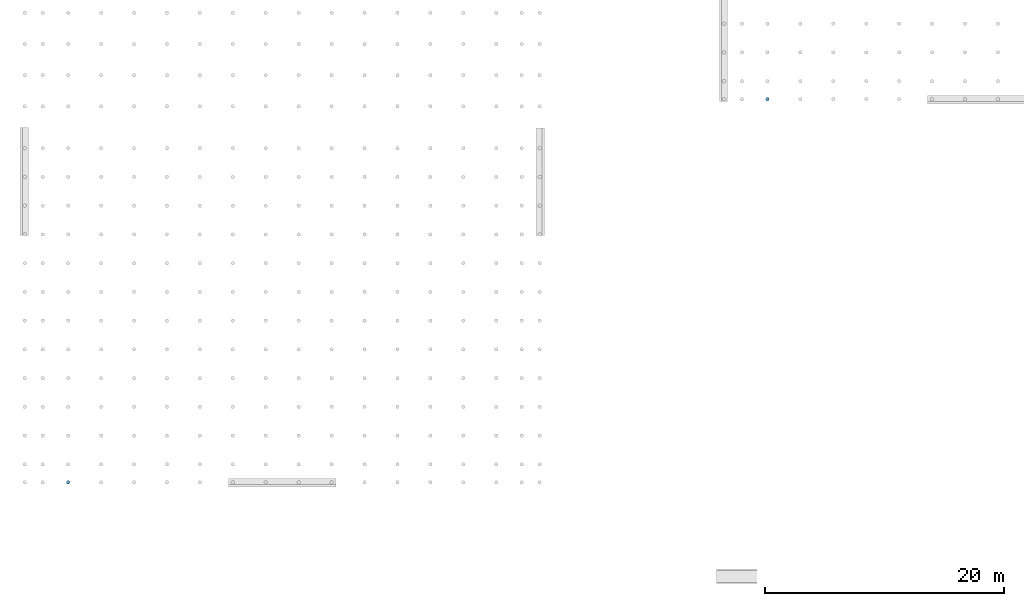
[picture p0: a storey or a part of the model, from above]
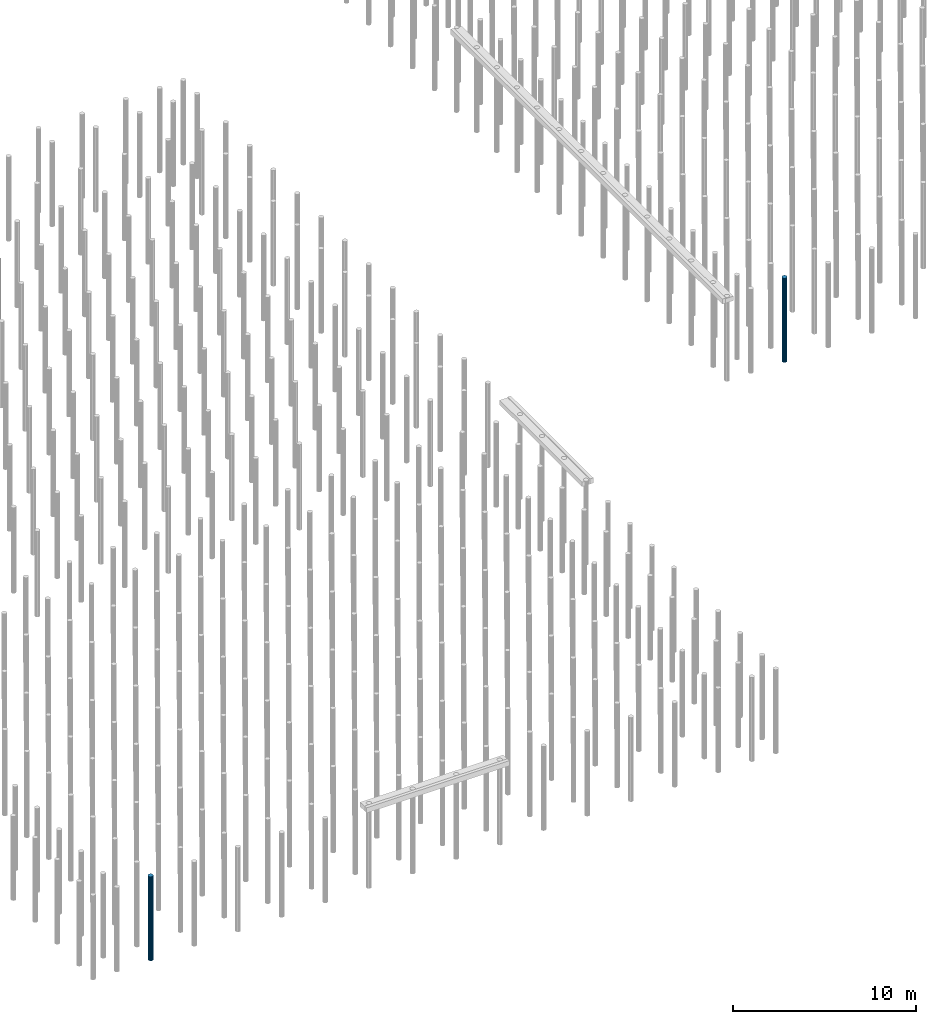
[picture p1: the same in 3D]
Properties of the parts of a building model (IFC2X3), part 1 of 13

# File
Description: ViewDefinition [1, SurfaceGeometryAddOnView, QuantityTakeOffAddOnView, SpaceBoundary2ndLevelAddOnView], Option [Elements to export: Visible elements (on all stories)], Option [Partial Structure Display: Entire Model], Option [IFC Domain: All], Option [Structural Function: All Elements], Option [Convert Grid elements: On], Option [Convert IFC Annotations and Archicad 2D elements: Off], Option [Convert 2D symbols of Doors and Windows: Off], Option [Export geometries that Participates in Collision Detection only: On], Option [Split complex elements: Off], Option [Material Preservation: Never explode], Option [IFC Model position: Survey Point and Project Origin], Option [Curtain Wall export mode: Single Element], Option [Railing export mode: Single Element], Option [Stair export mode: Single Element], Option [Properties To Export: Current Scheme properties only], Option [Space containment: On], Option [IFC Domain For Space Containment: Custom], Option [Geometry to type objects: On], Option [Element Properties: Off], Option [Building Material Properties: Off], Option [Element Parameters: Off], Option [Component Parameters: IFC Component Quantities Only], Option [IFC Base Quantities: On], Option [Door Window Parameters: Off], Option [IFC Space boundaries: On], Option [Archicad Zone Categories as IFC Space classification data: Off], Option [Element Classifications: On]
File name: /Volumes/WERKEN/COURAGE - WERKEN - 2025/COURAGE - 2507 - zrd - middelburg/2507 - TEKENWERK/2507 - 04 - TO - TECHNISCH ONTWERP/2507 - TO - IFC/2507 - 20260205 - definitief - IFC/ZRD-MIDDELBURG_TO_ARC_COU.ifc.ifc
Time: 2026-02-26T14:34:23
Author: Architect
Organization: COURAGE architecten B.V.
Written by: DDS_IFC v3.0
Made in: Graphisoft - Archicad - 27.0.0
Authorization: The authorising person

# IfcProject, ZRD MIDDELBURG
Phase: VOORLOPIG

# IfcSite, Site
RefLatitude: 51, 27, 0, 0; RefLongitude: 5, 29, 0, 0; RefElevation: 0 mm
BaseQuantities - GrossPerimeter: 0 mm; GrossArea: 0 m2

# IfcBuilding, Naam gebouw
BaseQuantities - GrossFloorArea: 0 m2

# IfcBuildingStorey (3)
In: Naam gebouw
BaseQuantities - GrossFloorArea: 0 m2
Name | Elevation (mm) | NetHeight (mm) = GrossHeight (mm) = Height (mm)
-2 fundering | -1020 | 1020
01 dak | 15320 | 1000
00 begane grond | 0 | 15320

# IfcBeam: ALG - ALGEMEEN 200 x 100, samengesteld_element_opsluitband
In: 00 begane grond
Type - PredefinedType: BEAM
Classification: Balk (ARCHICAD Classification); Material: ALG - ALGEMEEN
Pset_BeamCommon - Slope: 0 deg; IsExternal: yes; LoadBearing: no; Reference: ALG - ALGEMEEN 200 x 100
Component Quantities - ALG - ALGEMEEN, Mass: 2.64 kg; ALG - ALGEMEEN, Projected Component Area (Net): 0.0165 m2; ALG - ALGEMEEN, Projected Component Area (Gross): 0.0165 m2; ALG - ALGEMEEN, Component Thickness: 200 mm; ALG - ALGEMEEN, Rectangular Component Height: 100 mm; ALG - ALGEMEEN, Rectangular Component Width: 200 mm; ALG - ALGEMEEN, Component Cross Section Area: 0.02 m2; ALG - ALGEMEEN, Component Volume (Net): 0.0033 m3; ALG - ALGEMEEN, Component Volume (Gross): 0.0033 m3
BaseQuantities - NetSurfaceAreaExtrudedSides: 0.099 m2; Length: 165 mm; Width: 200 mm; Depth: 100 mm; CrossSectionArea: 0.02 m2; OuterSurfaceArea: 0.099 m2; TotalSurfaceArea: 0.139 m2; GrossSurfaceArea: 0.139 m2; GrossVolume: 0.0033 m3; NetSurfaceArea: 0.139 m2; NetVolume: 0.0033 m3
CPset_Phasing - Renovation Phase: Bestaand

# IfcBeam: Beton gewapend C 1000 x 600 (3)
In: -2 fundering
Type - PredefinedType: BEAM
Classification: Balk (ARCHICAD Classification); Material: Beton gewapend C
Pset_BeamCommon - Slope: 0 deg; IsExternal: yes; LoadBearing: yes; Reference: Beton gewapend C 1000 x 600
CPset_Phasing - Renovation Phase: Bestaand
BaseQuantities - Width: 1000 mm; Depth: 600 mm; CrossSectionArea: 0.6 m2
Component Quantities - Beton gewapend C, Component Thickness: 1000 mm; Beton gewapend C, Rectangular Component Height: 600 mm; Beton gewapend C, Rectangular Component Width: 1000 mm; Beton gewapend C, Component Cross Section Area: 0.6 m2
Name | NetSurfaceAreaExtrudedSides (m2) = OuterSurfaceArea (m2) | Length (mm) | TotalSurfaceArea (m2) = GrossSurfaceArea (m2) = NetSurfaceArea (m2) | GrossVolume (m3) = NetVolume (m3) = Beton gewapend C, Projected Component Area (Net) (m2) = Beton gewapend C, Projected Component Area (Gross) (m2) = Beton gewapend C, Component Volume (Net) (m3) = Beton gewapend C, Component Volume (Gross) (m3) | Beton gewapend C, Mass (kg)
Balk-x | 80.8 | 25250 | 82 | 15.15 | 34845
Balk-x | 27.2 | 8500 | 28.4 | 5.1 | 11730
Balk-x | 62.4 | 19500 | 63.6 | 11.7 | 26910

# IfcBeam: Beton gewapend C 500 x 600 (5)
In: -2 fundering
Type - PredefinedType: BEAM
Classification: Balk (ARCHICAD Classification); Material: Beton gewapend C
Pset_BeamCommon - Slope: 0 deg; IsExternal: yes; LoadBearing: yes; Reference: Beton gewapend C 500 x 600
Component Quantities - Beton gewapend C, Component Thickness: 500 mm; Beton gewapend C, Rectangular Component Height: 600 mm; Beton gewapend C, Rectangular Component Width: 500 mm; Beton gewapend C, Component Cross Section Area: 0.3 m2
CPset_Phasing - Renovation Phase: Bestaand
BaseQuantities - Width: 500 mm; Depth: 600 mm; CrossSectionArea: 0.3 m2
Name | Beton gewapend C, Mass (kg) | Beton gewapend C, Projected Component Area (Net) (m2) = Beton gewapend C, Projected Component Area (Gross) (m2) | Beton gewapend C, Component Volume (Net) (m3) = Beton gewapend C, Component Volume (Gross) (m3) = NetVolume (m3) | NetSurfaceAreaExtrudedSides (m2) = OuterSurfaceArea (m2) | Length (mm) | TotalSurfaceArea (m2) = GrossSurfaceArea (m2) = NetSurfaceArea (m2) | GrossVolume (m3)
2 x Balk-x | 10453.5 | 9.24 | 4.545 | 33.33 | 15400 | 33.93 | 4.845
Balk-x | 10971 | 9.84 | 4.77 | 34.98 | 16400 | 35.58 | 4.77
2 x Balk-x | 10626 | 9.24 | 4.62 | 33.88 | 15400 | 34.48 | 4.92

# IfcBeam: Beton gewapend C vloer 200 x 350 (8)
In: -2 fundering
Type - PredefinedType: BEAM
Classification: Balk (ARCHICAD Classification); Material: Beton gewapend C vloer
Pset_BeamCommon - Slope: 0 deg; IsExternal: yes; LoadBearing: no; Reference: Beton gewapend C vloer 200 x 350
CPset_Phasing - Renovation Phase: Bestaand
BaseQuantities - Width: 200 mm; Depth: 350 mm; CrossSectionArea: 0.07 m2
Component Quantities - Beton gewapend C vloer, Component Thickness: 200 mm; Beton gewapend C vloer, Rectangular Component Height: 350 mm; Beton gewapend C vloer, Rectangular Component Width: 200 mm; Beton gewapend C vloer, Component Cross Section Area: 0.07 m2
Name | NetSurfaceAreaExtrudedSides (m2) = OuterSurfaceArea (m2) | Length (mm) | TotalSurfaceArea (m2) = GrossSurfaceArea (m2) = NetSurfaceArea (m2) | GrossVolume (m3) = NetVolume (m3) = Beton gewapend C vloer, Component Volume (Net) (m3) = Beton gewapend C vloer, Component Volume (Gross) (m3) | Beton gewapend C vloer, Mass (kg) | Beton gewapend C vloer, Projected Component Area (Net) (m2) = Beton gewapend C vloer, Projected Component Area (Gross) (m2)
6 x wvb. | 9.9 | 9000 | 10.04 | 0.63 | 1512 | 3.15
wvb. | 9.196 | 8360 | 9.336 | 0.5852 | 1404.48 | 2.926
wvb. | 32.604 | 29640 | 32.744 | 2.0748 | 4979.52 | 10.374

# IfcBeam: Beton gewapend C vloer 500 x 300 (8)
In: -2 fundering
Type - PredefinedType: BEAM
Classification: Balk (ARCHICAD Classification); Material: Beton gewapend C vloer
CPset_Phasing - Renovation Phase: Bestaand
Pset_BeamCommon - Slope: 0 deg; IsExternal: yes; LoadBearing: no; Reference: Beton gewapend C vloer 500 x 300
BaseQuantities - Width: 500 mm; Depth: 300 mm; CrossSectionArea: 0.15 m2
Component Quantities - Beton gewapend C vloer, Component Thickness: 500 mm; Beton gewapend C vloer, Rectangular Component Height: 300 mm; Beton gewapend C vloer, Rectangular Component Width: 500 mm; Beton gewapend C vloer, Component Cross Section Area: 0.15 m2
Name | NetSurfaceAreaExtrudedSides (m2) = OuterSurfaceArea (m2) | Length (mm) | TotalSurfaceArea (m2) = GrossSurfaceArea (m2) = NetSurfaceArea (m2) | GrossVolume (m3) = NetVolume (m3) = Beton gewapend C vloer, Component Volume (Net) (m3) = Beton gewapend C vloer, Component Volume (Gross) (m3) | Beton gewapend C vloer, Mass (kg) | Beton gewapend C vloer, Projected Component Area (Net) (m2) = Beton gewapend C vloer, Projected Component Area (Gross) (m2)
6 x wvb. | 14.4 | 9000 | 14.7 | 1.35 | 3240 | 2.7
wvb. | 13.376 | 8360 | 13.676 | 1.254 | 3009.6 | 2.508
wvb. | 47.424 | 29640 | 47.724 | 4.446 | 10670.4 | 8.892

# IfcBeam: Boiler elektrisch 27, boilervat 250 liter
In: 00 begane grond
Type - PredefinedType: BEAM
Classification: Balk (ARCHICAD Classification); 47 Dakafwerkingen (NL/SfB (4 cijfers))
Component Quantities - Component, Component Volume (Net): 0.414247 m3; Component, Component Volume (Gross): 0.414247 m3
Pset_BeamCommon - IsExternal: yes; LoadBearing: yes
CPset_Phasing - Renovation Phase: Bestaand

# IfcBeam: Brandslang haspelkast 27 (6)
In: 00 begane grond
Type - PredefinedType: BEAM
Classification: Balk (ARCHICAD Classification); 47 Dakafwerkingen (NL/SfB (4 cijfers))
CPset_Phasing - Renovation Phase: Bestaand
Pset_BeamCommon - IsExternal: yes; LoadBearing: no
Component Quantities - Component, Component Volume (Net): 0.0522858 m3; Component, Component Volume (Gross): 0.0522858 m3

# IfcBeam: Buis vk koudgev balk 27 (252)
Type - PredefinedType: BEAM
Classification: Balk (ARCHICAD Classification); 28.11 kolom-/liggerconstructies (NL/SfB (4 cijfers)); Material: Metaal - Staal AFW
CPset_Phasing - Renovation Phase: Bestaand
Pset_BeamCommon - IsExternal: no; LoadBearing: yes
Name | In | Metaal - Staal AFW, Mass (kg) | Metaal - Staal AFW, Component Volume (Net) (m3) = Metaal - Staal AFW, Component Volume (Gross) (m3)
56 x K90x4 | 00 begane grond | 71.1366 | 0.008948
129 x K90x4 | 00 begane grond | 72.6055 | 0.00913277
32 x K90x4 | 00 begane grond | 34.8339 | 0.00438162
6 x K90x4 | 00 begane grond | 70.9268 | 0.00892161
6 x K90x4 | 00 begane grond | 73.0777 | 0.00919216
2 x K90x4 | 00 begane grond | 71.3465 | 0.0089744
3 x K90x4 | 00 begane grond | 598.471 | 0.0752794
3 x K120x5 | 00 begane grond | 266.611 | 0.0335359
K120x5 | 00 begane grond | 276.459 | 0.0347747
K120x5 | 00 begane grond | 206.993 | 0.0260368
K120x5 | 00 begane grond | 48.0989 | 0.00605018
2 x K120x5 | 00 begane grond | 83.8874 | 0.0105519
5 x K90x4 | 01 dak | 673.804 | 0.0847553
5 x K90x4 | 01 dak | 598.261 | 0.075253

# IfcBeam: Constructie - achterconstructie lamellen (ophanging) 60 x 7310 (16)
In: 00 begane grond
Type - PredefinedType: BEAM
Classification: Balk (ARCHICAD Classification); 28.11 kolom-/liggerconstructies (NL/SfB (4 cijfers)); Material: Metaal - Staal C (3)
Pset_BeamCommon - Slope: 0 deg; IsExternal: yes; LoadBearing: yes; Reference: Constructie - achterconstructie lamellen (ophanging) 60 x 7310
CPset_Phasing - Renovation Phase: Bestaand
BaseQuantities - NetSurfaceAreaExtrudedSides: 0.324155 m2; Length: 450 mm; CrossSectionArea: 0.0108103 m2; OuterSurfaceArea: 0.324155 m2; TotalSurfaceArea: 0.345775 m2; GrossSurfaceArea: 0.345775 m2; GrossVolume: 0.00486464 m3; NetSurfaceArea: 0.345775 m2; NetVolume: 0.00486464 m3
Component Quantities - Metaal - Staal C 1, Mass: 12.8913 kg; Metaal - Staal C 1, Rectangular Component Height: 60.0286 mm; Metaal - Staal C 1, Rectangular Component Width: 60.0286 mm; Metaal - Staal C 1, Component Cross Section Area: 0.00360343 m2; Metaal - Staal C 1, Component Volume (Net): 0.00162155 m3; Metaal - Staal C 1, Component Volume (Gross): 0.00162155 m3; Metaal - Staal C 2, Mass: 12.8913 kg; Metaal - Staal C 2, Rectangular Component Height: 60.0286 mm; Metaal - Staal C 2, Rectangular Component Width: 60.0286 mm; Metaal - Staal C 2, Component Cross Section Area: 0.00360343 m2; Metaal - Staal C 2, Component Volume (Net): 0.00162155 m3; Metaal - Staal C 2, Component Volume (Gross): 0.00162155 m3; Metaal - Staal C 3, Mass: 12.8913 kg; Metaal - Staal C 3, Rectangular Component Height: 60.0286 mm; Metaal - Staal C 3, Rectangular Component Width: 60.0286 mm; Metaal - Staal C 3, Component Cross Section Area: 0.00360343 m2; Metaal - Staal C 3, Component Volume (Net): 0.00162155 m3; Metaal - Staal C 3, Component Volume (Gross): 0.00162155 m3

# IfcBeam: Constructie - achterconstructie lamellen 150 x 7400 (4)
In: 00 begane grond
Type - PredefinedType: BEAM
Classification: Balk (ARCHICAD Classification); 28.11 kolom-/liggerconstructies (NL/SfB (4 cijfers)); Material: Metaal - Staal C (3)
CPset_Phasing - Renovation Phase: Bestaand
BaseQuantities - CrossSectionArea: 0.0086588 m2
Pset_BeamCommon - Slope: 0 deg; IsExternal: yes; LoadBearing: yes; Reference: Constructie - achterconstructie lamellen 150 x 7400
Component Quantities - Metaal - Staal C 1, Component Cross Section Area: 0.00288627 m2; Metaal - Staal C 2, Component Cross Section Area: 0.00288627 m2; Metaal - Staal C 3, Component Cross Section Area: 0.00288627 m2
Name | NetSurfaceAreaExtrudedSides (m2) = OuterSurfaceArea (m2) | Length (mm) | TotalSurfaceArea (m2) = GrossSurfaceArea (m2) = NetSurfaceArea (m2) | GrossVolume (m3) | NetVolume (m3) | Metaal - Staal C 1, Mass (kg) = Metaal - Staal C 2, Mass (kg) = Metaal - Staal C 3, Mass (kg) | Metaal - Staal C 1, Component Volume (Net) (m3) = Metaal - Staal C 1, Component Volume (Gross) (m3) = Metaal - Staal C 2, Component Volume (Net) (m3) = Metaal - Staal C 2, Component Volume (Gross) (m3) = Metaal - Staal C 3, Component Volume (Net) (m3) = Metaal - Staal C 3, Component Volume (Gross) (m3)
K150 (X3) | 62.1806 | 18127.5 | 62.1979 | 0.15669 | 0.156474 | 414.655 | 0.0521579
3 x K150 (X3) | 62.0518 | 18090 | 62.0691 | 0.156366 | 0.156149 | 413.796 | 0.0520498

# IfcBeam: Fundering - EPS bekisting KME 1240 x 720 (3)
In: -2 fundering
Type - PredefinedType: BEAM
Classification: Balk (ARCHICAD Classification); Material: Isolatie - Kunststof hard
CPset_Phasing - Renovation Phase: Bestaand
Pset_BeamCommon - Slope: 0 deg; IsExternal: yes; LoadBearing: no; Reference: Fundering - EPS bekisting KME 1240 x 720
BaseQuantities - CrossSectionArea: 0.333915 m2
Component Quantities - Isolatie - Kunststof hard, Component Cross Section Area: 0.333915 m2
Name | NetSurfaceAreaExtrudedSides (m2) = OuterSurfaceArea (m2) | Length (mm) | TotalSurfaceArea (m2) = GrossSurfaceArea (m2) = NetSurfaceArea (m2) | GrossVolume (m3) | NetVolume (m3) = Isolatie - Kunststof hard, Component Volume (Net) (m3) = Isolatie - Kunststof hard, Component Volume (Gross) (m3) | Isolatie - Kunststof hard, Mass (kg)
wvb. | 74.4122 | 19500 | 75.08 | 6.51135 | 5.61898 | 561.898
wvb. | 32.4361 | 8500 | 33.1039 | 2.83828 | 2.4493 | 244.93
wvb. | 95.6481 | 25250 | 96.3159 | 8.43136 | 7.20618 | 720.618

# IfcBeam: Fundering - EPS bekisting KME 740 x 720 (5)
In: -2 fundering
Type - PredefinedType: BEAM
Classification: Balk (ARCHICAD Classification); Material: Isolatie - Kunststof hard
BaseQuantities - CrossSectionArea: 0.228153 m2
Component Quantities - Isolatie - Kunststof hard, Component Cross Section Area: 0.228153 m2
Pset_BeamCommon - Slope: 0 deg; IsExternal: yes; LoadBearing: no; Reference: Fundering - EPS bekisting KME 740 x 720
CPset_Phasing - Renovation Phase: Bestaand
Name | NetSurfaceAreaExtrudedSides (m2) = OuterSurfaceArea (m2) | Length (mm) | TotalSurfaceArea (m2) = GrossSurfaceArea (m2) = NetSurfaceArea (m2) | GrossVolume (m3) | NetVolume (m3) = Isolatie - Kunststof hard, Component Volume (Net) (m3) = Isolatie - Kunststof hard, Component Volume (Gross) (m3) | Isolatie - Kunststof hard, Mass (kg)
wvb. | 60.2143 | 15420 | 60.6706 | 3.45651 | 3.35993 | 335.993
2 x wvb. | 62.0658 | 15200 | 62.5221 | 3.79552 | 3.45973 | 345.973
wvb. | 60.2143 | 15420 | 60.6706 | 3.45506 | 3.35993 | 335.993
wvb. | 65.0673 | 16640 | 65.5236 | 3.62763 | 3.62763 | 362.763

# IfcBeam: Gevel lekdorpel 30 x 57 (19)
In: 00 begane grond
Type - PredefinedType: BEAM
Material: Metaal - Titanium zink
CPset_Phasing - Renovation Phase: Bestaand
Pset_BeamCommon - Slope: 0 deg; IsExternal: yes; LoadBearing: no; Reference: Gevel lekdorpel 30 x 57
Component Quantities - Metaal - Titanium zink, Component Cross Section Area: 0.00015341 m2
BaseQuantities - CrossSectionArea: 0.00015341 m2
Name | Classification | Metaal - Titanium zink, Mass (kg) | Metaal - Titanium zink, Component Volume (Net) (m3) = Metaal - Titanium zink, Component Volume (Gross) (m3) = GrossVolume (m3) = NetVolume (m3) | NetSurfaceAreaExtrudedSides (m2) = OuterSurfaceArea (m2) | Length (mm) | TotalSurfaceArea (m2) = GrossSurfaceArea (m2) = NetSurfaceArea (m2)
8 x aluminium lekdorpel | Balk (ARCHICAD Classification); 41.12 bekledingen (NL/SfB (4 cijfers)) | 19.9384 | 0.00276922 | 2.93163 | 18270 | 2.93193
2 x aluminium lekdorpel | Balk (ARCHICAD Classification); 41.12 bekledingen (NL/SfB (4 cijfers)) | 39.5652 | 0.00549517 | 5.81745 | 36240 | 5.81776
2 x aluminium lekdorpel | Balk (ARCHICAD Classification); 41.12 bekledingen (NL/SfB (4 cijfers)) | 23.8375 | 0.00331077 | 3.50494 | 21840 | 3.50524
aluminium lekdorpel | Balk (ARCHICAD Classification); 41.12 bekledingen (NL/SfB (4 cijfers)) | 0.453512 | 0.0000629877 | 0.0666738 | 430 | 0.0669806
3 x aluminium lekdorpel | Balk (ARCHICAD Classification); 41.12 bekledingen (NL/SfB (4 cijfers)) | 0.655321 | 0.0000910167 | 0.0963549 | 600 | 0.0966617
aluminium lekdorpel | Balk (ARCHICAD Classification); 41.12 bekledingen (NL/SfB (4 cijfers)) | 24.0393 | 0.0033388 | 3.53462 | 22010 | 3.53492
 | Balk (ARCHICAD Classification) | 0.453512 | 0.0000629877 | 0.0666738 | 430 | 0.0669806
aluminium lekdorpel | Balk (ARCHICAD Classification); 41.12 bekledingen (NL/SfB (4 cijfers)) | 63.1625 | 0.00877257 | 9.28706 | 57860 | 9.28737

# IfcBeam: HEA balk 27 (82)
Type - PredefinedType: BEAM
Classification: Balk (ARCHICAD Classification); 28.11 kolom-/liggerconstructies (NL/SfB (4 cijfers)); Material: Metaal - Staal AFW
CPset_Phasing - Renovation Phase: Bestaand
Pset_BeamCommon - IsExternal: no; LoadBearing: yes
Name | In | Metaal - Staal AFW, Mass (kg) | Metaal - Staal AFW, Component Volume (Net) (m3) | Metaal - Staal AFW, Component Volume (Gross) (m3)
2 x HEA240 | 00 begane grond | 3943.37 | 0.496021 | 0.497603
2 x HEA240 | 00 begane grond | 3943.39 | 0.496023 | 0.497603
2 x HEA240 | 00 begane grond | 3501.56 | 0.440448 | 0.441832
2 x HEA240 | 00 begane grond | 3508.04 | 0.441263 | 0.441832
4 x HEA240 | 00 begane grond | 2616.37 | 0.329103 | 0.330289
4 x HEA240 | 00 begane grond | 1312.69 | 0.165118 | 0.165145
4 x HEA240 | 00 begane grond | 1312.82 | 0.165135 | 0.165145
15 x HEA240 | 00 begane grond | 1312.9 | 0.165145 | 0.165145
15 x HEA240 | 00 begane grond | 2625.8 | 0.330289 | 0.330289
15 x HEA240 | 00 begane grond | 1313.44 | 0.165213 | 0.165213
HEA240 | 00 begane grond | 3512.56 | 0.441832 | 0.441832
2 x HEA160 | 01 dak | 1989.81 | 0.25029 | 0.25029
2 x HEA220 | 01 dak | 2585.07 | 0.325166 | 0.325166
4 x HEA220 | 01 dak | 382.249 | 0.0480816 | 0.0480816
2 x HEA220 | 01 dak | 2214.16 | 0.27851 | 0.27851
4 x HEA160 | 01 dak | 1323.74 | 0.166508 | 0.166508
2 x HEA160 | 01 dak | 1767.62 | 0.222342 | 0.222342

# IfcBeam: HEA140 140 x 133 (180)
In: 00 begane grond
Type - PredefinedType: BEAM
Classification: Balk (ARCHICAD Classification); Material: Metaal - Staal C
Component Quantities - Metaal - Staal C, Component Cross Section Area: 0.003018 m2
BaseQuantities - CrossSectionArea: 0.003018 m2
CPset_Phasing - Renovation Phase: Bestaand
Pset_BeamCommon - IsExternal: no; LoadBearing: yes; Reference: HEA140 140 x 133
Name | Metaal - Staal C, Mass (kg) | Metaal - Staal C, Component Volume (Net) (m3) = NetVolume (m3) | Metaal - Staal C, Component Volume (Gross) (m3) | NetSurfaceAreaExtrudedSides (m2) = OuterSurfaceArea (m2) | Length (mm) | TotalSurfaceArea (m2) = GrossSurfaceArea (m2) = NetSurfaceArea (m2) | GrossVolume (m3) | Slope (deg)
30 x HEA140 | 101.111 | 0.0127183 | 0.0133229 | 3.43453 | 4350.46 | 3.44057 | 0.0133229 | 38.6749
30 x HEA140 | 99.0656 | 0.0124611 | 0.0130767 | 3.36507 | 4266.87 | 3.37111 | 0.0130767 | 37.3061
30 x HEA140 | 100.084 | 0.0125891 | 0.0131989 | 3.39965 | 4308.43 | 3.40569 | 0.0131989 | 37.9969
30 x HEA140 | 102.15 | 0.012849 | 0.0134489 | 3.46983 | 4393.1 | 3.47586 | 0.0134489 | 39.3403
16 x HEA140 | 94.4002 | 0.0118742 | 0.0125029 | 3.20659 | 4074.5 | 3.21263 | 0.0125029 | 35.8857
30 x HEA140 | 98.0599 | 0.0123346 | 0.0129564 | 3.33091 | 4225.93 | 3.33694 | 0.0129564 | 36.6024
14 x HEA140 | 94.2291 | 0.0118527 | 0.0124813 | 3.20078 | 4067.37 | 3.20682 | 0.0125029 | 35.8857

# IfcBeam: HEA200 200 x 190 (3)
In: 00 begane grond
Type - PredefinedType: BEAM
Classification: Balk (ARCHICAD Classification); 28.11 kolom-/liggerconstructies (NL/SfB (4 cijfers)); Material: Metaal - Staal C
Pset_BeamCommon - Slope: 0 deg; IsExternal: no; LoadBearing: yes; Reference: HEA200 200 x 190
CPset_Phasing - Renovation Phase: Bestaand
BaseQuantities - CrossSectionArea: 0.005105 m2
Component Quantities - Metaal - Staal C, Component Cross Section Area: 0.005105 m2
Name | NetSurfaceAreaExtrudedSides (m2) = OuterSurfaceArea (m2) | Length (mm) | TotalSurfaceArea (m2) = GrossSurfaceArea (m2) = NetSurfaceArea (m2) | GrossVolume (m3) = NetVolume (m3) = Metaal - Staal C, Component Volume (Net) (m3) = Metaal - Staal C, Component Volume (Gross) (m3) | Metaal - Staal C, Mass (kg)
stalen constructie | 7.88892 | 6760 | 7.89913 | 0.0345098 | 274.353
2 x HEA200 | 16.6648 | 14280 | 16.675 | 0.0728994 | 579.55

# IfcBeam: Hoeklijn gelijk balk 27 (25)
In: 00 begane grond
Type - PredefinedType: BEAM
Classification: Balk (ARCHICAD Classification); 28.11 kolom-/liggerconstructies (NL/SfB (4 cijfers)); Material: Metaal - Staal AFW
Pset_BeamCommon - IsExternal: yes; LoadBearing: yes
CPset_Phasing - Renovation Phase: Bestaand
Name | Metaal - Staal AFW, Mass (kg) | Metaal - Staal AFW, Component Volume (Net) (m3) = Metaal - Staal AFW, Component Volume (Gross) (m3)
L60x6 | 34.5898 | 0.00435091
3 x L60x6 | 24.2386 | 0.00304887
4 x L60x6 | 30.6679 | 0.00385759
4 x L60x6 | 24.9458 | 0.00313783
L60x6 | 17.5842 | 0.00221185
2 x L60x6 | 44.3623 | 0.00558017
6 x L60x6 | 46.2268 | 0.0058147
2 x L60x6 | 43.5265 | 0.00547503
2 x L60x6 | 44.716 | 0.00562465

# IfcBeam: Hout AFW 20 x 65 (294)
In: 00 begane grond
Type - PredefinedType: BEAM
Classification: Balk (ARCHICAD Classification); Material: Hout AFW
Pset_BeamCommon - Slope: 0 deg; IsExternal: no; LoadBearing: yes; Reference: Hout AFW 20 x 65
Component Quantities - Hout AFW, Component Thickness: 20 mm; Hout AFW, Rectangular Component Height: 65 mm; Hout AFW, Rectangular Component Width: 20 mm; Hout AFW, Component Cross Section Area: 0.0013 m2
CPset_Phasing - Renovation Phase: Bestaand
BaseQuantities - Width: 20 mm; Depth: 65 mm; CrossSectionArea: 0.0013 m2
Name | Hout AFW, Mass (kg) | Hout AFW, Projected Component Area (Net) (m2) = Hout AFW, Projected Component Area (Gross) (m2) | Hout AFW, Component Volume (Net) (m3) = Hout AFW, Component Volume (Gross) (m3) = GrossVolume (m3) = NetVolume (m3) | NetSurfaceAreaExtrudedSides (m2) = OuterSurfaceArea (m2) | Length (mm) | TotalSurfaceArea (m2) = GrossSurfaceArea (m2) = NetSurfaceArea (m2)
24 x plafondafwerking_02 | 1.7875 | 0.1625 | 0.00325 | 0.425 | 2500 | 0.4276
262 x plafondafwerking_02 | 1.02245 | 0.09295 | 0.001859 | 0.2431 | 1430 | 0.2457
8 x plafondafwerking_02 | 1.66738 | 0.15158 | 0.00303159 | 0.396439 | 2331.99 | 0.399039

# IfcBeam: Hout AFW 31 x 55, Plafondafwerking 3
In: 00 begane grond
Type - PredefinedType: BEAM
Classification: Balk (ARCHICAD Classification); Material: Hout AFW
Pset_BeamCommon - Slope: 0 deg; IsExternal: no; LoadBearing: yes; Reference: Hout AFW 31 x 55
BaseQuantities - NetSurfaceAreaExtrudedSides: 0.43 m2; Length: 2500 mm; Width: 31 mm; Depth: 55 mm; CrossSectionArea: 0.001705 m2; OuterSurfaceArea: 0.43 m2; TotalSurfaceArea: 0.43341 m2; GrossSurfaceArea: 0.43341 m2; GrossVolume: 0.0042625 m3; NetSurfaceArea: 0.43341 m2; NetVolume: 0.0042625 m3
CPset_Phasing - Renovation Phase: Bestaand
Component Quantities - Hout AFW, Mass: 2.34438 kg; Hout AFW, Projected Component Area (Net): 0.1375 m2; Hout AFW, Projected Component Area (Gross): 0.1375 m2; Hout AFW, Component Thickness: 31 mm; Hout AFW, Rectangular Component Height: 55 mm; Hout AFW, Rectangular Component Width: 31 mm; Hout AFW, Component Cross Section Area: 0.001705 m2; Hout AFW, Component Volume (Net): 0.0042625 m3; Hout AFW, Component Volume (Gross): 0.0042625 m3

# IfcBeam: L 140x70x15 - S355 140 x 78 (4)
In: 00 begane grond
Type - PredefinedType: BEAM
Classification: Balk (ARCHICAD Classification); 28.11 kolom-/liggerconstructies (NL/SfB (4 cijfers)); Material: WSP_metaal - staal - S355
Pset_ReinforcementBarPitchOfBeam - Reference: Tequ 140x140x15 - S355
Pset_BeamCommon - Slope: 0 deg; Reference: Tequ 140x140x15 - S355; Span: 1510 mm; FireRating: use instance; IsExternal: no; LoadBearing: yes
CPset_Phasing - Renovation Phase: Bestaand
BaseQuantities - CrossSectionArea: 0.00306619 m2
Component Quantities - WSP_metaal - staal - S355, Component Cross Section Area: 0.00306619 m2
Name (28_WSP_SF_staal - T v21-1:Tequ 140x140x15 - S355:...) | NetSurfaceAreaExtrudedSides (m2) = OuterSurfaceArea (m2) | Length (mm) | TotalSurfaceArea (m2) = GrossSurfaceArea (m2) = NetSurfaceArea (m2) | GrossVolume (m3) | NetVolume (m3) = WSP_metaal - staal - S355, Component Volume (Net) (m3) | WSP_metaal - staal - S355, Mass (kg) | WSP_metaal - staal - S355, Component Volume (Gross) (m3)
2 x 1613390 | 0.545053 | 1510 | 0.551185 | 0.00463119 | 0.00419732 | 9.65384 | 0.00116797
2 x 1613390 | 0.839237 | 2325 | 0.845369 | 0.0071308 | 0.00646276 | 14.8644 | 0.00179836

# IfcBeam: L60X6 60 x 60 (34)
In: 00 begane grond
Type - PredefinedType: BEAM
Classification: Balk (ARCHICAD Classification); Material: Metaal - Aluminium AFW
CPset_Phasing - Renovation Phase: Bestaand
Pset_BeamCommon - Slope: 0 deg; IsExternal: no; LoadBearing: no; Reference: L60X6 60 x 60
Component Quantities - Metaal - Aluminium AFW, Component Cross Section Area: 0.000684 m2
BaseQuantities - CrossSectionArea: 0.000684 m2
Name | Metaal - Aluminium AFW, Mass (kg) | Metaal - Aluminium AFW, Component Volume (Net) (m3) = Metaal - Aluminium AFW, Component Volume (Gross) (m3) = NetVolume (m3) | NetSurfaceAreaExtrudedSides (m2) = OuterSurfaceArea (m2) | Length (mm) | TotalSurfaceArea (m2) = GrossSurfaceArea (m2) = NetSurfaceArea (m2) | GrossVolume (m3)
2 x hout_multiplex_aansluitplaat | 14.8714 | 0.00531123 | 1.86821 | 7884.64 | 1.86958 | 0.00538006
2 x hout_multiplex_aansluitplaat | 7.15438 | 0.00255514 | 0.896232 | 3770 | 0.8976 | 0.00255514
hout_multiplex_aansluitplaat | 9.22546 | 0.00329481 | 1.15809 | 4891.59 | 1.15946 | 0.00332806
6 x hout_multiplex_aansluitplaat | 0.229824 | 0.00008208 | 0.0288 | 180 | 0.030168 | 0.00008208
4 x hout_multiplex_aansluitplaat | 9.08873 | 0.00324598 | 1.13863 | 4780 | 1.14 | 0.00324598
hout_multiplex_aansluitplaat | 9.22738 | 0.00329549 | 1.15841 | 4891.59 | 1.15978 | 0.00332806
hout_multiplex_aansluitplaat | 9.32813 | 0.00333148 | 1.16863 | 4905 | 1.17 | 0.00333148
hout_multiplex_aansluitplaat | 9.00027 | 0.00321438 | 1.12816 | 4784.97 | 1.12953 | 0.00321438
hout_multiplex_aansluitplaat | 5.17161 | 0.001847 | 0.647765 | 2734.72 | 0.649133 | 0.001847
hout_multiplex_aansluitplaat | 7.35608 | 0.00262717 | 0.921528 | 3882 | 0.922896 | 0.00263722
hout_multiplex_aansluitplaat | 0.295747 | 0.000105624 | 0.037368 | 240 | 0.038736 | 0.000105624
hout_multiplex_aansluitplaat | 0.229885 | 0.0000821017 | 0.0288076 | 180.032 | 0.0301756 | 0.0000821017
2 x hout_multiplex_aansluitplaat | 0.2394 | 0.0000855 | 0.03 | 185 | 0.031368 | 0.0000855
hout_multiplex_aansluitplaat | 0.297904 | 0.000106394 | 0.0376383 | 241.126 | 0.0390063 | 0.000106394
hout_multiplex_aansluitplaat | 1.68487 | 0.000601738 | 0.210829 | 914.155 | 0.212197 | 0.000601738
hout_multiplex_aansluitplaat | 0.293385 | 0.00010478 | 0.037072 | 238.767 | 0.03844 | 0.00010478
hout_multiplex_aansluitplaat | 0.206414 | 0.0000737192 | 0.021564 | 180 | 0.022932 | 0.00008208
hout_multiplex_aansluitplaat | 7.38061 | 0.00263593 | 0.924727 | 3886.23 | 0.926095 | 0.00263806
hout_multiplex_aansluitplaat | 0.229824 | 0.0000820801 | 0.0288 | 180 | 0.030168 | 0.0000820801
hout_multiplex_aansluitplaat | 0.224516 | 0.0000801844 | 0.0281651 | 180 | 0.0295331 | 0.00008208
hout_multiplex_aansluitplaat | 7.37726 | 0.00263473 | 0.924243 | 3883.05 | 0.925611 | 0.00263722
hout_multiplex_aansluitplaat | 7.37471 | 0.00263383 | 0.924013 | 3885 | 0.925381 | 0.00263722
hout_multiplex_aansluitplaat | 7.3842 | 0.00263722 | 0.925032 | 3890 | 0.9264 | 0.00263722

# IfcBeam: Lichtgewicht Betonnen Jersey Barrières 610 x 810 (50)
In: 00 begane grond
Type - PredefinedType: BEAM
Material: Beton gewapend C
Pset_BeamCommon - Slope: 0 deg; IsExternal: yes; LoadBearing: no; Reference: Lichtgewicht Betonnen Jersey Barrières 610 x 810
BaseQuantities - NetSurfaceAreaExtrudedSides: 3.00618 m2; Length: 1200 mm; CrossSectionArea: 0.252044 m2; OuterSurfaceArea: 3.00618 m2; TotalSurfaceArea: 3.51027 m2; GrossSurfaceArea: 3.51027 m2; GrossVolume: 0.302453 m3; NetSurfaceArea: 3.51027 m2; NetVolume: 0.302453 m3
CPset_Phasing - Renovation Phase: Bestaand
Component Quantities - Beton gewapend C, Mass: 695.641 kg; Beton gewapend C, Component Cross Section Area: 0.252044 m2; Beton gewapend C, Component Volume (Net): 0.302453 m3; Beton gewapend C, Component Volume (Gross): 0.302453 m3
Name | Classification
42 x jersey barriere | Balk (ARCHICAD Classification); 71 Vaste verkeersvoorzieningen (NL/SfB (4 cijfers))
8 x betonnen afdekker | Balk (ARCHICAD Classification)

# IfcBeam: Logo ZRD overslaghal 3438 x 3000 (2)
In: 00 begane grond
Type - PredefinedType: BEAM
Classification: Balk (ARCHICAD Classification); 64 Communicatie (NL/SfB (4 cijfers)); Material: ALG - GRIJS (3), ALG - BLAUW, ALG - GROEN
Pset_BeamCommon - Slope: 0 deg; IsExternal: yes; LoadBearing: no; Reference: Logo ZRD overslaghal 3438 x 3000
CPset_Phasing - Renovation Phase: Bestaand
BaseQuantities - NetSurfaceAreaExtrudedSides: 1.49015 m2; Length: 50 mm; CrossSectionArea: 4.20748 m2; OuterSurfaceArea: 1.49015 m2; TotalSurfaceArea: 9.90512 m2; GrossSurfaceArea: 9.90512 m2; GrossVolume: 0.210298 m3; NetSurfaceArea: 9.90512 m2; NetVolume: 0.210298 m3
Component Quantities - ALG - GRIJS 1, Mass: 27.7001 kg; ALG - GRIJS 1, Component Cross Section Area: 0.692502 m2; ALG - GRIJS 1, Component Volume (Net): 0.0346251 m3; ALG - GRIJS 1, Component Volume (Gross): 0.0346251 m3; ALG - BLAUW, Mass: 35.4353 kg; ALG - BLAUW, Component Cross Section Area: 0.886218 m2; ALG - BLAUW, Component Volume (Net): 0.0442941 m3; ALG - BLAUW, Component Volume (Gross): 0.0442941 m3; ALG - GROEN, Mass: 35.4353 kg; ALG - GROEN, Component Cross Section Area: 0.886218 m2; ALG - GROEN, Component Volume (Net): 0.0442941 m3; ALG - GROEN, Component Volume (Gross): 0.0442941 m3; ALG - GRIJS 2, Mass: 35.7544 kg; ALG - GRIJS 2, Component Cross Section Area: 0.894383 m2; ALG - GRIJS 2, Component Volume (Net): 0.0446931 m3; ALG - GRIJS 2, Component Volume (Gross): 0.0446931 m3; ALG - GRIJS 3, Mass: 33.9131 kg; ALG - GRIJS 3, Component Cross Section Area: 0.848162 m2; ALG - GRIJS 3, Component Volume (Net): 0.0423913 m3; ALG - GRIJS 3, Component Volume (Gross): 0.0423913 m3

# IfcBeam: Logo ZRD personeelsgebouw (blauw) 859 x 716 (2)
In: 00 begane grond
Type - PredefinedType: BEAM
Classification: Balk (ARCHICAD Classification); Material: Hout - Hardhout
Pset_BeamCommon - Slope: 0 deg; IsExternal: no; LoadBearing: yes; Reference: Logo ZRD personeelsgebouw (blauw) 859 x 716
Component Quantities - Hout - Hardhout, Mass: 1.42847 kg; Hout - Hardhout, Component Cross Section Area: 0.204185 m2; Hout - Hardhout, Component Volume (Net): 0.00204068 m3; Hout - Hardhout, Component Volume (Gross): 0.00204068 m3
BaseQuantities - NetSurfaceAreaExtrudedSides: 0.0268842 m2; Length: 10 mm; CrossSectionArea: 0.204185 m2; OuterSurfaceArea: 0.0268842 m2; TotalSurfaceArea: 0.435254 m2; GrossSurfaceArea: 0.435254 m2; GrossVolume: 0.00204068 m3; NetSurfaceArea: 0.435254 m2; NetVolume: 0.00204068 m3
CPset_Phasing - Renovation Phase: Bestaand

# IfcBeam: Logo ZRD personeelsgebouw (grijs) 1650 x 600 (2)
In: 00 begane grond
Type - PredefinedType: BEAM
Classification: Balk (ARCHICAD Classification); Material: Hout - Hardhout (3)
CPset_Phasing - Renovation Phase: Bestaand
BaseQuantities - NetSurfaceAreaExtrudedSides: 0.0892593 m2; Length: 10 mm; CrossSectionArea: 0.561035 m2; OuterSurfaceArea: 0.0892593 m2; TotalSurfaceArea: 1.21133 m2; GrossSurfaceArea: 1.21133 m2; GrossVolume: 0.0056076 m3; NetSurfaceArea: 1.21133 m2; NetVolume: 0.0056076 m3
Pset_BeamCommon - Slope: 0 deg; IsExternal: no; LoadBearing: yes; Reference: Logo ZRD personeelsgebouw (grijs) 1650 x 600
Component Quantities - Hout - Hardhout 1, Mass: 1.11687 kg; Hout - Hardhout 1, Component Cross Section Area: 0.159553 m2; Hout - Hardhout 1, Component Volume (Net): 0.00159553 m3; Hout - Hardhout 1, Component Volume (Gross): 0.00159553 m3; Hout - Hardhout 2, Mass: 1.44132 kg; Hout - Hardhout 2, Component Cross Section Area: 0.206066 m2; Hout - Hardhout 2, Component Volume (Net): 0.00205903 m3; Hout - Hardhout 2, Component Volume (Gross): 0.00205903 m3; Hout - Hardhout 3, Mass: 1.36713 kg; Hout - Hardhout 3, Component Cross Section Area: 0.195416 m2; Hout - Hardhout 3, Component Volume (Net): 0.00195304 m3; Hout - Hardhout 3, Component Volume (Gross): 0.00195304 m3

# IfcBeam: Logo ZRD personeelsgebouw (groen) 859 x 716 (2)
In: 00 begane grond
Type - PredefinedType: BEAM
Classification: Balk (ARCHICAD Classification); Material: Hout - Hardhout
Pset_BeamCommon - Slope: 0 deg; IsExternal: no; LoadBearing: yes; Reference: Logo ZRD personeelsgebouw (groen) 859 x 716
BaseQuantities - NetSurfaceAreaExtrudedSides: 0.0268842 m2; Length: 10 mm; CrossSectionArea: 0.204185 m2; OuterSurfaceArea: 0.0268842 m2; TotalSurfaceArea: 0.435254 m2; GrossSurfaceArea: 0.435254 m2; GrossVolume: 0.00204068 m3; NetSurfaceArea: 0.435254 m2; NetVolume: 0.00204068 m3
CPset_Phasing - Renovation Phase: Bestaand
Component Quantities - Hout - Hardhout, Mass: 1.42847 kg; Hout - Hardhout, Component Cross Section Area: 0.204185 m2; Hout - Hardhout, Component Volume (Net): 0.00204068 m3; Hout - Hardhout, Component Volume (Gross): 0.00204068 m3

# IfcBeam: Membraan - dampopen D250 (6)
In: 00 begane grond
Type - PredefinedType: BEAM
Classification: Balk (ARCHICAD Classification); Material: Membraan - dampopen
BaseQuantities - Width: 250 mm; Depth: 250 mm; CrossSectionArea: 0.0490874 m2
CPset_Phasing - Renovation Phase: Bestaand
Component Quantities - Membraan - dampopen, Component Thickness: 250 mm; Membraan - dampopen, Component Cross Section Area: 0.0490874 m2
Pset_BeamCommon - Slope: 0 deg; IsExternal: no; LoadBearing: yes; Reference: Membraan - dampopen D250
Name | NetSurfaceAreaExtrudedSides (m2) = OuterSurfaceArea (m2) | Length (mm) | TotalSurfaceArea (m2) = GrossSurfaceArea (m2) = NetSurfaceArea (m2) | GrossVolume (m3) = NetVolume (m3) = Membraan - dampopen, Component Volume (Net) (m3) = Membraan - dampopen, Component Volume (Gross) (m3) | Membraan - dampopen, Mass (kg) | Membraan - dampopen, Projected Component Area (Net) (m2) = Membraan - dampopen, Projected Component Area (Gross) (m2)
5 x airsock | 3.13501 | 4000 | 3.23318 | 0.194706 | 177.182 | 1
airsock | 1.5675 | 2000 | 1.66568 | 0.0973529 | 88.5911 | 0.5

# IfcBeam: Metaal - Aluminium 34 x 33 (12)
In: 00 begane grond
Type - PredefinedType: BEAM
Classification: Balk (ARCHICAD Classification); Material: Metaal - Aluminium
Pset_BeamCommon - Slope: 0 deg; IsExternal: no; LoadBearing: no; Reference: Metaal - Aluminium 34 x 33
BaseQuantities - Width: 33.5 mm; Depth: 32.5 mm; CrossSectionArea: 0.00108875 m2
CPset_Phasing - Renovation Phase: Nieuw
Component Quantities - Metaal - Aluminium, Component Thickness: 33.5 mm; Metaal - Aluminium, Rectangular Component Height: 32.5 mm; Metaal - Aluminium, Rectangular Component Width: 33.5 mm; Metaal - Aluminium, Component Cross Section Area: 0.00108875 m2
Name | NetSurfaceAreaExtrudedSides (m2) = OuterSurfaceArea (m2) | Length (mm) | TotalSurfaceArea (m2) = GrossSurfaceArea (m2) = NetSurfaceArea (m2) | GrossVolume (m3) | NetVolume (m3) = Metaal - Aluminium, Component Volume (Net) (m3) = Metaal - Aluminium, Component Volume (Gross) (m3) | Metaal - Aluminium, Mass (kg) | Metaal - Aluminium, Projected Component Area (Net) (m2) = Metaal - Aluminium, Projected Component Area (Gross) (m2)
10 x led-lijn | 0.520608 | 3944 | 0.522786 | 0.00430056 | 0.00429403 | 12.0233 | 0.12818
led-lijn | 0.329868 | 2499 | 0.332046 | 0.00272188 | 0.00272079 | 7.6182 | 0.0812175
led-lijn | 0.521268 | 3949 | 0.523446 | 0.00430056 | 0.00429947 | 12.0385 | 0.128343

# IfcBeam: Metaal - Staal C 10 x 70 (10)
In: 00 begane grond
Type - PredefinedType: BEAM
Classification: Balk (ARCHICAD Classification); 28.11 kolom-/liggerconstructies (NL/SfB (4 cijfers)); Material: Metaal - Staal C
BaseQuantities - Width: 10 mm; Depth: 70 mm; CrossSectionArea: 0.0007 m2
Pset_BeamCommon - IsExternal: no; LoadBearing: yes; Reference: Metaal - Staal C 10 x 70
CPset_Phasing - Renovation Phase: Bestaand
Component Quantities - Metaal - Staal C, Component Thickness: 10 mm; Metaal - Staal C, Rectangular Component Height: 70 mm; Metaal - Staal C, Rectangular Component Width: 10 mm; Metaal - Staal C, Component Cross Section Area: 0.0007 m2
Name | NetSurfaceAreaExtrudedSides (m2) = OuterSurfaceArea (m2) | Length (mm) | TotalSurfaceArea (m2) = GrossSurfaceArea (m2) = NetSurfaceArea (m2) | GrossVolume (m3) | NetVolume (m3) = Metaal - Staal C, Component Volume (Net) (m3) = Metaal - Staal C, Component Volume (Gross) (m3) | Slope (deg) | Metaal - Staal C, Mass (kg) | Metaal - Staal C, Projected Component Area (Net) (m2) = Metaal - Staal C, Projected Component Area (Gross) (m2)
2 x wvb. - S70x10 | 0.898507 | 5656.1 | 0.899907 | 0.00393253 | 0.0039317 | 31.8891 | 31.257 | 0.39317
2 x wvb. - S70x10 | 0.903809 | 5698.27 | 0.905209 | 0.00396229 | 0.0039549 | 31.6217 | 31.4414 | 0.39549
2 x wvb. - S70x10 | 0.758869 | 4796.37 | 0.760269 | 0.00332005 | 0.00332005 | 37.3573 | 26.3944 | 0.332005
2 x wvb. - S70x10 | 0.772576 | 4839.61 | 0.773976 | 0.00338002 | 0.00338002 | 8.93561 | 26.8712 | 0.338002
2 x wvb. - S70x10 | 0.795393 | 4991.75 | 0.796793 | 0.00347984 | 0.00347984 | 16.357 | 27.6648 | 0.347984

# IfcBeam: Metaal - Staal C 15 x 120 (120)
In: 00 begane grond
Type - PredefinedType: BEAM
Classification: Balk (ARCHICAD Classification); Material: Metaal - Staal C
Pset_BeamCommon - IsExternal: yes; LoadBearing: no; Reference: Metaal - Staal C 15 x 120
BaseQuantities - Width: 15 mm; Depth: 120 mm; CrossSectionArea: 0.0018 m2
Component Quantities - Metaal - Staal C, Component Thickness: 15 mm; Metaal - Staal C, Rectangular Component Height: 120 mm; Metaal - Staal C, Rectangular Component Width: 15 mm; Metaal - Staal C, Component Cross Section Area: 0.0018 m2
CPset_Phasing - Renovation Phase: Bestaand
Name | Slope (deg) | NetSurfaceAreaExtrudedSides (m2) = OuterSurfaceArea (m2) | Length (mm) | TotalSurfaceArea (m2) = GrossSurfaceArea (m2) = NetSurfaceArea (m2) | GrossVolume (m3) | NetVolume (m3) = Metaal - Staal C, Component Volume (Net) (m3) = Metaal - Staal C, Component Volume (Gross) (m3) | Metaal - Staal C, Mass (kg) | Metaal - Staal C, Projected Component Area (Net) (m2) = Metaal - Staal C, Projected Component Area (Gross) (m2)
36 x wvb. - S120x15 | 28.1239 | 2.11853 | 7910.56 | 2.12213 | 0.0141236 | 0.0141236 | 112.282 | 0.941571
24 x wvb. - S120x15 | 28.6135 | 2.08527 | 7788.7 | 2.08887 | 0.0139018 | 0.0139018 | 110.519 | 0.926788
12 x wvb. - S120x15 | 18.3589 | 1.87458 | 7143.59 | 1.87818 | 0.0128585 | 0.0124972 | 99.3526 | 0.833146
12 x wvb. - S120x15 | 18.3589 | 1.92877 | 7183.41 | 1.93237 | 0.0128585 | 0.0128585 | 102.225 | 0.857231
18 x wvb. - S120x15 | 18.0117 | 1.90959 | 7276.6 | 1.91319 | 0.0130979 | 0.0127306 | 101.208 | 0.848707
18 x wvb. - S120x15 | 18.0117 | 1.96468 | 7315.62 | 1.96828 | 0.0130979 | 0.0130979 | 104.128 | 0.873192

# IfcBeam: Metaal - Staal C 45 x 3680 (2)
In: 00 begane grond
Type - PredefinedType: BEAM
Classification: Balk (ARCHICAD Classification); Material: Metaal - Staal C
Pset_BeamCommon - Slope: 0 deg; IsExternal: yes; LoadBearing: no; Reference: Metaal - Staal C 45 x 3680
CPset_Phasing - Renovation Phase: Bestaand
BaseQuantities - NetSurfaceAreaExtrudedSides: 0.3725 m2; Length: 50 mm; Width: 45 mm; Depth: 3680 mm; CrossSectionArea: 0.1656 m2; OuterSurfaceArea: 0.3725 m2; TotalSurfaceArea: 0.7037 m2; GrossSurfaceArea: 0.7037 m2; GrossVolume: 0.00828 m3; NetSurfaceArea: 0.7037 m2; NetVolume: 0.00828 m3
Component Quantities - Metaal - Staal C, Mass: 65.826 kg; Metaal - Staal C, Projected Component Area (Net): 0.184 m2; Metaal - Staal C, Projected Component Area (Gross): 0.184 m2; Metaal - Staal C, Component Thickness: 45 mm; Metaal - Staal C, Rectangular Component Height: 3680 mm; Metaal - Staal C, Rectangular Component Width: 45 mm; Metaal - Staal C, Component Cross Section Area: 0.1656 m2; Metaal - Staal C, Component Volume (Net): 0.00828 m3; Metaal - Staal C, Component Volume (Gross): 0.00828 m3

# IfcBeam: Metaal - Staal C 45 x 50 (4)
In: 00 begane grond
Type - PredefinedType: BEAM
Classification: Balk (ARCHICAD Classification); Material: Metaal - Staal C
Pset_BeamCommon - Slope: 0 deg; IsExternal: yes; LoadBearing: no; Reference: Metaal - Staal C 45 x 50
CPset_Phasing - Renovation Phase: Bestaand
BaseQuantities - Width: 45 mm; Depth: 50 mm; CrossSectionArea: 0.00225 m2
Component Quantities - Metaal - Staal C, Component Thickness: 45 mm; Metaal - Staal C, Rectangular Component Height: 50 mm; Metaal - Staal C, Rectangular Component Width: 45 mm; Metaal - Staal C, Component Cross Section Area: 0.00225 m2
Name | NetSurfaceAreaExtrudedSides (m2) = OuterSurfaceArea (m2) | Length (mm) | TotalSurfaceArea (m2) = GrossSurfaceArea (m2) = NetSurfaceArea (m2) | GrossVolume (m3) = NetVolume (m3) = Metaal - Staal C, Component Volume (Net) (m3) = Metaal - Staal C, Component Volume (Gross) (m3) | Metaal - Staal C, Mass (kg) | Metaal - Staal C, Projected Component Area (Net) (m2) = Metaal - Staal C, Projected Component Area (Gross) (m2)
2 x wvb. | 10.972 | 57770 | 10.9765 | 0.129932 | 1032.96 | 2.8885
2 x wvb. | 2.75215 | 14507.5 | 2.75665 | 0.0325912 | 259.1 | 0.725375

# IfcBeam: Metaal - Staal C D16 (6)
In: 00 begane grond
Type - PredefinedType: BEAM
Classification: Balk (ARCHICAD Classification); 28.11 kolom-/liggerconstructies (NL/SfB (4 cijfers)); Material: Metaal - Staal C
BaseQuantities - Width: 16 mm; Depth: 16 mm; CrossSectionArea: 0.000201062 m2
Component Quantities - Metaal - Staal C, Component Thickness: 16 mm; Metaal - Staal C, Component Cross Section Area: 0.000201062 m2
CPset_Phasing - Renovation Phase: Bestaand
Pset_BeamCommon - IsExternal: no; LoadBearing: yes; Reference: Metaal - Staal C D16
Name | NetSurfaceAreaExtrudedSides (m2) = OuterSurfaceArea (m2) | Length (mm) | TotalSurfaceArea (m2) = GrossSurfaceArea (m2) = NetSurfaceArea (m2) | GrossVolume (m3) = NetVolume (m3) = Metaal - Staal C, Component Volume (Net) (m3) = Metaal - Staal C, Component Volume (Gross) (m3) | Metaal - Staal C, Mass (kg) | Metaal - Staal C, Projected Component Area (Net) (m2) = Metaal - Staal C, Projected Component Area (Gross) (m2) | Slope (deg)
2 x wvb. - R16 | 0.239104 | 4893.53 | 0.239506 | 0.000883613 | 7.02472 | 0.078101 | 37.3573
2 x wvb. - R16 | 0.193574 | 3954.92 | 0.193976 | 0.000715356 | 5.68708 | 0.0632292 | 10.9403
2 x wvb. - R16 | 0.20205 | 4130.62 | 0.202452 | 0.000746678 | 5.93609 | 0.0659977 | 19.8407

# IfcBeam: Muurafdekker_210 394 x 841 (8)
In: 01 dak
Type - PredefinedType: BEAM
Classification: Balk (ARCHICAD Classification); 27.16 gootconstructies (NL/SfB (4 cijfers)); Material: Membraan - dampdicht, Metaal - Titanium zink
CPset_Phasing - Renovation Phase: Bestaand
Pset_BeamCommon - Slope: 0 deg; IsExternal: yes; LoadBearing: no; Reference: Muurafdekker_210 394 x 841
Component Quantities - Metaal - Titanium zink, Component Cross Section Area: 0.00108094 m2; Membraan - dampdicht, Rectangular Component Height: 813.652 mm; Membraan - dampdicht, Rectangular Component Width: 2 mm; Membraan - dampdicht, Component Cross Section Area: 0.0016273 m2
BaseQuantities - CrossSectionArea: 0.00270825 m2
Name | Metaal - Titanium zink, Mass (kg) | Metaal - Titanium zink, Component Volume (Net) (m3) = Metaal - Titanium zink, Component Volume (Gross) (m3) | Membraan - dampdicht, Mass (kg) | Membraan - dampdicht, Component Volume (Net) (m3) = Membraan - dampdicht, Component Volume (Gross) (m3) | NetSurfaceAreaExtrudedSides (m2) = OuterSurfaceArea (m2) | Length (mm) | TotalSurfaceArea (m2) = GrossSurfaceArea (m2) = NetSurfaceArea (m2) | GrossVolume (m3) = NetVolume (m3)
2 x dakkap | 502.342 | 0.0697697 | 95.2096 | 0.104626 | 174.999 | 65010 | 175.005 | 0.174396
2 x dakkap | 446.397 | 0.0619996 | 84.5475 | 0.0929093 | 155.445 | 57810 | 155.451 | 0.154909
4 x dakkap | 334.507 | 0.0464593 | 63.2233 | 0.0694761 | 116.337 | 43410 | 116.342 | 0.115935

# IfcBeam: Pomp vloermontage 27, hydrofoor
In: 00 begane grond
Type - PredefinedType: BEAM
Classification: Balk (ARCHICAD Classification); 47 Dakafwerkingen (NL/SfB (4 cijfers))
CPset_Phasing - Renovation Phase: Bestaand
Pset_BeamCommon - IsExternal: no; LoadBearing: no
Component Quantities - Component, Component Volume (Net): 0.0440682 m3; Component, Component Volume (Gross): 0.0440682 m3

# IfcBeam: Radiator paneel 27, radiator
In: 00 begane grond
Type - PredefinedType: BEAM
Classification: Balk (ARCHICAD Classification); 47 Dakafwerkingen (NL/SfB (4 cijfers))
CPset_Phasing - Renovation Phase: Bestaand
Pset_BeamCommon - IsExternal: no; LoadBearing: no
Component Quantities - Component, Component Volume (Net): 0.00825 m3; Component, Component Volume (Gross): 0.00825 m3

# IfcBeam: SFB180-HE180B+290x10 290 x 190 (8)
In: 00 begane grond
Type - PredefinedType: BEAM
Classification: Balk (ARCHICAD Classification); 28.11 kolom-/liggerconstructies (NL/SfB (4 cijfers)); Material: Metaal - Staal C (2)
Pset_BeamCommon - Slope: 0 deg; IsExternal: yes; LoadBearing: no; Reference: SFB180-HE180B+290x10 290 x 190
CPset_Phasing - Renovation Phase: Bestaand
Component Quantities - Metaal - Staal C 1, Rectangular Component Height: 10 mm; Metaal - Staal C 1, Rectangular Component Width: 290 mm; Metaal - Staal C 1, Component Cross Section Area: 0.0029 m2; Metaal - Staal C 2, Component Cross Section Area: 0.00652514 m2
BaseQuantities - CrossSectionArea: 0.00942514 m2
Name | Metaal - Staal C 1, Mass (kg) | Metaal - Staal C 1, Component Volume (Net) (m3) = Metaal - Staal C 1, Component Volume (Gross) (m3) | Metaal - Staal C 2, Mass (kg) | Metaal - Staal C 2, Component Volume (Net) (m3) = Metaal - Staal C 2, Component Volume (Gross) (m3) | NetSurfaceAreaExtrudedSides (m2) = OuterSurfaceArea (m2) | Length (mm) | TotalSurfaceArea (m2) = GrossSurfaceArea (m2) = NetSurfaceArea (m2) | GrossVolume (m3) | NetVolume (m3)
SFB180_300 | 361.843 | 0.0455148 | 828.421 | 0.104204 | 20.1609 | 15892 | 20.1797 | 0.150291 | 0.149719
2 x SFB180_300 | 107.436 | 0.013514 | 242.917 | 0.0305556 | 5.94697 | 4660 | 5.96583 | 0.0440696 | 0.0440696
SFB180_300 | 361.963 | 0.04553 | 828.838 | 0.104256 | 20.1694 | 15900 | 20.1882 | 0.150366 | 0.149786
2 x SFB180_300 | 107.466 | 0.0135177 | 242.984 | 0.030564 | 5.94861 | 4661.28 | 5.96746 | 0.0440817 | 0.0440817
2 x SFB180_300 | 122.162 | 0.0153663 | 276.212 | 0.0347437 | 6.76209 | 5298.72 | 6.78094 | 0.05011 | 0.05011

# IfcBeam: SFB180-HE180B+400x10 400 x 190 (2)
In: 00 begane grond
Type - PredefinedType: BEAM
Classification: Balk (ARCHICAD Classification); 28.11 kolom-/liggerconstructies (NL/SfB (4 cijfers)); Material: Metaal - Staal C (2)
Pset_BeamCommon - Slope: 0 deg; IsExternal: yes; LoadBearing: no; Reference: SFB180-HE180B+400x10 400 x 190
CPset_Phasing - Renovation Phase: Bestaand
BaseQuantities - NetSurfaceAreaExtrudedSides: 23.5456 m2; Length: 15900 mm; CrossSectionArea: 0.0105251 m2; OuterSurfaceArea: 23.5456 m2; TotalSurfaceArea: 23.5666 m2; GrossSurfaceArea: 23.5666 m2; GrossVolume: 0.167856 m3; NetSurfaceArea: 23.5666 m2; NetVolume: 0.166696 m3
Component Quantities - Metaal - Staal C 1, Mass: 496.398 kg; Metaal - Staal C 1, Rectangular Component Height: 10 mm; Metaal - Staal C 1, Rectangular Component Width: 400 mm; Metaal - Staal C 1, Component Cross Section Area: 0.004 m2; Metaal - Staal C 1, Component Volume (Net): 0.06244 m3; Metaal - Staal C 1, Component Volume (Gross): 0.06244 m3; Metaal - Staal C 2, Mass: 828.838 kg; Metaal - Staal C 2, Component Cross Section Area: 0.00652514 m2; Metaal - Staal C 2, Component Volume (Net): 0.104256 m3; Metaal - Staal C 2, Component Volume (Gross): 0.104256 m3

# IfcBeam: Schilderij 27 (7)
In: 00 begane grond
Type - PredefinedType: BEAM
Classification: Balk (ARCHICAD Classification); 47 Dakafwerkingen (NL/SfB (4 cijfers))
Pset_BeamCommon - IsExternal: yes; LoadBearing: yes
CPset_Phasing - Renovation Phase: Bestaand
Component Quantities - Component, Component Volume (Net): 0.0111375 m3; Component, Component Volume (Gross): 0.0111375 m3

# IfcBeam: UNP300 100 x 300 (11)
In: 00 begane grond
Type - PredefinedType: BEAM
Classification: Balk (ARCHICAD Classification); 28.11 kolom-/liggerconstructies (NL/SfB (4 cijfers)); Material: Metaal - Staal C
BaseQuantities - CrossSectionArea: 0.00544322 m2
Component Quantities - Metaal - Staal C, Component Cross Section Area: 0.00544322 m2
Pset_BeamCommon - Slope: 0 deg; IsExternal: yes; LoadBearing: yes; Reference: UNP300 100 x 300
CPset_Phasing - Renovation Phase: Bestaand
Name | NetSurfaceAreaExtrudedSides (m2) = OuterSurfaceArea (m2) | Length (mm) | TotalSurfaceArea (m2) = GrossSurfaceArea (m2) = NetSurfaceArea (m2) | GrossVolume (m3) | NetVolume (m3) = Metaal - Staal C, Component Volume (Net) (m3) = Metaal - Staal C, Component Volume (Gross) (m3) | Metaal - Staal C, Mass (kg)
UNP300 | 6.42486 | 6900 | 6.43574 | 0.0377758 | 0.0372671 | 296.273
5 x UNP300 | 6.50245 | 6920 | 6.51334 | 0.0377758 | 0.0377758 | 300.318
UNP300 | 6.31452 | 6720 | 6.32541 | 0.0367386 | 0.036684 | 291.638
UNP300 | 6.31452 | 6720 | 6.32541 | 0.0367932 | 0.036684 | 291.638
UNP300 | 6.48084 | 6980 | 6.49173 | 0.0382125 | 0.037578 | 298.745
UNP300 | 6.35211 | 6760 | 6.36299 | 0.0369024 | 0.0369024 | 293.374
UNP300 | 6.3801 | 6800 | 6.39099 | 0.0371207 | 0.0370578 | 294.609

# IfcBeam: Warmtepomp enkelsysteem 27, wtw unit
In: 00 begane grond
Type - PredefinedType: BEAM
Classification: Balk (ARCHICAD Classification); 47 Dakafwerkingen (NL/SfB (4 cijfers))
CPset_Phasing - Renovation Phase: Bestaand
Pset_BeamCommon - IsExternal: no; LoadBearing: no
Component Quantities - Component, Component Volume (Net): 0.359527 m3; Component, Component Volume (Gross): 0.359527 m3

# IfcBeam: betonnen wand - opstand 205 x 110 (47)
In: 00 begane grond
Type - PredefinedType: BEAM
Classification: Balk (ARCHICAD Classification); Material: Beton gewapend C
Pset_BeamCommon - Slope: 0 deg; IsExternal: yes; LoadBearing: no; Reference: betonnen wand - opstand 205 x 110
BaseQuantities - CrossSectionArea: 0.0149 m2
CPset_Phasing - Renovation Phase: Bestaand
Component Quantities - Beton gewapend C, Component Cross Section Area: 0.0149 m2
Name | NetSurfaceAreaExtrudedSides (m2) = OuterSurfaceArea (m2) | Length (mm) | TotalSurfaceArea (m2) = GrossSurfaceArea (m2) = NetSurfaceArea (m2) | GrossVolume (m3) | NetVolume (m3) = Beton gewapend C, Component Volume (Net) (m3) = Beton gewapend C, Component Volume (Gross) (m3) | Beton gewapend C, Mass (kg)
29 x betonnen afdekker | 3.89766 | 6910 | 3.92746 | 0.102959 | 0.102959 | 236.806
2 x betonnen afdekker | 3.81805 | 6770 | 3.84785 | 0.100873 | 0.100869 | 231.999
2 x betonnen afdekker | 3.91647 | 6960 | 3.94627 | 0.103704 | 0.103648 | 238.39
3 x betonnen afdekker | 1.86986 | 3315 | 1.89966 | 0.0493935 | 0.0493935 | 113.605
4 x betonnen afdekker | 3.81587 | 6765 | 3.84567 | 0.100798 | 0.100798 | 231.837
betonnen afdekker | 3.81796 | 6770 | 3.84776 | 0.100873 | 0.100867 | 231.994
4 x betonnen afdekker | 3.81869 | 6770 | 3.84849 | 0.100873 | 0.100873 | 232.008
betonnen afdekker | 3.91438 | 6960 | 3.94418 | 0.103704 | 0.103616 | 238.318
betonnen afdekker | 1.86704 | 3310 | 1.89684 | 0.049319 | 0.049319 | 113.434

# IfcBeam: dakrand personeelsgebouw 370 x 272 (4)
In: 01 dak
Type - PredefinedType: BEAM
Classification: Balk (ARCHICAD Classification); 27.16 gootconstructies (NL/SfB (4 cijfers)); Material: Membraan - dampdicht, Metaal - Titanium zink (6)
BaseQuantities - CrossSectionArea: 0.000850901 m2
Pset_BeamCommon - Slope: 0 deg; IsExternal: yes; LoadBearing: no; Reference: dakrand personeelsgebouw 370 x 272
Component Quantities - Metaal - Titanium zink 1, Component Cross Section Area: 0.0000075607 m2; Metaal - Titanium zink 2, Component Cross Section Area: 0.0000249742 m2; Metaal - Titanium zink 3, Component Cross Section Area: 0.0000334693 m2; Metaal - Titanium zink 4, Component Cross Section Area: 0.000156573 m2; Metaal - Titanium zink 5, Component Cross Section Area: 0.00000850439 m2; Metaal - Titanium zink 6, Component Cross Section Area: 0.0000198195 m2; Membraan - dampdicht, Rectangular Component Height: 200 mm; Membraan - dampdicht, Rectangular Component Width: 3 mm; Membraan - dampdicht, Component Cross Section Area: 0.0006 m2
CPset_Phasing - Renovation Phase: Bestaand
Name | NetSurfaceAreaExtrudedSides (m2) = OuterSurfaceArea (m2) | Length (mm) | TotalSurfaceArea (m2) = GrossSurfaceArea (m2) = NetSurfaceArea (m2) | GrossVolume (m3) = NetVolume (m3) | Metaal - Titanium zink 1, Mass (kg) | Metaal - Titanium zink 1, Component Volume (Net) (m3) = Metaal - Titanium zink 1, Component Volume (Gross) (m3) | Metaal - Titanium zink 2, Mass (kg) | Metaal - Titanium zink 2, Component Volume (Net) (m3) = Metaal - Titanium zink 2, Component Volume (Gross) (m3) | Metaal - Titanium zink 3, Mass (kg) | Metaal - Titanium zink 3, Component Volume (Net) (m3) = Metaal - Titanium zink 3, Component Volume (Gross) (m3) | Metaal - Titanium zink 4, Mass (kg) | Metaal - Titanium zink 4, Component Volume (Net) (m3) = Metaal - Titanium zink 4, Component Volume (Gross) (m3) | Metaal - Titanium zink 5, Mass (kg) | Metaal - Titanium zink 5, Component Volume (Net) (m3) = Metaal - Titanium zink 5, Component Volume (Gross) (m3) | Metaal - Titanium zink 6, Mass (kg) | Metaal - Titanium zink 6, Component Volume (Net) (m3) = Metaal - Titanium zink 6, Component Volume (Gross) (m3) | Membraan - dampdicht, Mass (kg) | Membraan - dampdicht, Component Volume (Net) (m3) = Membraan - dampdicht, Component Volume (Gross) (m3)
2 x dakkap | 21.7794 | 15900 | 21.7811 | 0.0130096 | 0.860132 | 0.000119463 | 2.85006 | 0.000395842 | 3.7916 | 0.000526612 | 17.4412 | 0.00242239 | 0.928925 | 0.000129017 | 2.16341 | 0.000300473 | 8.29538 | 0.0091158
2 x dakkap | 22.4854 | 16400 | 22.4871 | 0.013435 | 0.887351 | 0.000123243 | 2.93997 | 0.000408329 | 3.91209 | 0.000543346 | 18.0049 | 0.00250067 | 0.959541 | 0.00013327 | 2.23476 | 0.000310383 | 8.56838 | 0.0094158

# IfcBeam: duivenpin (994)
In: 01 dak
Type - PredefinedType: BEAM
Classification: Balk (ARCHICAD Classification); 47 Dakafwerkingen (NL/SfB (4 cijfers)); Material: Metaal - Staal C, Hout C
CPset_Phasing - Renovation Phase: Bestaand
Pset_BeamCommon - IsExternal: yes; LoadBearing: no
Component Quantities - Metaal - Staal C, Mass: 0.99375 kg; Metaal - Staal C, Component Volume (Net): 0.000125 m3; Metaal - Staal C, Component Volume (Gross): 0.000125 m3; Hout C, Mass: 0.0452956 kg; Hout C, Component Volume (Net): 0.0000823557 m3; Hout C, Component Volume (Gross): 0.0000823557 m3

# IfcBeam: gevel waterslag 80 x 57 (8)
In: 00 begane grond
Type - PredefinedType: BEAM
Classification: Balk (ARCHICAD Classification); 41.12 bekledingen (NL/SfB (4 cijfers)); Material: Metaal - Titanium zink
CPset_Phasing - Renovation Phase: Bestaand
Pset_BeamCommon - Slope: 0 deg; IsExternal: yes; LoadBearing: no; Reference: gevel waterslag 80 x 57
Component Quantities - Metaal - Titanium zink, Component Cross Section Area: 0.000250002 m2
BaseQuantities - CrossSectionArea: 0.000250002 m2
Name | Metaal - Titanium zink, Mass (kg) | Metaal - Titanium zink, Component Volume (Net) (m3) = Metaal - Titanium zink, Component Volume (Gross) (m3) = GrossVolume (m3) = NetVolume (m3) | NetSurfaceAreaExtrudedSides (m2) = OuterSurfaceArea (m2) | Length (mm) | TotalSurfaceArea (m2) = GrossSurfaceArea (m2) = NetSurfaceArea (m2)
4 x aluminium waterslag | 77.5523 | 0.0107711 | 11.0038 | 43460 | 11.0043
2 x aluminium waterslag | 103.295 | 0.0143465 | 14.6564 | 57860 | 14.6569
2 x aluminium waterslag | 116.166 | 0.0161341 | 16.4826 | 65060 | 16.4831

# IfcBeam: led-lijn 55 x 75 (23)
In: 00 begane grond
Type - PredefinedType: BEAM
Classification: Balk (ARCHICAD Classification); Material: Glas - Lichtgevend, Metaal - Aluminium AFW
Pset_BeamCommon - Slope: 0 deg; IsExternal: no; LoadBearing: no; Reference: led-lijn 55 x 75
CPset_Phasing - Renovation Phase: Bestaand
Component Quantities - Metaal - Aluminium AFW, Component Cross Section Area: 0.000975 m2; Glas - Lichtgevend, Rectangular Component Height: 70 mm; Glas - Lichtgevend, Rectangular Component Width: 45 mm; Glas - Lichtgevend, Component Cross Section Area: 0.00315 m2
BaseQuantities - CrossSectionArea: 0.004125 m2
Name | Metaal - Aluminium AFW, Mass (kg) | Metaal - Aluminium AFW, Component Volume (Net) (m3) = Metaal - Aluminium AFW, Component Volume (Gross) (m3) | Glas - Lichtgevend, Mass (kg) | Glas - Lichtgevend, Component Volume (Net) (m3) = Glas - Lichtgevend, Component Volume (Gross) (m3) | NetSurfaceAreaExtrudedSides (m2) = OuterSurfaceArea (m2) | Length (mm) | TotalSurfaceArea (m2) = GrossSurfaceArea (m2) = NetSurfaceArea (m2) | GrossVolume (m3) = NetVolume (m3)
20 x led-lijn | 3.9039 | 0.00139425 | 9.81981 | 0.0045045 | 0.3718 | 1430 | 0.38005 | 0.00589875
2 x led-lijn | 6.825 | 0.0024375 | 17.1675 | 0.007875 | 0.65 | 2500 | 0.65825 | 0.0103125
led-lijn | 6.36634 | 0.00227369 | 16.0138 | 0.00734578 | 0.606318 | 2331.99 | 0.614568 | 0.00961948

# IfcBeam: lichtstraat polycarbonaat (constructie) 7420 x 670 (65)
In: 01 dak
Type - PredefinedType: BEAM
Pset_BeamCommon - Slope: 0 deg; IsExternal: yes; LoadBearing: yes; Reference: lichtstraat polycarbonaat (constructie) 7420 x 670
CPset_Phasing - Renovation Phase: Bestaand
BaseQuantities - Length: 75 mm; CrossSectionArea: 0.114269 m2; GrossVolume: 0.00853573 m3
Name | Classification | Material | NetSurfaceAreaExtrudedSides (m2) = OuterSurfaceArea (m2) | TotalSurfaceArea (m2) = GrossSurfaceArea (m2) = NetSurfaceArea (m2) | NetVolume (m3) | Metaal - Aluminium AFW 1, Mass (kg) | Metaal - Aluminium AFW 1, Component Cross Section Area (m2) | Metaal - Aluminium AFW 1, Component Volume (Net) (m3) = Metaal - Aluminium AFW 1, Component Volume (Gross) (m3) | Metaal - Aluminium AFW 2, Mass (kg) | Metaal - Aluminium AFW 2, Component Cross Section Area (m2) | Metaal - Aluminium AFW 2, Component Volume (Net) (m3) = Metaal - Aluminium AFW 2, Component Volume (Gross) (m3)
61 x Plafondafwerking 3 | Balk (ARCHICAD Classification) | Metaal - Aluminium AFW (2) | 2.17709 | 2.40563 | 0.00534423 | 7.47808 | 0.0358301 | 0.00267074 | 7.48575 | 0.0358858 | 0.00267348
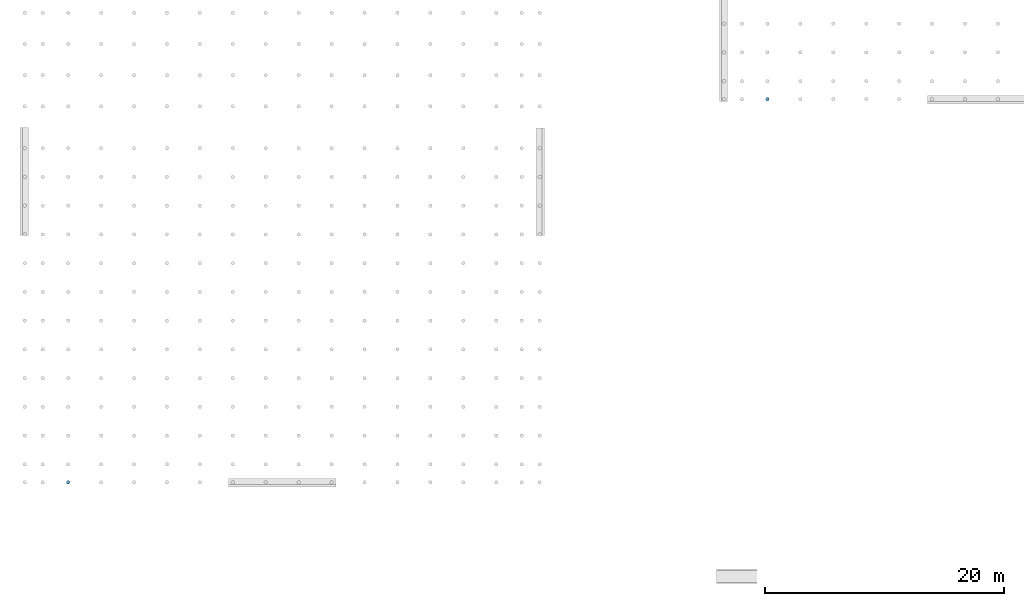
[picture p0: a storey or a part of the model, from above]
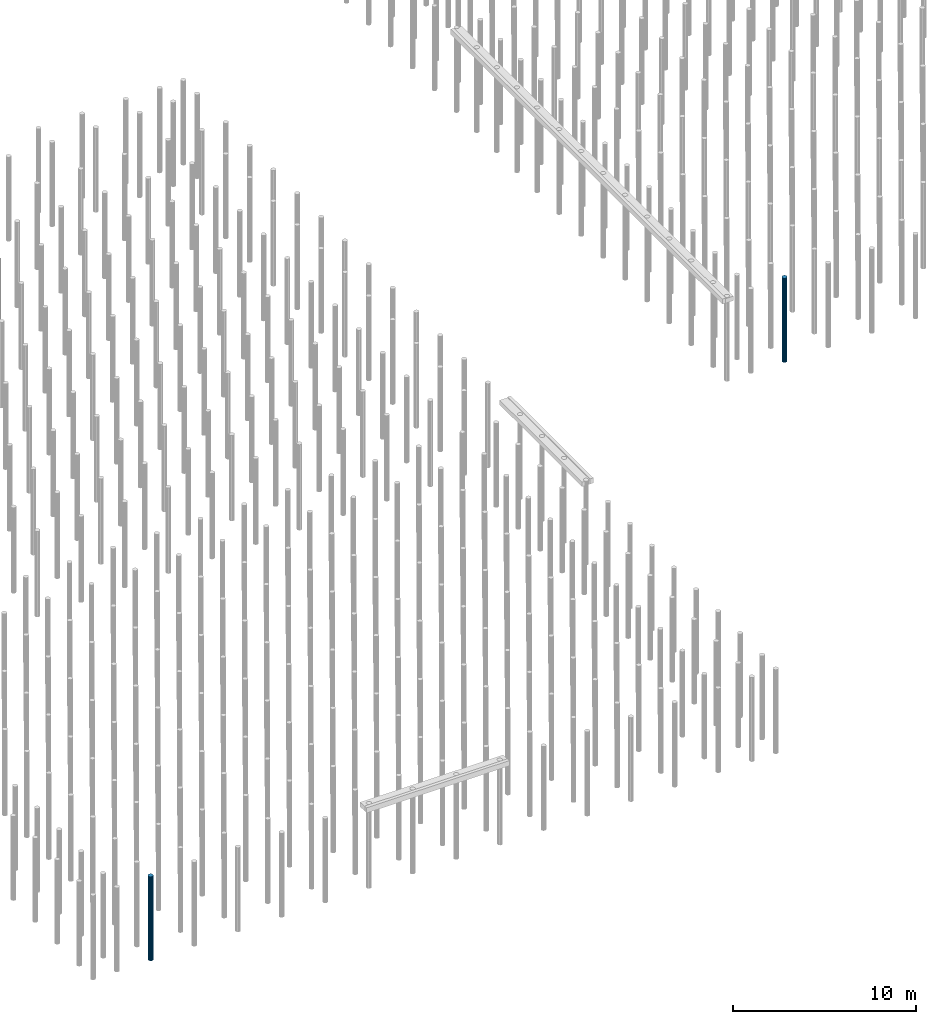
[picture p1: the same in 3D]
Properties of the parts of a building model (IFC2X3), part 2 of 13

# IfcBeam: lichtstraat polycarbonaat (constructie) 7420 x 670 (65)
Name | Classification | Material | NetSurfaceAreaExtrudedSides (m2) = OuterSurfaceArea (m2) | TotalSurfaceArea (m2) = GrossSurfaceArea (m2) = NetSurfaceArea (m2) | NetVolume (m3) | Metaal - Aluminium AFW 1, Mass (kg) | Metaal - Aluminium AFW 1, Component Cross Section Area (m2) | Metaal - Aluminium AFW 1, Component Volume (Net) (m3) = Metaal - Aluminium AFW 1, Component Volume (Gross) (m3) | Metaal - Aluminium AFW 2, Mass (kg) | Metaal - Aluminium AFW 2, Component Cross Section Area (m2) | Metaal - Aluminium AFW 2, Component Volume (Net) (m3) = Metaal - Aluminium AFW 2, Component Volume (Gross) (m3)
3 x lichtstraat | Balk (ARCHICAD Classification); 31.21 gesloten ramen (NL/SfB (4 cijfers)) | Metaal - Aluminium AFW (8), Hout - Dak (6) | 2.33589 | 2.56443 | 0.00853573 | 0.0880012 | 0.000419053 | 0.000031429 | 0.0384308 | 0.000183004 | 0.0000137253 | Component Quantities - Hout - Dak 1, Mass: 0.34086 kg; Hout - Dak 1, Rectangular Component Height: 184 mm; Hout - Dak 1, Rectangular Component Width: 38 mm; Hout - Dak 1, Component Cross Section Area: 0.006992 m2; Hout - Dak 1, Component Volume (Net): 0.0005244 m3; Hout - Dak 1, Component Volume (Gross): 0.0005244 m3; Hout - Dak 2, Mass: 0.514605 kg; Hout - Dak 2, Component Cross Section Area: 0.010556 m2; Hout - Dak 2, Component Volume (Net): 0.0007917 m3; Hout - Dak 2, Component Volume (Gross): 0.0007917 m3; Hout - Dak 3, Mass: 0.119438 kg; Hout - Dak 3, Component Cross Section Area: 0.00245 m2; Hout - Dak 3, Component Volume (Net): 0.00018375 m3; Hout - Dak 3, Component Volume (Gross): 0.00018375 m3; Metaal - Aluminium AFW 3, Mass: 0.142091 kg; Metaal - Aluminium AFW 3, Component Cross Section Area: 0.000676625 m2; Metaal - Aluminium AFW 3, Component Volume (Net): 0.0000507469 m3; Metaal - Aluminium AFW 3, Component Volume (Gross): 0.0000507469 m3; Hout - Dak 4, Mass: 0.34086 kg; Hout - Dak 4, Rectangular Component Height: 184 mm; Hout - Dak 4, Rectangular Component Width: 38 mm; Hout - Dak 4, Component Cross Section Area: 0.006992 m2; Hout - Dak 4, Component Volume (Net): 0.0005244 m3; Hout - Dak 4, Component Volume (Gross): 0.0005244 m3; Hout - Dak 5, Mass: 0.514605 kg; Hout - Dak 5, Component Cross Section Area: 0.010556 m2; Hout - Dak 5, Component Volume (Net): 0.0007917 m3; Hout - Dak 5, Component Volume (Gross): 0.0007917 m3; Hout - Dak 6, Mass: 0.119438 kg; Hout - Dak 6, Component Cross Section Area: 0.00245 m2; Hout - Dak 6, Component Volume (Net): 0.00018375 m3; Hout - Dak 6, Component Volume (Gross): 0.00018375 m3; Metaal - Aluminium AFW 4, Mass: 0.0880012 kg; Metaal - Aluminium AFW 4, Component Cross Section Area: 0.000419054 m2; Metaal - Aluminium AFW 4, Component Volume (Net): 0.000031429 m3; Metaal - Aluminium AFW 4, Component Volume (Gross): 0.000031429 m3; Metaal - Aluminium AFW 5, Mass: 0.0384308 kg; Metaal - Aluminium AFW 5, Component Cross Section Area: 0.000183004 m2; Metaal - Aluminium AFW 5, Component Volume (Net): 0.0000137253 m3; Metaal - Aluminium AFW 5, Component Volume (Gross): 0.0000137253 m3; Metaal - Aluminium AFW 6, Mass: 0.142091 kg; Metaal - Aluminium AFW 6, Component Cross Section Area: 0.000676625 m2; Metaal - Aluminium AFW 6, Component Volume (Net): 0.0000507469 m3; Metaal - Aluminium AFW 6, Component Volume (Gross): 0.0000507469 m3; Metaal - Aluminium AFW 7, Mass: 7.47808 kg; Metaal - Aluminium AFW 7, Component Cross Section Area: 0.0358301 m2; Metaal - Aluminium AFW 7, Component Volume (Net): 0.00267074 m3; Metaal - Aluminium AFW 7, Component Volume (Gross): 0.00267074 m3; Metaal - Aluminium AFW 8, Mass: 7.48575 kg; Metaal - Aluminium AFW 8, Component Cross Section Area: 0.0358858 m2; Metaal - Aluminium AFW 8, Component Volume (Net): 0.00267348 m3; Metaal - Aluminium AFW 8, Component Volume (Gross): 0.00267348 m3
Plafondafwerking 3 | Balk (ARCHICAD Classification) | Metaal - Aluminium AFW (8), Hout - Dak (6) | 2.33589 | 2.56443 | 0.00853573 | 0.0880012 | 0.000419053 | 0.000031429 | 0.0384308 | 0.000183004 | 0.0000137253 | Component Quantities - Hout - Dak 1, Mass: 0.34086 kg; Hout - Dak 1, Rectangular Component Height: 184 mm; Hout - Dak 1, Rectangular Component Width: 38 mm; Hout - Dak 1, Component Cross Section Area: 0.006992 m2; Hout - Dak 1, Component Volume (Net): 0.0005244 m3; Hout - Dak 1, Component Volume (Gross): 0.0005244 m3; Hout - Dak 2, Mass: 0.514605 kg; Hout - Dak 2, Component Cross Section Area: 0.010556 m2; Hout - Dak 2, Component Volume (Net): 0.0007917 m3; Hout - Dak 2, Component Volume (Gross): 0.0007917 m3; Hout - Dak 3, Mass: 0.119438 kg; Hout - Dak 3, Component Cross Section Area: 0.00245 m2; Hout - Dak 3, Component Volume (Net): 0.00018375 m3; Hout - Dak 3, Component Volume (Gross): 0.00018375 m3; Metaal - Aluminium AFW 3, Mass: 0.142091 kg; Metaal - Aluminium AFW 3, Component Cross Section Area: 0.000676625 m2; Metaal - Aluminium AFW 3, Component Volume (Net): 0.0000507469 m3; Metaal - Aluminium AFW 3, Component Volume (Gross): 0.0000507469 m3; Hout - Dak 4, Mass: 0.34086 kg; Hout - Dak 4, Rectangular Component Height: 184 mm; Hout - Dak 4, Rectangular Component Width: 38 mm; Hout - Dak 4, Component Cross Section Area: 0.006992 m2; Hout - Dak 4, Component Volume (Net): 0.0005244 m3; Hout - Dak 4, Component Volume (Gross): 0.0005244 m3; Hout - Dak 5, Mass: 0.514605 kg; Hout - Dak 5, Component Cross Section Area: 0.010556 m2; Hout - Dak 5, Component Volume (Net): 0.0007917 m3; Hout - Dak 5, Component Volume (Gross): 0.0007917 m3; Hout - Dak 6, Mass: 0.119438 kg; Hout - Dak 6, Component Cross Section Area: 0.00245 m2; Hout - Dak 6, Component Volume (Net): 0.00018375 m3; Hout - Dak 6, Component Volume (Gross): 0.00018375 m3; Metaal - Aluminium AFW 4, Mass: 0.0880012 kg; Metaal - Aluminium AFW 4, Component Cross Section Area: 0.000419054 m2; Metaal - Aluminium AFW 4, Component Volume (Net): 0.000031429 m3; Metaal - Aluminium AFW 4, Component Volume (Gross): 0.000031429 m3; Metaal - Aluminium AFW 5, Mass: 0.0384308 kg; Metaal - Aluminium AFW 5, Component Cross Section Area: 0.000183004 m2; Metaal - Aluminium AFW 5, Component Volume (Net): 0.0000137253 m3; Metaal - Aluminium AFW 5, Component Volume (Gross): 0.0000137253 m3; Metaal - Aluminium AFW 6, Mass: 0.142091 kg; Metaal - Aluminium AFW 6, Component Cross Section Area: 0.000676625 m2; Metaal - Aluminium AFW 6, Component Volume (Net): 0.0000507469 m3; Metaal - Aluminium AFW 6, Component Volume (Gross): 0.0000507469 m3; Metaal - Aluminium AFW 7, Mass: 7.47808 kg; Metaal - Aluminium AFW 7, Component Cross Section Area: 0.0358301 m2; Metaal - Aluminium AFW 7, Component Volume (Net): 0.00267074 m3; Metaal - Aluminium AFW 7, Component Volume (Gross): 0.00267074 m3; Metaal - Aluminium AFW 8, Mass: 7.48575 kg; Metaal - Aluminium AFW 8, Component Cross Section Area: 0.0358858 m2; Metaal - Aluminium AFW 8, Component Volume (Net): 0.00267348 m3; Metaal - Aluminium AFW 8, Component Volume (Gross): 0.00267348 m3

# IfcBeam: lichtstraat polycarbonaat (constructie-kopzijde) 220 x 193 (4)
In: 01 dak
Type - PredefinedType: BEAM
Classification: Balk (ARCHICAD Classification); Material: Metaal - Aluminium AFW (3), Hout - Dak (3)
Pset_BeamCommon - Slope: 0 deg; IsExternal: yes; LoadBearing: yes; Reference: lichtstraat polycarbonaat (constructie-kopzijde) 220 x 193
BaseQuantities - NetSurfaceAreaExtrudedSides: 7.40753 m2; Length: 6980 mm; CrossSectionArea: 0.0212767 m2; OuterSurfaceArea: 7.40753 m2; TotalSurfaceArea: 7.45008 m2; GrossSurfaceArea: 7.45008 m2; GrossVolume: 0.148511 m3; NetSurfaceArea: 7.45008 m2; NetVolume: 0.148511 m3
Component Quantities - Hout - Dak 1, Mass: 31.7227 kg; Hout - Dak 1, Rectangular Component Height: 184 mm; Hout - Dak 1, Rectangular Component Width: 38 mm; Hout - Dak 1, Component Cross Section Area: 0.006992 m2; Hout - Dak 1, Component Volume (Net): 0.0488042 m3; Hout - Dak 1, Component Volume (Gross): 0.0488042 m3; Hout - Dak 2, Mass: 47.8926 kg; Hout - Dak 2, Component Cross Section Area: 0.010556 m2; Hout - Dak 2, Component Volume (Net): 0.0736809 m3; Hout - Dak 2, Component Volume (Gross): 0.0736809 m3; Hout - Dak 3, Mass: 11.1156 kg; Hout - Dak 3, Component Cross Section Area: 0.00245 m2; Hout - Dak 3, Component Volume (Net): 0.017101 m3; Hout - Dak 3, Component Volume (Gross): 0.017101 m3; Metaal - Aluminium AFW 1, Mass: 8.18998 kg; Metaal - Aluminium AFW 1, Component Cross Section Area: 0.000419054 m2; Metaal - Aluminium AFW 1, Component Volume (Net): 0.00292499 m3; Metaal - Aluminium AFW 1, Component Volume (Gross): 0.00292499 m3; Metaal - Aluminium AFW 2, Mass: 3.57663 kg; Metaal - Aluminium AFW 2, Component Cross Section Area: 0.000183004 m2; Metaal - Aluminium AFW 2, Component Volume (Net): 0.00127737 m3; Metaal - Aluminium AFW 2, Component Volume (Gross): 0.00127737 m3; Metaal - Aluminium AFW 3, Mass: 13.224 kg; Metaal - Aluminium AFW 3, Component Cross Section Area: 0.000676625 m2; Metaal - Aluminium AFW 3, Component Volume (Net): 0.00472285 m3; Metaal - Aluminium AFW 3, Component Volume (Gross): 0.00472285 m3
CPset_Phasing - Renovation Phase: Bestaand

# IfcBeam: lichtstraat polycarbonaat (polycarbonaat) 7420 x 665 (2)
In: 01 dak
Type - PredefinedType: BEAM
Classification: Balk (ARCHICAD Classification); 31.21 gesloten ramen (NL/SfB (4 cijfers)); Material: Kunststof - massief, Metaal - Aluminium AFW (6), Hout - Dak (6)
BaseQuantities - CrossSectionArea: 0.150136 m2
CPset_Phasing - Renovation Phase: Bestaand
Pset_BeamCommon - Slope: 0 deg; IsExternal: yes; LoadBearing: yes; Reference: lichtstraat polycarbonaat (polycarbonaat) 7420 x 665
Component Quantities - Hout - Dak 1, Rectangular Component Height: 184 mm; Hout - Dak 1, Rectangular Component Width: 38 mm; Hout - Dak 1, Component Cross Section Area: 0.006992 m2; Hout - Dak 2, Component Cross Section Area: 0.010556 m2; Hout - Dak 3, Component Cross Section Area: 0.00245 m2; Metaal - Aluminium AFW 1, Component Cross Section Area: 0.000419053 m2; Metaal - Aluminium AFW 2, Component Cross Section Area: 0.000183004 m2; Metaal - Aluminium AFW 3, Component Cross Section Area: 0.000676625 m2; Hout - Dak 4, Rectangular Component Height: 184 mm; Hout - Dak 4, Rectangular Component Width: 38 mm; Hout - Dak 4, Component Cross Section Area: 0.006992 m2; Hout - Dak 5, Component Cross Section Area: 0.010556 m2; Hout - Dak 6, Component Cross Section Area: 0.00245 m2; Metaal - Aluminium AFW 4, Component Cross Section Area: 0.000419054 m2; Metaal - Aluminium AFW 5, Component Cross Section Area: 0.000183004 m2; Metaal - Aluminium AFW 6, Component Cross Section Area: 0.000676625 m2; Kunststof - massief, Component Cross Section Area: 0.107583 m2
Name | NetSurfaceAreaExtrudedSides (m2) = OuterSurfaceArea (m2) | Length (mm) | TotalSurfaceArea (m2) = GrossSurfaceArea (m2) = NetSurfaceArea (m2) | GrossVolume (m3) | NetVolume (m3) | Hout - Dak 1, Mass (kg) = Hout - Dak 4, Mass (kg) | Hout - Dak 1, Component Volume (Net) (m3) = Hout - Dak 1, Component Volume (Gross) (m3) = Hout - Dak 4, Component Volume (Net) (m3) = Hout - Dak 4, Component Volume (Gross) (m3) | Hout - Dak 2, Mass (kg) = Hout - Dak 5, Mass (kg) | Hout - Dak 2, Component Volume (Net) (m3) = Hout - Dak 2, Component Volume (Gross) (m3) = Hout - Dak 5, Component Volume (Net) (m3) = Hout - Dak 5, Component Volume (Gross) (m3) | Hout - Dak 3, Mass (kg) = Hout - Dak 6, Mass (kg) | Hout - Dak 3, Component Volume (Net) (m3) = Hout - Dak 3, Component Volume (Gross) (m3) = Hout - Dak 6, Component Volume (Net) (m3) = Hout - Dak 6, Component Volume (Gross) (m3) | Metaal - Aluminium AFW 1, Mass (kg) = Metaal - Aluminium AFW 4, Mass (kg) | Metaal - Aluminium AFW 1, Component Volume (Net) (m3) = Metaal - Aluminium AFW 1, Component Volume (Gross) (m3) = Metaal - Aluminium AFW 4, Component Volume (Net) (m3) = Metaal - Aluminium AFW 4, Component Volume (Gross) (m3) | Metaal - Aluminium AFW 2, Mass (kg) = Metaal - Aluminium AFW 5, Mass (kg) | Metaal - Aluminium AFW 2, Component Volume (Net) (m3) = Metaal - Aluminium AFW 2, Component Volume (Gross) (m3) = Metaal - Aluminium AFW 5, Component Volume (Net) (m3) = Metaal - Aluminium AFW 5, Component Volume (Gross) (m3) | Metaal - Aluminium AFW 3, Mass (kg) = Metaal - Aluminium AFW 6, Mass (kg) | Metaal - Aluminium AFW 3, Component Volume (Net) (m3) = Metaal - Aluminium AFW 3, Component Volume (Gross) (m3) = Metaal - Aluminium AFW 6, Component Volume (Net) (m3) = Metaal - Aluminium AFW 6, Component Volume (Gross) (m3) | Kunststof - massief, Mass (kg) | Kunststof - massief, Component Volume (Net) (m3) = Kunststof - massief, Component Volume (Gross) (m3)
lichtstraat | 715.665 | 42970 | 715.966 | 6.46078 | 6.45886 | 195.086 | 0.300132 | 294.526 | 0.453116 | 68.3581 | 0.105166 | 50.366 | 0.0179879 | 21.9952 | 0.00785544 | 81.3236 | 0.0290441 | 6438.84 | 4.63226
lichtstraat | 835.597 | 50170 | 835.898 | 7.54333 | 7.54142 | 227.808 | 0.350474 | 343.928 | 0.52912 | 79.8241 | 0.122806 | 58.8142 | 0.0210051 | 25.6846 | 0.00917307 | 94.9644 | 0.0339158 | 7517.72 | 5.40843

# IfcBuildingElementProxy: 8200 - hanglamp 03 (3)
In: 00 begane grond
Material: ALG - ALGEMEEN
Component Quantities - ALG - ALGEMEEN, Mass: 0.467878 kg; ALG - ALGEMEEN, Component Volume (Net): 0.000584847 m3; ALG - ALGEMEEN, Component Volume (Gross): 0.000584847 m3

# IfcBuildingElementProxy: 8200 - railspot 02 (37)
In: 00 begane grond
Material: ALG - ALGEMEEN
Component Quantities - ALG - ALGEMEEN, Mass: 0.0894263 kg; ALG - ALGEMEEN, Component Volume (Net): 0.000111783 m3; ALG - ALGEMEEN, Component Volume (Gross): 0.000111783 m3

# IfcBuildingElementProxy: Bandalux_Premium-Plus-2-Roller-Shades_INT (16)
In: 00 begane grond
Name | Component, Component Volume (Net) (m3) = Component, Component Volume (Gross) (m3)
2 x rolgordijn | 0.006937
2 x rolgordijn | 0.00613877
4 x rolgordijn | 0.00627596
4 x rolgordijn | 0.00506614
rolgordijn | 0.00217255
rolgordijn | 0.00519087
2 x rolgordijn | 0.0050412

# IfcBuildingElementProxy: Beton C (3)
In: 00 begane grond
Material: Beton C
Name | Beton C, Mass (kg) | Beton C, Component Volume (Net) (m3) = Beton C, Component Volume (Gross) (m3)
 | 162.58 | 0.0677417
2 x  | 0 | 0

# IfcBuildingElementProxy: Bovenkast recht 27 (3)
In: 00 begane grond
Component Quantities - Component, Component Volume (Net): 0.0377543 m3; Component, Component Volume (Gross): 0.0377543 m3

# IfcBuildingElementProxy: Douche armatuur 27 (2)
In: 00 begane grond
Component Quantities - Component, Component Volume (Net): 0.00195224 m3; Component, Component Volume (Gross): 0.00195224 m3

# IfcBuildingElementProxy: Frame vloer 27 KM, hulpstaal
In: 01 dak
Component Quantities - Component, Component Volume (Net): 0.45243 m3; Component, Component Volume (Gross): 0.45243 m3

# IfcBuildingElementProxy: Invalidentoilet 27
In: 00 begane grond
Component Quantities - Component, Component Volume (Net): 0.0263776 m3; Component, Component Volume (Gross): 0.0263776 m3

# IfcBuildingElementProxy: Koffiezetapparaat 27
In: 00 begane grond
Component Quantities - Component, Component Volume (Net): 0.0753755 m3; Component, Component Volume (Gross): 0.0753755 m3

# IfcBuildingElementProxy: Kraan wand 27 (2)
In: 00 begane grond
Component Quantities - Component, Component Volume (Net): 0.000236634 m3; Component, Component Volume (Gross): 0.000236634 m3

# IfcBuildingElementProxy: Kubus 27 (6)
Name | In | Component, Component Volume (Net) (m3) = Component, Component Volume (Gross) (m3)
3 x nestkast | 00 begane grond | 0.1296
nestkast | 00 begane grond | 0.1296 | Classification: 0- INDIRECTE PROJECTVOORZIENINGEN (NL/SfB (4 cijfers))
2 x  | 01 dak | 0.341303

# IfcBuildingElementProxy: Onderkast recht 27 (6)
In: 00 begane grond
Name | Component, Component Volume (Net) (m3) = Component, Component Volume (Gross) (m3)
 | 0.0793267
 | 0.0781367
2 x  | 0.107883
2 x sanitairmeubel | 0.0585062

# IfcBuildingElementProxy: Pot 27 (2)
In: 00 begane grond
Component Quantities - Component, Component Volume (Net): 0.00114238 m3; Component, Component Volume (Gross): 0.00114238 m3

# IfcBuildingElementProxy: Quooker+fusion+square
In: 00 begane grond
Component Quantities - Component, Component Volume (Net): 0 m3; Component, Component Volume (Gross): 0 m3

# IfcBuildingElementProxy: Spiegel 27 (7)
In: 00 begane grond
Name | Component, Component Volume (Net) (m3) = Component, Component Volume (Gross) (m3)
2 x spiegel | 0.00954
spiegel | 0.0096
2 x spiegel | 0.00182528
2 x spiegel | 0.0064

# IfcBuildingElementProxy: Tekst 3D 27 (23)
In: 00 begane grond
Name | Component, Component Volume (Net) (m3) = Component, Component Volume (Gross) (m3)
11 x 03 | 0.000329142
03 | 0.00138403
03 | 0.000813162
03 | 0.000459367
03 | 0.000753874
2 x 03 | 0.001108
03 | 0.00131255
03 | 0.00140227
03 | 0.00151212
03 | 0.00140341
03 | 0.000779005
03 | 0.00329879

# IfcBuildingElementProxy: Televisie flatscreen 27 (7)
In: 00 begane grond
Name | Component, Component Volume (Net) (m3) = Component, Component Volume (Gross) (m3)
2 x  | 0.0464199
 | 0.0951764
 | 0.132587
2 x  | 0.0475784
 | 0.0865615

# IfcBuildingElementProxy: Toilet 27 (2)
In: 00 begane grond
Component Quantities - Component, Component Volume (Net): 0.0239146 m3; Component, Component Volume (Gross): 0.0239146 m3

# IfcBuildingElementProxy: Uitstortgootsteen 27 (4)
In: 00 begane grond
Name | Component, Component Volume (Net) (m3) = Component, Component Volume (Gross) (m3)
 | 0.135071
 | 0.0774343
2 x  | 0.094429

# IfcBuildingElementProxy: Urinoir 27
In: 00 begane grond
Component Quantities - Component, Component Volume (Net): 0.0164242 m3; Component, Component Volume (Gross): 0.0164242 m3

# IfcBuildingElementProxy: Wasbak 27 (2)
In: 00 begane grond
Name | Component, Component Volume (Net) (m3) = Component, Component Volume (Gross) (m3)
 | 0.0286349
 | 0.0331347

# IfcBuildingElementProxy: Zonnepaneel 27 (6)
In: 01 dak
Component Quantities - Component, Component Volume (Net): 0.313022 m3; Component, Component Volume (Gross): 0.313022 m3

# IfcBuildingElementProxy: rood-groen-licht (5)
In: 00 begane grond
Component Quantities - Component, Component Volume (Net): 0 m3; Component, Component Volume (Gross): 0 m3

# IfcColumn: ALG - ONTWERP 100 x 200, Kolom-x
In: 00 begane grond
Type - PredefinedType: COLUMN
Classification: Kolom (ARCHICAD Classification); Material: ALG - ONTWERP
CPset_Phasing - Renovation Phase: Bestaand
Pset_ColumnCommon - Slope: 90 deg; IsExternal: yes; LoadBearing: no; Reference: ALG - ONTWERP 100 x 200
BaseQuantities - Length: 3600 mm; Width: 100 mm; Depth: 200 mm; CrossSectionArea: 0.02 m2; OuterSurfaceArea: 2.16 m2; TotalSurfaceArea: 2.2 m2; GrossSurfaceArea: 2.2 m2; GrossVolume: 0.072 m3; NetVolume: 0.072 m3
Component Quantities - ALG - ONTWERP, Mass: 57.6 kg; ALG - ONTWERP, Component Thickness: 100 mm; ALG - ONTWERP, Rectangular Component Height: 200 mm; ALG - ONTWERP, Rectangular Component Width: 100 mm; ALG - ONTWERP, Component Cross Section Area: 0.02 m2; ALG - ONTWERP, Component Volume (Net): 0.072 m3; ALG - ONTWERP, Component Volume (Gross): 0.072 m3

# IfcColumn: ALG - ONTWERP 200 x 200, Kolom-x
In: 00 begane grond
Type - PredefinedType: COLUMN
Classification: Kolom (ARCHICAD Classification); Material: ALG - ONTWERP
Pset_ColumnCommon - Slope: 90 deg; IsExternal: yes; LoadBearing: no; Reference: ALG - ONTWERP 200 x 200
BaseQuantities - Length: 3600 mm; Width: 200 mm; Depth: 200 mm; CrossSectionArea: 0.04 m2; OuterSurfaceArea: 2.88 m2; TotalSurfaceArea: 2.96 m2; GrossSurfaceArea: 2.96 m2; GrossVolume: 0.144 m3; NetVolume: 0.144 m3
Component Quantities - ALG - ONTWERP, Mass: 115.2 kg; ALG - ONTWERP, Component Thickness: 200 mm; ALG - ONTWERP, Rectangular Component Height: 200 mm; ALG - ONTWERP, Rectangular Component Width: 200 mm; ALG - ONTWERP, Component Cross Section Area: 0.04 m2; ALG - ONTWERP, Component Volume (Net): 0.144 m3; ALG - ONTWERP, Component Volume (Gross): 0.144 m3
CPset_Phasing - Renovation Phase: Bestaand

# IfcColumn: CFRHS120X120X8 120 x 120 (23)
In: 00 begane grond
Type - PredefinedType: COLUMN
Classification: Kolom (ARCHICAD Classification); Material: Metaal - Staal C
CPset_Phasing - Renovation Phase: Bestaand
BaseQuantities - Length: 3110 mm; CrossSectionArea: 0.00357027 m2; OuterSurfaceArea: 2.73986 m2; TotalSurfaceArea: 2.74699 m2; GrossSurfaceArea: 2.74699 m2; GrossVolume: 0.0110879 m3; NetVolume: 0.0110879 m3
Pset_ColumnCommon - Slope: 90 deg; IsExternal: no; LoadBearing: yes; Reference: CFRHS120X120X8 120 x 120
Component Quantities - Metaal - Staal C, Mass: 88.1491 kg; Metaal - Staal C, Component Cross Section Area: 0.00357027 m2; Metaal - Staal C, Component Volume (Net): 0.0110879 m3; Metaal - Staal C, Component Volume (Gross): 0.0110879 m3

# IfcColumn: CFRHS60X60X5 60 x 60 (2)
In: 00 begane grond
Type - PredefinedType: COLUMN
Classification: Kolom (ARCHICAD Classification); Material: Metaal - Staal C
Pset_ColumnCommon - Slope: 90 deg; IsExternal: no; LoadBearing: yes; Reference: CFRHS60X60X5 60 x 60
CPset_Phasing - Renovation Phase: Bestaand
BaseQuantities - Length: 3110 mm; CrossSectionArea: 0.0011 m2; OuterSurfaceArea: 1.3684 m2; TotalSurfaceArea: 1.3706 m2; GrossSurfaceArea: 1.3706 m2; GrossVolume: 0.003421 m3; NetVolume: 0.003421 m3
Component Quantities - Metaal - Staal C, Mass: 27.1969 kg; Metaal - Staal C, Component Cross Section Area: 0.0011 m2; Metaal - Staal C, Component Volume (Net): 0.003421 m3; Metaal - Staal C, Component Volume (Gross): 0.003421 m3

# IfcColumn: HEA140 140 x 133 (165)
In: 00 begane grond
Type - PredefinedType: COLUMN
Classification: Kolom (ARCHICAD Classification); Material: Metaal - Staal C
Pset_ColumnCommon - Slope: 90 deg; IsExternal: no; LoadBearing: yes; Reference: HEA140 140 x 133
Component Quantities - Metaal - Staal C, Component Cross Section Area: 0.003018 m2
BaseQuantities - CrossSectionArea: 0.003018 m2
CPset_Phasing - Renovation Phase: Bestaand
Name | Metaal - Staal C, Mass (kg) | Metaal - Staal C, Component Volume (Net) (m3) = Metaal - Staal C, Component Volume (Gross) (m3) = GrossVolume (m3) = NetVolume (m3) | Length (mm) | OuterSurfaceArea (m2) | TotalSurfaceArea (m2) = GrossSurfaceArea (m2)
30 x HEA140 | 60.4569 | 0.00760464 | 2519.76 | 2.05361 | 2.05964
30 x HEA140 | 65.2281 | 0.00820479 | 2718.62 | 2.21567 | 2.22171
30 x HEA140 | 62.0473 | 0.00780469 | 2586.05 | 2.10763 | 2.11367
30 x HEA140 | 63.6377 | 0.00800474 | 2652.33 | 2.16165 | 2.16769
30 x HEA140 | 66.8185 | 0.00840484 | 2784.9 | 2.2697 | 2.27573
15 x HEA140 | 68.3793 | 0.00860118 | 2849.96 | 2.32272 | 2.32875

# IfcColumn: HEA160 160 x 152 (62)
In: 01 dak
Type - PredefinedType: COLUMN
Classification: 28.11 kolom-/liggerconstructies (NL/SfB (4 cijfers)); Kolom (ARCHICAD Classification); Material: Metaal - Staal C
Pset_ColumnCommon - Slope: 90 deg; IsExternal: no; LoadBearing: yes; Reference: HEA160 160 x 152
Component Quantities - Metaal - Staal C, Component Cross Section Area: 0.003684 m2
CPset_Phasing - Renovation Phase: Bestaand
BaseQuantities - CrossSectionArea: 0.003684 m2
Name | Metaal - Staal C, Mass (kg) | Metaal - Staal C, Component Volume (Net) (m3) = Metaal - Staal C, Component Volume (Gross) (m3) = GrossVolume (m3) = NetVolume (m3) | Length (mm) | OuterSurfaceArea (m2) | TotalSurfaceArea (m2) = GrossSurfaceArea (m2)
38 x HEA160 | 30.8986 | 0.00388662 | 1055 | 0.98326 | 0.990628
2 x HEA160 | 24.0148 | 0.00302073 | 819.961 | 0.764203 | 0.771571
4 x HEA160 | 27.1526 | 0.00341543 | 927.097 | 0.864054 | 0.871422
4 x HEA160 | 23.2509 | 0.00292465 | 793.878 | 0.739895 | 0.747263
2 x HEA160 | 23.2447 | 0.00292386 | 793.665 | 0.739695 | 0.747063
4 x HEA160 | 21.2938 | 0.00267847 | 727.055 | 0.677615 | 0.684983
4 x HEA160 | 27.1464 | 0.00341464 | 926.883 | 0.863855 | 0.871223
4 x HEA160 | 21.3001 | 0.00267926 | 727.269 | 0.677815 | 0.685183

# IfcColumn: HEA220 220 x 210 (30)
In: 01 dak
Type - PredefinedType: COLUMN
Classification: 28.11 kolom-/liggerconstructies (NL/SfB (4 cijfers)); Kolom (ARCHICAD Classification); Material: Metaal - Staal C
CPset_Phasing - Renovation Phase: Bestaand
Pset_ColumnCommon - Slope: 90 deg; IsExternal: no; LoadBearing: yes; Reference: HEA220 220 x 210
BaseQuantities - Length: 420 mm; CrossSectionArea: 0.006156 m2; OuterSurfaceArea: 0.54012 m2; TotalSurfaceArea: 0.552432 m2; GrossSurfaceArea: 0.552432 m2; GrossVolume: 0.00258552 m3; NetVolume: 0.00258552 m3
Component Quantities - Metaal - Staal C, Mass: 20.5549 kg; Metaal - Staal C, Component Cross Section Area: 0.006156 m2; Metaal - Staal C, Component Volume (Net): 0.00258552 m3; Metaal - Staal C, Component Volume (Gross): 0.00258552 m3

# IfcColumn: HEA240 240 x 230 (9)
In: 00 begane grond
Type - PredefinedType: COLUMN
Classification: 28.11 kolom-/liggerconstructies (NL/SfB (4 cijfers)); Kolom (ARCHICAD Classification); Material: Metaal - Staal C
Pset_ColumnCommon - Slope: 90 deg; IsExternal: no; LoadBearing: yes; Reference: HEA240 240 x 230
CPset_Phasing - Renovation Phase: Bestaand
BaseQuantities - Length: 12000 mm; CrossSectionArea: 0.007305 m2; OuterSurfaceArea: 16.86 m2; TotalSurfaceArea: 16.8746 m2; GrossSurfaceArea: 16.8746 m2; GrossVolume: 0.08766 m3; NetVolume: 0.08766 m3
Component Quantities - Metaal - Staal C, Mass: 696.897 kg; Metaal - Staal C, Component Cross Section Area: 0.007305 m2; Metaal - Staal C, Component Volume (Net): 0.08766 m3; Metaal - Staal C, Component Volume (Gross): 0.08766 m3

# IfcColumn: HEB280 280 x 280 (62)
In: 00 begane grond
Type - PredefinedType: COLUMN
Classification: 28.11 kolom-/liggerconstructies (NL/SfB (4 cijfers)); Kolom (ARCHICAD Classification); Material: Metaal - Staal C
Pset_ColumnCommon - Slope: 90 deg; IsExternal: no; LoadBearing: yes; Reference: HEB280 280 x 280
CPset_Phasing - Renovation Phase: Bestaand
BaseQuantities - CrossSectionArea: 0.012642 m2
Component Quantities - Metaal - Staal C, Component Cross Section Area: 0.012642 m2
Name | Length (mm) | OuterSurfaceArea (m2) | TotalSurfaceArea (m2) = GrossSurfaceArea (m2) | GrossVolume (m3) = NetVolume (m3) = Metaal - Staal C, Component Volume (Net) (m3) = Metaal - Staal C, Component Volume (Gross) (m3) | Metaal - Staal C, Mass (kg)
20 x HEB280 | 10920 | 18.1162 | 18.1415 | 0.13805 | 1097.5
18 x HEB280 | 10920 | 18.1163 | 18.1416 | 0.138051 | 1097.5
2 x HEB280 | 10817.8 | 17.9468 | 17.9721 | 0.136759 | 1087.24
2 x HEB280 | 10951.1 | 18.1678 | 18.1931 | 0.138443 | 1100.62
2 x HEB280 | 10951.3 | 18.1682 | 18.1935 | 0.138446 | 1100.65
2 x HEB280 | 10818.1 | 17.9472 | 17.9724 | 0.136762 | 1087.26
2 x HEB280 | 10817.8 | 17.9468 | 17.9721 | 0.136759 | 1087.23
2 x HEB280 | 10951 | 18.1678 | 18.1931 | 0.138443 | 1100.62
2 x HEB280 | 10951.3 | 18.1681 | 18.1934 | 0.138446 | 1100.64
2 x HEB280 | 10818 | 17.9471 | 17.9724 | 0.136762 | 1087.26
2 x HEB280 | 11017.9 | 18.2786 | 18.3039 | 0.139288 | 1107.34
4 x HEB280 | 11017.7 | 18.2783 | 18.3036 | 0.139285 | 1107.32
2 x HEB280 | 11017.9 | 18.2787 | 18.304 | 0.139288 | 1107.34

# IfcColumn: Hout C 75 x 200 (190)
In: 00 begane grond
Type - PredefinedType: COLUMN
Classification: Kolom (ARCHICAD Classification); 41.12 bekledingen (NL/SfB (4 cijfers)); Material: Hout C
Pset_ColumnCommon - Slope: 90 deg; IsExternal: yes; LoadBearing: no; Reference: Hout C 75 x 200
CPset_Phasing - Renovation Phase: Bestaand
Component Quantities - Hout C, Component Thickness: 75 mm; Hout C, Rectangular Component Height: 200 mm; Hout C, Rectangular Component Width: 75 mm; Hout C, Component Cross Section Area: 0.015 m2
BaseQuantities - Width: 75 mm; Depth: 200 mm; CrossSectionArea: 0.015 m2
Name | Hout C, Mass (kg) | Hout C, Component Volume (Net) (m3) = Hout C, Component Volume (Gross) (m3) = GrossVolume (m3) = NetVolume (m3) | Length (mm) | OuterSurfaceArea (m2) | TotalSurfaceArea (m2) = GrossSurfaceArea (m2)
182 x houten lamellen | 30.195 | 0.0549 | 3660 | 2.013 | 2.043
4 x houten lamellen | 9.1575 | 0.01665 | 1110 | 0.6105 | 0.6405
4 x houten lamellen | 8.02312 | 0.0145875 | 972.5 | 0.534875 | 0.564875

# IfcColumn: Hout C 75 x 250 (154)
In: 00 begane grond
Type - PredefinedType: COLUMN
Classification: Kolom (ARCHICAD Classification); 41.12 bekledingen (NL/SfB (4 cijfers)); Material: Hout C
Pset_ColumnCommon - Slope: 90 deg; IsExternal: yes; LoadBearing: no; Reference: Hout C 75 x 250
CPset_Phasing - Renovation Phase: Bestaand
BaseQuantities - Width: 75 mm; Depth: 250 mm; CrossSectionArea: 0.01875 m2
Component Quantities - Hout C, Component Thickness: 75 mm; Hout C, Rectangular Component Height: 250 mm; Hout C, Rectangular Component Width: 75 mm; Hout C, Component Cross Section Area: 0.01875 m2
Name | Length (mm) | OuterSurfaceArea (m2) | TotalSurfaceArea (m2) = GrossSurfaceArea (m2) | GrossVolume (m3) = NetVolume (m3) = Hout C, Component Volume (Net) (m3) = Hout C, Component Volume (Gross) (m3) | Hout C, Mass (kg)
63 x houten lamellen | 8100 | 5.265 | 5.3025 | 0.151875 | 83.5313
81 x houten lamellen | 8100 | 5.265 | 5.3025 | 0.151875 | 83.5312
5 x houten lamellen | 1110 | 0.7215 | 0.759 | 0.0208125 | 11.4469
5 x houten lamellen | 972.5 | 0.632125 | 0.669625 | 0.0182344 | 10.0289

# IfcColumn: Hout C 75 x 400 (8)
In: 00 begane grond
Type - PredefinedType: COLUMN
Classification: Kolom (ARCHICAD Classification); 41.12 bekledingen (NL/SfB (4 cijfers)); Material: Hout C
Pset_ColumnCommon - Slope: 90 deg; IsExternal: yes; LoadBearing: no; Reference: Hout C 75 x 400
CPset_Phasing - Renovation Phase: Bestaand
Component Quantities - Hout C, Mass: 133.65 kg; Hout C, Component Thickness: 75 mm; Hout C, Rectangular Component Height: 400 mm; Hout C, Rectangular Component Width: 75 mm; Hout C, Component Cross Section Area: 0.03 m2; Hout C, Component Volume (Net): 0.243 m3; Hout C, Component Volume (Gross): 0.243 m3
BaseQuantities - Length: 8100 mm; Width: 75 mm; Depth: 400 mm; CrossSectionArea: 0.03 m2; OuterSurfaceArea: 7.695 m2; TotalSurfaceArea: 7.755 m2; GrossSurfaceArea: 7.755 m2; GrossVolume: 0.243 m3; NetVolume: 0.243 m3

# IfcColumn: Metaal - Aluminium 20 x 22 (7)
In: 00 begane grond
Type - PredefinedType: COLUMN
Classification: Kolom (ARCHICAD Classification); Material: Metaal - Aluminium
Pset_ColumnCommon - Slope: 90 deg; IsExternal: yes; LoadBearing: no; Reference: Metaal - Aluminium 20 x 22
CPset_Phasing - Renovation Phase: Bestaand
BaseQuantities - Length: 1464 mm; Width: 20 mm; Depth: 22 mm; CrossSectionArea: 0.00044 m2
Component Quantities - Metaal - Aluminium, Component Thickness: 20 mm; Metaal - Aluminium, Rectangular Component Height: 22 mm; Metaal - Aluminium, Rectangular Component Width: 20 mm; Metaal - Aluminium, Component Cross Section Area: 0.00044 m2
Name | OuterSurfaceArea (m2) | TotalSurfaceArea (m2) = GrossSurfaceArea (m2) | GrossVolume (m3) = NetVolume (m3) = Metaal - Aluminium, Component Volume (Net) (m3) = Metaal - Aluminium, Component Volume (Gross) (m3) | Metaal - Aluminium, Mass (kg)
4 x Kolom-x | 0.090768 | 0.091608 | 0.00061488 | 1.72166
3 x Kolom-x | 0.122976 | 0.123856 | 0.00064416 | 1.80365

# IfcColumn: UNP300 100 x 300 (22)
In: 00 begane grond
Type - PredefinedType: COLUMN
Classification: 28.11 kolom-/liggerconstructies (NL/SfB (4 cijfers)); Kolom (ARCHICAD Classification); Material: Metaal - Staal C
Pset_ColumnCommon - Slope: 90 deg; IsExternal: yes; LoadBearing: yes; Reference: UNP300 100 x 300
CPset_Phasing - Renovation Phase: Bestaand
BaseQuantities - CrossSectionArea: 0.00544322 m2
Component Quantities - Metaal - Staal C, Component Cross Section Area: 0.00544322 m2
Name | Length (mm) | OuterSurfaceArea (m2) | TotalSurfaceArea (m2) = GrossSurfaceArea (m2) | GrossVolume (m3) = NetVolume (m3) = Metaal - Staal C, Component Volume (Net) (m3) = Metaal - Staal C, Component Volume (Gross) (m3) | Metaal - Staal C, Mass (kg)
8 x UNP300 | 6600 | 6.20176 | 6.21268 | 0.0360289 | 286.43
14 x UNP300 | 6500 | 6.1078 | 6.11871 | 0.035483 | 282.09

# IfcDoor: D1 27 (18)
In: 00 begane grond
Type - OperationType: SINGLE_SWING_LEFT; ParameterTakesPrecedence: no; Sizeable: no
Material - Deurblad: n.v.t.; Onderdorpel: n.v.t.; Stofdorpel: n.v.t.; Vensterbank: n.v.t.; Ventilatierooster: n.v.t.; Spouwlat: n.v.t.; Rollaag / Latei: n.v.t.; Afwerking dagkant buiten: n.v.t.; Afwerking dagkant binnen: n.v.t.; Zonwering - behuizing: n.v.t.; Zonwering - isolatie: n.v.t.; Glas: Glas - kozijn exterieur
Pset_DoorCommon - ThermalTransmittance: 0
CPset_Phasing - Renovation Phase: Bestaand
Name | OverallHeight (mm) | OverallWidth (mm) = Width (mm) | Classification | Frame / Draaiend deel | IsExternal | Component, Component Volume (Net) (m3) = Component, Component Volume (Gross) (m3) = Volume (m3) = NetVolume (m3) | Height (mm) | Perimeter (mm) | Area (m2) | Depth (mm) | SelfClosing
2 x aluminium loopdeur | 2367 | 1034 | 31 Buitenwandopeningen (NL/SfB (4 cijfers)); Deur (ARCHICAD Classification) | n.v.t. | yes | 0.125918 | 2387 | 6842 | 2.46816 | 400 | Pset_FireRatingProperties - FireResistanceRating: Zelfsluitend
aluminium loopdeur | 2600 | 1035 | Deur (ARCHICAD Classification) | Aluminium | no | 0.0521654 | 2600 | 7270 | 2.691 | 200 | Pset_FireRatingProperties - FireResistanceRating: Zelfsluitend; Pset_DoorCommon - GlazingAreaFraction: 1.72182
aluminium loopdeur | 2367 | 1034 | 31 Buitenwandopeningen (NL/SfB (4 cijfers)); Deur (ARCHICAD Classification) | n.v.t. | yes | 0.125918 | 2367 | 6802 | 2.44748 | 400 | Pset_FireRatingProperties - FireResistanceRating: Zelfsluitend
Bi-H05 | 2600 | 1034 | Deur (ARCHICAD Classification) | n.v.t. | no | 0.137862 | 2600 | 7268 | 2.6884 | 100 | no
Bi-H07 | 2600 | 1034 | Deur (ARCHICAD Classification) | n.v.t. | no | 0.137846 | 2600 | 7268 | 2.6884 | 100 | no
Bi-H11 | 2600 | 1034 | Deur (ARCHICAD Classification) | n.v.t. | no | 0.136928 | 2600 | 7268 | 2.6884 | 100 | no
Bi-H09 | 2600 | 1034 | Deur (ARCHICAD Classification) | n.v.t. | no | 0.136912 | 2600 | 7268 | 2.6884 | 100 | no
Bi-H12 | 2600 | 1034 | Deur (ARCHICAD Classification) | n.v.t. | no | 0.136912 | 2600 | 7268 | 2.6884 | 100 | no
Bi-H13 | 2600 | 1034 | Deur (ARCHICAD Classification) | n.v.t. | no | 0.136928 | 2600 | 7268 | 2.6884 | 100 | no
Bi-S07 | 2600 | 1034 | Deur (ARCHICAD Classification) | Aluminium | no | 0.039172 | 2600 | 7268 | 2.6884 | 100 | yes | Pset_FireRatingProperties - FireResistanceRating: Zelfsluitend; Pset_DoorCommon - GlazingAreaFraction: 1.90483
2 x Merk-x | 2367 | 1034 | Deur (ARCHICAD Classification) | n.v.t. | no | 0.125959 | 2367 | 6802 | 2.44748 | 120 | Pset_FireRatingProperties - FireResistanceRating: Zelfsluitend
Bi-H01 | 2600 | 1034 | Deur (ARCHICAD Classification) | n.v.t. | no | 0.136928 | 2600 | 7268 | 2.6884 | 100 | no
Bi-H02 | 2600 | 1034 | Deur (ARCHICAD Classification) | n.v.t. | no | 0.136928 | 2600 | 7268 | 2.6884 | 100 | no
Bi-H03 | 2600 | 1034 | Deur (ARCHICAD Classification) | n.v.t. | no | 0.136928 | 2600 | 7268 | 2.6884 | 100 | no
Bi-H04 | 2600 | 1034 | Deur (ARCHICAD Classification) | n.v.t. | no | 0.136912 | 2600 | 7268 | 2.6884 | 100 | no
Bi-H06 | 2600 | 1034 | Deur (ARCHICAD Classification) | n.v.t. | no | 0.136928 | 2600 | 7268 | 2.6884 | 100 | no

# IfcDoor: D1 27 (8)
In: 00 begane grond
Type - OperationType: SINGLE_SWING_RIGHT; ParameterTakesPrecedence: no; Sizeable: no
OverallWidth: 1034 mm
Material - Frame / Draaiend deel: n.v.t.; Deurblad: n.v.t.; Onderdorpel: n.v.t.; Stofdorpel: n.v.t.; Vensterbank: n.v.t.; Ventilatierooster: n.v.t.; Spouwlat: n.v.t.; Rollaag / Latei: n.v.t.; Afwerking dagkant buiten: n.v.t.; Afwerking dagkant binnen: n.v.t.; Zonwering - behuizing: n.v.t.; Zonwering - isolatie: n.v.t.; Glas: Glas - kozijn exterieur
Pset_DoorCommon - ThermalTransmittance: 0
CPset_Phasing - Renovation Phase: Bestaand
BaseQuantities - Width: 1034 mm
Name | OverallHeight (mm) | Classification | IsExternal | Height (mm) | Perimeter (mm) | Area (m2) | Volume (m3) = NetVolume (m3) = Component, Component Volume (Net) (m3) = Component, Component Volume (Gross) (m3) | Depth (mm)
aluminium loopdeur | 2367 | 31 Buitenwandopeningen (NL/SfB (4 cijfers)); Deur (ARCHICAD Classification) | yes | 2387 | 6842 | 2.46816 | 0.125918 | 400 | Pset_FireRatingProperties - FireResistanceRating: Zelfsluitend
Bi-H14 | 2600 | Deur (ARCHICAD Classification) | no | 2600 | 7268 | 2.6884 | 0.136928 | 100 | Pset_DoorCommon - SelfClosing: no
Bi-H10 | 2600 | Deur (ARCHICAD Classification) | no | 2600 | 7268 | 2.6884 | 0.136928 | 100 | Pset_DoorCommon - SelfClosing: no
Bi-H08 | 2600 | Deur (ARCHICAD Classification) | no | 2600 | 7268 | 2.6884 | 0.136928 | 100 | Pset_DoorCommon - SelfClosing: no
2 x Merk-x | 2367 | Deur (ARCHICAD Classification) | no | 2367 | 6802 | 2.44748 | 0.125959 | 120 | Pset_FireRatingProperties - FireResistanceRating: Zelfsluitend
2 x Merk-x | 2600 | Deur (ARCHICAD Classification) | no | 2600 | 7268 | 2.6884 | 0.137906 | 100

# IfcDoor: D1 garage hefdeur 27 (11)
In: 00 begane grond
Type - OperationType: ROLLINGUP; ParameterTakesPrecedence: no; Sizeable: no
OverallHeight: 6550 mm
Material - Frame / Draaiend deel: n.v.t.; Deurblad: n.v.t.; Onderdorpel: n.v.t.; Stofdorpel: n.v.t.; Spouwlat: n.v.t.; Rollaag / Latei: n.v.t.; Afwerking dagkant buiten: n.v.t.; Afwerking dagkant binnen: n.v.t.; Zonwering - behuizing: n.v.t.; Zonwering - isolatie: n.v.t.; Glas: Glas - kozijn exterieur
CPset_Phasing - Renovation Phase: Bestaand
BaseQuantities - Height: 4500 mm; Depth: 70 mm
Pset_DoorCommon - ThermalTransmittance: 0; IsExternal: yes
Name | OverallWidth (mm) | Classification | Width (mm) | Perimeter (mm) | Area (m2) | Volume (m3) = NetVolume (m3) = Component, Component Volume (Net) (m3) = Component, Component Volume (Gross) (m3)
Merk-x | 6820 | Deur (ARCHICAD Classification) | 6820 | 22640 | 30.69 | 2.19066
Merk-x | 6880.01 | Deur (ARCHICAD Classification) | 6880.01 | 22760 | 30.96 | 2.20974
2 x Merk-x | 6820 | Deur (ARCHICAD Classification) | 6720 | 22440 | 30.24 | 2.19066
Merk-x | 6820 | Deur (ARCHICAD Classification) | 6770 | 22540 | 30.465 | 2.19066
Merk-x | 6880 | Deur (ARCHICAD Classification) | 6880.01 | 22760 | 30.96 | 2.20974
2 x Merk-x | 6500 | Deur (ARCHICAD Classification) | 5200 | 19400 | 23.4 | 2.0889
Merk-x | 6500 | Deur (ARCHICAD Classification) | 6400 | 21800 | 28.8 | 2.0889
Merk-x | 6500 | Deur (ARCHICAD Classification); 31.30 algemeen (verzamelniveau) (NL/SfB (4 cijfers)) | 6400 | 21800 | 28.8 | 2.0889
Merk-x | 6800 | Deur (ARCHICAD Classification) | 6800 | 22600 | 30.6 | 2.1843

# IfcDoor: D1 zl1-b 27 (2)
In: 00 begane grond
Type - OperationType: SINGLE_SWING_LEFT; ParameterTakesPrecedence: no; Sizeable: no
OverallHeight: 2600 mm; OverallWidth: 1440 mm; Classification: Deur (ARCHICAD Classification)
Pset_DoorCommon - ThermalTransmittance: 0; GlazingAreaFraction: 2.73732; IsExternal: no
Material - Frame / Draaiend deel: Aluminium; Deurblad: n.v.t.; Onderdorpel: n.v.t.; Stofdorpel: n.v.t.; Vensterbank: n.v.t.; Ventilatierooster: n.v.t.; Spouwlat: n.v.t.; Rollaag / Latei: n.v.t.; Afwerking dagkant buiten: n.v.t.; Afwerking dagkant binnen: n.v.t.; Zonwering - behuizing: n.v.t.; Zonwering - isolatie: n.v.t.; Glas: Glas - kozijn interieur
Pset_FireRatingProperties - FireResistanceRating: Zelfsluitend
CPset_Phasing - Renovation Phase: Bestaand
Component Quantities - Component, Component Volume (Net): 0.0525958 m3; Component, Component Volume (Gross): 0.0525958 m3
BaseQuantities - Height: 2600 mm; Width: 1440 mm; Perimeter: 8080 mm; Area: 3.744 m2; Volume: 0.0525958 m3; Depth: 100 mm; NetVolume: 0.0525958 m3
Name | SelfClosing
Bi-S04 | no
Bi-S09 | yes

# IfcDoor: D1 zl2 27 (4)
In: 00 begane grond
Type - OperationType: USERDEFINED; ParameterTakesPrecedence: no; Sizeable: no
OverallHeight: 2600 mm; Classification: Deur (ARCHICAD Classification)
Material - Frame / Draaiend deel: Aluminium; Deurblad: n.v.t.; Onderdorpel: n.v.t.; Stofdorpel: n.v.t.; Vensterbank: n.v.t.; Ventilatierooster: n.v.t.; Spouwlat: n.v.t.; Rollaag / Latei: n.v.t.; Afwerking dagkant buiten: n.v.t.; Afwerking dagkant binnen: n.v.t.; Zonwering - behuizing: n.v.t.; Zonwering - isolatie: n.v.t.; Glas: Glas - kozijn interieur
CPset_Phasing - Renovation Phase: Bestaand
BaseQuantities - Height: 2600 mm; Depth: 100 mm
Pset_DoorCommon - ThermalTransmittance: 0; SelfClosing: no; IsExternal: no
Name | OverallWidth (mm) = Width (mm) | Perimeter (mm) | Area (m2) | Volume (m3) = NetVolume (m3) = Component, Component Volume (Net) (m3) = Component, Component Volume (Gross) (m3) | GlazingAreaFraction
Bi-S10 | 3770 | 12740 | 9.802 | 0.0830075 | 8.28846
Bi-S02 | 3770 | 12740 | 9.802 | 0.0830075 | 8.28846
Bi-S05 | 3880 | 12960 | 10.088 | 0.0839777 | 8.55829
Bi-S06 | 3770 | 12740 | 9.802 | 0.0830075 | 8.28846

# IfcDoor: DSn 27 (2)
In: 00 begane grond
Type - OperationType: USERDEFINED; ParameterTakesPrecedence: no; Sizeable: no
OverallHeight: 2600 mm; Classification: Deur (ARCHICAD Classification)
Pset_DoorCommon - ThermalTransmittance: 0
Material - Frame / Draaiend deel: Aluminium; Deurblad: n.v.t.; Onderdorpel: n.v.t.; Stofdorpel: n.v.t.; Vensterbank: n.v.t.; Ventilatierooster: n.v.t.; Spouwlat: n.v.t.; Rollaag / Latei: n.v.t.; Afwerking dagkant buiten: n.v.t.; Afwerking dagkant binnen: n.v.t.; Zonwering - behuizing: n.v.t.; Zonwering - isolatie: n.v.t.; Glas: Verf - wit
BaseQuantities - Height: 2600 mm
CPset_Phasing - Renovation Phase: Bestaand
Name | OverallWidth (mm) = Width (mm) | GlazingAreaFraction | IsExternal | Component, Component Volume (Net) (m3) = Component, Component Volume (Gross) (m3) = Volume (m3) = NetVolume (m3) | Perimeter (mm) | Area (m2) | Depth (mm)
aluminium loopdeur | 2400 | 4.71869 | yes | 0.0734124 | 10000 | 6.24 | 200
Bi-S01b | 2380 | 4.848 | no | 0.0552432 | 9960 | 6.188 | 100 | Pset_DoorCommon - SelfClosing: no

# IfcDoor: DV1 27, Bi-S06
In: 00 begane grond
Type - OperationType: FOLDING_TO_LEFT; ParameterTakesPrecedence: no; Sizeable: no
OverallHeight: 2600 mm; OverallWidth: 4770 mm; Classification: Deur (ARCHICAD Classification)
CPset_Phasing - Renovation Phase: Bestaand
Pset_DoorCommon - ThermalTransmittance: 0; SelfClosing: no; IsExternal: no
Material - Frame / Draaiend deel: n.v.t.; Deurblad: n.v.t.; Onderdorpel: n.v.t.; Stofdorpel: n.v.t.; Vensterbank: n.v.t.; Ventilatierooster: n.v.t.; Spouwlat: n.v.t.; Rollaag / Latei: n.v.t.; Afwerking dagkant buiten: n.v.t.; Afwerking dagkant binnen: n.v.t.; Zonwering - behuizing: n.v.t.; Zonwering - isolatie: n.v.t.; Glas: Verf - wit
BaseQuantities - Height: 2600 mm; Width: 4770 mm; Perimeter: 14740 mm; Area: 12.402 m2; Volume: 0.644775 m3; Depth: 100 mm; NetVolume: 0.644775 m3
Component Quantities - Component, Component Volume (Net): 0.644775 m3; Component, Component Volume (Gross): 0.644775 m3

# IfcFlowTerminal: Spot plafond 01 27 (40)
In: 00 begane grond
Classification: Verlichting - lamp (ARCHICAD Classification)
Component Quantities - Component, Component Volume (Net): 0.0000277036 m3; Component, Component Volume (Gross): 0.0000277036 m3
CPset_Phasing - Renovation Phase: Bestaand

# IfcFlowTerminal: TL plafond 27 (23)
In: 00 begane grond
Classification: Verlichting - lamp (ARCHICAD Classification)
Component Quantities - Component, Component Volume (Net): 0.00221184 m3; Component, Component Volume (Gross): 0.00221184 m3
CPset_Phasing - Renovation Phase: Bestaand

# IfcOpeningElement (74)
Name | In | Depth (mm) | Height (mm) | Width (mm) | Area (m2) | Volume (m3)
3 x aluminium loopdeur | 00 begane grond | 400 | 2387 | 1034 | 2.46816 | 0.125918
4 x Opening-x | 00 begane grond | 100 | 2500 | 6920 | 17.3 | 1.73 | Classification: Lege opening (ARCHICAD Classification); CPset_Phasing - Renovation Phase: Bestaand
2 x Opening-x | 00 begane grond | 100 | 2500 | 6980 | 17.45 | 1.745 | Classification: Lege opening (ARCHICAD Classification); CPset_Phasing - Renovation Phase: Bestaand
4 x Opening-x | 00 begane grond | 100 | 2500 | 6600 | 16.5 | 1.65 | Classification: Lege opening (ARCHICAD Classification); CPset_Phasing - Renovation Phase: Bestaand
Opening-x | 00 begane grond | 100 | 2500 | 6790 | 16.975 | 1.6975 | Classification: Lege opening (ARCHICAD Classification); CPset_Phasing - Renovation Phase: Bestaand
aluminium kozijn | 00 begane grond | 200 | 1600 | 15280 | 24.448 | 0.227277
aluminium loopdeur | 00 begane grond | 200 | 2600 | 1035 | 2.691 | 0.0521654
aluminium kozijn | 00 begane grond | 200 | 1600 | 11950 | 19.12 | 0.179851
aluminium kozijn | 00 begane grond | 200 | 1600 | 2915 | 4.664 | 0.0511747
2 x aluminium kozijn | 00 begane grond | 200 | 2600 | 1545 | 4.017 | 0.0392561
aluminium kozijn | 00 begane grond | 200 | 1600 | 4945 | 7.912 | 0.080086
aluminium kozijn | 00 begane grond | 200 | 1600 | 4825 | 7.72 | 0.0615819
aluminium loopdeur | 00 begane grond | 200 | 2600 | 2400 | 6.24 | 0.0734124
Bi-S01c | 00 begane grond | 100 | 2600 | 1142 | 2.9692 | 0.026385
Bi-S01b | 00 begane grond | 100 | 2600 | 2380 | 6.188 | 0.0552432
Bi-S01a | 00 begane grond | 100 | 2600 | 1142 | 2.9692 | 0.026385
aluminium loopdeur | 00 begane grond | 400 | 2367 | 1034 | 2.44748 | 0.125918
Bi-S10 | 00 begane grond | 100 | 2600 | 3770 | 9.802 | 0.0830075
Bi-S02 | 00 begane grond | 100 | 2600 | 3770 | 9.802 | 0.0830075
Bi-S04 | 00 begane grond | 100 | 2600 | 1440 | 3.744 | 0.0525958
Bi-H05 | 00 begane grond | 100 | 2600 | 1034 | 2.6884 | 0.137862
Bi-H07 | 00 begane grond | 100 | 2600 | 1034 | 2.6884 | 0.137846
Bi-H14 | 00 begane grond | 100 | 2600 | 1034 | 2.6884 | 0.136928
Bi-S09 | 00 begane grond | 100 | 2600 | 1440 | 3.744 | 0.0525958
Bi-H11 | 00 begane grond | 100 | 2600 | 1034 | 2.6884 | 0.136928
Bi-H10 | 00 begane grond | 100 | 2600 | 1034 | 2.6884 | 0.136928
Bi-H08 | 00 begane grond | 100 | 2600 | 1034 | 2.6884 | 0.136928
Bi-H12 | 00 begane grond | 100 | 2600 | 1034 | 2.6884 | 0.136912
Bi-H09 | 00 begane grond | 100 | 2600 | 1034 | 2.6884 | 0.136912
Bi-H13 | 00 begane grond | 100 | 2600 | 1034 | 2.6884 | 0.136928
Bi-S06 | 00 begane grond | 100 | 2600 | 4770 | 12.402 | 0.644775
Bi-S07 | 00 begane grond | 100 | 2600 | 1034 | 2.6884 | 0.039172
Bi-S08 | 00 begane grond | 100 | 1575 | 1730 | 2.72475 | 0.0295995
4 x Merk-x | 00 begane grond | 120 | 2367 | 1034 | 2.44748 | 0.125959
Bi-S06 | 00 begane grond | 100 | 2600 | 3770 | 9.802 | 0.0830075
Bi-S03 | 00 begane grond | 100 | 2600 | 3880 | 10.088 | 0.04692
Bi-S05 | 00 begane grond | 100 | 2600 | 3880 | 10.088 | 0.0839777
Bi-H02 | 00 begane grond | 100 | 2600 | 1034 | 2.6884 | 0.136928
Bi-H03 | 00 begane grond | 100 | 2600 | 1034 | 2.6884 | 0.136928
Bi-H01 | 00 begane grond | 100 | 2600 | 1034 | 2.6884 | 0.136928
Bi-H04 | 00 begane grond | 100 | 2600 | 1034 | 2.6884 | 0.136912
Bi-H06 | 00 begane grond | 100 | 2600 | 1034 | 2.6884 | 0.136928
Bi-S11 | 00 begane grond | 100 | 2600 | 3880 | 10.088 | 0.04692
2 x Merk-x | 00 begane grond | 100 | 2600 | 1034 | 2.6884 | 0.137906
15 x Merk-x | 01 dak | 100 | 800 | 800 | 0.64 | 0.064
solatube | 01 dak | 100 | 800 | 800 | 0.64 | 0.064

# IfcRailing: Railing Type (5)
Type - PredefinedType: BALUSTRADE
Classification: Balustrade (ARCHICAD Classification)
CPset_Phasing - Renovation Phase: Bestaand
Pset_RailingCommon - IsExternal: yes
Name | In | Material | GrossVolume (m3) = NetVolume (m3) | Length (mm) | Metaal - RVS 2, Mass (kg) | Metaal - RVS 2, Component Volume (Net) (m3) = Metaal - RVS 2, Component Volume (Gross) (m3) | Metaal - RVS 1, Mass (kg) | Metaal - RVS 1, Component Volume (Net) (m3) = Metaal - RVS 1, Component Volume (Gross) (m3) | Metaal - Aluminium C 1, Mass (kg) = Metaal - Aluminium C 2, Mass (kg) | Metaal - Aluminium C 1, Component Volume (Net) (m3) = Metaal - Aluminium C 1, Component Volume (Gross) (m3) = Metaal - Aluminium C 2, Component Volume (Net) (m3) = Metaal - Aluminium C 2, Component Volume (Gross) (m3) | Metaal - Staal C 1, Mass (kg) = Metaal - Staal C 2, Mass (kg) | Metaal - Staal C 1, Component Volume (Net) (m3) = Metaal - Staal C 1, Component Volume (Gross) (m3) = Metaal - Staal C 2, Component Volume (Net) (m3) = Metaal - Staal C 2, Component Volume (Gross) (m3)
Reling-x | 00 begane grond | Metaal - RVS (6), Metaal - Aluminium C (4) | 0.450624 | 25090 | 0.2528 | 0.000032 | 170.387 | 0.021568 | 60.3904 | 0.021568 | Component Quantities - Metaal - RVS 5, Mass: 1268.55 kg; Metaal - RVS 5, Component Volume (Net): 0.160576 m3; Metaal - RVS 5, Component Volume (Gross): 0.160576 m3; Metaal - RVS 6, Mass: 1268.55 kg; Metaal - RVS 6, Component Volume (Net): 0.160576 m3; Metaal - RVS 6, Component Volume (Gross): 0.160576 m3; Metaal - Aluminium C 3, Mass: 60.3904 kg; Metaal - Aluminium C 3, Component Volume (Net): 0.021568 m3; Metaal - Aluminium C 3, Component Volume (Gross): 0.021568 m3; Metaal - Aluminium C 4, Mass: 60.3904 kg; Metaal - Aluminium C 4, Component Volume (Net): 0.021568 m3; Metaal - Aluminium C 4, Component Volume (Gross): 0.021568 m3; Metaal - RVS 4, Mass: 0.2528 kg; Metaal - RVS 4, Component Volume (Net): 0.000032 m3; Metaal - RVS 4, Component Volume (Gross): 0.000032 m3; Metaal - RVS 3, Mass: 170.387 kg; Metaal - RVS 3, Component Volume (Net): 0.021568 m3; Metaal - RVS 3, Component Volume (Gross): 0.021568 m3
2 x Reling-x | 01 dak | Metaal - Staal C (2), Metaal - RVS (2), Metaal - Aluminium C (2) | 0.0304 | 6000 | 75.84 | 0.0096 | 75.84 | 0.0096 | 7.84 | 0.0028 | 22.26 | 0.0028
2 x Reling-x | 01 dak | Metaal - Staal C (2), Metaal - RVS (2), Metaal - Aluminium C | 0.016272 | 2460 | 31.0944 | 0.003936 | 31.0944 | 0.003936 |  |  | 22.26 | 0.0028 | Component Quantities - Metaal - Aluminium C, Mass: 7.84 kg; Metaal - Aluminium C, Component Volume (Net): 0.0028 m3; Metaal - Aluminium C, Component Volume (Gross): 0.0028 m3

# IfcRoof (4)
In: 01 dak
Classification: 27.11 vlakke daken (NL/SfB (4 cijfers)); Dak (ARCHICAD Classification); Material: Isolatie - PIR
Pset_RoofCommon - IsExternal: yes
CPset_Phasing - Renovation Phase: Bestaand
Component Quantities - Isolatie - PIR, Component Thickness: 100 mm
Name | TotalArea (m2) = Isolatie - PIR, Projected Component Area (Net) (m2) = TotalSurfaceArea (m2) | Isolatie - PIR, Mass (kg) | Isolatie - PIR, Projected Component Area (Gross) (m2) | Isolatie - PIR, Component Volume (Net) (m3) | Isolatie - PIR, Component Volume (Gross) (m3)
2 x dakisolatie | 1179.08 | 18864.4 | 1179.08 | 117.902 | 117.902
dakisolatie | 1044.79 | 16715.7 | 1052.79 | 104.473 | 105.274
dakisolatie | 1052.79 | 16843.8 | 1052.79 | 105.274 | 105.274

# IfcRoof: FLAT_ROOF (4)
In: 01 dak
Classification: Plat dak (ARCHICAD Classification); 27.11 vlakke daken (NL/SfB (4 cijfers)); Material: Metaal - Staal AFW
Pset_RoofCommon - IsExternal: no
CPset_Phasing - Renovation Phase: Bestaand
Name | TotalArea (m2) | Metaal - Staal AFW, Mass (kg) | Metaal - Staal AFW, Component Volume (Net) (m3) | Metaal - Staal AFW, Component Volume (Gross) (m3)
stalen dakplaat | 4105.7 | 11423.7 | 1.43694 | 1.66702
stalen dakplaat | 4105.71 | 11423.7 | 1.43695 | 1.66702
stalen dakplaat | 3339.61 | 9291.93 | 1.1688 | 1.34617
stalen dakplaat | 3364.58 | 9361.55 | 1.17755 | 1.34617

# IfcSlab: ALG - ALGEMEEN 70, Vloer-x
In: 00 begane grond
Classification: Vloer (ARCHICAD Classification); Material: ALG - ALGEMEEN
Pset_SlabCommon - IsExternal: yes; LoadBearing: no
CPset_Phasing - Renovation Phase: Bestaand
Component Quantities - ALG - ALGEMEEN, Mass: 171.808 kg; ALG - ALGEMEEN, Projected Component Area (Net): 3.068 m2; ALG - ALGEMEEN, Projected Component Area (Gross): 3.068 m2; ALG - ALGEMEEN, Component Thickness: 70 mm; ALG - ALGEMEEN, Component Volume (Net): 0.21476 m3; ALG - ALGEMEEN, Component Volume (Gross): 0.21476 m3
BaseQuantities - Width: 70 mm; Perimeter: 7320 mm; GrossArea: 3.068 m2; NetArea: 3.068 m2; GrossVolume: 0.21476 m3; NetVolume: 0.21476 m3

# IfcSlab: Cement 20 (2)
In: 00 begane grond
Material: Cement
Pset_SlabCommon - IsExternal: no; LoadBearing: yes
CPset_Phasing - Renovation Phase: Bestaand
Component Quantities - Cement, Component Thickness: 20 mm
BaseQuantities - Width: 20 mm
Name | Classification | Cement, Mass (kg) | Cement, Projected Component Area (Net) (m2) = NetArea (m2) | Cement, Projected Component Area (Gross) (m2) | Cement, Component Volume (Net) (m3) = NetVolume (m3) | Cement, Component Volume (Gross) (m3) | Perimeter (mm) | GrossArea (m2) | GrossVolume (m3)
pantserdekvloer | Vloer (ARCHICAD Classification); 43.21 afwerklagen (NL/SfB (4 cijfers)) | 92058.7 | 2422.6 | 2428 | 48.4519 | 48.5599 | 199200 | 2422.8 | 48.456
pantserdekvloer | Vloer (ARCHICAD Classification) | 103919 | 2734.72 | 2734.72 | 54.6943 | 54.6943 | 213600 | 2734.92 | 54.6984

# IfcSlab: Grind 50 (3)
In: 01 dak
Classification: Vloer (ARCHICAD Classification); Material: Grind
Pset_SlabCommon - IsExternal: yes; LoadBearing: no
BaseQuantities - Width: 50 mm
CPset_Phasing - Renovation Phase: Bestaand
Component Quantities - Grind, Component Thickness: 50 mm
Name | Perimeter (mm) | GrossArea (m2) | NetArea (m2) | GrossVolume (m3) | NetVolume (m3) = Grind, Component Volume (Net) (m3) | Grind, Mass (kg) | Grind, Projected Component Area (Net) (m2) | Grind, Projected Component Area (Gross) (m2) | Grind, Component Volume (Gross) (m3)
Vloer-x | 61778 | 238.471 | 17.8028 | 11.9263 | 0.89292 | 1607.26 | 17.8711 | 238.331 | 11.9159
Vloer-x | 25564 | 31.8269 | 27.2457 | 1.59134 | 1.36228 | 2452.11 | 27.2457 | 31.8269 | 1.59134
Vloer-x | 6000 | 2.16 | 2.16 | 0.108 | 0.108 | 194.4 | 2.16 | 2.16 | 0.108

# IfcSlab: Hout - Hardhout 40, Vloer-x
In: 00 begane grond
Classification: Vloer (ARCHICAD Classification); Material: Hout - Hardhout
CPset_Phasing - Renovation Phase: Bestaand
Component Quantities - Hout - Hardhout, Mass: 15.54 kg; Hout - Hardhout, Projected Component Area (Net): 0.555 m2; Hout - Hardhout, Projected Component Area (Gross): 0.555 m2; Hout - Hardhout, Component Thickness: 40 mm; Hout - Hardhout, Component Volume (Net): 0.0222 m3; Hout - Hardhout, Component Volume (Gross): 0.0222 m3
BaseQuantities - Width: 40 mm; Perimeter: 4300 mm; GrossArea: 0.555 m2; NetArea: 0.555 m2; GrossVolume: 0.0222 m3; NetVolume: 0.0222 m3
Pset_SlabCommon - IsExternal: no; LoadBearing: no

# IfcSlab: Hout - Hardhout 50 (8)
In: 00 begane grond
Classification: Vloer (ARCHICAD Classification); Material: Hout - Hardhout
BaseQuantities - Width: 50 mm
Component Quantities - Hout - Hardhout, Component Thickness: 50 mm
CPset_Phasing - Renovation Phase: Bestaand
Pset_SlabCommon - IsExternal: no; LoadBearing: no
Name | Perimeter (mm) | GrossArea (m2) = NetArea (m2) = Hout - Hardhout, Projected Component Area (Net) (m2) = Hout - Hardhout, Projected Component Area (Gross) (m2) | GrossVolume (m3) = NetVolume (m3) = Hout - Hardhout, Component Volume (Net) (m3) = Hout - Hardhout, Component Volume (Gross) (m3) | Hout - Hardhout, Mass (kg)
2 x Vloer-x | 4730 | 0.433 | 0.02165 | 15.155
4 x Vloer-x | 8124 | 0.7724 | 0.03862 | 27.034
2 x Vloer-x | 2332 | 0.166 | 0.0083 | 5.81

# IfcSlab: Metaal - Aluminium AFW 50 (3)
In: 00 begane grond
Classification: Vloer (ARCHICAD Classification); 52.11 afvoerinstallatie; in het gebouw (NL/SfB (4 cijfers)); Material: Metaal - Aluminium AFW
CPset_Phasing - Renovation Phase: Bestaand
Component Quantities - Metaal - Aluminium AFW, Mass: 252 kg; Metaal - Aluminium AFW, Projected Component Area (Net): 1.8 m2; Metaal - Aluminium AFW, Projected Component Area (Gross): 1.8 m2; Metaal - Aluminium AFW, Component Thickness: 50 mm; Metaal - Aluminium AFW, Component Volume (Net): 0.09 m3; Metaal - Aluminium AFW, Component Volume (Gross): 0.09 m3
BaseQuantities - Width: 50 mm; Perimeter: 12600 mm; GrossArea: 1.8 m2; NetArea: 1.8 m2; GrossVolume: 0.09 m3; NetVolume: 0.09 m3
Pset_SlabCommon - IsExternal: no; LoadBearing: yes

# IfcSlab: Profielplaat 27 (6)
In: 00 begane grond
Classification: Vloer (ARCHICAD Classification); 27.21 vlakke daken (NL/SfB (4 cijfers)); Material: Metaal - Staal AFW
CPset_Phasing - Renovation Phase: Bestaand
Name | Metaal - Staal AFW, Mass (kg) | Metaal - Staal AFW, Component Volume (Net) (m3) = Metaal - Staal AFW, Component Volume (Gross) (m3)
plafondafwerking_01 | 309.773 | 0.0389652
plafondafwerking_01 | 303.754 | 0.0382081
plafondafwerking_01 | 46.4182 | 0.00583877
plafondafwerking_01 | 25.5162 | 0.00320958
plafondafwerking_01 | 74.0264 | 0.00931149
plafondafwerking_01 | 150.703 | 0.0189564

# IfcSlab: Slab 10, 17_WSP_FD_beton - fundatiepaal v21-2:ø300 (schroef):1528049
In: -2 fundering
Classification: Vloerplaat - fundering (ARCHICAD Classification); Material: WSP_beton - ihwg beton
Pset_SlabCommon - Reference: ø300 (schroef); IsExternal: yes; LoadBearing: no
Pset_ReinforcementBarPitchOfSlab - Reference: ø300 (schroef)
CPset_Phasing - Renovation Phase: Bestaand
Component Quantities - WSP_beton - ihwg beton, Mass: 903.056 kg; WSP_beton - ihwg beton, Component Volume (Net): 0.392633 m3; WSP_beton - ihwg beton, Component Volume (Gross): 0.392633 m3

# IfcSlab: Slab 100, 17_WSP_FD_beton - fundatiepaal v21-2:ø300 (schroef):1473540
In: -2 fundering
Classification: Vloerplaat - fundering (ARCHICAD Classification); Material: WSP_beton - ihwg beton
Pset_SlabCommon - Reference: ø300 (schroef); IsExternal: yes; LoadBearing: no
Component Quantities - WSP_beton - ihwg beton, Mass: 903.056 kg; WSP_beton - ihwg beton, Component Volume (Net): 0.392633 m3; WSP_beton - ihwg beton, Component Volume (Gross): 0.392633 m3
Pset_ReinforcementBarPitchOfSlab - Reference: ø300 (schroef)
CPset_Phasing - Renovation Phase: Bestaand

# IfcSlab: Slab 101, 17_WSP_FD_beton - fundatiepaal v21-2:ø300 (schroef):1473541
In: -2 fundering
Classification: Vloerplaat - fundering (ARCHICAD Classification); Material: WSP_beton - ihwg beton
Pset_ReinforcementBarPitchOfSlab - Reference: ø300 (schroef)
Pset_SlabCommon - Reference: ø300 (schroef); IsExternal: yes; LoadBearing: no
Component Quantities - WSP_beton - ihwg beton, Mass: 903.056 kg; WSP_beton - ihwg beton, Component Volume (Net): 0.392633 m3; WSP_beton - ihwg beton, Component Volume (Gross): 0.392633 m3
CPset_Phasing - Renovation Phase: Bestaand

# IfcSlab: Slab 102, 17_WSP_FD_beton - fundatiepaal v21-2:ø300 (schroef):1473546
In: -2 fundering
Classification: Vloerplaat - fundering (ARCHICAD Classification); Material: WSP_beton - ihwg beton
Pset_SlabCommon - Reference: ø300 (schroef); IsExternal: yes; LoadBearing: no
Pset_ReinforcementBarPitchOfSlab - Reference: ø300 (schroef)
CPset_Phasing - Renovation Phase: Bestaand
Component Quantities - WSP_beton - ihwg beton, Mass: 903.056 kg; WSP_beton - ihwg beton, Component Volume (Net): 0.392633 m3; WSP_beton - ihwg beton, Component Volume (Gross): 0.392633 m3

# IfcSlab: Slab 103, 17_WSP_FD_beton - fundatiepaal v21-2:ø300 (schroef):1473547
In: -2 fundering
Classification: Vloerplaat - fundering (ARCHICAD Classification); Material: WSP_beton - ihwg beton
Pset_SlabCommon - Reference: ø300 (schroef); IsExternal: yes; LoadBearing: no
CPset_Phasing - Renovation Phase: Bestaand
Component Quantities - WSP_beton - ihwg beton, Mass: 903.056 kg; WSP_beton - ihwg beton, Component Volume (Net): 0.392633 m3; WSP_beton - ihwg beton, Component Volume (Gross): 0.392633 m3
Pset_ReinforcementBarPitchOfSlab - Reference: ø300 (schroef)

# IfcSlab: Slab 104, 17_WSP_FD_beton - fundatiepaal v21-2:ø300 (schroef):1473544
In: -2 fundering
Classification: Vloerplaat - fundering (ARCHICAD Classification); Material: WSP_beton - ihwg beton
Pset_SlabCommon - Reference: ø300 (schroef); IsExternal: yes; LoadBearing: no
Component Quantities - WSP_beton - ihwg beton, Mass: 903.056 kg; WSP_beton - ihwg beton, Component Volume (Net): 0.392633 m3; WSP_beton - ihwg beton, Component Volume (Gross): 0.392633 m3
CPset_Phasing - Renovation Phase: Bestaand
Pset_ReinforcementBarPitchOfSlab - Reference: ø300 (schroef)

# IfcSlab: Slab 105, 17_WSP_FD_beton - fundatiepaal v21-2:ø300 (schroef):1473545
In: -2 fundering
Classification: Vloerplaat - fundering (ARCHICAD Classification); Material: WSP_beton - ihwg beton
Pset_SlabCommon - Reference: ø300 (schroef); IsExternal: yes; LoadBearing: no
Pset_ReinforcementBarPitchOfSlab - Reference: ø300 (schroef)
Component Quantities - WSP_beton - ihwg beton, Mass: 903.056 kg; WSP_beton - ihwg beton, Component Volume (Net): 0.392633 m3; WSP_beton - ihwg beton, Component Volume (Gross): 0.392633 m3
CPset_Phasing - Renovation Phase: Bestaand

# IfcSlab: Slab 106, 17_WSP_FD_beton - fundatiepaal v21-2:ø300 (schroef):1473550
In: -2 fundering
Classification: Vloerplaat - fundering (ARCHICAD Classification); Material: WSP_beton - ihwg beton
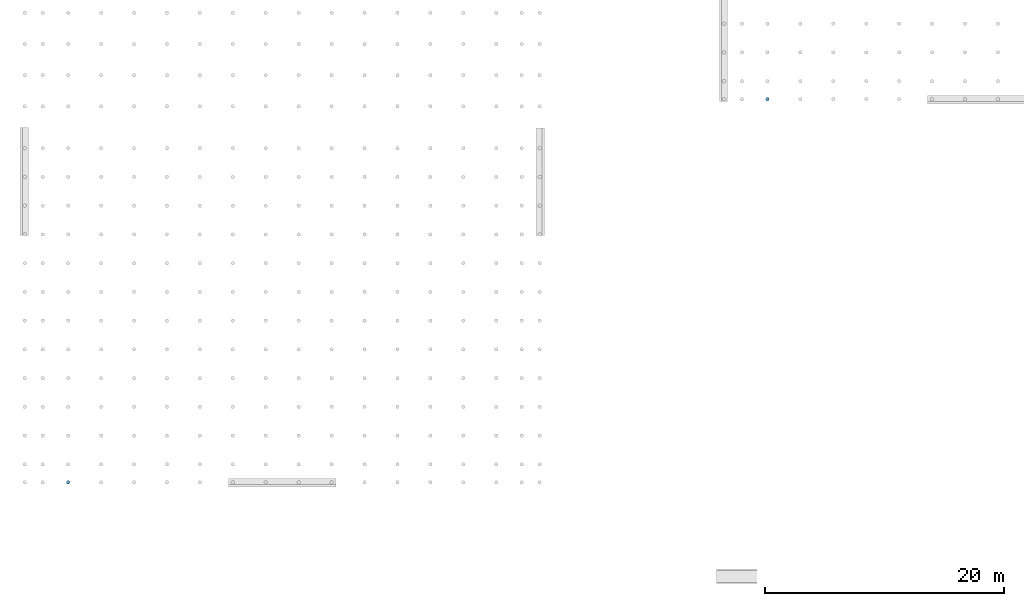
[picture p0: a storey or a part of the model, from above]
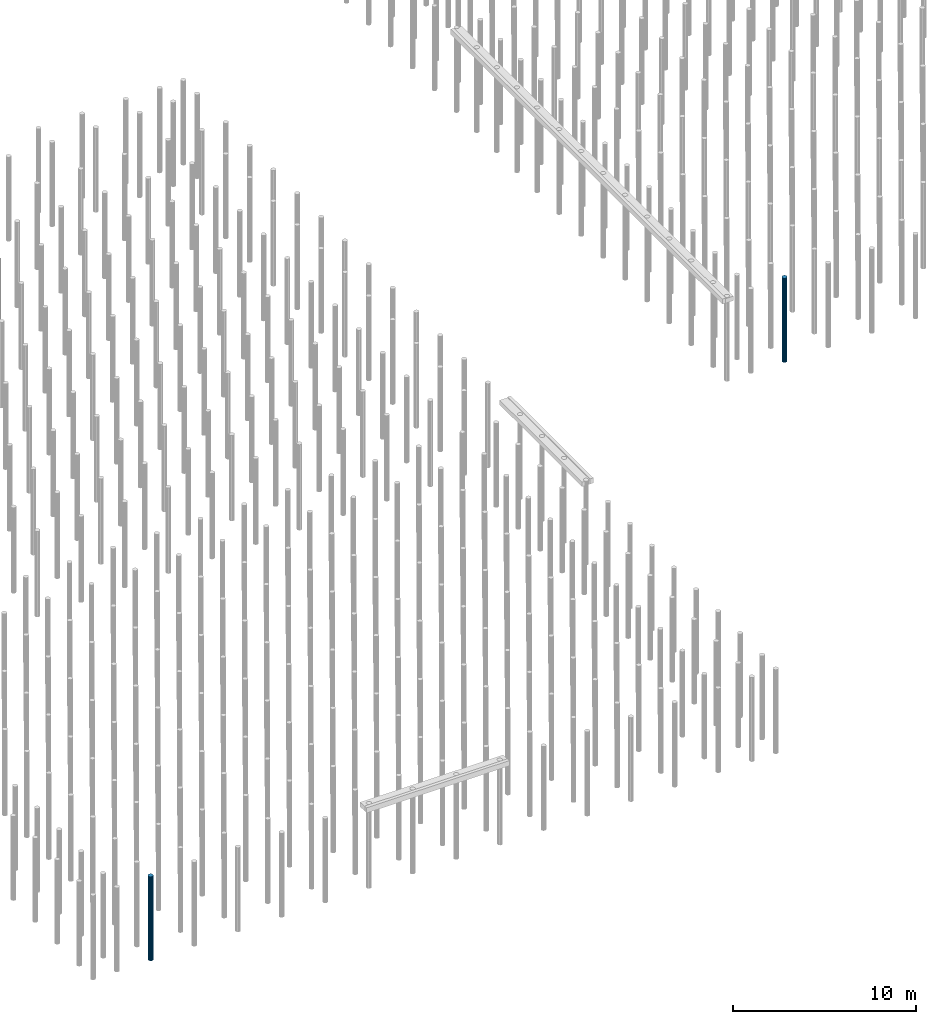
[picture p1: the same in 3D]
Properties of the parts of a building model (IFC2X3), part 3 of 13

# IfcSlab: Slab 106, 17_WSP_FD_beton - fundatiepaal v21-2:ø300 (schroef):1473550
Pset_SlabCommon - Reference: ø300 (schroef); IsExternal: yes; LoadBearing: no
Component Quantities - WSP_beton - ihwg beton, Mass: 903.056 kg; WSP_beton - ihwg beton, Component Volume (Net): 0.392633 m3; WSP_beton - ihwg beton, Component Volume (Gross): 0.392633 m3
CPset_Phasing - Renovation Phase: Bestaand
Pset_ReinforcementBarPitchOfSlab - Reference: ø300 (schroef)

# IfcSlab: Slab 107, 17_WSP_FD_beton - fundatiepaal v21-2:ø300 (schroef):1473551
In: -2 fundering
Classification: Vloerplaat - fundering (ARCHICAD Classification); Material: WSP_beton - ihwg beton
Pset_SlabCommon - Reference: ø300 (schroef); IsExternal: yes; LoadBearing: no
Pset_ReinforcementBarPitchOfSlab - Reference: ø300 (schroef)
Component Quantities - WSP_beton - ihwg beton, Mass: 903.056 kg; WSP_beton - ihwg beton, Component Volume (Net): 0.392633 m3; WSP_beton - ihwg beton, Component Volume (Gross): 0.392633 m3
CPset_Phasing - Renovation Phase: Bestaand

# IfcSlab: Slab 108, 17_WSP_FD_beton - fundatiepaal v21-2:ø300 (schroef):1473548
In: -2 fundering
Classification: Vloerplaat - fundering (ARCHICAD Classification); Material: WSP_beton - ihwg beton
Pset_ReinforcementBarPitchOfSlab - Reference: ø300 (schroef)
Pset_SlabCommon - Reference: ø300 (schroef); IsExternal: yes; LoadBearing: no
Component Quantities - WSP_beton - ihwg beton, Mass: 903.056 kg; WSP_beton - ihwg beton, Component Volume (Net): 0.392633 m3; WSP_beton - ihwg beton, Component Volume (Gross): 0.392633 m3
CPset_Phasing - Renovation Phase: Bestaand

# IfcSlab: Slab 109, 17_WSP_FD_beton - fundatiepaal v21-2:ø300 (schroef):1473549
In: -2 fundering
Classification: Vloerplaat - fundering (ARCHICAD Classification); Material: WSP_beton - ihwg beton
Pset_SlabCommon - Reference: ø300 (schroef); IsExternal: yes; LoadBearing: no
Pset_ReinforcementBarPitchOfSlab - Reference: ø300 (schroef)
CPset_Phasing - Renovation Phase: Bestaand
Component Quantities - WSP_beton - ihwg beton, Mass: 903.056 kg; WSP_beton - ihwg beton, Component Volume (Net): 0.392633 m3; WSP_beton - ihwg beton, Component Volume (Gross): 0.392633 m3

# IfcSlab: Slab 11, 17_WSP_FD_beton - fundatiepaal v21-2:ø300 (schroef):1528048
In: -2 fundering
Classification: Vloerplaat - fundering (ARCHICAD Classification); Material: WSP_beton - ihwg beton
CPset_Phasing - Renovation Phase: Bestaand
Pset_ReinforcementBarPitchOfSlab - Reference: ø300 (schroef)
Pset_SlabCommon - Reference: ø300 (schroef); IsExternal: yes; LoadBearing: no
Component Quantities - WSP_beton - ihwg beton, Mass: 903.056 kg; WSP_beton - ihwg beton, Component Volume (Net): 0.392633 m3; WSP_beton - ihwg beton, Component Volume (Gross): 0.392633 m3

# IfcSlab: Slab 110, 17_WSP_FD_beton - fundatiepaal v21-2:ø300 (schroef):1473554
In: -2 fundering
Classification: Vloerplaat - fundering (ARCHICAD Classification); Material: WSP_beton - ihwg beton
Pset_SlabCommon - Reference: ø300 (schroef); IsExternal: yes; LoadBearing: no
CPset_Phasing - Renovation Phase: Bestaand
Pset_ReinforcementBarPitchOfSlab - Reference: ø300 (schroef)
Component Quantities - WSP_beton - ihwg beton, Mass: 903.056 kg; WSP_beton - ihwg beton, Component Volume (Net): 0.392633 m3; WSP_beton - ihwg beton, Component Volume (Gross): 0.392633 m3

# IfcSlab: Slab 111, 17_WSP_FD_beton - fundatiepaal v21-2:ø300 (schroef):1473555
In: -2 fundering
Classification: Vloerplaat - fundering (ARCHICAD Classification); Material: WSP_beton - ihwg beton
Pset_SlabCommon - Reference: ø300 (schroef); IsExternal: yes; LoadBearing: no
CPset_Phasing - Renovation Phase: Bestaand
Pset_ReinforcementBarPitchOfSlab - Reference: ø300 (schroef)
Component Quantities - WSP_beton - ihwg beton, Mass: 903.056 kg; WSP_beton - ihwg beton, Component Volume (Net): 0.392633 m3; WSP_beton - ihwg beton, Component Volume (Gross): 0.392633 m3

# IfcSlab: Slab 112, 17_WSP_FD_beton - fundatiepaal v21-2:ø300 (schroef):1473552
In: -2 fundering
Classification: Vloerplaat - fundering (ARCHICAD Classification); Material: WSP_beton - ihwg beton
Pset_SlabCommon - Reference: ø300 (schroef); IsExternal: yes; LoadBearing: no
Pset_ReinforcementBarPitchOfSlab - Reference: ø300 (schroef)
CPset_Phasing - Renovation Phase: Bestaand
Component Quantities - WSP_beton - ihwg beton, Mass: 903.056 kg; WSP_beton - ihwg beton, Component Volume (Net): 0.392633 m3; WSP_beton - ihwg beton, Component Volume (Gross): 0.392633 m3

# IfcSlab: Slab 113, 17_WSP_FD_beton - fundatiepaal v21-2:ø300 (schroef):1473553
In: -2 fundering
Classification: Vloerplaat - fundering (ARCHICAD Classification); Material: WSP_beton - ihwg beton
Pset_SlabCommon - Reference: ø300 (schroef); IsExternal: yes; LoadBearing: no
CPset_Phasing - Renovation Phase: Bestaand
Component Quantities - WSP_beton - ihwg beton, Mass: 903.056 kg; WSP_beton - ihwg beton, Component Volume (Net): 0.392633 m3; WSP_beton - ihwg beton, Component Volume (Gross): 0.392633 m3
Pset_ReinforcementBarPitchOfSlab - Reference: ø300 (schroef)

# IfcSlab: Slab 114, 17_WSP_FD_beton - fundatiepaal v21-2:ø300 (schroef):1473558
In: -2 fundering
Classification: Vloerplaat - fundering (ARCHICAD Classification); Material: WSP_beton - ihwg beton
Pset_SlabCommon - Reference: ø300 (schroef); IsExternal: yes; LoadBearing: no
Component Quantities - WSP_beton - ihwg beton, Mass: 903.056 kg; WSP_beton - ihwg beton, Component Volume (Net): 0.392633 m3; WSP_beton - ihwg beton, Component Volume (Gross): 0.392633 m3
CPset_Phasing - Renovation Phase: Bestaand
Pset_ReinforcementBarPitchOfSlab - Reference: ø300 (schroef)

# IfcSlab: Slab 115, 17_WSP_FD_beton - fundatiepaal v21-2:ø300 (schroef):1473559
In: -2 fundering
Classification: Vloerplaat - fundering (ARCHICAD Classification); Material: WSP_beton - ihwg beton
Pset_ReinforcementBarPitchOfSlab - Reference: ø300 (schroef)
CPset_Phasing - Renovation Phase: Bestaand
Pset_SlabCommon - Reference: ø300 (schroef); IsExternal: yes; LoadBearing: no
Component Quantities - WSP_beton - ihwg beton, Mass: 903.056 kg; WSP_beton - ihwg beton, Component Volume (Net): 0.392633 m3; WSP_beton - ihwg beton, Component Volume (Gross): 0.392633 m3

# IfcSlab: Slab 116, 17_WSP_FD_beton - fundatiepaal v21-2:ø300 (schroef):1473556
In: -2 fundering
Classification: Vloerplaat - fundering (ARCHICAD Classification); Material: WSP_beton - ihwg beton
Pset_SlabCommon - Reference: ø300 (schroef); IsExternal: yes; LoadBearing: no
Component Quantities - WSP_beton - ihwg beton, Mass: 903.056 kg; WSP_beton - ihwg beton, Component Volume (Net): 0.392633 m3; WSP_beton - ihwg beton, Component Volume (Gross): 0.392633 m3
CPset_Phasing - Renovation Phase: Bestaand
Pset_ReinforcementBarPitchOfSlab - Reference: ø300 (schroef)

# IfcSlab: Slab 117, 17_WSP_FD_beton - fundatiepaal v21-2:ø300 (schroef):1473557
In: -2 fundering
Classification: Vloerplaat - fundering (ARCHICAD Classification); Material: WSP_beton - ihwg beton
Pset_ReinforcementBarPitchOfSlab - Reference: ø300 (schroef)
Pset_SlabCommon - Reference: ø300 (schroef); IsExternal: yes; LoadBearing: no
CPset_Phasing - Renovation Phase: Bestaand
Component Quantities - WSP_beton - ihwg beton, Mass: 903.056 kg; WSP_beton - ihwg beton, Component Volume (Net): 0.392633 m3; WSP_beton - ihwg beton, Component Volume (Gross): 0.392633 m3

# IfcSlab: Slab 118, 17_WSP_FD_beton - fundatiepaal v21-2:ø300 (schroef):1473562
In: -2 fundering
Classification: Vloerplaat - fundering (ARCHICAD Classification); Material: WSP_beton - ihwg beton
Pset_ReinforcementBarPitchOfSlab - Reference: ø300 (schroef)
Pset_SlabCommon - Reference: ø300 (schroef); IsExternal: yes; LoadBearing: no
Component Quantities - WSP_beton - ihwg beton, Mass: 903.056 kg; WSP_beton - ihwg beton, Component Volume (Net): 0.392633 m3; WSP_beton - ihwg beton, Component Volume (Gross): 0.392633 m3
CPset_Phasing - Renovation Phase: Bestaand

# IfcSlab: Slab 119, 17_WSP_FD_beton - fundatiepaal v21-2:ø300 (schroef):1473563
In: -2 fundering
Classification: Vloerplaat - fundering (ARCHICAD Classification); Material: WSP_beton - ihwg beton
CPset_Phasing - Renovation Phase: Bestaand
Pset_SlabCommon - Reference: ø300 (schroef); IsExternal: yes; LoadBearing: no
Pset_ReinforcementBarPitchOfSlab - Reference: ø300 (schroef)
Component Quantities - WSP_beton - ihwg beton, Mass: 903.056 kg; WSP_beton - ihwg beton, Component Volume (Net): 0.392633 m3; WSP_beton - ihwg beton, Component Volume (Gross): 0.392633 m3

# IfcSlab: Slab 12, 17_WSP_FD_beton - fundatiepaal v21-2:ø300 (schroef):1528051
In: -2 fundering
Classification: Vloerplaat - fundering (ARCHICAD Classification); Material: WSP_beton - ihwg beton
Pset_SlabCommon - Reference: ø300 (schroef); IsExternal: yes; LoadBearing: no
Component Quantities - WSP_beton - ihwg beton, Mass: 903.056 kg; WSP_beton - ihwg beton, Component Volume (Net): 0.392633 m3; WSP_beton - ihwg beton, Component Volume (Gross): 0.392633 m3
CPset_Phasing - Renovation Phase: Bestaand
Pset_ReinforcementBarPitchOfSlab - Reference: ø300 (schroef)

# IfcSlab: Slab 120, 17_WSP_FD_beton - fundatiepaal v21-2:ø300 (schroef):1473560
In: -2 fundering
Classification: Vloerplaat - fundering (ARCHICAD Classification); Material: WSP_beton - ihwg beton
Pset_SlabCommon - Reference: ø300 (schroef); IsExternal: yes; LoadBearing: no
Pset_ReinforcementBarPitchOfSlab - Reference: ø300 (schroef)
CPset_Phasing - Renovation Phase: Bestaand
Component Quantities - WSP_beton - ihwg beton, Mass: 903.056 kg; WSP_beton - ihwg beton, Component Volume (Net): 0.392633 m3; WSP_beton - ihwg beton, Component Volume (Gross): 0.392633 m3

# IfcSlab: Slab 121, 17_WSP_FD_beton - fundatiepaal v21-2:ø300 (schroef):1473561
In: -2 fundering
Classification: Vloerplaat - fundering (ARCHICAD Classification); Material: WSP_beton - ihwg beton
Pset_ReinforcementBarPitchOfSlab - Reference: ø300 (schroef)
CPset_Phasing - Renovation Phase: Bestaand
Pset_SlabCommon - Reference: ø300 (schroef); IsExternal: yes; LoadBearing: no
Component Quantities - WSP_beton - ihwg beton, Mass: 903.056 kg; WSP_beton - ihwg beton, Component Volume (Net): 0.392633 m3; WSP_beton - ihwg beton, Component Volume (Gross): 0.392633 m3

# IfcSlab: Slab 122, 17_WSP_FD_beton - fundatiepaal v21-2:ø300 (schroef):1473566
In: -2 fundering
Classification: Vloerplaat - fundering (ARCHICAD Classification); Material: WSP_beton - ihwg beton
Pset_SlabCommon - Reference: ø300 (schroef); IsExternal: yes; LoadBearing: no
Pset_ReinforcementBarPitchOfSlab - Reference: ø300 (schroef)
Component Quantities - WSP_beton - ihwg beton, Mass: 903.056 kg; WSP_beton - ihwg beton, Component Volume (Net): 0.392633 m3; WSP_beton - ihwg beton, Component Volume (Gross): 0.392633 m3
CPset_Phasing - Renovation Phase: Bestaand

# IfcSlab: Slab 123, 17_WSP_FD_beton - fundatiepaal v21-2:ø300 (schroef):1473567
In: -2 fundering
Classification: Vloerplaat - fundering (ARCHICAD Classification); Material: WSP_beton - ihwg beton
Pset_SlabCommon - Reference: ø300 (schroef); IsExternal: yes; LoadBearing: no
CPset_Phasing - Renovation Phase: Bestaand
Pset_ReinforcementBarPitchOfSlab - Reference: ø300 (schroef)
Component Quantities - WSP_beton - ihwg beton, Mass: 903.056 kg; WSP_beton - ihwg beton, Component Volume (Net): 0.392633 m3; WSP_beton - ihwg beton, Component Volume (Gross): 0.392633 m3

# IfcSlab: Slab 124, 17_WSP_FD_beton - fundatiepaal v21-2:ø300 (schroef):1473564
In: -2 fundering
Classification: Vloerplaat - fundering (ARCHICAD Classification); Material: WSP_beton - ihwg beton
Pset_SlabCommon - Reference: ø300 (schroef); IsExternal: yes; LoadBearing: no
Pset_ReinforcementBarPitchOfSlab - Reference: ø300 (schroef)
Component Quantities - WSP_beton - ihwg beton, Mass: 903.056 kg; WSP_beton - ihwg beton, Component Volume (Net): 0.392633 m3; WSP_beton - ihwg beton, Component Volume (Gross): 0.392633 m3
CPset_Phasing - Renovation Phase: Bestaand

# IfcSlab: Slab 125, 17_WSP_FD_beton - fundatiepaal v21-2:ø300 (schroef):1473565
In: -2 fundering
Classification: Vloerplaat - fundering (ARCHICAD Classification); Material: WSP_beton - ihwg beton
Pset_SlabCommon - Reference: ø300 (schroef); IsExternal: yes; LoadBearing: no
Pset_ReinforcementBarPitchOfSlab - Reference: ø300 (schroef)
Component Quantities - WSP_beton - ihwg beton, Mass: 903.056 kg; WSP_beton - ihwg beton, Component Volume (Net): 0.392633 m3; WSP_beton - ihwg beton, Component Volume (Gross): 0.392633 m3
CPset_Phasing - Renovation Phase: Bestaand

# IfcSlab: Slab 126, 17_WSP_FD_beton - fundatiepaal v21-2:ø300 (schroef):1472802
In: -2 fundering
Classification: Vloerplaat - fundering (ARCHICAD Classification); Material: WSP_beton - ihwg beton
Pset_ReinforcementBarPitchOfSlab - Reference: ø300 (schroef)
Pset_SlabCommon - Reference: ø300 (schroef); IsExternal: yes; LoadBearing: no
Component Quantities - WSP_beton - ihwg beton, Mass: 887.213 kg; WSP_beton - ihwg beton, Component Volume (Net): 0.385745 m3; WSP_beton - ihwg beton, Component Volume (Gross): 0.385745 m3
CPset_Phasing - Renovation Phase: Bestaand

# IfcSlab: Slab 127, 17_WSP_FD_beton - fundatiepaal v21-2:ø300 (schroef):1472803
In: -2 fundering
Classification: Vloerplaat - fundering (ARCHICAD Classification); Material: WSP_beton - ihwg beton
Pset_SlabCommon - Reference: ø300 (schroef); IsExternal: yes; LoadBearing: no
Component Quantities - WSP_beton - ihwg beton, Mass: 887.213 kg; WSP_beton - ihwg beton, Component Volume (Net): 0.385745 m3; WSP_beton - ihwg beton, Component Volume (Gross): 0.385745 m3
CPset_Phasing - Renovation Phase: Bestaand
Pset_ReinforcementBarPitchOfSlab - Reference: ø300 (schroef)

# IfcSlab: Slab 128, 17_WSP_FD_beton - fundatiepaal v21-2:ø300 (schroef):1472806
In: -2 fundering
Classification: Vloerplaat - fundering (ARCHICAD Classification); Material: WSP_beton - ihwg beton
Pset_SlabCommon - Reference: ø300 (schroef); IsExternal: yes; LoadBearing: no
Component Quantities - WSP_beton - ihwg beton, Mass: 887.213 kg; WSP_beton - ihwg beton, Component Volume (Net): 0.385745 m3; WSP_beton - ihwg beton, Component Volume (Gross): 0.385745 m3
Pset_ReinforcementBarPitchOfSlab - Reference: ø300 (schroef)
CPset_Phasing - Renovation Phase: Bestaand

# IfcSlab: Slab 129, 17_WSP_FD_beton - fundatiepaal v21-2:ø300 (schroef):1472807
In: -2 fundering
Classification: Vloerplaat - fundering (ARCHICAD Classification); Material: WSP_beton - ihwg beton
Pset_ReinforcementBarPitchOfSlab - Reference: ø300 (schroef)
Pset_SlabCommon - Reference: ø300 (schroef); IsExternal: yes; LoadBearing: no
CPset_Phasing - Renovation Phase: Bestaand
Component Quantities - WSP_beton - ihwg beton, Mass: 887.213 kg; WSP_beton - ihwg beton, Component Volume (Net): 0.385745 m3; WSP_beton - ihwg beton, Component Volume (Gross): 0.385745 m3

# IfcSlab: Slab 13, 17_WSP_FD_beton - fundatiepaal v21-2:ø300 (schroef):1528050
In: -2 fundering
Classification: Vloerplaat - fundering (ARCHICAD Classification); Material: WSP_beton - ihwg beton
Pset_ReinforcementBarPitchOfSlab - Reference: ø300 (schroef)
Pset_SlabCommon - Reference: ø300 (schroef); IsExternal: yes; LoadBearing: no
CPset_Phasing - Renovation Phase: Bestaand
Component Quantities - WSP_beton - ihwg beton, Mass: 903.056 kg; WSP_beton - ihwg beton, Component Volume (Net): 0.392633 m3; WSP_beton - ihwg beton, Component Volume (Gross): 0.392633 m3

# IfcSlab: Slab 130, 17_WSP_FD_beton - fundatiepaal v21-2:ø300 (schroef):1472804
In: -2 fundering
Classification: Vloerplaat - fundering (ARCHICAD Classification); Material: WSP_beton - ihwg beton
Pset_ReinforcementBarPitchOfSlab - Reference: ø300 (schroef)
Pset_SlabCommon - Reference: ø300 (schroef); IsExternal: yes; LoadBearing: no
CPset_Phasing - Renovation Phase: Bestaand
Component Quantities - WSP_beton - ihwg beton, Mass: 887.213 kg; WSP_beton - ihwg beton, Component Volume (Net): 0.385745 m3; WSP_beton - ihwg beton, Component Volume (Gross): 0.385745 m3

# IfcSlab: Slab 131, 17_WSP_FD_beton - fundatiepaal v21-2:ø300 (schroef):1472805
In: -2 fundering
Classification: Vloerplaat - fundering (ARCHICAD Classification); Material: WSP_beton - ihwg beton
Pset_SlabCommon - Reference: ø300 (schroef); IsExternal: yes; LoadBearing: no
Pset_ReinforcementBarPitchOfSlab - Reference: ø300 (schroef)
Component Quantities - WSP_beton - ihwg beton, Mass: 887.213 kg; WSP_beton - ihwg beton, Component Volume (Net): 0.385745 m3; WSP_beton - ihwg beton, Component Volume (Gross): 0.385745 m3
CPset_Phasing - Renovation Phase: Bestaand

# IfcSlab: Slab 132, 17_WSP_FD_beton - fundatiepaal v21-2:ø300 (schroef):1472810
In: -2 fundering
Classification: Vloerplaat - fundering (ARCHICAD Classification); Material: WSP_beton - ihwg beton
Pset_ReinforcementBarPitchOfSlab - Reference: ø300 (schroef)
Pset_SlabCommon - Reference: ø300 (schroef); IsExternal: yes; LoadBearing: no
Component Quantities - WSP_beton - ihwg beton, Mass: 887.213 kg; WSP_beton - ihwg beton, Component Volume (Net): 0.385745 m3; WSP_beton - ihwg beton, Component Volume (Gross): 0.385745 m3
CPset_Phasing - Renovation Phase: Bestaand

# IfcSlab: Slab 133, 17_WSP_FD_beton - fundatiepaal v21-2:ø300 (schroef):1472811
In: -2 fundering
Classification: Vloerplaat - fundering (ARCHICAD Classification); Material: WSP_beton - ihwg beton
Pset_SlabCommon - Reference: ø300 (schroef); IsExternal: yes; LoadBearing: no
Pset_ReinforcementBarPitchOfSlab - Reference: ø300 (schroef)
CPset_Phasing - Renovation Phase: Bestaand
Component Quantities - WSP_beton - ihwg beton, Mass: 887.213 kg; WSP_beton - ihwg beton, Component Volume (Net): 0.385745 m3; WSP_beton - ihwg beton, Component Volume (Gross): 0.385745 m3

# IfcSlab: Slab 134, 17_WSP_FD_beton - fundatiepaal v21-2:ø300 (schroef):1472808
In: -2 fundering
Classification: Vloerplaat - fundering (ARCHICAD Classification); Material: WSP_beton - ihwg beton
Pset_SlabCommon - Reference: ø300 (schroef); IsExternal: yes; LoadBearing: no
Pset_ReinforcementBarPitchOfSlab - Reference: ø300 (schroef)
Component Quantities - WSP_beton - ihwg beton, Mass: 887.213 kg; WSP_beton - ihwg beton, Component Volume (Net): 0.385745 m3; WSP_beton - ihwg beton, Component Volume (Gross): 0.385745 m3
CPset_Phasing - Renovation Phase: Bestaand

# IfcSlab: Slab 135, 17_WSP_FD_beton - fundatiepaal v21-2:ø300 (schroef):1472809
In: -2 fundering
Classification: Vloerplaat - fundering (ARCHICAD Classification); Material: WSP_beton - ihwg beton
Pset_SlabCommon - Reference: ø300 (schroef); IsExternal: yes; LoadBearing: no
Pset_ReinforcementBarPitchOfSlab - Reference: ø300 (schroef)
CPset_Phasing - Renovation Phase: Bestaand
Component Quantities - WSP_beton - ihwg beton, Mass: 887.213 kg; WSP_beton - ihwg beton, Component Volume (Net): 0.385745 m3; WSP_beton - ihwg beton, Component Volume (Gross): 0.385745 m3

# IfcSlab: Slab 136, 17_WSP_FD_beton - fundatiepaal v21-2:ø300 (schroef):1472815
In: -2 fundering
Classification: Vloerplaat - fundering (ARCHICAD Classification); Material: WSP_beton - ihwg beton
Pset_SlabCommon - Reference: ø300 (schroef); IsExternal: yes; LoadBearing: no
Pset_ReinforcementBarPitchOfSlab - Reference: ø300 (schroef)
Component Quantities - WSP_beton - ihwg beton, Mass: 887.213 kg; WSP_beton - ihwg beton, Component Volume (Net): 0.385745 m3; WSP_beton - ihwg beton, Component Volume (Gross): 0.385745 m3
CPset_Phasing - Renovation Phase: Bestaand

# IfcSlab: Slab 137, 17_WSP_FD_beton - fundatiepaal v21-2:ø300 (schroef):1472812
In: -2 fundering
Classification: Vloerplaat - fundering (ARCHICAD Classification); Material: WSP_beton - ihwg beton
Pset_ReinforcementBarPitchOfSlab - Reference: ø300 (schroef)
CPset_Phasing - Renovation Phase: Bestaand
Component Quantities - WSP_beton - ihwg beton, Mass: 887.213 kg; WSP_beton - ihwg beton, Component Volume (Net): 0.385745 m3; WSP_beton - ihwg beton, Component Volume (Gross): 0.385745 m3
Pset_SlabCommon - Reference: ø300 (schroef); IsExternal: yes; LoadBearing: no

# IfcSlab: Slab 138, 17_WSP_FD_beton - fundatiepaal v21-2:ø300 (schroef):1472813
In: -2 fundering
Classification: Vloerplaat - fundering (ARCHICAD Classification); Material: WSP_beton - ihwg beton
CPset_Phasing - Renovation Phase: Bestaand
Pset_SlabCommon - Reference: ø300 (schroef); IsExternal: yes; LoadBearing: no
Component Quantities - WSP_beton - ihwg beton, Mass: 887.213 kg; WSP_beton - ihwg beton, Component Volume (Net): 0.385745 m3; WSP_beton - ihwg beton, Component Volume (Gross): 0.385745 m3
Pset_ReinforcementBarPitchOfSlab - Reference: ø300 (schroef)

# IfcSlab: Slab 139, 17_WSP_FD_beton - fundatiepaal v21-2:ø300 (schroef):1472610
In: -2 fundering
Classification: Vloerplaat - fundering (ARCHICAD Classification); Material: WSP_beton - ihwg beton
Pset_SlabCommon - Reference: ø300 (schroef); IsExternal: yes; LoadBearing: no
Pset_ReinforcementBarPitchOfSlab - Reference: ø300 (schroef)
CPset_Phasing - Renovation Phase: Bestaand
Component Quantities - WSP_beton - ihwg beton, Mass: 887.213 kg; WSP_beton - ihwg beton, Component Volume (Net): 0.385745 m3; WSP_beton - ihwg beton, Component Volume (Gross): 0.385745 m3

# IfcSlab: Slab 14, 17_WSP_FD_beton - fundatiepaal v21-2:ø300 (schroef):1528061
In: -2 fundering
Classification: Vloerplaat - fundering (ARCHICAD Classification); Material: WSP_beton - ihwg beton
Pset_SlabCommon - Reference: ø300 (schroef); IsExternal: yes; LoadBearing: no
CPset_Phasing - Renovation Phase: Bestaand
Pset_ReinforcementBarPitchOfSlab - Reference: ø300 (schroef)
Component Quantities - WSP_beton - ihwg beton, Mass: 903.056 kg; WSP_beton - ihwg beton, Component Volume (Net): 0.392633 m3; WSP_beton - ihwg beton, Component Volume (Gross): 0.392633 m3

# IfcSlab: Slab 140, 17_WSP_FD_beton - fundatiepaal v21-2:ø300 (schroef):1472611
In: -2 fundering
Classification: Vloerplaat - fundering (ARCHICAD Classification); Material: WSP_beton - ihwg beton
Pset_SlabCommon - Reference: ø300 (schroef); IsExternal: yes; LoadBearing: no
CPset_Phasing - Renovation Phase: Bestaand
Pset_ReinforcementBarPitchOfSlab - Reference: ø300 (schroef)
Component Quantities - WSP_beton - ihwg beton, Mass: 887.213 kg; WSP_beton - ihwg beton, Component Volume (Net): 0.385745 m3; WSP_beton - ihwg beton, Component Volume (Gross): 0.385745 m3

# IfcSlab: Slab 141, 17_WSP_FD_beton - fundatiepaal v21-2:ø300 (schroef):1472614
In: -2 fundering
Classification: Vloerplaat - fundering (ARCHICAD Classification); Material: WSP_beton - ihwg beton
Pset_SlabCommon - Reference: ø300 (schroef); IsExternal: yes; LoadBearing: no
Component Quantities - WSP_beton - ihwg beton, Mass: 887.213 kg; WSP_beton - ihwg beton, Component Volume (Net): 0.385745 m3; WSP_beton - ihwg beton, Component Volume (Gross): 0.385745 m3
CPset_Phasing - Renovation Phase: Bestaand
Pset_ReinforcementBarPitchOfSlab - Reference: ø300 (schroef)

# IfcSlab: Slab 142, 17_WSP_FD_beton - fundatiepaal v21-2:ø300 (schroef):1472615
In: -2 fundering
Classification: Vloerplaat - fundering (ARCHICAD Classification); Material: WSP_beton - ihwg beton
Pset_ReinforcementBarPitchOfSlab - Reference: ø300 (schroef)
Pset_SlabCommon - Reference: ø300 (schroef); IsExternal: yes; LoadBearing: no
CPset_Phasing - Renovation Phase: Bestaand
Component Quantities - WSP_beton - ihwg beton, Mass: 887.213 kg; WSP_beton - ihwg beton, Component Volume (Net): 0.385745 m3; WSP_beton - ihwg beton, Component Volume (Gross): 0.385745 m3

# IfcSlab: Slab 143, 17_WSP_FD_beton - fundatiepaal v21-2:ø300 (schroef):1472612
In: -2 fundering
Classification: Vloerplaat - fundering (ARCHICAD Classification); Material: WSP_beton - ihwg beton
Pset_SlabCommon - Reference: ø300 (schroef); IsExternal: yes; LoadBearing: no
Pset_ReinforcementBarPitchOfSlab - Reference: ø300 (schroef)
Component Quantities - WSP_beton - ihwg beton, Mass: 887.213 kg; WSP_beton - ihwg beton, Component Volume (Net): 0.385745 m3; WSP_beton - ihwg beton, Component Volume (Gross): 0.385745 m3
CPset_Phasing - Renovation Phase: Bestaand

# IfcSlab: Slab 144, 17_WSP_FD_beton - fundatiepaal v21-2:ø300 (schroef):1472613
In: -2 fundering
Classification: Vloerplaat - fundering (ARCHICAD Classification); Material: WSP_beton - ihwg beton
Pset_SlabCommon - Reference: ø300 (schroef); IsExternal: yes; LoadBearing: no
CPset_Phasing - Renovation Phase: Bestaand
Component Quantities - WSP_beton - ihwg beton, Mass: 887.213 kg; WSP_beton - ihwg beton, Component Volume (Net): 0.385745 m3; WSP_beton - ihwg beton, Component Volume (Gross): 0.385745 m3
Pset_ReinforcementBarPitchOfSlab - Reference: ø300 (schroef)

# IfcSlab: Slab 145, 17_WSP_FD_beton - fundatiepaal v21-2:ø300 (schroef):1472618
In: -2 fundering
Classification: Vloerplaat - fundering (ARCHICAD Classification); Material: WSP_beton - ihwg beton
Pset_SlabCommon - Reference: ø300 (schroef); IsExternal: yes; LoadBearing: no
Pset_ReinforcementBarPitchOfSlab - Reference: ø300 (schroef)
Component Quantities - WSP_beton - ihwg beton, Mass: 887.213 kg; WSP_beton - ihwg beton, Component Volume (Net): 0.385745 m3; WSP_beton - ihwg beton, Component Volume (Gross): 0.385745 m3
CPset_Phasing - Renovation Phase: Bestaand

# IfcSlab: Slab 146, 17_WSP_FD_beton - fundatiepaal v21-2:ø300 (schroef):1472619
In: -2 fundering
Classification: Vloerplaat - fundering (ARCHICAD Classification); Material: WSP_beton - ihwg beton
Pset_SlabCommon - Reference: ø300 (schroef); IsExternal: yes; LoadBearing: no
Component Quantities - WSP_beton - ihwg beton, Mass: 887.213 kg; WSP_beton - ihwg beton, Component Volume (Net): 0.385745 m3; WSP_beton - ihwg beton, Component Volume (Gross): 0.385745 m3
Pset_ReinforcementBarPitchOfSlab - Reference: ø300 (schroef)
CPset_Phasing - Renovation Phase: Bestaand

# IfcSlab: Slab 147, 17_WSP_FD_beton - fundatiepaal v21-2:ø300 (schroef):1472616
In: -2 fundering
Classification: Vloerplaat - fundering (ARCHICAD Classification); Material: WSP_beton - ihwg beton
Pset_SlabCommon - Reference: ø300 (schroef); IsExternal: yes; LoadBearing: no
CPset_Phasing - Renovation Phase: Bestaand
Pset_ReinforcementBarPitchOfSlab - Reference: ø300 (schroef)
Component Quantities - WSP_beton - ihwg beton, Mass: 887.213 kg; WSP_beton - ihwg beton, Component Volume (Net): 0.385745 m3; WSP_beton - ihwg beton, Component Volume (Gross): 0.385745 m3

# IfcSlab: Slab 148, 17_WSP_FD_beton - fundatiepaal v21-2:ø300 (schroef):1472617
In: -2 fundering
Classification: Vloerplaat - fundering (ARCHICAD Classification); Material: WSP_beton - ihwg beton
Pset_SlabCommon - Reference: ø300 (schroef); IsExternal: yes; LoadBearing: no
Pset_ReinforcementBarPitchOfSlab - Reference: ø300 (schroef)
Component Quantities - WSP_beton - ihwg beton, Mass: 887.213 kg; WSP_beton - ihwg beton, Component Volume (Net): 0.385745 m3; WSP_beton - ihwg beton, Component Volume (Gross): 0.385745 m3
CPset_Phasing - Renovation Phase: Bestaand

# IfcSlab: Slab 149, 17_WSP_FD_beton - fundatiepaal v21-2:ø300 (schroef):1472622
In: -2 fundering
Classification: Vloerplaat - fundering (ARCHICAD Classification); Material: WSP_beton - ihwg beton
Pset_SlabCommon - Reference: ø300 (schroef); IsExternal: yes; LoadBearing: no
Pset_ReinforcementBarPitchOfSlab - Reference: ø300 (schroef)
CPset_Phasing - Renovation Phase: Bestaand
Component Quantities - WSP_beton - ihwg beton, Mass: 887.213 kg; WSP_beton - ihwg beton, Component Volume (Net): 0.385745 m3; WSP_beton - ihwg beton, Component Volume (Gross): 0.385745 m3

# IfcSlab: Slab 15, 17_WSP_FD_beton - fundatiepaal v21-2:ø300 (schroef):1528060
In: -2 fundering
Classification: Vloerplaat - fundering (ARCHICAD Classification); Material: WSP_beton - ihwg beton
Pset_ReinforcementBarPitchOfSlab - Reference: ø300 (schroef)
Pset_SlabCommon - Reference: ø300 (schroef); IsExternal: yes; LoadBearing: no
CPset_Phasing - Renovation Phase: Bestaand
Component Quantities - WSP_beton - ihwg beton, Mass: 903.056 kg; WSP_beton - ihwg beton, Component Volume (Net): 0.392633 m3; WSP_beton - ihwg beton, Component Volume (Gross): 0.392633 m3

# IfcSlab: Slab 150, 17_WSP_FD_beton - fundatiepaal v21-2:ø300 (schroef):1472623
In: -2 fundering
Classification: Vloerplaat - fundering (ARCHICAD Classification); Material: WSP_beton - ihwg beton
Pset_SlabCommon - Reference: ø300 (schroef); IsExternal: yes; LoadBearing: no
CPset_Phasing - Renovation Phase: Bestaand
Pset_ReinforcementBarPitchOfSlab - Reference: ø300 (schroef)
Component Quantities - WSP_beton - ihwg beton, Mass: 887.213 kg; WSP_beton - ihwg beton, Component Volume (Net): 0.385745 m3; WSP_beton - ihwg beton, Component Volume (Gross): 0.385745 m3

# IfcSlab: Slab 151, 17_WSP_FD_beton - fundatiepaal v21-2:ø300 (schroef):1472620
In: -2 fundering
Classification: Vloerplaat - fundering (ARCHICAD Classification); Material: WSP_beton - ihwg beton
Pset_ReinforcementBarPitchOfSlab - Reference: ø300 (schroef)
Component Quantities - WSP_beton - ihwg beton, Mass: 887.213 kg; WSP_beton - ihwg beton, Component Volume (Net): 0.385745 m3; WSP_beton - ihwg beton, Component Volume (Gross): 0.385745 m3
Pset_SlabCommon - Reference: ø300 (schroef); IsExternal: yes; LoadBearing: no
CPset_Phasing - Renovation Phase: Bestaand

# IfcSlab: Slab 152, 17_WSP_FD_beton - fundatiepaal v21-2:ø300 (schroef):1472621
In: -2 fundering
Classification: Vloerplaat - fundering (ARCHICAD Classification); Material: WSP_beton - ihwg beton
Pset_SlabCommon - Reference: ø300 (schroef); IsExternal: yes; LoadBearing: no
Pset_ReinforcementBarPitchOfSlab - Reference: ø300 (schroef)
CPset_Phasing - Renovation Phase: Bestaand
Component Quantities - WSP_beton - ihwg beton, Mass: 887.213 kg; WSP_beton - ihwg beton, Component Volume (Net): 0.385745 m3; WSP_beton - ihwg beton, Component Volume (Gross): 0.385745 m3

# IfcSlab: Slab 153, 17_WSP_FD_beton - fundatiepaal v21-2:ø300 (schroef):1472578
In: -2 fundering
Classification: Vloerplaat - fundering (ARCHICAD Classification); Material: WSP_beton - ihwg beton
Pset_SlabCommon - Reference: ø300 (schroef); IsExternal: yes; LoadBearing: no
Pset_ReinforcementBarPitchOfSlab - Reference: ø300 (schroef)
Component Quantities - WSP_beton - ihwg beton, Mass: 903.056 kg; WSP_beton - ihwg beton, Component Volume (Net): 0.392633 m3; WSP_beton - ihwg beton, Component Volume (Gross): 0.392633 m3
CPset_Phasing - Renovation Phase: Bestaand

# IfcSlab: Slab 154, 17_WSP_FD_beton - fundatiepaal v21-2:ø300 (schroef):1472579
In: -2 fundering
Classification: Vloerplaat - fundering (ARCHICAD Classification); Material: WSP_beton - ihwg beton
Pset_ReinforcementBarPitchOfSlab - Reference: ø300 (schroef)
CPset_Phasing - Renovation Phase: Bestaand
Component Quantities - WSP_beton - ihwg beton, Mass: 903.056 kg; WSP_beton - ihwg beton, Component Volume (Net): 0.392633 m3; WSP_beton - ihwg beton, Component Volume (Gross): 0.392633 m3
Pset_SlabCommon - Reference: ø300 (schroef); IsExternal: yes; LoadBearing: no

# IfcSlab: Slab 155, 17_WSP_FD_beton - fundatiepaal v21-2:ø300 (schroef):1472576
In: -2 fundering
Classification: Vloerplaat - fundering (ARCHICAD Classification); Material: WSP_beton - ihwg beton
Pset_SlabCommon - Reference: ø300 (schroef); IsExternal: yes; LoadBearing: no
Pset_ReinforcementBarPitchOfSlab - Reference: ø300 (schroef)
Component Quantities - WSP_beton - ihwg beton, Mass: 903.056 kg; WSP_beton - ihwg beton, Component Volume (Net): 0.392633 m3; WSP_beton - ihwg beton, Component Volume (Gross): 0.392633 m3
CPset_Phasing - Renovation Phase: Bestaand

# IfcSlab: Slab 156, 17_WSP_FD_beton - fundatiepaal v21-2:ø300 (schroef):1472577
In: -2 fundering
Classification: Vloerplaat - fundering (ARCHICAD Classification); Material: WSP_beton - ihwg beton
Pset_SlabCommon - Reference: ø300 (schroef); IsExternal: yes; LoadBearing: no
Pset_ReinforcementBarPitchOfSlab - Reference: ø300 (schroef)
CPset_Phasing - Renovation Phase: Bestaand
Component Quantities - WSP_beton - ihwg beton, Mass: 903.056 kg; WSP_beton - ihwg beton, Component Volume (Net): 0.392633 m3; WSP_beton - ihwg beton, Component Volume (Gross): 0.392633 m3

# IfcSlab: Slab 157, 17_WSP_FD_beton - fundatiepaal v21-2:ø300 (schroef):1472582
In: -2 fundering
Classification: Vloerplaat - fundering (ARCHICAD Classification); Material: WSP_beton - ihwg beton
Pset_SlabCommon - Reference: ø300 (schroef); IsExternal: yes; LoadBearing: no
Pset_ReinforcementBarPitchOfSlab - Reference: ø300 (schroef)
CPset_Phasing - Renovation Phase: Bestaand
Component Quantities - WSP_beton - ihwg beton, Mass: 903.056 kg; WSP_beton - ihwg beton, Component Volume (Net): 0.392633 m3; WSP_beton - ihwg beton, Component Volume (Gross): 0.392633 m3

# IfcSlab: Slab 158, 17_WSP_FD_beton - fundatiepaal v21-2:ø300 (schroef):1472583
In: -2 fundering
Classification: Vloerplaat - fundering (ARCHICAD Classification); Material: WSP_beton - ihwg beton
Pset_ReinforcementBarPitchOfSlab - Reference: ø300 (schroef)
Pset_SlabCommon - Reference: ø300 (schroef); IsExternal: yes; LoadBearing: no
Component Quantities - WSP_beton - ihwg beton, Mass: 903.056 kg; WSP_beton - ihwg beton, Component Volume (Net): 0.392633 m3; WSP_beton - ihwg beton, Component Volume (Gross): 0.392633 m3
CPset_Phasing - Renovation Phase: Bestaand

# IfcSlab: Slab 159, 17_WSP_FD_beton - fundatiepaal v21-2:ø300 (schroef):1472580
In: -2 fundering
Classification: Vloerplaat - fundering (ARCHICAD Classification); Material: WSP_beton - ihwg beton
Pset_ReinforcementBarPitchOfSlab - Reference: ø300 (schroef)
Component Quantities - WSP_beton - ihwg beton, Mass: 903.056 kg; WSP_beton - ihwg beton, Component Volume (Net): 0.392633 m3; WSP_beton - ihwg beton, Component Volume (Gross): 0.392633 m3
CPset_Phasing - Renovation Phase: Bestaand
Pset_SlabCommon - Reference: ø300 (schroef); IsExternal: yes; LoadBearing: no

# IfcSlab: Slab 16, 17_WSP_FD_beton - fundatiepaal v21-2:ø300 (schroef):1528062
In: -2 fundering
Classification: Vloerplaat - fundering (ARCHICAD Classification); Material: WSP_beton - ihwg beton
Pset_SlabCommon - Reference: ø300 (schroef); IsExternal: yes; LoadBearing: no
CPset_Phasing - Renovation Phase: Bestaand
Pset_ReinforcementBarPitchOfSlab - Reference: ø300 (schroef)
Component Quantities - WSP_beton - ihwg beton, Mass: 887.213 kg; WSP_beton - ihwg beton, Component Volume (Net): 0.385745 m3; WSP_beton - ihwg beton, Component Volume (Gross): 0.385745 m3

# IfcSlab: Slab 160, 17_WSP_FD_beton - fundatiepaal v21-2:ø300 (schroef):1472581
In: -2 fundering
Classification: Vloerplaat - fundering (ARCHICAD Classification); Material: WSP_beton - ihwg beton
Pset_SlabCommon - Reference: ø300 (schroef); IsExternal: yes; LoadBearing: no
Component Quantities - WSP_beton - ihwg beton, Mass: 903.056 kg; WSP_beton - ihwg beton, Component Volume (Net): 0.392633 m3; WSP_beton - ihwg beton, Component Volume (Gross): 0.392633 m3
CPset_Phasing - Renovation Phase: Bestaand
Pset_ReinforcementBarPitchOfSlab - Reference: ø300 (schroef)

# IfcSlab: Slab 161, 17_WSP_FD_beton - fundatiepaal v21-2:ø300 (schroef):1472586
In: -2 fundering
Classification: Vloerplaat - fundering (ARCHICAD Classification); Material: WSP_beton - ihwg beton
Pset_SlabCommon - Reference: ø300 (schroef); IsExternal: yes; LoadBearing: no
CPset_Phasing - Renovation Phase: Bestaand
Component Quantities - WSP_beton - ihwg beton, Mass: 903.056 kg; WSP_beton - ihwg beton, Component Volume (Net): 0.392633 m3; WSP_beton - ihwg beton, Component Volume (Gross): 0.392633 m3
Pset_ReinforcementBarPitchOfSlab - Reference: ø300 (schroef)

# IfcSlab: Slab 162, 17_WSP_FD_beton - fundatiepaal v21-2:ø300 (schroef):1472587
In: -2 fundering
Classification: Vloerplaat - fundering (ARCHICAD Classification); Material: WSP_beton - ihwg beton
CPset_Phasing - Renovation Phase: Bestaand
Pset_ReinforcementBarPitchOfSlab - Reference: ø300 (schroef)
Pset_SlabCommon - Reference: ø300 (schroef); IsExternal: yes; LoadBearing: no
Component Quantities - WSP_beton - ihwg beton, Mass: 903.056 kg; WSP_beton - ihwg beton, Component Volume (Net): 0.392633 m3; WSP_beton - ihwg beton, Component Volume (Gross): 0.392633 m3

# IfcSlab: Slab 163, 17_WSP_FD_beton - fundatiepaal v21-2:ø300 (schroef):1472584
In: -2 fundering
Classification: Vloerplaat - fundering (ARCHICAD Classification); Material: WSP_beton - ihwg beton
Pset_SlabCommon - Reference: ø300 (schroef); IsExternal: yes; LoadBearing: no
Pset_ReinforcementBarPitchOfSlab - Reference: ø300 (schroef)
Component Quantities - WSP_beton - ihwg beton, Mass: 903.056 kg; WSP_beton - ihwg beton, Component Volume (Net): 0.392633 m3; WSP_beton - ihwg beton, Component Volume (Gross): 0.392633 m3
CPset_Phasing - Renovation Phase: Bestaand

# IfcSlab: Slab 164, 17_WSP_FD_beton - fundatiepaal v21-2:ø300 (schroef):1472585
In: -2 fundering
Classification: Vloerplaat - fundering (ARCHICAD Classification); Material: WSP_beton - ihwg beton
CPset_Phasing - Renovation Phase: Bestaand
Component Quantities - WSP_beton - ihwg beton, Mass: 903.056 kg; WSP_beton - ihwg beton, Component Volume (Net): 0.392633 m3; WSP_beton - ihwg beton, Component Volume (Gross): 0.392633 m3
Pset_ReinforcementBarPitchOfSlab - Reference: ø300 (schroef)
Pset_SlabCommon - Reference: ø300 (schroef); IsExternal: yes; LoadBearing: no

# IfcSlab: Slab 165, 17_WSP_FD_beton - fundatiepaal v21-2:ø300 (schroef):1472590
In: -2 fundering
Classification: Vloerplaat - fundering (ARCHICAD Classification); Material: WSP_beton - ihwg beton
Pset_ReinforcementBarPitchOfSlab - Reference: ø300 (schroef)
CPset_Phasing - Renovation Phase: Bestaand
Pset_SlabCommon - Reference: ø300 (schroef); IsExternal: yes; LoadBearing: no
Component Quantities - WSP_beton - ihwg beton, Mass: 903.056 kg; WSP_beton - ihwg beton, Component Volume (Net): 0.392633 m3; WSP_beton - ihwg beton, Component Volume (Gross): 0.392633 m3

# IfcSlab: Slab 166, 17_WSP_FD_beton - fundatiepaal v21-2:ø300 (schroef):1472591
In: -2 fundering
Classification: Vloerplaat - fundering (ARCHICAD Classification); Material: WSP_beton - ihwg beton
Pset_ReinforcementBarPitchOfSlab - Reference: ø300 (schroef)
CPset_Phasing - Renovation Phase: Bestaand
Component Quantities - WSP_beton - ihwg beton, Mass: 903.056 kg; WSP_beton - ihwg beton, Component Volume (Net): 0.392633 m3; WSP_beton - ihwg beton, Component Volume (Gross): 0.392633 m3
Pset_SlabCommon - Reference: ø300 (schroef); IsExternal: yes; LoadBearing: no

# IfcSlab: Slab 167, 17_WSP_FD_beton - fundatiepaal v21-2:ø300 (schroef):1472588
In: -2 fundering
Classification: Vloerplaat - fundering (ARCHICAD Classification); Material: WSP_beton - ihwg beton
Pset_ReinforcementBarPitchOfSlab - Reference: ø300 (schroef)
CPset_Phasing - Renovation Phase: Bestaand
Pset_SlabCommon - Reference: ø300 (schroef); IsExternal: yes; LoadBearing: no
Component Quantities - WSP_beton - ihwg beton, Mass: 903.056 kg; WSP_beton - ihwg beton, Component Volume (Net): 0.392633 m3; WSP_beton - ihwg beton, Component Volume (Gross): 0.392633 m3

# IfcSlab: Slab 168, 17_WSP_FD_beton - fundatiepaal v21-2:ø300 (schroef):1472589
In: -2 fundering
Classification: Vloerplaat - fundering (ARCHICAD Classification); Material: WSP_beton - ihwg beton
Pset_SlabCommon - Reference: ø300 (schroef); IsExternal: yes; LoadBearing: no
Pset_ReinforcementBarPitchOfSlab - Reference: ø300 (schroef)
Component Quantities - WSP_beton - ihwg beton, Mass: 903.056 kg; WSP_beton - ihwg beton, Component Volume (Net): 0.392633 m3; WSP_beton - ihwg beton, Component Volume (Gross): 0.392633 m3
CPset_Phasing - Renovation Phase: Bestaand

# IfcSlab: Slab 169, 17_WSP_FD_beton - fundatiepaal v21-2:ø300 (schroef):1472594
In: -2 fundering
Classification: Vloerplaat - fundering (ARCHICAD Classification); Material: WSP_beton - ihwg beton
Pset_SlabCommon - Reference: ø300 (schroef); IsExternal: yes; LoadBearing: no
Pset_ReinforcementBarPitchOfSlab - Reference: ø300 (schroef)
Component Quantities - WSP_beton - ihwg beton, Mass: 903.056 kg; WSP_beton - ihwg beton, Component Volume (Net): 0.392633 m3; WSP_beton - ihwg beton, Component Volume (Gross): 0.392633 m3
CPset_Phasing - Renovation Phase: Bestaand

# IfcSlab: Slab 17, 17_WSP_FD_beton - fundatiepaal v21-2:ø300 (schroef):1528057
In: -2 fundering
Classification: Vloerplaat - fundering (ARCHICAD Classification); Material: WSP_beton - ihwg beton
Pset_ReinforcementBarPitchOfSlab - Reference: ø300 (schroef)
Pset_SlabCommon - Reference: ø300 (schroef); IsExternal: yes; LoadBearing: no
Component Quantities - WSP_beton - ihwg beton, Mass: 903.056 kg; WSP_beton - ihwg beton, Component Volume (Net): 0.392633 m3; WSP_beton - ihwg beton, Component Volume (Gross): 0.392633 m3
CPset_Phasing - Renovation Phase: Bestaand

# IfcSlab: Slab 170, 17_WSP_FD_beton - fundatiepaal v21-2:ø300 (schroef):1472595
In: -2 fundering
Classification: Vloerplaat - fundering (ARCHICAD Classification); Material: WSP_beton - ihwg beton
CPset_Phasing - Renovation Phase: Bestaand
Pset_ReinforcementBarPitchOfSlab - Reference: ø300 (schroef)
Pset_SlabCommon - Reference: ø300 (schroef); IsExternal: yes; LoadBearing: no
Component Quantities - WSP_beton - ihwg beton, Mass: 903.056 kg; WSP_beton - ihwg beton, Component Volume (Net): 0.392633 m3; WSP_beton - ihwg beton, Component Volume (Gross): 0.392633 m3

# IfcSlab: Slab 171, 17_WSP_FD_beton - fundatiepaal v21-2:ø300 (schroef):1472592
In: -2 fundering
Classification: Vloerplaat - fundering (ARCHICAD Classification); Material: WSP_beton - ihwg beton
Pset_SlabCommon - Reference: ø300 (schroef); IsExternal: yes; LoadBearing: no
Component Quantities - WSP_beton - ihwg beton, Mass: 903.056 kg; WSP_beton - ihwg beton, Component Volume (Net): 0.392633 m3; WSP_beton - ihwg beton, Component Volume (Gross): 0.392633 m3
Pset_ReinforcementBarPitchOfSlab - Reference: ø300 (schroef)
CPset_Phasing - Renovation Phase: Bestaand

# IfcSlab: Slab 172, 17_WSP_FD_beton - fundatiepaal v21-2:ø300 (schroef):1472593
In: -2 fundering
Classification: Vloerplaat - fundering (ARCHICAD Classification); Material: WSP_beton - ihwg beton
Pset_SlabCommon - Reference: ø300 (schroef); IsExternal: yes; LoadBearing: no
CPset_Phasing - Renovation Phase: Bestaand
Pset_ReinforcementBarPitchOfSlab - Reference: ø300 (schroef)
Component Quantities - WSP_beton - ihwg beton, Mass: 903.056 kg; WSP_beton - ihwg beton, Component Volume (Net): 0.392633 m3; WSP_beton - ihwg beton, Component Volume (Gross): 0.392633 m3

# IfcSlab: Slab 173, 17_WSP_FD_beton - fundatiepaal v21-2:ø300 (schroef):1472546
In: -2 fundering
Classification: Vloerplaat - fundering (ARCHICAD Classification); Material: WSP_beton - ihwg beton
Pset_ReinforcementBarPitchOfSlab - Reference: ø300 (schroef)
Pset_SlabCommon - Reference: ø300 (schroef); IsExternal: yes; LoadBearing: no
CPset_Phasing - Renovation Phase: Bestaand
Component Quantities - WSP_beton - ihwg beton, Mass: 903.056 kg; WSP_beton - ihwg beton, Component Volume (Net): 0.392633 m3; WSP_beton - ihwg beton, Component Volume (Gross): 0.392633 m3

# IfcSlab: Slab 174, 17_WSP_FD_beton - fundatiepaal v21-2:ø300 (schroef):1472547
In: -2 fundering
Classification: Vloerplaat - fundering (ARCHICAD Classification); Material: WSP_beton - ihwg beton
Pset_SlabCommon - Reference: ø300 (schroef); IsExternal: yes; LoadBearing: no
Pset_ReinforcementBarPitchOfSlab - Reference: ø300 (schroef)
CPset_Phasing - Renovation Phase: Bestaand
Component Quantities - WSP_beton - ihwg beton, Mass: 903.056 kg; WSP_beton - ihwg beton, Component Volume (Net): 0.392633 m3; WSP_beton - ihwg beton, Component Volume (Gross): 0.392633 m3

# IfcSlab: Slab 175, 17_WSP_FD_beton - fundatiepaal v21-2:ø300 (schroef):1472544
In: -2 fundering
Classification: Vloerplaat - fundering (ARCHICAD Classification); Material: WSP_beton - ihwg beton
Pset_SlabCommon - Reference: ø300 (schroef); IsExternal: yes; LoadBearing: no
Pset_ReinforcementBarPitchOfSlab - Reference: ø300 (schroef)
Component Quantities - WSP_beton - ihwg beton, Mass: 903.056 kg; WSP_beton - ihwg beton, Component Volume (Net): 0.392633 m3; WSP_beton - ihwg beton, Component Volume (Gross): 0.392633 m3
CPset_Phasing - Renovation Phase: Bestaand

# IfcSlab: Slab 176, 17_WSP_FD_beton - fundatiepaal v21-2:ø300 (schroef):1472545
In: -2 fundering
Classification: Vloerplaat - fundering (ARCHICAD Classification); Material: WSP_beton - ihwg beton
Pset_SlabCommon - Reference: ø300 (schroef); IsExternal: yes; LoadBearing: no
Pset_ReinforcementBarPitchOfSlab - Reference: ø300 (schroef)
CPset_Phasing - Renovation Phase: Bestaand
Component Quantities - WSP_beton - ihwg beton, Mass: 903.056 kg; WSP_beton - ihwg beton, Component Volume (Net): 0.392633 m3; WSP_beton - ihwg beton, Component Volume (Gross): 0.392633 m3

# IfcSlab: Slab 177, 17_WSP_FD_beton - fundatiepaal v21-2:ø300 (schroef):1472550
In: -2 fundering
Classification: Vloerplaat - fundering (ARCHICAD Classification); Material: WSP_beton - ihwg beton
Pset_SlabCommon - Reference: ø300 (schroef); IsExternal: yes; LoadBearing: no
Pset_ReinforcementBarPitchOfSlab - Reference: ø300 (schroef)
CPset_Phasing - Renovation Phase: Bestaand
Component Quantities - WSP_beton - ihwg beton, Mass: 903.056 kg; WSP_beton - ihwg beton, Component Volume (Net): 0.392633 m3; WSP_beton - ihwg beton, Component Volume (Gross): 0.392633 m3

# IfcSlab: Slab 178, 17_WSP_FD_beton - fundatiepaal v21-2:ø300 (schroef):1472551
In: -2 fundering
Classification: Vloerplaat - fundering (ARCHICAD Classification); Material: WSP_beton - ihwg beton
CPset_Phasing - Renovation Phase: Bestaand
Pset_ReinforcementBarPitchOfSlab - Reference: ø300 (schroef)
Component Quantities - WSP_beton - ihwg beton, Mass: 903.056 kg; WSP_beton - ihwg beton, Component Volume (Net): 0.392633 m3; WSP_beton - ihwg beton, Component Volume (Gross): 0.392633 m3
Pset_SlabCommon - Reference: ø300 (schroef); IsExternal: yes; LoadBearing: no

# IfcSlab: Slab 179, 17_WSP_FD_beton - fundatiepaal v21-2:ø300 (schroef):1472548
In: -2 fundering
Classification: Vloerplaat - fundering (ARCHICAD Classification); Material: WSP_beton - ihwg beton
Pset_SlabCommon - Reference: ø300 (schroef); IsExternal: yes; LoadBearing: no
Pset_ReinforcementBarPitchOfSlab - Reference: ø300 (schroef)
CPset_Phasing - Renovation Phase: Bestaand
Component Quantities - WSP_beton - ihwg beton, Mass: 903.056 kg; WSP_beton - ihwg beton, Component Volume (Net): 0.392633 m3; WSP_beton - ihwg beton, Component Volume (Gross): 0.392633 m3

# IfcSlab: Slab 18, 17_WSP_FD_beton - fundatiepaal v21-2:ø300 (schroef):1528056
In: -2 fundering
Classification: Vloerplaat - fundering (ARCHICAD Classification); Material: WSP_beton - ihwg beton
Pset_ReinforcementBarPitchOfSlab - Reference: ø300 (schroef)
Pset_SlabCommon - Reference: ø300 (schroef); IsExternal: yes; LoadBearing: no
CPset_Phasing - Renovation Phase: Bestaand
Component Quantities - WSP_beton - ihwg beton, Mass: 903.056 kg; WSP_beton - ihwg beton, Component Volume (Net): 0.392633 m3; WSP_beton - ihwg beton, Component Volume (Gross): 0.392633 m3

# IfcSlab: Slab 180, 17_WSP_FD_beton - fundatiepaal v21-2:ø300 (schroef):1472549
In: -2 fundering
Classification: Vloerplaat - fundering (ARCHICAD Classification); Material: WSP_beton - ihwg beton
Pset_ReinforcementBarPitchOfSlab - Reference: ø300 (schroef)
Pset_SlabCommon - Reference: ø300 (schroef); IsExternal: yes; LoadBearing: no
CPset_Phasing - Renovation Phase: Bestaand
Component Quantities - WSP_beton - ihwg beton, Mass: 903.056 kg; WSP_beton - ihwg beton, Component Volume (Net): 0.392633 m3; WSP_beton - ihwg beton, Component Volume (Gross): 0.392633 m3

# IfcSlab: Slab 181, 17_WSP_FD_beton - fundatiepaal v21-2:ø300 (schroef):1472554
In: -2 fundering
Classification: Vloerplaat - fundering (ARCHICAD Classification); Material: WSP_beton - ihwg beton
Pset_SlabCommon - Reference: ø300 (schroef); IsExternal: yes; LoadBearing: no
Pset_ReinforcementBarPitchOfSlab - Reference: ø300 (schroef)
CPset_Phasing - Renovation Phase: Bestaand
Component Quantities - WSP_beton - ihwg beton, Mass: 903.056 kg; WSP_beton - ihwg beton, Component Volume (Net): 0.392633 m3; WSP_beton - ihwg beton, Component Volume (Gross): 0.392633 m3

# IfcSlab: Slab 182, 17_WSP_FD_beton - fundatiepaal v21-2:ø300 (schroef):1472555
In: -2 fundering
Classification: Vloerplaat - fundering (ARCHICAD Classification); Material: WSP_beton - ihwg beton
Pset_ReinforcementBarPitchOfSlab - Reference: ø300 (schroef)
Pset_SlabCommon - Reference: ø300 (schroef); IsExternal: yes; LoadBearing: no
CPset_Phasing - Renovation Phase: Bestaand
Component Quantities - WSP_beton - ihwg beton, Mass: 903.056 kg; WSP_beton - ihwg beton, Component Volume (Net): 0.392633 m3; WSP_beton - ihwg beton, Component Volume (Gross): 0.392633 m3

# IfcSlab: Slab 183, 17_WSP_FD_beton - fundatiepaal v21-2:ø300 (schroef):1472552
In: -2 fundering
Classification: Vloerplaat - fundering (ARCHICAD Classification); Material: WSP_beton - ihwg beton
Pset_SlabCommon - Reference: ø300 (schroef); IsExternal: yes; LoadBearing: no
Pset_ReinforcementBarPitchOfSlab - Reference: ø300 (schroef)
Component Quantities - WSP_beton - ihwg beton, Mass: 903.056 kg; WSP_beton - ihwg beton, Component Volume (Net): 0.392633 m3; WSP_beton - ihwg beton, Component Volume (Gross): 0.392633 m3
CPset_Phasing - Renovation Phase: Bestaand

# IfcSlab: Slab 184, 17_WSP_FD_beton - fundatiepaal v21-2:ø300 (schroef):1472553
In: -2 fundering
Classification: Vloerplaat - fundering (ARCHICAD Classification); Material: WSP_beton - ihwg beton
Pset_SlabCommon - Reference: ø300 (schroef); IsExternal: yes; LoadBearing: no
Pset_ReinforcementBarPitchOfSlab - Reference: ø300 (schroef)
CPset_Phasing - Renovation Phase: Bestaand
Component Quantities - WSP_beton - ihwg beton, Mass: 903.056 kg; WSP_beton - ihwg beton, Component Volume (Net): 0.392633 m3; WSP_beton - ihwg beton, Component Volume (Gross): 0.392633 m3

# IfcSlab: Slab 185, 17_WSP_FD_beton - fundatiepaal v21-2:ø300 (schroef):1472558
In: -2 fundering
Classification: Vloerplaat - fundering (ARCHICAD Classification); Material: WSP_beton - ihwg beton
Pset_SlabCommon - Reference: ø300 (schroef); IsExternal: yes; LoadBearing: no
Pset_ReinforcementBarPitchOfSlab - Reference: ø300 (schroef)
CPset_Phasing - Renovation Phase: Bestaand
Component Quantities - WSP_beton - ihwg beton, Mass: 903.056 kg; WSP_beton - ihwg beton, Component Volume (Net): 0.392633 m3; WSP_beton - ihwg beton, Component Volume (Gross): 0.392633 m3

# IfcSlab: Slab 186, 17_WSP_FD_beton - fundatiepaal v21-2:ø300 (schroef):1472559
In: -2 fundering
Classification: Vloerplaat - fundering (ARCHICAD Classification); Material: WSP_beton - ihwg beton
Pset_SlabCommon - Reference: ø300 (schroef); IsExternal: yes; LoadBearing: no
Pset_ReinforcementBarPitchOfSlab - Reference: ø300 (schroef)
CPset_Phasing - Renovation Phase: Bestaand
Component Quantities - WSP_beton - ihwg beton, Mass: 903.056 kg; WSP_beton - ihwg beton, Component Volume (Net): 0.392633 m3; WSP_beton - ihwg beton, Component Volume (Gross): 0.392633 m3

# IfcSlab: Slab 187, 17_WSP_FD_beton - fundatiepaal v21-2:ø300 (schroef):1472556
In: -2 fundering
Classification: Vloerplaat - fundering (ARCHICAD Classification); Material: WSP_beton - ihwg beton
Pset_ReinforcementBarPitchOfSlab - Reference: ø300 (schroef)
CPset_Phasing - Renovation Phase: Bestaand
Pset_SlabCommon - Reference: ø300 (schroef); IsExternal: yes; LoadBearing: no
Component Quantities - WSP_beton - ihwg beton, Mass: 903.056 kg; WSP_beton - ihwg beton, Component Volume (Net): 0.392633 m3; WSP_beton - ihwg beton, Component Volume (Gross): 0.392633 m3

# IfcSlab: Slab 188, 17_WSP_FD_beton - fundatiepaal v21-2:ø300 (schroef):1472557
In: -2 fundering
Classification: Vloerplaat - fundering (ARCHICAD Classification); Material: WSP_beton - ihwg beton
Pset_ReinforcementBarPitchOfSlab - Reference: ø300 (schroef)
Pset_SlabCommon - Reference: ø300 (schroef); IsExternal: yes; LoadBearing: no
Component Quantities - WSP_beton - ihwg beton, Mass: 903.056 kg; WSP_beton - ihwg beton, Component Volume (Net): 0.392633 m3; WSP_beton - ihwg beton, Component Volume (Gross): 0.392633 m3
CPset_Phasing - Renovation Phase: Bestaand

# IfcSlab: Slab 189, 17_WSP_FD_beton - fundatiepaal v21-2:ø300 (schroef):1472562
In: -2 fundering
Classification: Vloerplaat - fundering (ARCHICAD Classification); Material: WSP_beton - ihwg beton
Pset_SlabCommon - Reference: ø300 (schroef); IsExternal: yes; LoadBearing: no
Pset_ReinforcementBarPitchOfSlab - Reference: ø300 (schroef)
CPset_Phasing - Renovation Phase: Bestaand
Component Quantities - WSP_beton - ihwg beton, Mass: 903.056 kg; WSP_beton - ihwg beton, Component Volume (Net): 0.392633 m3; WSP_beton - ihwg beton, Component Volume (Gross): 0.392633 m3

# IfcSlab: Slab 19, 17_WSP_FD_beton - fundatiepaal v21-2:ø300 (schroef):1528059
In: -2 fundering
Classification: Vloerplaat - fundering (ARCHICAD Classification); Material: WSP_beton - ihwg beton
Pset_ReinforcementBarPitchOfSlab - Reference: ø300 (schroef)
Pset_SlabCommon - Reference: ø300 (schroef); IsExternal: yes; LoadBearing: no
Component Quantities - WSP_beton - ihwg beton, Mass: 903.056 kg; WSP_beton - ihwg beton, Component Volume (Net): 0.392633 m3; WSP_beton - ihwg beton, Component Volume (Gross): 0.392633 m3
CPset_Phasing - Renovation Phase: Bestaand

# IfcSlab: Slab 190, 17_WSP_FD_beton - fundatiepaal v21-2:ø300 (schroef):1472563
In: -2 fundering
Classification: Vloerplaat - fundering (ARCHICAD Classification); Material: WSP_beton - ihwg beton
Pset_ReinforcementBarPitchOfSlab - Reference: ø300 (schroef)
Pset_SlabCommon - Reference: ø300 (schroef); IsExternal: yes; LoadBearing: no
CPset_Phasing - Renovation Phase: Bestaand
Component Quantities - WSP_beton - ihwg beton, Mass: 903.056 kg; WSP_beton - ihwg beton, Component Volume (Net): 0.392633 m3; WSP_beton - ihwg beton, Component Volume (Gross): 0.392633 m3

# IfcSlab: Slab 191, 17_WSP_FD_beton - fundatiepaal v21-2:ø300 (schroef):1472560
In: -2 fundering
Classification: Vloerplaat - fundering (ARCHICAD Classification); Material: WSP_beton - ihwg beton
Pset_SlabCommon - Reference: ø300 (schroef); IsExternal: yes; LoadBearing: no
Pset_ReinforcementBarPitchOfSlab - Reference: ø300 (schroef)
Component Quantities - WSP_beton - ihwg beton, Mass: 903.056 kg; WSP_beton - ihwg beton, Component Volume (Net): 0.392633 m3; WSP_beton - ihwg beton, Component Volume (Gross): 0.392633 m3
CPset_Phasing - Renovation Phase: Bestaand

# IfcSlab: Slab 192, 17_WSP_FD_beton - fundatiepaal v21-2:ø300 (schroef):1472561
In: -2 fundering
Classification: Vloerplaat - fundering (ARCHICAD Classification); Material: WSP_beton - ihwg beton
Pset_SlabCommon - Reference: ø300 (schroef); IsExternal: yes; LoadBearing: no
Pset_ReinforcementBarPitchOfSlab - Reference: ø300 (schroef)
CPset_Phasing - Renovation Phase: Bestaand
Component Quantities - WSP_beton - ihwg beton, Mass: 903.056 kg; WSP_beton - ihwg beton, Component Volume (Net): 0.392633 m3; WSP_beton - ihwg beton, Component Volume (Gross): 0.392633 m3

# IfcSlab: Slab 193, 17_WSP_FD_beton - fundatiepaal v21-2:ø300 (schroef):1472566
In: -2 fundering
Classification: Vloerplaat - fundering (ARCHICAD Classification); Material: WSP_beton - ihwg beton
Pset_ReinforcementBarPitchOfSlab - Reference: ø300 (schroef)
Pset_SlabCommon - Reference: ø300 (schroef); IsExternal: yes; LoadBearing: no
Component Quantities - WSP_beton - ihwg beton, Mass: 903.056 kg; WSP_beton - ihwg beton, Component Volume (Net): 0.392633 m3; WSP_beton - ihwg beton, Component Volume (Gross): 0.392633 m3
CPset_Phasing - Renovation Phase: Bestaand

# IfcSlab: Slab 194, 17_WSP_FD_beton - fundatiepaal v21-2:ø300 (schroef):1472567
In: -2 fundering
Classification: Vloerplaat - fundering (ARCHICAD Classification); Material: WSP_beton - ihwg beton
Pset_SlabCommon - Reference: ø300 (schroef); IsExternal: yes; LoadBearing: no
Component Quantities - WSP_beton - ihwg beton, Mass: 903.056 kg; WSP_beton - ihwg beton, Component Volume (Net): 0.392633 m3; WSP_beton - ihwg beton, Component Volume (Gross): 0.392633 m3
CPset_Phasing - Renovation Phase: Bestaand
Pset_ReinforcementBarPitchOfSlab - Reference: ø300 (schroef)

# IfcSlab: Slab 195, 17_WSP_FD_beton - fundatiepaal v21-2:ø300 (schroef):1472564
In: -2 fundering
Classification: Vloerplaat - fundering (ARCHICAD Classification); Material: WSP_beton - ihwg beton
Pset_SlabCommon - Reference: ø300 (schroef); IsExternal: yes; LoadBearing: no
Pset_ReinforcementBarPitchOfSlab - Reference: ø300 (schroef)
CPset_Phasing - Renovation Phase: Bestaand
Component Quantities - WSP_beton - ihwg beton, Mass: 903.056 kg; WSP_beton - ihwg beton, Component Volume (Net): 0.392633 m3; WSP_beton - ihwg beton, Component Volume (Gross): 0.392633 m3

# IfcSlab: Slab 196, 17_WSP_FD_beton - fundatiepaal v21-2:ø300 (schroef):1472565
In: -2 fundering
Classification: Vloerplaat - fundering (ARCHICAD Classification); Material: WSP_beton - ihwg beton
Pset_ReinforcementBarPitchOfSlab - Reference: ø300 (schroef)
Pset_SlabCommon - Reference: ø300 (schroef); IsExternal: yes; LoadBearing: no
Component Quantities - WSP_beton - ihwg beton, Mass: 903.056 kg; WSP_beton - ihwg beton, Component Volume (Net): 0.392633 m3; WSP_beton - ihwg beton, Component Volume (Gross): 0.392633 m3
CPset_Phasing - Renovation Phase: Bestaand

# IfcSlab: Slab 197, 17_WSP_FD_beton - fundatiepaal v21-2:ø300 (schroef):1472570
In: -2 fundering
Classification: Vloerplaat - fundering (ARCHICAD Classification); Material: WSP_beton - ihwg beton
Pset_ReinforcementBarPitchOfSlab - Reference: ø300 (schroef)
Pset_SlabCommon - Reference: ø300 (schroef); IsExternal: yes; LoadBearing: no
Component Quantities - WSP_beton - ihwg beton, Mass: 903.056 kg; WSP_beton - ihwg beton, Component Volume (Net): 0.392633 m3; WSP_beton - ihwg beton, Component Volume (Gross): 0.392633 m3
CPset_Phasing - Renovation Phase: Bestaand

# IfcSlab: Slab 198, 17_WSP_FD_beton - fundatiepaal v21-2:ø300 (schroef):1472571
In: -2 fundering
Classification: Vloerplaat - fundering (ARCHICAD Classification); Material: WSP_beton - ihwg beton
CPset_Phasing - Renovation Phase: Bestaand
Pset_SlabCommon - Reference: ø300 (schroef); IsExternal: yes; LoadBearing: no
Component Quantities - WSP_beton - ihwg beton, Mass: 903.056 kg; WSP_beton - ihwg beton, Component Volume (Net): 0.392633 m3; WSP_beton - ihwg beton, Component Volume (Gross): 0.392633 m3
Pset_ReinforcementBarPitchOfSlab - Reference: ø300 (schroef)

# IfcSlab: Slab 199, 17_WSP_FD_beton - fundatiepaal v21-2:ø300 (schroef):1472568
In: -2 fundering
Classification: Vloerplaat - fundering (ARCHICAD Classification); Material: WSP_beton - ihwg beton
Pset_SlabCommon - Reference: ø300 (schroef); IsExternal: yes; LoadBearing: no
Pset_ReinforcementBarPitchOfSlab - Reference: ø300 (schroef)
Component Quantities - WSP_beton - ihwg beton, Mass: 903.056 kg; WSP_beton - ihwg beton, Component Volume (Net): 0.392633 m3; WSP_beton - ihwg beton, Component Volume (Gross): 0.392633 m3
CPset_Phasing - Renovation Phase: Bestaand

# IfcSlab: Slab 20, 17_WSP_FD_beton - fundatiepaal v21-2:ø300 (schroef):1528058
In: -2 fundering
Classification: Vloerplaat - fundering (ARCHICAD Classification); Material: WSP_beton - ihwg beton
Pset_ReinforcementBarPitchOfSlab - Reference: ø300 (schroef)
CPset_Phasing - Renovation Phase: Bestaand
Pset_SlabCommon - Reference: ø300 (schroef); IsExternal: yes; LoadBearing: no
Component Quantities - WSP_beton - ihwg beton, Mass: 903.056 kg; WSP_beton - ihwg beton, Component Volume (Net): 0.392633 m3; WSP_beton - ihwg beton, Component Volume (Gross): 0.392633 m3

# IfcSlab: Slab 200, 17_WSP_FD_beton - fundatiepaal v21-2:ø300 (schroef):1472569
In: -2 fundering
Classification: Vloerplaat - fundering (ARCHICAD Classification); Material: WSP_beton - ihwg beton
Pset_SlabCommon - Reference: ø300 (schroef); IsExternal: yes; LoadBearing: no
Component Quantities - WSP_beton - ihwg beton, Mass: 903.056 kg; WSP_beton - ihwg beton, Component Volume (Net): 0.392633 m3; WSP_beton - ihwg beton, Component Volume (Gross): 0.392633 m3
CPset_Phasing - Renovation Phase: Bestaand
Pset_ReinforcementBarPitchOfSlab - Reference: ø300 (schroef)

# IfcSlab: Slab 201, 17_WSP_FD_beton - fundatiepaal v21-2:ø300 (schroef):1472574
In: -2 fundering
Classification: Vloerplaat - fundering (ARCHICAD Classification); Material: WSP_beton - ihwg beton
Pset_SlabCommon - Reference: ø300 (schroef); IsExternal: yes; LoadBearing: no
CPset_Phasing - Renovation Phase: Bestaand
Pset_ReinforcementBarPitchOfSlab - Reference: ø300 (schroef)
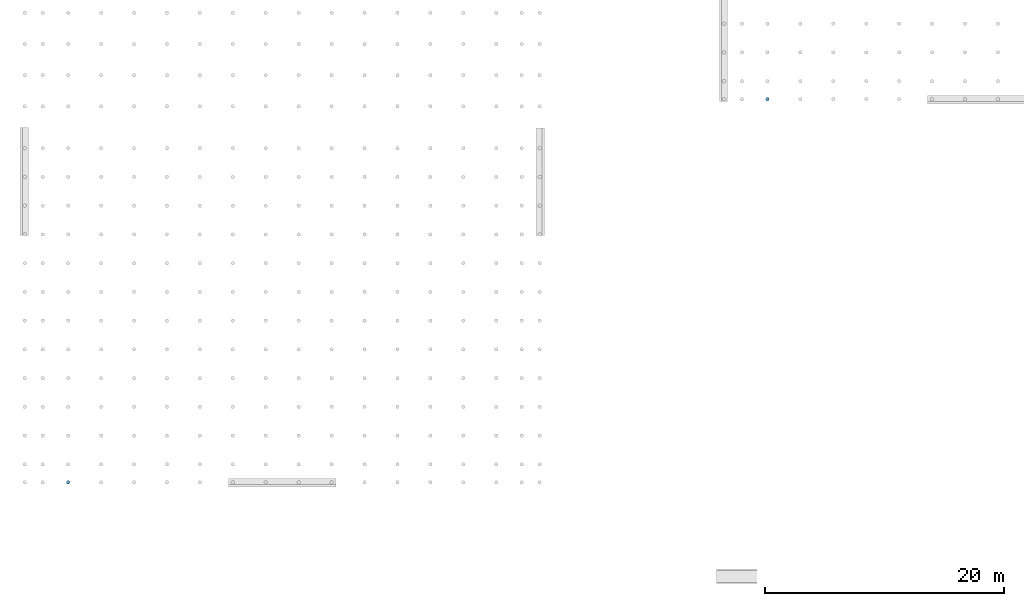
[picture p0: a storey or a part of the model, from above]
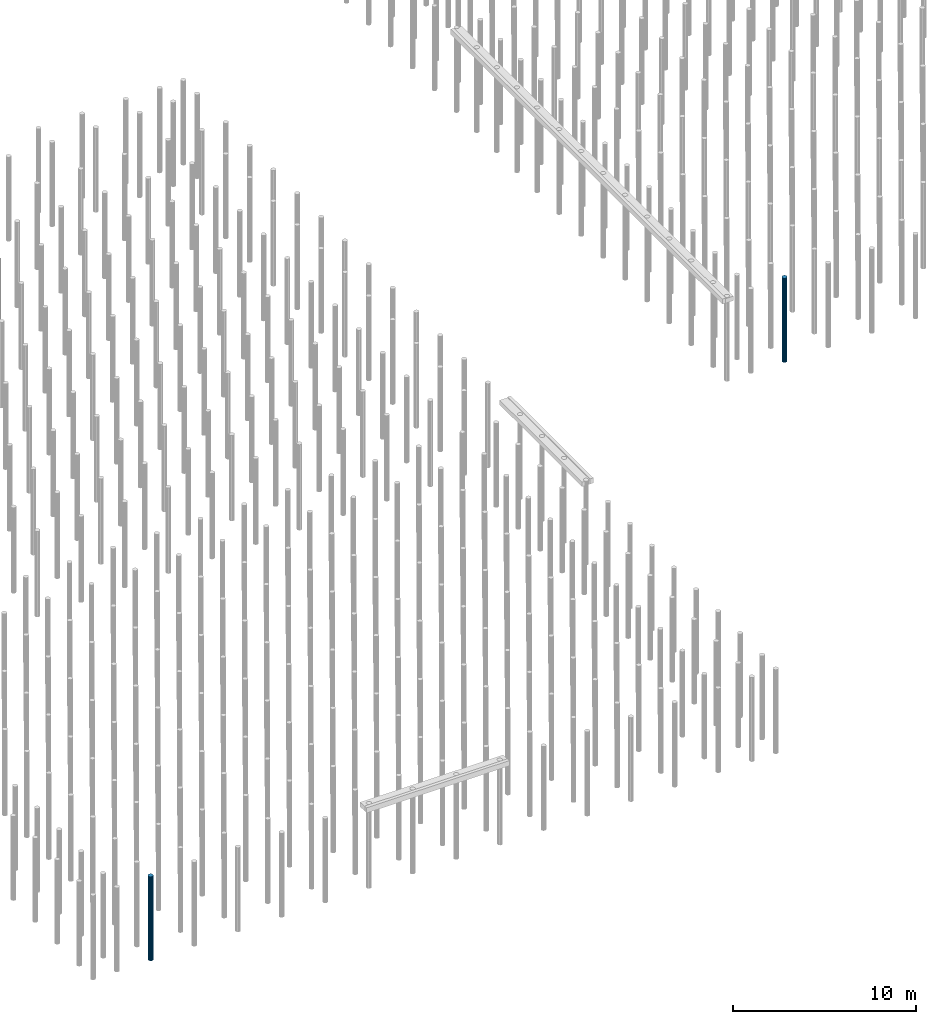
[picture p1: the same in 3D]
Properties of the parts of a building model (IFC2X3), part 4 of 13

# IfcSlab: Slab 201, 17_WSP_FD_beton - fundatiepaal v21-2:ø300 (schroef):1472574
Component Quantities - WSP_beton - ihwg beton, Mass: 903.056 kg; WSP_beton - ihwg beton, Component Volume (Net): 0.392633 m3; WSP_beton - ihwg beton, Component Volume (Gross): 0.392633 m3

# IfcSlab: Slab 202, 17_WSP_FD_beton - fundatiepaal v21-2:ø300 (schroef):1472575
In: -2 fundering
Classification: Vloerplaat - fundering (ARCHICAD Classification); Material: WSP_beton - ihwg beton
Pset_SlabCommon - Reference: ø300 (schroef); IsExternal: yes; LoadBearing: no
Pset_ReinforcementBarPitchOfSlab - Reference: ø300 (schroef)
Component Quantities - WSP_beton - ihwg beton, Mass: 903.056 kg; WSP_beton - ihwg beton, Component Volume (Net): 0.392633 m3; WSP_beton - ihwg beton, Component Volume (Gross): 0.392633 m3
CPset_Phasing - Renovation Phase: Bestaand

# IfcSlab: Slab 203, 17_WSP_FD_beton - fundatiepaal v21-2:ø300 (schroef):1472572
In: -2 fundering
Classification: Vloerplaat - fundering (ARCHICAD Classification); Material: WSP_beton - ihwg beton
Pset_SlabCommon - Reference: ø300 (schroef); IsExternal: yes; LoadBearing: no
Pset_ReinforcementBarPitchOfSlab - Reference: ø300 (schroef)
CPset_Phasing - Renovation Phase: Bestaand
Component Quantities - WSP_beton - ihwg beton, Mass: 903.056 kg; WSP_beton - ihwg beton, Component Volume (Net): 0.392633 m3; WSP_beton - ihwg beton, Component Volume (Gross): 0.392633 m3

# IfcSlab: Slab 204, 17_WSP_FD_beton - fundatiepaal v21-2:ø300 (schroef):1472573
In: -2 fundering
Classification: Vloerplaat - fundering (ARCHICAD Classification); Material: WSP_beton - ihwg beton
CPset_Phasing - Renovation Phase: Bestaand
Component Quantities - WSP_beton - ihwg beton, Mass: 903.056 kg; WSP_beton - ihwg beton, Component Volume (Net): 0.392633 m3; WSP_beton - ihwg beton, Component Volume (Gross): 0.392633 m3
Pset_ReinforcementBarPitchOfSlab - Reference: ø300 (schroef)
Pset_SlabCommon - Reference: ø300 (schroef); IsExternal: yes; LoadBearing: no

# IfcSlab: Slab 205, 17_WSP_FD_beton - fundatiepaal v21-2:ø300 (schroef):1472514
In: -2 fundering
Classification: Vloerplaat - fundering (ARCHICAD Classification); Material: WSP_beton - ihwg beton
Pset_ReinforcementBarPitchOfSlab - Reference: ø300 (schroef)
Pset_SlabCommon - Reference: ø300 (schroef); IsExternal: yes; LoadBearing: no
CPset_Phasing - Renovation Phase: Bestaand
Component Quantities - WSP_beton - ihwg beton, Mass: 903.056 kg; WSP_beton - ihwg beton, Component Volume (Net): 0.392633 m3; WSP_beton - ihwg beton, Component Volume (Gross): 0.392633 m3

# IfcSlab: Slab 206, 17_WSP_FD_beton - fundatiepaal v21-2:ø300 (schroef):1472515
In: -2 fundering
Classification: Vloerplaat - fundering (ARCHICAD Classification); Material: WSP_beton - ihwg beton
Pset_SlabCommon - Reference: ø300 (schroef); IsExternal: yes; LoadBearing: no
Pset_ReinforcementBarPitchOfSlab - Reference: ø300 (schroef)
CPset_Phasing - Renovation Phase: Bestaand
Component Quantities - WSP_beton - ihwg beton, Mass: 903.056 kg; WSP_beton - ihwg beton, Component Volume (Net): 0.392633 m3; WSP_beton - ihwg beton, Component Volume (Gross): 0.392633 m3

# IfcSlab: Slab 207, 17_WSP_FD_beton - fundatiepaal v21-2:ø300 (schroef):1472512
In: -2 fundering
Classification: Vloerplaat - fundering (ARCHICAD Classification); Material: WSP_beton - ihwg beton
Pset_SlabCommon - Reference: ø300 (schroef); IsExternal: yes; LoadBearing: no
Component Quantities - WSP_beton - ihwg beton, Mass: 903.056 kg; WSP_beton - ihwg beton, Component Volume (Net): 0.392633 m3; WSP_beton - ihwg beton, Component Volume (Gross): 0.392633 m3
CPset_Phasing - Renovation Phase: Bestaand
Pset_ReinforcementBarPitchOfSlab - Reference: ø300 (schroef)

# IfcSlab: Slab 208, 17_WSP_FD_beton - fundatiepaal v21-2:ø300 (schroef):1472513
In: -2 fundering
Classification: Vloerplaat - fundering (ARCHICAD Classification); Material: WSP_beton - ihwg beton
Pset_SlabCommon - Reference: ø300 (schroef); IsExternal: yes; LoadBearing: no
Component Quantities - WSP_beton - ihwg beton, Mass: 903.056 kg; WSP_beton - ihwg beton, Component Volume (Net): 0.392633 m3; WSP_beton - ihwg beton, Component Volume (Gross): 0.392633 m3
CPset_Phasing - Renovation Phase: Bestaand
Pset_ReinforcementBarPitchOfSlab - Reference: ø300 (schroef)

# IfcSlab: Slab 209, 17_WSP_FD_beton - fundatiepaal v21-2:ø300 (schroef):1472518
In: -2 fundering
Classification: Vloerplaat - fundering (ARCHICAD Classification); Material: WSP_beton - ihwg beton
Pset_ReinforcementBarPitchOfSlab - Reference: ø300 (schroef)
Pset_SlabCommon - Reference: ø300 (schroef); IsExternal: yes; LoadBearing: no
CPset_Phasing - Renovation Phase: Bestaand
Component Quantities - WSP_beton - ihwg beton, Mass: 903.056 kg; WSP_beton - ihwg beton, Component Volume (Net): 0.392633 m3; WSP_beton - ihwg beton, Component Volume (Gross): 0.392633 m3

# IfcSlab: Slab 21, 17_WSP_FD_beton - fundatiepaal v21-2:ø300 (schroef):1528485
In: -2 fundering
Classification: Vloerplaat - fundering (ARCHICAD Classification); Material: WSP_beton - ihwg beton
CPset_Phasing - Renovation Phase: Bestaand
Pset_ReinforcementBarPitchOfSlab - Reference: ø300 (schroef)
Pset_SlabCommon - Reference: ø300 (schroef); IsExternal: yes; LoadBearing: no
Component Quantities - WSP_beton - ihwg beton, Mass: 903.056 kg; WSP_beton - ihwg beton, Component Volume (Net): 0.392633 m3; WSP_beton - ihwg beton, Component Volume (Gross): 0.392633 m3

# IfcSlab: Slab 210, 17_WSP_FD_beton - fundatiepaal v21-2:ø300 (schroef):1472519
In: -2 fundering
Classification: Vloerplaat - fundering (ARCHICAD Classification); Material: WSP_beton - ihwg beton
Pset_SlabCommon - Reference: ø300 (schroef); IsExternal: yes; LoadBearing: no
Component Quantities - WSP_beton - ihwg beton, Mass: 903.056 kg; WSP_beton - ihwg beton, Component Volume (Net): 0.392633 m3; WSP_beton - ihwg beton, Component Volume (Gross): 0.392633 m3
CPset_Phasing - Renovation Phase: Bestaand
Pset_ReinforcementBarPitchOfSlab - Reference: ø300 (schroef)

# IfcSlab: Slab 211, 17_WSP_FD_beton - fundatiepaal v21-2:ø300 (schroef):1472516
In: -2 fundering
Classification: Vloerplaat - fundering (ARCHICAD Classification); Material: WSP_beton - ihwg beton
Pset_ReinforcementBarPitchOfSlab - Reference: ø300 (schroef)
Pset_SlabCommon - Reference: ø300 (schroef); IsExternal: yes; LoadBearing: no
CPset_Phasing - Renovation Phase: Bestaand
Component Quantities - WSP_beton - ihwg beton, Mass: 903.056 kg; WSP_beton - ihwg beton, Component Volume (Net): 0.392633 m3; WSP_beton - ihwg beton, Component Volume (Gross): 0.392633 m3

# IfcSlab: Slab 212, 17_WSP_FD_beton - fundatiepaal v21-2:ø300 (schroef):1472517
In: -2 fundering
Classification: Vloerplaat - fundering (ARCHICAD Classification); Material: WSP_beton - ihwg beton
Pset_ReinforcementBarPitchOfSlab - Reference: ø300 (schroef)
Pset_SlabCommon - Reference: ø300 (schroef); IsExternal: yes; LoadBearing: no
Component Quantities - WSP_beton - ihwg beton, Mass: 903.056 kg; WSP_beton - ihwg beton, Component Volume (Net): 0.392633 m3; WSP_beton - ihwg beton, Component Volume (Gross): 0.392633 m3
CPset_Phasing - Renovation Phase: Bestaand

# IfcSlab: Slab 213, 17_WSP_FD_beton - fundatiepaal v21-2:ø300 (schroef):1472522
In: -2 fundering
Classification: Vloerplaat - fundering (ARCHICAD Classification); Material: WSP_beton - ihwg beton
Pset_SlabCommon - Reference: ø300 (schroef); IsExternal: yes; LoadBearing: no
Pset_ReinforcementBarPitchOfSlab - Reference: ø300 (schroef)
CPset_Phasing - Renovation Phase: Bestaand
Component Quantities - WSP_beton - ihwg beton, Mass: 903.056 kg; WSP_beton - ihwg beton, Component Volume (Net): 0.392633 m3; WSP_beton - ihwg beton, Component Volume (Gross): 0.392633 m3

# IfcSlab: Slab 214, 17_WSP_FD_beton - fundatiepaal v21-2:ø300 (schroef):1472523
In: -2 fundering
Classification: Vloerplaat - fundering (ARCHICAD Classification); Material: WSP_beton - ihwg beton
Pset_SlabCommon - Reference: ø300 (schroef); IsExternal: yes; LoadBearing: no
CPset_Phasing - Renovation Phase: Bestaand
Pset_ReinforcementBarPitchOfSlab - Reference: ø300 (schroef)
Component Quantities - WSP_beton - ihwg beton, Mass: 903.056 kg; WSP_beton - ihwg beton, Component Volume (Net): 0.392633 m3; WSP_beton - ihwg beton, Component Volume (Gross): 0.392633 m3

# IfcSlab: Slab 215, 17_WSP_FD_beton - fundatiepaal v21-2:ø300 (schroef):1472520
In: -2 fundering
Classification: Vloerplaat - fundering (ARCHICAD Classification); Material: WSP_beton - ihwg beton
Pset_SlabCommon - Reference: ø300 (schroef); IsExternal: yes; LoadBearing: no
Pset_ReinforcementBarPitchOfSlab - Reference: ø300 (schroef)
Component Quantities - WSP_beton - ihwg beton, Mass: 903.056 kg; WSP_beton - ihwg beton, Component Volume (Net): 0.392633 m3; WSP_beton - ihwg beton, Component Volume (Gross): 0.392633 m3
CPset_Phasing - Renovation Phase: Bestaand

# IfcSlab: Slab 216, 17_WSP_FD_beton - fundatiepaal v21-2:ø300 (schroef):1472521
In: -2 fundering
Classification: Vloerplaat - fundering (ARCHICAD Classification); Material: WSP_beton - ihwg beton
Pset_SlabCommon - Reference: ø300 (schroef); IsExternal: yes; LoadBearing: no
Pset_ReinforcementBarPitchOfSlab - Reference: ø300 (schroef)
CPset_Phasing - Renovation Phase: Bestaand
Component Quantities - WSP_beton - ihwg beton, Mass: 903.056 kg; WSP_beton - ihwg beton, Component Volume (Net): 0.392633 m3; WSP_beton - ihwg beton, Component Volume (Gross): 0.392633 m3

# IfcSlab: Slab 217, 17_WSP_FD_beton - fundatiepaal v21-2:ø300 (schroef):1472526
In: -2 fundering
Classification: Vloerplaat - fundering (ARCHICAD Classification); Material: WSP_beton - ihwg beton
Pset_SlabCommon - Reference: ø300 (schroef); IsExternal: yes; LoadBearing: no
Pset_ReinforcementBarPitchOfSlab - Reference: ø300 (schroef)
Component Quantities - WSP_beton - ihwg beton, Mass: 903.056 kg; WSP_beton - ihwg beton, Component Volume (Net): 0.392633 m3; WSP_beton - ihwg beton, Component Volume (Gross): 0.392633 m3
CPset_Phasing - Renovation Phase: Bestaand

# IfcSlab: Slab 218, 17_WSP_FD_beton - fundatiepaal v21-2:ø300 (schroef):1472527
In: -2 fundering
Classification: Vloerplaat - fundering (ARCHICAD Classification); Material: WSP_beton - ihwg beton
Pset_SlabCommon - Reference: ø300 (schroef); IsExternal: yes; LoadBearing: no
Pset_ReinforcementBarPitchOfSlab - Reference: ø300 (schroef)
Component Quantities - WSP_beton - ihwg beton, Mass: 903.056 kg; WSP_beton - ihwg beton, Component Volume (Net): 0.392633 m3; WSP_beton - ihwg beton, Component Volume (Gross): 0.392633 m3
CPset_Phasing - Renovation Phase: Bestaand

# IfcSlab: Slab 219, 17_WSP_FD_beton - fundatiepaal v21-2:ø300 (schroef):1472524
In: -2 fundering
Classification: Vloerplaat - fundering (ARCHICAD Classification); Material: WSP_beton - ihwg beton
Pset_SlabCommon - Reference: ø300 (schroef); IsExternal: yes; LoadBearing: no
Pset_ReinforcementBarPitchOfSlab - Reference: ø300 (schroef)
Component Quantities - WSP_beton - ihwg beton, Mass: 903.056 kg; WSP_beton - ihwg beton, Component Volume (Net): 0.392633 m3; WSP_beton - ihwg beton, Component Volume (Gross): 0.392633 m3
CPset_Phasing - Renovation Phase: Bestaand

# IfcSlab: Slab 22, 17_WSP_FD_beton - fundatiepaal v21-2:ø300 (schroef):1528484
In: -2 fundering
Classification: Vloerplaat - fundering (ARCHICAD Classification); Material: WSP_beton - ihwg beton
CPset_Phasing - Renovation Phase: Bestaand
Pset_ReinforcementBarPitchOfSlab - Reference: ø300 (schroef)
Pset_SlabCommon - Reference: ø300 (schroef); IsExternal: yes; LoadBearing: no
Component Quantities - WSP_beton - ihwg beton, Mass: 903.056 kg; WSP_beton - ihwg beton, Component Volume (Net): 0.392633 m3; WSP_beton - ihwg beton, Component Volume (Gross): 0.392633 m3

# IfcSlab: Slab 220, 17_WSP_FD_beton - fundatiepaal v21-2:ø300 (schroef):1472525
In: -2 fundering
Classification: Vloerplaat - fundering (ARCHICAD Classification); Material: WSP_beton - ihwg beton
CPset_Phasing - Renovation Phase: Bestaand
Pset_ReinforcementBarPitchOfSlab - Reference: ø300 (schroef)
Pset_SlabCommon - Reference: ø300 (schroef); IsExternal: yes; LoadBearing: no
Component Quantities - WSP_beton - ihwg beton, Mass: 903.056 kg; WSP_beton - ihwg beton, Component Volume (Net): 0.392633 m3; WSP_beton - ihwg beton, Component Volume (Gross): 0.392633 m3

# IfcSlab: Slab 221, 17_WSP_FD_beton - fundatiepaal v21-2:ø300 (schroef):1472530
In: -2 fundering
Classification: Vloerplaat - fundering (ARCHICAD Classification); Material: WSP_beton - ihwg beton
CPset_Phasing - Renovation Phase: Bestaand
Pset_ReinforcementBarPitchOfSlab - Reference: ø300 (schroef)
Pset_SlabCommon - Reference: ø300 (schroef); IsExternal: yes; LoadBearing: no
Component Quantities - WSP_beton - ihwg beton, Mass: 903.056 kg; WSP_beton - ihwg beton, Component Volume (Net): 0.392633 m3; WSP_beton - ihwg beton, Component Volume (Gross): 0.392633 m3

# IfcSlab: Slab 222, 17_WSP_FD_beton - fundatiepaal v21-2:ø300 (schroef):1472531
In: -2 fundering
Classification: Vloerplaat - fundering (ARCHICAD Classification); Material: WSP_beton - ihwg beton
Pset_ReinforcementBarPitchOfSlab - Reference: ø300 (schroef)
Pset_SlabCommon - Reference: ø300 (schroef); IsExternal: yes; LoadBearing: no
CPset_Phasing - Renovation Phase: Bestaand
Component Quantities - WSP_beton - ihwg beton, Mass: 903.056 kg; WSP_beton - ihwg beton, Component Volume (Net): 0.392633 m3; WSP_beton - ihwg beton, Component Volume (Gross): 0.392633 m3

# IfcSlab: Slab 223, 17_WSP_FD_beton - fundatiepaal v21-2:ø300 (schroef):1472528
In: -2 fundering
Classification: Vloerplaat - fundering (ARCHICAD Classification); Material: WSP_beton - ihwg beton
Pset_ReinforcementBarPitchOfSlab - Reference: ø300 (schroef)
CPset_Phasing - Renovation Phase: Bestaand
Component Quantities - WSP_beton - ihwg beton, Mass: 903.056 kg; WSP_beton - ihwg beton, Component Volume (Net): 0.392633 m3; WSP_beton - ihwg beton, Component Volume (Gross): 0.392633 m3
Pset_SlabCommon - Reference: ø300 (schroef); IsExternal: yes; LoadBearing: no

# IfcSlab: Slab 224, 17_WSP_FD_beton - fundatiepaal v21-2:ø300 (schroef):1472529
In: -2 fundering
Classification: Vloerplaat - fundering (ARCHICAD Classification); Material: WSP_beton - ihwg beton
CPset_Phasing - Renovation Phase: Bestaand
Pset_ReinforcementBarPitchOfSlab - Reference: ø300 (schroef)
Pset_SlabCommon - Reference: ø300 (schroef); IsExternal: yes; LoadBearing: no
Component Quantities - WSP_beton - ihwg beton, Mass: 903.056 kg; WSP_beton - ihwg beton, Component Volume (Net): 0.392633 m3; WSP_beton - ihwg beton, Component Volume (Gross): 0.392633 m3

# IfcSlab: Slab 225, 17_WSP_FD_beton - fundatiepaal v21-2:ø300 (schroef):1472534
In: -2 fundering
Classification: Vloerplaat - fundering (ARCHICAD Classification); Material: WSP_beton - ihwg beton
Pset_SlabCommon - Reference: ø300 (schroef); IsExternal: yes; LoadBearing: no
Pset_ReinforcementBarPitchOfSlab - Reference: ø300 (schroef)
CPset_Phasing - Renovation Phase: Bestaand
Component Quantities - WSP_beton - ihwg beton, Mass: 903.056 kg; WSP_beton - ihwg beton, Component Volume (Net): 0.392633 m3; WSP_beton - ihwg beton, Component Volume (Gross): 0.392633 m3

# IfcSlab: Slab 226, 17_WSP_FD_beton - fundatiepaal v21-2:ø300 (schroef):1472535
In: -2 fundering
Classification: Vloerplaat - fundering (ARCHICAD Classification); Material: WSP_beton - ihwg beton
Pset_ReinforcementBarPitchOfSlab - Reference: ø300 (schroef)
Pset_SlabCommon - Reference: ø300 (schroef); IsExternal: yes; LoadBearing: no
CPset_Phasing - Renovation Phase: Bestaand
Component Quantities - WSP_beton - ihwg beton, Mass: 903.056 kg; WSP_beton - ihwg beton, Component Volume (Net): 0.392633 m3; WSP_beton - ihwg beton, Component Volume (Gross): 0.392633 m3

# IfcSlab: Slab 227, 17_WSP_FD_beton - fundatiepaal v21-2:ø300 (schroef):1472532
In: -2 fundering
Classification: Vloerplaat - fundering (ARCHICAD Classification); Material: WSP_beton - ihwg beton
Pset_SlabCommon - Reference: ø300 (schroef); IsExternal: yes; LoadBearing: no
Pset_ReinforcementBarPitchOfSlab - Reference: ø300 (schroef)
Component Quantities - WSP_beton - ihwg beton, Mass: 903.056 kg; WSP_beton - ihwg beton, Component Volume (Net): 0.392633 m3; WSP_beton - ihwg beton, Component Volume (Gross): 0.392633 m3
CPset_Phasing - Renovation Phase: Bestaand

# IfcSlab: Slab 228, 17_WSP_FD_beton - fundatiepaal v21-2:ø300 (schroef):1472533
In: -2 fundering
Classification: Vloerplaat - fundering (ARCHICAD Classification); Material: WSP_beton - ihwg beton
Pset_SlabCommon - Reference: ø300 (schroef); IsExternal: yes; LoadBearing: no
Pset_ReinforcementBarPitchOfSlab - Reference: ø300 (schroef)
Component Quantities - WSP_beton - ihwg beton, Mass: 903.056 kg; WSP_beton - ihwg beton, Component Volume (Net): 0.392633 m3; WSP_beton - ihwg beton, Component Volume (Gross): 0.392633 m3
CPset_Phasing - Renovation Phase: Bestaand

# IfcSlab: Slab 229, 17_WSP_FD_beton - fundatiepaal v21-2:ø300 (schroef):1472538
In: -2 fundering
Classification: Vloerplaat - fundering (ARCHICAD Classification); Material: WSP_beton - ihwg beton
Pset_SlabCommon - Reference: ø300 (schroef); IsExternal: yes; LoadBearing: no
Pset_ReinforcementBarPitchOfSlab - Reference: ø300 (schroef)
CPset_Phasing - Renovation Phase: Bestaand
Component Quantities - WSP_beton - ihwg beton, Mass: 903.056 kg; WSP_beton - ihwg beton, Component Volume (Net): 0.392633 m3; WSP_beton - ihwg beton, Component Volume (Gross): 0.392633 m3

# IfcSlab: Slab 23, 17_WSP_FD_beton - fundatiepaal v21-2:ø300 (schroef):1528487
In: -2 fundering
Classification: Vloerplaat - fundering (ARCHICAD Classification); Material: WSP_beton - ihwg beton
Pset_SlabCommon - Reference: ø300 (schroef); IsExternal: yes; LoadBearing: no
Pset_ReinforcementBarPitchOfSlab - Reference: ø300 (schroef)
CPset_Phasing - Renovation Phase: Bestaand
Component Quantities - WSP_beton - ihwg beton, Mass: 903.056 kg; WSP_beton - ihwg beton, Component Volume (Net): 0.392633 m3; WSP_beton - ihwg beton, Component Volume (Gross): 0.392633 m3

# IfcSlab: Slab 230, 17_WSP_FD_beton - fundatiepaal v21-2:ø300 (schroef):1472539
In: -2 fundering
Classification: Vloerplaat - fundering (ARCHICAD Classification); Material: WSP_beton - ihwg beton
Pset_SlabCommon - Reference: ø300 (schroef); IsExternal: yes; LoadBearing: no
Pset_ReinforcementBarPitchOfSlab - Reference: ø300 (schroef)
CPset_Phasing - Renovation Phase: Bestaand
Component Quantities - WSP_beton - ihwg beton, Mass: 903.056 kg; WSP_beton - ihwg beton, Component Volume (Net): 0.392633 m3; WSP_beton - ihwg beton, Component Volume (Gross): 0.392633 m3

# IfcSlab: Slab 231, 17_WSP_FD_beton - fundatiepaal v21-2:ø300 (schroef):1472536
In: -2 fundering
Classification: Vloerplaat - fundering (ARCHICAD Classification); Material: WSP_beton - ihwg beton
Pset_SlabCommon - Reference: ø300 (schroef); IsExternal: yes; LoadBearing: no
CPset_Phasing - Renovation Phase: Bestaand
Pset_ReinforcementBarPitchOfSlab - Reference: ø300 (schroef)
Component Quantities - WSP_beton - ihwg beton, Mass: 903.056 kg; WSP_beton - ihwg beton, Component Volume (Net): 0.392633 m3; WSP_beton - ihwg beton, Component Volume (Gross): 0.392633 m3

# IfcSlab: Slab 232, 17_WSP_FD_beton - fundatiepaal v21-2:ø300 (schroef):1472537
In: -2 fundering
Classification: Vloerplaat - fundering (ARCHICAD Classification); Material: WSP_beton - ihwg beton
Pset_ReinforcementBarPitchOfSlab - Reference: ø300 (schroef)
Component Quantities - WSP_beton - ihwg beton, Mass: 903.056 kg; WSP_beton - ihwg beton, Component Volume (Net): 0.392633 m3; WSP_beton - ihwg beton, Component Volume (Gross): 0.392633 m3
Pset_SlabCommon - Reference: ø300 (schroef); IsExternal: yes; LoadBearing: no
CPset_Phasing - Renovation Phase: Bestaand

# IfcSlab: Slab 233, 17_WSP_FD_beton - fundatiepaal v21-2:ø300 (schroef):1472542
In: -2 fundering
Classification: Vloerplaat - fundering (ARCHICAD Classification); Material: WSP_beton - ihwg beton
Pset_SlabCommon - Reference: ø300 (schroef); IsExternal: yes; LoadBearing: no
Pset_ReinforcementBarPitchOfSlab - Reference: ø300 (schroef)
Component Quantities - WSP_beton - ihwg beton, Mass: 903.056 kg; WSP_beton - ihwg beton, Component Volume (Net): 0.392633 m3; WSP_beton - ihwg beton, Component Volume (Gross): 0.392633 m3
CPset_Phasing - Renovation Phase: Bestaand

# IfcSlab: Slab 234, 17_WSP_FD_beton - fundatiepaal v21-2:ø300 (schroef):1472543
In: -2 fundering
Classification: Vloerplaat - fundering (ARCHICAD Classification); Material: WSP_beton - ihwg beton
Pset_ReinforcementBarPitchOfSlab - Reference: ø300 (schroef)
Pset_SlabCommon - Reference: ø300 (schroef); IsExternal: yes; LoadBearing: no
CPset_Phasing - Renovation Phase: Bestaand
Component Quantities - WSP_beton - ihwg beton, Mass: 903.056 kg; WSP_beton - ihwg beton, Component Volume (Net): 0.392633 m3; WSP_beton - ihwg beton, Component Volume (Gross): 0.392633 m3

# IfcSlab: Slab 235, 17_WSP_FD_beton - fundatiepaal v21-2:ø300 (schroef):1472540
In: -2 fundering
Classification: Vloerplaat - fundering (ARCHICAD Classification); Material: WSP_beton - ihwg beton
Pset_SlabCommon - Reference: ø300 (schroef); IsExternal: yes; LoadBearing: no
Pset_ReinforcementBarPitchOfSlab - Reference: ø300 (schroef)
CPset_Phasing - Renovation Phase: Bestaand
Component Quantities - WSP_beton - ihwg beton, Mass: 903.056 kg; WSP_beton - ihwg beton, Component Volume (Net): 0.392633 m3; WSP_beton - ihwg beton, Component Volume (Gross): 0.392633 m3

# IfcSlab: Slab 236, 17_WSP_FD_beton - fundatiepaal v21-2:ø300 (schroef):1472541
In: -2 fundering
Classification: Vloerplaat - fundering (ARCHICAD Classification); Material: WSP_beton - ihwg beton
Pset_ReinforcementBarPitchOfSlab - Reference: ø300 (schroef)
Pset_SlabCommon - Reference: ø300 (schroef); IsExternal: yes; LoadBearing: no
Component Quantities - WSP_beton - ihwg beton, Mass: 903.056 kg; WSP_beton - ihwg beton, Component Volume (Net): 0.392633 m3; WSP_beton - ihwg beton, Component Volume (Gross): 0.392633 m3
CPset_Phasing - Renovation Phase: Bestaand

# IfcSlab: Slab 237, 17_WSP_FD_beton - fundatiepaal v21-2:ø300 (schroef):1473350
In: -2 fundering
Classification: Vloerplaat - fundering (ARCHICAD Classification); Material: WSP_beton - ihwg beton
Pset_ReinforcementBarPitchOfSlab - Reference: ø300 (schroef)
Pset_SlabCommon - Reference: ø300 (schroef); IsExternal: yes; LoadBearing: no
CPset_Phasing - Renovation Phase: Bestaand
Component Quantities - WSP_beton - ihwg beton, Mass: 887.213 kg; WSP_beton - ihwg beton, Component Volume (Net): 0.385745 m3; WSP_beton - ihwg beton, Component Volume (Gross): 0.385745 m3

# IfcSlab: Slab 238, 17_WSP_FD_beton - fundatiepaal v21-2:ø300 (schroef):1473351
In: -2 fundering
Classification: Vloerplaat - fundering (ARCHICAD Classification); Material: WSP_beton - ihwg beton
Pset_SlabCommon - Reference: ø300 (schroef); IsExternal: yes; LoadBearing: no
Pset_ReinforcementBarPitchOfSlab - Reference: ø300 (schroef)
Component Quantities - WSP_beton - ihwg beton, Mass: 887.213 kg; WSP_beton - ihwg beton, Component Volume (Net): 0.385745 m3; WSP_beton - ihwg beton, Component Volume (Gross): 0.385745 m3
CPset_Phasing - Renovation Phase: Bestaand

# IfcSlab: Slab 239, 17_WSP_FD_beton - fundatiepaal v21-2:ø300 (schroef):1473348
In: -2 fundering
Classification: Vloerplaat - fundering (ARCHICAD Classification); Material: WSP_beton - ihwg beton
Pset_SlabCommon - Reference: ø300 (schroef); IsExternal: yes; LoadBearing: no
CPset_Phasing - Renovation Phase: Bestaand
Component Quantities - WSP_beton - ihwg beton, Mass: 887.213 kg; WSP_beton - ihwg beton, Component Volume (Net): 0.385745 m3; WSP_beton - ihwg beton, Component Volume (Gross): 0.385745 m3
Pset_ReinforcementBarPitchOfSlab - Reference: ø300 (schroef)

# IfcSlab: Slab 24, 17_WSP_FD_beton - fundatiepaal v21-2:ø300 (schroef):1528486
In: -2 fundering
Classification: Vloerplaat - fundering (ARCHICAD Classification); Material: WSP_beton - ihwg beton
Pset_SlabCommon - Reference: ø300 (schroef); IsExternal: yes; LoadBearing: no
Pset_ReinforcementBarPitchOfSlab - Reference: ø300 (schroef)
CPset_Phasing - Renovation Phase: Bestaand
Component Quantities - WSP_beton - ihwg beton, Mass: 903.056 kg; WSP_beton - ihwg beton, Component Volume (Net): 0.392633 m3; WSP_beton - ihwg beton, Component Volume (Gross): 0.392633 m3

# IfcSlab: Slab 240, 17_WSP_FD_beton - fundatiepaal v21-2:ø300 (schroef):1473349
In: -2 fundering
Classification: Vloerplaat - fundering (ARCHICAD Classification); Material: WSP_beton - ihwg beton
Pset_SlabCommon - Reference: ø300 (schroef); IsExternal: yes; LoadBearing: no
Pset_ReinforcementBarPitchOfSlab - Reference: ø300 (schroef)
Component Quantities - WSP_beton - ihwg beton, Mass: 887.213 kg; WSP_beton - ihwg beton, Component Volume (Net): 0.385745 m3; WSP_beton - ihwg beton, Component Volume (Gross): 0.385745 m3
CPset_Phasing - Renovation Phase: Bestaand

# IfcSlab: Slab 241, 17_WSP_FD_beton - fundatiepaal v21-2:ø300 (schroef):1473354
In: -2 fundering
Classification: Vloerplaat - fundering (ARCHICAD Classification); Material: WSP_beton - ihwg beton
Pset_SlabCommon - Reference: ø300 (schroef); IsExternal: yes; LoadBearing: no
CPset_Phasing - Renovation Phase: Bestaand
Component Quantities - WSP_beton - ihwg beton, Mass: 887.213 kg; WSP_beton - ihwg beton, Component Volume (Net): 0.385745 m3; WSP_beton - ihwg beton, Component Volume (Gross): 0.385745 m3
Pset_ReinforcementBarPitchOfSlab - Reference: ø300 (schroef)

# IfcSlab: Slab 242, 17_WSP_FD_beton - fundatiepaal v21-2:ø300 (schroef):1473355
In: -2 fundering
Classification: Vloerplaat - fundering (ARCHICAD Classification); Material: WSP_beton - ihwg beton
Pset_SlabCommon - Reference: ø300 (schroef); IsExternal: yes; LoadBearing: no
Pset_ReinforcementBarPitchOfSlab - Reference: ø300 (schroef)
Component Quantities - WSP_beton - ihwg beton, Mass: 887.213 kg; WSP_beton - ihwg beton, Component Volume (Net): 0.385745 m3; WSP_beton - ihwg beton, Component Volume (Gross): 0.385745 m3
CPset_Phasing - Renovation Phase: Bestaand

# IfcSlab: Slab 243, 17_WSP_FD_beton - fundatiepaal v21-2:ø300 (schroef):1473352
In: -2 fundering
Classification: Vloerplaat - fundering (ARCHICAD Classification); Material: WSP_beton - ihwg beton
Pset_SlabCommon - Reference: ø300 (schroef); IsExternal: yes; LoadBearing: no
Pset_ReinforcementBarPitchOfSlab - Reference: ø300 (schroef)
CPset_Phasing - Renovation Phase: Bestaand
Component Quantities - WSP_beton - ihwg beton, Mass: 887.213 kg; WSP_beton - ihwg beton, Component Volume (Net): 0.385745 m3; WSP_beton - ihwg beton, Component Volume (Gross): 0.385745 m3

# IfcSlab: Slab 244, 17_WSP_FD_beton - fundatiepaal v21-2:ø300 (schroef):1473353
In: -2 fundering
Classification: Vloerplaat - fundering (ARCHICAD Classification); Material: WSP_beton - ihwg beton
Pset_ReinforcementBarPitchOfSlab - Reference: ø300 (schroef)
Pset_SlabCommon - Reference: ø300 (schroef); IsExternal: yes; LoadBearing: no
Component Quantities - WSP_beton - ihwg beton, Mass: 887.213 kg; WSP_beton - ihwg beton, Component Volume (Net): 0.385745 m3; WSP_beton - ihwg beton, Component Volume (Gross): 0.385745 m3
CPset_Phasing - Renovation Phase: Bestaand

# IfcSlab: Slab 245, 17_WSP_FD_beton - fundatiepaal v21-2:ø300 (schroef):1473358
In: -2 fundering
Classification: Vloerplaat - fundering (ARCHICAD Classification); Material: WSP_beton - ihwg beton
Pset_ReinforcementBarPitchOfSlab - Reference: ø300 (schroef)
Pset_SlabCommon - Reference: ø300 (schroef); IsExternal: yes; LoadBearing: no
Component Quantities - WSP_beton - ihwg beton, Mass: 887.213 kg; WSP_beton - ihwg beton, Component Volume (Net): 0.385745 m3; WSP_beton - ihwg beton, Component Volume (Gross): 0.385745 m3
CPset_Phasing - Renovation Phase: Bestaand

# IfcSlab: Slab 246, 17_WSP_FD_beton - fundatiepaal v21-2:ø300 (schroef):1473359
In: -2 fundering
Classification: Vloerplaat - fundering (ARCHICAD Classification); Material: WSP_beton - ihwg beton
Pset_ReinforcementBarPitchOfSlab - Reference: ø300 (schroef)
Pset_SlabCommon - Reference: ø300 (schroef); IsExternal: yes; LoadBearing: no
CPset_Phasing - Renovation Phase: Bestaand
Component Quantities - WSP_beton - ihwg beton, Mass: 887.213 kg; WSP_beton - ihwg beton, Component Volume (Net): 0.385745 m3; WSP_beton - ihwg beton, Component Volume (Gross): 0.385745 m3

# IfcSlab: Slab 247, 17_WSP_FD_beton - fundatiepaal v21-2:ø300 (schroef):1473356
In: -2 fundering
Classification: Vloerplaat - fundering (ARCHICAD Classification); Material: WSP_beton - ihwg beton
Pset_SlabCommon - Reference: ø300 (schroef); IsExternal: yes; LoadBearing: no
Component Quantities - WSP_beton - ihwg beton, Mass: 887.213 kg; WSP_beton - ihwg beton, Component Volume (Net): 0.385745 m3; WSP_beton - ihwg beton, Component Volume (Gross): 0.385745 m3
CPset_Phasing - Renovation Phase: Bestaand
Pset_ReinforcementBarPitchOfSlab - Reference: ø300 (schroef)

# IfcSlab: Slab 248, 17_WSP_FD_beton - fundatiepaal v21-2:ø300 (schroef):1473357
In: -2 fundering
Classification: Vloerplaat - fundering (ARCHICAD Classification); Material: WSP_beton - ihwg beton
Pset_ReinforcementBarPitchOfSlab - Reference: ø300 (schroef)
Pset_SlabCommon - Reference: ø300 (schroef); IsExternal: yes; LoadBearing: no
CPset_Phasing - Renovation Phase: Bestaand
Component Quantities - WSP_beton - ihwg beton, Mass: 887.213 kg; WSP_beton - ihwg beton, Component Volume (Net): 0.385745 m3; WSP_beton - ihwg beton, Component Volume (Gross): 0.385745 m3

# IfcSlab: Slab 249, 17_WSP_FD_beton - fundatiepaal v21-2:ø300 (schroef):1473362
In: -2 fundering
Classification: Vloerplaat - fundering (ARCHICAD Classification); Material: WSP_beton - ihwg beton
Pset_SlabCommon - Reference: ø300 (schroef); IsExternal: yes; LoadBearing: no
Pset_ReinforcementBarPitchOfSlab - Reference: ø300 (schroef)
CPset_Phasing - Renovation Phase: Bestaand
Component Quantities - WSP_beton - ihwg beton, Mass: 887.213 kg; WSP_beton - ihwg beton, Component Volume (Net): 0.385745 m3; WSP_beton - ihwg beton, Component Volume (Gross): 0.385745 m3

# IfcSlab: Slab 25, 17_WSP_FD_beton - fundatiepaal v21-2:ø300 (schroef):1528481
In: -2 fundering
Classification: Vloerplaat - fundering (ARCHICAD Classification); Material: WSP_beton - ihwg beton
CPset_Phasing - Renovation Phase: Bestaand
Pset_ReinforcementBarPitchOfSlab - Reference: ø300 (schroef)
Pset_SlabCommon - Reference: ø300 (schroef); IsExternal: yes; LoadBearing: no
Component Quantities - WSP_beton - ihwg beton, Mass: 903.056 kg; WSP_beton - ihwg beton, Component Volume (Net): 0.392633 m3; WSP_beton - ihwg beton, Component Volume (Gross): 0.392633 m3

# IfcSlab: Slab 250, 17_WSP_FD_beton - fundatiepaal v21-2:ø300 (schroef):1473363
In: -2 fundering
Classification: Vloerplaat - fundering (ARCHICAD Classification); Material: WSP_beton - ihwg beton
Pset_ReinforcementBarPitchOfSlab - Reference: ø300 (schroef)
CPset_Phasing - Renovation Phase: Bestaand
Component Quantities - WSP_beton - ihwg beton, Mass: 887.213 kg; WSP_beton - ihwg beton, Component Volume (Net): 0.385745 m3; WSP_beton - ihwg beton, Component Volume (Gross): 0.385745 m3
Pset_SlabCommon - Reference: ø300 (schroef); IsExternal: yes; LoadBearing: no

# IfcSlab: Slab 251, 17_WSP_FD_beton - fundatiepaal v21-2:ø300 (schroef):1473360
In: -2 fundering
Classification: Vloerplaat - fundering (ARCHICAD Classification); Material: WSP_beton - ihwg beton
Pset_ReinforcementBarPitchOfSlab - Reference: ø300 (schroef)
CPset_Phasing - Renovation Phase: Bestaand
Component Quantities - WSP_beton - ihwg beton, Mass: 887.213 kg; WSP_beton - ihwg beton, Component Volume (Net): 0.385745 m3; WSP_beton - ihwg beton, Component Volume (Gross): 0.385745 m3
Pset_SlabCommon - Reference: ø300 (schroef); IsExternal: yes; LoadBearing: no

# IfcSlab: Slab 252, 17_WSP_FD_beton - fundatiepaal v21-2:ø300 (schroef):1473361
In: -2 fundering
Classification: Vloerplaat - fundering (ARCHICAD Classification); Material: WSP_beton - ihwg beton
Pset_SlabCommon - Reference: ø300 (schroef); IsExternal: yes; LoadBearing: no
Pset_ReinforcementBarPitchOfSlab - Reference: ø300 (schroef)
CPset_Phasing - Renovation Phase: Bestaand
Component Quantities - WSP_beton - ihwg beton, Mass: 887.213 kg; WSP_beton - ihwg beton, Component Volume (Net): 0.385745 m3; WSP_beton - ihwg beton, Component Volume (Gross): 0.385745 m3

# IfcSlab: Slab 253, 17_WSP_FD_beton - fundatiepaal v21-2:ø300 (schroef):1473364
In: -2 fundering
Classification: Vloerplaat - fundering (ARCHICAD Classification); Material: WSP_beton - ihwg beton
Pset_SlabCommon - Reference: ø300 (schroef); IsExternal: yes; LoadBearing: no
Pset_ReinforcementBarPitchOfSlab - Reference: ø300 (schroef)
Component Quantities - WSP_beton - ihwg beton, Mass: 887.213 kg; WSP_beton - ihwg beton, Component Volume (Net): 0.385745 m3; WSP_beton - ihwg beton, Component Volume (Gross): 0.385745 m3
CPset_Phasing - Renovation Phase: Bestaand

# IfcSlab: Slab 254, 17_WSP_FD_beton - fundatiepaal v21-2:ø300 (schroef):1473365
In: -2 fundering
Classification: Vloerplaat - fundering (ARCHICAD Classification); Material: WSP_beton - ihwg beton
Pset_SlabCommon - Reference: ø300 (schroef); IsExternal: yes; LoadBearing: no
Pset_ReinforcementBarPitchOfSlab - Reference: ø300 (schroef)
CPset_Phasing - Renovation Phase: Bestaand
Component Quantities - WSP_beton - ihwg beton, Mass: 887.213 kg; WSP_beton - ihwg beton, Component Volume (Net): 0.385745 m3; WSP_beton - ihwg beton, Component Volume (Gross): 0.385745 m3

# IfcSlab: Slab 255, 17_WSP_FD_beton - fundatiepaal v21-2:ø300 (schroef):1473506
In: -2 fundering
Classification: Vloerplaat - fundering (ARCHICAD Classification); Material: WSP_beton - ihwg beton
Pset_SlabCommon - Reference: ø300 (schroef); IsExternal: yes; LoadBearing: no
CPset_Phasing - Renovation Phase: Bestaand
Pset_ReinforcementBarPitchOfSlab - Reference: ø300 (schroef)
Component Quantities - WSP_beton - ihwg beton, Mass: 903.056 kg; WSP_beton - ihwg beton, Component Volume (Net): 0.392633 m3; WSP_beton - ihwg beton, Component Volume (Gross): 0.392633 m3

# IfcSlab: Slab 256, 17_WSP_FD_beton - fundatiepaal v21-2:ø300 (schroef):1473507
In: -2 fundering
Classification: Vloerplaat - fundering (ARCHICAD Classification); Material: WSP_beton - ihwg beton
Pset_SlabCommon - Reference: ø300 (schroef); IsExternal: yes; LoadBearing: no
Pset_ReinforcementBarPitchOfSlab - Reference: ø300 (schroef)
CPset_Phasing - Renovation Phase: Bestaand
Component Quantities - WSP_beton - ihwg beton, Mass: 903.056 kg; WSP_beton - ihwg beton, Component Volume (Net): 0.392633 m3; WSP_beton - ihwg beton, Component Volume (Gross): 0.392633 m3

# IfcSlab: Slab 257, 17_WSP_FD_beton - fundatiepaal v21-2:ø300 (schroef):1473504
In: -2 fundering
Classification: Vloerplaat - fundering (ARCHICAD Classification); Material: WSP_beton - ihwg beton
Pset_ReinforcementBarPitchOfSlab - Reference: ø300 (schroef)
Pset_SlabCommon - Reference: ø300 (schroef); IsExternal: yes; LoadBearing: no
Component Quantities - WSP_beton - ihwg beton, Mass: 903.056 kg; WSP_beton - ihwg beton, Component Volume (Net): 0.392633 m3; WSP_beton - ihwg beton, Component Volume (Gross): 0.392633 m3
CPset_Phasing - Renovation Phase: Bestaand

# IfcSlab: Slab 258, 17_WSP_FD_beton - fundatiepaal v21-2:ø300 (schroef):1473505
In: -2 fundering
Classification: Vloerplaat - fundering (ARCHICAD Classification); Material: WSP_beton - ihwg beton
Component Quantities - WSP_beton - ihwg beton, Mass: 903.056 kg; WSP_beton - ihwg beton, Component Volume (Net): 0.392633 m3; WSP_beton - ihwg beton, Component Volume (Gross): 0.392633 m3
Pset_ReinforcementBarPitchOfSlab - Reference: ø300 (schroef)
Pset_SlabCommon - Reference: ø300 (schroef); IsExternal: yes; LoadBearing: no
CPset_Phasing - Renovation Phase: Bestaand

# IfcSlab: Slab 259, 17_WSP_FD_beton - fundatiepaal v21-2:ø300 (schroef):1473510
In: -2 fundering
Classification: Vloerplaat - fundering (ARCHICAD Classification); Material: WSP_beton - ihwg beton
Pset_SlabCommon - Reference: ø300 (schroef); IsExternal: yes; LoadBearing: no
Pset_ReinforcementBarPitchOfSlab - Reference: ø300 (schroef)
Component Quantities - WSP_beton - ihwg beton, Mass: 903.056 kg; WSP_beton - ihwg beton, Component Volume (Net): 0.392633 m3; WSP_beton - ihwg beton, Component Volume (Gross): 0.392633 m3
CPset_Phasing - Renovation Phase: Bestaand

# IfcSlab: Slab 26, 17_WSP_FD_beton - fundatiepaal v21-2:ø300 (schroef):1528480
In: -2 fundering
Classification: Vloerplaat - fundering (ARCHICAD Classification); Material: WSP_beton - ihwg beton
Pset_SlabCommon - Reference: ø300 (schroef); IsExternal: yes; LoadBearing: no
Pset_ReinforcementBarPitchOfSlab - Reference: ø300 (schroef)
CPset_Phasing - Renovation Phase: Bestaand
Component Quantities - WSP_beton - ihwg beton, Mass: 903.056 kg; WSP_beton - ihwg beton, Component Volume (Net): 0.392633 m3; WSP_beton - ihwg beton, Component Volume (Gross): 0.392633 m3

# IfcSlab: Slab 260, 17_WSP_FD_beton - fundatiepaal v21-2:ø300 (schroef):1473511
In: -2 fundering
Classification: Vloerplaat - fundering (ARCHICAD Classification); Material: WSP_beton - ihwg beton
Pset_SlabCommon - Reference: ø300 (schroef); IsExternal: yes; LoadBearing: no
Pset_ReinforcementBarPitchOfSlab - Reference: ø300 (schroef)
Component Quantities - WSP_beton - ihwg beton, Mass: 903.056 kg; WSP_beton - ihwg beton, Component Volume (Net): 0.392633 m3; WSP_beton - ihwg beton, Component Volume (Gross): 0.392633 m3
CPset_Phasing - Renovation Phase: Bestaand

# IfcSlab: Slab 261, 17_WSP_FD_beton - fundatiepaal v21-2:ø300 (schroef):1473508
In: -2 fundering
Classification: Vloerplaat - fundering (ARCHICAD Classification); Material: WSP_beton - ihwg beton
Pset_SlabCommon - Reference: ø300 (schroef); IsExternal: yes; LoadBearing: no
CPset_Phasing - Renovation Phase: Bestaand
Pset_ReinforcementBarPitchOfSlab - Reference: ø300 (schroef)
Component Quantities - WSP_beton - ihwg beton, Mass: 903.056 kg; WSP_beton - ihwg beton, Component Volume (Net): 0.392633 m3; WSP_beton - ihwg beton, Component Volume (Gross): 0.392633 m3

# IfcSlab: Slab 262, 17_WSP_FD_beton - fundatiepaal v21-2:ø300 (schroef):1473509
In: -2 fundering
Classification: Vloerplaat - fundering (ARCHICAD Classification); Material: WSP_beton - ihwg beton
CPset_Phasing - Renovation Phase: Bestaand
Pset_ReinforcementBarPitchOfSlab - Reference: ø300 (schroef)
Pset_SlabCommon - Reference: ø300 (schroef); IsExternal: yes; LoadBearing: no
Component Quantities - WSP_beton - ihwg beton, Mass: 903.056 kg; WSP_beton - ihwg beton, Component Volume (Net): 0.392633 m3; WSP_beton - ihwg beton, Component Volume (Gross): 0.392633 m3

# IfcSlab: Slab 263, 17_WSP_FD_beton - fundatiepaal v21-2:ø300 (schroef):1473514
In: -2 fundering
Classification: Vloerplaat - fundering (ARCHICAD Classification); Material: WSP_beton - ihwg beton
Pset_ReinforcementBarPitchOfSlab - Reference: ø300 (schroef)
CPset_Phasing - Renovation Phase: Bestaand
Pset_SlabCommon - Reference: ø300 (schroef); IsExternal: yes; LoadBearing: no
Component Quantities - WSP_beton - ihwg beton, Mass: 903.056 kg; WSP_beton - ihwg beton, Component Volume (Net): 0.392633 m3; WSP_beton - ihwg beton, Component Volume (Gross): 0.392633 m3

# IfcSlab: Slab 264, 17_WSP_FD_beton - fundatiepaal v21-2:ø300 (schroef):1473515
In: -2 fundering
Classification: Vloerplaat - fundering (ARCHICAD Classification); Material: WSP_beton - ihwg beton
Pset_SlabCommon - Reference: ø300 (schroef); IsExternal: yes; LoadBearing: no
CPset_Phasing - Renovation Phase: Bestaand
Component Quantities - WSP_beton - ihwg beton, Mass: 903.056 kg; WSP_beton - ihwg beton, Component Volume (Net): 0.392633 m3; WSP_beton - ihwg beton, Component Volume (Gross): 0.392633 m3
Pset_ReinforcementBarPitchOfSlab - Reference: ø300 (schroef)

# IfcSlab: Slab 265, 17_WSP_FD_beton - fundatiepaal v21-2:ø300 (schroef):1473512
In: -2 fundering
Classification: Vloerplaat - fundering (ARCHICAD Classification); Material: WSP_beton - ihwg beton
Pset_SlabCommon - Reference: ø300 (schroef); IsExternal: yes; LoadBearing: no
CPset_Phasing - Renovation Phase: Bestaand
Component Quantities - WSP_beton - ihwg beton, Mass: 903.056 kg; WSP_beton - ihwg beton, Component Volume (Net): 0.392633 m3; WSP_beton - ihwg beton, Component Volume (Gross): 0.392633 m3
Pset_ReinforcementBarPitchOfSlab - Reference: ø300 (schroef)

# IfcSlab: Slab 266, 17_WSP_FD_beton - fundatiepaal v21-2:ø300 (schroef):1473513
In: -2 fundering
Classification: Vloerplaat - fundering (ARCHICAD Classification); Material: WSP_beton - ihwg beton
Pset_SlabCommon - Reference: ø300 (schroef); IsExternal: yes; LoadBearing: no
CPset_Phasing - Renovation Phase: Bestaand
Pset_ReinforcementBarPitchOfSlab - Reference: ø300 (schroef)
Component Quantities - WSP_beton - ihwg beton, Mass: 903.056 kg; WSP_beton - ihwg beton, Component Volume (Net): 0.392633 m3; WSP_beton - ihwg beton, Component Volume (Gross): 0.392633 m3

# IfcSlab: Slab 267, 17_WSP_FD_beton - fundatiepaal v21-2:ø300 (schroef):1473518
In: -2 fundering
Classification: Vloerplaat - fundering (ARCHICAD Classification); Material: WSP_beton - ihwg beton
Pset_SlabCommon - Reference: ø300 (schroef); IsExternal: yes; LoadBearing: no
Component Quantities - WSP_beton - ihwg beton, Mass: 903.056 kg; WSP_beton - ihwg beton, Component Volume (Net): 0.392633 m3; WSP_beton - ihwg beton, Component Volume (Gross): 0.392633 m3
Pset_ReinforcementBarPitchOfSlab - Reference: ø300 (schroef)
CPset_Phasing - Renovation Phase: Bestaand

# IfcSlab: Slab 268, 17_WSP_FD_beton - fundatiepaal v21-2:ø300 (schroef):1473519
In: -2 fundering
Classification: Vloerplaat - fundering (ARCHICAD Classification); Material: WSP_beton - ihwg beton
Pset_ReinforcementBarPitchOfSlab - Reference: ø300 (schroef)
Pset_SlabCommon - Reference: ø300 (schroef); IsExternal: yes; LoadBearing: no
Component Quantities - WSP_beton - ihwg beton, Mass: 903.056 kg; WSP_beton - ihwg beton, Component Volume (Net): 0.392633 m3; WSP_beton - ihwg beton, Component Volume (Gross): 0.392633 m3
CPset_Phasing - Renovation Phase: Bestaand

# IfcSlab: Slab 269, 17_WSP_FD_beton - fundatiepaal v21-2:ø300 (schroef):1473516
In: -2 fundering
Classification: Vloerplaat - fundering (ARCHICAD Classification); Material: WSP_beton - ihwg beton
Pset_ReinforcementBarPitchOfSlab - Reference: ø300 (schroef)
Pset_SlabCommon - Reference: ø300 (schroef); IsExternal: yes; LoadBearing: no
CPset_Phasing - Renovation Phase: Bestaand
Component Quantities - WSP_beton - ihwg beton, Mass: 903.056 kg; WSP_beton - ihwg beton, Component Volume (Net): 0.392633 m3; WSP_beton - ihwg beton, Component Volume (Gross): 0.392633 m3

# IfcSlab: Slab 27, 17_WSP_FD_beton - fundatiepaal v21-2:ø300 (schroef):1528483
In: -2 fundering
Classification: Vloerplaat - fundering (ARCHICAD Classification); Material: WSP_beton - ihwg beton
Pset_SlabCommon - Reference: ø300 (schroef); IsExternal: yes; LoadBearing: no
Pset_ReinforcementBarPitchOfSlab - Reference: ø300 (schroef)
CPset_Phasing - Renovation Phase: Bestaand
Component Quantities - WSP_beton - ihwg beton, Mass: 903.056 kg; WSP_beton - ihwg beton, Component Volume (Net): 0.392633 m3; WSP_beton - ihwg beton, Component Volume (Gross): 0.392633 m3

# IfcSlab: Slab 270, 17_WSP_FD_beton - fundatiepaal v21-2:ø300 (schroef):1473517
In: -2 fundering
Classification: Vloerplaat - fundering (ARCHICAD Classification); Material: WSP_beton - ihwg beton
Pset_ReinforcementBarPitchOfSlab - Reference: ø300 (schroef)
Pset_SlabCommon - Reference: ø300 (schroef); IsExternal: yes; LoadBearing: no
CPset_Phasing - Renovation Phase: Bestaand
Component Quantities - WSP_beton - ihwg beton, Mass: 903.056 kg; WSP_beton - ihwg beton, Component Volume (Net): 0.392633 m3; WSP_beton - ihwg beton, Component Volume (Gross): 0.392633 m3

# IfcSlab: Slab 271, 17_WSP_FD_beton - fundatiepaal v21-2:ø300 (schroef):1473522
In: -2 fundering
Classification: Vloerplaat - fundering (ARCHICAD Classification); Material: WSP_beton - ihwg beton
Pset_ReinforcementBarPitchOfSlab - Reference: ø300 (schroef)
Pset_SlabCommon - Reference: ø300 (schroef); IsExternal: yes; LoadBearing: no
Component Quantities - WSP_beton - ihwg beton, Mass: 903.056 kg; WSP_beton - ihwg beton, Component Volume (Net): 0.392633 m3; WSP_beton - ihwg beton, Component Volume (Gross): 0.392633 m3
CPset_Phasing - Renovation Phase: Bestaand

# IfcSlab: Slab 272, 17_WSP_FD_beton - fundatiepaal v21-2:ø300 (schroef):1473523
In: -2 fundering
Classification: Vloerplaat - fundering (ARCHICAD Classification); Material: WSP_beton - ihwg beton
Pset_ReinforcementBarPitchOfSlab - Reference: ø300 (schroef)
Pset_SlabCommon - Reference: ø300 (schroef); IsExternal: yes; LoadBearing: no
CPset_Phasing - Renovation Phase: Bestaand
Component Quantities - WSP_beton - ihwg beton, Mass: 903.056 kg; WSP_beton - ihwg beton, Component Volume (Net): 0.392633 m3; WSP_beton - ihwg beton, Component Volume (Gross): 0.392633 m3

# IfcSlab: Slab 273, 17_WSP_FD_beton - fundatiepaal v21-2:ø300 (schroef):1473520
In: -2 fundering
Classification: Vloerplaat - fundering (ARCHICAD Classification); Material: WSP_beton - ihwg beton
Pset_ReinforcementBarPitchOfSlab - Reference: ø300 (schroef)
CPset_Phasing - Renovation Phase: Bestaand
Pset_SlabCommon - Reference: ø300 (schroef); IsExternal: yes; LoadBearing: no
Component Quantities - WSP_beton - ihwg beton, Mass: 903.056 kg; WSP_beton - ihwg beton, Component Volume (Net): 0.392633 m3; WSP_beton - ihwg beton, Component Volume (Gross): 0.392633 m3

# IfcSlab: Slab 274, 17_WSP_FD_beton - fundatiepaal v21-2:ø300 (schroef):1473521
In: -2 fundering
Classification: Vloerplaat - fundering (ARCHICAD Classification); Material: WSP_beton - ihwg beton
CPset_Phasing - Renovation Phase: Bestaand
Pset_ReinforcementBarPitchOfSlab - Reference: ø300 (schroef)
Pset_SlabCommon - Reference: ø300 (schroef); IsExternal: yes; LoadBearing: no
Component Quantities - WSP_beton - ihwg beton, Mass: 903.056 kg; WSP_beton - ihwg beton, Component Volume (Net): 0.392633 m3; WSP_beton - ihwg beton, Component Volume (Gross): 0.392633 m3

# IfcSlab: Slab 275, 17_WSP_FD_beton - fundatiepaal v21-2:ø300 (schroef):1473526
In: -2 fundering
Classification: Vloerplaat - fundering (ARCHICAD Classification); Material: WSP_beton - ihwg beton
Pset_SlabCommon - Reference: ø300 (schroef); IsExternal: yes; LoadBearing: no
CPset_Phasing - Renovation Phase: Bestaand
Pset_ReinforcementBarPitchOfSlab - Reference: ø300 (schroef)
Component Quantities - WSP_beton - ihwg beton, Mass: 903.056 kg; WSP_beton - ihwg beton, Component Volume (Net): 0.392633 m3; WSP_beton - ihwg beton, Component Volume (Gross): 0.392633 m3

# IfcSlab: Slab 276, 17_WSP_FD_beton - fundatiepaal v21-2:ø300 (schroef):1473527
In: -2 fundering
Classification: Vloerplaat - fundering (ARCHICAD Classification); Material: WSP_beton - ihwg beton
Pset_SlabCommon - Reference: ø300 (schroef); IsExternal: yes; LoadBearing: no
Pset_ReinforcementBarPitchOfSlab - Reference: ø300 (schroef)
CPset_Phasing - Renovation Phase: Bestaand
Component Quantities - WSP_beton - ihwg beton, Mass: 903.056 kg; WSP_beton - ihwg beton, Component Volume (Net): 0.392633 m3; WSP_beton - ihwg beton, Component Volume (Gross): 0.392633 m3

# IfcSlab: Slab 277, 17_WSP_FD_beton - fundatiepaal v21-2:ø300 (schroef):1473524
In: -2 fundering
Classification: Vloerplaat - fundering (ARCHICAD Classification); Material: WSP_beton - ihwg beton
Pset_SlabCommon - Reference: ø300 (schroef); IsExternal: yes; LoadBearing: no
Pset_ReinforcementBarPitchOfSlab - Reference: ø300 (schroef)
CPset_Phasing - Renovation Phase: Bestaand
Component Quantities - WSP_beton - ihwg beton, Mass: 903.056 kg; WSP_beton - ihwg beton, Component Volume (Net): 0.392633 m3; WSP_beton - ihwg beton, Component Volume (Gross): 0.392633 m3

# IfcSlab: Slab 278, 17_WSP_FD_beton - fundatiepaal v21-2:ø300 (schroef):1473525
In: -2 fundering
Classification: Vloerplaat - fundering (ARCHICAD Classification); Material: WSP_beton - ihwg beton
Pset_ReinforcementBarPitchOfSlab - Reference: ø300 (schroef)
Pset_SlabCommon - Reference: ø300 (schroef); IsExternal: yes; LoadBearing: no
CPset_Phasing - Renovation Phase: Bestaand
Component Quantities - WSP_beton - ihwg beton, Mass: 903.056 kg; WSP_beton - ihwg beton, Component Volume (Net): 0.392633 m3; WSP_beton - ihwg beton, Component Volume (Gross): 0.392633 m3

# IfcSlab: Slab 279, 17_WSP_FD_beton - fundatiepaal v21-2:ø300 (schroef):1473530
In: -2 fundering
Classification: Vloerplaat - fundering (ARCHICAD Classification); Material: WSP_beton - ihwg beton
Pset_SlabCommon - Reference: ø300 (schroef); IsExternal: yes; LoadBearing: no
CPset_Phasing - Renovation Phase: Bestaand
Component Quantities - WSP_beton - ihwg beton, Mass: 903.056 kg; WSP_beton - ihwg beton, Component Volume (Net): 0.392633 m3; WSP_beton - ihwg beton, Component Volume (Gross): 0.392633 m3
Pset_ReinforcementBarPitchOfSlab - Reference: ø300 (schroef)

# IfcSlab: Slab 28, 17_WSP_FD_beton - fundatiepaal v21-2:ø300 (schroef):1528482
In: -2 fundering
Classification: Vloerplaat - fundering (ARCHICAD Classification); Material: WSP_beton - ihwg beton
Pset_SlabCommon - Reference: ø300 (schroef); IsExternal: yes; LoadBearing: no
Pset_ReinforcementBarPitchOfSlab - Reference: ø300 (schroef)
CPset_Phasing - Renovation Phase: Bestaand
Component Quantities - WSP_beton - ihwg beton, Mass: 903.056 kg; WSP_beton - ihwg beton, Component Volume (Net): 0.392633 m3; WSP_beton - ihwg beton, Component Volume (Gross): 0.392633 m3

# IfcSlab: Slab 280, 17_WSP_FD_beton - fundatiepaal v21-2:ø300 (schroef):1473531
In: -2 fundering
Classification: Vloerplaat - fundering (ARCHICAD Classification); Material: WSP_beton - ihwg beton
Pset_SlabCommon - Reference: ø300 (schroef); IsExternal: yes; LoadBearing: no
Pset_ReinforcementBarPitchOfSlab - Reference: ø300 (schroef)
CPset_Phasing - Renovation Phase: Bestaand
Component Quantities - WSP_beton - ihwg beton, Mass: 903.056 kg; WSP_beton - ihwg beton, Component Volume (Net): 0.392633 m3; WSP_beton - ihwg beton, Component Volume (Gross): 0.392633 m3

# IfcSlab: Slab 281, 17_WSP_FD_beton - fundatiepaal v21-2:ø300 (schroef):1473528
In: -2 fundering
Classification: Vloerplaat - fundering (ARCHICAD Classification); Material: WSP_beton - ihwg beton
Pset_ReinforcementBarPitchOfSlab - Reference: ø300 (schroef)
Pset_SlabCommon - Reference: ø300 (schroef); IsExternal: yes; LoadBearing: no
CPset_Phasing - Renovation Phase: Bestaand
Component Quantities - WSP_beton - ihwg beton, Mass: 903.056 kg; WSP_beton - ihwg beton, Component Volume (Net): 0.392633 m3; WSP_beton - ihwg beton, Component Volume (Gross): 0.392633 m3

# IfcSlab: Slab 282, 17_WSP_FD_beton - fundatiepaal v21-2:ø300 (schroef):1473529
In: -2 fundering
Classification: Vloerplaat - fundering (ARCHICAD Classification); Material: WSP_beton - ihwg beton
Pset_SlabCommon - Reference: ø300 (schroef); IsExternal: yes; LoadBearing: no
Pset_ReinforcementBarPitchOfSlab - Reference: ø300 (schroef)
Component Quantities - WSP_beton - ihwg beton, Mass: 903.056 kg; WSP_beton - ihwg beton, Component Volume (Net): 0.392633 m3; WSP_beton - ihwg beton, Component Volume (Gross): 0.392633 m3
CPset_Phasing - Renovation Phase: Bestaand

# IfcSlab: Slab 283, 17_WSP_FD_beton - fundatiepaal v21-2:ø300 (schroef):1473534
In: -2 fundering
Classification: Vloerplaat - fundering (ARCHICAD Classification); Material: WSP_beton - ihwg beton
Pset_SlabCommon - Reference: ø300 (schroef); IsExternal: yes; LoadBearing: no
Component Quantities - WSP_beton - ihwg beton, Mass: 903.056 kg; WSP_beton - ihwg beton, Component Volume (Net): 0.392633 m3; WSP_beton - ihwg beton, Component Volume (Gross): 0.392633 m3
CPset_Phasing - Renovation Phase: Bestaand
Pset_ReinforcementBarPitchOfSlab - Reference: ø300 (schroef)

# IfcSlab: Slab 284, 17_WSP_FD_beton - fundatiepaal v21-2:ø300 (schroef):1473535
In: -2 fundering
Classification: Vloerplaat - fundering (ARCHICAD Classification); Material: WSP_beton - ihwg beton
Pset_ReinforcementBarPitchOfSlab - Reference: ø300 (schroef)
Component Quantities - WSP_beton - ihwg beton, Mass: 903.056 kg; WSP_beton - ihwg beton, Component Volume (Net): 0.392633 m3; WSP_beton - ihwg beton, Component Volume (Gross): 0.392633 m3
CPset_Phasing - Renovation Phase: Bestaand
Pset_SlabCommon - Reference: ø300 (schroef); IsExternal: yes; LoadBearing: no

# IfcSlab: Slab 285, 17_WSP_FD_beton - fundatiepaal v21-2:ø300 (schroef):1473532
In: -2 fundering
Classification: Vloerplaat - fundering (ARCHICAD Classification); Material: WSP_beton - ihwg beton
Component Quantities - WSP_beton - ihwg beton, Mass: 903.056 kg; WSP_beton - ihwg beton, Component Volume (Net): 0.392633 m3; WSP_beton - ihwg beton, Component Volume (Gross): 0.392633 m3
CPset_Phasing - Renovation Phase: Bestaand
Pset_ReinforcementBarPitchOfSlab - Reference: ø300 (schroef)
Pset_SlabCommon - Reference: ø300 (schroef); IsExternal: yes; LoadBearing: no

# IfcSlab: Slab 286, 17_WSP_FD_beton - fundatiepaal v21-2:ø300 (schroef):1473533
In: -2 fundering
Classification: Vloerplaat - fundering (ARCHICAD Classification); Material: WSP_beton - ihwg beton
Pset_ReinforcementBarPitchOfSlab - Reference: ø300 (schroef)
Pset_SlabCommon - Reference: ø300 (schroef); IsExternal: yes; LoadBearing: no
Component Quantities - WSP_beton - ihwg beton, Mass: 903.056 kg; WSP_beton - ihwg beton, Component Volume (Net): 0.392633 m3; WSP_beton - ihwg beton, Component Volume (Gross): 0.392633 m3
CPset_Phasing - Renovation Phase: Bestaand

# IfcSlab: Slab 287, 17_WSP_FD_beton - fundatiepaal v21-2:ø300 (schroef):1473474
In: -2 fundering
Classification: Vloerplaat - fundering (ARCHICAD Classification); Material: WSP_beton - ihwg beton
Pset_SlabCommon - Reference: ø300 (schroef); IsExternal: yes; LoadBearing: no
Pset_ReinforcementBarPitchOfSlab - Reference: ø300 (schroef)
CPset_Phasing - Renovation Phase: Bestaand
Component Quantities - WSP_beton - ihwg beton, Mass: 903.056 kg; WSP_beton - ihwg beton, Component Volume (Net): 0.392633 m3; WSP_beton - ihwg beton, Component Volume (Gross): 0.392633 m3

# IfcSlab: Slab 288, 17_WSP_FD_beton - fundatiepaal v21-2:ø300 (schroef):1473475
In: -2 fundering
Classification: Vloerplaat - fundering (ARCHICAD Classification); Material: WSP_beton - ihwg beton
Pset_SlabCommon - Reference: ø300 (schroef); IsExternal: yes; LoadBearing: no
Pset_ReinforcementBarPitchOfSlab - Reference: ø300 (schroef)
CPset_Phasing - Renovation Phase: Bestaand
Component Quantities - WSP_beton - ihwg beton, Mass: 903.056 kg; WSP_beton - ihwg beton, Component Volume (Net): 0.392633 m3; WSP_beton - ihwg beton, Component Volume (Gross): 0.392633 m3

# IfcSlab: Slab 289, 17_WSP_FD_beton - fundatiepaal v21-2:ø300 (schroef):1473472
In: -2 fundering
Classification: Vloerplaat - fundering (ARCHICAD Classification); Material: WSP_beton - ihwg beton
Pset_ReinforcementBarPitchOfSlab - Reference: ø300 (schroef)
Component Quantities - WSP_beton - ihwg beton, Mass: 903.056 kg; WSP_beton - ihwg beton, Component Volume (Net): 0.392633 m3; WSP_beton - ihwg beton, Component Volume (Gross): 0.392633 m3
CPset_Phasing - Renovation Phase: Bestaand
Pset_SlabCommon - Reference: ø300 (schroef); IsExternal: yes; LoadBearing: no

# IfcSlab: Slab 29, 17_WSP_FD_beton - fundatiepaal v21-2:ø300 (schroef):1528492
In: -2 fundering
Classification: Vloerplaat - fundering (ARCHICAD Classification); Material: WSP_beton - ihwg beton
Pset_SlabCommon - Reference: ø300 (schroef); IsExternal: yes; LoadBearing: no
CPset_Phasing - Renovation Phase: Bestaand
Pset_ReinforcementBarPitchOfSlab - Reference: ø300 (schroef)
Component Quantities - WSP_beton - ihwg beton, Mass: 887.213 kg; WSP_beton - ihwg beton, Component Volume (Net): 0.385745 m3; WSP_beton - ihwg beton, Component Volume (Gross): 0.385745 m3

# IfcSlab: Slab 290, 17_WSP_FD_beton - fundatiepaal v21-2:ø300 (schroef):1473473
In: -2 fundering
Classification: Vloerplaat - fundering (ARCHICAD Classification); Material: WSP_beton - ihwg beton
Pset_SlabCommon - Reference: ø300 (schroef); IsExternal: yes; LoadBearing: no
Pset_ReinforcementBarPitchOfSlab - Reference: ø300 (schroef)
Component Quantities - WSP_beton - ihwg beton, Mass: 903.056 kg; WSP_beton - ihwg beton, Component Volume (Net): 0.392633 m3; WSP_beton - ihwg beton, Component Volume (Gross): 0.392633 m3
CPset_Phasing - Renovation Phase: Bestaand

# IfcSlab: Slab 291, 17_WSP_FD_beton - fundatiepaal v21-2:ø300 (schroef):1473478
In: -2 fundering
Classification: Vloerplaat - fundering (ARCHICAD Classification); Material: WSP_beton - ihwg beton
Component Quantities - WSP_beton - ihwg beton, Mass: 903.056 kg; WSP_beton - ihwg beton, Component Volume (Net): 0.392633 m3; WSP_beton - ihwg beton, Component Volume (Gross): 0.392633 m3
CPset_Phasing - Renovation Phase: Bestaand
Pset_ReinforcementBarPitchOfSlab - Reference: ø300 (schroef)
Pset_SlabCommon - Reference: ø300 (schroef); IsExternal: yes; LoadBearing: no

# IfcSlab: Slab 292, 17_WSP_FD_beton - fundatiepaal v21-2:ø300 (schroef):1473479
In: -2 fundering
Classification: Vloerplaat - fundering (ARCHICAD Classification); Material: WSP_beton - ihwg beton
Pset_ReinforcementBarPitchOfSlab - Reference: ø300 (schroef)
Pset_SlabCommon - Reference: ø300 (schroef); IsExternal: yes; LoadBearing: no
CPset_Phasing - Renovation Phase: Bestaand
Component Quantities - WSP_beton - ihwg beton, Mass: 903.056 kg; WSP_beton - ihwg beton, Component Volume (Net): 0.392633 m3; WSP_beton - ihwg beton, Component Volume (Gross): 0.392633 m3

# IfcSlab: Slab 293, 17_WSP_FD_beton - fundatiepaal v21-2:ø300 (schroef):1473476
In: -2 fundering
Classification: Vloerplaat - fundering (ARCHICAD Classification); Material: WSP_beton - ihwg beton
Pset_ReinforcementBarPitchOfSlab - Reference: ø300 (schroef)
Pset_SlabCommon - Reference: ø300 (schroef); IsExternal: yes; LoadBearing: no
Component Quantities - WSP_beton - ihwg beton, Mass: 903.056 kg; WSP_beton - ihwg beton, Component Volume (Net): 0.392633 m3; WSP_beton - ihwg beton, Component Volume (Gross): 0.392633 m3
CPset_Phasing - Renovation Phase: Bestaand

# IfcSlab: Slab 294, 17_WSP_FD_beton - fundatiepaal v21-2:ø300 (schroef):1473477
In: -2 fundering
Classification: Vloerplaat - fundering (ARCHICAD Classification); Material: WSP_beton - ihwg beton
Pset_SlabCommon - Reference: ø300 (schroef); IsExternal: yes; LoadBearing: no
CPset_Phasing - Renovation Phase: Bestaand
Component Quantities - WSP_beton - ihwg beton, Mass: 903.056 kg; WSP_beton - ihwg beton, Component Volume (Net): 0.392633 m3; WSP_beton - ihwg beton, Component Volume (Gross): 0.392633 m3
Pset_ReinforcementBarPitchOfSlab - Reference: ø300 (schroef)

# IfcSlab: Slab 295, 17_WSP_FD_beton - fundatiepaal v21-2:ø300 (schroef):1473482
In: -2 fundering
Classification: Vloerplaat - fundering (ARCHICAD Classification); Material: WSP_beton - ihwg beton
Component Quantities - WSP_beton - ihwg beton, Mass: 903.056 kg; WSP_beton - ihwg beton, Component Volume (Net): 0.392633 m3; WSP_beton - ihwg beton, Component Volume (Gross): 0.392633 m3
Pset_SlabCommon - Reference: ø300 (schroef); IsExternal: yes; LoadBearing: no
Pset_ReinforcementBarPitchOfSlab - Reference: ø300 (schroef)
CPset_Phasing - Renovation Phase: Bestaand

# IfcSlab: Slab 296, 17_WSP_FD_beton - fundatiepaal v21-2:ø300 (schroef):1473483
In: -2 fundering
Classification: Vloerplaat - fundering (ARCHICAD Classification); Material: WSP_beton - ihwg beton
Pset_SlabCommon - Reference: ø300 (schroef); IsExternal: yes; LoadBearing: no
Pset_ReinforcementBarPitchOfSlab - Reference: ø300 (schroef)
CPset_Phasing - Renovation Phase: Bestaand
Component Quantities - WSP_beton - ihwg beton, Mass: 903.056 kg; WSP_beton - ihwg beton, Component Volume (Net): 0.392633 m3; WSP_beton - ihwg beton, Component Volume (Gross): 0.392633 m3

# IfcSlab: Slab 297, 17_WSP_FD_beton - fundatiepaal v21-2:ø300 (schroef):1473480
In: -2 fundering
Classification: Vloerplaat - fundering (ARCHICAD Classification); Material: WSP_beton - ihwg beton
Pset_SlabCommon - Reference: ø300 (schroef); IsExternal: yes; LoadBearing: no
CPset_Phasing - Renovation Phase: Bestaand
Component Quantities - WSP_beton - ihwg beton, Mass: 903.056 kg; WSP_beton - ihwg beton, Component Volume (Net): 0.392633 m3; WSP_beton - ihwg beton, Component Volume (Gross): 0.392633 m3
Pset_ReinforcementBarPitchOfSlab - Reference: ø300 (schroef)

# IfcSlab: Slab 298, 17_WSP_FD_beton - fundatiepaal v21-2:ø300 (schroef):1473481
In: -2 fundering
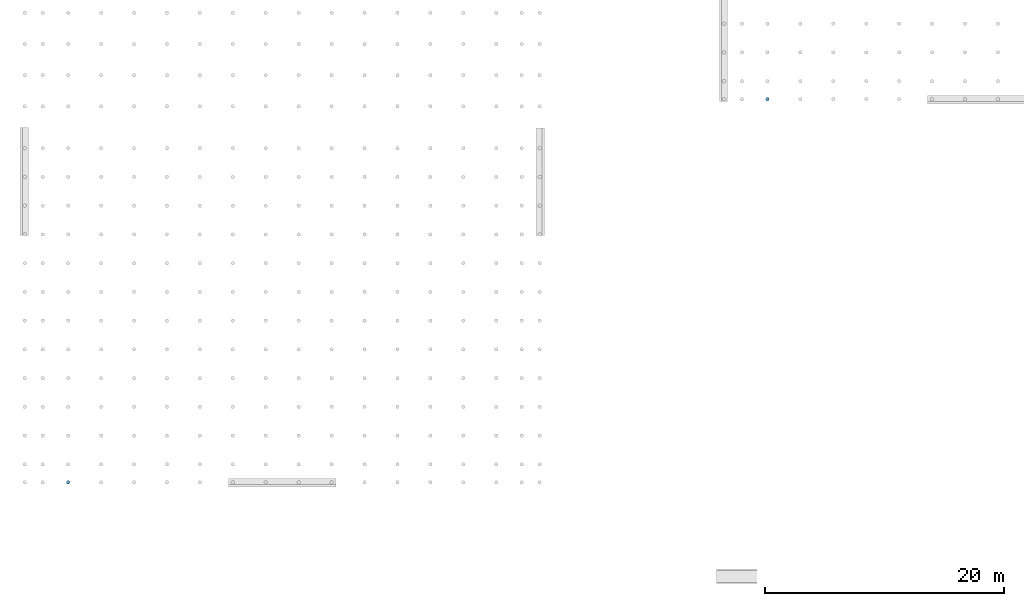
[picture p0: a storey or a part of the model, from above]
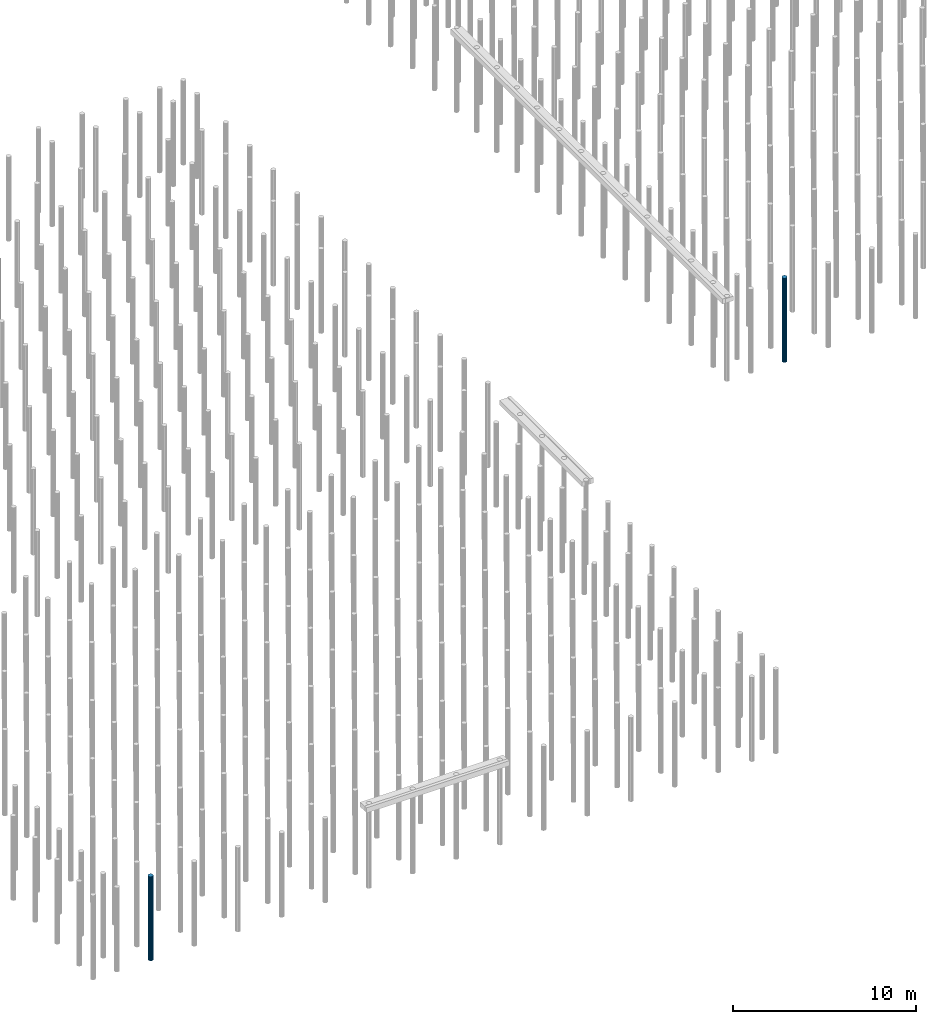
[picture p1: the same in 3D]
Properties of the parts of a building model (IFC2X3), part 5 of 13

# IfcSlab: Slab 298, 17_WSP_FD_beton - fundatiepaal v21-2:ø300 (schroef):1473481
Classification: Vloerplaat - fundering (ARCHICAD Classification); Material: WSP_beton - ihwg beton
Pset_SlabCommon - Reference: ø300 (schroef); IsExternal: yes; LoadBearing: no
CPset_Phasing - Renovation Phase: Bestaand
Pset_ReinforcementBarPitchOfSlab - Reference: ø300 (schroef)
Component Quantities - WSP_beton - ihwg beton, Mass: 903.056 kg; WSP_beton - ihwg beton, Component Volume (Net): 0.392633 m3; WSP_beton - ihwg beton, Component Volume (Gross): 0.392633 m3

# IfcSlab: Slab 299, 17_WSP_FD_beton - fundatiepaal v21-2:ø300 (schroef):1473486
In: -2 fundering
Classification: Vloerplaat - fundering (ARCHICAD Classification); Material: WSP_beton - ihwg beton
Pset_ReinforcementBarPitchOfSlab - Reference: ø300 (schroef)
Pset_SlabCommon - Reference: ø300 (schroef); IsExternal: yes; LoadBearing: no
Component Quantities - WSP_beton - ihwg beton, Mass: 903.056 kg; WSP_beton - ihwg beton, Component Volume (Net): 0.392633 m3; WSP_beton - ihwg beton, Component Volume (Gross): 0.392633 m3
CPset_Phasing - Renovation Phase: Bestaand

# IfcSlab: Slab 3, 17_WSP_FD_beton - fundatiepaal v21-2:ø300 (schroef):1528045
In: -2 fundering
Classification: Vloerplaat - fundering (ARCHICAD Classification); Material: WSP_beton - ihwg beton
Component Quantities - WSP_beton - ihwg beton, Mass: 887.213 kg; WSP_beton - ihwg beton, Component Volume (Net): 0.385745 m3; WSP_beton - ihwg beton, Component Volume (Gross): 0.385745 m3
CPset_Phasing - Renovation Phase: Bestaand
Pset_ReinforcementBarPitchOfSlab - Reference: ø300 (schroef)
Pset_SlabCommon - Reference: ø300 (schroef); IsExternal: yes; LoadBearing: no

# IfcSlab: Slab 30, 17_WSP_FD_beton - fundatiepaal v21-2:ø300 (schroef):1528489
In: -2 fundering
Classification: Vloerplaat - fundering (ARCHICAD Classification); Material: WSP_beton - ihwg beton
Pset_SlabCommon - Reference: ø300 (schroef); IsExternal: yes; LoadBearing: no
Pset_ReinforcementBarPitchOfSlab - Reference: ø300 (schroef)
CPset_Phasing - Renovation Phase: Bestaand
Component Quantities - WSP_beton - ihwg beton, Mass: 903.056 kg; WSP_beton - ihwg beton, Component Volume (Net): 0.392633 m3; WSP_beton - ihwg beton, Component Volume (Gross): 0.392633 m3

# IfcSlab: Slab 300, 17_WSP_FD_beton - fundatiepaal v21-2:ø300 (schroef):1473487
In: -2 fundering
Classification: Vloerplaat - fundering (ARCHICAD Classification); Material: WSP_beton - ihwg beton
Pset_SlabCommon - Reference: ø300 (schroef); IsExternal: yes; LoadBearing: no
Pset_ReinforcementBarPitchOfSlab - Reference: ø300 (schroef)
CPset_Phasing - Renovation Phase: Bestaand
Component Quantities - WSP_beton - ihwg beton, Mass: 903.056 kg; WSP_beton - ihwg beton, Component Volume (Net): 0.392633 m3; WSP_beton - ihwg beton, Component Volume (Gross): 0.392633 m3

# IfcSlab: Slab 301, 17_WSP_FD_beton - fundatiepaal v21-2:ø300 (schroef):1473484
In: -2 fundering
Classification: Vloerplaat - fundering (ARCHICAD Classification); Material: WSP_beton - ihwg beton
Pset_ReinforcementBarPitchOfSlab - Reference: ø300 (schroef)
Pset_SlabCommon - Reference: ø300 (schroef); IsExternal: yes; LoadBearing: no
CPset_Phasing - Renovation Phase: Bestaand
Component Quantities - WSP_beton - ihwg beton, Mass: 903.056 kg; WSP_beton - ihwg beton, Component Volume (Net): 0.392633 m3; WSP_beton - ihwg beton, Component Volume (Gross): 0.392633 m3

# IfcSlab: Slab 302, 17_WSP_FD_beton - fundatiepaal v21-2:ø300 (schroef):1473485
In: -2 fundering
Classification: Vloerplaat - fundering (ARCHICAD Classification); Material: WSP_beton - ihwg beton
Pset_SlabCommon - Reference: ø300 (schroef); IsExternal: yes; LoadBearing: no
Pset_ReinforcementBarPitchOfSlab - Reference: ø300 (schroef)
CPset_Phasing - Renovation Phase: Bestaand
Component Quantities - WSP_beton - ihwg beton, Mass: 903.056 kg; WSP_beton - ihwg beton, Component Volume (Net): 0.392633 m3; WSP_beton - ihwg beton, Component Volume (Gross): 0.392633 m3

# IfcSlab: Slab 303, 17_WSP_FD_beton - fundatiepaal v21-2:ø300 (schroef):1473490
In: -2 fundering
Classification: Vloerplaat - fundering (ARCHICAD Classification); Material: WSP_beton - ihwg beton
Pset_ReinforcementBarPitchOfSlab - Reference: ø300 (schroef)
Pset_SlabCommon - Reference: ø300 (schroef); IsExternal: yes; LoadBearing: no
Component Quantities - WSP_beton - ihwg beton, Mass: 903.056 kg; WSP_beton - ihwg beton, Component Volume (Net): 0.392633 m3; WSP_beton - ihwg beton, Component Volume (Gross): 0.392633 m3
CPset_Phasing - Renovation Phase: Bestaand

# IfcSlab: Slab 304, 17_WSP_FD_beton - fundatiepaal v21-2:ø300 (schroef):1473491
In: -2 fundering
Classification: Vloerplaat - fundering (ARCHICAD Classification); Material: WSP_beton - ihwg beton
Pset_SlabCommon - Reference: ø300 (schroef); IsExternal: yes; LoadBearing: no
Pset_ReinforcementBarPitchOfSlab - Reference: ø300 (schroef)
Component Quantities - WSP_beton - ihwg beton, Mass: 903.056 kg; WSP_beton - ihwg beton, Component Volume (Net): 0.392633 m3; WSP_beton - ihwg beton, Component Volume (Gross): 0.392633 m3
CPset_Phasing - Renovation Phase: Bestaand

# IfcSlab: Slab 305, 17_WSP_FD_beton - fundatiepaal v21-2:ø300 (schroef):1473488
In: -2 fundering
Classification: Vloerplaat - fundering (ARCHICAD Classification); Material: WSP_beton - ihwg beton
Pset_SlabCommon - Reference: ø300 (schroef); IsExternal: yes; LoadBearing: no
Component Quantities - WSP_beton - ihwg beton, Mass: 903.056 kg; WSP_beton - ihwg beton, Component Volume (Net): 0.392633 m3; WSP_beton - ihwg beton, Component Volume (Gross): 0.392633 m3
Pset_ReinforcementBarPitchOfSlab - Reference: ø300 (schroef)
CPset_Phasing - Renovation Phase: Bestaand

# IfcSlab: Slab 306, 17_WSP_FD_beton - fundatiepaal v21-2:ø300 (schroef):1473489
In: -2 fundering
Classification: Vloerplaat - fundering (ARCHICAD Classification); Material: WSP_beton - ihwg beton
Pset_SlabCommon - Reference: ø300 (schroef); IsExternal: yes; LoadBearing: no
Pset_ReinforcementBarPitchOfSlab - Reference: ø300 (schroef)
Component Quantities - WSP_beton - ihwg beton, Mass: 903.056 kg; WSP_beton - ihwg beton, Component Volume (Net): 0.392633 m3; WSP_beton - ihwg beton, Component Volume (Gross): 0.392633 m3
CPset_Phasing - Renovation Phase: Bestaand

# IfcSlab: Slab 307, 17_WSP_FD_beton - fundatiepaal v21-2:ø300 (schroef):1473494
In: -2 fundering
Classification: Vloerplaat - fundering (ARCHICAD Classification); Material: WSP_beton - ihwg beton
Pset_ReinforcementBarPitchOfSlab - Reference: ø300 (schroef)
Pset_SlabCommon - Reference: ø300 (schroef); IsExternal: yes; LoadBearing: no
CPset_Phasing - Renovation Phase: Bestaand
Component Quantities - WSP_beton - ihwg beton, Mass: 903.056 kg; WSP_beton - ihwg beton, Component Volume (Net): 0.392633 m3; WSP_beton - ihwg beton, Component Volume (Gross): 0.392633 m3

# IfcSlab: Slab 308, 17_WSP_FD_beton - fundatiepaal v21-2:ø300 (schroef):1473495
In: -2 fundering
Classification: Vloerplaat - fundering (ARCHICAD Classification); Material: WSP_beton - ihwg beton
CPset_Phasing - Renovation Phase: Bestaand
Pset_SlabCommon - Reference: ø300 (schroef); IsExternal: yes; LoadBearing: no
Component Quantities - WSP_beton - ihwg beton, Mass: 903.056 kg; WSP_beton - ihwg beton, Component Volume (Net): 0.392633 m3; WSP_beton - ihwg beton, Component Volume (Gross): 0.392633 m3
Pset_ReinforcementBarPitchOfSlab - Reference: ø300 (schroef)

# IfcSlab: Slab 309, 17_WSP_FD_beton - fundatiepaal v21-2:ø300 (schroef):1473492
In: -2 fundering
Classification: Vloerplaat - fundering (ARCHICAD Classification); Material: WSP_beton - ihwg beton
Pset_SlabCommon - Reference: ø300 (schroef); IsExternal: yes; LoadBearing: no
Pset_ReinforcementBarPitchOfSlab - Reference: ø300 (schroef)
CPset_Phasing - Renovation Phase: Bestaand
Component Quantities - WSP_beton - ihwg beton, Mass: 903.056 kg; WSP_beton - ihwg beton, Component Volume (Net): 0.392633 m3; WSP_beton - ihwg beton, Component Volume (Gross): 0.392633 m3

# IfcSlab: Slab 31, 17_WSP_FD_beton - fundatiepaal v21-2:ø300 (schroef):1528488
In: -2 fundering
Classification: Vloerplaat - fundering (ARCHICAD Classification); Material: WSP_beton - ihwg beton
Pset_ReinforcementBarPitchOfSlab - Reference: ø300 (schroef)
Pset_SlabCommon - Reference: ø300 (schroef); IsExternal: yes; LoadBearing: no
CPset_Phasing - Renovation Phase: Bestaand
Component Quantities - WSP_beton - ihwg beton, Mass: 903.056 kg; WSP_beton - ihwg beton, Component Volume (Net): 0.392633 m3; WSP_beton - ihwg beton, Component Volume (Gross): 0.392633 m3

# IfcSlab: Slab 310, 17_WSP_FD_beton - fundatiepaal v21-2:ø300 (schroef):1473493
In: -2 fundering
Classification: Vloerplaat - fundering (ARCHICAD Classification); Material: WSP_beton - ihwg beton
Pset_ReinforcementBarPitchOfSlab - Reference: ø300 (schroef)
Pset_SlabCommon - Reference: ø300 (schroef); IsExternal: yes; LoadBearing: no
CPset_Phasing - Renovation Phase: Bestaand
Component Quantities - WSP_beton - ihwg beton, Mass: 903.056 kg; WSP_beton - ihwg beton, Component Volume (Net): 0.392633 m3; WSP_beton - ihwg beton, Component Volume (Gross): 0.392633 m3

# IfcSlab: Slab 311, 17_WSP_FD_beton - fundatiepaal v21-2:ø300 (schroef):1473498
In: -2 fundering
Classification: Vloerplaat - fundering (ARCHICAD Classification); Material: WSP_beton - ihwg beton
Pset_SlabCommon - Reference: ø300 (schroef); IsExternal: yes; LoadBearing: no
CPset_Phasing - Renovation Phase: Bestaand
Component Quantities - WSP_beton - ihwg beton, Mass: 903.056 kg; WSP_beton - ihwg beton, Component Volume (Net): 0.392633 m3; WSP_beton - ihwg beton, Component Volume (Gross): 0.392633 m3
Pset_ReinforcementBarPitchOfSlab - Reference: ø300 (schroef)

# IfcSlab: Slab 312, 17_WSP_FD_beton - fundatiepaal v21-2:ø300 (schroef):1473499
In: -2 fundering
Classification: Vloerplaat - fundering (ARCHICAD Classification); Material: WSP_beton - ihwg beton
Pset_SlabCommon - Reference: ø300 (schroef); IsExternal: yes; LoadBearing: no
Pset_ReinforcementBarPitchOfSlab - Reference: ø300 (schroef)
CPset_Phasing - Renovation Phase: Bestaand
Component Quantities - WSP_beton - ihwg beton, Mass: 903.056 kg; WSP_beton - ihwg beton, Component Volume (Net): 0.392633 m3; WSP_beton - ihwg beton, Component Volume (Gross): 0.392633 m3

# IfcSlab: Slab 313, 17_WSP_FD_beton - fundatiepaal v21-2:ø300 (schroef):1473496
In: -2 fundering
Classification: Vloerplaat - fundering (ARCHICAD Classification); Material: WSP_beton - ihwg beton
Pset_ReinforcementBarPitchOfSlab - Reference: ø300 (schroef)
Pset_SlabCommon - Reference: ø300 (schroef); IsExternal: yes; LoadBearing: no
Component Quantities - WSP_beton - ihwg beton, Mass: 903.056 kg; WSP_beton - ihwg beton, Component Volume (Net): 0.392633 m3; WSP_beton - ihwg beton, Component Volume (Gross): 0.392633 m3
CPset_Phasing - Renovation Phase: Bestaand

# IfcSlab: Slab 314, 17_WSP_FD_beton - fundatiepaal v21-2:ø300 (schroef):1473497
In: -2 fundering
Classification: Vloerplaat - fundering (ARCHICAD Classification); Material: WSP_beton - ihwg beton
Pset_SlabCommon - Reference: ø300 (schroef); IsExternal: yes; LoadBearing: no
Pset_ReinforcementBarPitchOfSlab - Reference: ø300 (schroef)
CPset_Phasing - Renovation Phase: Bestaand
Component Quantities - WSP_beton - ihwg beton, Mass: 903.056 kg; WSP_beton - ihwg beton, Component Volume (Net): 0.392633 m3; WSP_beton - ihwg beton, Component Volume (Gross): 0.392633 m3

# IfcSlab: Slab 315, 17_WSP_FD_beton - fundatiepaal v21-2:ø300 (schroef):1473502
In: -2 fundering
Classification: Vloerplaat - fundering (ARCHICAD Classification); Material: WSP_beton - ihwg beton
CPset_Phasing - Renovation Phase: Bestaand
Pset_ReinforcementBarPitchOfSlab - Reference: ø300 (schroef)
Pset_SlabCommon - Reference: ø300 (schroef); IsExternal: yes; LoadBearing: no
Component Quantities - WSP_beton - ihwg beton, Mass: 903.056 kg; WSP_beton - ihwg beton, Component Volume (Net): 0.392633 m3; WSP_beton - ihwg beton, Component Volume (Gross): 0.392633 m3

# IfcSlab: Slab 316, 17_WSP_FD_beton - fundatiepaal v21-2:ø300 (schroef):1473503
In: -2 fundering
Classification: Vloerplaat - fundering (ARCHICAD Classification); Material: WSP_beton - ihwg beton
CPset_Phasing - Renovation Phase: Bestaand
Pset_SlabCommon - Reference: ø300 (schroef); IsExternal: yes; LoadBearing: no
Pset_ReinforcementBarPitchOfSlab - Reference: ø300 (schroef)
Component Quantities - WSP_beton - ihwg beton, Mass: 903.056 kg; WSP_beton - ihwg beton, Component Volume (Net): 0.392633 m3; WSP_beton - ihwg beton, Component Volume (Gross): 0.392633 m3

# IfcSlab: Slab 317, 17_WSP_FD_beton - fundatiepaal v21-2:ø300 (schroef):1473500
In: -2 fundering
Classification: Vloerplaat - fundering (ARCHICAD Classification); Material: WSP_beton - ihwg beton
Pset_SlabCommon - Reference: ø300 (schroef); IsExternal: yes; LoadBearing: no
Pset_ReinforcementBarPitchOfSlab - Reference: ø300 (schroef)
Component Quantities - WSP_beton - ihwg beton, Mass: 903.056 kg; WSP_beton - ihwg beton, Component Volume (Net): 0.392633 m3; WSP_beton - ihwg beton, Component Volume (Gross): 0.392633 m3
CPset_Phasing - Renovation Phase: Bestaand

# IfcSlab: Slab 318, 17_WSP_FD_beton - fundatiepaal v21-2:ø300 (schroef):1473501
In: -2 fundering
Classification: Vloerplaat - fundering (ARCHICAD Classification); Material: WSP_beton - ihwg beton
Pset_SlabCommon - Reference: ø300 (schroef); IsExternal: yes; LoadBearing: no
Component Quantities - WSP_beton - ihwg beton, Mass: 903.056 kg; WSP_beton - ihwg beton, Component Volume (Net): 0.392633 m3; WSP_beton - ihwg beton, Component Volume (Gross): 0.392633 m3
CPset_Phasing - Renovation Phase: Bestaand
Pset_ReinforcementBarPitchOfSlab - Reference: ø300 (schroef)

# IfcSlab: Slab 319, 17_WSP_FD_beton - fundatiepaal v21-2:ø300 (schroef):1473442
In: -2 fundering
Classification: Vloerplaat - fundering (ARCHICAD Classification); Material: WSP_beton - ihwg beton
Pset_SlabCommon - Reference: ø300 (schroef); IsExternal: yes; LoadBearing: no
Pset_ReinforcementBarPitchOfSlab - Reference: ø300 (schroef)
CPset_Phasing - Renovation Phase: Bestaand
Component Quantities - WSP_beton - ihwg beton, Mass: 887.213 kg; WSP_beton - ihwg beton, Component Volume (Net): 0.385745 m3; WSP_beton - ihwg beton, Component Volume (Gross): 0.385745 m3

# IfcSlab: Slab 32, 17_WSP_FD_beton - fundatiepaal v21-2:ø300 (schroef):1528491
In: -2 fundering
Classification: Vloerplaat - fundering (ARCHICAD Classification); Material: WSP_beton - ihwg beton
Pset_SlabCommon - Reference: ø300 (schroef); IsExternal: yes; LoadBearing: no
CPset_Phasing - Renovation Phase: Bestaand
Component Quantities - WSP_beton - ihwg beton, Mass: 903.056 kg; WSP_beton - ihwg beton, Component Volume (Net): 0.392633 m3; WSP_beton - ihwg beton, Component Volume (Gross): 0.392633 m3
Pset_ReinforcementBarPitchOfSlab - Reference: ø300 (schroef)

# IfcSlab: Slab 320, 17_WSP_FD_beton - fundatiepaal v21-2:ø300 (schroef):1473443
In: -2 fundering
Classification: Vloerplaat - fundering (ARCHICAD Classification); Material: WSP_beton - ihwg beton
Pset_SlabCommon - Reference: ø300 (schroef); IsExternal: yes; LoadBearing: no
Pset_ReinforcementBarPitchOfSlab - Reference: ø300 (schroef)
Component Quantities - WSP_beton - ihwg beton, Mass: 887.213 kg; WSP_beton - ihwg beton, Component Volume (Net): 0.385745 m3; WSP_beton - ihwg beton, Component Volume (Gross): 0.385745 m3
CPset_Phasing - Renovation Phase: Bestaand

# IfcSlab: Slab 321, 17_WSP_FD_beton - fundatiepaal v21-2:ø300 (schroef):1473440
In: -2 fundering
Classification: Vloerplaat - fundering (ARCHICAD Classification); Material: WSP_beton - ihwg beton
Pset_ReinforcementBarPitchOfSlab - Reference: ø300 (schroef)
Pset_SlabCommon - Reference: ø300 (schroef); IsExternal: yes; LoadBearing: no
CPset_Phasing - Renovation Phase: Bestaand
Component Quantities - WSP_beton - ihwg beton, Mass: 887.213 kg; WSP_beton - ihwg beton, Component Volume (Net): 0.385745 m3; WSP_beton - ihwg beton, Component Volume (Gross): 0.385745 m3

# IfcSlab: Slab 322, 17_WSP_FD_beton - fundatiepaal v21-2:ø300 (schroef):1473441
In: -2 fundering
Classification: Vloerplaat - fundering (ARCHICAD Classification); Material: WSP_beton - ihwg beton
CPset_Phasing - Renovation Phase: Bestaand
Pset_SlabCommon - Reference: ø300 (schroef); IsExternal: yes; LoadBearing: no
Pset_ReinforcementBarPitchOfSlab - Reference: ø300 (schroef)
Component Quantities - WSP_beton - ihwg beton, Mass: 887.213 kg; WSP_beton - ihwg beton, Component Volume (Net): 0.385745 m3; WSP_beton - ihwg beton, Component Volume (Gross): 0.385745 m3

# IfcSlab: Slab 323, 17_WSP_FD_beton - fundatiepaal v21-2:ø300 (schroef):1473446
In: -2 fundering
Classification: Vloerplaat - fundering (ARCHICAD Classification); Material: WSP_beton - ihwg beton
CPset_Phasing - Renovation Phase: Bestaand
Pset_ReinforcementBarPitchOfSlab - Reference: ø300 (schroef)
Pset_SlabCommon - Reference: ø300 (schroef); IsExternal: yes; LoadBearing: no
Component Quantities - WSP_beton - ihwg beton, Mass: 887.213 kg; WSP_beton - ihwg beton, Component Volume (Net): 0.385745 m3; WSP_beton - ihwg beton, Component Volume (Gross): 0.385745 m3

# IfcSlab: Slab 324, 17_WSP_FD_beton - fundatiepaal v21-2:ø300 (schroef):1473447
In: -2 fundering
Classification: Vloerplaat - fundering (ARCHICAD Classification); Material: WSP_beton - ihwg beton
Pset_SlabCommon - Reference: ø300 (schroef); IsExternal: yes; LoadBearing: no
Pset_ReinforcementBarPitchOfSlab - Reference: ø300 (schroef)
CPset_Phasing - Renovation Phase: Bestaand
Component Quantities - WSP_beton - ihwg beton, Mass: 887.213 kg; WSP_beton - ihwg beton, Component Volume (Net): 0.385745 m3; WSP_beton - ihwg beton, Component Volume (Gross): 0.385745 m3

# IfcSlab: Slab 325, 17_WSP_FD_beton - fundatiepaal v21-2:ø300 (schroef):1473444
In: -2 fundering
Classification: Vloerplaat - fundering (ARCHICAD Classification); Material: WSP_beton - ihwg beton
Pset_ReinforcementBarPitchOfSlab - Reference: ø300 (schroef)
Pset_SlabCommon - Reference: ø300 (schroef); IsExternal: yes; LoadBearing: no
Component Quantities - WSP_beton - ihwg beton, Mass: 887.213 kg; WSP_beton - ihwg beton, Component Volume (Net): 0.385745 m3; WSP_beton - ihwg beton, Component Volume (Gross): 0.385745 m3
CPset_Phasing - Renovation Phase: Bestaand

# IfcSlab: Slab 326, 17_WSP_FD_beton - fundatiepaal v21-2:ø300 (schroef):1473445
In: -2 fundering
Classification: Vloerplaat - fundering (ARCHICAD Classification); Material: WSP_beton - ihwg beton
CPset_Phasing - Renovation Phase: Bestaand
Component Quantities - WSP_beton - ihwg beton, Mass: 887.213 kg; WSP_beton - ihwg beton, Component Volume (Net): 0.385745 m3; WSP_beton - ihwg beton, Component Volume (Gross): 0.385745 m3
Pset_ReinforcementBarPitchOfSlab - Reference: ø300 (schroef)
Pset_SlabCommon - Reference: ø300 (schroef); IsExternal: yes; LoadBearing: no

# IfcSlab: Slab 327, 17_WSP_FD_beton - fundatiepaal v21-2:ø300 (schroef):1473450
In: -2 fundering
Classification: Vloerplaat - fundering (ARCHICAD Classification); Material: WSP_beton - ihwg beton
CPset_Phasing - Renovation Phase: Bestaand
Pset_SlabCommon - Reference: ø300 (schroef); IsExternal: yes; LoadBearing: no
Pset_ReinforcementBarPitchOfSlab - Reference: ø300 (schroef)
Component Quantities - WSP_beton - ihwg beton, Mass: 887.213 kg; WSP_beton - ihwg beton, Component Volume (Net): 0.385745 m3; WSP_beton - ihwg beton, Component Volume (Gross): 0.385745 m3

# IfcSlab: Slab 328, 17_WSP_FD_beton - fundatiepaal v21-2:ø300 (schroef):1473451
In: -2 fundering
Classification: Vloerplaat - fundering (ARCHICAD Classification); Material: WSP_beton - ihwg beton
Component Quantities - WSP_beton - ihwg beton, Mass: 887.213 kg; WSP_beton - ihwg beton, Component Volume (Net): 0.385745 m3; WSP_beton - ihwg beton, Component Volume (Gross): 0.385745 m3
Pset_SlabCommon - Reference: ø300 (schroef); IsExternal: yes; LoadBearing: no
Pset_ReinforcementBarPitchOfSlab - Reference: ø300 (schroef)
CPset_Phasing - Renovation Phase: Bestaand

# IfcSlab: Slab 329, 17_WSP_FD_beton - fundatiepaal v21-2:ø300 (schroef):1473448
In: -2 fundering
Classification: Vloerplaat - fundering (ARCHICAD Classification); Material: WSP_beton - ihwg beton
Pset_SlabCommon - Reference: ø300 (schroef); IsExternal: yes; LoadBearing: no
Pset_ReinforcementBarPitchOfSlab - Reference: ø300 (schroef)
Component Quantities - WSP_beton - ihwg beton, Mass: 887.213 kg; WSP_beton - ihwg beton, Component Volume (Net): 0.385745 m3; WSP_beton - ihwg beton, Component Volume (Gross): 0.385745 m3
CPset_Phasing - Renovation Phase: Bestaand

# IfcSlab: Slab 33, 17_WSP_FD_beton - fundatiepaal v21-2:ø300 (schroef):1528490
In: -2 fundering
Classification: Vloerplaat - fundering (ARCHICAD Classification); Material: WSP_beton - ihwg beton
Pset_ReinforcementBarPitchOfSlab - Reference: ø300 (schroef)
Component Quantities - WSP_beton - ihwg beton, Mass: 903.056 kg; WSP_beton - ihwg beton, Component Volume (Net): 0.392633 m3; WSP_beton - ihwg beton, Component Volume (Gross): 0.392633 m3
CPset_Phasing - Renovation Phase: Bestaand
Pset_SlabCommon - Reference: ø300 (schroef); IsExternal: yes; LoadBearing: no

# IfcSlab: Slab 330, 17_WSP_FD_beton - fundatiepaal v21-2:ø300 (schroef):1473449
In: -2 fundering
Classification: Vloerplaat - fundering (ARCHICAD Classification); Material: WSP_beton - ihwg beton
Component Quantities - WSP_beton - ihwg beton, Mass: 887.213 kg; WSP_beton - ihwg beton, Component Volume (Net): 0.385745 m3; WSP_beton - ihwg beton, Component Volume (Gross): 0.385745 m3
Pset_SlabCommon - Reference: ø300 (schroef); IsExternal: yes; LoadBearing: no
Pset_ReinforcementBarPitchOfSlab - Reference: ø300 (schroef)
CPset_Phasing - Renovation Phase: Bestaand

# IfcSlab: Slab 331, 17_WSP_FD_beton - fundatiepaal v21-2:ø300 (schroef):1473454
In: -2 fundering
Classification: Vloerplaat - fundering (ARCHICAD Classification); Material: WSP_beton - ihwg beton
CPset_Phasing - Renovation Phase: Bestaand
Pset_ReinforcementBarPitchOfSlab - Reference: ø300 (schroef)
Component Quantities - WSP_beton - ihwg beton, Mass: 887.213 kg; WSP_beton - ihwg beton, Component Volume (Net): 0.385745 m3; WSP_beton - ihwg beton, Component Volume (Gross): 0.385745 m3
Pset_SlabCommon - Reference: ø300 (schroef); IsExternal: yes; LoadBearing: no

# IfcSlab: Slab 332, 17_WSP_FD_beton - fundatiepaal v21-2:ø300 (schroef):1473455
In: -2 fundering
Classification: Vloerplaat - fundering (ARCHICAD Classification); Material: WSP_beton - ihwg beton
Pset_SlabCommon - Reference: ø300 (schroef); IsExternal: yes; LoadBearing: no
Pset_ReinforcementBarPitchOfSlab - Reference: ø300 (schroef)
Component Quantities - WSP_beton - ihwg beton, Mass: 887.213 kg; WSP_beton - ihwg beton, Component Volume (Net): 0.385745 m3; WSP_beton - ihwg beton, Component Volume (Gross): 0.385745 m3
CPset_Phasing - Renovation Phase: Bestaand

# IfcSlab: Slab 333, 17_WSP_FD_beton - fundatiepaal v21-2:ø300 (schroef):1473452
In: -2 fundering
Classification: Vloerplaat - fundering (ARCHICAD Classification); Material: WSP_beton - ihwg beton
Pset_ReinforcementBarPitchOfSlab - Reference: ø300 (schroef)
Pset_SlabCommon - Reference: ø300 (schroef); IsExternal: yes; LoadBearing: no
Component Quantities - WSP_beton - ihwg beton, Mass: 887.213 kg; WSP_beton - ihwg beton, Component Volume (Net): 0.385745 m3; WSP_beton - ihwg beton, Component Volume (Gross): 0.385745 m3
CPset_Phasing - Renovation Phase: Bestaand

# IfcSlab: Slab 334, 17_WSP_FD_beton - fundatiepaal v21-2:ø300 (schroef):1473453
In: -2 fundering
Classification: Vloerplaat - fundering (ARCHICAD Classification); Material: WSP_beton - ihwg beton
Pset_SlabCommon - Reference: ø300 (schroef); IsExternal: yes; LoadBearing: no
CPset_Phasing - Renovation Phase: Bestaand
Component Quantities - WSP_beton - ihwg beton, Mass: 887.213 kg; WSP_beton - ihwg beton, Component Volume (Net): 0.385745 m3; WSP_beton - ihwg beton, Component Volume (Gross): 0.385745 m3
Pset_ReinforcementBarPitchOfSlab - Reference: ø300 (schroef)

# IfcSlab: Slab 335, 17_WSP_FD_beton - fundatiepaal v21-2:ø300 (schroef):1473458
In: -2 fundering
Classification: Vloerplaat - fundering (ARCHICAD Classification); Material: WSP_beton - ihwg beton
Pset_SlabCommon - Reference: ø300 (schroef); IsExternal: yes; LoadBearing: no
Pset_ReinforcementBarPitchOfSlab - Reference: ø300 (schroef)
CPset_Phasing - Renovation Phase: Bestaand
Component Quantities - WSP_beton - ihwg beton, Mass: 903.056 kg; WSP_beton - ihwg beton, Component Volume (Net): 0.392633 m3; WSP_beton - ihwg beton, Component Volume (Gross): 0.392633 m3

# IfcSlab: Slab 336, 17_WSP_FD_beton - fundatiepaal v21-2:ø300 (schroef):1473459
In: -2 fundering
Classification: Vloerplaat - fundering (ARCHICAD Classification); Material: WSP_beton - ihwg beton
Pset_SlabCommon - Reference: ø300 (schroef); IsExternal: yes; LoadBearing: no
Pset_ReinforcementBarPitchOfSlab - Reference: ø300 (schroef)
CPset_Phasing - Renovation Phase: Bestaand
Component Quantities - WSP_beton - ihwg beton, Mass: 903.056 kg; WSP_beton - ihwg beton, Component Volume (Net): 0.392633 m3; WSP_beton - ihwg beton, Component Volume (Gross): 0.392633 m3

# IfcSlab: Slab 337, 17_WSP_FD_beton - fundatiepaal v21-2:ø300 (schroef):1473456
In: -2 fundering
Classification: Vloerplaat - fundering (ARCHICAD Classification); Material: WSP_beton - ihwg beton
Pset_ReinforcementBarPitchOfSlab - Reference: ø300 (schroef)
Pset_SlabCommon - Reference: ø300 (schroef); IsExternal: yes; LoadBearing: no
Component Quantities - WSP_beton - ihwg beton, Mass: 887.213 kg; WSP_beton - ihwg beton, Component Volume (Net): 0.385745 m3; WSP_beton - ihwg beton, Component Volume (Gross): 0.385745 m3
CPset_Phasing - Renovation Phase: Bestaand

# IfcSlab: Slab 338, 17_WSP_FD_beton - fundatiepaal v21-2:ø300 (schroef):1473457
In: -2 fundering
Classification: Vloerplaat - fundering (ARCHICAD Classification); Material: WSP_beton - ihwg beton
Pset_SlabCommon - Reference: ø300 (schroef); IsExternal: yes; LoadBearing: no
CPset_Phasing - Renovation Phase: Bestaand
Pset_ReinforcementBarPitchOfSlab - Reference: ø300 (schroef)
Component Quantities - WSP_beton - ihwg beton, Mass: 887.213 kg; WSP_beton - ihwg beton, Component Volume (Net): 0.385745 m3; WSP_beton - ihwg beton, Component Volume (Gross): 0.385745 m3

# IfcSlab: Slab 339, 17_WSP_FD_beton - fundatiepaal v21-2:ø300 (schroef):1473462
In: -2 fundering
Classification: Vloerplaat - fundering (ARCHICAD Classification); Material: WSP_beton - ihwg beton
Pset_SlabCommon - Reference: ø300 (schroef); IsExternal: yes; LoadBearing: no
Pset_ReinforcementBarPitchOfSlab - Reference: ø300 (schroef)
CPset_Phasing - Renovation Phase: Bestaand
Component Quantities - WSP_beton - ihwg beton, Mass: 903.056 kg; WSP_beton - ihwg beton, Component Volume (Net): 0.392633 m3; WSP_beton - ihwg beton, Component Volume (Gross): 0.392633 m3

# IfcSlab: Slab 34, 17_WSP_FD_beton - fundatiepaal v21-2:ø300 (schroef):1528477
In: -2 fundering
Classification: Vloerplaat - fundering (ARCHICAD Classification); Material: WSP_beton - ihwg beton
Pset_SlabCommon - Reference: ø300 (schroef); IsExternal: yes; LoadBearing: no
Pset_ReinforcementBarPitchOfSlab - Reference: ø300 (schroef)
CPset_Phasing - Renovation Phase: Bestaand
Component Quantities - WSP_beton - ihwg beton, Mass: 887.213 kg; WSP_beton - ihwg beton, Component Volume (Net): 0.385745 m3; WSP_beton - ihwg beton, Component Volume (Gross): 0.385745 m3

# IfcSlab: Slab 340, 17_WSP_FD_beton - fundatiepaal v21-2:ø300 (schroef):1473463
In: -2 fundering
Classification: Vloerplaat - fundering (ARCHICAD Classification); Material: WSP_beton - ihwg beton
Pset_ReinforcementBarPitchOfSlab - Reference: ø300 (schroef)
Pset_SlabCommon - Reference: ø300 (schroef); IsExternal: yes; LoadBearing: no
CPset_Phasing - Renovation Phase: Bestaand
Component Quantities - WSP_beton - ihwg beton, Mass: 903.056 kg; WSP_beton - ihwg beton, Component Volume (Net): 0.392633 m3; WSP_beton - ihwg beton, Component Volume (Gross): 0.392633 m3

# IfcSlab: Slab 341, 17_WSP_FD_beton - fundatiepaal v21-2:ø300 (schroef):1473460
In: -2 fundering
Classification: Vloerplaat - fundering (ARCHICAD Classification); Material: WSP_beton - ihwg beton
Pset_ReinforcementBarPitchOfSlab - Reference: ø300 (schroef)
Pset_SlabCommon - Reference: ø300 (schroef); IsExternal: yes; LoadBearing: no
CPset_Phasing - Renovation Phase: Bestaand
Component Quantities - WSP_beton - ihwg beton, Mass: 903.056 kg; WSP_beton - ihwg beton, Component Volume (Net): 0.392633 m3; WSP_beton - ihwg beton, Component Volume (Gross): 0.392633 m3

# IfcSlab: Slab 342, 17_WSP_FD_beton - fundatiepaal v21-2:ø300 (schroef):1473461
In: -2 fundering
Classification: Vloerplaat - fundering (ARCHICAD Classification); Material: WSP_beton - ihwg beton
Pset_SlabCommon - Reference: ø300 (schroef); IsExternal: yes; LoadBearing: no
Pset_ReinforcementBarPitchOfSlab - Reference: ø300 (schroef)
Component Quantities - WSP_beton - ihwg beton, Mass: 903.056 kg; WSP_beton - ihwg beton, Component Volume (Net): 0.392633 m3; WSP_beton - ihwg beton, Component Volume (Gross): 0.392633 m3
CPset_Phasing - Renovation Phase: Bestaand

# IfcSlab: Slab 343, 17_WSP_FD_beton - fundatiepaal v21-2:ø300 (schroef):1473466
In: -2 fundering
Classification: Vloerplaat - fundering (ARCHICAD Classification); Material: WSP_beton - ihwg beton
Component Quantities - WSP_beton - ihwg beton, Mass: 903.056 kg; WSP_beton - ihwg beton, Component Volume (Net): 0.392633 m3; WSP_beton - ihwg beton, Component Volume (Gross): 0.392633 m3
Pset_SlabCommon - Reference: ø300 (schroef); IsExternal: yes; LoadBearing: no
CPset_Phasing - Renovation Phase: Bestaand
Pset_ReinforcementBarPitchOfSlab - Reference: ø300 (schroef)

# IfcSlab: Slab 344, 17_WSP_FD_beton - fundatiepaal v21-2:ø300 (schroef):1473467
In: -2 fundering
Classification: Vloerplaat - fundering (ARCHICAD Classification); Material: WSP_beton - ihwg beton
Pset_SlabCommon - Reference: ø300 (schroef); IsExternal: yes; LoadBearing: no
CPset_Phasing - Renovation Phase: Bestaand
Pset_ReinforcementBarPitchOfSlab - Reference: ø300 (schroef)
Component Quantities - WSP_beton - ihwg beton, Mass: 903.056 kg; WSP_beton - ihwg beton, Component Volume (Net): 0.392633 m3; WSP_beton - ihwg beton, Component Volume (Gross): 0.392633 m3

# IfcSlab: Slab 345, 17_WSP_FD_beton - fundatiepaal v21-2:ø300 (schroef):1473464
In: -2 fundering
Classification: Vloerplaat - fundering (ARCHICAD Classification); Material: WSP_beton - ihwg beton
Pset_SlabCommon - Reference: ø300 (schroef); IsExternal: yes; LoadBearing: no
Pset_ReinforcementBarPitchOfSlab - Reference: ø300 (schroef)
CPset_Phasing - Renovation Phase: Bestaand
Component Quantities - WSP_beton - ihwg beton, Mass: 903.056 kg; WSP_beton - ihwg beton, Component Volume (Net): 0.392633 m3; WSP_beton - ihwg beton, Component Volume (Gross): 0.392633 m3

# IfcSlab: Slab 346, 17_WSP_FD_beton - fundatiepaal v21-2:ø300 (schroef):1473465
In: -2 fundering
Classification: Vloerplaat - fundering (ARCHICAD Classification); Material: WSP_beton - ihwg beton
Pset_SlabCommon - Reference: ø300 (schroef); IsExternal: yes; LoadBearing: no
Pset_ReinforcementBarPitchOfSlab - Reference: ø300 (schroef)
Component Quantities - WSP_beton - ihwg beton, Mass: 903.056 kg; WSP_beton - ihwg beton, Component Volume (Net): 0.392633 m3; WSP_beton - ihwg beton, Component Volume (Gross): 0.392633 m3
CPset_Phasing - Renovation Phase: Bestaand

# IfcSlab: Slab 347, 17_WSP_FD_beton - fundatiepaal v21-2:ø300 (schroef):1473470
In: -2 fundering
Classification: Vloerplaat - fundering (ARCHICAD Classification); Material: WSP_beton - ihwg beton
Pset_SlabCommon - Reference: ø300 (schroef); IsExternal: yes; LoadBearing: no
Pset_ReinforcementBarPitchOfSlab - Reference: ø300 (schroef)
Component Quantities - WSP_beton - ihwg beton, Mass: 903.056 kg; WSP_beton - ihwg beton, Component Volume (Net): 0.392633 m3; WSP_beton - ihwg beton, Component Volume (Gross): 0.392633 m3
CPset_Phasing - Renovation Phase: Bestaand

# IfcSlab: Slab 348, 17_WSP_FD_beton - fundatiepaal v21-2:ø300 (schroef):1473471
In: -2 fundering
Classification: Vloerplaat - fundering (ARCHICAD Classification); Material: WSP_beton - ihwg beton
Pset_SlabCommon - Reference: ø300 (schroef); IsExternal: yes; LoadBearing: no
Pset_ReinforcementBarPitchOfSlab - Reference: ø300 (schroef)
CPset_Phasing - Renovation Phase: Bestaand
Component Quantities - WSP_beton - ihwg beton, Mass: 903.056 kg; WSP_beton - ihwg beton, Component Volume (Net): 0.392633 m3; WSP_beton - ihwg beton, Component Volume (Gross): 0.392633 m3

# IfcSlab: Slab 349, 17_WSP_FD_beton - fundatiepaal v21-2:ø300 (schroef):1473468
In: -2 fundering
Classification: Vloerplaat - fundering (ARCHICAD Classification); Material: WSP_beton - ihwg beton
Pset_SlabCommon - Reference: ø300 (schroef); IsExternal: yes; LoadBearing: no
Pset_ReinforcementBarPitchOfSlab - Reference: ø300 (schroef)
Component Quantities - WSP_beton - ihwg beton, Mass: 903.056 kg; WSP_beton - ihwg beton, Component Volume (Net): 0.392633 m3; WSP_beton - ihwg beton, Component Volume (Gross): 0.392633 m3
CPset_Phasing - Renovation Phase: Bestaand

# IfcSlab: Slab 35, 17_WSP_FD_beton - fundatiepaal v21-2:ø300 (schroef):1528476
In: -2 fundering
Classification: Vloerplaat - fundering (ARCHICAD Classification); Material: WSP_beton - ihwg beton
Pset_SlabCommon - Reference: ø300 (schroef); IsExternal: yes; LoadBearing: no
Pset_ReinforcementBarPitchOfSlab - Reference: ø300 (schroef)
Component Quantities - WSP_beton - ihwg beton, Mass: 887.213 kg; WSP_beton - ihwg beton, Component Volume (Net): 0.385745 m3; WSP_beton - ihwg beton, Component Volume (Gross): 0.385745 m3
CPset_Phasing - Renovation Phase: Bestaand

# IfcSlab: Slab 350, 17_WSP_FD_beton - fundatiepaal v21-2:ø300 (schroef):1473469
In: -2 fundering
Classification: Vloerplaat - fundering (ARCHICAD Classification); Material: WSP_beton - ihwg beton
Pset_SlabCommon - Reference: ø300 (schroef); IsExternal: yes; LoadBearing: no
Pset_ReinforcementBarPitchOfSlab - Reference: ø300 (schroef)
CPset_Phasing - Renovation Phase: Bestaand
Component Quantities - WSP_beton - ihwg beton, Mass: 903.056 kg; WSP_beton - ihwg beton, Component Volume (Net): 0.392633 m3; WSP_beton - ihwg beton, Component Volume (Gross): 0.392633 m3

# IfcSlab: Slab 351, 17_WSP_FD_beton - fundatiepaal v21-2:ø300 (schroef):1473426
In: -2 fundering
Classification: Vloerplaat - fundering (ARCHICAD Classification); Material: WSP_beton - ihwg beton
Pset_SlabCommon - Reference: ø300 (schroef); IsExternal: yes; LoadBearing: no
Pset_ReinforcementBarPitchOfSlab - Reference: ø300 (schroef)
Component Quantities - WSP_beton - ihwg beton, Mass: 887.213 kg; WSP_beton - ihwg beton, Component Volume (Net): 0.385745 m3; WSP_beton - ihwg beton, Component Volume (Gross): 0.385745 m3
CPset_Phasing - Renovation Phase: Bestaand

# IfcSlab: Slab 352, 17_WSP_FD_beton - fundatiepaal v21-2:ø300 (schroef):1473427
In: -2 fundering
Classification: Vloerplaat - fundering (ARCHICAD Classification); Material: WSP_beton - ihwg beton
Pset_SlabCommon - Reference: ø300 (schroef); IsExternal: yes; LoadBearing: no
Pset_ReinforcementBarPitchOfSlab - Reference: ø300 (schroef)
CPset_Phasing - Renovation Phase: Bestaand
Component Quantities - WSP_beton - ihwg beton, Mass: 887.213 kg; WSP_beton - ihwg beton, Component Volume (Net): 0.385745 m3; WSP_beton - ihwg beton, Component Volume (Gross): 0.385745 m3

# IfcSlab: Slab 353, 17_WSP_FD_beton - fundatiepaal v21-2:ø300 (schroef):1473425
In: -2 fundering
Classification: Vloerplaat - fundering (ARCHICAD Classification); Material: WSP_beton - ihwg beton
Pset_ReinforcementBarPitchOfSlab - Reference: ø300 (schroef)
CPset_Phasing - Renovation Phase: Bestaand
Component Quantities - WSP_beton - ihwg beton, Mass: 887.213 kg; WSP_beton - ihwg beton, Component Volume (Net): 0.385745 m3; WSP_beton - ihwg beton, Component Volume (Gross): 0.385745 m3
Pset_SlabCommon - Reference: ø300 (schroef); IsExternal: yes; LoadBearing: no

# IfcSlab: Slab 354, 17_WSP_FD_beton - fundatiepaal v21-2:ø300 (schroef):1473430
In: -2 fundering
Classification: Vloerplaat - fundering (ARCHICAD Classification); Material: WSP_beton - ihwg beton
Pset_SlabCommon - Reference: ø300 (schroef); IsExternal: yes; LoadBearing: no
Pset_ReinforcementBarPitchOfSlab - Reference: ø300 (schroef)
Component Quantities - WSP_beton - ihwg beton, Mass: 887.213 kg; WSP_beton - ihwg beton, Component Volume (Net): 0.385745 m3; WSP_beton - ihwg beton, Component Volume (Gross): 0.385745 m3
CPset_Phasing - Renovation Phase: Bestaand

# IfcSlab: Slab 355, 17_WSP_FD_beton - fundatiepaal v21-2:ø300 (schroef):1473431
In: -2 fundering
Classification: Vloerplaat - fundering (ARCHICAD Classification); Material: WSP_beton - ihwg beton
Pset_SlabCommon - Reference: ø300 (schroef); IsExternal: yes; LoadBearing: no
Pset_ReinforcementBarPitchOfSlab - Reference: ø300 (schroef)
Component Quantities - WSP_beton - ihwg beton, Mass: 887.213 kg; WSP_beton - ihwg beton, Component Volume (Net): 0.385745 m3; WSP_beton - ihwg beton, Component Volume (Gross): 0.385745 m3
CPset_Phasing - Renovation Phase: Bestaand

# IfcSlab: Slab 356, 17_WSP_FD_beton - fundatiepaal v21-2:ø300 (schroef):1473428
In: -2 fundering
Classification: Vloerplaat - fundering (ARCHICAD Classification); Material: WSP_beton - ihwg beton
Pset_ReinforcementBarPitchOfSlab - Reference: ø300 (schroef)
Pset_SlabCommon - Reference: ø300 (schroef); IsExternal: yes; LoadBearing: no
CPset_Phasing - Renovation Phase: Bestaand
Component Quantities - WSP_beton - ihwg beton, Mass: 887.213 kg; WSP_beton - ihwg beton, Component Volume (Net): 0.385745 m3; WSP_beton - ihwg beton, Component Volume (Gross): 0.385745 m3

# IfcSlab: Slab 357, 17_WSP_FD_beton - fundatiepaal v21-2:ø300 (schroef):1473429
In: -2 fundering
Classification: Vloerplaat - fundering (ARCHICAD Classification); Material: WSP_beton - ihwg beton
Pset_SlabCommon - Reference: ø300 (schroef); IsExternal: yes; LoadBearing: no
Pset_ReinforcementBarPitchOfSlab - Reference: ø300 (schroef)
CPset_Phasing - Renovation Phase: Bestaand
Component Quantities - WSP_beton - ihwg beton, Mass: 887.213 kg; WSP_beton - ihwg beton, Component Volume (Net): 0.385745 m3; WSP_beton - ihwg beton, Component Volume (Gross): 0.385745 m3

# IfcSlab: Slab 358, 17_WSP_FD_beton - fundatiepaal v21-2:ø300 (schroef):1473434
In: -2 fundering
Classification: Vloerplaat - fundering (ARCHICAD Classification); Material: WSP_beton - ihwg beton
Component Quantities - WSP_beton - ihwg beton, Mass: 887.213 kg; WSP_beton - ihwg beton, Component Volume (Net): 0.385745 m3; WSP_beton - ihwg beton, Component Volume (Gross): 0.385745 m3
CPset_Phasing - Renovation Phase: Bestaand
Pset_SlabCommon - Reference: ø300 (schroef); IsExternal: yes; LoadBearing: no
Pset_ReinforcementBarPitchOfSlab - Reference: ø300 (schroef)

# IfcSlab: Slab 359, 17_WSP_FD_beton - fundatiepaal v21-2:ø300 (schroef):1473435
In: -2 fundering
Classification: Vloerplaat - fundering (ARCHICAD Classification); Material: WSP_beton - ihwg beton
Pset_ReinforcementBarPitchOfSlab - Reference: ø300 (schroef)
Component Quantities - WSP_beton - ihwg beton, Mass: 887.213 kg; WSP_beton - ihwg beton, Component Volume (Net): 0.385745 m3; WSP_beton - ihwg beton, Component Volume (Gross): 0.385745 m3
CPset_Phasing - Renovation Phase: Bestaand
Pset_SlabCommon - Reference: ø300 (schroef); IsExternal: yes; LoadBearing: no

# IfcSlab: Slab 36, 17_WSP_FD_beton - fundatiepaal v21-2:ø300 (schroef):1528479
In: -2 fundering
Classification: Vloerplaat - fundering (ARCHICAD Classification); Material: WSP_beton - ihwg beton
CPset_Phasing - Renovation Phase: Bestaand
Pset_ReinforcementBarPitchOfSlab - Reference: ø300 (schroef)
Component Quantities - WSP_beton - ihwg beton, Mass: 903.056 kg; WSP_beton - ihwg beton, Component Volume (Net): 0.392633 m3; WSP_beton - ihwg beton, Component Volume (Gross): 0.392633 m3
Pset_SlabCommon - Reference: ø300 (schroef); IsExternal: yes; LoadBearing: no

# IfcSlab: Slab 360, 17_WSP_FD_beton - fundatiepaal v21-2:ø300 (schroef):1473432
In: -2 fundering
Classification: Vloerplaat - fundering (ARCHICAD Classification); Material: WSP_beton - ihwg beton
Pset_ReinforcementBarPitchOfSlab - Reference: ø300 (schroef)
Pset_SlabCommon - Reference: ø300 (schroef); IsExternal: yes; LoadBearing: no
CPset_Phasing - Renovation Phase: Bestaand
Component Quantities - WSP_beton - ihwg beton, Mass: 887.213 kg; WSP_beton - ihwg beton, Component Volume (Net): 0.385745 m3; WSP_beton - ihwg beton, Component Volume (Gross): 0.385745 m3

# IfcSlab: Slab 361, 17_WSP_FD_beton - fundatiepaal v21-2:ø300 (schroef):1473433
In: -2 fundering
Classification: Vloerplaat - fundering (ARCHICAD Classification); Material: WSP_beton - ihwg beton
Pset_SlabCommon - Reference: ø300 (schroef); IsExternal: yes; LoadBearing: no
CPset_Phasing - Renovation Phase: Bestaand
Pset_ReinforcementBarPitchOfSlab - Reference: ø300 (schroef)
Component Quantities - WSP_beton - ihwg beton, Mass: 887.213 kg; WSP_beton - ihwg beton, Component Volume (Net): 0.385745 m3; WSP_beton - ihwg beton, Component Volume (Gross): 0.385745 m3

# IfcSlab: Slab 362, 17_WSP_FD_beton - fundatiepaal v21-2:ø300 (schroef):1473438
In: -2 fundering
Classification: Vloerplaat - fundering (ARCHICAD Classification); Material: WSP_beton - ihwg beton
CPset_Phasing - Renovation Phase: Bestaand
Pset_SlabCommon - Reference: ø300 (schroef); IsExternal: yes; LoadBearing: no
Pset_ReinforcementBarPitchOfSlab - Reference: ø300 (schroef)
Component Quantities - WSP_beton - ihwg beton, Mass: 887.213 kg; WSP_beton - ihwg beton, Component Volume (Net): 0.385745 m3; WSP_beton - ihwg beton, Component Volume (Gross): 0.385745 m3

# IfcSlab: Slab 363, 17_WSP_FD_beton - fundatiepaal v21-2:ø300 (schroef):1473439
In: -2 fundering
Classification: Vloerplaat - fundering (ARCHICAD Classification); Material: WSP_beton - ihwg beton
Pset_SlabCommon - Reference: ø300 (schroef); IsExternal: yes; LoadBearing: no
CPset_Phasing - Renovation Phase: Bestaand
Pset_ReinforcementBarPitchOfSlab - Reference: ø300 (schroef)
Component Quantities - WSP_beton - ihwg beton, Mass: 887.213 kg; WSP_beton - ihwg beton, Component Volume (Net): 0.385745 m3; WSP_beton - ihwg beton, Component Volume (Gross): 0.385745 m3

# IfcSlab: Slab 364, 17_WSP_FD_beton - fundatiepaal v21-2:ø300 (schroef):1473436
In: -2 fundering
Classification: Vloerplaat - fundering (ARCHICAD Classification); Material: WSP_beton - ihwg beton
Pset_SlabCommon - Reference: ø300 (schroef); IsExternal: yes; LoadBearing: no
Component Quantities - WSP_beton - ihwg beton, Mass: 887.213 kg; WSP_beton - ihwg beton, Component Volume (Net): 0.385745 m3; WSP_beton - ihwg beton, Component Volume (Gross): 0.385745 m3
Pset_ReinforcementBarPitchOfSlab - Reference: ø300 (schroef)
CPset_Phasing - Renovation Phase: Bestaand

# IfcSlab: Slab 365, 17_WSP_FD_beton - fundatiepaal v21-2:ø300 (schroef):1473437
In: -2 fundering
Classification: Vloerplaat - fundering (ARCHICAD Classification); Material: WSP_beton - ihwg beton
Pset_ReinforcementBarPitchOfSlab - Reference: ø300 (schroef)
CPset_Phasing - Renovation Phase: Bestaand
Pset_SlabCommon - Reference: ø300 (schroef); IsExternal: yes; LoadBearing: no
Component Quantities - WSP_beton - ihwg beton, Mass: 887.213 kg; WSP_beton - ihwg beton, Component Volume (Net): 0.385745 m3; WSP_beton - ihwg beton, Component Volume (Gross): 0.385745 m3

# IfcSlab: Slab 366, 17_WSP_FD_beton - fundatiepaal v21-2:ø300 (schroef):1473262
In: -2 fundering
Classification: Vloerplaat - fundering (ARCHICAD Classification); Material: WSP_beton - ihwg beton
Pset_SlabCommon - Reference: ø300 (schroef); IsExternal: yes; LoadBearing: no
Pset_ReinforcementBarPitchOfSlab - Reference: ø300 (schroef)
Component Quantities - WSP_beton - ihwg beton, Mass: 887.213 kg; WSP_beton - ihwg beton, Component Volume (Net): 0.385745 m3; WSP_beton - ihwg beton, Component Volume (Gross): 0.385745 m3
CPset_Phasing - Renovation Phase: Bestaand

# IfcSlab: Slab 367, 17_WSP_FD_beton - fundatiepaal v21-2:ø300 (schroef):1473263
In: -2 fundering
Classification: Vloerplaat - fundering (ARCHICAD Classification); Material: WSP_beton - ihwg beton
Pset_ReinforcementBarPitchOfSlab - Reference: ø300 (schroef)
Pset_SlabCommon - Reference: ø300 (schroef); IsExternal: yes; LoadBearing: no
Component Quantities - WSP_beton - ihwg beton, Mass: 887.213 kg; WSP_beton - ihwg beton, Component Volume (Net): 0.385745 m3; WSP_beton - ihwg beton, Component Volume (Gross): 0.385745 m3
CPset_Phasing - Renovation Phase: Bestaand

# IfcSlab: Slab 368, 17_WSP_FD_beton - fundatiepaal v21-2:ø300 (schroef):1473266
In: -2 fundering
Classification: Vloerplaat - fundering (ARCHICAD Classification); Material: WSP_beton - ihwg beton
CPset_Phasing - Renovation Phase: Bestaand
Pset_ReinforcementBarPitchOfSlab - Reference: ø300 (schroef)
Component Quantities - WSP_beton - ihwg beton, Mass: 887.213 kg; WSP_beton - ihwg beton, Component Volume (Net): 0.385745 m3; WSP_beton - ihwg beton, Component Volume (Gross): 0.385745 m3
Pset_SlabCommon - Reference: ø300 (schroef); IsExternal: yes; LoadBearing: no

# IfcSlab: Slab 369, 17_WSP_FD_beton - fundatiepaal v21-2:ø300 (schroef):1473267
In: -2 fundering
Classification: Vloerplaat - fundering (ARCHICAD Classification); Material: WSP_beton - ihwg beton
Pset_ReinforcementBarPitchOfSlab - Reference: ø300 (schroef)
Component Quantities - WSP_beton - ihwg beton, Mass: 887.213 kg; WSP_beton - ihwg beton, Component Volume (Net): 0.385745 m3; WSP_beton - ihwg beton, Component Volume (Gross): 0.385745 m3
CPset_Phasing - Renovation Phase: Bestaand
Pset_SlabCommon - Reference: ø300 (schroef); IsExternal: yes; LoadBearing: no

# IfcSlab: Slab 37, 17_WSP_FD_beton - fundatiepaal v21-2:ø300 (schroef):1528478
In: -2 fundering
Classification: Vloerplaat - fundering (ARCHICAD Classification); Material: WSP_beton - ihwg beton
Pset_SlabCommon - Reference: ø300 (schroef); IsExternal: yes; LoadBearing: no
CPset_Phasing - Renovation Phase: Bestaand
Pset_ReinforcementBarPitchOfSlab - Reference: ø300 (schroef)
Component Quantities - WSP_beton - ihwg beton, Mass: 903.056 kg; WSP_beton - ihwg beton, Component Volume (Net): 0.392633 m3; WSP_beton - ihwg beton, Component Volume (Gross): 0.392633 m3

# IfcSlab: Slab 370, 17_WSP_FD_beton - fundatiepaal v21-2:ø300 (schroef):1473264
In: -2 fundering
Classification: Vloerplaat - fundering (ARCHICAD Classification); Material: WSP_beton - ihwg beton
Pset_SlabCommon - Reference: ø300 (schroef); IsExternal: yes; LoadBearing: no
Pset_ReinforcementBarPitchOfSlab - Reference: ø300 (schroef)
Component Quantities - WSP_beton - ihwg beton, Mass: 887.213 kg; WSP_beton - ihwg beton, Component Volume (Net): 0.385745 m3; WSP_beton - ihwg beton, Component Volume (Gross): 0.385745 m3
CPset_Phasing - Renovation Phase: Bestaand

# IfcSlab: Slab 371, 17_WSP_FD_beton - fundatiepaal v21-2:ø300 (schroef):1473265
In: -2 fundering
Classification: Vloerplaat - fundering (ARCHICAD Classification); Material: WSP_beton - ihwg beton
Pset_SlabCommon - Reference: ø300 (schroef); IsExternal: yes; LoadBearing: no
CPset_Phasing - Renovation Phase: Bestaand
Pset_ReinforcementBarPitchOfSlab - Reference: ø300 (schroef)
Component Quantities - WSP_beton - ihwg beton, Mass: 887.213 kg; WSP_beton - ihwg beton, Component Volume (Net): 0.385745 m3; WSP_beton - ihwg beton, Component Volume (Gross): 0.385745 m3

# IfcSlab: Slab 372, 17_WSP_FD_beton - fundatiepaal v21-2:ø300 (schroef):1473270
In: -2 fundering
Classification: Vloerplaat - fundering (ARCHICAD Classification); Material: WSP_beton - ihwg beton
Pset_SlabCommon - Reference: ø300 (schroef); IsExternal: yes; LoadBearing: no
CPset_Phasing - Renovation Phase: Bestaand
Component Quantities - WSP_beton - ihwg beton, Mass: 887.213 kg; WSP_beton - ihwg beton, Component Volume (Net): 0.385745 m3; WSP_beton - ihwg beton, Component Volume (Gross): 0.385745 m3
Pset_ReinforcementBarPitchOfSlab - Reference: ø300 (schroef)

# IfcSlab: Slab 373, 17_WSP_FD_beton - fundatiepaal v21-2:ø300 (schroef):1473271
In: -2 fundering
Classification: Vloerplaat - fundering (ARCHICAD Classification); Material: WSP_beton - ihwg beton
Pset_SlabCommon - Reference: ø300 (schroef); IsExternal: yes; LoadBearing: no
Pset_ReinforcementBarPitchOfSlab - Reference: ø300 (schroef)
CPset_Phasing - Renovation Phase: Bestaand
Component Quantities - WSP_beton - ihwg beton, Mass: 887.213 kg; WSP_beton - ihwg beton, Component Volume (Net): 0.385745 m3; WSP_beton - ihwg beton, Component Volume (Gross): 0.385745 m3

# IfcSlab: Slab 374, 17_WSP_FD_beton - fundatiepaal v21-2:ø300 (schroef):1473268
In: -2 fundering
Classification: Vloerplaat - fundering (ARCHICAD Classification); Material: WSP_beton - ihwg beton
Pset_SlabCommon - Reference: ø300 (schroef); IsExternal: yes; LoadBearing: no
Pset_ReinforcementBarPitchOfSlab - Reference: ø300 (schroef)
CPset_Phasing - Renovation Phase: Bestaand
Component Quantities - WSP_beton - ihwg beton, Mass: 887.213 kg; WSP_beton - ihwg beton, Component Volume (Net): 0.385745 m3; WSP_beton - ihwg beton, Component Volume (Gross): 0.385745 m3

# IfcSlab: Slab 375, 17_WSP_FD_beton - fundatiepaal v21-2:ø300 (schroef):1473269
In: -2 fundering
Classification: Vloerplaat - fundering (ARCHICAD Classification); Material: WSP_beton - ihwg beton
Pset_ReinforcementBarPitchOfSlab - Reference: ø300 (schroef)
Pset_SlabCommon - Reference: ø300 (schroef); IsExternal: yes; LoadBearing: no
Component Quantities - WSP_beton - ihwg beton, Mass: 887.213 kg; WSP_beton - ihwg beton, Component Volume (Net): 0.385745 m3; WSP_beton - ihwg beton, Component Volume (Gross): 0.385745 m3
CPset_Phasing - Renovation Phase: Bestaand

# IfcSlab: Slab 376, 17_WSP_FD_beton - fundatiepaal v21-2:ø300 (schroef):1473274
In: -2 fundering
Classification: Vloerplaat - fundering (ARCHICAD Classification); Material: WSP_beton - ihwg beton
Pset_SlabCommon - Reference: ø300 (schroef); IsExternal: yes; LoadBearing: no
Component Quantities - WSP_beton - ihwg beton, Mass: 887.213 kg; WSP_beton - ihwg beton, Component Volume (Net): 0.385745 m3; WSP_beton - ihwg beton, Component Volume (Gross): 0.385745 m3
CPset_Phasing - Renovation Phase: Bestaand
Pset_ReinforcementBarPitchOfSlab - Reference: ø300 (schroef)

# IfcSlab: Slab 377, 17_WSP_FD_beton - fundatiepaal v21-2:ø300 (schroef):1473275
In: -2 fundering
Classification: Vloerplaat - fundering (ARCHICAD Classification); Material: WSP_beton - ihwg beton
Pset_SlabCommon - Reference: ø300 (schroef); IsExternal: yes; LoadBearing: no
Pset_ReinforcementBarPitchOfSlab - Reference: ø300 (schroef)
CPset_Phasing - Renovation Phase: Bestaand
Component Quantities - WSP_beton - ihwg beton, Mass: 887.213 kg; WSP_beton - ihwg beton, Component Volume (Net): 0.385745 m3; WSP_beton - ihwg beton, Component Volume (Gross): 0.385745 m3

# IfcSlab: Slab 378, 17_WSP_FD_beton - fundatiepaal v21-2:ø300 (schroef):1473272
In: -2 fundering
Classification: Vloerplaat - fundering (ARCHICAD Classification); Material: WSP_beton - ihwg beton
Pset_SlabCommon - Reference: ø300 (schroef); IsExternal: yes; LoadBearing: no
Pset_ReinforcementBarPitchOfSlab - Reference: ø300 (schroef)
CPset_Phasing - Renovation Phase: Bestaand
Component Quantities - WSP_beton - ihwg beton, Mass: 887.213 kg; WSP_beton - ihwg beton, Component Volume (Net): 0.385745 m3; WSP_beton - ihwg beton, Component Volume (Gross): 0.385745 m3

# IfcSlab: Slab 379, 17_WSP_FD_beton - fundatiepaal v21-2:ø300 (schroef):1473273
In: -2 fundering
Classification: Vloerplaat - fundering (ARCHICAD Classification); Material: WSP_beton - ihwg beton
Pset_SlabCommon - Reference: ø300 (schroef); IsExternal: yes; LoadBearing: no
CPset_Phasing - Renovation Phase: Bestaand
Component Quantities - WSP_beton - ihwg beton, Mass: 887.213 kg; WSP_beton - ihwg beton, Component Volume (Net): 0.385745 m3; WSP_beton - ihwg beton, Component Volume (Gross): 0.385745 m3
Pset_ReinforcementBarPitchOfSlab - Reference: ø300 (schroef)

# IfcSlab: Slab 38, 17_WSP_FD_beton - fundatiepaal v21-2:ø300 (schroef):1528475
In: -2 fundering
Classification: Vloerplaat - fundering (ARCHICAD Classification); Material: WSP_beton - ihwg beton
Pset_SlabCommon - Reference: ø300 (schroef); IsExternal: yes; LoadBearing: no
Pset_ReinforcementBarPitchOfSlab - Reference: ø300 (schroef)
Component Quantities - WSP_beton - ihwg beton, Mass: 887.213 kg; WSP_beton - ihwg beton, Component Volume (Net): 0.385745 m3; WSP_beton - ihwg beton, Component Volume (Gross): 0.385745 m3
CPset_Phasing - Renovation Phase: Bestaand

# IfcSlab: Slab 380, 17_WSP_FD_beton - fundatiepaal v21-2:ø300 (schroef):1473278
In: -2 fundering
Classification: Vloerplaat - fundering (ARCHICAD Classification); Material: WSP_beton - ihwg beton
Pset_ReinforcementBarPitchOfSlab - Reference: ø300 (schroef)
Pset_SlabCommon - Reference: ø300 (schroef); IsExternal: yes; LoadBearing: no
Component Quantities - WSP_beton - ihwg beton, Mass: 887.213 kg; WSP_beton - ihwg beton, Component Volume (Net): 0.385745 m3; WSP_beton - ihwg beton, Component Volume (Gross): 0.385745 m3
CPset_Phasing - Renovation Phase: Bestaand

# IfcSlab: Slab 381, 17_WSP_FD_beton - fundatiepaal v21-2:ø300 (schroef):1473279
In: -2 fundering
Classification: Vloerplaat - fundering (ARCHICAD Classification); Material: WSP_beton - ihwg beton
Pset_SlabCommon - Reference: ø300 (schroef); IsExternal: yes; LoadBearing: no
Pset_ReinforcementBarPitchOfSlab - Reference: ø300 (schroef)
CPset_Phasing - Renovation Phase: Bestaand
Component Quantities - WSP_beton - ihwg beton, Mass: 887.213 kg; WSP_beton - ihwg beton, Component Volume (Net): 0.385745 m3; WSP_beton - ihwg beton, Component Volume (Gross): 0.385745 m3

# IfcSlab: Slab 382, 17_WSP_FD_beton - fundatiepaal v21-2:ø300 (schroef):1473276
In: -2 fundering
Classification: Vloerplaat - fundering (ARCHICAD Classification); Material: WSP_beton - ihwg beton
Pset_SlabCommon - Reference: ø300 (schroef); IsExternal: yes; LoadBearing: no
Component Quantities - WSP_beton - ihwg beton, Mass: 887.213 kg; WSP_beton - ihwg beton, Component Volume (Net): 0.385745 m3; WSP_beton - ihwg beton, Component Volume (Gross): 0.385745 m3
CPset_Phasing - Renovation Phase: Bestaand
Pset_ReinforcementBarPitchOfSlab - Reference: ø300 (schroef)

# IfcSlab: Slab 383, 17_WSP_FD_beton - fundatiepaal v21-2:ø300 (schroef):1473277
In: -2 fundering
Classification: Vloerplaat - fundering (ARCHICAD Classification); Material: WSP_beton - ihwg beton
Pset_SlabCommon - Reference: ø300 (schroef); IsExternal: yes; LoadBearing: no
Component Quantities - WSP_beton - ihwg beton, Mass: 887.213 kg; WSP_beton - ihwg beton, Component Volume (Net): 0.385745 m3; WSP_beton - ihwg beton, Component Volume (Gross): 0.385745 m3
CPset_Phasing - Renovation Phase: Bestaand
Pset_ReinforcementBarPitchOfSlab - Reference: ø300 (schroef)

# IfcSlab: Slab 384, 17_WSP_FD_beton - fundatiepaal v21-2:ø300 (schroef):1471566
In: -2 fundering
Classification: Vloerplaat - fundering (ARCHICAD Classification); Material: WSP_beton - ihwg beton
Pset_ReinforcementBarPitchOfSlab - Reference: ø300 (schroef)
Pset_SlabCommon - Reference: ø300 (schroef); IsExternal: yes; LoadBearing: no
Component Quantities - WSP_beton - ihwg beton, Mass: 887.213 kg; WSP_beton - ihwg beton, Component Volume (Net): 0.385745 m3; WSP_beton - ihwg beton, Component Volume (Gross): 0.385745 m3
CPset_Phasing - Renovation Phase: Bestaand

# IfcSlab: Slab 385, 17_WSP_FD_beton - fundatiepaal v21-2:ø300 (schroef):1471567
In: -2 fundering
Classification: Vloerplaat - fundering (ARCHICAD Classification); Material: WSP_beton - ihwg beton
Pset_SlabCommon - Reference: ø300 (schroef); IsExternal: yes; LoadBearing: no
CPset_Phasing - Renovation Phase: Bestaand
Component Quantities - WSP_beton - ihwg beton, Mass: 887.213 kg; WSP_beton - ihwg beton, Component Volume (Net): 0.385745 m3; WSP_beton - ihwg beton, Component Volume (Gross): 0.385745 m3
Pset_ReinforcementBarPitchOfSlab - Reference: ø300 (schroef)

# IfcSlab: Slab 386, 17_WSP_FD_beton - fundatiepaal v21-2:ø300 (schroef):1471564
In: -2 fundering
Classification: Vloerplaat - fundering (ARCHICAD Classification); Material: WSP_beton - ihwg beton
Pset_SlabCommon - Reference: ø300 (schroef); IsExternal: yes; LoadBearing: no
Component Quantities - WSP_beton - ihwg beton, Mass: 887.213 kg; WSP_beton - ihwg beton, Component Volume (Net): 0.385745 m3; WSP_beton - ihwg beton, Component Volume (Gross): 0.385745 m3
CPset_Phasing - Renovation Phase: Bestaand
Pset_ReinforcementBarPitchOfSlab - Reference: ø300 (schroef)

# IfcSlab: Slab 387, 17_WSP_FD_beton - fundatiepaal v21-2:ø300 (schroef):1471565
In: -2 fundering
Classification: Vloerplaat - fundering (ARCHICAD Classification); Material: WSP_beton - ihwg beton
Pset_SlabCommon - Reference: ø300 (schroef); IsExternal: yes; LoadBearing: no
Pset_ReinforcementBarPitchOfSlab - Reference: ø300 (schroef)
Component Quantities - WSP_beton - ihwg beton, Mass: 887.213 kg; WSP_beton - ihwg beton, Component Volume (Net): 0.385745 m3; WSP_beton - ihwg beton, Component Volume (Gross): 0.385745 m3
CPset_Phasing - Renovation Phase: Bestaand

# IfcSlab: Slab 388, 17_WSP_FD_beton - fundatiepaal v21-2:ø300 (schroef):1471570
In: -2 fundering
Classification: Vloerplaat - fundering (ARCHICAD Classification); Material: WSP_beton - ihwg beton
Pset_ReinforcementBarPitchOfSlab - Reference: ø300 (schroef)
Pset_SlabCommon - Reference: ø300 (schroef); IsExternal: yes; LoadBearing: no
Component Quantities - WSP_beton - ihwg beton, Mass: 887.213 kg; WSP_beton - ihwg beton, Component Volume (Net): 0.385745 m3; WSP_beton - ihwg beton, Component Volume (Gross): 0.385745 m3
CPset_Phasing - Renovation Phase: Bestaand

# IfcSlab: Slab 389, 17_WSP_FD_beton - fundatiepaal v21-2:ø300 (schroef):1471571
In: -2 fundering
Classification: Vloerplaat - fundering (ARCHICAD Classification); Material: WSP_beton - ihwg beton
Pset_ReinforcementBarPitchOfSlab - Reference: ø300 (schroef)
Pset_SlabCommon - Reference: ø300 (schroef); IsExternal: yes; LoadBearing: no
Component Quantities - WSP_beton - ihwg beton, Mass: 887.213 kg; WSP_beton - ihwg beton, Component Volume (Net): 0.385745 m3; WSP_beton - ihwg beton, Component Volume (Gross): 0.385745 m3
CPset_Phasing - Renovation Phase: Bestaand

# IfcSlab: Slab 39, 17_WSP_FD_beton - fundatiepaal v21-2:ø300 (schroef):1473602
In: -2 fundering
Classification: Vloerplaat - fundering (ARCHICAD Classification); Material: WSP_beton - ihwg beton
Pset_SlabCommon - Reference: ø300 (schroef); IsExternal: yes; LoadBearing: no
Component Quantities - WSP_beton - ihwg beton, Mass: 903.056 kg; WSP_beton - ihwg beton, Component Volume (Net): 0.392633 m3; WSP_beton - ihwg beton, Component Volume (Gross): 0.392633 m3
Pset_ReinforcementBarPitchOfSlab - Reference: ø300 (schroef)
CPset_Phasing - Renovation Phase: Bestaand

# IfcSlab: Slab 390, 17_WSP_FD_beton - fundatiepaal v21-2:ø300 (schroef):1471568
In: -2 fundering
Classification: Vloerplaat - fundering (ARCHICAD Classification); Material: WSP_beton - ihwg beton
Pset_SlabCommon - Reference: ø300 (schroef); IsExternal: yes; LoadBearing: no
Component Quantities - WSP_beton - ihwg beton, Mass: 887.213 kg; WSP_beton - ihwg beton, Component Volume (Net): 0.385745 m3; WSP_beton - ihwg beton, Component Volume (Gross): 0.385745 m3
Pset_ReinforcementBarPitchOfSlab - Reference: ø300 (schroef)
CPset_Phasing - Renovation Phase: Bestaand

# IfcSlab: Slab 391, 17_WSP_FD_beton - fundatiepaal v21-2:ø300 (schroef):1471569
In: -2 fundering
Classification: Vloerplaat - fundering (ARCHICAD Classification); Material: WSP_beton - ihwg beton
Pset_ReinforcementBarPitchOfSlab - Reference: ø300 (schroef)
Pset_SlabCommon - Reference: ø300 (schroef); IsExternal: yes; LoadBearing: no
CPset_Phasing - Renovation Phase: Bestaand
Component Quantities - WSP_beton - ihwg beton, Mass: 887.213 kg; WSP_beton - ihwg beton, Component Volume (Net): 0.385745 m3; WSP_beton - ihwg beton, Component Volume (Gross): 0.385745 m3

# IfcSlab: Slab 392, 17_WSP_FD_beton - fundatiepaal v21-2:ø300 (schroef):1471574
In: -2 fundering
Classification: Vloerplaat - fundering (ARCHICAD Classification); Material: WSP_beton - ihwg beton
Pset_ReinforcementBarPitchOfSlab - Reference: ø300 (schroef)
Pset_SlabCommon - Reference: ø300 (schroef); IsExternal: yes; LoadBearing: no
CPset_Phasing - Renovation Phase: Bestaand
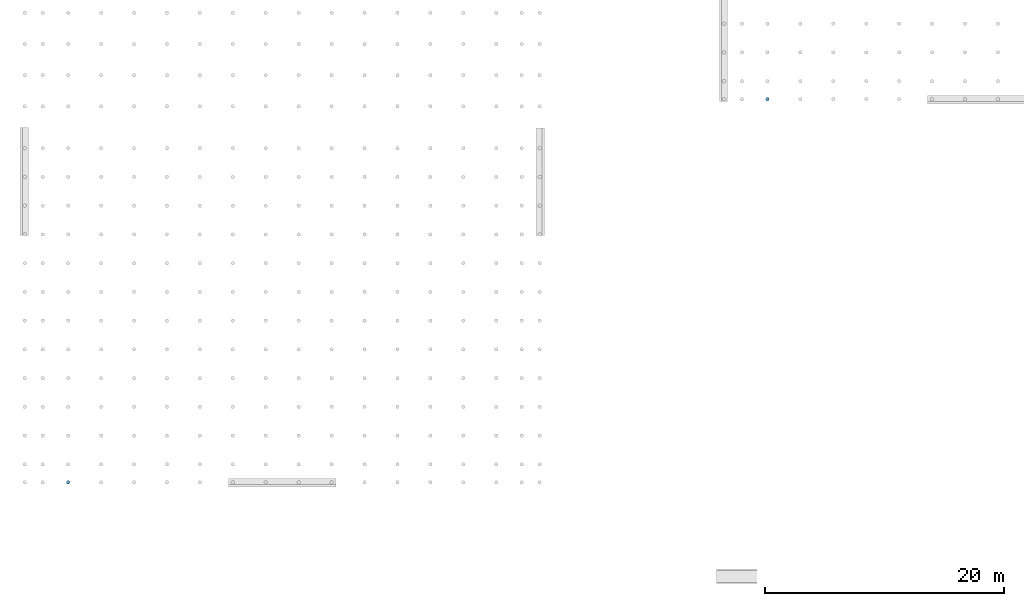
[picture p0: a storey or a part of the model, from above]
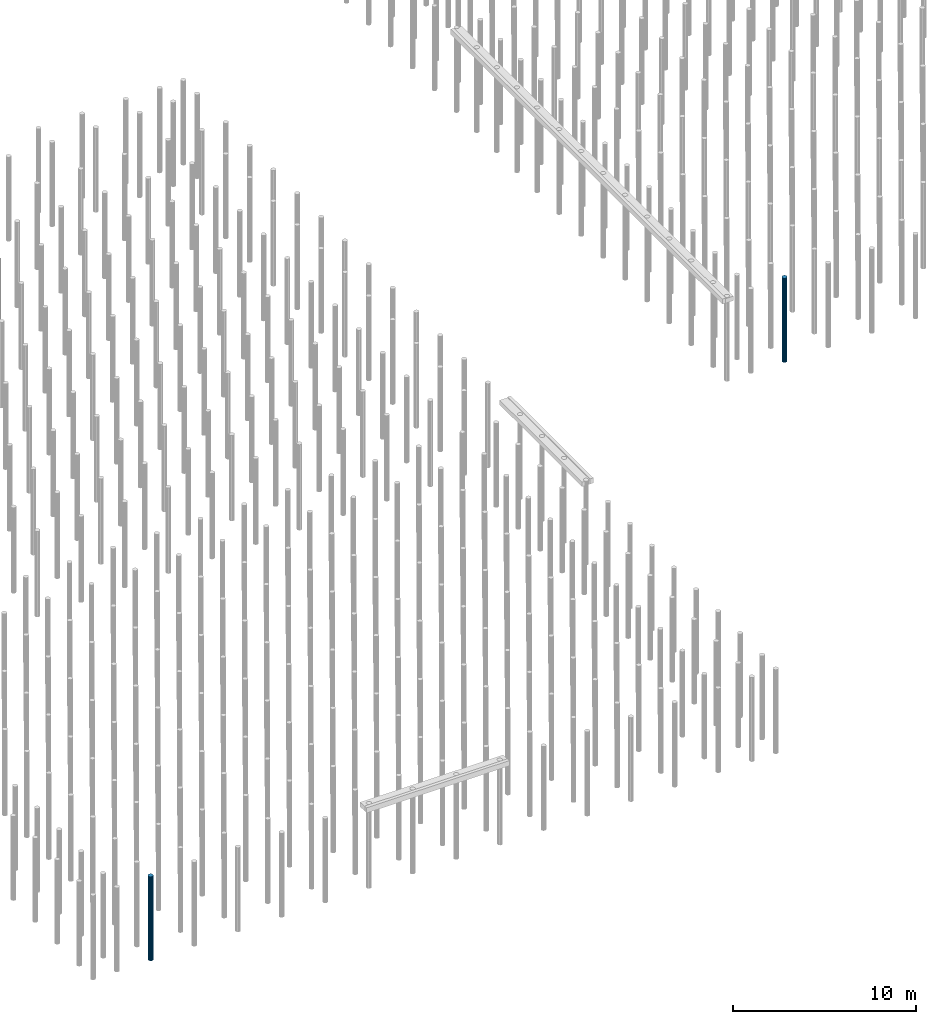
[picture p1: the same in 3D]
Properties of the parts of a building model (IFC2X3), part 6 of 13

# IfcSlab: Slab 392, 17_WSP_FD_beton - fundatiepaal v21-2:ø300 (schroef):1471574
Component Quantities - WSP_beton - ihwg beton, Mass: 887.213 kg; WSP_beton - ihwg beton, Component Volume (Net): 0.385745 m3; WSP_beton - ihwg beton, Component Volume (Gross): 0.385745 m3

# IfcSlab: Slab 393, 17_WSP_FD_beton - fundatiepaal v21-2:ø300 (schroef):1471575
In: -2 fundering
Classification: Vloerplaat - fundering (ARCHICAD Classification); Material: WSP_beton - ihwg beton
Pset_SlabCommon - Reference: ø300 (schroef); IsExternal: yes; LoadBearing: no
Component Quantities - WSP_beton - ihwg beton, Mass: 887.213 kg; WSP_beton - ihwg beton, Component Volume (Net): 0.385745 m3; WSP_beton - ihwg beton, Component Volume (Gross): 0.385745 m3
CPset_Phasing - Renovation Phase: Bestaand
Pset_ReinforcementBarPitchOfSlab - Reference: ø300 (schroef)

# IfcSlab: Slab 394, 17_WSP_FD_beton - fundatiepaal v21-2:ø300 (schroef):1471572
In: -2 fundering
Classification: Vloerplaat - fundering (ARCHICAD Classification); Material: WSP_beton - ihwg beton
Pset_SlabCommon - Reference: ø300 (schroef); IsExternal: yes; LoadBearing: no
Pset_ReinforcementBarPitchOfSlab - Reference: ø300 (schroef)
Component Quantities - WSP_beton - ihwg beton, Mass: 887.213 kg; WSP_beton - ihwg beton, Component Volume (Net): 0.385745 m3; WSP_beton - ihwg beton, Component Volume (Gross): 0.385745 m3
CPset_Phasing - Renovation Phase: Bestaand

# IfcSlab: Slab 395, 17_WSP_FD_beton - fundatiepaal v21-2:ø300 (schroef):1471573
In: -2 fundering
Classification: Vloerplaat - fundering (ARCHICAD Classification); Material: WSP_beton - ihwg beton
Pset_SlabCommon - Reference: ø300 (schroef); IsExternal: yes; LoadBearing: no
Pset_ReinforcementBarPitchOfSlab - Reference: ø300 (schroef)
Component Quantities - WSP_beton - ihwg beton, Mass: 887.213 kg; WSP_beton - ihwg beton, Component Volume (Net): 0.385745 m3; WSP_beton - ihwg beton, Component Volume (Gross): 0.385745 m3
CPset_Phasing - Renovation Phase: Bestaand

# IfcSlab: Slab 396, 17_WSP_FD_beton - fundatiepaal v21-2:ø300 (schroef):1471576
In: -2 fundering
Classification: Vloerplaat - fundering (ARCHICAD Classification); Material: WSP_beton - ihwg beton
Pset_SlabCommon - Reference: ø300 (schroef); IsExternal: yes; LoadBearing: no
Pset_ReinforcementBarPitchOfSlab - Reference: ø300 (schroef)
Component Quantities - WSP_beton - ihwg beton, Mass: 887.213 kg; WSP_beton - ihwg beton, Component Volume (Net): 0.385745 m3; WSP_beton - ihwg beton, Component Volume (Gross): 0.385745 m3
CPset_Phasing - Renovation Phase: Bestaand

# IfcSlab: Slab 397, 17_WSP_FD_beton - fundatiepaal v21-2:ø300 (schroef):1471577
In: -2 fundering
Classification: Vloerplaat - fundering (ARCHICAD Classification); Material: WSP_beton - ihwg beton
Pset_ReinforcementBarPitchOfSlab - Reference: ø300 (schroef)
Pset_SlabCommon - Reference: ø300 (schroef); IsExternal: yes; LoadBearing: no
CPset_Phasing - Renovation Phase: Bestaand
Component Quantities - WSP_beton - ihwg beton, Mass: 887.213 kg; WSP_beton - ihwg beton, Component Volume (Net): 0.385745 m3; WSP_beton - ihwg beton, Component Volume (Gross): 0.385745 m3

# IfcSlab: Slab 398, 17_WSP_FD_beton - fundatiepaal v21-2:ø300 (schroef):1472482
In: -2 fundering
Classification: Vloerplaat - fundering (ARCHICAD Classification); Material: WSP_beton - ihwg beton
Pset_SlabCommon - Reference: ø300 (schroef); IsExternal: yes; LoadBearing: no
Pset_ReinforcementBarPitchOfSlab - Reference: ø300 (schroef)
CPset_Phasing - Renovation Phase: Bestaand
Component Quantities - WSP_beton - ihwg beton, Mass: 903.056 kg; WSP_beton - ihwg beton, Component Volume (Net): 0.392633 m3; WSP_beton - ihwg beton, Component Volume (Gross): 0.392633 m3

# IfcSlab: Slab 399, 17_WSP_FD_beton - fundatiepaal v21-2:ø300 (schroef):1472483
In: -2 fundering
Classification: Vloerplaat - fundering (ARCHICAD Classification); Material: WSP_beton - ihwg beton
Pset_SlabCommon - Reference: ø300 (schroef); IsExternal: yes; LoadBearing: no
Pset_ReinforcementBarPitchOfSlab - Reference: ø300 (schroef)
Component Quantities - WSP_beton - ihwg beton, Mass: 903.056 kg; WSP_beton - ihwg beton, Component Volume (Net): 0.392633 m3; WSP_beton - ihwg beton, Component Volume (Gross): 0.392633 m3
CPset_Phasing - Renovation Phase: Bestaand

# IfcSlab: Slab 4, 17_WSP_FD_beton - fundatiepaal v21-2:ø300 (schroef):1528047
In: -2 fundering
Classification: Vloerplaat - fundering (ARCHICAD Classification); Material: WSP_beton - ihwg beton
Pset_SlabCommon - Reference: ø300 (schroef); IsExternal: yes; LoadBearing: no
Component Quantities - WSP_beton - ihwg beton, Mass: 887.213 kg; WSP_beton - ihwg beton, Component Volume (Net): 0.385745 m3; WSP_beton - ihwg beton, Component Volume (Gross): 0.385745 m3
CPset_Phasing - Renovation Phase: Bestaand
Pset_ReinforcementBarPitchOfSlab - Reference: ø300 (schroef)

# IfcSlab: Slab 40, 17_WSP_FD_beton - fundatiepaal v21-2:ø300 (schroef):1473603
In: -2 fundering
Classification: Vloerplaat - fundering (ARCHICAD Classification); Material: WSP_beton - ihwg beton
Pset_ReinforcementBarPitchOfSlab - Reference: ø300 (schroef)
Component Quantities - WSP_beton - ihwg beton, Mass: 903.056 kg; WSP_beton - ihwg beton, Component Volume (Net): 0.392633 m3; WSP_beton - ihwg beton, Component Volume (Gross): 0.392633 m3
CPset_Phasing - Renovation Phase: Bestaand
Pset_SlabCommon - Reference: ø300 (schroef); IsExternal: yes; LoadBearing: no

# IfcSlab: Slab 400, 17_WSP_FD_beton - fundatiepaal v21-2:ø300 (schroef):1472480
In: -2 fundering
Classification: Vloerplaat - fundering (ARCHICAD Classification); Material: WSP_beton - ihwg beton
Component Quantities - WSP_beton - ihwg beton, Mass: 903.056 kg; WSP_beton - ihwg beton, Component Volume (Net): 0.392633 m3; WSP_beton - ihwg beton, Component Volume (Gross): 0.392633 m3
Pset_ReinforcementBarPitchOfSlab - Reference: ø300 (schroef)
Pset_SlabCommon - Reference: ø300 (schroef); IsExternal: yes; LoadBearing: no
CPset_Phasing - Renovation Phase: Bestaand

# IfcSlab: Slab 401, 17_WSP_FD_beton - fundatiepaal v21-2:ø300 (schroef):1472481
In: -2 fundering
Classification: Vloerplaat - fundering (ARCHICAD Classification); Material: WSP_beton - ihwg beton
Pset_ReinforcementBarPitchOfSlab - Reference: ø300 (schroef)
Component Quantities - WSP_beton - ihwg beton, Mass: 903.056 kg; WSP_beton - ihwg beton, Component Volume (Net): 0.392633 m3; WSP_beton - ihwg beton, Component Volume (Gross): 0.392633 m3
CPset_Phasing - Renovation Phase: Bestaand
Pset_SlabCommon - Reference: ø300 (schroef); IsExternal: yes; LoadBearing: no

# IfcSlab: Slab 402, 17_WSP_FD_beton - fundatiepaal v21-2:ø300 (schroef):1472486
In: -2 fundering
Classification: Vloerplaat - fundering (ARCHICAD Classification); Material: WSP_beton - ihwg beton
Pset_SlabCommon - Reference: ø300 (schroef); IsExternal: yes; LoadBearing: no
Pset_ReinforcementBarPitchOfSlab - Reference: ø300 (schroef)
Component Quantities - WSP_beton - ihwg beton, Mass: 903.056 kg; WSP_beton - ihwg beton, Component Volume (Net): 0.392633 m3; WSP_beton - ihwg beton, Component Volume (Gross): 0.392633 m3
CPset_Phasing - Renovation Phase: Bestaand

# IfcSlab: Slab 403, 17_WSP_FD_beton - fundatiepaal v21-2:ø300 (schroef):1472487
In: -2 fundering
Classification: Vloerplaat - fundering (ARCHICAD Classification); Material: WSP_beton - ihwg beton
Pset_SlabCommon - Reference: ø300 (schroef); IsExternal: yes; LoadBearing: no
Pset_ReinforcementBarPitchOfSlab - Reference: ø300 (schroef)
CPset_Phasing - Renovation Phase: Bestaand
Component Quantities - WSP_beton - ihwg beton, Mass: 903.056 kg; WSP_beton - ihwg beton, Component Volume (Net): 0.392633 m3; WSP_beton - ihwg beton, Component Volume (Gross): 0.392633 m3

# IfcSlab: Slab 404, 17_WSP_FD_beton - fundatiepaal v21-2:ø300 (schroef):1472484
In: -2 fundering
Classification: Vloerplaat - fundering (ARCHICAD Classification); Material: WSP_beton - ihwg beton
Pset_SlabCommon - Reference: ø300 (schroef); IsExternal: yes; LoadBearing: no
Pset_ReinforcementBarPitchOfSlab - Reference: ø300 (schroef)
CPset_Phasing - Renovation Phase: Bestaand
Component Quantities - WSP_beton - ihwg beton, Mass: 903.056 kg; WSP_beton - ihwg beton, Component Volume (Net): 0.392633 m3; WSP_beton - ihwg beton, Component Volume (Gross): 0.392633 m3

# IfcSlab: Slab 405, 17_WSP_FD_beton - fundatiepaal v21-2:ø300 (schroef):1472485
In: -2 fundering
Classification: Vloerplaat - fundering (ARCHICAD Classification); Material: WSP_beton - ihwg beton
CPset_Phasing - Renovation Phase: Bestaand
Component Quantities - WSP_beton - ihwg beton, Mass: 903.056 kg; WSP_beton - ihwg beton, Component Volume (Net): 0.392633 m3; WSP_beton - ihwg beton, Component Volume (Gross): 0.392633 m3
Pset_ReinforcementBarPitchOfSlab - Reference: ø300 (schroef)
Pset_SlabCommon - Reference: ø300 (schroef); IsExternal: yes; LoadBearing: no

# IfcSlab: Slab 406, 17_WSP_FD_beton - fundatiepaal v21-2:ø300 (schroef):1472490
In: -2 fundering
Classification: Vloerplaat - fundering (ARCHICAD Classification); Material: WSP_beton - ihwg beton
Pset_ReinforcementBarPitchOfSlab - Reference: ø300 (schroef)
Pset_SlabCommon - Reference: ø300 (schroef); IsExternal: yes; LoadBearing: no
CPset_Phasing - Renovation Phase: Bestaand
Component Quantities - WSP_beton - ihwg beton, Mass: 903.056 kg; WSP_beton - ihwg beton, Component Volume (Net): 0.392633 m3; WSP_beton - ihwg beton, Component Volume (Gross): 0.392633 m3

# IfcSlab: Slab 407, 17_WSP_FD_beton - fundatiepaal v21-2:ø300 (schroef):1472491
In: -2 fundering
Classification: Vloerplaat - fundering (ARCHICAD Classification); Material: WSP_beton - ihwg beton
Pset_SlabCommon - Reference: ø300 (schroef); IsExternal: yes; LoadBearing: no
Pset_ReinforcementBarPitchOfSlab - Reference: ø300 (schroef)
CPset_Phasing - Renovation Phase: Bestaand
Component Quantities - WSP_beton - ihwg beton, Mass: 903.056 kg; WSP_beton - ihwg beton, Component Volume (Net): 0.392633 m3; WSP_beton - ihwg beton, Component Volume (Gross): 0.392633 m3

# IfcSlab: Slab 408, 17_WSP_FD_beton - fundatiepaal v21-2:ø300 (schroef):1472488
In: -2 fundering
Classification: Vloerplaat - fundering (ARCHICAD Classification); Material: WSP_beton - ihwg beton
Pset_SlabCommon - Reference: ø300 (schroef); IsExternal: yes; LoadBearing: no
Pset_ReinforcementBarPitchOfSlab - Reference: ø300 (schroef)
CPset_Phasing - Renovation Phase: Bestaand
Component Quantities - WSP_beton - ihwg beton, Mass: 903.056 kg; WSP_beton - ihwg beton, Component Volume (Net): 0.392633 m3; WSP_beton - ihwg beton, Component Volume (Gross): 0.392633 m3

# IfcSlab: Slab 409, 17_WSP_FD_beton - fundatiepaal v21-2:ø300 (schroef):1472489
In: -2 fundering
Classification: Vloerplaat - fundering (ARCHICAD Classification); Material: WSP_beton - ihwg beton
Pset_SlabCommon - Reference: ø300 (schroef); IsExternal: yes; LoadBearing: no
Pset_ReinforcementBarPitchOfSlab - Reference: ø300 (schroef)
Component Quantities - WSP_beton - ihwg beton, Mass: 903.056 kg; WSP_beton - ihwg beton, Component Volume (Net): 0.392633 m3; WSP_beton - ihwg beton, Component Volume (Gross): 0.392633 m3
CPset_Phasing - Renovation Phase: Bestaand

# IfcSlab: Slab 41, 17_WSP_FD_beton - fundatiepaal v21-2:ø300 (schroef):1473600
In: -2 fundering
Classification: Vloerplaat - fundering (ARCHICAD Classification); Material: WSP_beton - ihwg beton
Pset_SlabCommon - Reference: ø300 (schroef); IsExternal: yes; LoadBearing: no
Pset_ReinforcementBarPitchOfSlab - Reference: ø300 (schroef)
CPset_Phasing - Renovation Phase: Bestaand
Component Quantities - WSP_beton - ihwg beton, Mass: 903.056 kg; WSP_beton - ihwg beton, Component Volume (Net): 0.392633 m3; WSP_beton - ihwg beton, Component Volume (Gross): 0.392633 m3

# IfcSlab: Slab 410, 17_WSP_FD_beton - fundatiepaal v21-2:ø300 (schroef):1472494
In: -2 fundering
Classification: Vloerplaat - fundering (ARCHICAD Classification); Material: WSP_beton - ihwg beton
Pset_ReinforcementBarPitchOfSlab - Reference: ø300 (schroef)
CPset_Phasing - Renovation Phase: Bestaand
Component Quantities - WSP_beton - ihwg beton, Mass: 903.056 kg; WSP_beton - ihwg beton, Component Volume (Net): 0.392633 m3; WSP_beton - ihwg beton, Component Volume (Gross): 0.392633 m3
Pset_SlabCommon - Reference: ø300 (schroef); IsExternal: yes; LoadBearing: no

# IfcSlab: Slab 411, 17_WSP_FD_beton - fundatiepaal v21-2:ø300 (schroef):1472495
In: -2 fundering
Classification: Vloerplaat - fundering (ARCHICAD Classification); Material: WSP_beton - ihwg beton
Pset_ReinforcementBarPitchOfSlab - Reference: ø300 (schroef)
CPset_Phasing - Renovation Phase: Bestaand
Pset_SlabCommon - Reference: ø300 (schroef); IsExternal: yes; LoadBearing: no
Component Quantities - WSP_beton - ihwg beton, Mass: 903.056 kg; WSP_beton - ihwg beton, Component Volume (Net): 0.392633 m3; WSP_beton - ihwg beton, Component Volume (Gross): 0.392633 m3

# IfcSlab: Slab 412, 17_WSP_FD_beton - fundatiepaal v21-2:ø300 (schroef):1472492
In: -2 fundering
Classification: Vloerplaat - fundering (ARCHICAD Classification); Material: WSP_beton - ihwg beton
Pset_ReinforcementBarPitchOfSlab - Reference: ø300 (schroef)
CPset_Phasing - Renovation Phase: Bestaand
Pset_SlabCommon - Reference: ø300 (schroef); IsExternal: yes; LoadBearing: no
Component Quantities - WSP_beton - ihwg beton, Mass: 903.056 kg; WSP_beton - ihwg beton, Component Volume (Net): 0.392633 m3; WSP_beton - ihwg beton, Component Volume (Gross): 0.392633 m3

# IfcSlab: Slab 413, 17_WSP_FD_beton - fundatiepaal v21-2:ø300 (schroef):1472493
In: -2 fundering
Classification: Vloerplaat - fundering (ARCHICAD Classification); Material: WSP_beton - ihwg beton
Pset_ReinforcementBarPitchOfSlab - Reference: ø300 (schroef)
Pset_SlabCommon - Reference: ø300 (schroef); IsExternal: yes; LoadBearing: no
CPset_Phasing - Renovation Phase: Bestaand
Component Quantities - WSP_beton - ihwg beton, Mass: 903.056 kg; WSP_beton - ihwg beton, Component Volume (Net): 0.392633 m3; WSP_beton - ihwg beton, Component Volume (Gross): 0.392633 m3

# IfcSlab: Slab 414, 17_WSP_FD_beton - fundatiepaal v21-2:ø300 (schroef):1472498
In: -2 fundering
Classification: Vloerplaat - fundering (ARCHICAD Classification); Material: WSP_beton - ihwg beton
Pset_SlabCommon - Reference: ø300 (schroef); IsExternal: yes; LoadBearing: no
Pset_ReinforcementBarPitchOfSlab - Reference: ø300 (schroef)
CPset_Phasing - Renovation Phase: Bestaand
Component Quantities - WSP_beton - ihwg beton, Mass: 903.056 kg; WSP_beton - ihwg beton, Component Volume (Net): 0.392633 m3; WSP_beton - ihwg beton, Component Volume (Gross): 0.392633 m3

# IfcSlab: Slab 415, 17_WSP_FD_beton - fundatiepaal v21-2:ø300 (schroef):1472499
In: -2 fundering
Classification: Vloerplaat - fundering (ARCHICAD Classification); Material: WSP_beton - ihwg beton
Pset_ReinforcementBarPitchOfSlab - Reference: ø300 (schroef)
CPset_Phasing - Renovation Phase: Bestaand
Pset_SlabCommon - Reference: ø300 (schroef); IsExternal: yes; LoadBearing: no
Component Quantities - WSP_beton - ihwg beton, Mass: 903.056 kg; WSP_beton - ihwg beton, Component Volume (Net): 0.392633 m3; WSP_beton - ihwg beton, Component Volume (Gross): 0.392633 m3

# IfcSlab: Slab 416, 17_WSP_FD_beton - fundatiepaal v21-2:ø300 (schroef):1472496
In: -2 fundering
Classification: Vloerplaat - fundering (ARCHICAD Classification); Material: WSP_beton - ihwg beton
Pset_SlabCommon - Reference: ø300 (schroef); IsExternal: yes; LoadBearing: no
Pset_ReinforcementBarPitchOfSlab - Reference: ø300 (schroef)
CPset_Phasing - Renovation Phase: Bestaand
Component Quantities - WSP_beton - ihwg beton, Mass: 903.056 kg; WSP_beton - ihwg beton, Component Volume (Net): 0.392633 m3; WSP_beton - ihwg beton, Component Volume (Gross): 0.392633 m3

# IfcSlab: Slab 417, 17_WSP_FD_beton - fundatiepaal v21-2:ø300 (schroef):1472497
In: -2 fundering
Classification: Vloerplaat - fundering (ARCHICAD Classification); Material: WSP_beton - ihwg beton
Pset_SlabCommon - Reference: ø300 (schroef); IsExternal: yes; LoadBearing: no
Component Quantities - WSP_beton - ihwg beton, Mass: 903.056 kg; WSP_beton - ihwg beton, Component Volume (Net): 0.392633 m3; WSP_beton - ihwg beton, Component Volume (Gross): 0.392633 m3
Pset_ReinforcementBarPitchOfSlab - Reference: ø300 (schroef)
CPset_Phasing - Renovation Phase: Bestaand

# IfcSlab: Slab 418, 17_WSP_FD_beton - fundatiepaal v21-2:ø300 (schroef):1472502
In: -2 fundering
Classification: Vloerplaat - fundering (ARCHICAD Classification); Material: WSP_beton - ihwg beton
Pset_ReinforcementBarPitchOfSlab - Reference: ø300 (schroef)
Component Quantities - WSP_beton - ihwg beton, Mass: 903.056 kg; WSP_beton - ihwg beton, Component Volume (Net): 0.392633 m3; WSP_beton - ihwg beton, Component Volume (Gross): 0.392633 m3
Pset_SlabCommon - Reference: ø300 (schroef); IsExternal: yes; LoadBearing: no
CPset_Phasing - Renovation Phase: Bestaand

# IfcSlab: Slab 419, 17_WSP_FD_beton - fundatiepaal v21-2:ø300 (schroef):1472503
In: -2 fundering
Classification: Vloerplaat - fundering (ARCHICAD Classification); Material: WSP_beton - ihwg beton
Pset_SlabCommon - Reference: ø300 (schroef); IsExternal: yes; LoadBearing: no
Pset_ReinforcementBarPitchOfSlab - Reference: ø300 (schroef)
CPset_Phasing - Renovation Phase: Bestaand
Component Quantities - WSP_beton - ihwg beton, Mass: 903.056 kg; WSP_beton - ihwg beton, Component Volume (Net): 0.392633 m3; WSP_beton - ihwg beton, Component Volume (Gross): 0.392633 m3

# IfcSlab: Slab 42, 17_WSP_FD_beton - fundatiepaal v21-2:ø300 (schroef):1473601
In: -2 fundering
Classification: Vloerplaat - fundering (ARCHICAD Classification); Material: WSP_beton - ihwg beton
CPset_Phasing - Renovation Phase: Bestaand
Component Quantities - WSP_beton - ihwg beton, Mass: 903.056 kg; WSP_beton - ihwg beton, Component Volume (Net): 0.392633 m3; WSP_beton - ihwg beton, Component Volume (Gross): 0.392633 m3
Pset_ReinforcementBarPitchOfSlab - Reference: ø300 (schroef)
Pset_SlabCommon - Reference: ø300 (schroef); IsExternal: yes; LoadBearing: no

# IfcSlab: Slab 420, 17_WSP_FD_beton - fundatiepaal v21-2:ø300 (schroef):1472500
In: -2 fundering
Classification: Vloerplaat - fundering (ARCHICAD Classification); Material: WSP_beton - ihwg beton
Component Quantities - WSP_beton - ihwg beton, Mass: 903.056 kg; WSP_beton - ihwg beton, Component Volume (Net): 0.392633 m3; WSP_beton - ihwg beton, Component Volume (Gross): 0.392633 m3
CPset_Phasing - Renovation Phase: Bestaand
Pset_ReinforcementBarPitchOfSlab - Reference: ø300 (schroef)
Pset_SlabCommon - Reference: ø300 (schroef); IsExternal: yes; LoadBearing: no

# IfcSlab: Slab 421, 17_WSP_FD_beton - fundatiepaal v21-2:ø300 (schroef):1472501
In: -2 fundering
Classification: Vloerplaat - fundering (ARCHICAD Classification); Material: WSP_beton - ihwg beton
Pset_SlabCommon - Reference: ø300 (schroef); IsExternal: yes; LoadBearing: no
Pset_ReinforcementBarPitchOfSlab - Reference: ø300 (schroef)
Component Quantities - WSP_beton - ihwg beton, Mass: 903.056 kg; WSP_beton - ihwg beton, Component Volume (Net): 0.392633 m3; WSP_beton - ihwg beton, Component Volume (Gross): 0.392633 m3
CPset_Phasing - Renovation Phase: Bestaand

# IfcSlab: Slab 422, 17_WSP_FD_beton - fundatiepaal v21-2:ø300 (schroef):1472506
In: -2 fundering
Classification: Vloerplaat - fundering (ARCHICAD Classification); Material: WSP_beton - ihwg beton
Pset_SlabCommon - Reference: ø300 (schroef); IsExternal: yes; LoadBearing: no
Pset_ReinforcementBarPitchOfSlab - Reference: ø300 (schroef)
Component Quantities - WSP_beton - ihwg beton, Mass: 903.056 kg; WSP_beton - ihwg beton, Component Volume (Net): 0.392633 m3; WSP_beton - ihwg beton, Component Volume (Gross): 0.392633 m3
CPset_Phasing - Renovation Phase: Bestaand

# IfcSlab: Slab 423, 17_WSP_FD_beton - fundatiepaal v21-2:ø300 (schroef):1472507
In: -2 fundering
Classification: Vloerplaat - fundering (ARCHICAD Classification); Material: WSP_beton - ihwg beton
Pset_SlabCommon - Reference: ø300 (schroef); IsExternal: yes; LoadBearing: no
CPset_Phasing - Renovation Phase: Bestaand
Component Quantities - WSP_beton - ihwg beton, Mass: 903.056 kg; WSP_beton - ihwg beton, Component Volume (Net): 0.392633 m3; WSP_beton - ihwg beton, Component Volume (Gross): 0.392633 m3
Pset_ReinforcementBarPitchOfSlab - Reference: ø300 (schroef)

# IfcSlab: Slab 424, 17_WSP_FD_beton - fundatiepaal v21-2:ø300 (schroef):1472504
In: -2 fundering
Classification: Vloerplaat - fundering (ARCHICAD Classification); Material: WSP_beton - ihwg beton
Pset_ReinforcementBarPitchOfSlab - Reference: ø300 (schroef)
Pset_SlabCommon - Reference: ø300 (schroef); IsExternal: yes; LoadBearing: no
CPset_Phasing - Renovation Phase: Bestaand
Component Quantities - WSP_beton - ihwg beton, Mass: 903.056 kg; WSP_beton - ihwg beton, Component Volume (Net): 0.392633 m3; WSP_beton - ihwg beton, Component Volume (Gross): 0.392633 m3

# IfcSlab: Slab 425, 17_WSP_FD_beton - fundatiepaal v21-2:ø300 (schroef):1472505
In: -2 fundering
Classification: Vloerplaat - fundering (ARCHICAD Classification); Material: WSP_beton - ihwg beton
Pset_SlabCommon - Reference: ø300 (schroef); IsExternal: yes; LoadBearing: no
CPset_Phasing - Renovation Phase: Bestaand
Pset_ReinforcementBarPitchOfSlab - Reference: ø300 (schroef)
Component Quantities - WSP_beton - ihwg beton, Mass: 903.056 kg; WSP_beton - ihwg beton, Component Volume (Net): 0.392633 m3; WSP_beton - ihwg beton, Component Volume (Gross): 0.392633 m3

# IfcSlab: Slab 426, 17_WSP_FD_beton - fundatiepaal v21-2:ø300 (schroef):1472510
In: -2 fundering
Classification: Vloerplaat - fundering (ARCHICAD Classification); Material: WSP_beton - ihwg beton
Pset_SlabCommon - Reference: ø300 (schroef); IsExternal: yes; LoadBearing: no
Pset_ReinforcementBarPitchOfSlab - Reference: ø300 (schroef)
Component Quantities - WSP_beton - ihwg beton, Mass: 903.056 kg; WSP_beton - ihwg beton, Component Volume (Net): 0.392633 m3; WSP_beton - ihwg beton, Component Volume (Gross): 0.392633 m3
CPset_Phasing - Renovation Phase: Bestaand

# IfcSlab: Slab 427, 17_WSP_FD_beton - fundatiepaal v21-2:ø300 (schroef):1472511
In: -2 fundering
Classification: Vloerplaat - fundering (ARCHICAD Classification); Material: WSP_beton - ihwg beton
Pset_ReinforcementBarPitchOfSlab - Reference: ø300 (schroef)
CPset_Phasing - Renovation Phase: Bestaand
Pset_SlabCommon - Reference: ø300 (schroef); IsExternal: yes; LoadBearing: no
Component Quantities - WSP_beton - ihwg beton, Mass: 903.056 kg; WSP_beton - ihwg beton, Component Volume (Net): 0.392633 m3; WSP_beton - ihwg beton, Component Volume (Gross): 0.392633 m3

# IfcSlab: Slab 428, 17_WSP_FD_beton - fundatiepaal v21-2:ø300 (schroef):1472508
In: -2 fundering
Classification: Vloerplaat - fundering (ARCHICAD Classification); Material: WSP_beton - ihwg beton
Pset_SlabCommon - Reference: ø300 (schroef); IsExternal: yes; LoadBearing: no
Pset_ReinforcementBarPitchOfSlab - Reference: ø300 (schroef)
Component Quantities - WSP_beton - ihwg beton, Mass: 903.056 kg; WSP_beton - ihwg beton, Component Volume (Net): 0.392633 m3; WSP_beton - ihwg beton, Component Volume (Gross): 0.392633 m3
CPset_Phasing - Renovation Phase: Bestaand

# IfcSlab: Slab 429, 17_WSP_FD_beton - fundatiepaal v21-2:ø300 (schroef):1472509
In: -2 fundering
Classification: Vloerplaat - fundering (ARCHICAD Classification); Material: WSP_beton - ihwg beton
Pset_SlabCommon - Reference: ø300 (schroef); IsExternal: yes; LoadBearing: no
Component Quantities - WSP_beton - ihwg beton, Mass: 903.056 kg; WSP_beton - ihwg beton, Component Volume (Net): 0.392633 m3; WSP_beton - ihwg beton, Component Volume (Gross): 0.392633 m3
CPset_Phasing - Renovation Phase: Bestaand
Pset_ReinforcementBarPitchOfSlab - Reference: ø300 (schroef)

# IfcSlab: Slab 43, 17_WSP_FD_beton - fundatiepaal v21-2:ø300 (schroef):1473606
In: -2 fundering
Classification: Vloerplaat - fundering (ARCHICAD Classification); Material: WSP_beton - ihwg beton
Pset_SlabCommon - Reference: ø300 (schroef); IsExternal: yes; LoadBearing: no
Pset_ReinforcementBarPitchOfSlab - Reference: ø300 (schroef)
Component Quantities - WSP_beton - ihwg beton, Mass: 903.056 kg; WSP_beton - ihwg beton, Component Volume (Net): 0.392633 m3; WSP_beton - ihwg beton, Component Volume (Gross): 0.392633 m3
CPset_Phasing - Renovation Phase: Bestaand

# IfcSlab: Slab 430, 17_WSP_FD_beton - fundatiepaal v21-2:ø300 (schroef):1472450
In: -2 fundering
Classification: Vloerplaat - fundering (ARCHICAD Classification); Material: WSP_beton - ihwg beton
Component Quantities - WSP_beton - ihwg beton, Mass: 903.056 kg; WSP_beton - ihwg beton, Component Volume (Net): 0.392633 m3; WSP_beton - ihwg beton, Component Volume (Gross): 0.392633 m3
CPset_Phasing - Renovation Phase: Bestaand
Pset_ReinforcementBarPitchOfSlab - Reference: ø300 (schroef)
Pset_SlabCommon - Reference: ø300 (schroef); IsExternal: yes; LoadBearing: no

# IfcSlab: Slab 431, 17_WSP_FD_beton - fundatiepaal v21-2:ø300 (schroef):1472451
In: -2 fundering
Classification: Vloerplaat - fundering (ARCHICAD Classification); Material: WSP_beton - ihwg beton
CPset_Phasing - Renovation Phase: Bestaand
Pset_ReinforcementBarPitchOfSlab - Reference: ø300 (schroef)
Pset_SlabCommon - Reference: ø300 (schroef); IsExternal: yes; LoadBearing: no
Component Quantities - WSP_beton - ihwg beton, Mass: 903.056 kg; WSP_beton - ihwg beton, Component Volume (Net): 0.392633 m3; WSP_beton - ihwg beton, Component Volume (Gross): 0.392633 m3

# IfcSlab: Slab 432, 17_WSP_FD_beton - fundatiepaal v21-2:ø300 (schroef):1472448
In: -2 fundering
Classification: Vloerplaat - fundering (ARCHICAD Classification); Material: WSP_beton - ihwg beton
Pset_ReinforcementBarPitchOfSlab - Reference: ø300 (schroef)
Pset_SlabCommon - Reference: ø300 (schroef); IsExternal: yes; LoadBearing: no
Component Quantities - WSP_beton - ihwg beton, Mass: 903.056 kg; WSP_beton - ihwg beton, Component Volume (Net): 0.392633 m3; WSP_beton - ihwg beton, Component Volume (Gross): 0.392633 m3
CPset_Phasing - Renovation Phase: Bestaand

# IfcSlab: Slab 433, 17_WSP_FD_beton - fundatiepaal v21-2:ø300 (schroef):1472449
In: -2 fundering
Classification: Vloerplaat - fundering (ARCHICAD Classification); Material: WSP_beton - ihwg beton
Pset_SlabCommon - Reference: ø300 (schroef); IsExternal: yes; LoadBearing: no
Component Quantities - WSP_beton - ihwg beton, Mass: 903.056 kg; WSP_beton - ihwg beton, Component Volume (Net): 0.392633 m3; WSP_beton - ihwg beton, Component Volume (Gross): 0.392633 m3
Pset_ReinforcementBarPitchOfSlab - Reference: ø300 (schroef)
CPset_Phasing - Renovation Phase: Bestaand

# IfcSlab: Slab 434, 17_WSP_FD_beton - fundatiepaal v21-2:ø300 (schroef):1472454
In: -2 fundering
Classification: Vloerplaat - fundering (ARCHICAD Classification); Material: WSP_beton - ihwg beton
Pset_SlabCommon - Reference: ø300 (schroef); IsExternal: yes; LoadBearing: no
Pset_ReinforcementBarPitchOfSlab - Reference: ø300 (schroef)
Component Quantities - WSP_beton - ihwg beton, Mass: 903.056 kg; WSP_beton - ihwg beton, Component Volume (Net): 0.392633 m3; WSP_beton - ihwg beton, Component Volume (Gross): 0.392633 m3
CPset_Phasing - Renovation Phase: Bestaand

# IfcSlab: Slab 435, 17_WSP_FD_beton - fundatiepaal v21-2:ø300 (schroef):1472455
In: -2 fundering
Classification: Vloerplaat - fundering (ARCHICAD Classification); Material: WSP_beton - ihwg beton
CPset_Phasing - Renovation Phase: Bestaand
Component Quantities - WSP_beton - ihwg beton, Mass: 903.056 kg; WSP_beton - ihwg beton, Component Volume (Net): 0.392633 m3; WSP_beton - ihwg beton, Component Volume (Gross): 0.392633 m3
Pset_SlabCommon - Reference: ø300 (schroef); IsExternal: yes; LoadBearing: no
Pset_ReinforcementBarPitchOfSlab - Reference: ø300 (schroef)

# IfcSlab: Slab 436, 17_WSP_FD_beton - fundatiepaal v21-2:ø300 (schroef):1472452
In: -2 fundering
Classification: Vloerplaat - fundering (ARCHICAD Classification); Material: WSP_beton - ihwg beton
Pset_SlabCommon - Reference: ø300 (schroef); IsExternal: yes; LoadBearing: no
CPset_Phasing - Renovation Phase: Bestaand
Pset_ReinforcementBarPitchOfSlab - Reference: ø300 (schroef)
Component Quantities - WSP_beton - ihwg beton, Mass: 903.056 kg; WSP_beton - ihwg beton, Component Volume (Net): 0.392633 m3; WSP_beton - ihwg beton, Component Volume (Gross): 0.392633 m3

# IfcSlab: Slab 437, 17_WSP_FD_beton - fundatiepaal v21-2:ø300 (schroef):1472453
In: -2 fundering
Classification: Vloerplaat - fundering (ARCHICAD Classification); Material: WSP_beton - ihwg beton
Pset_ReinforcementBarPitchOfSlab - Reference: ø300 (schroef)
Pset_SlabCommon - Reference: ø300 (schroef); IsExternal: yes; LoadBearing: no
Component Quantities - WSP_beton - ihwg beton, Mass: 903.056 kg; WSP_beton - ihwg beton, Component Volume (Net): 0.392633 m3; WSP_beton - ihwg beton, Component Volume (Gross): 0.392633 m3
CPset_Phasing - Renovation Phase: Bestaand

# IfcSlab: Slab 438, 17_WSP_FD_beton - fundatiepaal v21-2:ø300 (schroef):1472458
In: -2 fundering
Classification: Vloerplaat - fundering (ARCHICAD Classification); Material: WSP_beton - ihwg beton
Pset_SlabCommon - Reference: ø300 (schroef); IsExternal: yes; LoadBearing: no
Pset_ReinforcementBarPitchOfSlab - Reference: ø300 (schroef)
Component Quantities - WSP_beton - ihwg beton, Mass: 903.056 kg; WSP_beton - ihwg beton, Component Volume (Net): 0.392633 m3; WSP_beton - ihwg beton, Component Volume (Gross): 0.392633 m3
CPset_Phasing - Renovation Phase: Bestaand

# IfcSlab: Slab 439, 17_WSP_FD_beton - fundatiepaal v21-2:ø300 (schroef):1472459
In: -2 fundering
Classification: Vloerplaat - fundering (ARCHICAD Classification); Material: WSP_beton - ihwg beton
Pset_ReinforcementBarPitchOfSlab - Reference: ø300 (schroef)
Pset_SlabCommon - Reference: ø300 (schroef); IsExternal: yes; LoadBearing: no
CPset_Phasing - Renovation Phase: Bestaand
Component Quantities - WSP_beton - ihwg beton, Mass: 903.056 kg; WSP_beton - ihwg beton, Component Volume (Net): 0.392633 m3; WSP_beton - ihwg beton, Component Volume (Gross): 0.392633 m3

# IfcSlab: Slab 44, 17_WSP_FD_beton - fundatiepaal v21-2:ø300 (schroef):1473607
In: -2 fundering
Classification: Vloerplaat - fundering (ARCHICAD Classification); Material: WSP_beton - ihwg beton
Pset_SlabCommon - Reference: ø300 (schroef); IsExternal: yes; LoadBearing: no
CPset_Phasing - Renovation Phase: Bestaand
Pset_ReinforcementBarPitchOfSlab - Reference: ø300 (schroef)
Component Quantities - WSP_beton - ihwg beton, Mass: 903.056 kg; WSP_beton - ihwg beton, Component Volume (Net): 0.392633 m3; WSP_beton - ihwg beton, Component Volume (Gross): 0.392633 m3

# IfcSlab: Slab 440, 17_WSP_FD_beton - fundatiepaal v21-2:ø300 (schroef):1472456
In: -2 fundering
Classification: Vloerplaat - fundering (ARCHICAD Classification); Material: WSP_beton - ihwg beton
Pset_ReinforcementBarPitchOfSlab - Reference: ø300 (schroef)
Pset_SlabCommon - Reference: ø300 (schroef); IsExternal: yes; LoadBearing: no
Component Quantities - WSP_beton - ihwg beton, Mass: 903.056 kg; WSP_beton - ihwg beton, Component Volume (Net): 0.392633 m3; WSP_beton - ihwg beton, Component Volume (Gross): 0.392633 m3
CPset_Phasing - Renovation Phase: Bestaand

# IfcSlab: Slab 441, 17_WSP_FD_beton - fundatiepaal v21-2:ø300 (schroef):1472457
In: -2 fundering
Classification: Vloerplaat - fundering (ARCHICAD Classification); Material: WSP_beton - ihwg beton
Pset_SlabCommon - Reference: ø300 (schroef); IsExternal: yes; LoadBearing: no
Pset_ReinforcementBarPitchOfSlab - Reference: ø300 (schroef)
CPset_Phasing - Renovation Phase: Bestaand
Component Quantities - WSP_beton - ihwg beton, Mass: 903.056 kg; WSP_beton - ihwg beton, Component Volume (Net): 0.392633 m3; WSP_beton - ihwg beton, Component Volume (Gross): 0.392633 m3

# IfcSlab: Slab 442, 17_WSP_FD_beton - fundatiepaal v21-2:ø300 (schroef):1472462
In: -2 fundering
Classification: Vloerplaat - fundering (ARCHICAD Classification); Material: WSP_beton - ihwg beton
Pset_ReinforcementBarPitchOfSlab - Reference: ø300 (schroef)
Pset_SlabCommon - Reference: ø300 (schroef); IsExternal: yes; LoadBearing: no
CPset_Phasing - Renovation Phase: Bestaand
Component Quantities - WSP_beton - ihwg beton, Mass: 903.056 kg; WSP_beton - ihwg beton, Component Volume (Net): 0.392633 m3; WSP_beton - ihwg beton, Component Volume (Gross): 0.392633 m3

# IfcSlab: Slab 443, 17_WSP_FD_beton - fundatiepaal v21-2:ø300 (schroef):1472463
In: -2 fundering
Classification: Vloerplaat - fundering (ARCHICAD Classification); Material: WSP_beton - ihwg beton
Pset_ReinforcementBarPitchOfSlab - Reference: ø300 (schroef)
Pset_SlabCommon - Reference: ø300 (schroef); IsExternal: yes; LoadBearing: no
CPset_Phasing - Renovation Phase: Bestaand
Component Quantities - WSP_beton - ihwg beton, Mass: 903.056 kg; WSP_beton - ihwg beton, Component Volume (Net): 0.392633 m3; WSP_beton - ihwg beton, Component Volume (Gross): 0.392633 m3

# IfcSlab: Slab 444, 17_WSP_FD_beton - fundatiepaal v21-2:ø300 (schroef):1472460
In: -2 fundering
Classification: Vloerplaat - fundering (ARCHICAD Classification); Material: WSP_beton - ihwg beton
Pset_ReinforcementBarPitchOfSlab - Reference: ø300 (schroef)
Pset_SlabCommon - Reference: ø300 (schroef); IsExternal: yes; LoadBearing: no
CPset_Phasing - Renovation Phase: Bestaand
Component Quantities - WSP_beton - ihwg beton, Mass: 903.056 kg; WSP_beton - ihwg beton, Component Volume (Net): 0.392633 m3; WSP_beton - ihwg beton, Component Volume (Gross): 0.392633 m3

# IfcSlab: Slab 445, 17_WSP_FD_beton - fundatiepaal v21-2:ø300 (schroef):1472461
In: -2 fundering
Classification: Vloerplaat - fundering (ARCHICAD Classification); Material: WSP_beton - ihwg beton
Pset_SlabCommon - Reference: ø300 (schroef); IsExternal: yes; LoadBearing: no
Pset_ReinforcementBarPitchOfSlab - Reference: ø300 (schroef)
Component Quantities - WSP_beton - ihwg beton, Mass: 903.056 kg; WSP_beton - ihwg beton, Component Volume (Net): 0.392633 m3; WSP_beton - ihwg beton, Component Volume (Gross): 0.392633 m3
CPset_Phasing - Renovation Phase: Bestaand

# IfcSlab: Slab 446, 17_WSP_FD_beton - fundatiepaal v21-2:ø300 (schroef):1472466
In: -2 fundering
Classification: Vloerplaat - fundering (ARCHICAD Classification); Material: WSP_beton - ihwg beton
Pset_SlabCommon - Reference: ø300 (schroef); IsExternal: yes; LoadBearing: no
Component Quantities - WSP_beton - ihwg beton, Mass: 903.056 kg; WSP_beton - ihwg beton, Component Volume (Net): 0.392633 m3; WSP_beton - ihwg beton, Component Volume (Gross): 0.392633 m3
CPset_Phasing - Renovation Phase: Bestaand
Pset_ReinforcementBarPitchOfSlab - Reference: ø300 (schroef)

# IfcSlab: Slab 447, 17_WSP_FD_beton - fundatiepaal v21-2:ø300 (schroef):1472467
In: -2 fundering
Classification: Vloerplaat - fundering (ARCHICAD Classification); Material: WSP_beton - ihwg beton
Pset_SlabCommon - Reference: ø300 (schroef); IsExternal: yes; LoadBearing: no
CPset_Phasing - Renovation Phase: Bestaand
Component Quantities - WSP_beton - ihwg beton, Mass: 903.056 kg; WSP_beton - ihwg beton, Component Volume (Net): 0.392633 m3; WSP_beton - ihwg beton, Component Volume (Gross): 0.392633 m3
Pset_ReinforcementBarPitchOfSlab - Reference: ø300 (schroef)

# IfcSlab: Slab 448, 17_WSP_FD_beton - fundatiepaal v21-2:ø300 (schroef):1472464
In: -2 fundering
Classification: Vloerplaat - fundering (ARCHICAD Classification); Material: WSP_beton - ihwg beton
Pset_SlabCommon - Reference: ø300 (schroef); IsExternal: yes; LoadBearing: no
Pset_ReinforcementBarPitchOfSlab - Reference: ø300 (schroef)
CPset_Phasing - Renovation Phase: Bestaand
Component Quantities - WSP_beton - ihwg beton, Mass: 903.056 kg; WSP_beton - ihwg beton, Component Volume (Net): 0.392633 m3; WSP_beton - ihwg beton, Component Volume (Gross): 0.392633 m3

# IfcSlab: Slab 449, 17_WSP_FD_beton - fundatiepaal v21-2:ø300 (schroef):1472465
In: -2 fundering
Classification: Vloerplaat - fundering (ARCHICAD Classification); Material: WSP_beton - ihwg beton
CPset_Phasing - Renovation Phase: Bestaand
Pset_SlabCommon - Reference: ø300 (schroef); IsExternal: yes; LoadBearing: no
Pset_ReinforcementBarPitchOfSlab - Reference: ø300 (schroef)
Component Quantities - WSP_beton - ihwg beton, Mass: 903.056 kg; WSP_beton - ihwg beton, Component Volume (Net): 0.392633 m3; WSP_beton - ihwg beton, Component Volume (Gross): 0.392633 m3

# IfcSlab: Slab 45, 17_WSP_FD_beton - fundatiepaal v21-2:ø300 (schroef):1473604
In: -2 fundering
Classification: Vloerplaat - fundering (ARCHICAD Classification); Material: WSP_beton - ihwg beton
CPset_Phasing - Renovation Phase: Bestaand
Pset_SlabCommon - Reference: ø300 (schroef); IsExternal: yes; LoadBearing: no
Component Quantities - WSP_beton - ihwg beton, Mass: 903.056 kg; WSP_beton - ihwg beton, Component Volume (Net): 0.392633 m3; WSP_beton - ihwg beton, Component Volume (Gross): 0.392633 m3
Pset_ReinforcementBarPitchOfSlab - Reference: ø300 (schroef)

# IfcSlab: Slab 450, 17_WSP_FD_beton - fundatiepaal v21-2:ø300 (schroef):1472470
In: -2 fundering
Classification: Vloerplaat - fundering (ARCHICAD Classification); Material: WSP_beton - ihwg beton
Pset_SlabCommon - Reference: ø300 (schroef); IsExternal: yes; LoadBearing: no
CPset_Phasing - Renovation Phase: Bestaand
Component Quantities - WSP_beton - ihwg beton, Mass: 903.056 kg; WSP_beton - ihwg beton, Component Volume (Net): 0.392633 m3; WSP_beton - ihwg beton, Component Volume (Gross): 0.392633 m3
Pset_ReinforcementBarPitchOfSlab - Reference: ø300 (schroef)

# IfcSlab: Slab 451, 17_WSP_FD_beton - fundatiepaal v21-2:ø300 (schroef):1472471
In: -2 fundering
Classification: Vloerplaat - fundering (ARCHICAD Classification); Material: WSP_beton - ihwg beton
Pset_SlabCommon - Reference: ø300 (schroef); IsExternal: yes; LoadBearing: no
Pset_ReinforcementBarPitchOfSlab - Reference: ø300 (schroef)
CPset_Phasing - Renovation Phase: Bestaand
Component Quantities - WSP_beton - ihwg beton, Mass: 903.056 kg; WSP_beton - ihwg beton, Component Volume (Net): 0.392633 m3; WSP_beton - ihwg beton, Component Volume (Gross): 0.392633 m3

# IfcSlab: Slab 452, 17_WSP_FD_beton - fundatiepaal v21-2:ø300 (schroef):1472468
In: -2 fundering
Classification: Vloerplaat - fundering (ARCHICAD Classification); Material: WSP_beton - ihwg beton
Pset_ReinforcementBarPitchOfSlab - Reference: ø300 (schroef)
Pset_SlabCommon - Reference: ø300 (schroef); IsExternal: yes; LoadBearing: no
CPset_Phasing - Renovation Phase: Bestaand
Component Quantities - WSP_beton - ihwg beton, Mass: 903.056 kg; WSP_beton - ihwg beton, Component Volume (Net): 0.392633 m3; WSP_beton - ihwg beton, Component Volume (Gross): 0.392633 m3

# IfcSlab: Slab 453, 17_WSP_FD_beton - fundatiepaal v21-2:ø300 (schroef):1472469
In: -2 fundering
Classification: Vloerplaat - fundering (ARCHICAD Classification); Material: WSP_beton - ihwg beton
Pset_SlabCommon - Reference: ø300 (schroef); IsExternal: yes; LoadBearing: no
Pset_ReinforcementBarPitchOfSlab - Reference: ø300 (schroef)
CPset_Phasing - Renovation Phase: Bestaand
Component Quantities - WSP_beton - ihwg beton, Mass: 903.056 kg; WSP_beton - ihwg beton, Component Volume (Net): 0.392633 m3; WSP_beton - ihwg beton, Component Volume (Gross): 0.392633 m3

# IfcSlab: Slab 454, 17_WSP_FD_beton - fundatiepaal v21-2:ø300 (schroef):1472474
In: -2 fundering
Classification: Vloerplaat - fundering (ARCHICAD Classification); Material: WSP_beton - ihwg beton
Pset_SlabCommon - Reference: ø300 (schroef); IsExternal: yes; LoadBearing: no
CPset_Phasing - Renovation Phase: Bestaand
Component Quantities - WSP_beton - ihwg beton, Mass: 903.056 kg; WSP_beton - ihwg beton, Component Volume (Net): 0.392633 m3; WSP_beton - ihwg beton, Component Volume (Gross): 0.392633 m3
Pset_ReinforcementBarPitchOfSlab - Reference: ø300 (schroef)

# IfcSlab: Slab 455, 17_WSP_FD_beton - fundatiepaal v21-2:ø300 (schroef):1472475
In: -2 fundering
Classification: Vloerplaat - fundering (ARCHICAD Classification); Material: WSP_beton - ihwg beton
Pset_ReinforcementBarPitchOfSlab - Reference: ø300 (schroef)
Pset_SlabCommon - Reference: ø300 (schroef); IsExternal: yes; LoadBearing: no
Component Quantities - WSP_beton - ihwg beton, Mass: 903.056 kg; WSP_beton - ihwg beton, Component Volume (Net): 0.392633 m3; WSP_beton - ihwg beton, Component Volume (Gross): 0.392633 m3
CPset_Phasing - Renovation Phase: Bestaand

# IfcSlab: Slab 456, 17_WSP_FD_beton - fundatiepaal v21-2:ø300 (schroef):1472472
In: -2 fundering
Classification: Vloerplaat - fundering (ARCHICAD Classification); Material: WSP_beton - ihwg beton
Pset_SlabCommon - Reference: ø300 (schroef); IsExternal: yes; LoadBearing: no
Pset_ReinforcementBarPitchOfSlab - Reference: ø300 (schroef)
CPset_Phasing - Renovation Phase: Bestaand
Component Quantities - WSP_beton - ihwg beton, Mass: 903.056 kg; WSP_beton - ihwg beton, Component Volume (Net): 0.392633 m3; WSP_beton - ihwg beton, Component Volume (Gross): 0.392633 m3

# IfcSlab: Slab 457, 17_WSP_FD_beton - fundatiepaal v21-2:ø300 (schroef):1472473
In: -2 fundering
Classification: Vloerplaat - fundering (ARCHICAD Classification); Material: WSP_beton - ihwg beton
Component Quantities - WSP_beton - ihwg beton, Mass: 903.056 kg; WSP_beton - ihwg beton, Component Volume (Net): 0.392633 m3; WSP_beton - ihwg beton, Component Volume (Gross): 0.392633 m3
CPset_Phasing - Renovation Phase: Bestaand
Pset_ReinforcementBarPitchOfSlab - Reference: ø300 (schroef)
Pset_SlabCommon - Reference: ø300 (schroef); IsExternal: yes; LoadBearing: no

# IfcSlab: Slab 458, 17_WSP_FD_beton - fundatiepaal v21-2:ø300 (schroef):1472478
In: -2 fundering
Classification: Vloerplaat - fundering (ARCHICAD Classification); Material: WSP_beton - ihwg beton
Pset_SlabCommon - Reference: ø300 (schroef); IsExternal: yes; LoadBearing: no
CPset_Phasing - Renovation Phase: Bestaand
Pset_ReinforcementBarPitchOfSlab - Reference: ø300 (schroef)
Component Quantities - WSP_beton - ihwg beton, Mass: 903.056 kg; WSP_beton - ihwg beton, Component Volume (Net): 0.392633 m3; WSP_beton - ihwg beton, Component Volume (Gross): 0.392633 m3

# IfcSlab: Slab 459, 17_WSP_FD_beton - fundatiepaal v21-2:ø300 (schroef):1472479
In: -2 fundering
Classification: Vloerplaat - fundering (ARCHICAD Classification); Material: WSP_beton - ihwg beton
Pset_SlabCommon - Reference: ø300 (schroef); IsExternal: yes; LoadBearing: no
Component Quantities - WSP_beton - ihwg beton, Mass: 903.056 kg; WSP_beton - ihwg beton, Component Volume (Net): 0.392633 m3; WSP_beton - ihwg beton, Component Volume (Gross): 0.392633 m3
CPset_Phasing - Renovation Phase: Bestaand
Pset_ReinforcementBarPitchOfSlab - Reference: ø300 (schroef)

# IfcSlab: Slab 46, 17_WSP_FD_beton - fundatiepaal v21-2:ø300 (schroef):1473605
In: -2 fundering
Classification: Vloerplaat - fundering (ARCHICAD Classification); Material: WSP_beton - ihwg beton
Pset_SlabCommon - Reference: ø300 (schroef); IsExternal: yes; LoadBearing: no
Pset_ReinforcementBarPitchOfSlab - Reference: ø300 (schroef)
CPset_Phasing - Renovation Phase: Bestaand
Component Quantities - WSP_beton - ihwg beton, Mass: 903.056 kg; WSP_beton - ihwg beton, Component Volume (Net): 0.392633 m3; WSP_beton - ihwg beton, Component Volume (Gross): 0.392633 m3

# IfcSlab: Slab 460, 17_WSP_FD_beton - fundatiepaal v21-2:ø300 (schroef):1472476
In: -2 fundering
Classification: Vloerplaat - fundering (ARCHICAD Classification); Material: WSP_beton - ihwg beton
Pset_SlabCommon - Reference: ø300 (schroef); IsExternal: yes; LoadBearing: no
Pset_ReinforcementBarPitchOfSlab - Reference: ø300 (schroef)
Component Quantities - WSP_beton - ihwg beton, Mass: 903.056 kg; WSP_beton - ihwg beton, Component Volume (Net): 0.392633 m3; WSP_beton - ihwg beton, Component Volume (Gross): 0.392633 m3
CPset_Phasing - Renovation Phase: Bestaand

# IfcSlab: Slab 461, 17_WSP_FD_beton - fundatiepaal v21-2:ø300 (schroef):1472477
In: -2 fundering
Classification: Vloerplaat - fundering (ARCHICAD Classification); Material: WSP_beton - ihwg beton
Pset_SlabCommon - Reference: ø300 (schroef); IsExternal: yes; LoadBearing: no
Component Quantities - WSP_beton - ihwg beton, Mass: 903.056 kg; WSP_beton - ihwg beton, Component Volume (Net): 0.392633 m3; WSP_beton - ihwg beton, Component Volume (Gross): 0.392633 m3
CPset_Phasing - Renovation Phase: Bestaand
Pset_ReinforcementBarPitchOfSlab - Reference: ø300 (schroef)

# IfcSlab: Slab 462, 17_WSP_FD_beton - fundatiepaal v21-2:ø300 (schroef):1472430
In: -2 fundering
Classification: Vloerplaat - fundering (ARCHICAD Classification); Material: WSP_beton - ihwg beton
Pset_SlabCommon - Reference: ø300 (schroef); IsExternal: yes; LoadBearing: no
Pset_ReinforcementBarPitchOfSlab - Reference: ø300 (schroef)
CPset_Phasing - Renovation Phase: Bestaand
Component Quantities - WSP_beton - ihwg beton, Mass: 903.056 kg; WSP_beton - ihwg beton, Component Volume (Net): 0.392633 m3; WSP_beton - ihwg beton, Component Volume (Gross): 0.392633 m3

# IfcSlab: Slab 463, 17_WSP_FD_beton - fundatiepaal v21-2:ø300 (schroef):1472431
In: -2 fundering
Classification: Vloerplaat - fundering (ARCHICAD Classification); Material: WSP_beton - ihwg beton
Pset_SlabCommon - Reference: ø300 (schroef); IsExternal: yes; LoadBearing: no
Pset_ReinforcementBarPitchOfSlab - Reference: ø300 (schroef)
CPset_Phasing - Renovation Phase: Bestaand
Component Quantities - WSP_beton - ihwg beton, Mass: 903.056 kg; WSP_beton - ihwg beton, Component Volume (Net): 0.392633 m3; WSP_beton - ihwg beton, Component Volume (Gross): 0.392633 m3

# IfcSlab: Slab 464, 17_WSP_FD_beton - fundatiepaal v21-2:ø300 (schroef):1472428
In: -2 fundering
Classification: Vloerplaat - fundering (ARCHICAD Classification); Material: WSP_beton - ihwg beton
Pset_ReinforcementBarPitchOfSlab - Reference: ø300 (schroef)
Pset_SlabCommon - Reference: ø300 (schroef); IsExternal: yes; LoadBearing: no
CPset_Phasing - Renovation Phase: Bestaand
Component Quantities - WSP_beton - ihwg beton, Mass: 903.056 kg; WSP_beton - ihwg beton, Component Volume (Net): 0.392633 m3; WSP_beton - ihwg beton, Component Volume (Gross): 0.392633 m3

# IfcSlab: Slab 465, 17_WSP_FD_beton - fundatiepaal v21-2:ø300 (schroef):1472429
In: -2 fundering
Classification: Vloerplaat - fundering (ARCHICAD Classification); Material: WSP_beton - ihwg beton
Pset_ReinforcementBarPitchOfSlab - Reference: ø300 (schroef)
Pset_SlabCommon - Reference: ø300 (schroef); IsExternal: yes; LoadBearing: no
CPset_Phasing - Renovation Phase: Bestaand
Component Quantities - WSP_beton - ihwg beton, Mass: 903.056 kg; WSP_beton - ihwg beton, Component Volume (Net): 0.392633 m3; WSP_beton - ihwg beton, Component Volume (Gross): 0.392633 m3

# IfcSlab: Slab 466, 17_WSP_FD_beton - fundatiepaal v21-2:ø300 (schroef):1472434
In: -2 fundering
Classification: Vloerplaat - fundering (ARCHICAD Classification); Material: WSP_beton - ihwg beton
Pset_SlabCommon - Reference: ø300 (schroef); IsExternal: yes; LoadBearing: no
Pset_ReinforcementBarPitchOfSlab - Reference: ø300 (schroef)
Component Quantities - WSP_beton - ihwg beton, Mass: 903.056 kg; WSP_beton - ihwg beton, Component Volume (Net): 0.392633 m3; WSP_beton - ihwg beton, Component Volume (Gross): 0.392633 m3
CPset_Phasing - Renovation Phase: Bestaand

# IfcSlab: Slab 467, 17_WSP_FD_beton - fundatiepaal v21-2:ø300 (schroef):1472435
In: -2 fundering
Classification: Vloerplaat - fundering (ARCHICAD Classification); Material: WSP_beton - ihwg beton
Pset_ReinforcementBarPitchOfSlab - Reference: ø300 (schroef)
Pset_SlabCommon - Reference: ø300 (schroef); IsExternal: yes; LoadBearing: no
CPset_Phasing - Renovation Phase: Bestaand
Component Quantities - WSP_beton - ihwg beton, Mass: 903.056 kg; WSP_beton - ihwg beton, Component Volume (Net): 0.392633 m3; WSP_beton - ihwg beton, Component Volume (Gross): 0.392633 m3

# IfcSlab: Slab 468, 17_WSP_FD_beton - fundatiepaal v21-2:ø300 (schroef):1472432
In: -2 fundering
Classification: Vloerplaat - fundering (ARCHICAD Classification); Material: WSP_beton - ihwg beton
Pset_ReinforcementBarPitchOfSlab - Reference: ø300 (schroef)
Pset_SlabCommon - Reference: ø300 (schroef); IsExternal: yes; LoadBearing: no
Component Quantities - WSP_beton - ihwg beton, Mass: 903.056 kg; WSP_beton - ihwg beton, Component Volume (Net): 0.392633 m3; WSP_beton - ihwg beton, Component Volume (Gross): 0.392633 m3
CPset_Phasing - Renovation Phase: Bestaand

# IfcSlab: Slab 469, 17_WSP_FD_beton - fundatiepaal v21-2:ø300 (schroef):1472433
In: -2 fundering
Classification: Vloerplaat - fundering (ARCHICAD Classification); Material: WSP_beton - ihwg beton
Pset_SlabCommon - Reference: ø300 (schroef); IsExternal: yes; LoadBearing: no
Pset_ReinforcementBarPitchOfSlab - Reference: ø300 (schroef)
Component Quantities - WSP_beton - ihwg beton, Mass: 903.056 kg; WSP_beton - ihwg beton, Component Volume (Net): 0.392633 m3; WSP_beton - ihwg beton, Component Volume (Gross): 0.392633 m3
CPset_Phasing - Renovation Phase: Bestaand

# IfcSlab: Slab 47, 17_WSP_FD_beton - fundatiepaal v21-2:ø300 (schroef):1473610
In: -2 fundering
Classification: Vloerplaat - fundering (ARCHICAD Classification); Material: WSP_beton - ihwg beton
Pset_SlabCommon - Reference: ø300 (schroef); IsExternal: yes; LoadBearing: no
Pset_ReinforcementBarPitchOfSlab - Reference: ø300 (schroef)
CPset_Phasing - Renovation Phase: Bestaand
Component Quantities - WSP_beton - ihwg beton, Mass: 903.056 kg; WSP_beton - ihwg beton, Component Volume (Net): 0.392633 m3; WSP_beton - ihwg beton, Component Volume (Gross): 0.392633 m3

# IfcSlab: Slab 470, 17_WSP_FD_beton - fundatiepaal v21-2:ø300 (schroef):1472438
In: -2 fundering
Classification: Vloerplaat - fundering (ARCHICAD Classification); Material: WSP_beton - ihwg beton
Pset_SlabCommon - Reference: ø300 (schroef); IsExternal: yes; LoadBearing: no
Pset_ReinforcementBarPitchOfSlab - Reference: ø300 (schroef)
Component Quantities - WSP_beton - ihwg beton, Mass: 903.056 kg; WSP_beton - ihwg beton, Component Volume (Net): 0.392633 m3; WSP_beton - ihwg beton, Component Volume (Gross): 0.392633 m3
CPset_Phasing - Renovation Phase: Bestaand

# IfcSlab: Slab 471, 17_WSP_FD_beton - fundatiepaal v21-2:ø300 (schroef):1472439
In: -2 fundering
Classification: Vloerplaat - fundering (ARCHICAD Classification); Material: WSP_beton - ihwg beton
Pset_SlabCommon - Reference: ø300 (schroef); IsExternal: yes; LoadBearing: no
Component Quantities - WSP_beton - ihwg beton, Mass: 903.056 kg; WSP_beton - ihwg beton, Component Volume (Net): 0.392633 m3; WSP_beton - ihwg beton, Component Volume (Gross): 0.392633 m3
CPset_Phasing - Renovation Phase: Bestaand
Pset_ReinforcementBarPitchOfSlab - Reference: ø300 (schroef)

# IfcSlab: Slab 472, 17_WSP_FD_beton - fundatiepaal v21-2:ø300 (schroef):1472436
In: -2 fundering
Classification: Vloerplaat - fundering (ARCHICAD Classification); Material: WSP_beton - ihwg beton
Pset_ReinforcementBarPitchOfSlab - Reference: ø300 (schroef)
Pset_SlabCommon - Reference: ø300 (schroef); IsExternal: yes; LoadBearing: no
CPset_Phasing - Renovation Phase: Bestaand
Component Quantities - WSP_beton - ihwg beton, Mass: 903.056 kg; WSP_beton - ihwg beton, Component Volume (Net): 0.392633 m3; WSP_beton - ihwg beton, Component Volume (Gross): 0.392633 m3

# IfcSlab: Slab 473, 17_WSP_FD_beton - fundatiepaal v21-2:ø300 (schroef):1472437
In: -2 fundering
Classification: Vloerplaat - fundering (ARCHICAD Classification); Material: WSP_beton - ihwg beton
Pset_SlabCommon - Reference: ø300 (schroef); IsExternal: yes; LoadBearing: no
CPset_Phasing - Renovation Phase: Bestaand
Component Quantities - WSP_beton - ihwg beton, Mass: 903.056 kg; WSP_beton - ihwg beton, Component Volume (Net): 0.392633 m3; WSP_beton - ihwg beton, Component Volume (Gross): 0.392633 m3
Pset_ReinforcementBarPitchOfSlab - Reference: ø300 (schroef)

# IfcSlab: Slab 474, 17_WSP_FD_beton - fundatiepaal v21-2:ø300 (schroef):1472442
In: -2 fundering
Classification: Vloerplaat - fundering (ARCHICAD Classification); Material: WSP_beton - ihwg beton
Pset_SlabCommon - Reference: ø300 (schroef); IsExternal: yes; LoadBearing: no
Pset_ReinforcementBarPitchOfSlab - Reference: ø300 (schroef)
CPset_Phasing - Renovation Phase: Bestaand
Component Quantities - WSP_beton - ihwg beton, Mass: 903.056 kg; WSP_beton - ihwg beton, Component Volume (Net): 0.392633 m3; WSP_beton - ihwg beton, Component Volume (Gross): 0.392633 m3

# IfcSlab: Slab 475, 17_WSP_FD_beton - fundatiepaal v21-2:ø300 (schroef):1472443
In: -2 fundering
Classification: Vloerplaat - fundering (ARCHICAD Classification); Material: WSP_beton - ihwg beton
Pset_SlabCommon - Reference: ø300 (schroef); IsExternal: yes; LoadBearing: no
Pset_ReinforcementBarPitchOfSlab - Reference: ø300 (schroef)
Component Quantities - WSP_beton - ihwg beton, Mass: 903.056 kg; WSP_beton - ihwg beton, Component Volume (Net): 0.392633 m3; WSP_beton - ihwg beton, Component Volume (Gross): 0.392633 m3
CPset_Phasing - Renovation Phase: Bestaand

# IfcSlab: Slab 476, 17_WSP_FD_beton - fundatiepaal v21-2:ø300 (schroef):1472440
In: -2 fundering
Classification: Vloerplaat - fundering (ARCHICAD Classification); Material: WSP_beton - ihwg beton
Pset_ReinforcementBarPitchOfSlab - Reference: ø300 (schroef)
Pset_SlabCommon - Reference: ø300 (schroef); IsExternal: yes; LoadBearing: no
CPset_Phasing - Renovation Phase: Bestaand
Component Quantities - WSP_beton - ihwg beton, Mass: 903.056 kg; WSP_beton - ihwg beton, Component Volume (Net): 0.392633 m3; WSP_beton - ihwg beton, Component Volume (Gross): 0.392633 m3

# IfcSlab: Slab 477, 17_WSP_FD_beton - fundatiepaal v21-2:ø300 (schroef):1472441
In: -2 fundering
Classification: Vloerplaat - fundering (ARCHICAD Classification); Material: WSP_beton - ihwg beton
Pset_SlabCommon - Reference: ø300 (schroef); IsExternal: yes; LoadBearing: no
Pset_ReinforcementBarPitchOfSlab - Reference: ø300 (schroef)
CPset_Phasing - Renovation Phase: Bestaand
Component Quantities - WSP_beton - ihwg beton, Mass: 903.056 kg; WSP_beton - ihwg beton, Component Volume (Net): 0.392633 m3; WSP_beton - ihwg beton, Component Volume (Gross): 0.392633 m3

# IfcSlab: Slab 478, 17_WSP_FD_beton - fundatiepaal v21-2:ø300 (schroef):1472446
In: -2 fundering
Classification: Vloerplaat - fundering (ARCHICAD Classification); Material: WSP_beton - ihwg beton
Pset_SlabCommon - Reference: ø300 (schroef); IsExternal: yes; LoadBearing: no
CPset_Phasing - Renovation Phase: Bestaand
Pset_ReinforcementBarPitchOfSlab - Reference: ø300 (schroef)
Component Quantities - WSP_beton - ihwg beton, Mass: 903.056 kg; WSP_beton - ihwg beton, Component Volume (Net): 0.392633 m3; WSP_beton - ihwg beton, Component Volume (Gross): 0.392633 m3

# IfcSlab: Slab 479, 17_WSP_FD_beton - fundatiepaal v21-2:ø300 (schroef):1472447
In: -2 fundering
Classification: Vloerplaat - fundering (ARCHICAD Classification); Material: WSP_beton - ihwg beton
Pset_SlabCommon - Reference: ø300 (schroef); IsExternal: yes; LoadBearing: no
Component Quantities - WSP_beton - ihwg beton, Mass: 903.056 kg; WSP_beton - ihwg beton, Component Volume (Net): 0.392633 m3; WSP_beton - ihwg beton, Component Volume (Gross): 0.392633 m3
CPset_Phasing - Renovation Phase: Bestaand
Pset_ReinforcementBarPitchOfSlab - Reference: ø300 (schroef)

# IfcSlab: Slab 48, 17_WSP_FD_beton - fundatiepaal v21-2:ø300 (schroef):1473611
In: -2 fundering
Classification: Vloerplaat - fundering (ARCHICAD Classification); Material: WSP_beton - ihwg beton
Pset_ReinforcementBarPitchOfSlab - Reference: ø300 (schroef)
Pset_SlabCommon - Reference: ø300 (schroef); IsExternal: yes; LoadBearing: no
CPset_Phasing - Renovation Phase: Bestaand
Component Quantities - WSP_beton - ihwg beton, Mass: 903.056 kg; WSP_beton - ihwg beton, Component Volume (Net): 0.392633 m3; WSP_beton - ihwg beton, Component Volume (Gross): 0.392633 m3

# IfcSlab: Slab 480, 17_WSP_FD_beton - fundatiepaal v21-2:ø300 (schroef):1472444
In: -2 fundering
Classification: Vloerplaat - fundering (ARCHICAD Classification); Material: WSP_beton - ihwg beton
Pset_SlabCommon - Reference: ø300 (schroef); IsExternal: yes; LoadBearing: no
Pset_ReinforcementBarPitchOfSlab - Reference: ø300 (schroef)
Component Quantities - WSP_beton - ihwg beton, Mass: 903.056 kg; WSP_beton - ihwg beton, Component Volume (Net): 0.392633 m3; WSP_beton - ihwg beton, Component Volume (Gross): 0.392633 m3
CPset_Phasing - Renovation Phase: Bestaand

# IfcSlab: Slab 481, 17_WSP_FD_beton - fundatiepaal v21-2:ø300 (schroef):1472445
In: -2 fundering
Classification: Vloerplaat - fundering (ARCHICAD Classification); Material: WSP_beton - ihwg beton
Pset_SlabCommon - Reference: ø300 (schroef); IsExternal: yes; LoadBearing: no
Pset_ReinforcementBarPitchOfSlab - Reference: ø300 (schroef)
Component Quantities - WSP_beton - ihwg beton, Mass: 903.056 kg; WSP_beton - ihwg beton, Component Volume (Net): 0.392633 m3; WSP_beton - ihwg beton, Component Volume (Gross): 0.392633 m3
CPset_Phasing - Renovation Phase: Bestaand

# IfcSlab: Slab 482, 17_WSP_FD_beton - fundatiepaal v21-2:ø300 (schroef):1472226
In: -2 fundering
Classification: Vloerplaat - fundering (ARCHICAD Classification); Material: WSP_beton - ihwg beton
Pset_ReinforcementBarPitchOfSlab - Reference: ø300 (schroef)
Component Quantities - WSP_beton - ihwg beton, Mass: 887.213 kg; WSP_beton - ihwg beton, Component Volume (Net): 0.385745 m3; WSP_beton - ihwg beton, Component Volume (Gross): 0.385745 m3
CPset_Phasing - Renovation Phase: Bestaand
Pset_SlabCommon - Reference: ø300 (schroef); IsExternal: yes; LoadBearing: no

# IfcSlab: Slab 483, 17_WSP_FD_beton - fundatiepaal v21-2:ø300 (schroef):1472224
In: -2 fundering
Classification: Vloerplaat - fundering (ARCHICAD Classification); Material: WSP_beton - ihwg beton
Pset_SlabCommon - Reference: ø300 (schroef); IsExternal: yes; LoadBearing: no
Component Quantities - WSP_beton - ihwg beton, Mass: 887.213 kg; WSP_beton - ihwg beton, Component Volume (Net): 0.385745 m3; WSP_beton - ihwg beton, Component Volume (Gross): 0.385745 m3
CPset_Phasing - Renovation Phase: Bestaand
Pset_ReinforcementBarPitchOfSlab - Reference: ø300 (schroef)

# IfcSlab: Slab 484, 17_WSP_FD_beton - fundatiepaal v21-2:ø300 (schroef):1472225
In: -2 fundering
Classification: Vloerplaat - fundering (ARCHICAD Classification); Material: WSP_beton - ihwg beton
CPset_Phasing - Renovation Phase: Bestaand
Pset_ReinforcementBarPitchOfSlab - Reference: ø300 (schroef)
Component Quantities - WSP_beton - ihwg beton, Mass: 887.213 kg; WSP_beton - ihwg beton, Component Volume (Net): 0.385745 m3; WSP_beton - ihwg beton, Component Volume (Gross): 0.385745 m3
Pset_SlabCommon - Reference: ø300 (schroef); IsExternal: yes; LoadBearing: no

# IfcSlab: Slab 485, 17_WSP_FD_beton - fundatiepaal v21-2:ø300 (schroef):1472228
In: -2 fundering
Classification: Vloerplaat - fundering (ARCHICAD Classification); Material: WSP_beton - ihwg beton
CPset_Phasing - Renovation Phase: Bestaand
Pset_SlabCommon - Reference: ø300 (schroef); IsExternal: yes; LoadBearing: no
Component Quantities - WSP_beton - ihwg beton, Mass: 887.213 kg; WSP_beton - ihwg beton, Component Volume (Net): 0.385745 m3; WSP_beton - ihwg beton, Component Volume (Gross): 0.385745 m3
Pset_ReinforcementBarPitchOfSlab - Reference: ø300 (schroef)

# IfcSlab: Slab 486, 17_WSP_FD_beton - fundatiepaal v21-2:ø300 (schroef):1472215
In: -2 fundering
Classification: Vloerplaat - fundering (ARCHICAD Classification); Material: WSP_beton - ihwg beton
Pset_SlabCommon - Reference: ø300 (schroef); IsExternal: yes; LoadBearing: no
Pset_ReinforcementBarPitchOfSlab - Reference: ø300 (schroef)
CPset_Phasing - Renovation Phase: Bestaand
Component Quantities - WSP_beton - ihwg beton, Mass: 887.213 kg; WSP_beton - ihwg beton, Component Volume (Net): 0.385745 m3; WSP_beton - ihwg beton, Component Volume (Gross): 0.385745 m3

# IfcSlab: Slab 487, 17_WSP_FD_beton - fundatiepaal v21-2:ø300 (schroef):1472218
In: -2 fundering
Classification: Vloerplaat - fundering (ARCHICAD Classification); Material: WSP_beton - ihwg beton
Pset_SlabCommon - Reference: ø300 (schroef); IsExternal: yes; LoadBearing: no
CPset_Phasing - Renovation Phase: Bestaand
Pset_ReinforcementBarPitchOfSlab - Reference: ø300 (schroef)
Component Quantities - WSP_beton - ihwg beton, Mass: 887.213 kg; WSP_beton - ihwg beton, Component Volume (Net): 0.385745 m3; WSP_beton - ihwg beton, Component Volume (Gross): 0.385745 m3

# IfcSlab: Slab 488, 17_WSP_FD_beton - fundatiepaal v21-2:ø300 (schroef):1472219
In: -2 fundering
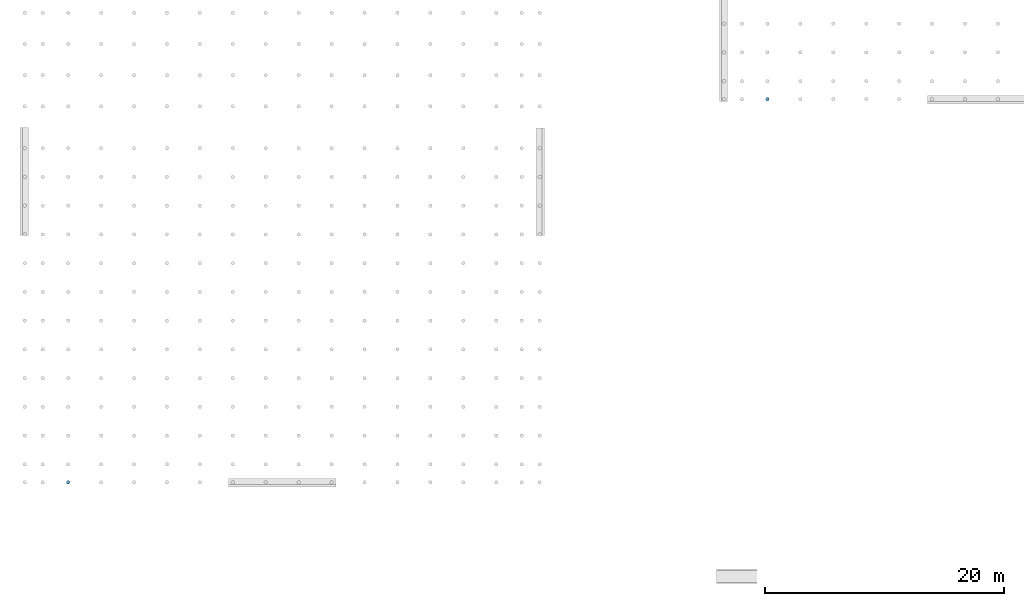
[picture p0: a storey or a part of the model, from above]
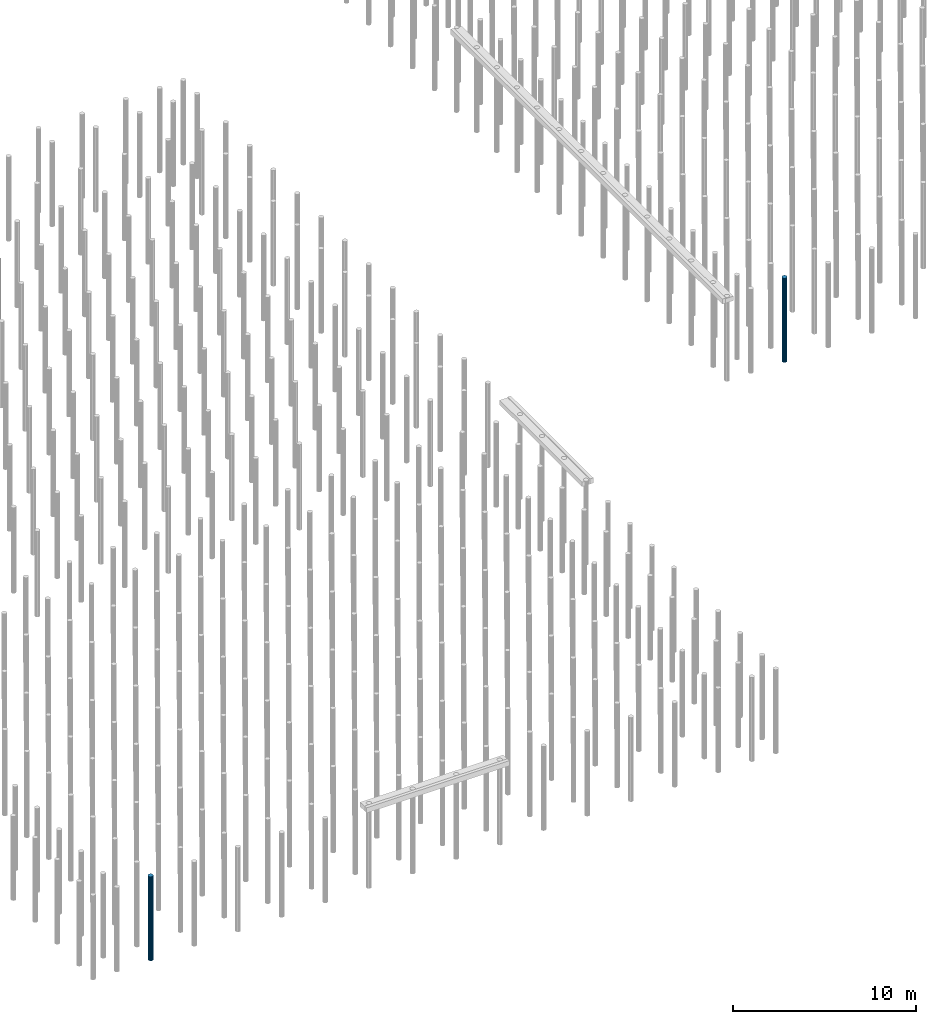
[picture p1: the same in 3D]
Properties of the parts of a building model (IFC2X3), part 7 of 13

# IfcSlab: Slab 488, 17_WSP_FD_beton - fundatiepaal v21-2:ø300 (schroef):1472219
Classification: Vloerplaat - fundering (ARCHICAD Classification); Material: WSP_beton - ihwg beton
Pset_ReinforcementBarPitchOfSlab - Reference: ø300 (schroef)
CPset_Phasing - Renovation Phase: Bestaand
Component Quantities - WSP_beton - ihwg beton, Mass: 887.213 kg; WSP_beton - ihwg beton, Component Volume (Net): 0.385745 m3; WSP_beton - ihwg beton, Component Volume (Gross): 0.385745 m3
Pset_SlabCommon - Reference: ø300 (schroef); IsExternal: yes; LoadBearing: no

# IfcSlab: Slab 489, 17_WSP_FD_beton - fundatiepaal v21-2:ø300 (schroef):1472216
In: -2 fundering
Classification: Vloerplaat - fundering (ARCHICAD Classification); Material: WSP_beton - ihwg beton
Pset_SlabCommon - Reference: ø300 (schroef); IsExternal: yes; LoadBearing: no
Pset_ReinforcementBarPitchOfSlab - Reference: ø300 (schroef)
CPset_Phasing - Renovation Phase: Bestaand
Component Quantities - WSP_beton - ihwg beton, Mass: 887.213 kg; WSP_beton - ihwg beton, Component Volume (Net): 0.385745 m3; WSP_beton - ihwg beton, Component Volume (Gross): 0.385745 m3

# IfcSlab: Slab 49, 17_WSP_FD_beton - fundatiepaal v21-2:ø300 (schroef):1473608
In: -2 fundering
Classification: Vloerplaat - fundering (ARCHICAD Classification); Material: WSP_beton - ihwg beton
Pset_ReinforcementBarPitchOfSlab - Reference: ø300 (schroef)
Pset_SlabCommon - Reference: ø300 (schroef); IsExternal: yes; LoadBearing: no
CPset_Phasing - Renovation Phase: Bestaand
Component Quantities - WSP_beton - ihwg beton, Mass: 903.056 kg; WSP_beton - ihwg beton, Component Volume (Net): 0.392633 m3; WSP_beton - ihwg beton, Component Volume (Gross): 0.392633 m3

# IfcSlab: Slab 490, 17_WSP_FD_beton - fundatiepaal v21-2:ø300 (schroef):1472217
In: -2 fundering
Classification: Vloerplaat - fundering (ARCHICAD Classification); Material: WSP_beton - ihwg beton
Pset_SlabCommon - Reference: ø300 (schroef); IsExternal: yes; LoadBearing: no
Pset_ReinforcementBarPitchOfSlab - Reference: ø300 (schroef)
CPset_Phasing - Renovation Phase: Bestaand
Component Quantities - WSP_beton - ihwg beton, Mass: 887.213 kg; WSP_beton - ihwg beton, Component Volume (Net): 0.385745 m3; WSP_beton - ihwg beton, Component Volume (Gross): 0.385745 m3

# IfcSlab: Slab 491, 17_WSP_FD_beton - fundatiepaal v21-2:ø300 (schroef):1472222
In: -2 fundering
Classification: Vloerplaat - fundering (ARCHICAD Classification); Material: WSP_beton - ihwg beton
Pset_SlabCommon - Reference: ø300 (schroef); IsExternal: yes; LoadBearing: no
Pset_ReinforcementBarPitchOfSlab - Reference: ø300 (schroef)
Component Quantities - WSP_beton - ihwg beton, Mass: 887.213 kg; WSP_beton - ihwg beton, Component Volume (Net): 0.385745 m3; WSP_beton - ihwg beton, Component Volume (Gross): 0.385745 m3
CPset_Phasing - Renovation Phase: Bestaand

# IfcSlab: Slab 492, 17_WSP_FD_beton - fundatiepaal v21-2:ø300 (schroef):1472223
In: -2 fundering
Classification: Vloerplaat - fundering (ARCHICAD Classification); Material: WSP_beton - ihwg beton
Pset_SlabCommon - Reference: ø300 (schroef); IsExternal: yes; LoadBearing: no
Pset_ReinforcementBarPitchOfSlab - Reference: ø300 (schroef)
Component Quantities - WSP_beton - ihwg beton, Mass: 887.213 kg; WSP_beton - ihwg beton, Component Volume (Net): 0.385745 m3; WSP_beton - ihwg beton, Component Volume (Gross): 0.385745 m3
CPset_Phasing - Renovation Phase: Bestaand

# IfcSlab: Slab 493, 17_WSP_FD_beton - fundatiepaal v21-2:ø300 (schroef):1472220
In: -2 fundering
Classification: Vloerplaat - fundering (ARCHICAD Classification); Material: WSP_beton - ihwg beton
Pset_SlabCommon - Reference: ø300 (schroef); IsExternal: yes; LoadBearing: no
Pset_ReinforcementBarPitchOfSlab - Reference: ø300 (schroef)
Component Quantities - WSP_beton - ihwg beton, Mass: 887.213 kg; WSP_beton - ihwg beton, Component Volume (Net): 0.385745 m3; WSP_beton - ihwg beton, Component Volume (Gross): 0.385745 m3
CPset_Phasing - Renovation Phase: Bestaand

# IfcSlab: Slab 494, 17_WSP_FD_beton - fundatiepaal v21-2:ø300 (schroef):1472221
In: -2 fundering
Classification: Vloerplaat - fundering (ARCHICAD Classification); Material: WSP_beton - ihwg beton
Pset_SlabCommon - Reference: ø300 (schroef); IsExternal: yes; LoadBearing: no
Pset_ReinforcementBarPitchOfSlab - Reference: ø300 (schroef)
CPset_Phasing - Renovation Phase: Bestaand
Component Quantities - WSP_beton - ihwg beton, Mass: 887.213 kg; WSP_beton - ihwg beton, Component Volume (Net): 0.385745 m3; WSP_beton - ihwg beton, Component Volume (Gross): 0.385745 m3

# IfcSlab: Slab 495, 17_WSP_FD_beton - fundatiepaal v21-2:ø300 (schroef):1507119
In: -2 fundering
Classification: Vloerplaat - fundering (ARCHICAD Classification); Material: WSP_beton - ihwg beton
Pset_SlabCommon - Reference: ø300 (schroef); IsExternal: yes; LoadBearing: no
Pset_ReinforcementBarPitchOfSlab - Reference: ø300 (schroef)
CPset_Phasing - Renovation Phase: Bestaand
Component Quantities - WSP_beton - ihwg beton, Mass: 903.056 kg; WSP_beton - ihwg beton, Component Volume (Net): 0.392633 m3; WSP_beton - ihwg beton, Component Volume (Gross): 0.392633 m3

# IfcSlab: Slab 496, 17_WSP_FD_beton - fundatiepaal v21-2:ø300 (schroef):1507118
In: -2 fundering
Classification: Vloerplaat - fundering (ARCHICAD Classification); Material: WSP_beton - ihwg beton
Pset_ReinforcementBarPitchOfSlab - Reference: ø300 (schroef)
CPset_Phasing - Renovation Phase: Bestaand
Component Quantities - WSP_beton - ihwg beton, Mass: 903.056 kg; WSP_beton - ihwg beton, Component Volume (Net): 0.392633 m3; WSP_beton - ihwg beton, Component Volume (Gross): 0.392633 m3
Pset_SlabCommon - Reference: ø300 (schroef); IsExternal: yes; LoadBearing: no

# IfcSlab: Slab 497, 17_WSP_FD_beton - fundatiepaal v21-2:ø300 (schroef):1507117
In: -2 fundering
Classification: Vloerplaat - fundering (ARCHICAD Classification); Material: WSP_beton - ihwg beton
Pset_SlabCommon - Reference: ø300 (schroef); IsExternal: yes; LoadBearing: no
CPset_Phasing - Renovation Phase: Bestaand
Pset_ReinforcementBarPitchOfSlab - Reference: ø300 (schroef)
Component Quantities - WSP_beton - ihwg beton, Mass: 903.056 kg; WSP_beton - ihwg beton, Component Volume (Net): 0.392633 m3; WSP_beton - ihwg beton, Component Volume (Gross): 0.392633 m3

# IfcSlab: Slab 498, 17_WSP_FD_beton - fundatiepaal v21-2:ø300 (schroef):1507116
In: -2 fundering
Classification: Vloerplaat - fundering (ARCHICAD Classification); Material: WSP_beton - ihwg beton
Pset_ReinforcementBarPitchOfSlab - Reference: ø300 (schroef)
Pset_SlabCommon - Reference: ø300 (schroef); IsExternal: yes; LoadBearing: no
CPset_Phasing - Renovation Phase: Bestaand
Component Quantities - WSP_beton - ihwg beton, Mass: 903.056 kg; WSP_beton - ihwg beton, Component Volume (Net): 0.392633 m3; WSP_beton - ihwg beton, Component Volume (Gross): 0.392633 m3

# IfcSlab: Slab 499, 17_WSP_FD_beton - fundatiepaal v21-2:ø300 (schroef):1507115
In: -2 fundering
Classification: Vloerplaat - fundering (ARCHICAD Classification); Material: WSP_beton - ihwg beton
Pset_ReinforcementBarPitchOfSlab - Reference: ø300 (schroef)
Pset_SlabCommon - Reference: ø300 (schroef); IsExternal: yes; LoadBearing: no
CPset_Phasing - Renovation Phase: Bestaand
Component Quantities - WSP_beton - ihwg beton, Mass: 903.056 kg; WSP_beton - ihwg beton, Component Volume (Net): 0.392633 m3; WSP_beton - ihwg beton, Component Volume (Gross): 0.392633 m3

# IfcSlab: Slab 5, 17_WSP_FD_beton - fundatiepaal v21-2:ø300 (schroef):1528046
In: -2 fundering
Classification: Vloerplaat - fundering (ARCHICAD Classification); Material: WSP_beton - ihwg beton
Pset_ReinforcementBarPitchOfSlab - Reference: ø300 (schroef)
Pset_SlabCommon - Reference: ø300 (schroef); IsExternal: yes; LoadBearing: no
Component Quantities - WSP_beton - ihwg beton, Mass: 887.213 kg; WSP_beton - ihwg beton, Component Volume (Net): 0.385745 m3; WSP_beton - ihwg beton, Component Volume (Gross): 0.385745 m3
CPset_Phasing - Renovation Phase: Bestaand

# IfcSlab: Slab 50, 17_WSP_FD_beton - fundatiepaal v21-2:ø300 (schroef):1473609
In: -2 fundering
Classification: Vloerplaat - fundering (ARCHICAD Classification); Material: WSP_beton - ihwg beton
Pset_SlabCommon - Reference: ø300 (schroef); IsExternal: yes; LoadBearing: no
Pset_ReinforcementBarPitchOfSlab - Reference: ø300 (schroef)
CPset_Phasing - Renovation Phase: Bestaand
Component Quantities - WSP_beton - ihwg beton, Mass: 903.056 kg; WSP_beton - ihwg beton, Component Volume (Net): 0.392633 m3; WSP_beton - ihwg beton, Component Volume (Gross): 0.392633 m3

# IfcSlab: Slab 500, 17_WSP_FD_beton - fundatiepaal v21-2:ø300 (schroef):1507114
In: -2 fundering
Classification: Vloerplaat - fundering (ARCHICAD Classification); Material: WSP_beton - ihwg beton
Pset_SlabCommon - Reference: ø300 (schroef); IsExternal: yes; LoadBearing: no
Pset_ReinforcementBarPitchOfSlab - Reference: ø300 (schroef)
CPset_Phasing - Renovation Phase: Bestaand
Component Quantities - WSP_beton - ihwg beton, Mass: 903.056 kg; WSP_beton - ihwg beton, Component Volume (Net): 0.392633 m3; WSP_beton - ihwg beton, Component Volume (Gross): 0.392633 m3

# IfcSlab: Slab 501, 17_WSP_FD_beton - fundatiepaal v21-2:ø300 (schroef):1507113
In: -2 fundering
Classification: Vloerplaat - fundering (ARCHICAD Classification); Material: WSP_beton - ihwg beton
CPset_Phasing - Renovation Phase: Bestaand
Component Quantities - WSP_beton - ihwg beton, Mass: 903.056 kg; WSP_beton - ihwg beton, Component Volume (Net): 0.392633 m3; WSP_beton - ihwg beton, Component Volume (Gross): 0.392633 m3
Pset_ReinforcementBarPitchOfSlab - Reference: ø300 (schroef)
Pset_SlabCommon - Reference: ø300 (schroef); IsExternal: yes; LoadBearing: no

# IfcSlab: Slab 502, 17_WSP_FD_beton - fundatiepaal v21-2:ø300 (schroef):1507112
In: -2 fundering
Classification: Vloerplaat - fundering (ARCHICAD Classification); Material: WSP_beton - ihwg beton
Pset_SlabCommon - Reference: ø300 (schroef); IsExternal: yes; LoadBearing: no
Component Quantities - WSP_beton - ihwg beton, Mass: 903.056 kg; WSP_beton - ihwg beton, Component Volume (Net): 0.392633 m3; WSP_beton - ihwg beton, Component Volume (Gross): 0.392633 m3
CPset_Phasing - Renovation Phase: Bestaand
Pset_ReinforcementBarPitchOfSlab - Reference: ø300 (schroef)

# IfcSlab: Slab 503, 17_WSP_FD_beton - fundatiepaal v21-2:ø300 (schroef):1507111
In: -2 fundering
Classification: Vloerplaat - fundering (ARCHICAD Classification); Material: WSP_beton - ihwg beton
Pset_ReinforcementBarPitchOfSlab - Reference: ø300 (schroef)
Pset_SlabCommon - Reference: ø300 (schroef); IsExternal: yes; LoadBearing: no
CPset_Phasing - Renovation Phase: Bestaand
Component Quantities - WSP_beton - ihwg beton, Mass: 903.056 kg; WSP_beton - ihwg beton, Component Volume (Net): 0.392633 m3; WSP_beton - ihwg beton, Component Volume (Gross): 0.392633 m3

# IfcSlab: Slab 504, 17_WSP_FD_beton - fundatiepaal v21-2:ø300 (schroef):1507110
In: -2 fundering
Classification: Vloerplaat - fundering (ARCHICAD Classification); Material: WSP_beton - ihwg beton
CPset_Phasing - Renovation Phase: Bestaand
Pset_SlabCommon - Reference: ø300 (schroef); IsExternal: yes; LoadBearing: no
Pset_ReinforcementBarPitchOfSlab - Reference: ø300 (schroef)
Component Quantities - WSP_beton - ihwg beton, Mass: 903.056 kg; WSP_beton - ihwg beton, Component Volume (Net): 0.392633 m3; WSP_beton - ihwg beton, Component Volume (Gross): 0.392633 m3

# IfcSlab: Slab 505, 17_WSP_FD_beton - fundatiepaal v21-2:ø300 (schroef):1507109
In: -2 fundering
Classification: Vloerplaat - fundering (ARCHICAD Classification); Material: WSP_beton - ihwg beton
CPset_Phasing - Renovation Phase: Bestaand
Pset_ReinforcementBarPitchOfSlab - Reference: ø300 (schroef)
Pset_SlabCommon - Reference: ø300 (schroef); IsExternal: yes; LoadBearing: no
Component Quantities - WSP_beton - ihwg beton, Mass: 903.056 kg; WSP_beton - ihwg beton, Component Volume (Net): 0.392633 m3; WSP_beton - ihwg beton, Component Volume (Gross): 0.392633 m3

# IfcSlab: Slab 506, 17_WSP_FD_beton - fundatiepaal v21-2:ø300 (schroef):1507108
In: -2 fundering
Classification: Vloerplaat - fundering (ARCHICAD Classification); Material: WSP_beton - ihwg beton
Pset_ReinforcementBarPitchOfSlab - Reference: ø300 (schroef)
Pset_SlabCommon - Reference: ø300 (schroef); IsExternal: yes; LoadBearing: no
CPset_Phasing - Renovation Phase: Bestaand
Component Quantities - WSP_beton - ihwg beton, Mass: 903.056 kg; WSP_beton - ihwg beton, Component Volume (Net): 0.392633 m3; WSP_beton - ihwg beton, Component Volume (Gross): 0.392633 m3

# IfcSlab: Slab 507, 17_WSP_FD_beton - fundatiepaal v21-2:ø300 (schroef):1507107
In: -2 fundering
Classification: Vloerplaat - fundering (ARCHICAD Classification); Material: WSP_beton - ihwg beton
Pset_SlabCommon - Reference: ø300 (schroef); IsExternal: yes; LoadBearing: no
Component Quantities - WSP_beton - ihwg beton, Mass: 903.056 kg; WSP_beton - ihwg beton, Component Volume (Net): 0.392633 m3; WSP_beton - ihwg beton, Component Volume (Gross): 0.392633 m3
Pset_ReinforcementBarPitchOfSlab - Reference: ø300 (schroef)
CPset_Phasing - Renovation Phase: Bestaand

# IfcSlab: Slab 508, 17_WSP_FD_beton - fundatiepaal v21-2:ø300 (schroef):1507106
In: -2 fundering
Classification: Vloerplaat - fundering (ARCHICAD Classification); Material: WSP_beton - ihwg beton
Pset_ReinforcementBarPitchOfSlab - Reference: ø300 (schroef)
Pset_SlabCommon - Reference: ø300 (schroef); IsExternal: yes; LoadBearing: no
CPset_Phasing - Renovation Phase: Bestaand
Component Quantities - WSP_beton - ihwg beton, Mass: 903.056 kg; WSP_beton - ihwg beton, Component Volume (Net): 0.392633 m3; WSP_beton - ihwg beton, Component Volume (Gross): 0.392633 m3

# IfcSlab: Slab 509, 17_WSP_FD_beton - fundatiepaal v21-2:ø300 (schroef):1507105
In: -2 fundering
Classification: Vloerplaat - fundering (ARCHICAD Classification); Material: WSP_beton - ihwg beton
Pset_ReinforcementBarPitchOfSlab - Reference: ø300 (schroef)
Pset_SlabCommon - Reference: ø300 (schroef); IsExternal: yes; LoadBearing: no
Component Quantities - WSP_beton - ihwg beton, Mass: 903.056 kg; WSP_beton - ihwg beton, Component Volume (Net): 0.392633 m3; WSP_beton - ihwg beton, Component Volume (Gross): 0.392633 m3
CPset_Phasing - Renovation Phase: Bestaand

# IfcSlab: Slab 51, 17_WSP_FD_beton - fundatiepaal v21-2:ø300 (schroef):1473614
In: -2 fundering
Classification: Vloerplaat - fundering (ARCHICAD Classification); Material: WSP_beton - ihwg beton
Pset_SlabCommon - Reference: ø300 (schroef); IsExternal: yes; LoadBearing: no
CPset_Phasing - Renovation Phase: Bestaand
Component Quantities - WSP_beton - ihwg beton, Mass: 887.213 kg; WSP_beton - ihwg beton, Component Volume (Net): 0.385745 m3; WSP_beton - ihwg beton, Component Volume (Gross): 0.385745 m3
Pset_ReinforcementBarPitchOfSlab - Reference: ø300 (schroef)

# IfcSlab: Slab 510, 17_WSP_FD_beton - fundatiepaal v21-2:ø300 (schroef):1507104
In: -2 fundering
Classification: Vloerplaat - fundering (ARCHICAD Classification); Material: WSP_beton - ihwg beton
CPset_Phasing - Renovation Phase: Bestaand
Component Quantities - WSP_beton - ihwg beton, Mass: 903.056 kg; WSP_beton - ihwg beton, Component Volume (Net): 0.392633 m3; WSP_beton - ihwg beton, Component Volume (Gross): 0.392633 m3
Pset_SlabCommon - Reference: ø300 (schroef); IsExternal: yes; LoadBearing: no
Pset_ReinforcementBarPitchOfSlab - Reference: ø300 (schroef)

# IfcSlab: Slab 511, 17_WSP_FD_beton - fundatiepaal v21-2:ø300 (schroef):1507135
In: -2 fundering
Classification: Vloerplaat - fundering (ARCHICAD Classification); Material: WSP_beton - ihwg beton
Pset_SlabCommon - Reference: ø300 (schroef); IsExternal: yes; LoadBearing: no
Pset_ReinforcementBarPitchOfSlab - Reference: ø300 (schroef)
CPset_Phasing - Renovation Phase: Bestaand
Component Quantities - WSP_beton - ihwg beton, Mass: 903.056 kg; WSP_beton - ihwg beton, Component Volume (Net): 0.392633 m3; WSP_beton - ihwg beton, Component Volume (Gross): 0.392633 m3

# IfcSlab: Slab 512, 17_WSP_FD_beton - fundatiepaal v21-2:ø300 (schroef):1507134
In: -2 fundering
Classification: Vloerplaat - fundering (ARCHICAD Classification); Material: WSP_beton - ihwg beton
Pset_ReinforcementBarPitchOfSlab - Reference: ø300 (schroef)
Pset_SlabCommon - Reference: ø300 (schroef); IsExternal: yes; LoadBearing: no
Component Quantities - WSP_beton - ihwg beton, Mass: 903.056 kg; WSP_beton - ihwg beton, Component Volume (Net): 0.392633 m3; WSP_beton - ihwg beton, Component Volume (Gross): 0.392633 m3
CPset_Phasing - Renovation Phase: Bestaand

# IfcSlab: Slab 513, 17_WSP_FD_beton - fundatiepaal v21-2:ø300 (schroef):1507133
In: -2 fundering
Classification: Vloerplaat - fundering (ARCHICAD Classification); Material: WSP_beton - ihwg beton
Pset_SlabCommon - Reference: ø300 (schroef); IsExternal: yes; LoadBearing: no
CPset_Phasing - Renovation Phase: Bestaand
Pset_ReinforcementBarPitchOfSlab - Reference: ø300 (schroef)
Component Quantities - WSP_beton - ihwg beton, Mass: 903.056 kg; WSP_beton - ihwg beton, Component Volume (Net): 0.392633 m3; WSP_beton - ihwg beton, Component Volume (Gross): 0.392633 m3

# IfcSlab: Slab 514, 17_WSP_FD_beton - fundatiepaal v21-2:ø300 (schroef):1507132
In: -2 fundering
Classification: Vloerplaat - fundering (ARCHICAD Classification); Material: WSP_beton - ihwg beton
CPset_Phasing - Renovation Phase: Bestaand
Pset_ReinforcementBarPitchOfSlab - Reference: ø300 (schroef)
Pset_SlabCommon - Reference: ø300 (schroef); IsExternal: yes; LoadBearing: no
Component Quantities - WSP_beton - ihwg beton, Mass: 903.056 kg; WSP_beton - ihwg beton, Component Volume (Net): 0.392633 m3; WSP_beton - ihwg beton, Component Volume (Gross): 0.392633 m3

# IfcSlab: Slab 515, 17_WSP_FD_beton - fundatiepaal v21-2:ø300 (schroef):1507131
In: -2 fundering
Classification: Vloerplaat - fundering (ARCHICAD Classification); Material: WSP_beton - ihwg beton
Pset_SlabCommon - Reference: ø300 (schroef); IsExternal: yes; LoadBearing: no
CPset_Phasing - Renovation Phase: Bestaand
Pset_ReinforcementBarPitchOfSlab - Reference: ø300 (schroef)
Component Quantities - WSP_beton - ihwg beton, Mass: 903.056 kg; WSP_beton - ihwg beton, Component Volume (Net): 0.392633 m3; WSP_beton - ihwg beton, Component Volume (Gross): 0.392633 m3

# IfcSlab: Slab 516, 17_WSP_FD_beton - fundatiepaal v21-2:ø300 (schroef):1507130
In: -2 fundering
Classification: Vloerplaat - fundering (ARCHICAD Classification); Material: WSP_beton - ihwg beton
Pset_SlabCommon - Reference: ø300 (schroef); IsExternal: yes; LoadBearing: no
Component Quantities - WSP_beton - ihwg beton, Mass: 903.056 kg; WSP_beton - ihwg beton, Component Volume (Net): 0.392633 m3; WSP_beton - ihwg beton, Component Volume (Gross): 0.392633 m3
CPset_Phasing - Renovation Phase: Bestaand
Pset_ReinforcementBarPitchOfSlab - Reference: ø300 (schroef)

# IfcSlab: Slab 517, 17_WSP_FD_beton - fundatiepaal v21-2:ø300 (schroef):1507129
In: -2 fundering
Classification: Vloerplaat - fundering (ARCHICAD Classification); Material: WSP_beton - ihwg beton
Component Quantities - WSP_beton - ihwg beton, Mass: 903.056 kg; WSP_beton - ihwg beton, Component Volume (Net): 0.392633 m3; WSP_beton - ihwg beton, Component Volume (Gross): 0.392633 m3
CPset_Phasing - Renovation Phase: Bestaand
Pset_ReinforcementBarPitchOfSlab - Reference: ø300 (schroef)
Pset_SlabCommon - Reference: ø300 (schroef); IsExternal: yes; LoadBearing: no

# IfcSlab: Slab 518, 17_WSP_FD_beton - fundatiepaal v21-2:ø300 (schroef):1507128
In: -2 fundering
Classification: Vloerplaat - fundering (ARCHICAD Classification); Material: WSP_beton - ihwg beton
Pset_SlabCommon - Reference: ø300 (schroef); IsExternal: yes; LoadBearing: no
Component Quantities - WSP_beton - ihwg beton, Mass: 903.056 kg; WSP_beton - ihwg beton, Component Volume (Net): 0.392633 m3; WSP_beton - ihwg beton, Component Volume (Gross): 0.392633 m3
Pset_ReinforcementBarPitchOfSlab - Reference: ø300 (schroef)
CPset_Phasing - Renovation Phase: Bestaand

# IfcSlab: Slab 519, 17_WSP_FD_beton - fundatiepaal v21-2:ø300 (schroef):1507127
In: -2 fundering
Classification: Vloerplaat - fundering (ARCHICAD Classification); Material: WSP_beton - ihwg beton
Pset_ReinforcementBarPitchOfSlab - Reference: ø300 (schroef)
Component Quantities - WSP_beton - ihwg beton, Mass: 903.056 kg; WSP_beton - ihwg beton, Component Volume (Net): 0.392633 m3; WSP_beton - ihwg beton, Component Volume (Gross): 0.392633 m3
CPset_Phasing - Renovation Phase: Bestaand
Pset_SlabCommon - Reference: ø300 (schroef); IsExternal: yes; LoadBearing: no

# IfcSlab: Slab 52, 17_WSP_FD_beton - fundatiepaal v21-2:ø300 (schroef):1473615
In: -2 fundering
Classification: Vloerplaat - fundering (ARCHICAD Classification); Material: WSP_beton - ihwg beton
Pset_ReinforcementBarPitchOfSlab - Reference: ø300 (schroef)
Pset_SlabCommon - Reference: ø300 (schroef); IsExternal: yes; LoadBearing: no
Component Quantities - WSP_beton - ihwg beton, Mass: 887.213 kg; WSP_beton - ihwg beton, Component Volume (Net): 0.385745 m3; WSP_beton - ihwg beton, Component Volume (Gross): 0.385745 m3
CPset_Phasing - Renovation Phase: Bestaand

# IfcSlab: Slab 520, 17_WSP_FD_beton - fundatiepaal v21-2:ø300 (schroef):1507126
In: -2 fundering
Classification: Vloerplaat - fundering (ARCHICAD Classification); Material: WSP_beton - ihwg beton
Pset_SlabCommon - Reference: ø300 (schroef); IsExternal: yes; LoadBearing: no
Pset_ReinforcementBarPitchOfSlab - Reference: ø300 (schroef)
CPset_Phasing - Renovation Phase: Bestaand
Component Quantities - WSP_beton - ihwg beton, Mass: 903.056 kg; WSP_beton - ihwg beton, Component Volume (Net): 0.392633 m3; WSP_beton - ihwg beton, Component Volume (Gross): 0.392633 m3

# IfcSlab: Slab 521, 17_WSP_FD_beton - fundatiepaal v21-2:ø300 (schroef):1507125
In: -2 fundering
Classification: Vloerplaat - fundering (ARCHICAD Classification); Material: WSP_beton - ihwg beton
Pset_ReinforcementBarPitchOfSlab - Reference: ø300 (schroef)
Pset_SlabCommon - Reference: ø300 (schroef); IsExternal: yes; LoadBearing: no
CPset_Phasing - Renovation Phase: Bestaand
Component Quantities - WSP_beton - ihwg beton, Mass: 903.056 kg; WSP_beton - ihwg beton, Component Volume (Net): 0.392633 m3; WSP_beton - ihwg beton, Component Volume (Gross): 0.392633 m3

# IfcSlab: Slab 522, 17_WSP_FD_beton - fundatiepaal v21-2:ø300 (schroef):1507124
In: -2 fundering
Classification: Vloerplaat - fundering (ARCHICAD Classification); Material: WSP_beton - ihwg beton
Pset_SlabCommon - Reference: ø300 (schroef); IsExternal: yes; LoadBearing: no
CPset_Phasing - Renovation Phase: Bestaand
Component Quantities - WSP_beton - ihwg beton, Mass: 903.056 kg; WSP_beton - ihwg beton, Component Volume (Net): 0.392633 m3; WSP_beton - ihwg beton, Component Volume (Gross): 0.392633 m3
Pset_ReinforcementBarPitchOfSlab - Reference: ø300 (schroef)

# IfcSlab: Slab 523, 17_WSP_FD_beton - fundatiepaal v21-2:ø300 (schroef):1507123
In: -2 fundering
Classification: Vloerplaat - fundering (ARCHICAD Classification); Material: WSP_beton - ihwg beton
Pset_ReinforcementBarPitchOfSlab - Reference: ø300 (schroef)
Pset_SlabCommon - Reference: ø300 (schroef); IsExternal: yes; LoadBearing: no
Component Quantities - WSP_beton - ihwg beton, Mass: 903.056 kg; WSP_beton - ihwg beton, Component Volume (Net): 0.392633 m3; WSP_beton - ihwg beton, Component Volume (Gross): 0.392633 m3
CPset_Phasing - Renovation Phase: Bestaand

# IfcSlab: Slab 524, 17_WSP_FD_beton - fundatiepaal v21-2:ø300 (schroef):1507122
In: -2 fundering
Classification: Vloerplaat - fundering (ARCHICAD Classification); Material: WSP_beton - ihwg beton
CPset_Phasing - Renovation Phase: Bestaand
Pset_ReinforcementBarPitchOfSlab - Reference: ø300 (schroef)
Pset_SlabCommon - Reference: ø300 (schroef); IsExternal: yes; LoadBearing: no
Component Quantities - WSP_beton - ihwg beton, Mass: 903.056 kg; WSP_beton - ihwg beton, Component Volume (Net): 0.392633 m3; WSP_beton - ihwg beton, Component Volume (Gross): 0.392633 m3

# IfcSlab: Slab 525, 17_WSP_FD_beton - fundatiepaal v21-2:ø300 (schroef):1507121
In: -2 fundering
Classification: Vloerplaat - fundering (ARCHICAD Classification); Material: WSP_beton - ihwg beton
Pset_SlabCommon - Reference: ø300 (schroef); IsExternal: yes; LoadBearing: no
Component Quantities - WSP_beton - ihwg beton, Mass: 903.056 kg; WSP_beton - ihwg beton, Component Volume (Net): 0.392633 m3; WSP_beton - ihwg beton, Component Volume (Gross): 0.392633 m3
CPset_Phasing - Renovation Phase: Bestaand
Pset_ReinforcementBarPitchOfSlab - Reference: ø300 (schroef)

# IfcSlab: Slab 526, 17_WSP_FD_beton - fundatiepaal v21-2:ø300 (schroef):1507120
In: -2 fundering
Classification: Vloerplaat - fundering (ARCHICAD Classification); Material: WSP_beton - ihwg beton
CPset_Phasing - Renovation Phase: Bestaand
Pset_SlabCommon - Reference: ø300 (schroef); IsExternal: yes; LoadBearing: no
Pset_ReinforcementBarPitchOfSlab - Reference: ø300 (schroef)
Component Quantities - WSP_beton - ihwg beton, Mass: 903.056 kg; WSP_beton - ihwg beton, Component Volume (Net): 0.392633 m3; WSP_beton - ihwg beton, Component Volume (Gross): 0.392633 m3

# IfcSlab: Slab 527, 17_WSP_FD_beton - fundatiepaal v21-2:ø300 (schroef):1507087
In: -2 fundering
Classification: Vloerplaat - fundering (ARCHICAD Classification); Material: WSP_beton - ihwg beton
Component Quantities - WSP_beton - ihwg beton, Mass: 903.056 kg; WSP_beton - ihwg beton, Component Volume (Net): 0.392633 m3; WSP_beton - ihwg beton, Component Volume (Gross): 0.392633 m3
CPset_Phasing - Renovation Phase: Bestaand
Pset_SlabCommon - Reference: ø300 (schroef); IsExternal: yes; LoadBearing: no
Pset_ReinforcementBarPitchOfSlab - Reference: ø300 (schroef)

# IfcSlab: Slab 528, 17_WSP_FD_beton - fundatiepaal v21-2:ø300 (schroef):1507086
In: -2 fundering
Classification: Vloerplaat - fundering (ARCHICAD Classification); Material: WSP_beton - ihwg beton
Pset_SlabCommon - Reference: ø300 (schroef); IsExternal: yes; LoadBearing: no
CPset_Phasing - Renovation Phase: Bestaand
Pset_ReinforcementBarPitchOfSlab - Reference: ø300 (schroef)
Component Quantities - WSP_beton - ihwg beton, Mass: 903.056 kg; WSP_beton - ihwg beton, Component Volume (Net): 0.392633 m3; WSP_beton - ihwg beton, Component Volume (Gross): 0.392633 m3

# IfcSlab: Slab 529, 17_WSP_FD_beton - fundatiepaal v21-2:ø300 (schroef):1507085
In: -2 fundering
Classification: Vloerplaat - fundering (ARCHICAD Classification); Material: WSP_beton - ihwg beton
Pset_ReinforcementBarPitchOfSlab - Reference: ø300 (schroef)
CPset_Phasing - Renovation Phase: Bestaand
Pset_SlabCommon - Reference: ø300 (schroef); IsExternal: yes; LoadBearing: no
Component Quantities - WSP_beton - ihwg beton, Mass: 903.056 kg; WSP_beton - ihwg beton, Component Volume (Net): 0.392633 m3; WSP_beton - ihwg beton, Component Volume (Gross): 0.392633 m3

# IfcSlab: Slab 53, 17_WSP_FD_beton - fundatiepaal v21-2:ø300 (schroef):1473612
In: -2 fundering
Classification: Vloerplaat - fundering (ARCHICAD Classification); Material: WSP_beton - ihwg beton
Component Quantities - WSP_beton - ihwg beton, Mass: 887.213 kg; WSP_beton - ihwg beton, Component Volume (Net): 0.385745 m3; WSP_beton - ihwg beton, Component Volume (Gross): 0.385745 m3
CPset_Phasing - Renovation Phase: Bestaand
Pset_ReinforcementBarPitchOfSlab - Reference: ø300 (schroef)
Pset_SlabCommon - Reference: ø300 (schroef); IsExternal: yes; LoadBearing: no

# IfcSlab: Slab 530, 17_WSP_FD_beton - fundatiepaal v21-2:ø300 (schroef):1507084
In: -2 fundering
Classification: Vloerplaat - fundering (ARCHICAD Classification); Material: WSP_beton - ihwg beton
Pset_SlabCommon - Reference: ø300 (schroef); IsExternal: yes; LoadBearing: no
Pset_ReinforcementBarPitchOfSlab - Reference: ø300 (schroef)
CPset_Phasing - Renovation Phase: Bestaand
Component Quantities - WSP_beton - ihwg beton, Mass: 903.056 kg; WSP_beton - ihwg beton, Component Volume (Net): 0.392633 m3; WSP_beton - ihwg beton, Component Volume (Gross): 0.392633 m3

# IfcSlab: Slab 531, 17_WSP_FD_beton - fundatiepaal v21-2:ø300 (schroef):1507083
In: -2 fundering
Classification: Vloerplaat - fundering (ARCHICAD Classification); Material: WSP_beton - ihwg beton
Pset_SlabCommon - Reference: ø300 (schroef); IsExternal: yes; LoadBearing: no
Component Quantities - WSP_beton - ihwg beton, Mass: 903.056 kg; WSP_beton - ihwg beton, Component Volume (Net): 0.392633 m3; WSP_beton - ihwg beton, Component Volume (Gross): 0.392633 m3
CPset_Phasing - Renovation Phase: Bestaand
Pset_ReinforcementBarPitchOfSlab - Reference: ø300 (schroef)

# IfcSlab: Slab 532, 17_WSP_FD_beton - fundatiepaal v21-2:ø300 (schroef):1507082
In: -2 fundering
Classification: Vloerplaat - fundering (ARCHICAD Classification); Material: WSP_beton - ihwg beton
Pset_SlabCommon - Reference: ø300 (schroef); IsExternal: yes; LoadBearing: no
Pset_ReinforcementBarPitchOfSlab - Reference: ø300 (schroef)
CPset_Phasing - Renovation Phase: Bestaand
Component Quantities - WSP_beton - ihwg beton, Mass: 903.056 kg; WSP_beton - ihwg beton, Component Volume (Net): 0.392633 m3; WSP_beton - ihwg beton, Component Volume (Gross): 0.392633 m3

# IfcSlab: Slab 533, 17_WSP_FD_beton - fundatiepaal v21-2:ø300 (schroef):1507081
In: -2 fundering
Classification: Vloerplaat - fundering (ARCHICAD Classification); Material: WSP_beton - ihwg beton
Pset_ReinforcementBarPitchOfSlab - Reference: ø300 (schroef)
Pset_SlabCommon - Reference: ø300 (schroef); IsExternal: yes; LoadBearing: no
Component Quantities - WSP_beton - ihwg beton, Mass: 903.056 kg; WSP_beton - ihwg beton, Component Volume (Net): 0.392633 m3; WSP_beton - ihwg beton, Component Volume (Gross): 0.392633 m3
CPset_Phasing - Renovation Phase: Bestaand

# IfcSlab: Slab 534, 17_WSP_FD_beton - fundatiepaal v21-2:ø300 (schroef):1507080
In: -2 fundering
Classification: Vloerplaat - fundering (ARCHICAD Classification); Material: WSP_beton - ihwg beton
Pset_SlabCommon - Reference: ø300 (schroef); IsExternal: yes; LoadBearing: no
CPset_Phasing - Renovation Phase: Bestaand
Pset_ReinforcementBarPitchOfSlab - Reference: ø300 (schroef)
Component Quantities - WSP_beton - ihwg beton, Mass: 903.056 kg; WSP_beton - ihwg beton, Component Volume (Net): 0.392633 m3; WSP_beton - ihwg beton, Component Volume (Gross): 0.392633 m3

# IfcSlab: Slab 535, 17_WSP_FD_beton - fundatiepaal v21-2:ø300 (schroef):1507079
In: -2 fundering
Classification: Vloerplaat - fundering (ARCHICAD Classification); Material: WSP_beton - ihwg beton
CPset_Phasing - Renovation Phase: Bestaand
Pset_SlabCommon - Reference: ø300 (schroef); IsExternal: yes; LoadBearing: no
Component Quantities - WSP_beton - ihwg beton, Mass: 903.056 kg; WSP_beton - ihwg beton, Component Volume (Net): 0.392633 m3; WSP_beton - ihwg beton, Component Volume (Gross): 0.392633 m3
Pset_ReinforcementBarPitchOfSlab - Reference: ø300 (schroef)

# IfcSlab: Slab 536, 17_WSP_FD_beton - fundatiepaal v21-2:ø300 (schroef):1507078
In: -2 fundering
Classification: Vloerplaat - fundering (ARCHICAD Classification); Material: WSP_beton - ihwg beton
Pset_SlabCommon - Reference: ø300 (schroef); IsExternal: yes; LoadBearing: no
CPset_Phasing - Renovation Phase: Bestaand
Component Quantities - WSP_beton - ihwg beton, Mass: 903.056 kg; WSP_beton - ihwg beton, Component Volume (Net): 0.392633 m3; WSP_beton - ihwg beton, Component Volume (Gross): 0.392633 m3
Pset_ReinforcementBarPitchOfSlab - Reference: ø300 (schroef)

# IfcSlab: Slab 537, 17_WSP_FD_beton - fundatiepaal v21-2:ø300 (schroef):1507077
In: -2 fundering
Classification: Vloerplaat - fundering (ARCHICAD Classification); Material: WSP_beton - ihwg beton
Pset_ReinforcementBarPitchOfSlab - Reference: ø300 (schroef)
CPset_Phasing - Renovation Phase: Bestaand
Component Quantities - WSP_beton - ihwg beton, Mass: 903.056 kg; WSP_beton - ihwg beton, Component Volume (Net): 0.392633 m3; WSP_beton - ihwg beton, Component Volume (Gross): 0.392633 m3
Pset_SlabCommon - Reference: ø300 (schroef); IsExternal: yes; LoadBearing: no

# IfcSlab: Slab 538, 17_WSP_FD_beton - fundatiepaal v21-2:ø300 (schroef):1507076
In: -2 fundering
Classification: Vloerplaat - fundering (ARCHICAD Classification); Material: WSP_beton - ihwg beton
CPset_Phasing - Renovation Phase: Bestaand
Pset_SlabCommon - Reference: ø300 (schroef); IsExternal: yes; LoadBearing: no
Pset_ReinforcementBarPitchOfSlab - Reference: ø300 (schroef)
Component Quantities - WSP_beton - ihwg beton, Mass: 903.056 kg; WSP_beton - ihwg beton, Component Volume (Net): 0.392633 m3; WSP_beton - ihwg beton, Component Volume (Gross): 0.392633 m3

# IfcSlab: Slab 539, 17_WSP_FD_beton - fundatiepaal v21-2:ø300 (schroef):1507075
In: -2 fundering
Classification: Vloerplaat - fundering (ARCHICAD Classification); Material: WSP_beton - ihwg beton
Pset_SlabCommon - Reference: ø300 (schroef); IsExternal: yes; LoadBearing: no
Pset_ReinforcementBarPitchOfSlab - Reference: ø300 (schroef)
Component Quantities - WSP_beton - ihwg beton, Mass: 903.056 kg; WSP_beton - ihwg beton, Component Volume (Net): 0.392633 m3; WSP_beton - ihwg beton, Component Volume (Gross): 0.392633 m3
CPset_Phasing - Renovation Phase: Bestaand

# IfcSlab: Slab 54, 17_WSP_FD_beton - fundatiepaal v21-2:ø300 (schroef):1473613
In: -2 fundering
Classification: Vloerplaat - fundering (ARCHICAD Classification); Material: WSP_beton - ihwg beton
Pset_ReinforcementBarPitchOfSlab - Reference: ø300 (schroef)
Pset_SlabCommon - Reference: ø300 (schroef); IsExternal: yes; LoadBearing: no
CPset_Phasing - Renovation Phase: Bestaand
Component Quantities - WSP_beton - ihwg beton, Mass: 887.213 kg; WSP_beton - ihwg beton, Component Volume (Net): 0.385745 m3; WSP_beton - ihwg beton, Component Volume (Gross): 0.385745 m3

# IfcSlab: Slab 540, 17_WSP_FD_beton - fundatiepaal v21-2:ø300 (schroef):1507074
In: -2 fundering
Classification: Vloerplaat - fundering (ARCHICAD Classification); Material: WSP_beton - ihwg beton
Pset_ReinforcementBarPitchOfSlab - Reference: ø300 (schroef)
CPset_Phasing - Renovation Phase: Bestaand
Component Quantities - WSP_beton - ihwg beton, Mass: 903.056 kg; WSP_beton - ihwg beton, Component Volume (Net): 0.392633 m3; WSP_beton - ihwg beton, Component Volume (Gross): 0.392633 m3
Pset_SlabCommon - Reference: ø300 (schroef); IsExternal: yes; LoadBearing: no

# IfcSlab: Slab 541, 17_WSP_FD_beton - fundatiepaal v21-2:ø300 (schroef):1507073
In: -2 fundering
Classification: Vloerplaat - fundering (ARCHICAD Classification); Material: WSP_beton - ihwg beton
Pset_SlabCommon - Reference: ø300 (schroef); IsExternal: yes; LoadBearing: no
Pset_ReinforcementBarPitchOfSlab - Reference: ø300 (schroef)
CPset_Phasing - Renovation Phase: Bestaand
Component Quantities - WSP_beton - ihwg beton, Mass: 903.056 kg; WSP_beton - ihwg beton, Component Volume (Net): 0.392633 m3; WSP_beton - ihwg beton, Component Volume (Gross): 0.392633 m3

# IfcSlab: Slab 542, 17_WSP_FD_beton - fundatiepaal v21-2:ø300 (schroef):1507072
In: -2 fundering
Classification: Vloerplaat - fundering (ARCHICAD Classification); Material: WSP_beton - ihwg beton
Component Quantities - WSP_beton - ihwg beton, Mass: 887.213 kg; WSP_beton - ihwg beton, Component Volume (Net): 0.385745 m3; WSP_beton - ihwg beton, Component Volume (Gross): 0.385745 m3
CPset_Phasing - Renovation Phase: Bestaand
Pset_ReinforcementBarPitchOfSlab - Reference: ø300 (schroef)
Pset_SlabCommon - Reference: ø300 (schroef); IsExternal: yes; LoadBearing: no

# IfcSlab: Slab 543, 17_WSP_FD_beton - fundatiepaal v21-2:ø300 (schroef):1507103
In: -2 fundering
Classification: Vloerplaat - fundering (ARCHICAD Classification); Material: WSP_beton - ihwg beton
Pset_SlabCommon - Reference: ø300 (schroef); IsExternal: yes; LoadBearing: no
Pset_ReinforcementBarPitchOfSlab - Reference: ø300 (schroef)
CPset_Phasing - Renovation Phase: Bestaand
Component Quantities - WSP_beton - ihwg beton, Mass: 903.056 kg; WSP_beton - ihwg beton, Component Volume (Net): 0.392633 m3; WSP_beton - ihwg beton, Component Volume (Gross): 0.392633 m3

# IfcSlab: Slab 544, 17_WSP_FD_beton - fundatiepaal v21-2:ø300 (schroef):1507102
In: -2 fundering
Classification: Vloerplaat - fundering (ARCHICAD Classification); Material: WSP_beton - ihwg beton
Pset_SlabCommon - Reference: ø300 (schroef); IsExternal: yes; LoadBearing: no
CPset_Phasing - Renovation Phase: Bestaand
Component Quantities - WSP_beton - ihwg beton, Mass: 903.056 kg; WSP_beton - ihwg beton, Component Volume (Net): 0.392633 m3; WSP_beton - ihwg beton, Component Volume (Gross): 0.392633 m3
Pset_ReinforcementBarPitchOfSlab - Reference: ø300 (schroef)

# IfcSlab: Slab 545, 17_WSP_FD_beton - fundatiepaal v21-2:ø300 (schroef):1507101
In: -2 fundering
Classification: Vloerplaat - fundering (ARCHICAD Classification); Material: WSP_beton - ihwg beton
Component Quantities - WSP_beton - ihwg beton, Mass: 903.056 kg; WSP_beton - ihwg beton, Component Volume (Net): 0.392633 m3; WSP_beton - ihwg beton, Component Volume (Gross): 0.392633 m3
Pset_ReinforcementBarPitchOfSlab - Reference: ø300 (schroef)
Pset_SlabCommon - Reference: ø300 (schroef); IsExternal: yes; LoadBearing: no
CPset_Phasing - Renovation Phase: Bestaand

# IfcSlab: Slab 546, 17_WSP_FD_beton - fundatiepaal v21-2:ø300 (schroef):1507100
In: -2 fundering
Classification: Vloerplaat - fundering (ARCHICAD Classification); Material: WSP_beton - ihwg beton
Pset_SlabCommon - Reference: ø300 (schroef); IsExternal: yes; LoadBearing: no
Component Quantities - WSP_beton - ihwg beton, Mass: 903.056 kg; WSP_beton - ihwg beton, Component Volume (Net): 0.392633 m3; WSP_beton - ihwg beton, Component Volume (Gross): 0.392633 m3
Pset_ReinforcementBarPitchOfSlab - Reference: ø300 (schroef)
CPset_Phasing - Renovation Phase: Bestaand

# IfcSlab: Slab 547, 17_WSP_FD_beton - fundatiepaal v21-2:ø300 (schroef):1507099
In: -2 fundering
Classification: Vloerplaat - fundering (ARCHICAD Classification); Material: WSP_beton - ihwg beton
Pset_SlabCommon - Reference: ø300 (schroef); IsExternal: yes; LoadBearing: no
Component Quantities - WSP_beton - ihwg beton, Mass: 903.056 kg; WSP_beton - ihwg beton, Component Volume (Net): 0.392633 m3; WSP_beton - ihwg beton, Component Volume (Gross): 0.392633 m3
CPset_Phasing - Renovation Phase: Bestaand
Pset_ReinforcementBarPitchOfSlab - Reference: ø300 (schroef)

# IfcSlab: Slab 548, 17_WSP_FD_beton - fundatiepaal v21-2:ø300 (schroef):1507098
In: -2 fundering
Classification: Vloerplaat - fundering (ARCHICAD Classification); Material: WSP_beton - ihwg beton
Pset_SlabCommon - Reference: ø300 (schroef); IsExternal: yes; LoadBearing: no
Pset_ReinforcementBarPitchOfSlab - Reference: ø300 (schroef)
Component Quantities - WSP_beton - ihwg beton, Mass: 903.056 kg; WSP_beton - ihwg beton, Component Volume (Net): 0.392633 m3; WSP_beton - ihwg beton, Component Volume (Gross): 0.392633 m3
CPset_Phasing - Renovation Phase: Bestaand

# IfcSlab: Slab 549, 17_WSP_FD_beton - fundatiepaal v21-2:ø300 (schroef):1507097
In: -2 fundering
Classification: Vloerplaat - fundering (ARCHICAD Classification); Material: WSP_beton - ihwg beton
Pset_SlabCommon - Reference: ø300 (schroef); IsExternal: yes; LoadBearing: no
Pset_ReinforcementBarPitchOfSlab - Reference: ø300 (schroef)
CPset_Phasing - Renovation Phase: Bestaand
Component Quantities - WSP_beton - ihwg beton, Mass: 903.056 kg; WSP_beton - ihwg beton, Component Volume (Net): 0.392633 m3; WSP_beton - ihwg beton, Component Volume (Gross): 0.392633 m3

# IfcSlab: Slab 55, 17_WSP_FD_beton - fundatiepaal v21-2:ø300 (schroef):1473618
In: -2 fundering
Classification: Vloerplaat - fundering (ARCHICAD Classification); Material: WSP_beton - ihwg beton
Pset_SlabCommon - Reference: ø300 (schroef); IsExternal: yes; LoadBearing: no
Pset_ReinforcementBarPitchOfSlab - Reference: ø300 (schroef)
Component Quantities - WSP_beton - ihwg beton, Mass: 887.213 kg; WSP_beton - ihwg beton, Component Volume (Net): 0.385745 m3; WSP_beton - ihwg beton, Component Volume (Gross): 0.385745 m3
CPset_Phasing - Renovation Phase: Bestaand

# IfcSlab: Slab 550, 17_WSP_FD_beton - fundatiepaal v21-2:ø300 (schroef):1507096
In: -2 fundering
Classification: Vloerplaat - fundering (ARCHICAD Classification); Material: WSP_beton - ihwg beton
Pset_SlabCommon - Reference: ø300 (schroef); IsExternal: yes; LoadBearing: no
CPset_Phasing - Renovation Phase: Bestaand
Pset_ReinforcementBarPitchOfSlab - Reference: ø300 (schroef)
Component Quantities - WSP_beton - ihwg beton, Mass: 903.056 kg; WSP_beton - ihwg beton, Component Volume (Net): 0.392633 m3; WSP_beton - ihwg beton, Component Volume (Gross): 0.392633 m3

# IfcSlab: Slab 551, 17_WSP_FD_beton - fundatiepaal v21-2:ø300 (schroef):1507095
In: -2 fundering
Classification: Vloerplaat - fundering (ARCHICAD Classification); Material: WSP_beton - ihwg beton
Pset_ReinforcementBarPitchOfSlab - Reference: ø300 (schroef)
Pset_SlabCommon - Reference: ø300 (schroef); IsExternal: yes; LoadBearing: no
CPset_Phasing - Renovation Phase: Bestaand
Component Quantities - WSP_beton - ihwg beton, Mass: 903.056 kg; WSP_beton - ihwg beton, Component Volume (Net): 0.392633 m3; WSP_beton - ihwg beton, Component Volume (Gross): 0.392633 m3

# IfcSlab: Slab 552, 17_WSP_FD_beton - fundatiepaal v21-2:ø300 (schroef):1507094
In: -2 fundering
Classification: Vloerplaat - fundering (ARCHICAD Classification); Material: WSP_beton - ihwg beton
Pset_SlabCommon - Reference: ø300 (schroef); IsExternal: yes; LoadBearing: no
Component Quantities - WSP_beton - ihwg beton, Mass: 903.056 kg; WSP_beton - ihwg beton, Component Volume (Net): 0.392633 m3; WSP_beton - ihwg beton, Component Volume (Gross): 0.392633 m3
Pset_ReinforcementBarPitchOfSlab - Reference: ø300 (schroef)
CPset_Phasing - Renovation Phase: Bestaand

# IfcSlab: Slab 553, 17_WSP_FD_beton - fundatiepaal v21-2:ø300 (schroef):1507093
In: -2 fundering
Classification: Vloerplaat - fundering (ARCHICAD Classification); Material: WSP_beton - ihwg beton
Pset_SlabCommon - Reference: ø300 (schroef); IsExternal: yes; LoadBearing: no
Pset_ReinforcementBarPitchOfSlab - Reference: ø300 (schroef)
Component Quantities - WSP_beton - ihwg beton, Mass: 903.056 kg; WSP_beton - ihwg beton, Component Volume (Net): 0.392633 m3; WSP_beton - ihwg beton, Component Volume (Gross): 0.392633 m3
CPset_Phasing - Renovation Phase: Bestaand

# IfcSlab: Slab 554, 17_WSP_FD_beton - fundatiepaal v21-2:ø300 (schroef):1507092
In: -2 fundering
Classification: Vloerplaat - fundering (ARCHICAD Classification); Material: WSP_beton - ihwg beton
Pset_ReinforcementBarPitchOfSlab - Reference: ø300 (schroef)
Pset_SlabCommon - Reference: ø300 (schroef); IsExternal: yes; LoadBearing: no
CPset_Phasing - Renovation Phase: Bestaand
Component Quantities - WSP_beton - ihwg beton, Mass: 903.056 kg; WSP_beton - ihwg beton, Component Volume (Net): 0.392633 m3; WSP_beton - ihwg beton, Component Volume (Gross): 0.392633 m3

# IfcSlab: Slab 555, 17_WSP_FD_beton - fundatiepaal v21-2:ø300 (schroef):1507091
In: -2 fundering
Classification: Vloerplaat - fundering (ARCHICAD Classification); Material: WSP_beton - ihwg beton
Pset_SlabCommon - Reference: ø300 (schroef); IsExternal: yes; LoadBearing: no
Pset_ReinforcementBarPitchOfSlab - Reference: ø300 (schroef)
Component Quantities - WSP_beton - ihwg beton, Mass: 903.056 kg; WSP_beton - ihwg beton, Component Volume (Net): 0.392633 m3; WSP_beton - ihwg beton, Component Volume (Gross): 0.392633 m3
CPset_Phasing - Renovation Phase: Bestaand

# IfcSlab: Slab 556, 17_WSP_FD_beton - fundatiepaal v21-2:ø300 (schroef):1507090
In: -2 fundering
Classification: Vloerplaat - fundering (ARCHICAD Classification); Material: WSP_beton - ihwg beton
CPset_Phasing - Renovation Phase: Bestaand
Pset_ReinforcementBarPitchOfSlab - Reference: ø300 (schroef)
Pset_SlabCommon - Reference: ø300 (schroef); IsExternal: yes; LoadBearing: no
Component Quantities - WSP_beton - ihwg beton, Mass: 903.056 kg; WSP_beton - ihwg beton, Component Volume (Net): 0.392633 m3; WSP_beton - ihwg beton, Component Volume (Gross): 0.392633 m3

# IfcSlab: Slab 557, 17_WSP_FD_beton - fundatiepaal v21-2:ø300 (schroef):1507089
In: -2 fundering
Classification: Vloerplaat - fundering (ARCHICAD Classification); Material: WSP_beton - ihwg beton
Pset_SlabCommon - Reference: ø300 (schroef); IsExternal: yes; LoadBearing: no
Pset_ReinforcementBarPitchOfSlab - Reference: ø300 (schroef)
Component Quantities - WSP_beton - ihwg beton, Mass: 903.056 kg; WSP_beton - ihwg beton, Component Volume (Net): 0.392633 m3; WSP_beton - ihwg beton, Component Volume (Gross): 0.392633 m3
CPset_Phasing - Renovation Phase: Bestaand

# IfcSlab: Slab 558, 17_WSP_FD_beton - fundatiepaal v21-2:ø300 (schroef):1507088
In: -2 fundering
Classification: Vloerplaat - fundering (ARCHICAD Classification); Material: WSP_beton - ihwg beton
CPset_Phasing - Renovation Phase: Bestaand
Pset_SlabCommon - Reference: ø300 (schroef); IsExternal: yes; LoadBearing: no
Pset_ReinforcementBarPitchOfSlab - Reference: ø300 (schroef)
Component Quantities - WSP_beton - ihwg beton, Mass: 903.056 kg; WSP_beton - ihwg beton, Component Volume (Net): 0.392633 m3; WSP_beton - ihwg beton, Component Volume (Gross): 0.392633 m3

# IfcSlab: Slab 559, 17_WSP_FD_beton - fundatiepaal v21-2:ø300 (schroef):1507183
In: -2 fundering
Classification: Vloerplaat - fundering (ARCHICAD Classification); Material: WSP_beton - ihwg beton
Pset_ReinforcementBarPitchOfSlab - Reference: ø300 (schroef)
Pset_SlabCommon - Reference: ø300 (schroef); IsExternal: yes; LoadBearing: no
Component Quantities - WSP_beton - ihwg beton, Mass: 903.056 kg; WSP_beton - ihwg beton, Component Volume (Net): 0.392633 m3; WSP_beton - ihwg beton, Component Volume (Gross): 0.392633 m3
CPset_Phasing - Renovation Phase: Bestaand

# IfcSlab: Slab 56, 17_WSP_FD_beton - fundatiepaal v21-2:ø300 (schroef):1473619
In: -2 fundering
Classification: Vloerplaat - fundering (ARCHICAD Classification); Material: WSP_beton - ihwg beton
Pset_SlabCommon - Reference: ø300 (schroef); IsExternal: yes; LoadBearing: no
Component Quantities - WSP_beton - ihwg beton, Mass: 887.213 kg; WSP_beton - ihwg beton, Component Volume (Net): 0.385745 m3; WSP_beton - ihwg beton, Component Volume (Gross): 0.385745 m3
CPset_Phasing - Renovation Phase: Bestaand
Pset_ReinforcementBarPitchOfSlab - Reference: ø300 (schroef)

# IfcSlab: Slab 560, 17_WSP_FD_beton - fundatiepaal v21-2:ø300 (schroef):1507182
In: -2 fundering
Classification: Vloerplaat - fundering (ARCHICAD Classification); Material: WSP_beton - ihwg beton
Pset_SlabCommon - Reference: ø300 (schroef); IsExternal: yes; LoadBearing: no
Pset_ReinforcementBarPitchOfSlab - Reference: ø300 (schroef)
CPset_Phasing - Renovation Phase: Bestaand
Component Quantities - WSP_beton - ihwg beton, Mass: 903.056 kg; WSP_beton - ihwg beton, Component Volume (Net): 0.392633 m3; WSP_beton - ihwg beton, Component Volume (Gross): 0.392633 m3

# IfcSlab: Slab 561, 17_WSP_FD_beton - fundatiepaal v21-2:ø300 (schroef):1507181
In: -2 fundering
Classification: Vloerplaat - fundering (ARCHICAD Classification); Material: WSP_beton - ihwg beton
Pset_SlabCommon - Reference: ø300 (schroef); IsExternal: yes; LoadBearing: no
Pset_ReinforcementBarPitchOfSlab - Reference: ø300 (schroef)
CPset_Phasing - Renovation Phase: Bestaand
Component Quantities - WSP_beton - ihwg beton, Mass: 903.056 kg; WSP_beton - ihwg beton, Component Volume (Net): 0.392633 m3; WSP_beton - ihwg beton, Component Volume (Gross): 0.392633 m3

# IfcSlab: Slab 562, 17_WSP_FD_beton - fundatiepaal v21-2:ø300 (schroef):1507180
In: -2 fundering
Classification: Vloerplaat - fundering (ARCHICAD Classification); Material: WSP_beton - ihwg beton
Pset_SlabCommon - Reference: ø300 (schroef); IsExternal: yes; LoadBearing: no
Pset_ReinforcementBarPitchOfSlab - Reference: ø300 (schroef)
CPset_Phasing - Renovation Phase: Bestaand
Component Quantities - WSP_beton - ihwg beton, Mass: 903.056 kg; WSP_beton - ihwg beton, Component Volume (Net): 0.392633 m3; WSP_beton - ihwg beton, Component Volume (Gross): 0.392633 m3

# IfcSlab: Slab 563, 17_WSP_FD_beton - fundatiepaal v21-2:ø300 (schroef):1507179
In: -2 fundering
Classification: Vloerplaat - fundering (ARCHICAD Classification); Material: WSP_beton - ihwg beton
CPset_Phasing - Renovation Phase: Bestaand
Pset_ReinforcementBarPitchOfSlab - Reference: ø300 (schroef)
Pset_SlabCommon - Reference: ø300 (schroef); IsExternal: yes; LoadBearing: no
Component Quantities - WSP_beton - ihwg beton, Mass: 903.056 kg; WSP_beton - ihwg beton, Component Volume (Net): 0.392633 m3; WSP_beton - ihwg beton, Component Volume (Gross): 0.392633 m3

# IfcSlab: Slab 564, 17_WSP_FD_beton - fundatiepaal v21-2:ø300 (schroef):1507178
In: -2 fundering
Classification: Vloerplaat - fundering (ARCHICAD Classification); Material: WSP_beton - ihwg beton
Pset_SlabCommon - Reference: ø300 (schroef); IsExternal: yes; LoadBearing: no
Pset_ReinforcementBarPitchOfSlab - Reference: ø300 (schroef)
CPset_Phasing - Renovation Phase: Bestaand
Component Quantities - WSP_beton - ihwg beton, Mass: 903.056 kg; WSP_beton - ihwg beton, Component Volume (Net): 0.392633 m3; WSP_beton - ihwg beton, Component Volume (Gross): 0.392633 m3

# IfcSlab: Slab 565, 17_WSP_FD_beton - fundatiepaal v21-2:ø300 (schroef):1507177
In: -2 fundering
Classification: Vloerplaat - fundering (ARCHICAD Classification); Material: WSP_beton - ihwg beton
Pset_SlabCommon - Reference: ø300 (schroef); IsExternal: yes; LoadBearing: no
Component Quantities - WSP_beton - ihwg beton, Mass: 903.056 kg; WSP_beton - ihwg beton, Component Volume (Net): 0.392633 m3; WSP_beton - ihwg beton, Component Volume (Gross): 0.392633 m3
CPset_Phasing - Renovation Phase: Bestaand
Pset_ReinforcementBarPitchOfSlab - Reference: ø300 (schroef)

# IfcSlab: Slab 566, 17_WSP_FD_beton - fundatiepaal v21-2:ø300 (schroef):1507176
In: -2 fundering
Classification: Vloerplaat - fundering (ARCHICAD Classification); Material: WSP_beton - ihwg beton
Pset_ReinforcementBarPitchOfSlab - Reference: ø300 (schroef)
Component Quantities - WSP_beton - ihwg beton, Mass: 903.056 kg; WSP_beton - ihwg beton, Component Volume (Net): 0.392633 m3; WSP_beton - ihwg beton, Component Volume (Gross): 0.392633 m3
CPset_Phasing - Renovation Phase: Bestaand
Pset_SlabCommon - Reference: ø300 (schroef); IsExternal: yes; LoadBearing: no

# IfcSlab: Slab 567, 17_WSP_FD_beton - fundatiepaal v21-2:ø300 (schroef):1507175
In: -2 fundering
Classification: Vloerplaat - fundering (ARCHICAD Classification); Material: WSP_beton - ihwg beton
Pset_SlabCommon - Reference: ø300 (schroef); IsExternal: yes; LoadBearing: no
CPset_Phasing - Renovation Phase: Bestaand
Pset_ReinforcementBarPitchOfSlab - Reference: ø300 (schroef)
Component Quantities - WSP_beton - ihwg beton, Mass: 903.056 kg; WSP_beton - ihwg beton, Component Volume (Net): 0.392633 m3; WSP_beton - ihwg beton, Component Volume (Gross): 0.392633 m3

# IfcSlab: Slab 568, 17_WSP_FD_beton - fundatiepaal v21-2:ø300 (schroef):1507174
In: -2 fundering
Classification: Vloerplaat - fundering (ARCHICAD Classification); Material: WSP_beton - ihwg beton
Pset_SlabCommon - Reference: ø300 (schroef); IsExternal: yes; LoadBearing: no
Pset_ReinforcementBarPitchOfSlab - Reference: ø300 (schroef)
CPset_Phasing - Renovation Phase: Bestaand
Component Quantities - WSP_beton - ihwg beton, Mass: 903.056 kg; WSP_beton - ihwg beton, Component Volume (Net): 0.392633 m3; WSP_beton - ihwg beton, Component Volume (Gross): 0.392633 m3

# IfcSlab: Slab 569, 17_WSP_FD_beton - fundatiepaal v21-2:ø300 (schroef):1507173
In: -2 fundering
Classification: Vloerplaat - fundering (ARCHICAD Classification); Material: WSP_beton - ihwg beton
Pset_SlabCommon - Reference: ø300 (schroef); IsExternal: yes; LoadBearing: no
Pset_ReinforcementBarPitchOfSlab - Reference: ø300 (schroef)
Component Quantities - WSP_beton - ihwg beton, Mass: 903.056 kg; WSP_beton - ihwg beton, Component Volume (Net): 0.392633 m3; WSP_beton - ihwg beton, Component Volume (Gross): 0.392633 m3
CPset_Phasing - Renovation Phase: Bestaand

# IfcSlab: Slab 57, 17_WSP_FD_beton - fundatiepaal v21-2:ø300 (schroef):1473616
In: -2 fundering
Classification: Vloerplaat - fundering (ARCHICAD Classification); Material: WSP_beton - ihwg beton
Pset_SlabCommon - Reference: ø300 (schroef); IsExternal: yes; LoadBearing: no
Pset_ReinforcementBarPitchOfSlab - Reference: ø300 (schroef)
CPset_Phasing - Renovation Phase: Bestaand
Component Quantities - WSP_beton - ihwg beton, Mass: 887.213 kg; WSP_beton - ihwg beton, Component Volume (Net): 0.385745 m3; WSP_beton - ihwg beton, Component Volume (Gross): 0.385745 m3

# IfcSlab: Slab 570, 17_WSP_FD_beton - fundatiepaal v21-2:ø300 (schroef):1507172
In: -2 fundering
Classification: Vloerplaat - fundering (ARCHICAD Classification); Material: WSP_beton - ihwg beton
CPset_Phasing - Renovation Phase: Bestaand
Pset_ReinforcementBarPitchOfSlab - Reference: ø300 (schroef)
Component Quantities - WSP_beton - ihwg beton, Mass: 903.056 kg; WSP_beton - ihwg beton, Component Volume (Net): 0.392633 m3; WSP_beton - ihwg beton, Component Volume (Gross): 0.392633 m3
Pset_SlabCommon - Reference: ø300 (schroef); IsExternal: yes; LoadBearing: no

# IfcSlab: Slab 571, 17_WSP_FD_beton - fundatiepaal v21-2:ø300 (schroef):1507171
In: -2 fundering
Classification: Vloerplaat - fundering (ARCHICAD Classification); Material: WSP_beton - ihwg beton
Pset_ReinforcementBarPitchOfSlab - Reference: ø300 (schroef)
Component Quantities - WSP_beton - ihwg beton, Mass: 903.056 kg; WSP_beton - ihwg beton, Component Volume (Net): 0.392633 m3; WSP_beton - ihwg beton, Component Volume (Gross): 0.392633 m3
Pset_SlabCommon - Reference: ø300 (schroef); IsExternal: yes; LoadBearing: no
CPset_Phasing - Renovation Phase: Bestaand

# IfcSlab: Slab 572, 17_WSP_FD_beton - fundatiepaal v21-2:ø300 (schroef):1507170
In: -2 fundering
Classification: Vloerplaat - fundering (ARCHICAD Classification); Material: WSP_beton - ihwg beton
Pset_SlabCommon - Reference: ø300 (schroef); IsExternal: yes; LoadBearing: no
Pset_ReinforcementBarPitchOfSlab - Reference: ø300 (schroef)
Component Quantities - WSP_beton - ihwg beton, Mass: 903.056 kg; WSP_beton - ihwg beton, Component Volume (Net): 0.392633 m3; WSP_beton - ihwg beton, Component Volume (Gross): 0.392633 m3
CPset_Phasing - Renovation Phase: Bestaand

# IfcSlab: Slab 573, 17_WSP_FD_beton - fundatiepaal v21-2:ø300 (schroef):1507169
In: -2 fundering
Classification: Vloerplaat - fundering (ARCHICAD Classification); Material: WSP_beton - ihwg beton
Pset_SlabCommon - Reference: ø300 (schroef); IsExternal: yes; LoadBearing: no
Component Quantities - WSP_beton - ihwg beton, Mass: 903.056 kg; WSP_beton - ihwg beton, Component Volume (Net): 0.392633 m3; WSP_beton - ihwg beton, Component Volume (Gross): 0.392633 m3
Pset_ReinforcementBarPitchOfSlab - Reference: ø300 (schroef)
CPset_Phasing - Renovation Phase: Bestaand

# IfcSlab: Slab 574, 17_WSP_FD_beton - fundatiepaal v21-2:ø300 (schroef):1507168
In: -2 fundering
Classification: Vloerplaat - fundering (ARCHICAD Classification); Material: WSP_beton - ihwg beton
Pset_SlabCommon - Reference: ø300 (schroef); IsExternal: yes; LoadBearing: no
Pset_ReinforcementBarPitchOfSlab - Reference: ø300 (schroef)
CPset_Phasing - Renovation Phase: Bestaand
Component Quantities - WSP_beton - ihwg beton, Mass: 903.056 kg; WSP_beton - ihwg beton, Component Volume (Net): 0.392633 m3; WSP_beton - ihwg beton, Component Volume (Gross): 0.392633 m3

# IfcSlab: Slab 575, 17_WSP_FD_beton - fundatiepaal v21-2:ø300 (schroef):1507199
In: -2 fundering
Classification: Vloerplaat - fundering (ARCHICAD Classification); Material: WSP_beton - ihwg beton
Pset_SlabCommon - Reference: ø300 (schroef); IsExternal: yes; LoadBearing: no
Pset_ReinforcementBarPitchOfSlab - Reference: ø300 (schroef)
CPset_Phasing - Renovation Phase: Bestaand
Component Quantities - WSP_beton - ihwg beton, Mass: 903.056 kg; WSP_beton - ihwg beton, Component Volume (Net): 0.392633 m3; WSP_beton - ihwg beton, Component Volume (Gross): 0.392633 m3

# IfcSlab: Slab 576, 17_WSP_FD_beton - fundatiepaal v21-2:ø300 (schroef):1507198
In: -2 fundering
Classification: Vloerplaat - fundering (ARCHICAD Classification); Material: WSP_beton - ihwg beton
Pset_SlabCommon - Reference: ø300 (schroef); IsExternal: yes; LoadBearing: no
Pset_ReinforcementBarPitchOfSlab - Reference: ø300 (schroef)
CPset_Phasing - Renovation Phase: Bestaand
Component Quantities - WSP_beton - ihwg beton, Mass: 903.056 kg; WSP_beton - ihwg beton, Component Volume (Net): 0.392633 m3; WSP_beton - ihwg beton, Component Volume (Gross): 0.392633 m3

# IfcSlab: Slab 577, 17_WSP_FD_beton - fundatiepaal v21-2:ø300 (schroef):1507197
In: -2 fundering
Classification: Vloerplaat - fundering (ARCHICAD Classification); Material: WSP_beton - ihwg beton
Pset_SlabCommon - Reference: ø300 (schroef); IsExternal: yes; LoadBearing: no
Component Quantities - WSP_beton - ihwg beton, Mass: 903.056 kg; WSP_beton - ihwg beton, Component Volume (Net): 0.392633 m3; WSP_beton - ihwg beton, Component Volume (Gross): 0.392633 m3
Pset_ReinforcementBarPitchOfSlab - Reference: ø300 (schroef)
CPset_Phasing - Renovation Phase: Bestaand

# IfcSlab: Slab 578, 17_WSP_FD_beton - fundatiepaal v21-2:ø300 (schroef):1507196
In: -2 fundering
Classification: Vloerplaat - fundering (ARCHICAD Classification); Material: WSP_beton - ihwg beton
Pset_SlabCommon - Reference: ø300 (schroef); IsExternal: yes; LoadBearing: no
CPset_Phasing - Renovation Phase: Bestaand
Pset_ReinforcementBarPitchOfSlab - Reference: ø300 (schroef)
Component Quantities - WSP_beton - ihwg beton, Mass: 903.056 kg; WSP_beton - ihwg beton, Component Volume (Net): 0.392633 m3; WSP_beton - ihwg beton, Component Volume (Gross): 0.392633 m3

# IfcSlab: Slab 579, 17_WSP_FD_beton - fundatiepaal v21-2:ø300 (schroef):1507195
In: -2 fundering
Classification: Vloerplaat - fundering (ARCHICAD Classification); Material: WSP_beton - ihwg beton
Pset_SlabCommon - Reference: ø300 (schroef); IsExternal: yes; LoadBearing: no
Pset_ReinforcementBarPitchOfSlab - Reference: ø300 (schroef)
Component Quantities - WSP_beton - ihwg beton, Mass: 903.056 kg; WSP_beton - ihwg beton, Component Volume (Net): 0.392633 m3; WSP_beton - ihwg beton, Component Volume (Gross): 0.392633 m3
CPset_Phasing - Renovation Phase: Bestaand

# IfcSlab: Slab 58, 17_WSP_FD_beton - fundatiepaal v21-2:ø300 (schroef):1473617
In: -2 fundering
Classification: Vloerplaat - fundering (ARCHICAD Classification); Material: WSP_beton - ihwg beton
Pset_SlabCommon - Reference: ø300 (schroef); IsExternal: yes; LoadBearing: no
CPset_Phasing - Renovation Phase: Bestaand
Pset_ReinforcementBarPitchOfSlab - Reference: ø300 (schroef)
Component Quantities - WSP_beton - ihwg beton, Mass: 887.213 kg; WSP_beton - ihwg beton, Component Volume (Net): 0.385745 m3; WSP_beton - ihwg beton, Component Volume (Gross): 0.385745 m3

# IfcSlab: Slab 580, 17_WSP_FD_beton - fundatiepaal v21-2:ø300 (schroef):1507194
In: -2 fundering
Classification: Vloerplaat - fundering (ARCHICAD Classification); Material: WSP_beton - ihwg beton
Pset_SlabCommon - Reference: ø300 (schroef); IsExternal: yes; LoadBearing: no
Pset_ReinforcementBarPitchOfSlab - Reference: ø300 (schroef)
Component Quantities - WSP_beton - ihwg beton, Mass: 903.056 kg; WSP_beton - ihwg beton, Component Volume (Net): 0.392633 m3; WSP_beton - ihwg beton, Component Volume (Gross): 0.392633 m3
CPset_Phasing - Renovation Phase: Bestaand

# IfcSlab: Slab 581, 17_WSP_FD_beton - fundatiepaal v21-2:ø300 (schroef):1507193
In: -2 fundering
Classification: Vloerplaat - fundering (ARCHICAD Classification); Material: WSP_beton - ihwg beton
Pset_SlabCommon - Reference: ø300 (schroef); IsExternal: yes; LoadBearing: no
CPset_Phasing - Renovation Phase: Bestaand
Pset_ReinforcementBarPitchOfSlab - Reference: ø300 (schroef)
Component Quantities - WSP_beton - ihwg beton, Mass: 903.056 kg; WSP_beton - ihwg beton, Component Volume (Net): 0.392633 m3; WSP_beton - ihwg beton, Component Volume (Gross): 0.392633 m3

# IfcSlab: Slab 582, 17_WSP_FD_beton - fundatiepaal v21-2:ø300 (schroef):1507192
In: -2 fundering
Classification: Vloerplaat - fundering (ARCHICAD Classification); Material: WSP_beton - ihwg beton
Pset_SlabCommon - Reference: ø300 (schroef); IsExternal: yes; LoadBearing: no
Pset_ReinforcementBarPitchOfSlab - Reference: ø300 (schroef)
CPset_Phasing - Renovation Phase: Bestaand
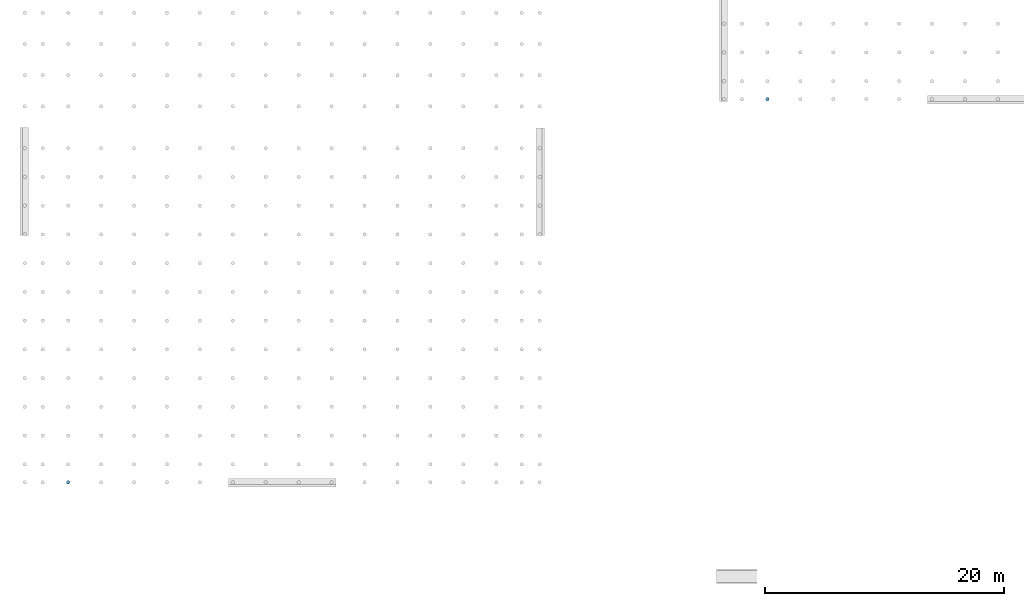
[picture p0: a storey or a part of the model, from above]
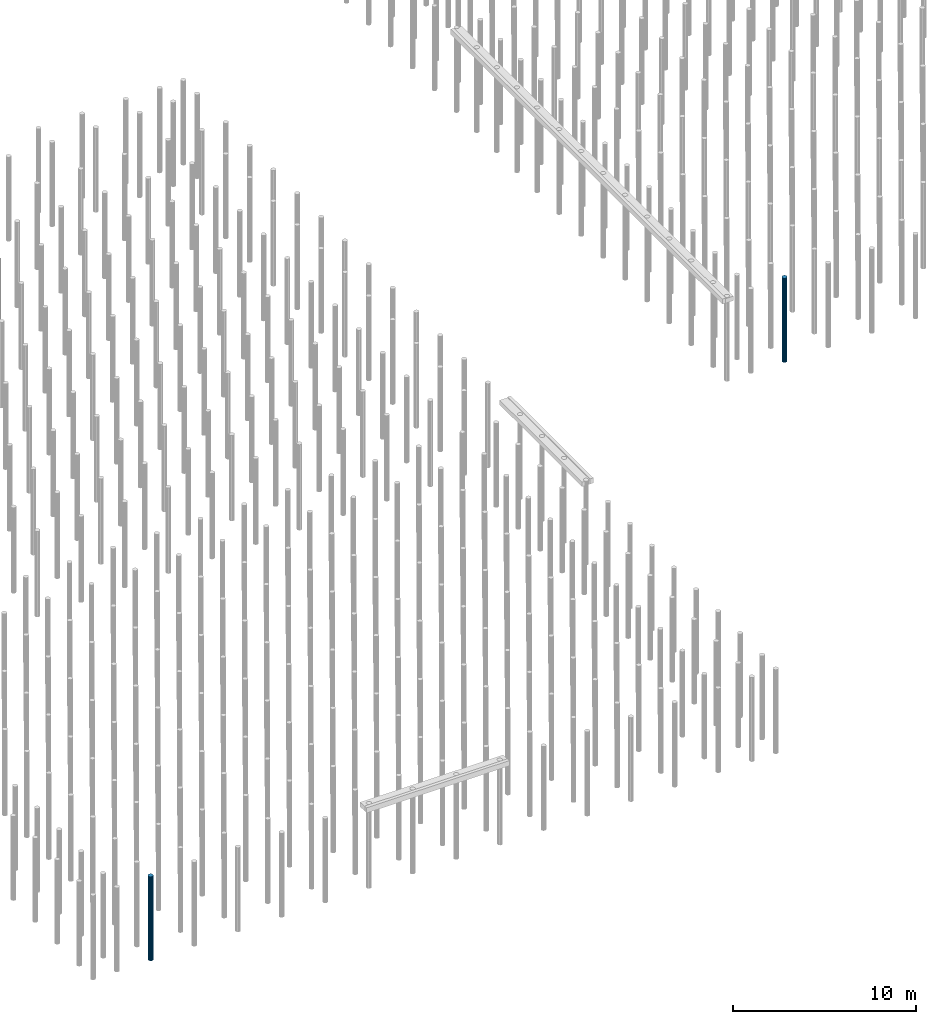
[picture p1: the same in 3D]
Properties of the parts of a building model (IFC2X3), part 8 of 13

# IfcSlab: Slab 582, 17_WSP_FD_beton - fundatiepaal v21-2:ø300 (schroef):1507192
Component Quantities - WSP_beton - ihwg beton, Mass: 903.056 kg; WSP_beton - ihwg beton, Component Volume (Net): 0.392633 m3; WSP_beton - ihwg beton, Component Volume (Gross): 0.392633 m3

# IfcSlab: Slab 583, 17_WSP_FD_beton - fundatiepaal v21-2:ø300 (schroef):1507191
In: -2 fundering
Classification: Vloerplaat - fundering (ARCHICAD Classification); Material: WSP_beton - ihwg beton
Component Quantities - WSP_beton - ihwg beton, Mass: 903.056 kg; WSP_beton - ihwg beton, Component Volume (Net): 0.392633 m3; WSP_beton - ihwg beton, Component Volume (Gross): 0.392633 m3
CPset_Phasing - Renovation Phase: Bestaand
Pset_ReinforcementBarPitchOfSlab - Reference: ø300 (schroef)
Pset_SlabCommon - Reference: ø300 (schroef); IsExternal: yes; LoadBearing: no

# IfcSlab: Slab 584, 17_WSP_FD_beton - fundatiepaal v21-2:ø300 (schroef):1507190
In: -2 fundering
Classification: Vloerplaat - fundering (ARCHICAD Classification); Material: WSP_beton - ihwg beton
Pset_ReinforcementBarPitchOfSlab - Reference: ø300 (schroef)
Pset_SlabCommon - Reference: ø300 (schroef); IsExternal: yes; LoadBearing: no
CPset_Phasing - Renovation Phase: Bestaand
Component Quantities - WSP_beton - ihwg beton, Mass: 903.056 kg; WSP_beton - ihwg beton, Component Volume (Net): 0.392633 m3; WSP_beton - ihwg beton, Component Volume (Gross): 0.392633 m3

# IfcSlab: Slab 585, 17_WSP_FD_beton - fundatiepaal v21-2:ø300 (schroef):1507189
In: -2 fundering
Classification: Vloerplaat - fundering (ARCHICAD Classification); Material: WSP_beton - ihwg beton
CPset_Phasing - Renovation Phase: Bestaand
Pset_SlabCommon - Reference: ø300 (schroef); IsExternal: yes; LoadBearing: no
Component Quantities - WSP_beton - ihwg beton, Mass: 903.056 kg; WSP_beton - ihwg beton, Component Volume (Net): 0.392633 m3; WSP_beton - ihwg beton, Component Volume (Gross): 0.392633 m3
Pset_ReinforcementBarPitchOfSlab - Reference: ø300 (schroef)

# IfcSlab: Slab 586, 17_WSP_FD_beton - fundatiepaal v21-2:ø300 (schroef):1507188
In: -2 fundering
Classification: Vloerplaat - fundering (ARCHICAD Classification); Material: WSP_beton - ihwg beton
CPset_Phasing - Renovation Phase: Bestaand
Pset_ReinforcementBarPitchOfSlab - Reference: ø300 (schroef)
Pset_SlabCommon - Reference: ø300 (schroef); IsExternal: yes; LoadBearing: no
Component Quantities - WSP_beton - ihwg beton, Mass: 903.056 kg; WSP_beton - ihwg beton, Component Volume (Net): 0.392633 m3; WSP_beton - ihwg beton, Component Volume (Gross): 0.392633 m3

# IfcSlab: Slab 587, 17_WSP_FD_beton - fundatiepaal v21-2:ø300 (schroef):1507187
In: -2 fundering
Classification: Vloerplaat - fundering (ARCHICAD Classification); Material: WSP_beton - ihwg beton
Pset_SlabCommon - Reference: ø300 (schroef); IsExternal: yes; LoadBearing: no
Component Quantities - WSP_beton - ihwg beton, Mass: 903.056 kg; WSP_beton - ihwg beton, Component Volume (Net): 0.392633 m3; WSP_beton - ihwg beton, Component Volume (Gross): 0.392633 m3
CPset_Phasing - Renovation Phase: Bestaand
Pset_ReinforcementBarPitchOfSlab - Reference: ø300 (schroef)

# IfcSlab: Slab 588, 17_WSP_FD_beton - fundatiepaal v21-2:ø300 (schroef):1507186
In: -2 fundering
Classification: Vloerplaat - fundering (ARCHICAD Classification); Material: WSP_beton - ihwg beton
Pset_SlabCommon - Reference: ø300 (schroef); IsExternal: yes; LoadBearing: no
Pset_ReinforcementBarPitchOfSlab - Reference: ø300 (schroef)
CPset_Phasing - Renovation Phase: Bestaand
Component Quantities - WSP_beton - ihwg beton, Mass: 903.056 kg; WSP_beton - ihwg beton, Component Volume (Net): 0.392633 m3; WSP_beton - ihwg beton, Component Volume (Gross): 0.392633 m3

# IfcSlab: Slab 589, 17_WSP_FD_beton - fundatiepaal v21-2:ø300 (schroef):1507185
In: -2 fundering
Classification: Vloerplaat - fundering (ARCHICAD Classification); Material: WSP_beton - ihwg beton
Pset_SlabCommon - Reference: ø300 (schroef); IsExternal: yes; LoadBearing: no
Pset_ReinforcementBarPitchOfSlab - Reference: ø300 (schroef)
Component Quantities - WSP_beton - ihwg beton, Mass: 903.056 kg; WSP_beton - ihwg beton, Component Volume (Net): 0.392633 m3; WSP_beton - ihwg beton, Component Volume (Gross): 0.392633 m3
CPset_Phasing - Renovation Phase: Bestaand

# IfcSlab: Slab 59, 17_WSP_FD_beton - fundatiepaal v21-2:ø300 (schroef):1473622
In: -2 fundering
Classification: Vloerplaat - fundering (ARCHICAD Classification); Material: WSP_beton - ihwg beton
Pset_SlabCommon - Reference: ø300 (schroef); IsExternal: yes; LoadBearing: no
CPset_Phasing - Renovation Phase: Bestaand
Component Quantities - WSP_beton - ihwg beton, Mass: 887.213 kg; WSP_beton - ihwg beton, Component Volume (Net): 0.385745 m3; WSP_beton - ihwg beton, Component Volume (Gross): 0.385745 m3
Pset_ReinforcementBarPitchOfSlab - Reference: ø300 (schroef)

# IfcSlab: Slab 590, 17_WSP_FD_beton - fundatiepaal v21-2:ø300 (schroef):1507184
In: -2 fundering
Classification: Vloerplaat - fundering (ARCHICAD Classification); Material: WSP_beton - ihwg beton
Component Quantities - WSP_beton - ihwg beton, Mass: 903.056 kg; WSP_beton - ihwg beton, Component Volume (Net): 0.392633 m3; WSP_beton - ihwg beton, Component Volume (Gross): 0.392633 m3
Pset_SlabCommon - Reference: ø300 (schroef); IsExternal: yes; LoadBearing: no
Pset_ReinforcementBarPitchOfSlab - Reference: ø300 (schroef)
CPset_Phasing - Renovation Phase: Bestaand

# IfcSlab: Slab 591, 17_WSP_FD_beton - fundatiepaal v21-2:ø300 (schroef):1507151
In: -2 fundering
Classification: Vloerplaat - fundering (ARCHICAD Classification); Material: WSP_beton - ihwg beton
Pset_ReinforcementBarPitchOfSlab - Reference: ø300 (schroef)
Component Quantities - WSP_beton - ihwg beton, Mass: 903.056 kg; WSP_beton - ihwg beton, Component Volume (Net): 0.392633 m3; WSP_beton - ihwg beton, Component Volume (Gross): 0.392633 m3
CPset_Phasing - Renovation Phase: Bestaand
Pset_SlabCommon - Reference: ø300 (schroef); IsExternal: yes; LoadBearing: no

# IfcSlab: Slab 592, 17_WSP_FD_beton - fundatiepaal v21-2:ø300 (schroef):1507150
In: -2 fundering
Classification: Vloerplaat - fundering (ARCHICAD Classification); Material: WSP_beton - ihwg beton
Pset_SlabCommon - Reference: ø300 (schroef); IsExternal: yes; LoadBearing: no
Pset_ReinforcementBarPitchOfSlab - Reference: ø300 (schroef)
CPset_Phasing - Renovation Phase: Bestaand
Component Quantities - WSP_beton - ihwg beton, Mass: 903.056 kg; WSP_beton - ihwg beton, Component Volume (Net): 0.392633 m3; WSP_beton - ihwg beton, Component Volume (Gross): 0.392633 m3

# IfcSlab: Slab 593, 17_WSP_FD_beton - fundatiepaal v21-2:ø300 (schroef):1507149
In: -2 fundering
Classification: Vloerplaat - fundering (ARCHICAD Classification); Material: WSP_beton - ihwg beton
Pset_ReinforcementBarPitchOfSlab - Reference: ø300 (schroef)
Pset_SlabCommon - Reference: ø300 (schroef); IsExternal: yes; LoadBearing: no
CPset_Phasing - Renovation Phase: Bestaand
Component Quantities - WSP_beton - ihwg beton, Mass: 903.056 kg; WSP_beton - ihwg beton, Component Volume (Net): 0.392633 m3; WSP_beton - ihwg beton, Component Volume (Gross): 0.392633 m3

# IfcSlab: Slab 594, 17_WSP_FD_beton - fundatiepaal v21-2:ø300 (schroef):1507148
In: -2 fundering
Classification: Vloerplaat - fundering (ARCHICAD Classification); Material: WSP_beton - ihwg beton
Pset_ReinforcementBarPitchOfSlab - Reference: ø300 (schroef)
Pset_SlabCommon - Reference: ø300 (schroef); IsExternal: yes; LoadBearing: no
Component Quantities - WSP_beton - ihwg beton, Mass: 903.056 kg; WSP_beton - ihwg beton, Component Volume (Net): 0.392633 m3; WSP_beton - ihwg beton, Component Volume (Gross): 0.392633 m3
CPset_Phasing - Renovation Phase: Bestaand

# IfcSlab: Slab 595, 17_WSP_FD_beton - fundatiepaal v21-2:ø300 (schroef):1507147
In: -2 fundering
Classification: Vloerplaat - fundering (ARCHICAD Classification); Material: WSP_beton - ihwg beton
Pset_SlabCommon - Reference: ø300 (schroef); IsExternal: yes; LoadBearing: no
CPset_Phasing - Renovation Phase: Bestaand
Component Quantities - WSP_beton - ihwg beton, Mass: 903.056 kg; WSP_beton - ihwg beton, Component Volume (Net): 0.392633 m3; WSP_beton - ihwg beton, Component Volume (Gross): 0.392633 m3
Pset_ReinforcementBarPitchOfSlab - Reference: ø300 (schroef)

# IfcSlab: Slab 596, 17_WSP_FD_beton - fundatiepaal v21-2:ø300 (schroef):1507146
In: -2 fundering
Classification: Vloerplaat - fundering (ARCHICAD Classification); Material: WSP_beton - ihwg beton
Pset_SlabCommon - Reference: ø300 (schroef); IsExternal: yes; LoadBearing: no
Pset_ReinforcementBarPitchOfSlab - Reference: ø300 (schroef)
CPset_Phasing - Renovation Phase: Bestaand
Component Quantities - WSP_beton - ihwg beton, Mass: 903.056 kg; WSP_beton - ihwg beton, Component Volume (Net): 0.392633 m3; WSP_beton - ihwg beton, Component Volume (Gross): 0.392633 m3

# IfcSlab: Slab 597, 17_WSP_FD_beton - fundatiepaal v21-2:ø300 (schroef):1507145
In: -2 fundering
Classification: Vloerplaat - fundering (ARCHICAD Classification); Material: WSP_beton - ihwg beton
Pset_SlabCommon - Reference: ø300 (schroef); IsExternal: yes; LoadBearing: no
Pset_ReinforcementBarPitchOfSlab - Reference: ø300 (schroef)
Component Quantities - WSP_beton - ihwg beton, Mass: 903.056 kg; WSP_beton - ihwg beton, Component Volume (Net): 0.392633 m3; WSP_beton - ihwg beton, Component Volume (Gross): 0.392633 m3
CPset_Phasing - Renovation Phase: Bestaand

# IfcSlab: Slab 598, 17_WSP_FD_beton - fundatiepaal v21-2:ø300 (schroef):1507144
In: -2 fundering
Classification: Vloerplaat - fundering (ARCHICAD Classification); Material: WSP_beton - ihwg beton
Pset_ReinforcementBarPitchOfSlab - Reference: ø300 (schroef)
Pset_SlabCommon - Reference: ø300 (schroef); IsExternal: yes; LoadBearing: no
CPset_Phasing - Renovation Phase: Bestaand
Component Quantities - WSP_beton - ihwg beton, Mass: 903.056 kg; WSP_beton - ihwg beton, Component Volume (Net): 0.392633 m3; WSP_beton - ihwg beton, Component Volume (Gross): 0.392633 m3

# IfcSlab: Slab 599, 17_WSP_FD_beton - fundatiepaal v21-2:ø300 (schroef):1507143
In: -2 fundering
Classification: Vloerplaat - fundering (ARCHICAD Classification); Material: WSP_beton - ihwg beton
Pset_SlabCommon - Reference: ø300 (schroef); IsExternal: yes; LoadBearing: no
Pset_ReinforcementBarPitchOfSlab - Reference: ø300 (schroef)
CPset_Phasing - Renovation Phase: Bestaand
Component Quantities - WSP_beton - ihwg beton, Mass: 903.056 kg; WSP_beton - ihwg beton, Component Volume (Net): 0.392633 m3; WSP_beton - ihwg beton, Component Volume (Gross): 0.392633 m3

# IfcSlab: Slab 6, 17_WSP_FD_beton - fundatiepaal v21-2:ø300 (schroef):1528053
In: -2 fundering
Classification: Vloerplaat - fundering (ARCHICAD Classification); Material: WSP_beton - ihwg beton
Pset_SlabCommon - Reference: ø300 (schroef); IsExternal: yes; LoadBearing: no
Component Quantities - WSP_beton - ihwg beton, Mass: 903.056 kg; WSP_beton - ihwg beton, Component Volume (Net): 0.392633 m3; WSP_beton - ihwg beton, Component Volume (Gross): 0.392633 m3
Pset_ReinforcementBarPitchOfSlab - Reference: ø300 (schroef)
CPset_Phasing - Renovation Phase: Bestaand

# IfcSlab: Slab 60, 17_WSP_FD_beton - fundatiepaal v21-2:ø300 (schroef):1473620
In: -2 fundering
Classification: Vloerplaat - fundering (ARCHICAD Classification); Material: WSP_beton - ihwg beton
CPset_Phasing - Renovation Phase: Bestaand
Pset_SlabCommon - Reference: ø300 (schroef); IsExternal: yes; LoadBearing: no
Pset_ReinforcementBarPitchOfSlab - Reference: ø300 (schroef)
Component Quantities - WSP_beton - ihwg beton, Mass: 887.213 kg; WSP_beton - ihwg beton, Component Volume (Net): 0.385745 m3; WSP_beton - ihwg beton, Component Volume (Gross): 0.385745 m3

# IfcSlab: Slab 600, 17_WSP_FD_beton - fundatiepaal v21-2:ø300 (schroef):1507142
In: -2 fundering
Classification: Vloerplaat - fundering (ARCHICAD Classification); Material: WSP_beton - ihwg beton
Pset_SlabCommon - Reference: ø300 (schroef); IsExternal: yes; LoadBearing: no
CPset_Phasing - Renovation Phase: Bestaand
Component Quantities - WSP_beton - ihwg beton, Mass: 903.056 kg; WSP_beton - ihwg beton, Component Volume (Net): 0.392633 m3; WSP_beton - ihwg beton, Component Volume (Gross): 0.392633 m3
Pset_ReinforcementBarPitchOfSlab - Reference: ø300 (schroef)

# IfcSlab: Slab 601, 17_WSP_FD_beton - fundatiepaal v21-2:ø300 (schroef):1507141
In: -2 fundering
Classification: Vloerplaat - fundering (ARCHICAD Classification); Material: WSP_beton - ihwg beton
Pset_SlabCommon - Reference: ø300 (schroef); IsExternal: yes; LoadBearing: no
CPset_Phasing - Renovation Phase: Bestaand
Component Quantities - WSP_beton - ihwg beton, Mass: 903.056 kg; WSP_beton - ihwg beton, Component Volume (Net): 0.392633 m3; WSP_beton - ihwg beton, Component Volume (Gross): 0.392633 m3
Pset_ReinforcementBarPitchOfSlab - Reference: ø300 (schroef)

# IfcSlab: Slab 602, 17_WSP_FD_beton - fundatiepaal v21-2:ø300 (schroef):1507140
In: -2 fundering
Classification: Vloerplaat - fundering (ARCHICAD Classification); Material: WSP_beton - ihwg beton
Pset_SlabCommon - Reference: ø300 (schroef); IsExternal: yes; LoadBearing: no
Pset_ReinforcementBarPitchOfSlab - Reference: ø300 (schroef)
CPset_Phasing - Renovation Phase: Bestaand
Component Quantities - WSP_beton - ihwg beton, Mass: 903.056 kg; WSP_beton - ihwg beton, Component Volume (Net): 0.392633 m3; WSP_beton - ihwg beton, Component Volume (Gross): 0.392633 m3

# IfcSlab: Slab 603, 17_WSP_FD_beton - fundatiepaal v21-2:ø300 (schroef):1507139
In: -2 fundering
Classification: Vloerplaat - fundering (ARCHICAD Classification); Material: WSP_beton - ihwg beton
Pset_ReinforcementBarPitchOfSlab - Reference: ø300 (schroef)
Pset_SlabCommon - Reference: ø300 (schroef); IsExternal: yes; LoadBearing: no
Component Quantities - WSP_beton - ihwg beton, Mass: 903.056 kg; WSP_beton - ihwg beton, Component Volume (Net): 0.392633 m3; WSP_beton - ihwg beton, Component Volume (Gross): 0.392633 m3
CPset_Phasing - Renovation Phase: Bestaand

# IfcSlab: Slab 604, 17_WSP_FD_beton - fundatiepaal v21-2:ø300 (schroef):1507138
In: -2 fundering
Classification: Vloerplaat - fundering (ARCHICAD Classification); Material: WSP_beton - ihwg beton
Pset_SlabCommon - Reference: ø300 (schroef); IsExternal: yes; LoadBearing: no
Pset_ReinforcementBarPitchOfSlab - Reference: ø300 (schroef)
CPset_Phasing - Renovation Phase: Bestaand
Component Quantities - WSP_beton - ihwg beton, Mass: 903.056 kg; WSP_beton - ihwg beton, Component Volume (Net): 0.392633 m3; WSP_beton - ihwg beton, Component Volume (Gross): 0.392633 m3

# IfcSlab: Slab 605, 17_WSP_FD_beton - fundatiepaal v21-2:ø300 (schroef):1507137
In: -2 fundering
Classification: Vloerplaat - fundering (ARCHICAD Classification); Material: WSP_beton - ihwg beton
CPset_Phasing - Renovation Phase: Bestaand
Pset_ReinforcementBarPitchOfSlab - Reference: ø300 (schroef)
Pset_SlabCommon - Reference: ø300 (schroef); IsExternal: yes; LoadBearing: no
Component Quantities - WSP_beton - ihwg beton, Mass: 903.056 kg; WSP_beton - ihwg beton, Component Volume (Net): 0.392633 m3; WSP_beton - ihwg beton, Component Volume (Gross): 0.392633 m3

# IfcSlab: Slab 606, 17_WSP_FD_beton - fundatiepaal v21-2:ø300 (schroef):1507136
In: -2 fundering
Classification: Vloerplaat - fundering (ARCHICAD Classification); Material: WSP_beton - ihwg beton
Pset_SlabCommon - Reference: ø300 (schroef); IsExternal: yes; LoadBearing: no
Pset_ReinforcementBarPitchOfSlab - Reference: ø300 (schroef)
CPset_Phasing - Renovation Phase: Bestaand
Component Quantities - WSP_beton - ihwg beton, Mass: 903.056 kg; WSP_beton - ihwg beton, Component Volume (Net): 0.392633 m3; WSP_beton - ihwg beton, Component Volume (Gross): 0.392633 m3

# IfcSlab: Slab 607, 17_WSP_FD_beton - fundatiepaal v21-2:ø300 (schroef):1507167
In: -2 fundering
Classification: Vloerplaat - fundering (ARCHICAD Classification); Material: WSP_beton - ihwg beton
Pset_SlabCommon - Reference: ø300 (schroef); IsExternal: yes; LoadBearing: no
CPset_Phasing - Renovation Phase: Bestaand
Component Quantities - WSP_beton - ihwg beton, Mass: 903.056 kg; WSP_beton - ihwg beton, Component Volume (Net): 0.392633 m3; WSP_beton - ihwg beton, Component Volume (Gross): 0.392633 m3
Pset_ReinforcementBarPitchOfSlab - Reference: ø300 (schroef)

# IfcSlab: Slab 608, 17_WSP_FD_beton - fundatiepaal v21-2:ø300 (schroef):1507166
In: -2 fundering
Classification: Vloerplaat - fundering (ARCHICAD Classification); Material: WSP_beton - ihwg beton
Pset_SlabCommon - Reference: ø300 (schroef); IsExternal: yes; LoadBearing: no
Pset_ReinforcementBarPitchOfSlab - Reference: ø300 (schroef)
CPset_Phasing - Renovation Phase: Bestaand
Component Quantities - WSP_beton - ihwg beton, Mass: 903.056 kg; WSP_beton - ihwg beton, Component Volume (Net): 0.392633 m3; WSP_beton - ihwg beton, Component Volume (Gross): 0.392633 m3

# IfcSlab: Slab 609, 17_WSP_FD_beton - fundatiepaal v21-2:ø300 (schroef):1507165
In: -2 fundering
Classification: Vloerplaat - fundering (ARCHICAD Classification); Material: WSP_beton - ihwg beton
Pset_SlabCommon - Reference: ø300 (schroef); IsExternal: yes; LoadBearing: no
Pset_ReinforcementBarPitchOfSlab - Reference: ø300 (schroef)
Component Quantities - WSP_beton - ihwg beton, Mass: 903.056 kg; WSP_beton - ihwg beton, Component Volume (Net): 0.392633 m3; WSP_beton - ihwg beton, Component Volume (Gross): 0.392633 m3
CPset_Phasing - Renovation Phase: Bestaand

# IfcSlab: Slab 61, 17_WSP_FD_beton - fundatiepaal v21-2:ø300 (schroef):1473621
In: -2 fundering
Classification: Vloerplaat - fundering (ARCHICAD Classification); Material: WSP_beton - ihwg beton
Pset_SlabCommon - Reference: ø300 (schroef); IsExternal: yes; LoadBearing: no
Pset_ReinforcementBarPitchOfSlab - Reference: ø300 (schroef)
CPset_Phasing - Renovation Phase: Bestaand
Component Quantities - WSP_beton - ihwg beton, Mass: 887.213 kg; WSP_beton - ihwg beton, Component Volume (Net): 0.385745 m3; WSP_beton - ihwg beton, Component Volume (Gross): 0.385745 m3

# IfcSlab: Slab 610, 17_WSP_FD_beton - fundatiepaal v21-2:ø300 (schroef):1507164
In: -2 fundering
Classification: Vloerplaat - fundering (ARCHICAD Classification); Material: WSP_beton - ihwg beton
Pset_SlabCommon - Reference: ø300 (schroef); IsExternal: yes; LoadBearing: no
Pset_ReinforcementBarPitchOfSlab - Reference: ø300 (schroef)
CPset_Phasing - Renovation Phase: Bestaand
Component Quantities - WSP_beton - ihwg beton, Mass: 903.056 kg; WSP_beton - ihwg beton, Component Volume (Net): 0.392633 m3; WSP_beton - ihwg beton, Component Volume (Gross): 0.392633 m3

# IfcSlab: Slab 611, 17_WSP_FD_beton - fundatiepaal v21-2:ø300 (schroef):1507163
In: -2 fundering
Classification: Vloerplaat - fundering (ARCHICAD Classification); Material: WSP_beton - ihwg beton
Pset_ReinforcementBarPitchOfSlab - Reference: ø300 (schroef)
Pset_SlabCommon - Reference: ø300 (schroef); IsExternal: yes; LoadBearing: no
CPset_Phasing - Renovation Phase: Bestaand
Component Quantities - WSP_beton - ihwg beton, Mass: 903.056 kg; WSP_beton - ihwg beton, Component Volume (Net): 0.392633 m3; WSP_beton - ihwg beton, Component Volume (Gross): 0.392633 m3

# IfcSlab: Slab 612, 17_WSP_FD_beton - fundatiepaal v21-2:ø300 (schroef):1507162
In: -2 fundering
Classification: Vloerplaat - fundering (ARCHICAD Classification); Material: WSP_beton - ihwg beton
Pset_SlabCommon - Reference: ø300 (schroef); IsExternal: yes; LoadBearing: no
Pset_ReinforcementBarPitchOfSlab - Reference: ø300 (schroef)
Component Quantities - WSP_beton - ihwg beton, Mass: 903.056 kg; WSP_beton - ihwg beton, Component Volume (Net): 0.392633 m3; WSP_beton - ihwg beton, Component Volume (Gross): 0.392633 m3
CPset_Phasing - Renovation Phase: Bestaand

# IfcSlab: Slab 613, 17_WSP_FD_beton - fundatiepaal v21-2:ø300 (schroef):1507161
In: -2 fundering
Classification: Vloerplaat - fundering (ARCHICAD Classification); Material: WSP_beton - ihwg beton
CPset_Phasing - Renovation Phase: Bestaand
Pset_ReinforcementBarPitchOfSlab - Reference: ø300 (schroef)
Pset_SlabCommon - Reference: ø300 (schroef); IsExternal: yes; LoadBearing: no
Component Quantities - WSP_beton - ihwg beton, Mass: 903.056 kg; WSP_beton - ihwg beton, Component Volume (Net): 0.392633 m3; WSP_beton - ihwg beton, Component Volume (Gross): 0.392633 m3

# IfcSlab: Slab 614, 17_WSP_FD_beton - fundatiepaal v21-2:ø300 (schroef):1507160
In: -2 fundering
Classification: Vloerplaat - fundering (ARCHICAD Classification); Material: WSP_beton - ihwg beton
Pset_SlabCommon - Reference: ø300 (schroef); IsExternal: yes; LoadBearing: no
CPset_Phasing - Renovation Phase: Bestaand
Component Quantities - WSP_beton - ihwg beton, Mass: 903.056 kg; WSP_beton - ihwg beton, Component Volume (Net): 0.392633 m3; WSP_beton - ihwg beton, Component Volume (Gross): 0.392633 m3
Pset_ReinforcementBarPitchOfSlab - Reference: ø300 (schroef)

# IfcSlab: Slab 615, 17_WSP_FD_beton - fundatiepaal v21-2:ø300 (schroef):1507159
In: -2 fundering
Classification: Vloerplaat - fundering (ARCHICAD Classification); Material: WSP_beton - ihwg beton
Pset_ReinforcementBarPitchOfSlab - Reference: ø300 (schroef)
Pset_SlabCommon - Reference: ø300 (schroef); IsExternal: yes; LoadBearing: no
CPset_Phasing - Renovation Phase: Bestaand
Component Quantities - WSP_beton - ihwg beton, Mass: 903.056 kg; WSP_beton - ihwg beton, Component Volume (Net): 0.392633 m3; WSP_beton - ihwg beton, Component Volume (Gross): 0.392633 m3

# IfcSlab: Slab 616, 17_WSP_FD_beton - fundatiepaal v21-2:ø300 (schroef):1507158
In: -2 fundering
Classification: Vloerplaat - fundering (ARCHICAD Classification); Material: WSP_beton - ihwg beton
Pset_SlabCommon - Reference: ø300 (schroef); IsExternal: yes; LoadBearing: no
Pset_ReinforcementBarPitchOfSlab - Reference: ø300 (schroef)
CPset_Phasing - Renovation Phase: Bestaand
Component Quantities - WSP_beton - ihwg beton, Mass: 903.056 kg; WSP_beton - ihwg beton, Component Volume (Net): 0.392633 m3; WSP_beton - ihwg beton, Component Volume (Gross): 0.392633 m3

# IfcSlab: Slab 617, 17_WSP_FD_beton - fundatiepaal v21-2:ø300 (schroef):1507157
In: -2 fundering
Classification: Vloerplaat - fundering (ARCHICAD Classification); Material: WSP_beton - ihwg beton
Pset_SlabCommon - Reference: ø300 (schroef); IsExternal: yes; LoadBearing: no
Pset_ReinforcementBarPitchOfSlab - Reference: ø300 (schroef)
Component Quantities - WSP_beton - ihwg beton, Mass: 903.056 kg; WSP_beton - ihwg beton, Component Volume (Net): 0.392633 m3; WSP_beton - ihwg beton, Component Volume (Gross): 0.392633 m3
CPset_Phasing - Renovation Phase: Bestaand

# IfcSlab: Slab 618, 17_WSP_FD_beton - fundatiepaal v21-2:ø300 (schroef):1507156
In: -2 fundering
Classification: Vloerplaat - fundering (ARCHICAD Classification); Material: WSP_beton - ihwg beton
Pset_SlabCommon - Reference: ø300 (schroef); IsExternal: yes; LoadBearing: no
Component Quantities - WSP_beton - ihwg beton, Mass: 903.056 kg; WSP_beton - ihwg beton, Component Volume (Net): 0.392633 m3; WSP_beton - ihwg beton, Component Volume (Gross): 0.392633 m3
CPset_Phasing - Renovation Phase: Bestaand
Pset_ReinforcementBarPitchOfSlab - Reference: ø300 (schroef)

# IfcSlab: Slab 619, 17_WSP_FD_beton - fundatiepaal v21-2:ø300 (schroef):1507155
In: -2 fundering
Classification: Vloerplaat - fundering (ARCHICAD Classification); Material: WSP_beton - ihwg beton
Pset_SlabCommon - Reference: ø300 (schroef); IsExternal: yes; LoadBearing: no
CPset_Phasing - Renovation Phase: Bestaand
Component Quantities - WSP_beton - ihwg beton, Mass: 903.056 kg; WSP_beton - ihwg beton, Component Volume (Net): 0.392633 m3; WSP_beton - ihwg beton, Component Volume (Gross): 0.392633 m3
Pset_ReinforcementBarPitchOfSlab - Reference: ø300 (schroef)

# IfcSlab: Slab 62, 17_WSP_FD_beton - fundatiepaal v21-2:ø300 (schroef):1473570
In: -2 fundering
Classification: Vloerplaat - fundering (ARCHICAD Classification); Material: WSP_beton - ihwg beton
Pset_SlabCommon - Reference: ø300 (schroef); IsExternal: yes; LoadBearing: no
Pset_ReinforcementBarPitchOfSlab - Reference: ø300 (schroef)
Component Quantities - WSP_beton - ihwg beton, Mass: 903.056 kg; WSP_beton - ihwg beton, Component Volume (Net): 0.392633 m3; WSP_beton - ihwg beton, Component Volume (Gross): 0.392633 m3
CPset_Phasing - Renovation Phase: Bestaand

# IfcSlab: Slab 620, 17_WSP_FD_beton - fundatiepaal v21-2:ø300 (schroef):1507154
In: -2 fundering
Classification: Vloerplaat - fundering (ARCHICAD Classification); Material: WSP_beton - ihwg beton
Pset_SlabCommon - Reference: ø300 (schroef); IsExternal: yes; LoadBearing: no
Pset_ReinforcementBarPitchOfSlab - Reference: ø300 (schroef)
CPset_Phasing - Renovation Phase: Bestaand
Component Quantities - WSP_beton - ihwg beton, Mass: 903.056 kg; WSP_beton - ihwg beton, Component Volume (Net): 0.392633 m3; WSP_beton - ihwg beton, Component Volume (Gross): 0.392633 m3

# IfcSlab: Slab 621, 17_WSP_FD_beton - fundatiepaal v21-2:ø300 (schroef):1507153
In: -2 fundering
Classification: Vloerplaat - fundering (ARCHICAD Classification); Material: WSP_beton - ihwg beton
Pset_SlabCommon - Reference: ø300 (schroef); IsExternal: yes; LoadBearing: no
CPset_Phasing - Renovation Phase: Bestaand
Pset_ReinforcementBarPitchOfSlab - Reference: ø300 (schroef)
Component Quantities - WSP_beton - ihwg beton, Mass: 903.056 kg; WSP_beton - ihwg beton, Component Volume (Net): 0.392633 m3; WSP_beton - ihwg beton, Component Volume (Gross): 0.392633 m3

# IfcSlab: Slab 622, 17_WSP_FD_beton - fundatiepaal v21-2:ø300 (schroef):1507152
In: -2 fundering
Classification: Vloerplaat - fundering (ARCHICAD Classification); Material: WSP_beton - ihwg beton
Pset_ReinforcementBarPitchOfSlab - Reference: ø300 (schroef)
Component Quantities - WSP_beton - ihwg beton, Mass: 903.056 kg; WSP_beton - ihwg beton, Component Volume (Net): 0.392633 m3; WSP_beton - ihwg beton, Component Volume (Gross): 0.392633 m3
Pset_SlabCommon - Reference: ø300 (schroef); IsExternal: yes; LoadBearing: no
CPset_Phasing - Renovation Phase: Bestaand

# IfcSlab: Slab 623, 17_WSP_FD_beton - fundatiepaal v21-2:ø300 (schroef):1507237
In: -2 fundering
Classification: Vloerplaat - fundering (ARCHICAD Classification); Material: WSP_beton - ihwg beton
Pset_SlabCommon - Reference: ø300 (schroef); IsExternal: yes; LoadBearing: no
CPset_Phasing - Renovation Phase: Bestaand
Pset_ReinforcementBarPitchOfSlab - Reference: ø300 (schroef)
Component Quantities - WSP_beton - ihwg beton, Mass: 887.213 kg; WSP_beton - ihwg beton, Component Volume (Net): 0.385745 m3; WSP_beton - ihwg beton, Component Volume (Gross): 0.385745 m3

# IfcSlab: Slab 624, 17_WSP_FD_beton - fundatiepaal v21-2:ø300 (schroef):1507236
In: -2 fundering
Classification: Vloerplaat - fundering (ARCHICAD Classification); Material: WSP_beton - ihwg beton
Pset_SlabCommon - Reference: ø300 (schroef); IsExternal: yes; LoadBearing: no
Pset_ReinforcementBarPitchOfSlab - Reference: ø300 (schroef)
Component Quantities - WSP_beton - ihwg beton, Mass: 887.213 kg; WSP_beton - ihwg beton, Component Volume (Net): 0.385745 m3; WSP_beton - ihwg beton, Component Volume (Gross): 0.385745 m3
CPset_Phasing - Renovation Phase: Bestaand

# IfcSlab: Slab 625, 17_WSP_FD_beton - fundatiepaal v21-2:ø300 (schroef):1507235
In: -2 fundering
Classification: Vloerplaat - fundering (ARCHICAD Classification); Material: WSP_beton - ihwg beton
Pset_SlabCommon - Reference: ø300 (schroef); IsExternal: yes; LoadBearing: no
Pset_ReinforcementBarPitchOfSlab - Reference: ø300 (schroef)
CPset_Phasing - Renovation Phase: Bestaand
Component Quantities - WSP_beton - ihwg beton, Mass: 887.213 kg; WSP_beton - ihwg beton, Component Volume (Net): 0.385745 m3; WSP_beton - ihwg beton, Component Volume (Gross): 0.385745 m3

# IfcSlab: Slab 626, 17_WSP_FD_beton - fundatiepaal v21-2:ø300 (schroef):1507234
In: -2 fundering
Classification: Vloerplaat - fundering (ARCHICAD Classification); Material: WSP_beton - ihwg beton
Pset_SlabCommon - Reference: ø300 (schroef); IsExternal: yes; LoadBearing: no
Pset_ReinforcementBarPitchOfSlab - Reference: ø300 (schroef)
CPset_Phasing - Renovation Phase: Bestaand
Component Quantities - WSP_beton - ihwg beton, Mass: 887.213 kg; WSP_beton - ihwg beton, Component Volume (Net): 0.385745 m3; WSP_beton - ihwg beton, Component Volume (Gross): 0.385745 m3

# IfcSlab: Slab 627, 17_WSP_FD_beton - fundatiepaal v21-2:ø300 (schroef):1507233
In: -2 fundering
Classification: Vloerplaat - fundering (ARCHICAD Classification); Material: WSP_beton - ihwg beton
Pset_SlabCommon - Reference: ø300 (schroef); IsExternal: yes; LoadBearing: no
Pset_ReinforcementBarPitchOfSlab - Reference: ø300 (schroef)
Component Quantities - WSP_beton - ihwg beton, Mass: 887.213 kg; WSP_beton - ihwg beton, Component Volume (Net): 0.385745 m3; WSP_beton - ihwg beton, Component Volume (Gross): 0.385745 m3
CPset_Phasing - Renovation Phase: Bestaand

# IfcSlab: Slab 628, 17_WSP_FD_beton - fundatiepaal v21-2:ø300 (schroef):1507232
In: -2 fundering
Classification: Vloerplaat - fundering (ARCHICAD Classification); Material: WSP_beton - ihwg beton
Pset_SlabCommon - Reference: ø300 (schroef); IsExternal: yes; LoadBearing: no
Component Quantities - WSP_beton - ihwg beton, Mass: 887.213 kg; WSP_beton - ihwg beton, Component Volume (Net): 0.385745 m3; WSP_beton - ihwg beton, Component Volume (Gross): 0.385745 m3
CPset_Phasing - Renovation Phase: Bestaand
Pset_ReinforcementBarPitchOfSlab - Reference: ø300 (schroef)

# IfcSlab: Slab 629, 17_WSP_FD_beton - fundatiepaal v21-2:ø300 (schroef):1507215
In: -2 fundering
Classification: Vloerplaat - fundering (ARCHICAD Classification); Material: WSP_beton - ihwg beton
Pset_SlabCommon - Reference: ø300 (schroef); IsExternal: yes; LoadBearing: no
Pset_ReinforcementBarPitchOfSlab - Reference: ø300 (schroef)
CPset_Phasing - Renovation Phase: Bestaand
Component Quantities - WSP_beton - ihwg beton, Mass: 903.056 kg; WSP_beton - ihwg beton, Component Volume (Net): 0.392633 m3; WSP_beton - ihwg beton, Component Volume (Gross): 0.392633 m3

# IfcSlab: Slab 63, 17_WSP_FD_beton - fundatiepaal v21-2:ø300 (schroef):1473571
In: -2 fundering
Classification: Vloerplaat - fundering (ARCHICAD Classification); Material: WSP_beton - ihwg beton
Pset_ReinforcementBarPitchOfSlab - Reference: ø300 (schroef)
Pset_SlabCommon - Reference: ø300 (schroef); IsExternal: yes; LoadBearing: no
Component Quantities - WSP_beton - ihwg beton, Mass: 903.056 kg; WSP_beton - ihwg beton, Component Volume (Net): 0.392633 m3; WSP_beton - ihwg beton, Component Volume (Gross): 0.392633 m3
CPset_Phasing - Renovation Phase: Bestaand

# IfcSlab: Slab 630, 17_WSP_FD_beton - fundatiepaal v21-2:ø300 (schroef):1507214
In: -2 fundering
Classification: Vloerplaat - fundering (ARCHICAD Classification); Material: WSP_beton - ihwg beton
Component Quantities - WSP_beton - ihwg beton, Mass: 903.056 kg; WSP_beton - ihwg beton, Component Volume (Net): 0.392633 m3; WSP_beton - ihwg beton, Component Volume (Gross): 0.392633 m3
Pset_ReinforcementBarPitchOfSlab - Reference: ø300 (schroef)
Pset_SlabCommon - Reference: ø300 (schroef); IsExternal: yes; LoadBearing: no
CPset_Phasing - Renovation Phase: Bestaand

# IfcSlab: Slab 631, 17_WSP_FD_beton - fundatiepaal v21-2:ø300 (schroef):1507213
In: -2 fundering
Classification: Vloerplaat - fundering (ARCHICAD Classification); Material: WSP_beton - ihwg beton
Pset_SlabCommon - Reference: ø300 (schroef); IsExternal: yes; LoadBearing: no
Pset_ReinforcementBarPitchOfSlab - Reference: ø300 (schroef)
Component Quantities - WSP_beton - ihwg beton, Mass: 903.056 kg; WSP_beton - ihwg beton, Component Volume (Net): 0.392633 m3; WSP_beton - ihwg beton, Component Volume (Gross): 0.392633 m3
CPset_Phasing - Renovation Phase: Bestaand

# IfcSlab: Slab 632, 17_WSP_FD_beton - fundatiepaal v21-2:ø300 (schroef):1507212
In: -2 fundering
Classification: Vloerplaat - fundering (ARCHICAD Classification); Material: WSP_beton - ihwg beton
CPset_Phasing - Renovation Phase: Bestaand
Pset_SlabCommon - Reference: ø300 (schroef); IsExternal: yes; LoadBearing: no
Pset_ReinforcementBarPitchOfSlab - Reference: ø300 (schroef)
Component Quantities - WSP_beton - ihwg beton, Mass: 903.056 kg; WSP_beton - ihwg beton, Component Volume (Net): 0.392633 m3; WSP_beton - ihwg beton, Component Volume (Gross): 0.392633 m3

# IfcSlab: Slab 633, 17_WSP_FD_beton - fundatiepaal v21-2:ø300 (schroef):1507211
In: -2 fundering
Classification: Vloerplaat - fundering (ARCHICAD Classification); Material: WSP_beton - ihwg beton
Pset_SlabCommon - Reference: ø300 (schroef); IsExternal: yes; LoadBearing: no
CPset_Phasing - Renovation Phase: Bestaand
Pset_ReinforcementBarPitchOfSlab - Reference: ø300 (schroef)
Component Quantities - WSP_beton - ihwg beton, Mass: 903.056 kg; WSP_beton - ihwg beton, Component Volume (Net): 0.392633 m3; WSP_beton - ihwg beton, Component Volume (Gross): 0.392633 m3

# IfcSlab: Slab 634, 17_WSP_FD_beton - fundatiepaal v21-2:ø300 (schroef):1507210
In: -2 fundering
Classification: Vloerplaat - fundering (ARCHICAD Classification); Material: WSP_beton - ihwg beton
Pset_ReinforcementBarPitchOfSlab - Reference: ø300 (schroef)
Pset_SlabCommon - Reference: ø300 (schroef); IsExternal: yes; LoadBearing: no
Component Quantities - WSP_beton - ihwg beton, Mass: 903.056 kg; WSP_beton - ihwg beton, Component Volume (Net): 0.392633 m3; WSP_beton - ihwg beton, Component Volume (Gross): 0.392633 m3
CPset_Phasing - Renovation Phase: Bestaand

# IfcSlab: Slab 635, 17_WSP_FD_beton - fundatiepaal v21-2:ø300 (schroef):1507209
In: -2 fundering
Classification: Vloerplaat - fundering (ARCHICAD Classification); Material: WSP_beton - ihwg beton
Pset_ReinforcementBarPitchOfSlab - Reference: ø300 (schroef)
CPset_Phasing - Renovation Phase: Bestaand
Pset_SlabCommon - Reference: ø300 (schroef); IsExternal: yes; LoadBearing: no
Component Quantities - WSP_beton - ihwg beton, Mass: 903.056 kg; WSP_beton - ihwg beton, Component Volume (Net): 0.392633 m3; WSP_beton - ihwg beton, Component Volume (Gross): 0.392633 m3

# IfcSlab: Slab 636, 17_WSP_FD_beton - fundatiepaal v21-2:ø300 (schroef):1507208
In: -2 fundering
Classification: Vloerplaat - fundering (ARCHICAD Classification); Material: WSP_beton - ihwg beton
Pset_SlabCommon - Reference: ø300 (schroef); IsExternal: yes; LoadBearing: no
Pset_ReinforcementBarPitchOfSlab - Reference: ø300 (schroef)
CPset_Phasing - Renovation Phase: Bestaand
Component Quantities - WSP_beton - ihwg beton, Mass: 903.056 kg; WSP_beton - ihwg beton, Component Volume (Net): 0.392633 m3; WSP_beton - ihwg beton, Component Volume (Gross): 0.392633 m3

# IfcSlab: Slab 637, 17_WSP_FD_beton - fundatiepaal v21-2:ø300 (schroef):1507207
In: -2 fundering
Classification: Vloerplaat - fundering (ARCHICAD Classification); Material: WSP_beton - ihwg beton
Pset_ReinforcementBarPitchOfSlab - Reference: ø300 (schroef)
CPset_Phasing - Renovation Phase: Bestaand
Pset_SlabCommon - Reference: ø300 (schroef); IsExternal: yes; LoadBearing: no
Component Quantities - WSP_beton - ihwg beton, Mass: 903.056 kg; WSP_beton - ihwg beton, Component Volume (Net): 0.392633 m3; WSP_beton - ihwg beton, Component Volume (Gross): 0.392633 m3

# IfcSlab: Slab 638, 17_WSP_FD_beton - fundatiepaal v21-2:ø300 (schroef):1507206
In: -2 fundering
Classification: Vloerplaat - fundering (ARCHICAD Classification); Material: WSP_beton - ihwg beton
Pset_SlabCommon - Reference: ø300 (schroef); IsExternal: yes; LoadBearing: no
Pset_ReinforcementBarPitchOfSlab - Reference: ø300 (schroef)
CPset_Phasing - Renovation Phase: Bestaand
Component Quantities - WSP_beton - ihwg beton, Mass: 903.056 kg; WSP_beton - ihwg beton, Component Volume (Net): 0.392633 m3; WSP_beton - ihwg beton, Component Volume (Gross): 0.392633 m3

# IfcSlab: Slab 639, 17_WSP_FD_beton - fundatiepaal v21-2:ø300 (schroef):1507205
In: -2 fundering
Classification: Vloerplaat - fundering (ARCHICAD Classification); Material: WSP_beton - ihwg beton
Pset_ReinforcementBarPitchOfSlab - Reference: ø300 (schroef)
Pset_SlabCommon - Reference: ø300 (schroef); IsExternal: yes; LoadBearing: no
Component Quantities - WSP_beton - ihwg beton, Mass: 903.056 kg; WSP_beton - ihwg beton, Component Volume (Net): 0.392633 m3; WSP_beton - ihwg beton, Component Volume (Gross): 0.392633 m3
CPset_Phasing - Renovation Phase: Bestaand

# IfcSlab: Slab 64, 17_WSP_FD_beton - fundatiepaal v21-2:ø300 (schroef):1473568
In: -2 fundering
Classification: Vloerplaat - fundering (ARCHICAD Classification); Material: WSP_beton - ihwg beton
Pset_SlabCommon - Reference: ø300 (schroef); IsExternal: yes; LoadBearing: no
Pset_ReinforcementBarPitchOfSlab - Reference: ø300 (schroef)
Component Quantities - WSP_beton - ihwg beton, Mass: 903.056 kg; WSP_beton - ihwg beton, Component Volume (Net): 0.392633 m3; WSP_beton - ihwg beton, Component Volume (Gross): 0.392633 m3
CPset_Phasing - Renovation Phase: Bestaand

# IfcSlab: Slab 640, 17_WSP_FD_beton - fundatiepaal v21-2:ø300 (schroef):1507204
In: -2 fundering
Classification: Vloerplaat - fundering (ARCHICAD Classification); Material: WSP_beton - ihwg beton
Pset_SlabCommon - Reference: ø300 (schroef); IsExternal: yes; LoadBearing: no
Pset_ReinforcementBarPitchOfSlab - Reference: ø300 (schroef)
CPset_Phasing - Renovation Phase: Bestaand
Component Quantities - WSP_beton - ihwg beton, Mass: 903.056 kg; WSP_beton - ihwg beton, Component Volume (Net): 0.392633 m3; WSP_beton - ihwg beton, Component Volume (Gross): 0.392633 m3

# IfcSlab: Slab 641, 17_WSP_FD_beton - fundatiepaal v21-2:ø300 (schroef):1507203
In: -2 fundering
Classification: Vloerplaat - fundering (ARCHICAD Classification); Material: WSP_beton - ihwg beton
Pset_ReinforcementBarPitchOfSlab - Reference: ø300 (schroef)
CPset_Phasing - Renovation Phase: Bestaand
Component Quantities - WSP_beton - ihwg beton, Mass: 903.056 kg; WSP_beton - ihwg beton, Component Volume (Net): 0.392633 m3; WSP_beton - ihwg beton, Component Volume (Gross): 0.392633 m3
Pset_SlabCommon - Reference: ø300 (schroef); IsExternal: yes; LoadBearing: no

# IfcSlab: Slab 642, 17_WSP_FD_beton - fundatiepaal v21-2:ø300 (schroef):1507202
In: -2 fundering
Classification: Vloerplaat - fundering (ARCHICAD Classification); Material: WSP_beton - ihwg beton
Pset_ReinforcementBarPitchOfSlab - Reference: ø300 (schroef)
Pset_SlabCommon - Reference: ø300 (schroef); IsExternal: yes; LoadBearing: no
Component Quantities - WSP_beton - ihwg beton, Mass: 903.056 kg; WSP_beton - ihwg beton, Component Volume (Net): 0.392633 m3; WSP_beton - ihwg beton, Component Volume (Gross): 0.392633 m3
CPset_Phasing - Renovation Phase: Bestaand

# IfcSlab: Slab 643, 17_WSP_FD_beton - fundatiepaal v21-2:ø300 (schroef):1507201
In: -2 fundering
Classification: Vloerplaat - fundering (ARCHICAD Classification); Material: WSP_beton - ihwg beton
Pset_SlabCommon - Reference: ø300 (schroef); IsExternal: yes; LoadBearing: no
Pset_ReinforcementBarPitchOfSlab - Reference: ø300 (schroef)
Component Quantities - WSP_beton - ihwg beton, Mass: 903.056 kg; WSP_beton - ihwg beton, Component Volume (Net): 0.392633 m3; WSP_beton - ihwg beton, Component Volume (Gross): 0.392633 m3
CPset_Phasing - Renovation Phase: Bestaand

# IfcSlab: Slab 644, 17_WSP_FD_beton - fundatiepaal v21-2:ø300 (schroef):1507200
In: -2 fundering
Classification: Vloerplaat - fundering (ARCHICAD Classification); Material: WSP_beton - ihwg beton
Pset_SlabCommon - Reference: ø300 (schroef); IsExternal: yes; LoadBearing: no
Pset_ReinforcementBarPitchOfSlab - Reference: ø300 (schroef)
CPset_Phasing - Renovation Phase: Bestaand
Component Quantities - WSP_beton - ihwg beton, Mass: 903.056 kg; WSP_beton - ihwg beton, Component Volume (Net): 0.392633 m3; WSP_beton - ihwg beton, Component Volume (Gross): 0.392633 m3

# IfcSlab: Slab 645, 17_WSP_FD_beton - fundatiepaal v21-2:ø300 (schroef):1507231
In: -2 fundering
Classification: Vloerplaat - fundering (ARCHICAD Classification); Material: WSP_beton - ihwg beton
Pset_ReinforcementBarPitchOfSlab - Reference: ø300 (schroef)
Pset_SlabCommon - Reference: ø300 (schroef); IsExternal: yes; LoadBearing: no
CPset_Phasing - Renovation Phase: Bestaand
Component Quantities - WSP_beton - ihwg beton, Mass: 887.213 kg; WSP_beton - ihwg beton, Component Volume (Net): 0.385745 m3; WSP_beton - ihwg beton, Component Volume (Gross): 0.385745 m3

# IfcSlab: Slab 646, 17_WSP_FD_beton - fundatiepaal v21-2:ø300 (schroef):1507230
In: -2 fundering
Classification: Vloerplaat - fundering (ARCHICAD Classification); Material: WSP_beton - ihwg beton
Pset_SlabCommon - Reference: ø300 (schroef); IsExternal: yes; LoadBearing: no
Pset_ReinforcementBarPitchOfSlab - Reference: ø300 (schroef)
Component Quantities - WSP_beton - ihwg beton, Mass: 887.213 kg; WSP_beton - ihwg beton, Component Volume (Net): 0.385745 m3; WSP_beton - ihwg beton, Component Volume (Gross): 0.385745 m3
CPset_Phasing - Renovation Phase: Bestaand

# IfcSlab: Slab 647, 17_WSP_FD_beton - fundatiepaal v21-2:ø300 (schroef):1507229
In: -2 fundering
Classification: Vloerplaat - fundering (ARCHICAD Classification); Material: WSP_beton - ihwg beton
Pset_ReinforcementBarPitchOfSlab - Reference: ø300 (schroef)
Pset_SlabCommon - Reference: ø300 (schroef); IsExternal: yes; LoadBearing: no
CPset_Phasing - Renovation Phase: Bestaand
Component Quantities - WSP_beton - ihwg beton, Mass: 887.213 kg; WSP_beton - ihwg beton, Component Volume (Net): 0.385745 m3; WSP_beton - ihwg beton, Component Volume (Gross): 0.385745 m3

# IfcSlab: Slab 648, 17_WSP_FD_beton - fundatiepaal v21-2:ø300 (schroef):1507228
In: -2 fundering
Classification: Vloerplaat - fundering (ARCHICAD Classification); Material: WSP_beton - ihwg beton
Pset_SlabCommon - Reference: ø300 (schroef); IsExternal: yes; LoadBearing: no
Pset_ReinforcementBarPitchOfSlab - Reference: ø300 (schroef)
Component Quantities - WSP_beton - ihwg beton, Mass: 887.213 kg; WSP_beton - ihwg beton, Component Volume (Net): 0.385745 m3; WSP_beton - ihwg beton, Component Volume (Gross): 0.385745 m3
CPset_Phasing - Renovation Phase: Bestaand

# IfcSlab: Slab 649, 17_WSP_FD_beton - fundatiepaal v21-2:ø300 (schroef):1507227
In: -2 fundering
Classification: Vloerplaat - fundering (ARCHICAD Classification); Material: WSP_beton - ihwg beton
CPset_Phasing - Renovation Phase: Bestaand
Pset_ReinforcementBarPitchOfSlab - Reference: ø300 (schroef)
Component Quantities - WSP_beton - ihwg beton, Mass: 887.213 kg; WSP_beton - ihwg beton, Component Volume (Net): 0.385745 m3; WSP_beton - ihwg beton, Component Volume (Gross): 0.385745 m3
Pset_SlabCommon - Reference: ø300 (schroef); IsExternal: yes; LoadBearing: no

# IfcSlab: Slab 65, 17_WSP_FD_beton - fundatiepaal v21-2:ø300 (schroef):1473569
In: -2 fundering
Classification: Vloerplaat - fundering (ARCHICAD Classification); Material: WSP_beton - ihwg beton
Pset_SlabCommon - Reference: ø300 (schroef); IsExternal: yes; LoadBearing: no
Pset_ReinforcementBarPitchOfSlab - Reference: ø300 (schroef)
CPset_Phasing - Renovation Phase: Bestaand
Component Quantities - WSP_beton - ihwg beton, Mass: 903.056 kg; WSP_beton - ihwg beton, Component Volume (Net): 0.392633 m3; WSP_beton - ihwg beton, Component Volume (Gross): 0.392633 m3

# IfcSlab: Slab 650, 17_WSP_FD_beton - fundatiepaal v21-2:ø300 (schroef):1507226
In: -2 fundering
Classification: Vloerplaat - fundering (ARCHICAD Classification); Material: WSP_beton - ihwg beton
Pset_SlabCommon - Reference: ø300 (schroef); IsExternal: yes; LoadBearing: no
Pset_ReinforcementBarPitchOfSlab - Reference: ø300 (schroef)
CPset_Phasing - Renovation Phase: Bestaand
Component Quantities - WSP_beton - ihwg beton, Mass: 903.056 kg; WSP_beton - ihwg beton, Component Volume (Net): 0.392633 m3; WSP_beton - ihwg beton, Component Volume (Gross): 0.392633 m3

# IfcSlab: Slab 651, 17_WSP_FD_beton - fundatiepaal v21-2:ø300 (schroef):1507225
In: -2 fundering
Classification: Vloerplaat - fundering (ARCHICAD Classification); Material: WSP_beton - ihwg beton
Pset_SlabCommon - Reference: ø300 (schroef); IsExternal: yes; LoadBearing: no
CPset_Phasing - Renovation Phase: Bestaand
Pset_ReinforcementBarPitchOfSlab - Reference: ø300 (schroef)
Component Quantities - WSP_beton - ihwg beton, Mass: 903.056 kg; WSP_beton - ihwg beton, Component Volume (Net): 0.392633 m3; WSP_beton - ihwg beton, Component Volume (Gross): 0.392633 m3

# IfcSlab: Slab 652, 17_WSP_FD_beton - fundatiepaal v21-2:ø300 (schroef):1507224
In: -2 fundering
Classification: Vloerplaat - fundering (ARCHICAD Classification); Material: WSP_beton - ihwg beton
Pset_ReinforcementBarPitchOfSlab - Reference: ø300 (schroef)
Pset_SlabCommon - Reference: ø300 (schroef); IsExternal: yes; LoadBearing: no
Component Quantities - WSP_beton - ihwg beton, Mass: 903.056 kg; WSP_beton - ihwg beton, Component Volume (Net): 0.392633 m3; WSP_beton - ihwg beton, Component Volume (Gross): 0.392633 m3
CPset_Phasing - Renovation Phase: Bestaand

# IfcSlab: Slab 653, 17_WSP_FD_beton - fundatiepaal v21-2:ø300 (schroef):1507223
In: -2 fundering
Classification: Vloerplaat - fundering (ARCHICAD Classification); Material: WSP_beton - ihwg beton
Pset_ReinforcementBarPitchOfSlab - Reference: ø300 (schroef)
Pset_SlabCommon - Reference: ø300 (schroef); IsExternal: yes; LoadBearing: no
Component Quantities - WSP_beton - ihwg beton, Mass: 903.056 kg; WSP_beton - ihwg beton, Component Volume (Net): 0.392633 m3; WSP_beton - ihwg beton, Component Volume (Gross): 0.392633 m3
CPset_Phasing - Renovation Phase: Bestaand

# IfcSlab: Slab 654, 17_WSP_FD_beton - fundatiepaal v21-2:ø300 (schroef):1507222
In: -2 fundering
Classification: Vloerplaat - fundering (ARCHICAD Classification); Material: WSP_beton - ihwg beton
Pset_SlabCommon - Reference: ø300 (schroef); IsExternal: yes; LoadBearing: no
Pset_ReinforcementBarPitchOfSlab - Reference: ø300 (schroef)
CPset_Phasing - Renovation Phase: Bestaand
Component Quantities - WSP_beton - ihwg beton, Mass: 903.056 kg; WSP_beton - ihwg beton, Component Volume (Net): 0.392633 m3; WSP_beton - ihwg beton, Component Volume (Gross): 0.392633 m3

# IfcSlab: Slab 655, 17_WSP_FD_beton - fundatiepaal v21-2:ø300 (schroef):1507221
In: -2 fundering
Classification: Vloerplaat - fundering (ARCHICAD Classification); Material: WSP_beton - ihwg beton
CPset_Phasing - Renovation Phase: Bestaand
Pset_ReinforcementBarPitchOfSlab - Reference: ø300 (schroef)
Pset_SlabCommon - Reference: ø300 (schroef); IsExternal: yes; LoadBearing: no
Component Quantities - WSP_beton - ihwg beton, Mass: 903.056 kg; WSP_beton - ihwg beton, Component Volume (Net): 0.392633 m3; WSP_beton - ihwg beton, Component Volume (Gross): 0.392633 m3

# IfcSlab: Slab 656, 17_WSP_FD_beton - fundatiepaal v21-2:ø300 (schroef):1507220
In: -2 fundering
Classification: Vloerplaat - fundering (ARCHICAD Classification); Material: WSP_beton - ihwg beton
Pset_ReinforcementBarPitchOfSlab - Reference: ø300 (schroef)
Pset_SlabCommon - Reference: ø300 (schroef); IsExternal: yes; LoadBearing: no
CPset_Phasing - Renovation Phase: Bestaand
Component Quantities - WSP_beton - ihwg beton, Mass: 903.056 kg; WSP_beton - ihwg beton, Component Volume (Net): 0.392633 m3; WSP_beton - ihwg beton, Component Volume (Gross): 0.392633 m3

# IfcSlab: Slab 657, 17_WSP_FD_beton - fundatiepaal v21-2:ø300 (schroef):1507219
In: -2 fundering
Classification: Vloerplaat - fundering (ARCHICAD Classification); Material: WSP_beton - ihwg beton
Pset_ReinforcementBarPitchOfSlab - Reference: ø300 (schroef)
Pset_SlabCommon - Reference: ø300 (schroef); IsExternal: yes; LoadBearing: no
Component Quantities - WSP_beton - ihwg beton, Mass: 903.056 kg; WSP_beton - ihwg beton, Component Volume (Net): 0.392633 m3; WSP_beton - ihwg beton, Component Volume (Gross): 0.392633 m3
CPset_Phasing - Renovation Phase: Bestaand

# IfcSlab: Slab 658, 17_WSP_FD_beton - fundatiepaal v21-2:ø300 (schroef):1507218
In: -2 fundering
Classification: Vloerplaat - fundering (ARCHICAD Classification); Material: WSP_beton - ihwg beton
Pset_SlabCommon - Reference: ø300 (schroef); IsExternal: yes; LoadBearing: no
Pset_ReinforcementBarPitchOfSlab - Reference: ø300 (schroef)
Component Quantities - WSP_beton - ihwg beton, Mass: 903.056 kg; WSP_beton - ihwg beton, Component Volume (Net): 0.392633 m3; WSP_beton - ihwg beton, Component Volume (Gross): 0.392633 m3
CPset_Phasing - Renovation Phase: Bestaand

# IfcSlab: Slab 659, 17_WSP_FD_beton - fundatiepaal v21-2:ø300 (schroef):1507217
In: -2 fundering
Classification: Vloerplaat - fundering (ARCHICAD Classification); Material: WSP_beton - ihwg beton
Pset_SlabCommon - Reference: ø300 (schroef); IsExternal: yes; LoadBearing: no
CPset_Phasing - Renovation Phase: Bestaand
Component Quantities - WSP_beton - ihwg beton, Mass: 903.056 kg; WSP_beton - ihwg beton, Component Volume (Net): 0.392633 m3; WSP_beton - ihwg beton, Component Volume (Gross): 0.392633 m3
Pset_ReinforcementBarPitchOfSlab - Reference: ø300 (schroef)

# IfcSlab: Slab 66, 17_WSP_FD_beton - fundatiepaal v21-2:ø300 (schroef):1473574
In: -2 fundering
Classification: Vloerplaat - fundering (ARCHICAD Classification); Material: WSP_beton - ihwg beton
Pset_SlabCommon - Reference: ø300 (schroef); IsExternal: yes; LoadBearing: no
Component Quantities - WSP_beton - ihwg beton, Mass: 903.056 kg; WSP_beton - ihwg beton, Component Volume (Net): 0.392633 m3; WSP_beton - ihwg beton, Component Volume (Gross): 0.392633 m3
Pset_ReinforcementBarPitchOfSlab - Reference: ø300 (schroef)
CPset_Phasing - Renovation Phase: Bestaand

# IfcSlab: Slab 660, 17_WSP_FD_beton - fundatiepaal v21-2:ø300 (schroef):1507216
In: -2 fundering
Classification: Vloerplaat - fundering (ARCHICAD Classification); Material: WSP_beton - ihwg beton
Pset_SlabCommon - Reference: ø300 (schroef); IsExternal: yes; LoadBearing: no
CPset_Phasing - Renovation Phase: Bestaand
Pset_ReinforcementBarPitchOfSlab - Reference: ø300 (schroef)
Component Quantities - WSP_beton - ihwg beton, Mass: 903.056 kg; WSP_beton - ihwg beton, Component Volume (Net): 0.392633 m3; WSP_beton - ihwg beton, Component Volume (Gross): 0.392633 m3

# IfcSlab: Slab 661, 17_WSP_FD_beton - fundatiepaal v21-2:ø300 (schroef):1506863
In: -2 fundering
Classification: Vloerplaat - fundering (ARCHICAD Classification); Material: WSP_beton - ihwg beton
Pset_SlabCommon - Reference: ø300 (schroef); IsExternal: yes; LoadBearing: no
Pset_ReinforcementBarPitchOfSlab - Reference: ø300 (schroef)
CPset_Phasing - Renovation Phase: Bestaand
Component Quantities - WSP_beton - ihwg beton, Mass: 903.056 kg; WSP_beton - ihwg beton, Component Volume (Net): 0.392633 m3; WSP_beton - ihwg beton, Component Volume (Gross): 0.392633 m3

# IfcSlab: Slab 662, 17_WSP_FD_beton - fundatiepaal v21-2:ø300 (schroef):1506862
In: -2 fundering
Classification: Vloerplaat - fundering (ARCHICAD Classification); Material: WSP_beton - ihwg beton
Pset_ReinforcementBarPitchOfSlab - Reference: ø300 (schroef)
CPset_Phasing - Renovation Phase: Bestaand
Pset_SlabCommon - Reference: ø300 (schroef); IsExternal: yes; LoadBearing: no
Component Quantities - WSP_beton - ihwg beton, Mass: 903.056 kg; WSP_beton - ihwg beton, Component Volume (Net): 0.392633 m3; WSP_beton - ihwg beton, Component Volume (Gross): 0.392633 m3

# IfcSlab: Slab 663, 17_WSP_FD_beton - fundatiepaal v21-2:ø300 (schroef):1506861
In: -2 fundering
Classification: Vloerplaat - fundering (ARCHICAD Classification); Material: WSP_beton - ihwg beton
Pset_ReinforcementBarPitchOfSlab - Reference: ø300 (schroef)
Pset_SlabCommon - Reference: ø300 (schroef); IsExternal: yes; LoadBearing: no
CPset_Phasing - Renovation Phase: Bestaand
Component Quantities - WSP_beton - ihwg beton, Mass: 903.056 kg; WSP_beton - ihwg beton, Component Volume (Net): 0.392633 m3; WSP_beton - ihwg beton, Component Volume (Gross): 0.392633 m3

# IfcSlab: Slab 664, 17_WSP_FD_beton - fundatiepaal v21-2:ø300 (schroef):1506860
In: -2 fundering
Classification: Vloerplaat - fundering (ARCHICAD Classification); Material: WSP_beton - ihwg beton
CPset_Phasing - Renovation Phase: Bestaand
Component Quantities - WSP_beton - ihwg beton, Mass: 903.056 kg; WSP_beton - ihwg beton, Component Volume (Net): 0.392633 m3; WSP_beton - ihwg beton, Component Volume (Gross): 0.392633 m3
Pset_ReinforcementBarPitchOfSlab - Reference: ø300 (schroef)
Pset_SlabCommon - Reference: ø300 (schroef); IsExternal: yes; LoadBearing: no

# IfcSlab: Slab 665, 17_WSP_FD_beton - fundatiepaal v21-2:ø300 (schroef):1506859
In: -2 fundering
Classification: Vloerplaat - fundering (ARCHICAD Classification); Material: WSP_beton - ihwg beton
Pset_SlabCommon - Reference: ø300 (schroef); IsExternal: yes; LoadBearing: no
Component Quantities - WSP_beton - ihwg beton, Mass: 903.056 kg; WSP_beton - ihwg beton, Component Volume (Net): 0.392633 m3; WSP_beton - ihwg beton, Component Volume (Gross): 0.392633 m3
Pset_ReinforcementBarPitchOfSlab - Reference: ø300 (schroef)
CPset_Phasing - Renovation Phase: Bestaand

# IfcSlab: Slab 666, 17_WSP_FD_beton - fundatiepaal v21-2:ø300 (schroef):1506858
In: -2 fundering
Classification: Vloerplaat - fundering (ARCHICAD Classification); Material: WSP_beton - ihwg beton
Pset_SlabCommon - Reference: ø300 (schroef); IsExternal: yes; LoadBearing: no
Pset_ReinforcementBarPitchOfSlab - Reference: ø300 (schroef)
CPset_Phasing - Renovation Phase: Bestaand
Component Quantities - WSP_beton - ihwg beton, Mass: 903.056 kg; WSP_beton - ihwg beton, Component Volume (Net): 0.392633 m3; WSP_beton - ihwg beton, Component Volume (Gross): 0.392633 m3

# IfcSlab: Slab 667, 17_WSP_FD_beton - fundatiepaal v21-2:ø300 (schroef):1506857
In: -2 fundering
Classification: Vloerplaat - fundering (ARCHICAD Classification); Material: WSP_beton - ihwg beton
Pset_SlabCommon - Reference: ø300 (schroef); IsExternal: yes; LoadBearing: no
Component Quantities - WSP_beton - ihwg beton, Mass: 903.056 kg; WSP_beton - ihwg beton, Component Volume (Net): 0.392633 m3; WSP_beton - ihwg beton, Component Volume (Gross): 0.392633 m3
CPset_Phasing - Renovation Phase: Bestaand
Pset_ReinforcementBarPitchOfSlab - Reference: ø300 (schroef)

# IfcSlab: Slab 668, 17_WSP_FD_beton - fundatiepaal v21-2:ø300 (schroef):1506856
In: -2 fundering
Classification: Vloerplaat - fundering (ARCHICAD Classification); Material: WSP_beton - ihwg beton
Pset_ReinforcementBarPitchOfSlab - Reference: ø300 (schroef)
Component Quantities - WSP_beton - ihwg beton, Mass: 903.056 kg; WSP_beton - ihwg beton, Component Volume (Net): 0.392633 m3; WSP_beton - ihwg beton, Component Volume (Gross): 0.392633 m3
Pset_SlabCommon - Reference: ø300 (schroef); IsExternal: yes; LoadBearing: no
CPset_Phasing - Renovation Phase: Bestaand

# IfcSlab: Slab 669, 17_WSP_FD_beton - fundatiepaal v21-2:ø300 (schroef):1506855
In: -2 fundering
Classification: Vloerplaat - fundering (ARCHICAD Classification); Material: WSP_beton - ihwg beton
Pset_SlabCommon - Reference: ø300 (schroef); IsExternal: yes; LoadBearing: no
Pset_ReinforcementBarPitchOfSlab - Reference: ø300 (schroef)
Component Quantities - WSP_beton - ihwg beton, Mass: 903.056 kg; WSP_beton - ihwg beton, Component Volume (Net): 0.392633 m3; WSP_beton - ihwg beton, Component Volume (Gross): 0.392633 m3
CPset_Phasing - Renovation Phase: Bestaand

# IfcSlab: Slab 67, 17_WSP_FD_beton - fundatiepaal v21-2:ø300 (schroef):1473575
In: -2 fundering
Classification: Vloerplaat - fundering (ARCHICAD Classification); Material: WSP_beton - ihwg beton
Pset_SlabCommon - Reference: ø300 (schroef); IsExternal: yes; LoadBearing: no
Pset_ReinforcementBarPitchOfSlab - Reference: ø300 (schroef)
Component Quantities - WSP_beton - ihwg beton, Mass: 903.056 kg; WSP_beton - ihwg beton, Component Volume (Net): 0.392633 m3; WSP_beton - ihwg beton, Component Volume (Gross): 0.392633 m3
CPset_Phasing - Renovation Phase: Bestaand

# IfcSlab: Slab 670, 17_WSP_FD_beton - fundatiepaal v21-2:ø300 (schroef):1506854
In: -2 fundering
Classification: Vloerplaat - fundering (ARCHICAD Classification); Material: WSP_beton - ihwg beton
Pset_ReinforcementBarPitchOfSlab - Reference: ø300 (schroef)
Pset_SlabCommon - Reference: ø300 (schroef); IsExternal: yes; LoadBearing: no
Component Quantities - WSP_beton - ihwg beton, Mass: 903.056 kg; WSP_beton - ihwg beton, Component Volume (Net): 0.392633 m3; WSP_beton - ihwg beton, Component Volume (Gross): 0.392633 m3
CPset_Phasing - Renovation Phase: Bestaand

# IfcSlab: Slab 671, 17_WSP_FD_beton - fundatiepaal v21-2:ø300 (schroef):1506853
In: -2 fundering
Classification: Vloerplaat - fundering (ARCHICAD Classification); Material: WSP_beton - ihwg beton
Pset_ReinforcementBarPitchOfSlab - Reference: ø300 (schroef)
CPset_Phasing - Renovation Phase: Bestaand
Pset_SlabCommon - Reference: ø300 (schroef); IsExternal: yes; LoadBearing: no
Component Quantities - WSP_beton - ihwg beton, Mass: 903.056 kg; WSP_beton - ihwg beton, Component Volume (Net): 0.392633 m3; WSP_beton - ihwg beton, Component Volume (Gross): 0.392633 m3

# IfcSlab: Slab 672, 17_WSP_FD_beton - fundatiepaal v21-2:ø300 (schroef):1506852
In: -2 fundering
Classification: Vloerplaat - fundering (ARCHICAD Classification); Material: WSP_beton - ihwg beton
Pset_SlabCommon - Reference: ø300 (schroef); IsExternal: yes; LoadBearing: no
Pset_ReinforcementBarPitchOfSlab - Reference: ø300 (schroef)
CPset_Phasing - Renovation Phase: Bestaand
Component Quantities - WSP_beton - ihwg beton, Mass: 903.056 kg; WSP_beton - ihwg beton, Component Volume (Net): 0.392633 m3; WSP_beton - ihwg beton, Component Volume (Gross): 0.392633 m3

# IfcSlab: Slab 673, 17_WSP_FD_beton - fundatiepaal v21-2:ø300 (schroef):1506851
In: -2 fundering
Classification: Vloerplaat - fundering (ARCHICAD Classification); Material: WSP_beton - ihwg beton
Component Quantities - WSP_beton - ihwg beton, Mass: 903.056 kg; WSP_beton - ihwg beton, Component Volume (Net): 0.392633 m3; WSP_beton - ihwg beton, Component Volume (Gross): 0.392633 m3
CPset_Phasing - Renovation Phase: Bestaand
Pset_SlabCommon - Reference: ø300 (schroef); IsExternal: yes; LoadBearing: no
Pset_ReinforcementBarPitchOfSlab - Reference: ø300 (schroef)

# IfcSlab: Slab 674, 17_WSP_FD_beton - fundatiepaal v21-2:ø300 (schroef):1506850
In: -2 fundering
Classification: Vloerplaat - fundering (ARCHICAD Classification); Material: WSP_beton - ihwg beton
Component Quantities - WSP_beton - ihwg beton, Mass: 903.056 kg; WSP_beton - ihwg beton, Component Volume (Net): 0.392633 m3; WSP_beton - ihwg beton, Component Volume (Gross): 0.392633 m3
CPset_Phasing - Renovation Phase: Bestaand
Pset_ReinforcementBarPitchOfSlab - Reference: ø300 (schroef)
Pset_SlabCommon - Reference: ø300 (schroef); IsExternal: yes; LoadBearing: no

# IfcSlab: Slab 675, 17_WSP_FD_beton - fundatiepaal v21-2:ø300 (schroef):1506849
In: -2 fundering
Classification: Vloerplaat - fundering (ARCHICAD Classification); Material: WSP_beton - ihwg beton
Pset_SlabCommon - Reference: ø300 (schroef); IsExternal: yes; LoadBearing: no
Pset_ReinforcementBarPitchOfSlab - Reference: ø300 (schroef)
Component Quantities - WSP_beton - ihwg beton, Mass: 903.056 kg; WSP_beton - ihwg beton, Component Volume (Net): 0.392633 m3; WSP_beton - ihwg beton, Component Volume (Gross): 0.392633 m3
CPset_Phasing - Renovation Phase: Bestaand

# IfcSlab: Slab 676, 17_WSP_FD_beton - fundatiepaal v21-2:ø300 (schroef):1506848
In: -2 fundering
Classification: Vloerplaat - fundering (ARCHICAD Classification); Material: WSP_beton - ihwg beton
Pset_SlabCommon - Reference: ø300 (schroef); IsExternal: yes; LoadBearing: no
CPset_Phasing - Renovation Phase: Bestaand
Component Quantities - WSP_beton - ihwg beton, Mass: 903.056 kg; WSP_beton - ihwg beton, Component Volume (Net): 0.392633 m3; WSP_beton - ihwg beton, Component Volume (Gross): 0.392633 m3
Pset_ReinforcementBarPitchOfSlab - Reference: ø300 (schroef)

# IfcSlab: Slab 677, 17_WSP_FD_beton - fundatiepaal v21-2:ø300 (schroef):1506879
In: -2 fundering
Classification: Vloerplaat - fundering (ARCHICAD Classification); Material: WSP_beton - ihwg beton
Pset_SlabCommon - Reference: ø300 (schroef); IsExternal: yes; LoadBearing: no
CPset_Phasing - Renovation Phase: Bestaand
Component Quantities - WSP_beton - ihwg beton, Mass: 903.056 kg; WSP_beton - ihwg beton, Component Volume (Net): 0.392633 m3; WSP_beton - ihwg beton, Component Volume (Gross): 0.392633 m3
Pset_ReinforcementBarPitchOfSlab - Reference: ø300 (schroef)

# IfcSlab: Slab 678, 17_WSP_FD_beton - fundatiepaal v21-2:ø300 (schroef):1506878
In: -2 fundering
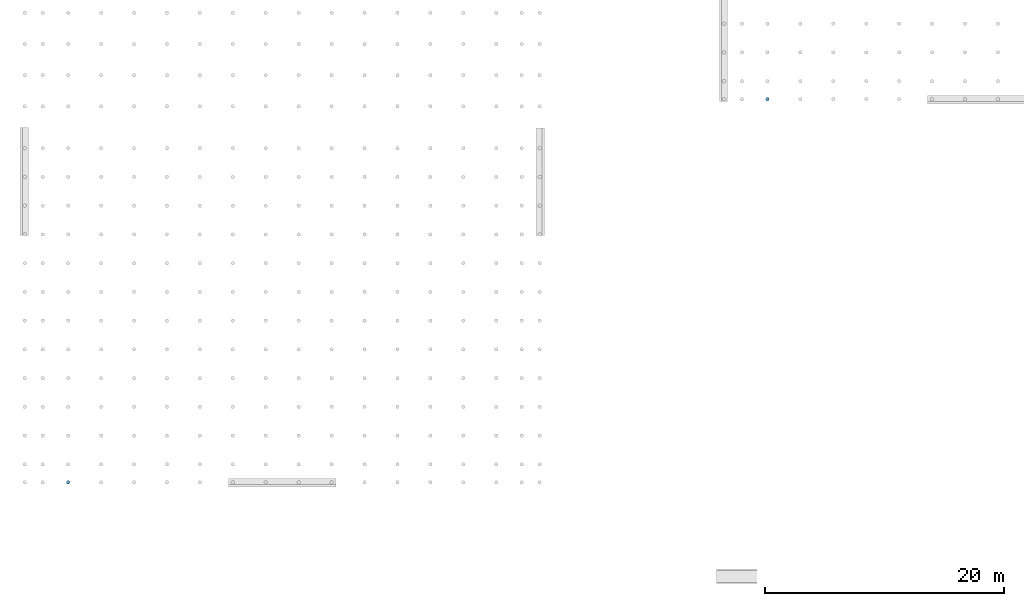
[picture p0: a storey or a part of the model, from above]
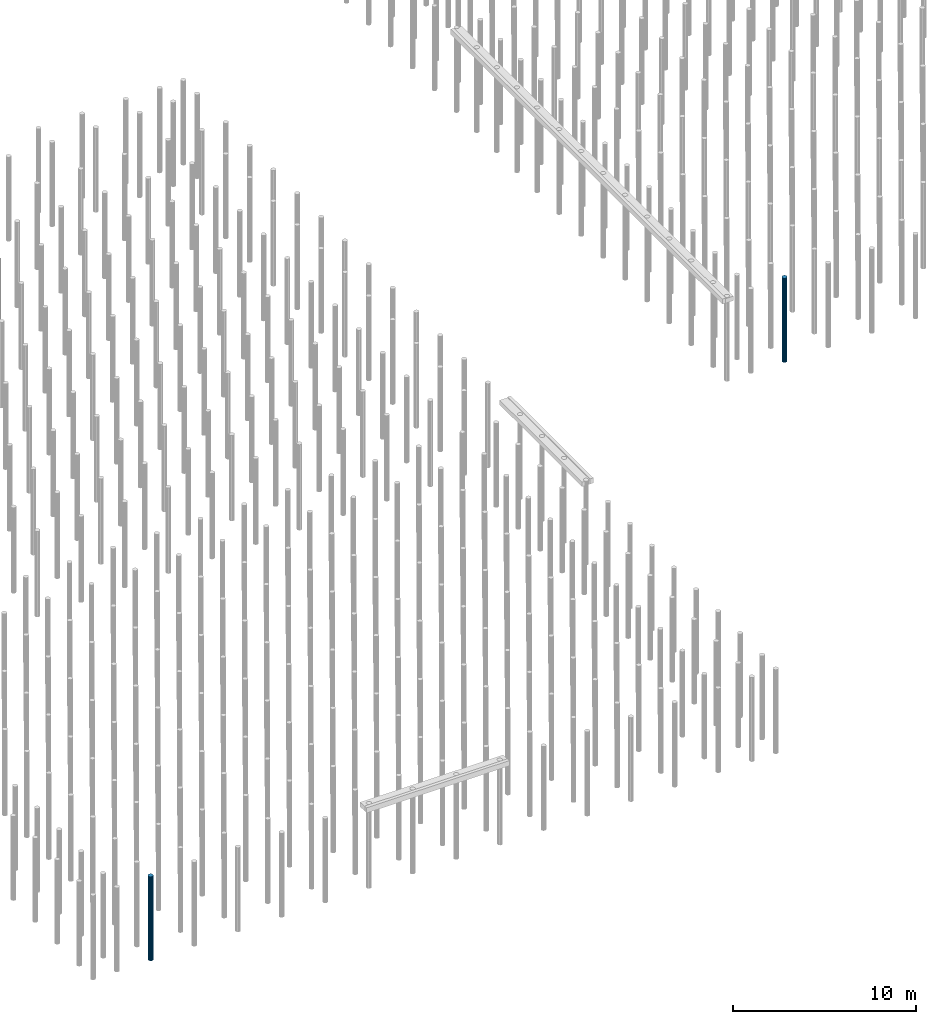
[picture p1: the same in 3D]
Properties of the parts of a building model (IFC2X3), part 9 of 13

# IfcSlab: Slab 678, 17_WSP_FD_beton - fundatiepaal v21-2:ø300 (schroef):1506878
Classification: Vloerplaat - fundering (ARCHICAD Classification); Material: WSP_beton - ihwg beton
Pset_SlabCommon - Reference: ø300 (schroef); IsExternal: yes; LoadBearing: no
CPset_Phasing - Renovation Phase: Bestaand
Pset_ReinforcementBarPitchOfSlab - Reference: ø300 (schroef)
Component Quantities - WSP_beton - ihwg beton, Mass: 903.056 kg; WSP_beton - ihwg beton, Component Volume (Net): 0.392633 m3; WSP_beton - ihwg beton, Component Volume (Gross): 0.392633 m3

# IfcSlab: Slab 679, 17_WSP_FD_beton - fundatiepaal v21-2:ø300 (schroef):1506877
In: -2 fundering
Classification: Vloerplaat - fundering (ARCHICAD Classification); Material: WSP_beton - ihwg beton
Pset_SlabCommon - Reference: ø300 (schroef); IsExternal: yes; LoadBearing: no
Pset_ReinforcementBarPitchOfSlab - Reference: ø300 (schroef)
Component Quantities - WSP_beton - ihwg beton, Mass: 903.056 kg; WSP_beton - ihwg beton, Component Volume (Net): 0.392633 m3; WSP_beton - ihwg beton, Component Volume (Gross): 0.392633 m3
CPset_Phasing - Renovation Phase: Bestaand

# IfcSlab: Slab 68, 17_WSP_FD_beton - fundatiepaal v21-2:ø300 (schroef):1473572
In: -2 fundering
Classification: Vloerplaat - fundering (ARCHICAD Classification); Material: WSP_beton - ihwg beton
Pset_ReinforcementBarPitchOfSlab - Reference: ø300 (schroef)
Pset_SlabCommon - Reference: ø300 (schroef); IsExternal: yes; LoadBearing: no
Component Quantities - WSP_beton - ihwg beton, Mass: 903.056 kg; WSP_beton - ihwg beton, Component Volume (Net): 0.392633 m3; WSP_beton - ihwg beton, Component Volume (Gross): 0.392633 m3
CPset_Phasing - Renovation Phase: Bestaand

# IfcSlab: Slab 680, 17_WSP_FD_beton - fundatiepaal v21-2:ø300 (schroef):1506876
In: -2 fundering
Classification: Vloerplaat - fundering (ARCHICAD Classification); Material: WSP_beton - ihwg beton
Pset_SlabCommon - Reference: ø300 (schroef); IsExternal: yes; LoadBearing: no
Pset_ReinforcementBarPitchOfSlab - Reference: ø300 (schroef)
Component Quantities - WSP_beton - ihwg beton, Mass: 903.056 kg; WSP_beton - ihwg beton, Component Volume (Net): 0.392633 m3; WSP_beton - ihwg beton, Component Volume (Gross): 0.392633 m3
CPset_Phasing - Renovation Phase: Bestaand

# IfcSlab: Slab 681, 17_WSP_FD_beton - fundatiepaal v21-2:ø300 (schroef):1506875
In: -2 fundering
Classification: Vloerplaat - fundering (ARCHICAD Classification); Material: WSP_beton - ihwg beton
Pset_ReinforcementBarPitchOfSlab - Reference: ø300 (schroef)
Component Quantities - WSP_beton - ihwg beton, Mass: 903.056 kg; WSP_beton - ihwg beton, Component Volume (Net): 0.392633 m3; WSP_beton - ihwg beton, Component Volume (Gross): 0.392633 m3
CPset_Phasing - Renovation Phase: Bestaand
Pset_SlabCommon - Reference: ø300 (schroef); IsExternal: yes; LoadBearing: no

# IfcSlab: Slab 682, 17_WSP_FD_beton - fundatiepaal v21-2:ø300 (schroef):1506874
In: -2 fundering
Classification: Vloerplaat - fundering (ARCHICAD Classification); Material: WSP_beton - ihwg beton
Pset_ReinforcementBarPitchOfSlab - Reference: ø300 (schroef)
CPset_Phasing - Renovation Phase: Bestaand
Pset_SlabCommon - Reference: ø300 (schroef); IsExternal: yes; LoadBearing: no
Component Quantities - WSP_beton - ihwg beton, Mass: 903.056 kg; WSP_beton - ihwg beton, Component Volume (Net): 0.392633 m3; WSP_beton - ihwg beton, Component Volume (Gross): 0.392633 m3

# IfcSlab: Slab 683, 17_WSP_FD_beton - fundatiepaal v21-2:ø300 (schroef):1506873
In: -2 fundering
Classification: Vloerplaat - fundering (ARCHICAD Classification); Material: WSP_beton - ihwg beton
Pset_SlabCommon - Reference: ø300 (schroef); IsExternal: yes; LoadBearing: no
CPset_Phasing - Renovation Phase: Bestaand
Pset_ReinforcementBarPitchOfSlab - Reference: ø300 (schroef)
Component Quantities - WSP_beton - ihwg beton, Mass: 903.056 kg; WSP_beton - ihwg beton, Component Volume (Net): 0.392633 m3; WSP_beton - ihwg beton, Component Volume (Gross): 0.392633 m3

# IfcSlab: Slab 684, 17_WSP_FD_beton - fundatiepaal v21-2:ø300 (schroef):1506872
In: -2 fundering
Classification: Vloerplaat - fundering (ARCHICAD Classification); Material: WSP_beton - ihwg beton
Pset_SlabCommon - Reference: ø300 (schroef); IsExternal: yes; LoadBearing: no
Pset_ReinforcementBarPitchOfSlab - Reference: ø300 (schroef)
CPset_Phasing - Renovation Phase: Bestaand
Component Quantities - WSP_beton - ihwg beton, Mass: 903.056 kg; WSP_beton - ihwg beton, Component Volume (Net): 0.392633 m3; WSP_beton - ihwg beton, Component Volume (Gross): 0.392633 m3

# IfcSlab: Slab 685, 17_WSP_FD_beton - fundatiepaal v21-2:ø300 (schroef):1506871
In: -2 fundering
Classification: Vloerplaat - fundering (ARCHICAD Classification); Material: WSP_beton - ihwg beton
Component Quantities - WSP_beton - ihwg beton, Mass: 903.056 kg; WSP_beton - ihwg beton, Component Volume (Net): 0.392633 m3; WSP_beton - ihwg beton, Component Volume (Gross): 0.392633 m3
Pset_ReinforcementBarPitchOfSlab - Reference: ø300 (schroef)
Pset_SlabCommon - Reference: ø300 (schroef); IsExternal: yes; LoadBearing: no
CPset_Phasing - Renovation Phase: Bestaand

# IfcSlab: Slab 686, 17_WSP_FD_beton - fundatiepaal v21-2:ø300 (schroef):1506870
In: -2 fundering
Classification: Vloerplaat - fundering (ARCHICAD Classification); Material: WSP_beton - ihwg beton
CPset_Phasing - Renovation Phase: Bestaand
Pset_ReinforcementBarPitchOfSlab - Reference: ø300 (schroef)
Component Quantities - WSP_beton - ihwg beton, Mass: 903.056 kg; WSP_beton - ihwg beton, Component Volume (Net): 0.392633 m3; WSP_beton - ihwg beton, Component Volume (Gross): 0.392633 m3
Pset_SlabCommon - Reference: ø300 (schroef); IsExternal: yes; LoadBearing: no

# IfcSlab: Slab 687, 17_WSP_FD_beton - fundatiepaal v21-2:ø300 (schroef):1506869
In: -2 fundering
Classification: Vloerplaat - fundering (ARCHICAD Classification); Material: WSP_beton - ihwg beton
Pset_SlabCommon - Reference: ø300 (schroef); IsExternal: yes; LoadBearing: no
Pset_ReinforcementBarPitchOfSlab - Reference: ø300 (schroef)
CPset_Phasing - Renovation Phase: Bestaand
Component Quantities - WSP_beton - ihwg beton, Mass: 903.056 kg; WSP_beton - ihwg beton, Component Volume (Net): 0.392633 m3; WSP_beton - ihwg beton, Component Volume (Gross): 0.392633 m3

# IfcSlab: Slab 688, 17_WSP_FD_beton - fundatiepaal v21-2:ø300 (schroef):1506868
In: -2 fundering
Classification: Vloerplaat - fundering (ARCHICAD Classification); Material: WSP_beton - ihwg beton
Pset_SlabCommon - Reference: ø300 (schroef); IsExternal: yes; LoadBearing: no
CPset_Phasing - Renovation Phase: Bestaand
Pset_ReinforcementBarPitchOfSlab - Reference: ø300 (schroef)
Component Quantities - WSP_beton - ihwg beton, Mass: 903.056 kg; WSP_beton - ihwg beton, Component Volume (Net): 0.392633 m3; WSP_beton - ihwg beton, Component Volume (Gross): 0.392633 m3

# IfcSlab: Slab 689, 17_WSP_FD_beton - fundatiepaal v21-2:ø300 (schroef):1506867
In: -2 fundering
Classification: Vloerplaat - fundering (ARCHICAD Classification); Material: WSP_beton - ihwg beton
Pset_SlabCommon - Reference: ø300 (schroef); IsExternal: yes; LoadBearing: no
CPset_Phasing - Renovation Phase: Bestaand
Pset_ReinforcementBarPitchOfSlab - Reference: ø300 (schroef)
Component Quantities - WSP_beton - ihwg beton, Mass: 903.056 kg; WSP_beton - ihwg beton, Component Volume (Net): 0.392633 m3; WSP_beton - ihwg beton, Component Volume (Gross): 0.392633 m3

# IfcSlab: Slab 69, 17_WSP_FD_beton - fundatiepaal v21-2:ø300 (schroef):1473573
In: -2 fundering
Classification: Vloerplaat - fundering (ARCHICAD Classification); Material: WSP_beton - ihwg beton
Pset_SlabCommon - Reference: ø300 (schroef); IsExternal: yes; LoadBearing: no
Pset_ReinforcementBarPitchOfSlab - Reference: ø300 (schroef)
Component Quantities - WSP_beton - ihwg beton, Mass: 903.056 kg; WSP_beton - ihwg beton, Component Volume (Net): 0.392633 m3; WSP_beton - ihwg beton, Component Volume (Gross): 0.392633 m3
CPset_Phasing - Renovation Phase: Bestaand

# IfcSlab: Slab 690, 17_WSP_FD_beton - fundatiepaal v21-2:ø300 (schroef):1506866
In: -2 fundering
Classification: Vloerplaat - fundering (ARCHICAD Classification); Material: WSP_beton - ihwg beton
Pset_SlabCommon - Reference: ø300 (schroef); IsExternal: yes; LoadBearing: no
Pset_ReinforcementBarPitchOfSlab - Reference: ø300 (schroef)
CPset_Phasing - Renovation Phase: Bestaand
Component Quantities - WSP_beton - ihwg beton, Mass: 903.056 kg; WSP_beton - ihwg beton, Component Volume (Net): 0.392633 m3; WSP_beton - ihwg beton, Component Volume (Gross): 0.392633 m3

# IfcSlab: Slab 691, 17_WSP_FD_beton - fundatiepaal v21-2:ø300 (schroef):1506865
In: -2 fundering
Classification: Vloerplaat - fundering (ARCHICAD Classification); Material: WSP_beton - ihwg beton
Pset_ReinforcementBarPitchOfSlab - Reference: ø300 (schroef)
Pset_SlabCommon - Reference: ø300 (schroef); IsExternal: yes; LoadBearing: no
CPset_Phasing - Renovation Phase: Bestaand
Component Quantities - WSP_beton - ihwg beton, Mass: 903.056 kg; WSP_beton - ihwg beton, Component Volume (Net): 0.392633 m3; WSP_beton - ihwg beton, Component Volume (Gross): 0.392633 m3

# IfcSlab: Slab 692, 17_WSP_FD_beton - fundatiepaal v21-2:ø300 (schroef):1506864
In: -2 fundering
Classification: Vloerplaat - fundering (ARCHICAD Classification); Material: WSP_beton - ihwg beton
Pset_SlabCommon - Reference: ø300 (schroef); IsExternal: yes; LoadBearing: no
Pset_ReinforcementBarPitchOfSlab - Reference: ø300 (schroef)
Component Quantities - WSP_beton - ihwg beton, Mass: 903.056 kg; WSP_beton - ihwg beton, Component Volume (Net): 0.392633 m3; WSP_beton - ihwg beton, Component Volume (Gross): 0.392633 m3
CPset_Phasing - Renovation Phase: Bestaand

# IfcSlab: Slab 693, 17_WSP_FD_beton - fundatiepaal v21-2:ø300 (schroef):1506831
In: -2 fundering
Classification: Vloerplaat - fundering (ARCHICAD Classification); Material: WSP_beton - ihwg beton
CPset_Phasing - Renovation Phase: Bestaand
Pset_ReinforcementBarPitchOfSlab - Reference: ø300 (schroef)
Component Quantities - WSP_beton - ihwg beton, Mass: 887.213 kg; WSP_beton - ihwg beton, Component Volume (Net): 0.385745 m3; WSP_beton - ihwg beton, Component Volume (Gross): 0.385745 m3
Pset_SlabCommon - Reference: ø300 (schroef); IsExternal: yes; LoadBearing: no

# IfcSlab: Slab 694, 17_WSP_FD_beton - fundatiepaal v21-2:ø300 (schroef):1506830
In: -2 fundering
Classification: Vloerplaat - fundering (ARCHICAD Classification); Material: WSP_beton - ihwg beton
Pset_SlabCommon - Reference: ø300 (schroef); IsExternal: yes; LoadBearing: no
Pset_ReinforcementBarPitchOfSlab - Reference: ø300 (schroef)
CPset_Phasing - Renovation Phase: Bestaand
Component Quantities - WSP_beton - ihwg beton, Mass: 887.213 kg; WSP_beton - ihwg beton, Component Volume (Net): 0.385745 m3; WSP_beton - ihwg beton, Component Volume (Gross): 0.385745 m3

# IfcSlab: Slab 695, 17_WSP_FD_beton - fundatiepaal v21-2:ø300 (schroef):1506829
In: -2 fundering
Classification: Vloerplaat - fundering (ARCHICAD Classification); Material: WSP_beton - ihwg beton
Pset_ReinforcementBarPitchOfSlab - Reference: ø300 (schroef)
Pset_SlabCommon - Reference: ø300 (schroef); IsExternal: yes; LoadBearing: no
Component Quantities - WSP_beton - ihwg beton, Mass: 887.213 kg; WSP_beton - ihwg beton, Component Volume (Net): 0.385745 m3; WSP_beton - ihwg beton, Component Volume (Gross): 0.385745 m3
CPset_Phasing - Renovation Phase: Bestaand

# IfcSlab: Slab 696, 17_WSP_FD_beton - fundatiepaal v21-2:ø300 (schroef):1506828
In: -2 fundering
Classification: Vloerplaat - fundering (ARCHICAD Classification); Material: WSP_beton - ihwg beton
Pset_SlabCommon - Reference: ø300 (schroef); IsExternal: yes; LoadBearing: no
CPset_Phasing - Renovation Phase: Bestaand
Component Quantities - WSP_beton - ihwg beton, Mass: 887.213 kg; WSP_beton - ihwg beton, Component Volume (Net): 0.385745 m3; WSP_beton - ihwg beton, Component Volume (Gross): 0.385745 m3
Pset_ReinforcementBarPitchOfSlab - Reference: ø300 (schroef)

# IfcSlab: Slab 697, 17_WSP_FD_beton - fundatiepaal v21-2:ø300 (schroef):1506827
In: -2 fundering
Classification: Vloerplaat - fundering (ARCHICAD Classification); Material: WSP_beton - ihwg beton
Pset_SlabCommon - Reference: ø300 (schroef); IsExternal: yes; LoadBearing: no
Component Quantities - WSP_beton - ihwg beton, Mass: 887.213 kg; WSP_beton - ihwg beton, Component Volume (Net): 0.385745 m3; WSP_beton - ihwg beton, Component Volume (Gross): 0.385745 m3
Pset_ReinforcementBarPitchOfSlab - Reference: ø300 (schroef)
CPset_Phasing - Renovation Phase: Bestaand

# IfcSlab: Slab 698, 17_WSP_FD_beton - fundatiepaal v21-2:ø300 (schroef):1506826
In: -2 fundering
Classification: Vloerplaat - fundering (ARCHICAD Classification); Material: WSP_beton - ihwg beton
Pset_ReinforcementBarPitchOfSlab - Reference: ø300 (schroef)
Pset_SlabCommon - Reference: ø300 (schroef); IsExternal: yes; LoadBearing: no
CPset_Phasing - Renovation Phase: Bestaand
Component Quantities - WSP_beton - ihwg beton, Mass: 887.213 kg; WSP_beton - ihwg beton, Component Volume (Net): 0.385745 m3; WSP_beton - ihwg beton, Component Volume (Gross): 0.385745 m3

# IfcSlab: Slab 699, 17_WSP_FD_beton - fundatiepaal v21-2:ø300 (schroef):1506825
In: -2 fundering
Classification: Vloerplaat - fundering (ARCHICAD Classification); Material: WSP_beton - ihwg beton
Pset_ReinforcementBarPitchOfSlab - Reference: ø300 (schroef)
Pset_SlabCommon - Reference: ø300 (schroef); IsExternal: yes; LoadBearing: no
CPset_Phasing - Renovation Phase: Bestaand
Component Quantities - WSP_beton - ihwg beton, Mass: 887.213 kg; WSP_beton - ihwg beton, Component Volume (Net): 0.385745 m3; WSP_beton - ihwg beton, Component Volume (Gross): 0.385745 m3

# IfcSlab: Slab 7, 17_WSP_FD_beton - fundatiepaal v21-2:ø300 (schroef):1528052
In: -2 fundering
Classification: Vloerplaat - fundering (ARCHICAD Classification); Material: WSP_beton - ihwg beton
Pset_SlabCommon - Reference: ø300 (schroef); IsExternal: yes; LoadBearing: no
Component Quantities - WSP_beton - ihwg beton, Mass: 903.056 kg; WSP_beton - ihwg beton, Component Volume (Net): 0.392633 m3; WSP_beton - ihwg beton, Component Volume (Gross): 0.392633 m3
CPset_Phasing - Renovation Phase: Bestaand
Pset_ReinforcementBarPitchOfSlab - Reference: ø300 (schroef)

# IfcSlab: Slab 70, 17_WSP_FD_beton - fundatiepaal v21-2:ø300 (schroef):1473578
In: -2 fundering
Classification: Vloerplaat - fundering (ARCHICAD Classification); Material: WSP_beton - ihwg beton
CPset_Phasing - Renovation Phase: Bestaand
Pset_ReinforcementBarPitchOfSlab - Reference: ø300 (schroef)
Pset_SlabCommon - Reference: ø300 (schroef); IsExternal: yes; LoadBearing: no
Component Quantities - WSP_beton - ihwg beton, Mass: 903.056 kg; WSP_beton - ihwg beton, Component Volume (Net): 0.392633 m3; WSP_beton - ihwg beton, Component Volume (Gross): 0.392633 m3

# IfcSlab: Slab 700, 17_WSP_FD_beton - fundatiepaal v21-2:ø300 (schroef):1506824
In: -2 fundering
Classification: Vloerplaat - fundering (ARCHICAD Classification); Material: WSP_beton - ihwg beton
Pset_SlabCommon - Reference: ø300 (schroef); IsExternal: yes; LoadBearing: no
Component Quantities - WSP_beton - ihwg beton, Mass: 887.213 kg; WSP_beton - ihwg beton, Component Volume (Net): 0.385745 m3; WSP_beton - ihwg beton, Component Volume (Gross): 0.385745 m3
CPset_Phasing - Renovation Phase: Bestaand
Pset_ReinforcementBarPitchOfSlab - Reference: ø300 (schroef)

# IfcSlab: Slab 701, 17_WSP_FD_beton - fundatiepaal v21-2:ø300 (schroef):1506823
In: -2 fundering
Classification: Vloerplaat - fundering (ARCHICAD Classification); Material: WSP_beton - ihwg beton
Pset_ReinforcementBarPitchOfSlab - Reference: ø300 (schroef)
Pset_SlabCommon - Reference: ø300 (schroef); IsExternal: yes; LoadBearing: no
Component Quantities - WSP_beton - ihwg beton, Mass: 887.213 kg; WSP_beton - ihwg beton, Component Volume (Net): 0.385745 m3; WSP_beton - ihwg beton, Component Volume (Gross): 0.385745 m3
CPset_Phasing - Renovation Phase: Bestaand

# IfcSlab: Slab 702, 17_WSP_FD_beton - fundatiepaal v21-2:ø300 (schroef):1506822
In: -2 fundering
Classification: Vloerplaat - fundering (ARCHICAD Classification); Material: WSP_beton - ihwg beton
Pset_SlabCommon - Reference: ø300 (schroef); IsExternal: yes; LoadBearing: no
Pset_ReinforcementBarPitchOfSlab - Reference: ø300 (schroef)
CPset_Phasing - Renovation Phase: Bestaand
Component Quantities - WSP_beton - ihwg beton, Mass: 887.213 kg; WSP_beton - ihwg beton, Component Volume (Net): 0.385745 m3; WSP_beton - ihwg beton, Component Volume (Gross): 0.385745 m3

# IfcSlab: Slab 703, 17_WSP_FD_beton - fundatiepaal v21-2:ø300 (schroef):1506821
In: -2 fundering
Classification: Vloerplaat - fundering (ARCHICAD Classification); Material: WSP_beton - ihwg beton
Pset_ReinforcementBarPitchOfSlab - Reference: ø300 (schroef)
Pset_SlabCommon - Reference: ø300 (schroef); IsExternal: yes; LoadBearing: no
Component Quantities - WSP_beton - ihwg beton, Mass: 887.213 kg; WSP_beton - ihwg beton, Component Volume (Net): 0.385745 m3; WSP_beton - ihwg beton, Component Volume (Gross): 0.385745 m3
CPset_Phasing - Renovation Phase: Bestaand

# IfcSlab: Slab 704, 17_WSP_FD_beton - fundatiepaal v21-2:ø300 (schroef):1506820
In: -2 fundering
Classification: Vloerplaat - fundering (ARCHICAD Classification); Material: WSP_beton - ihwg beton
Pset_SlabCommon - Reference: ø300 (schroef); IsExternal: yes; LoadBearing: no
Component Quantities - WSP_beton - ihwg beton, Mass: 887.213 kg; WSP_beton - ihwg beton, Component Volume (Net): 0.385745 m3; WSP_beton - ihwg beton, Component Volume (Gross): 0.385745 m3
Pset_ReinforcementBarPitchOfSlab - Reference: ø300 (schroef)
CPset_Phasing - Renovation Phase: Bestaand

# IfcSlab: Slab 705, 17_WSP_FD_beton - fundatiepaal v21-2:ø300 (schroef):1506819
In: -2 fundering
Classification: Vloerplaat - fundering (ARCHICAD Classification); Material: WSP_beton - ihwg beton
Pset_SlabCommon - Reference: ø300 (schroef); IsExternal: yes; LoadBearing: no
Pset_ReinforcementBarPitchOfSlab - Reference: ø300 (schroef)
CPset_Phasing - Renovation Phase: Bestaand
Component Quantities - WSP_beton - ihwg beton, Mass: 887.213 kg; WSP_beton - ihwg beton, Component Volume (Net): 0.385745 m3; WSP_beton - ihwg beton, Component Volume (Gross): 0.385745 m3

# IfcSlab: Slab 706, 17_WSP_FD_beton - fundatiepaal v21-2:ø300 (schroef):1506818
In: -2 fundering
Classification: Vloerplaat - fundering (ARCHICAD Classification); Material: WSP_beton - ihwg beton
Pset_SlabCommon - Reference: ø300 (schroef); IsExternal: yes; LoadBearing: no
Pset_ReinforcementBarPitchOfSlab - Reference: ø300 (schroef)
CPset_Phasing - Renovation Phase: Bestaand
Component Quantities - WSP_beton - ihwg beton, Mass: 887.213 kg; WSP_beton - ihwg beton, Component Volume (Net): 0.385745 m3; WSP_beton - ihwg beton, Component Volume (Gross): 0.385745 m3

# IfcSlab: Slab 707, 17_WSP_FD_beton - fundatiepaal v21-2:ø300 (schroef):1506817
In: -2 fundering
Classification: Vloerplaat - fundering (ARCHICAD Classification); Material: WSP_beton - ihwg beton
Pset_SlabCommon - Reference: ø300 (schroef); IsExternal: yes; LoadBearing: no
Pset_ReinforcementBarPitchOfSlab - Reference: ø300 (schroef)
CPset_Phasing - Renovation Phase: Bestaand
Component Quantities - WSP_beton - ihwg beton, Mass: 887.213 kg; WSP_beton - ihwg beton, Component Volume (Net): 0.385745 m3; WSP_beton - ihwg beton, Component Volume (Gross): 0.385745 m3

# IfcSlab: Slab 708, 17_WSP_FD_beton - fundatiepaal v21-2:ø300 (schroef):1506816
In: -2 fundering
Classification: Vloerplaat - fundering (ARCHICAD Classification); Material: WSP_beton - ihwg beton
Pset_SlabCommon - Reference: ø300 (schroef); IsExternal: yes; LoadBearing: no
Pset_ReinforcementBarPitchOfSlab - Reference: ø300 (schroef)
CPset_Phasing - Renovation Phase: Bestaand
Component Quantities - WSP_beton - ihwg beton, Mass: 887.213 kg; WSP_beton - ihwg beton, Component Volume (Net): 0.385745 m3; WSP_beton - ihwg beton, Component Volume (Gross): 0.385745 m3

# IfcSlab: Slab 709, 17_WSP_FD_beton - fundatiepaal v21-2:ø300 (schroef):1506847
In: -2 fundering
Classification: Vloerplaat - fundering (ARCHICAD Classification); Material: WSP_beton - ihwg beton
Pset_ReinforcementBarPitchOfSlab - Reference: ø300 (schroef)
CPset_Phasing - Renovation Phase: Bestaand
Pset_SlabCommon - Reference: ø300 (schroef); IsExternal: yes; LoadBearing: no
Component Quantities - WSP_beton - ihwg beton, Mass: 903.056 kg; WSP_beton - ihwg beton, Component Volume (Net): 0.392633 m3; WSP_beton - ihwg beton, Component Volume (Gross): 0.392633 m3

# IfcSlab: Slab 71, 17_WSP_FD_beton - fundatiepaal v21-2:ø300 (schroef):1473579
In: -2 fundering
Classification: Vloerplaat - fundering (ARCHICAD Classification); Material: WSP_beton - ihwg beton
Component Quantities - WSP_beton - ihwg beton, Mass: 903.056 kg; WSP_beton - ihwg beton, Component Volume (Net): 0.392633 m3; WSP_beton - ihwg beton, Component Volume (Gross): 0.392633 m3
Pset_SlabCommon - Reference: ø300 (schroef); IsExternal: yes; LoadBearing: no
Pset_ReinforcementBarPitchOfSlab - Reference: ø300 (schroef)
CPset_Phasing - Renovation Phase: Bestaand

# IfcSlab: Slab 710, 17_WSP_FD_beton - fundatiepaal v21-2:ø300 (schroef):1506846
In: -2 fundering
Classification: Vloerplaat - fundering (ARCHICAD Classification); Material: WSP_beton - ihwg beton
Pset_ReinforcementBarPitchOfSlab - Reference: ø300 (schroef)
Pset_SlabCommon - Reference: ø300 (schroef); IsExternal: yes; LoadBearing: no
CPset_Phasing - Renovation Phase: Bestaand
Component Quantities - WSP_beton - ihwg beton, Mass: 903.056 kg; WSP_beton - ihwg beton, Component Volume (Net): 0.392633 m3; WSP_beton - ihwg beton, Component Volume (Gross): 0.392633 m3

# IfcSlab: Slab 711, 17_WSP_FD_beton - fundatiepaal v21-2:ø300 (schroef):1506845
In: -2 fundering
Classification: Vloerplaat - fundering (ARCHICAD Classification); Material: WSP_beton - ihwg beton
Pset_SlabCommon - Reference: ø300 (schroef); IsExternal: yes; LoadBearing: no
Component Quantities - WSP_beton - ihwg beton, Mass: 903.056 kg; WSP_beton - ihwg beton, Component Volume (Net): 0.392633 m3; WSP_beton - ihwg beton, Component Volume (Gross): 0.392633 m3
CPset_Phasing - Renovation Phase: Bestaand
Pset_ReinforcementBarPitchOfSlab - Reference: ø300 (schroef)

# IfcSlab: Slab 712, 17_WSP_FD_beton - fundatiepaal v21-2:ø300 (schroef):1506844
In: -2 fundering
Classification: Vloerplaat - fundering (ARCHICAD Classification); Material: WSP_beton - ihwg beton
Pset_SlabCommon - Reference: ø300 (schroef); IsExternal: yes; LoadBearing: no
Component Quantities - WSP_beton - ihwg beton, Mass: 903.056 kg; WSP_beton - ihwg beton, Component Volume (Net): 0.392633 m3; WSP_beton - ihwg beton, Component Volume (Gross): 0.392633 m3
CPset_Phasing - Renovation Phase: Bestaand
Pset_ReinforcementBarPitchOfSlab - Reference: ø300 (schroef)

# IfcSlab: Slab 713, 17_WSP_FD_beton - fundatiepaal v21-2:ø300 (schroef):1506843
In: -2 fundering
Classification: Vloerplaat - fundering (ARCHICAD Classification); Material: WSP_beton - ihwg beton
Pset_SlabCommon - Reference: ø300 (schroef); IsExternal: yes; LoadBearing: no
Pset_ReinforcementBarPitchOfSlab - Reference: ø300 (schroef)
Component Quantities - WSP_beton - ihwg beton, Mass: 903.056 kg; WSP_beton - ihwg beton, Component Volume (Net): 0.392633 m3; WSP_beton - ihwg beton, Component Volume (Gross): 0.392633 m3
CPset_Phasing - Renovation Phase: Bestaand

# IfcSlab: Slab 714, 17_WSP_FD_beton - fundatiepaal v21-2:ø300 (schroef):1506842
In: -2 fundering
Classification: Vloerplaat - fundering (ARCHICAD Classification); Material: WSP_beton - ihwg beton
Pset_ReinforcementBarPitchOfSlab - Reference: ø300 (schroef)
Component Quantities - WSP_beton - ihwg beton, Mass: 903.056 kg; WSP_beton - ihwg beton, Component Volume (Net): 0.392633 m3; WSP_beton - ihwg beton, Component Volume (Gross): 0.392633 m3
CPset_Phasing - Renovation Phase: Bestaand
Pset_SlabCommon - Reference: ø300 (schroef); IsExternal: yes; LoadBearing: no

# IfcSlab: Slab 715, 17_WSP_FD_beton - fundatiepaal v21-2:ø300 (schroef):1506833
In: -2 fundering
Classification: Vloerplaat - fundering (ARCHICAD Classification); Material: WSP_beton - ihwg beton
Component Quantities - WSP_beton - ihwg beton, Mass: 887.213 kg; WSP_beton - ihwg beton, Component Volume (Net): 0.385745 m3; WSP_beton - ihwg beton, Component Volume (Gross): 0.385745 m3
Pset_SlabCommon - Reference: ø300 (schroef); IsExternal: yes; LoadBearing: no
Pset_ReinforcementBarPitchOfSlab - Reference: ø300 (schroef)
CPset_Phasing - Renovation Phase: Bestaand

# IfcSlab: Slab 716, 17_WSP_FD_beton - fundatiepaal v21-2:ø300 (schroef):1506832
In: -2 fundering
Classification: Vloerplaat - fundering (ARCHICAD Classification); Material: WSP_beton - ihwg beton
CPset_Phasing - Renovation Phase: Bestaand
Component Quantities - WSP_beton - ihwg beton, Mass: 887.213 kg; WSP_beton - ihwg beton, Component Volume (Net): 0.385745 m3; WSP_beton - ihwg beton, Component Volume (Gross): 0.385745 m3
Pset_ReinforcementBarPitchOfSlab - Reference: ø300 (schroef)
Pset_SlabCommon - Reference: ø300 (schroef); IsExternal: yes; LoadBearing: no

# IfcSlab: Slab 717, 17_WSP_FD_beton - fundatiepaal v21-2:ø300 (schroef):1506895
In: -2 fundering
Classification: Vloerplaat - fundering (ARCHICAD Classification); Material: WSP_beton - ihwg beton
Pset_ReinforcementBarPitchOfSlab - Reference: ø300 (schroef)
Pset_SlabCommon - Reference: ø300 (schroef); IsExternal: yes; LoadBearing: no
CPset_Phasing - Renovation Phase: Bestaand
Component Quantities - WSP_beton - ihwg beton, Mass: 903.056 kg; WSP_beton - ihwg beton, Component Volume (Net): 0.392633 m3; WSP_beton - ihwg beton, Component Volume (Gross): 0.392633 m3

# IfcSlab: Slab 718, 17_WSP_FD_beton - fundatiepaal v21-2:ø300 (schroef):1506894
In: -2 fundering
Classification: Vloerplaat - fundering (ARCHICAD Classification); Material: WSP_beton - ihwg beton
Pset_ReinforcementBarPitchOfSlab - Reference: ø300 (schroef)
CPset_Phasing - Renovation Phase: Bestaand
Component Quantities - WSP_beton - ihwg beton, Mass: 903.056 kg; WSP_beton - ihwg beton, Component Volume (Net): 0.392633 m3; WSP_beton - ihwg beton, Component Volume (Gross): 0.392633 m3
Pset_SlabCommon - Reference: ø300 (schroef); IsExternal: yes; LoadBearing: no

# IfcSlab: Slab 719, 17_WSP_FD_beton - fundatiepaal v21-2:ø300 (schroef):1506893
In: -2 fundering
Classification: Vloerplaat - fundering (ARCHICAD Classification); Material: WSP_beton - ihwg beton
Pset_SlabCommon - Reference: ø300 (schroef); IsExternal: yes; LoadBearing: no
Pset_ReinforcementBarPitchOfSlab - Reference: ø300 (schroef)
CPset_Phasing - Renovation Phase: Bestaand
Component Quantities - WSP_beton - ihwg beton, Mass: 903.056 kg; WSP_beton - ihwg beton, Component Volume (Net): 0.392633 m3; WSP_beton - ihwg beton, Component Volume (Gross): 0.392633 m3

# IfcSlab: Slab 72, 17_WSP_FD_beton - fundatiepaal v21-2:ø300 (schroef):1473576
In: -2 fundering
Classification: Vloerplaat - fundering (ARCHICAD Classification); Material: WSP_beton - ihwg beton
Pset_ReinforcementBarPitchOfSlab - Reference: ø300 (schroef)
Pset_SlabCommon - Reference: ø300 (schroef); IsExternal: yes; LoadBearing: no
CPset_Phasing - Renovation Phase: Bestaand
Component Quantities - WSP_beton - ihwg beton, Mass: 903.056 kg; WSP_beton - ihwg beton, Component Volume (Net): 0.392633 m3; WSP_beton - ihwg beton, Component Volume (Gross): 0.392633 m3

# IfcSlab: Slab 720, 17_WSP_FD_beton - fundatiepaal v21-2:ø300 (schroef):1506892
In: -2 fundering
Classification: Vloerplaat - fundering (ARCHICAD Classification); Material: WSP_beton - ihwg beton
Pset_ReinforcementBarPitchOfSlab - Reference: ø300 (schroef)
Pset_SlabCommon - Reference: ø300 (schroef); IsExternal: yes; LoadBearing: no
CPset_Phasing - Renovation Phase: Bestaand
Component Quantities - WSP_beton - ihwg beton, Mass: 903.056 kg; WSP_beton - ihwg beton, Component Volume (Net): 0.392633 m3; WSP_beton - ihwg beton, Component Volume (Gross): 0.392633 m3

# IfcSlab: Slab 721, 17_WSP_FD_beton - fundatiepaal v21-2:ø300 (schroef):1506891
In: -2 fundering
Classification: Vloerplaat - fundering (ARCHICAD Classification); Material: WSP_beton - ihwg beton
Pset_SlabCommon - Reference: ø300 (schroef); IsExternal: yes; LoadBearing: no
Pset_ReinforcementBarPitchOfSlab - Reference: ø300 (schroef)
CPset_Phasing - Renovation Phase: Bestaand
Component Quantities - WSP_beton - ihwg beton, Mass: 903.056 kg; WSP_beton - ihwg beton, Component Volume (Net): 0.392633 m3; WSP_beton - ihwg beton, Component Volume (Gross): 0.392633 m3

# IfcSlab: Slab 722, 17_WSP_FD_beton - fundatiepaal v21-2:ø300 (schroef):1506890
In: -2 fundering
Classification: Vloerplaat - fundering (ARCHICAD Classification); Material: WSP_beton - ihwg beton
Pset_ReinforcementBarPitchOfSlab - Reference: ø300 (schroef)
Pset_SlabCommon - Reference: ø300 (schroef); IsExternal: yes; LoadBearing: no
CPset_Phasing - Renovation Phase: Bestaand
Component Quantities - WSP_beton - ihwg beton, Mass: 903.056 kg; WSP_beton - ihwg beton, Component Volume (Net): 0.392633 m3; WSP_beton - ihwg beton, Component Volume (Gross): 0.392633 m3

# IfcSlab: Slab 723, 17_WSP_FD_beton - fundatiepaal v21-2:ø300 (schroef):1506889
In: -2 fundering
Classification: Vloerplaat - fundering (ARCHICAD Classification); Material: WSP_beton - ihwg beton
Pset_SlabCommon - Reference: ø300 (schroef); IsExternal: yes; LoadBearing: no
CPset_Phasing - Renovation Phase: Bestaand
Component Quantities - WSP_beton - ihwg beton, Mass: 903.056 kg; WSP_beton - ihwg beton, Component Volume (Net): 0.392633 m3; WSP_beton - ihwg beton, Component Volume (Gross): 0.392633 m3
Pset_ReinforcementBarPitchOfSlab - Reference: ø300 (schroef)

# IfcSlab: Slab 724, 17_WSP_FD_beton - fundatiepaal v21-2:ø300 (schroef):1506888
In: -2 fundering
Classification: Vloerplaat - fundering (ARCHICAD Classification); Material: WSP_beton - ihwg beton
Pset_SlabCommon - Reference: ø300 (schroef); IsExternal: yes; LoadBearing: no
Pset_ReinforcementBarPitchOfSlab - Reference: ø300 (schroef)
CPset_Phasing - Renovation Phase: Bestaand
Component Quantities - WSP_beton - ihwg beton, Mass: 903.056 kg; WSP_beton - ihwg beton, Component Volume (Net): 0.392633 m3; WSP_beton - ihwg beton, Component Volume (Gross): 0.392633 m3

# IfcSlab: Slab 725, 17_WSP_FD_beton - fundatiepaal v21-2:ø300 (schroef):1506887
In: -2 fundering
Classification: Vloerplaat - fundering (ARCHICAD Classification); Material: WSP_beton - ihwg beton
Pset_ReinforcementBarPitchOfSlab - Reference: ø300 (schroef)
Pset_SlabCommon - Reference: ø300 (schroef); IsExternal: yes; LoadBearing: no
CPset_Phasing - Renovation Phase: Bestaand
Component Quantities - WSP_beton - ihwg beton, Mass: 903.056 kg; WSP_beton - ihwg beton, Component Volume (Net): 0.392633 m3; WSP_beton - ihwg beton, Component Volume (Gross): 0.392633 m3

# IfcSlab: Slab 726, 17_WSP_FD_beton - fundatiepaal v21-2:ø300 (schroef):1506886
In: -2 fundering
Classification: Vloerplaat - fundering (ARCHICAD Classification); Material: WSP_beton - ihwg beton
Pset_ReinforcementBarPitchOfSlab - Reference: ø300 (schroef)
Pset_SlabCommon - Reference: ø300 (schroef); IsExternal: yes; LoadBearing: no
CPset_Phasing - Renovation Phase: Bestaand
Component Quantities - WSP_beton - ihwg beton, Mass: 903.056 kg; WSP_beton - ihwg beton, Component Volume (Net): 0.392633 m3; WSP_beton - ihwg beton, Component Volume (Gross): 0.392633 m3

# IfcSlab: Slab 727, 17_WSP_FD_beton - fundatiepaal v21-2:ø300 (schroef):1506885
In: -2 fundering
Classification: Vloerplaat - fundering (ARCHICAD Classification); Material: WSP_beton - ihwg beton
Pset_SlabCommon - Reference: ø300 (schroef); IsExternal: yes; LoadBearing: no
Pset_ReinforcementBarPitchOfSlab - Reference: ø300 (schroef)
Component Quantities - WSP_beton - ihwg beton, Mass: 903.056 kg; WSP_beton - ihwg beton, Component Volume (Net): 0.392633 m3; WSP_beton - ihwg beton, Component Volume (Gross): 0.392633 m3
CPset_Phasing - Renovation Phase: Bestaand

# IfcSlab: Slab 728, 17_WSP_FD_beton - fundatiepaal v21-2:ø300 (schroef):1506884
In: -2 fundering
Classification: Vloerplaat - fundering (ARCHICAD Classification); Material: WSP_beton - ihwg beton
Pset_ReinforcementBarPitchOfSlab - Reference: ø300 (schroef)
Pset_SlabCommon - Reference: ø300 (schroef); IsExternal: yes; LoadBearing: no
CPset_Phasing - Renovation Phase: Bestaand
Component Quantities - WSP_beton - ihwg beton, Mass: 903.056 kg; WSP_beton - ihwg beton, Component Volume (Net): 0.392633 m3; WSP_beton - ihwg beton, Component Volume (Gross): 0.392633 m3

# IfcSlab: Slab 729, 17_WSP_FD_beton - fundatiepaal v21-2:ø300 (schroef):1506883
In: -2 fundering
Classification: Vloerplaat - fundering (ARCHICAD Classification); Material: WSP_beton - ihwg beton
Pset_SlabCommon - Reference: ø300 (schroef); IsExternal: yes; LoadBearing: no
Pset_ReinforcementBarPitchOfSlab - Reference: ø300 (schroef)
Component Quantities - WSP_beton - ihwg beton, Mass: 903.056 kg; WSP_beton - ihwg beton, Component Volume (Net): 0.392633 m3; WSP_beton - ihwg beton, Component Volume (Gross): 0.392633 m3
CPset_Phasing - Renovation Phase: Bestaand

# IfcSlab: Slab 73, 17_WSP_FD_beton - fundatiepaal v21-2:ø300 (schroef):1473577
In: -2 fundering
Classification: Vloerplaat - fundering (ARCHICAD Classification); Material: WSP_beton - ihwg beton
Pset_SlabCommon - Reference: ø300 (schroef); IsExternal: yes; LoadBearing: no
Pset_ReinforcementBarPitchOfSlab - Reference: ø300 (schroef)
CPset_Phasing - Renovation Phase: Bestaand
Component Quantities - WSP_beton - ihwg beton, Mass: 903.056 kg; WSP_beton - ihwg beton, Component Volume (Net): 0.392633 m3; WSP_beton - ihwg beton, Component Volume (Gross): 0.392633 m3

# IfcSlab: Slab 730, 17_WSP_FD_beton - fundatiepaal v21-2:ø300 (schroef):1506882
In: -2 fundering
Classification: Vloerplaat - fundering (ARCHICAD Classification); Material: WSP_beton - ihwg beton
Pset_SlabCommon - Reference: ø300 (schroef); IsExternal: yes; LoadBearing: no
Pset_ReinforcementBarPitchOfSlab - Reference: ø300 (schroef)
Component Quantities - WSP_beton - ihwg beton, Mass: 903.056 kg; WSP_beton - ihwg beton, Component Volume (Net): 0.392633 m3; WSP_beton - ihwg beton, Component Volume (Gross): 0.392633 m3
CPset_Phasing - Renovation Phase: Bestaand

# IfcSlab: Slab 731, 17_WSP_FD_beton - fundatiepaal v21-2:ø300 (schroef):1506881
In: -2 fundering
Classification: Vloerplaat - fundering (ARCHICAD Classification); Material: WSP_beton - ihwg beton
Pset_ReinforcementBarPitchOfSlab - Reference: ø300 (schroef)
Pset_SlabCommon - Reference: ø300 (schroef); IsExternal: yes; LoadBearing: no
CPset_Phasing - Renovation Phase: Bestaand
Component Quantities - WSP_beton - ihwg beton, Mass: 903.056 kg; WSP_beton - ihwg beton, Component Volume (Net): 0.392633 m3; WSP_beton - ihwg beton, Component Volume (Gross): 0.392633 m3

# IfcSlab: Slab 732, 17_WSP_FD_beton - fundatiepaal v21-2:ø300 (schroef):1506880
In: -2 fundering
Classification: Vloerplaat - fundering (ARCHICAD Classification); Material: WSP_beton - ihwg beton
Pset_ReinforcementBarPitchOfSlab - Reference: ø300 (schroef)
Pset_SlabCommon - Reference: ø300 (schroef); IsExternal: yes; LoadBearing: no
Component Quantities - WSP_beton - ihwg beton, Mass: 903.056 kg; WSP_beton - ihwg beton, Component Volume (Net): 0.392633 m3; WSP_beton - ihwg beton, Component Volume (Gross): 0.392633 m3
CPset_Phasing - Renovation Phase: Bestaand

# IfcSlab: Slab 733, 17_WSP_FD_beton - fundatiepaal v21-2:ø300 (schroef):1506897
In: -2 fundering
Classification: Vloerplaat - fundering (ARCHICAD Classification); Material: WSP_beton - ihwg beton
Pset_ReinforcementBarPitchOfSlab - Reference: ø300 (schroef)
Component Quantities - WSP_beton - ihwg beton, Mass: 903.056 kg; WSP_beton - ihwg beton, Component Volume (Net): 0.392633 m3; WSP_beton - ihwg beton, Component Volume (Gross): 0.392633 m3
CPset_Phasing - Renovation Phase: Bestaand
Pset_SlabCommon - Reference: ø300 (schroef); IsExternal: yes; LoadBearing: no

# IfcSlab: Slab 734, 17_WSP_FD_beton - fundatiepaal v21-2:ø300 (schroef):1506896
In: -2 fundering
Classification: Vloerplaat - fundering (ARCHICAD Classification); Material: WSP_beton - ihwg beton
Pset_SlabCommon - Reference: ø300 (schroef); IsExternal: yes; LoadBearing: no
CPset_Phasing - Renovation Phase: Bestaand
Component Quantities - WSP_beton - ihwg beton, Mass: 903.056 kg; WSP_beton - ihwg beton, Component Volume (Net): 0.392633 m3; WSP_beton - ihwg beton, Component Volume (Gross): 0.392633 m3
Pset_ReinforcementBarPitchOfSlab - Reference: ø300 (schroef)

# IfcSlab: Slab 735, 17_WSP_FD_beton - fundatiepaal v21-2:ø300 (schroef):1507055
In: -2 fundering
Classification: Vloerplaat - fundering (ARCHICAD Classification); Material: WSP_beton - ihwg beton
Pset_SlabCommon - Reference: ø300 (schroef); IsExternal: yes; LoadBearing: no
Component Quantities - WSP_beton - ihwg beton, Mass: 887.213 kg; WSP_beton - ihwg beton, Component Volume (Net): 0.385745 m3; WSP_beton - ihwg beton, Component Volume (Gross): 0.385745 m3
CPset_Phasing - Renovation Phase: Bestaand
Pset_ReinforcementBarPitchOfSlab - Reference: ø300 (schroef)

# IfcSlab: Slab 736, 17_WSP_FD_beton - fundatiepaal v21-2:ø300 (schroef):1507054
In: -2 fundering
Classification: Vloerplaat - fundering (ARCHICAD Classification); Material: WSP_beton - ihwg beton
Component Quantities - WSP_beton - ihwg beton, Mass: 887.213 kg; WSP_beton - ihwg beton, Component Volume (Net): 0.385745 m3; WSP_beton - ihwg beton, Component Volume (Gross): 0.385745 m3
CPset_Phasing - Renovation Phase: Bestaand
Pset_SlabCommon - Reference: ø300 (schroef); IsExternal: yes; LoadBearing: no
Pset_ReinforcementBarPitchOfSlab - Reference: ø300 (schroef)

# IfcSlab: Slab 737, 17_WSP_FD_beton - fundatiepaal v21-2:ø300 (schroef):1507053
In: -2 fundering
Classification: Vloerplaat - fundering (ARCHICAD Classification); Material: WSP_beton - ihwg beton
Pset_ReinforcementBarPitchOfSlab - Reference: ø300 (schroef)
Pset_SlabCommon - Reference: ø300 (schroef); IsExternal: yes; LoadBearing: no
CPset_Phasing - Renovation Phase: Bestaand
Component Quantities - WSP_beton - ihwg beton, Mass: 887.213 kg; WSP_beton - ihwg beton, Component Volume (Net): 0.385745 m3; WSP_beton - ihwg beton, Component Volume (Gross): 0.385745 m3

# IfcSlab: Slab 738, 17_WSP_FD_beton - fundatiepaal v21-2:ø300 (schroef):1507052
In: -2 fundering
Classification: Vloerplaat - fundering (ARCHICAD Classification); Material: WSP_beton - ihwg beton
Component Quantities - WSP_beton - ihwg beton, Mass: 887.213 kg; WSP_beton - ihwg beton, Component Volume (Net): 0.385745 m3; WSP_beton - ihwg beton, Component Volume (Gross): 0.385745 m3
CPset_Phasing - Renovation Phase: Bestaand
Pset_ReinforcementBarPitchOfSlab - Reference: ø300 (schroef)
Pset_SlabCommon - Reference: ø300 (schroef); IsExternal: yes; LoadBearing: no

# IfcSlab: Slab 739, 17_WSP_FD_beton - fundatiepaal v21-2:ø300 (schroef):1507051
In: -2 fundering
Classification: Vloerplaat - fundering (ARCHICAD Classification); Material: WSP_beton - ihwg beton
Pset_SlabCommon - Reference: ø300 (schroef); IsExternal: yes; LoadBearing: no
CPset_Phasing - Renovation Phase: Bestaand
Component Quantities - WSP_beton - ihwg beton, Mass: 887.213 kg; WSP_beton - ihwg beton, Component Volume (Net): 0.385745 m3; WSP_beton - ihwg beton, Component Volume (Gross): 0.385745 m3
Pset_ReinforcementBarPitchOfSlab - Reference: ø300 (schroef)

# IfcSlab: Slab 74, 17_WSP_FD_beton - fundatiepaal v21-2:ø300 (schroef):1473582
In: -2 fundering
Classification: Vloerplaat - fundering (ARCHICAD Classification); Material: WSP_beton - ihwg beton
Pset_ReinforcementBarPitchOfSlab - Reference: ø300 (schroef)
Pset_SlabCommon - Reference: ø300 (schroef); IsExternal: yes; LoadBearing: no
CPset_Phasing - Renovation Phase: Bestaand
Component Quantities - WSP_beton - ihwg beton, Mass: 903.056 kg; WSP_beton - ihwg beton, Component Volume (Net): 0.392633 m3; WSP_beton - ihwg beton, Component Volume (Gross): 0.392633 m3

# IfcSlab: Slab 740, 17_WSP_FD_beton - fundatiepaal v21-2:ø300 (schroef):1507050
In: -2 fundering
Classification: Vloerplaat - fundering (ARCHICAD Classification); Material: WSP_beton - ihwg beton
Pset_SlabCommon - Reference: ø300 (schroef); IsExternal: yes; LoadBearing: no
Pset_ReinforcementBarPitchOfSlab - Reference: ø300 (schroef)
Component Quantities - WSP_beton - ihwg beton, Mass: 887.213 kg; WSP_beton - ihwg beton, Component Volume (Net): 0.385745 m3; WSP_beton - ihwg beton, Component Volume (Gross): 0.385745 m3
CPset_Phasing - Renovation Phase: Bestaand

# IfcSlab: Slab 741, 17_WSP_FD_beton - fundatiepaal v21-2:ø300 (schroef):1507049
In: -2 fundering
Classification: Vloerplaat - fundering (ARCHICAD Classification); Material: WSP_beton - ihwg beton
Pset_SlabCommon - Reference: ø300 (schroef); IsExternal: yes; LoadBearing: no
Pset_ReinforcementBarPitchOfSlab - Reference: ø300 (schroef)
Component Quantities - WSP_beton - ihwg beton, Mass: 887.213 kg; WSP_beton - ihwg beton, Component Volume (Net): 0.385745 m3; WSP_beton - ihwg beton, Component Volume (Gross): 0.385745 m3
CPset_Phasing - Renovation Phase: Bestaand

# IfcSlab: Slab 742, 17_WSP_FD_beton - fundatiepaal v21-2:ø300 (schroef):1507048
In: -2 fundering
Classification: Vloerplaat - fundering (ARCHICAD Classification); Material: WSP_beton - ihwg beton
Pset_SlabCommon - Reference: ø300 (schroef); IsExternal: yes; LoadBearing: no
Pset_ReinforcementBarPitchOfSlab - Reference: ø300 (schroef)
CPset_Phasing - Renovation Phase: Bestaand
Component Quantities - WSP_beton - ihwg beton, Mass: 887.213 kg; WSP_beton - ihwg beton, Component Volume (Net): 0.385745 m3; WSP_beton - ihwg beton, Component Volume (Gross): 0.385745 m3

# IfcSlab: Slab 743, 17_WSP_FD_beton - fundatiepaal v21-2:ø300 (schroef):1507047
In: -2 fundering
Classification: Vloerplaat - fundering (ARCHICAD Classification); Material: WSP_beton - ihwg beton
Pset_ReinforcementBarPitchOfSlab - Reference: ø300 (schroef)
Pset_SlabCommon - Reference: ø300 (schroef); IsExternal: yes; LoadBearing: no
CPset_Phasing - Renovation Phase: Bestaand
Component Quantities - WSP_beton - ihwg beton, Mass: 887.213 kg; WSP_beton - ihwg beton, Component Volume (Net): 0.385745 m3; WSP_beton - ihwg beton, Component Volume (Gross): 0.385745 m3

# IfcSlab: Slab 744, 17_WSP_FD_beton - fundatiepaal v21-2:ø300 (schroef):1507046
In: -2 fundering
Classification: Vloerplaat - fundering (ARCHICAD Classification); Material: WSP_beton - ihwg beton
Pset_SlabCommon - Reference: ø300 (schroef); IsExternal: yes; LoadBearing: no
Pset_ReinforcementBarPitchOfSlab - Reference: ø300 (schroef)
CPset_Phasing - Renovation Phase: Bestaand
Component Quantities - WSP_beton - ihwg beton, Mass: 887.213 kg; WSP_beton - ihwg beton, Component Volume (Net): 0.385745 m3; WSP_beton - ihwg beton, Component Volume (Gross): 0.385745 m3

# IfcSlab: Slab 745, 17_WSP_FD_beton - fundatiepaal v21-2:ø300 (schroef):1507045
In: -2 fundering
Classification: Vloerplaat - fundering (ARCHICAD Classification); Material: WSP_beton - ihwg beton
Pset_SlabCommon - Reference: ø300 (schroef); IsExternal: yes; LoadBearing: no
Pset_ReinforcementBarPitchOfSlab - Reference: ø300 (schroef)
Component Quantities - WSP_beton - ihwg beton, Mass: 887.213 kg; WSP_beton - ihwg beton, Component Volume (Net): 0.385745 m3; WSP_beton - ihwg beton, Component Volume (Gross): 0.385745 m3
CPset_Phasing - Renovation Phase: Bestaand

# IfcSlab: Slab 746, 17_WSP_FD_beton - fundatiepaal v21-2:ø300 (schroef):1507044
In: -2 fundering
Classification: Vloerplaat - fundering (ARCHICAD Classification); Material: WSP_beton - ihwg beton
Pset_SlabCommon - Reference: ø300 (schroef); IsExternal: yes; LoadBearing: no
Component Quantities - WSP_beton - ihwg beton, Mass: 887.213 kg; WSP_beton - ihwg beton, Component Volume (Net): 0.385745 m3; WSP_beton - ihwg beton, Component Volume (Gross): 0.385745 m3
Pset_ReinforcementBarPitchOfSlab - Reference: ø300 (schroef)
CPset_Phasing - Renovation Phase: Bestaand

# IfcSlab: Slab 747, 17_WSP_FD_beton - fundatiepaal v21-2:ø300 (schroef):1507043
In: -2 fundering
Classification: Vloerplaat - fundering (ARCHICAD Classification); Material: WSP_beton - ihwg beton
Pset_SlabCommon - Reference: ø300 (schroef); IsExternal: yes; LoadBearing: no
CPset_Phasing - Renovation Phase: Bestaand
Component Quantities - WSP_beton - ihwg beton, Mass: 887.213 kg; WSP_beton - ihwg beton, Component Volume (Net): 0.385745 m3; WSP_beton - ihwg beton, Component Volume (Gross): 0.385745 m3
Pset_ReinforcementBarPitchOfSlab - Reference: ø300 (schroef)

# IfcSlab: Slab 748, 17_WSP_FD_beton - fundatiepaal v21-2:ø300 (schroef):1507042
In: -2 fundering
Classification: Vloerplaat - fundering (ARCHICAD Classification); Material: WSP_beton - ihwg beton
Pset_SlabCommon - Reference: ø300 (schroef); IsExternal: yes; LoadBearing: no
Pset_ReinforcementBarPitchOfSlab - Reference: ø300 (schroef)
Component Quantities - WSP_beton - ihwg beton, Mass: 887.213 kg; WSP_beton - ihwg beton, Component Volume (Net): 0.385745 m3; WSP_beton - ihwg beton, Component Volume (Gross): 0.385745 m3
CPset_Phasing - Renovation Phase: Bestaand

# IfcSlab: Slab 749, 17_WSP_FD_beton - fundatiepaal v21-2:ø300 (schroef):1507041
In: -2 fundering
Classification: Vloerplaat - fundering (ARCHICAD Classification); Material: WSP_beton - ihwg beton
Pset_SlabCommon - Reference: ø300 (schroef); IsExternal: yes; LoadBearing: no
CPset_Phasing - Renovation Phase: Bestaand
Component Quantities - WSP_beton - ihwg beton, Mass: 887.213 kg; WSP_beton - ihwg beton, Component Volume (Net): 0.385745 m3; WSP_beton - ihwg beton, Component Volume (Gross): 0.385745 m3
Pset_ReinforcementBarPitchOfSlab - Reference: ø300 (schroef)

# IfcSlab: Slab 75, 17_WSP_FD_beton - fundatiepaal v21-2:ø300 (schroef):1473583
In: -2 fundering
Classification: Vloerplaat - fundering (ARCHICAD Classification); Material: WSP_beton - ihwg beton
Pset_SlabCommon - Reference: ø300 (schroef); IsExternal: yes; LoadBearing: no
CPset_Phasing - Renovation Phase: Bestaand
Component Quantities - WSP_beton - ihwg beton, Mass: 903.056 kg; WSP_beton - ihwg beton, Component Volume (Net): 0.392633 m3; WSP_beton - ihwg beton, Component Volume (Gross): 0.392633 m3
Pset_ReinforcementBarPitchOfSlab - Reference: ø300 (schroef)

# IfcSlab: Slab 750, 17_WSP_FD_beton - fundatiepaal v21-2:ø300 (schroef):1507040
In: -2 fundering
Classification: Vloerplaat - fundering (ARCHICAD Classification); Material: WSP_beton - ihwg beton
Pset_SlabCommon - Reference: ø300 (schroef); IsExternal: yes; LoadBearing: no
Pset_ReinforcementBarPitchOfSlab - Reference: ø300 (schroef)
Component Quantities - WSP_beton - ihwg beton, Mass: 887.213 kg; WSP_beton - ihwg beton, Component Volume (Net): 0.385745 m3; WSP_beton - ihwg beton, Component Volume (Gross): 0.385745 m3
CPset_Phasing - Renovation Phase: Bestaand

# IfcSlab: Slab 751, 17_WSP_FD_beton - fundatiepaal v21-2:ø300 (schroef):1507071
In: -2 fundering
Classification: Vloerplaat - fundering (ARCHICAD Classification); Material: WSP_beton - ihwg beton
Pset_ReinforcementBarPitchOfSlab - Reference: ø300 (schroef)
Pset_SlabCommon - Reference: ø300 (schroef); IsExternal: yes; LoadBearing: no
CPset_Phasing - Renovation Phase: Bestaand
Component Quantities - WSP_beton - ihwg beton, Mass: 887.213 kg; WSP_beton - ihwg beton, Component Volume (Net): 0.385745 m3; WSP_beton - ihwg beton, Component Volume (Gross): 0.385745 m3

# IfcSlab: Slab 752, 17_WSP_FD_beton - fundatiepaal v21-2:ø300 (schroef):1507070
In: -2 fundering
Classification: Vloerplaat - fundering (ARCHICAD Classification); Material: WSP_beton - ihwg beton
Pset_ReinforcementBarPitchOfSlab - Reference: ø300 (schroef)
Pset_SlabCommon - Reference: ø300 (schroef); IsExternal: yes; LoadBearing: no
Component Quantities - WSP_beton - ihwg beton, Mass: 887.213 kg; WSP_beton - ihwg beton, Component Volume (Net): 0.385745 m3; WSP_beton - ihwg beton, Component Volume (Gross): 0.385745 m3
CPset_Phasing - Renovation Phase: Bestaand

# IfcSlab: Slab 753, 17_WSP_FD_beton - fundatiepaal v21-2:ø300 (schroef):1507069
In: -2 fundering
Classification: Vloerplaat - fundering (ARCHICAD Classification); Material: WSP_beton - ihwg beton
Pset_SlabCommon - Reference: ø300 (schroef); IsExternal: yes; LoadBearing: no
Pset_ReinforcementBarPitchOfSlab - Reference: ø300 (schroef)
Component Quantities - WSP_beton - ihwg beton, Mass: 887.213 kg; WSP_beton - ihwg beton, Component Volume (Net): 0.385745 m3; WSP_beton - ihwg beton, Component Volume (Gross): 0.385745 m3
CPset_Phasing - Renovation Phase: Bestaand

# IfcSlab: Slab 754, 17_WSP_FD_beton - fundatiepaal v21-2:ø300 (schroef):1507068
In: -2 fundering
Classification: Vloerplaat - fundering (ARCHICAD Classification); Material: WSP_beton - ihwg beton
Pset_SlabCommon - Reference: ø300 (schroef); IsExternal: yes; LoadBearing: no
Pset_ReinforcementBarPitchOfSlab - Reference: ø300 (schroef)
Component Quantities - WSP_beton - ihwg beton, Mass: 887.213 kg; WSP_beton - ihwg beton, Component Volume (Net): 0.385745 m3; WSP_beton - ihwg beton, Component Volume (Gross): 0.385745 m3
CPset_Phasing - Renovation Phase: Bestaand

# IfcSlab: Slab 755, 17_WSP_FD_beton - fundatiepaal v21-2:ø300 (schroef):1507067
In: -2 fundering
Classification: Vloerplaat - fundering (ARCHICAD Classification); Material: WSP_beton - ihwg beton
Pset_SlabCommon - Reference: ø300 (schroef); IsExternal: yes; LoadBearing: no
Pset_ReinforcementBarPitchOfSlab - Reference: ø300 (schroef)
CPset_Phasing - Renovation Phase: Bestaand
Component Quantities - WSP_beton - ihwg beton, Mass: 887.213 kg; WSP_beton - ihwg beton, Component Volume (Net): 0.385745 m3; WSP_beton - ihwg beton, Component Volume (Gross): 0.385745 m3

# IfcSlab: Slab 756, 17_WSP_FD_beton - fundatiepaal v21-2:ø300 (schroef):1507066
In: -2 fundering
Classification: Vloerplaat - fundering (ARCHICAD Classification); Material: WSP_beton - ihwg beton
Pset_SlabCommon - Reference: ø300 (schroef); IsExternal: yes; LoadBearing: no
Component Quantities - WSP_beton - ihwg beton, Mass: 887.213 kg; WSP_beton - ihwg beton, Component Volume (Net): 0.385745 m3; WSP_beton - ihwg beton, Component Volume (Gross): 0.385745 m3
CPset_Phasing - Renovation Phase: Bestaand
Pset_ReinforcementBarPitchOfSlab - Reference: ø300 (schroef)

# IfcSlab: Slab 757, 17_WSP_FD_beton - fundatiepaal v21-2:ø300 (schroef):1507065
In: -2 fundering
Classification: Vloerplaat - fundering (ARCHICAD Classification); Material: WSP_beton - ihwg beton
Pset_SlabCommon - Reference: ø300 (schroef); IsExternal: yes; LoadBearing: no
Component Quantities - WSP_beton - ihwg beton, Mass: 887.213 kg; WSP_beton - ihwg beton, Component Volume (Net): 0.385745 m3; WSP_beton - ihwg beton, Component Volume (Gross): 0.385745 m3
CPset_Phasing - Renovation Phase: Bestaand
Pset_ReinforcementBarPitchOfSlab - Reference: ø300 (schroef)

# IfcSlab: Slab 758, 17_WSP_FD_beton - fundatiepaal v21-2:ø300 (schroef):1507064
In: -2 fundering
Classification: Vloerplaat - fundering (ARCHICAD Classification); Material: WSP_beton - ihwg beton
Component Quantities - WSP_beton - ihwg beton, Mass: 887.213 kg; WSP_beton - ihwg beton, Component Volume (Net): 0.385745 m3; WSP_beton - ihwg beton, Component Volume (Gross): 0.385745 m3
Pset_SlabCommon - Reference: ø300 (schroef); IsExternal: yes; LoadBearing: no
CPset_Phasing - Renovation Phase: Bestaand
Pset_ReinforcementBarPitchOfSlab - Reference: ø300 (schroef)

# IfcSlab: Slab 759, 17_WSP_FD_beton - fundatiepaal v21-2:ø300 (schroef):1507063
In: -2 fundering
Classification: Vloerplaat - fundering (ARCHICAD Classification); Material: WSP_beton - ihwg beton
Pset_SlabCommon - Reference: ø300 (schroef); IsExternal: yes; LoadBearing: no
CPset_Phasing - Renovation Phase: Bestaand
Component Quantities - WSP_beton - ihwg beton, Mass: 887.213 kg; WSP_beton - ihwg beton, Component Volume (Net): 0.385745 m3; WSP_beton - ihwg beton, Component Volume (Gross): 0.385745 m3
Pset_ReinforcementBarPitchOfSlab - Reference: ø300 (schroef)

# IfcSlab: Slab 76, 17_WSP_FD_beton - fundatiepaal v21-2:ø300 (schroef):1473580
In: -2 fundering
Classification: Vloerplaat - fundering (ARCHICAD Classification); Material: WSP_beton - ihwg beton
Pset_SlabCommon - Reference: ø300 (schroef); IsExternal: yes; LoadBearing: no
Pset_ReinforcementBarPitchOfSlab - Reference: ø300 (schroef)
CPset_Phasing - Renovation Phase: Bestaand
Component Quantities - WSP_beton - ihwg beton, Mass: 903.056 kg; WSP_beton - ihwg beton, Component Volume (Net): 0.392633 m3; WSP_beton - ihwg beton, Component Volume (Gross): 0.392633 m3

# IfcSlab: Slab 760, 17_WSP_FD_beton - fundatiepaal v21-2:ø300 (schroef):1507062
In: -2 fundering
Classification: Vloerplaat - fundering (ARCHICAD Classification); Material: WSP_beton - ihwg beton
Pset_SlabCommon - Reference: ø300 (schroef); IsExternal: yes; LoadBearing: no
Component Quantities - WSP_beton - ihwg beton, Mass: 887.213 kg; WSP_beton - ihwg beton, Component Volume (Net): 0.385745 m3; WSP_beton - ihwg beton, Component Volume (Gross): 0.385745 m3
Pset_ReinforcementBarPitchOfSlab - Reference: ø300 (schroef)
CPset_Phasing - Renovation Phase: Bestaand

# IfcSlab: Slab 761, 17_WSP_FD_beton - fundatiepaal v21-2:ø300 (schroef):1507061
In: -2 fundering
Classification: Vloerplaat - fundering (ARCHICAD Classification); Material: WSP_beton - ihwg beton
Pset_ReinforcementBarPitchOfSlab - Reference: ø300 (schroef)
Pset_SlabCommon - Reference: ø300 (schroef); IsExternal: yes; LoadBearing: no
CPset_Phasing - Renovation Phase: Bestaand
Component Quantities - WSP_beton - ihwg beton, Mass: 887.213 kg; WSP_beton - ihwg beton, Component Volume (Net): 0.385745 m3; WSP_beton - ihwg beton, Component Volume (Gross): 0.385745 m3

# IfcSlab: Slab 762, 17_WSP_FD_beton - fundatiepaal v21-2:ø300 (schroef):1507060
In: -2 fundering
Classification: Vloerplaat - fundering (ARCHICAD Classification); Material: WSP_beton - ihwg beton
Pset_ReinforcementBarPitchOfSlab - Reference: ø300 (schroef)
Pset_SlabCommon - Reference: ø300 (schroef); IsExternal: yes; LoadBearing: no
CPset_Phasing - Renovation Phase: Bestaand
Component Quantities - WSP_beton - ihwg beton, Mass: 887.213 kg; WSP_beton - ihwg beton, Component Volume (Net): 0.385745 m3; WSP_beton - ihwg beton, Component Volume (Gross): 0.385745 m3

# IfcSlab: Slab 763, 17_WSP_FD_beton - fundatiepaal v21-2:ø300 (schroef):1507059
In: -2 fundering
Classification: Vloerplaat - fundering (ARCHICAD Classification); Material: WSP_beton - ihwg beton
Pset_SlabCommon - Reference: ø300 (schroef); IsExternal: yes; LoadBearing: no
Pset_ReinforcementBarPitchOfSlab - Reference: ø300 (schroef)
Component Quantities - WSP_beton - ihwg beton, Mass: 887.213 kg; WSP_beton - ihwg beton, Component Volume (Net): 0.385745 m3; WSP_beton - ihwg beton, Component Volume (Gross): 0.385745 m3
CPset_Phasing - Renovation Phase: Bestaand

# IfcSlab: Slab 764, 17_WSP_FD_beton - fundatiepaal v21-2:ø300 (schroef):1507058
In: -2 fundering
Classification: Vloerplaat - fundering (ARCHICAD Classification); Material: WSP_beton - ihwg beton
CPset_Phasing - Renovation Phase: Bestaand
Pset_SlabCommon - Reference: ø300 (schroef); IsExternal: yes; LoadBearing: no
Component Quantities - WSP_beton - ihwg beton, Mass: 887.213 kg; WSP_beton - ihwg beton, Component Volume (Net): 0.385745 m3; WSP_beton - ihwg beton, Component Volume (Gross): 0.385745 m3
Pset_ReinforcementBarPitchOfSlab - Reference: ø300 (schroef)

# IfcSlab: Slab 765, 17_WSP_FD_beton - fundatiepaal v21-2:ø300 (schroef):1507057
In: -2 fundering
Classification: Vloerplaat - fundering (ARCHICAD Classification); Material: WSP_beton - ihwg beton
Pset_SlabCommon - Reference: ø300 (schroef); IsExternal: yes; LoadBearing: no
Pset_ReinforcementBarPitchOfSlab - Reference: ø300 (schroef)
CPset_Phasing - Renovation Phase: Bestaand
Component Quantities - WSP_beton - ihwg beton, Mass: 887.213 kg; WSP_beton - ihwg beton, Component Volume (Net): 0.385745 m3; WSP_beton - ihwg beton, Component Volume (Gross): 0.385745 m3

# IfcSlab: Slab 766, 17_WSP_FD_beton - fundatiepaal v21-2:ø300 (schroef):1507056
In: -2 fundering
Classification: Vloerplaat - fundering (ARCHICAD Classification); Material: WSP_beton - ihwg beton
Pset_SlabCommon - Reference: ø300 (schroef); IsExternal: yes; LoadBearing: no
Pset_ReinforcementBarPitchOfSlab - Reference: ø300 (schroef)
Component Quantities - WSP_beton - ihwg beton, Mass: 887.213 kg; WSP_beton - ihwg beton, Component Volume (Net): 0.385745 m3; WSP_beton - ihwg beton, Component Volume (Gross): 0.385745 m3
CPset_Phasing - Renovation Phase: Bestaand

# IfcSlab: Slab 767, 17_WSP_FD_beton - fundatiepaal v21-2:ø300 (schroef):1507023
In: -2 fundering
Classification: Vloerplaat - fundering (ARCHICAD Classification); Material: WSP_beton - ihwg beton
Pset_SlabCommon - Reference: ø300 (schroef); IsExternal: yes; LoadBearing: no
Pset_ReinforcementBarPitchOfSlab - Reference: ø300 (schroef)
Component Quantities - WSP_beton - ihwg beton, Mass: 887.213 kg; WSP_beton - ihwg beton, Component Volume (Net): 0.385745 m3; WSP_beton - ihwg beton, Component Volume (Gross): 0.385745 m3
CPset_Phasing - Renovation Phase: Bestaand

# IfcSlab: Slab 768, 17_WSP_FD_beton - fundatiepaal v21-2:ø300 (schroef):1507022
In: -2 fundering
Classification: Vloerplaat - fundering (ARCHICAD Classification); Material: WSP_beton - ihwg beton
Pset_SlabCommon - Reference: ø300 (schroef); IsExternal: yes; LoadBearing: no
CPset_Phasing - Renovation Phase: Bestaand
Component Quantities - WSP_beton - ihwg beton, Mass: 887.213 kg; WSP_beton - ihwg beton, Component Volume (Net): 0.385745 m3; WSP_beton - ihwg beton, Component Volume (Gross): 0.385745 m3
Pset_ReinforcementBarPitchOfSlab - Reference: ø300 (schroef)

# IfcSlab: Slab 769, 17_WSP_FD_beton - fundatiepaal v21-2:ø300 (schroef):1507013
In: -2 fundering
Classification: Vloerplaat - fundering (ARCHICAD Classification); Material: WSP_beton - ihwg beton
CPset_Phasing - Renovation Phase: Bestaand
Pset_ReinforcementBarPitchOfSlab - Reference: ø300 (schroef)
Pset_SlabCommon - Reference: ø300 (schroef); IsExternal: yes; LoadBearing: no
Component Quantities - WSP_beton - ihwg beton, Mass: 887.213 kg; WSP_beton - ihwg beton, Component Volume (Net): 0.385745 m3; WSP_beton - ihwg beton, Component Volume (Gross): 0.385745 m3

# IfcSlab: Slab 77, 17_WSP_FD_beton - fundatiepaal v21-2:ø300 (schroef):1473581
In: -2 fundering
Classification: Vloerplaat - fundering (ARCHICAD Classification); Material: WSP_beton - ihwg beton
Pset_ReinforcementBarPitchOfSlab - Reference: ø300 (schroef)
CPset_Phasing - Renovation Phase: Bestaand
Pset_SlabCommon - Reference: ø300 (schroef); IsExternal: yes; LoadBearing: no
Component Quantities - WSP_beton - ihwg beton, Mass: 903.056 kg; WSP_beton - ihwg beton, Component Volume (Net): 0.392633 m3; WSP_beton - ihwg beton, Component Volume (Gross): 0.392633 m3

# IfcSlab: Slab 770, 17_WSP_FD_beton - fundatiepaal v21-2:ø300 (schroef):1507012
In: -2 fundering
Classification: Vloerplaat - fundering (ARCHICAD Classification); Material: WSP_beton - ihwg beton
Pset_ReinforcementBarPitchOfSlab - Reference: ø300 (schroef)
Pset_SlabCommon - Reference: ø300 (schroef); IsExternal: yes; LoadBearing: no
CPset_Phasing - Renovation Phase: Bestaand
Component Quantities - WSP_beton - ihwg beton, Mass: 887.213 kg; WSP_beton - ihwg beton, Component Volume (Net): 0.385745 m3; WSP_beton - ihwg beton, Component Volume (Gross): 0.385745 m3

# IfcSlab: Slab 771, 17_WSP_FD_beton - fundatiepaal v21-2:ø300 (schroef):1507011
In: -2 fundering
Classification: Vloerplaat - fundering (ARCHICAD Classification); Material: WSP_beton - ihwg beton
Pset_SlabCommon - Reference: ø300 (schroef); IsExternal: yes; LoadBearing: no
CPset_Phasing - Renovation Phase: Bestaand
Pset_ReinforcementBarPitchOfSlab - Reference: ø300 (schroef)
Component Quantities - WSP_beton - ihwg beton, Mass: 887.213 kg; WSP_beton - ihwg beton, Component Volume (Net): 0.385745 m3; WSP_beton - ihwg beton, Component Volume (Gross): 0.385745 m3

# IfcSlab: Slab 772, 17_WSP_FD_beton - fundatiepaal v21-2:ø300 (schroef):1507010
In: -2 fundering
Classification: Vloerplaat - fundering (ARCHICAD Classification); Material: WSP_beton - ihwg beton
Pset_SlabCommon - Reference: ø300 (schroef); IsExternal: yes; LoadBearing: no
Pset_ReinforcementBarPitchOfSlab - Reference: ø300 (schroef)
CPset_Phasing - Renovation Phase: Bestaand
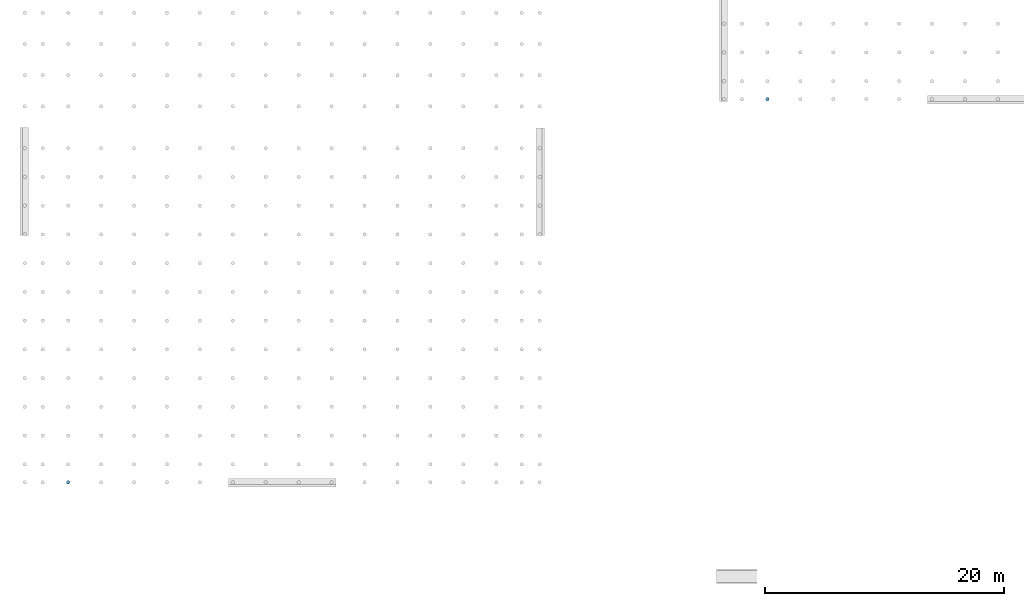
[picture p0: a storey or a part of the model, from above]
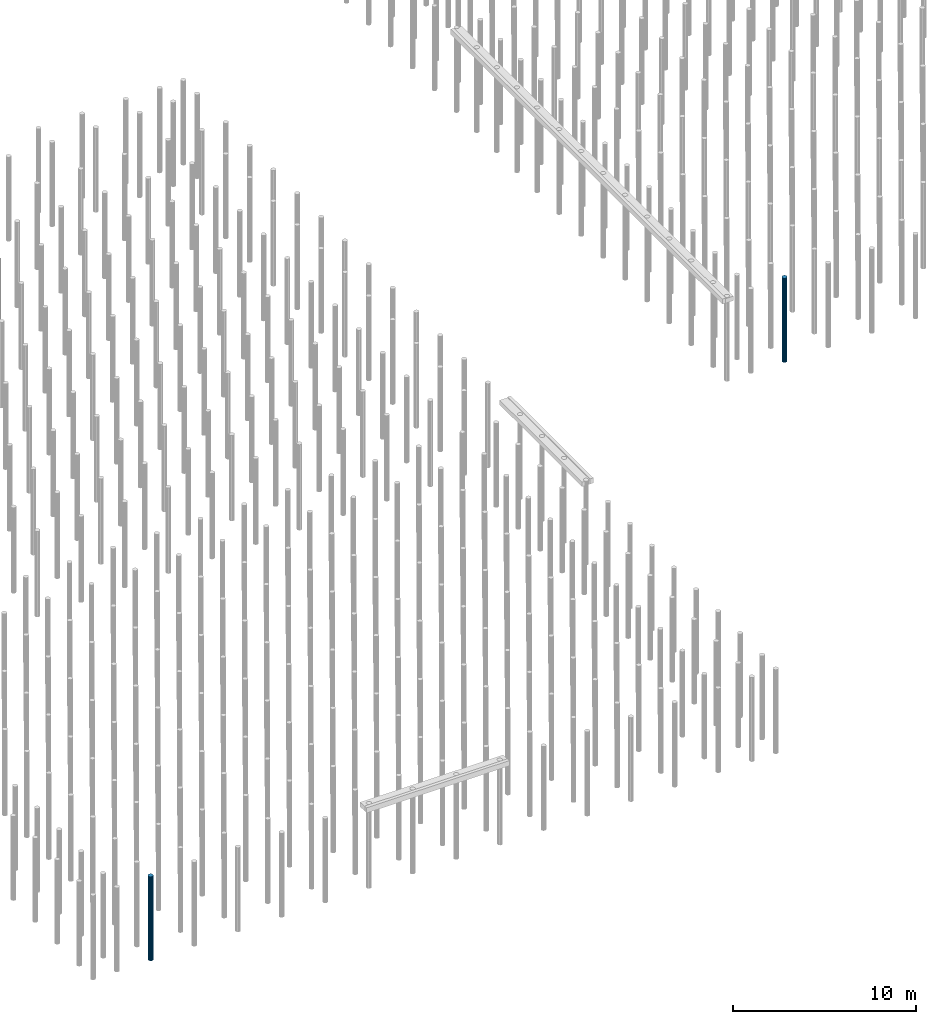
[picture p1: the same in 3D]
Properties of the parts of a building model (IFC2X3), part 10 of 13

# IfcSlab: Slab 772, 17_WSP_FD_beton - fundatiepaal v21-2:ø300 (schroef):1507010
Component Quantities - WSP_beton - ihwg beton, Mass: 887.213 kg; WSP_beton - ihwg beton, Component Volume (Net): 0.385745 m3; WSP_beton - ihwg beton, Component Volume (Gross): 0.385745 m3

# IfcSlab: Slab 773, 17_WSP_FD_beton - fundatiepaal v21-2:ø300 (schroef):1507039
In: -2 fundering
Classification: Vloerplaat - fundering (ARCHICAD Classification); Material: WSP_beton - ihwg beton
Pset_SlabCommon - Reference: ø300 (schroef); IsExternal: yes; LoadBearing: no
Pset_ReinforcementBarPitchOfSlab - Reference: ø300 (schroef)
CPset_Phasing - Renovation Phase: Bestaand
Component Quantities - WSP_beton - ihwg beton, Mass: 887.213 kg; WSP_beton - ihwg beton, Component Volume (Net): 0.385745 m3; WSP_beton - ihwg beton, Component Volume (Gross): 0.385745 m3

# IfcSlab: Slab 774, 17_WSP_FD_beton - fundatiepaal v21-2:ø300 (schroef):1507038
In: -2 fundering
Classification: Vloerplaat - fundering (ARCHICAD Classification); Material: WSP_beton - ihwg beton
CPset_Phasing - Renovation Phase: Bestaand
Pset_ReinforcementBarPitchOfSlab - Reference: ø300 (schroef)
Pset_SlabCommon - Reference: ø300 (schroef); IsExternal: yes; LoadBearing: no
Component Quantities - WSP_beton - ihwg beton, Mass: 887.213 kg; WSP_beton - ihwg beton, Component Volume (Net): 0.385745 m3; WSP_beton - ihwg beton, Component Volume (Gross): 0.385745 m3

# IfcSlab: Slab 775, 17_WSP_FD_beton - fundatiepaal v21-2:ø300 (schroef):1507037
In: -2 fundering
Classification: Vloerplaat - fundering (ARCHICAD Classification); Material: WSP_beton - ihwg beton
Pset_SlabCommon - Reference: ø300 (schroef); IsExternal: yes; LoadBearing: no
CPset_Phasing - Renovation Phase: Bestaand
Pset_ReinforcementBarPitchOfSlab - Reference: ø300 (schroef)
Component Quantities - WSP_beton - ihwg beton, Mass: 887.213 kg; WSP_beton - ihwg beton, Component Volume (Net): 0.385745 m3; WSP_beton - ihwg beton, Component Volume (Gross): 0.385745 m3

# IfcSlab: Slab 776, 17_WSP_FD_beton - fundatiepaal v21-2:ø300 (schroef):1507036
In: -2 fundering
Classification: Vloerplaat - fundering (ARCHICAD Classification); Material: WSP_beton - ihwg beton
Pset_ReinforcementBarPitchOfSlab - Reference: ø300 (schroef)
Pset_SlabCommon - Reference: ø300 (schroef); IsExternal: yes; LoadBearing: no
CPset_Phasing - Renovation Phase: Bestaand
Component Quantities - WSP_beton - ihwg beton, Mass: 887.213 kg; WSP_beton - ihwg beton, Component Volume (Net): 0.385745 m3; WSP_beton - ihwg beton, Component Volume (Gross): 0.385745 m3

# IfcSlab: Slab 777, 17_WSP_FD_beton - fundatiepaal v21-2:ø300 (schroef):1507035
In: -2 fundering
Classification: Vloerplaat - fundering (ARCHICAD Classification); Material: WSP_beton - ihwg beton
Pset_SlabCommon - Reference: ø300 (schroef); IsExternal: yes; LoadBearing: no
Pset_ReinforcementBarPitchOfSlab - Reference: ø300 (schroef)
CPset_Phasing - Renovation Phase: Bestaand
Component Quantities - WSP_beton - ihwg beton, Mass: 887.213 kg; WSP_beton - ihwg beton, Component Volume (Net): 0.385745 m3; WSP_beton - ihwg beton, Component Volume (Gross): 0.385745 m3

# IfcSlab: Slab 778, 17_WSP_FD_beton - fundatiepaal v21-2:ø300 (schroef):1507034
In: -2 fundering
Classification: Vloerplaat - fundering (ARCHICAD Classification); Material: WSP_beton - ihwg beton
Pset_ReinforcementBarPitchOfSlab - Reference: ø300 (schroef)
Pset_SlabCommon - Reference: ø300 (schroef); IsExternal: yes; LoadBearing: no
CPset_Phasing - Renovation Phase: Bestaand
Component Quantities - WSP_beton - ihwg beton, Mass: 887.213 kg; WSP_beton - ihwg beton, Component Volume (Net): 0.385745 m3; WSP_beton - ihwg beton, Component Volume (Gross): 0.385745 m3

# IfcSlab: Slab 779, 17_WSP_FD_beton - fundatiepaal v21-2:ø300 (schroef):1507033
In: -2 fundering
Classification: Vloerplaat - fundering (ARCHICAD Classification); Material: WSP_beton - ihwg beton
Pset_SlabCommon - Reference: ø300 (schroef); IsExternal: yes; LoadBearing: no
Pset_ReinforcementBarPitchOfSlab - Reference: ø300 (schroef)
CPset_Phasing - Renovation Phase: Bestaand
Component Quantities - WSP_beton - ihwg beton, Mass: 887.213 kg; WSP_beton - ihwg beton, Component Volume (Net): 0.385745 m3; WSP_beton - ihwg beton, Component Volume (Gross): 0.385745 m3

# IfcSlab: Slab 78, 17_WSP_FD_beton - fundatiepaal v21-2:ø300 (schroef):1473586
In: -2 fundering
Classification: Vloerplaat - fundering (ARCHICAD Classification); Material: WSP_beton - ihwg beton
Pset_SlabCommon - Reference: ø300 (schroef); IsExternal: yes; LoadBearing: no
CPset_Phasing - Renovation Phase: Bestaand
Component Quantities - WSP_beton - ihwg beton, Mass: 903.056 kg; WSP_beton - ihwg beton, Component Volume (Net): 0.392633 m3; WSP_beton - ihwg beton, Component Volume (Gross): 0.392633 m3
Pset_ReinforcementBarPitchOfSlab - Reference: ø300 (schroef)

# IfcSlab: Slab 780, 17_WSP_FD_beton - fundatiepaal v21-2:ø300 (schroef):1507032
In: -2 fundering
Classification: Vloerplaat - fundering (ARCHICAD Classification); Material: WSP_beton - ihwg beton
Pset_SlabCommon - Reference: ø300 (schroef); IsExternal: yes; LoadBearing: no
CPset_Phasing - Renovation Phase: Bestaand
Component Quantities - WSP_beton - ihwg beton, Mass: 887.213 kg; WSP_beton - ihwg beton, Component Volume (Net): 0.385745 m3; WSP_beton - ihwg beton, Component Volume (Gross): 0.385745 m3
Pset_ReinforcementBarPitchOfSlab - Reference: ø300 (schroef)

# IfcSlab: Slab 781, 17_WSP_FD_beton - fundatiepaal v21-2:ø300 (schroef):1507031
In: -2 fundering
Classification: Vloerplaat - fundering (ARCHICAD Classification); Material: WSP_beton - ihwg beton
Pset_ReinforcementBarPitchOfSlab - Reference: ø300 (schroef)
CPset_Phasing - Renovation Phase: Bestaand
Component Quantities - WSP_beton - ihwg beton, Mass: 887.213 kg; WSP_beton - ihwg beton, Component Volume (Net): 0.385745 m3; WSP_beton - ihwg beton, Component Volume (Gross): 0.385745 m3
Pset_SlabCommon - Reference: ø300 (schroef); IsExternal: yes; LoadBearing: no

# IfcSlab: Slab 782, 17_WSP_FD_beton - fundatiepaal v21-2:ø300 (schroef):1507030
In: -2 fundering
Classification: Vloerplaat - fundering (ARCHICAD Classification); Material: WSP_beton - ihwg beton
Pset_SlabCommon - Reference: ø300 (schroef); IsExternal: yes; LoadBearing: no
Pset_ReinforcementBarPitchOfSlab - Reference: ø300 (schroef)
Component Quantities - WSP_beton - ihwg beton, Mass: 887.213 kg; WSP_beton - ihwg beton, Component Volume (Net): 0.385745 m3; WSP_beton - ihwg beton, Component Volume (Gross): 0.385745 m3
CPset_Phasing - Renovation Phase: Bestaand

# IfcSlab: Slab 783, 17_WSP_FD_beton - fundatiepaal v21-2:ø300 (schroef):1507029
In: -2 fundering
Classification: Vloerplaat - fundering (ARCHICAD Classification); Material: WSP_beton - ihwg beton
Pset_ReinforcementBarPitchOfSlab - Reference: ø300 (schroef)
Pset_SlabCommon - Reference: ø300 (schroef); IsExternal: yes; LoadBearing: no
Component Quantities - WSP_beton - ihwg beton, Mass: 887.213 kg; WSP_beton - ihwg beton, Component Volume (Net): 0.385745 m3; WSP_beton - ihwg beton, Component Volume (Gross): 0.385745 m3
CPset_Phasing - Renovation Phase: Bestaand

# IfcSlab: Slab 784, 17_WSP_FD_beton - fundatiepaal v21-2:ø300 (schroef):1507028
In: -2 fundering
Classification: Vloerplaat - fundering (ARCHICAD Classification); Material: WSP_beton - ihwg beton
Pset_SlabCommon - Reference: ø300 (schroef); IsExternal: yes; LoadBearing: no
Pset_ReinforcementBarPitchOfSlab - Reference: ø300 (schroef)
CPset_Phasing - Renovation Phase: Bestaand
Component Quantities - WSP_beton - ihwg beton, Mass: 887.213 kg; WSP_beton - ihwg beton, Component Volume (Net): 0.385745 m3; WSP_beton - ihwg beton, Component Volume (Gross): 0.385745 m3

# IfcSlab: Slab 785, 17_WSP_FD_beton - fundatiepaal v21-2:ø300 (schroef):1507027
In: -2 fundering
Classification: Vloerplaat - fundering (ARCHICAD Classification); Material: WSP_beton - ihwg beton
Pset_SlabCommon - Reference: ø300 (schroef); IsExternal: yes; LoadBearing: no
Pset_ReinforcementBarPitchOfSlab - Reference: ø300 (schroef)
Component Quantities - WSP_beton - ihwg beton, Mass: 887.213 kg; WSP_beton - ihwg beton, Component Volume (Net): 0.385745 m3; WSP_beton - ihwg beton, Component Volume (Gross): 0.385745 m3
CPset_Phasing - Renovation Phase: Bestaand

# IfcSlab: Slab 786, 17_WSP_FD_beton - fundatiepaal v21-2:ø300 (schroef):1507026
In: -2 fundering
Classification: Vloerplaat - fundering (ARCHICAD Classification); Material: WSP_beton - ihwg beton
Pset_SlabCommon - Reference: ø300 (schroef); IsExternal: yes; LoadBearing: no
Pset_ReinforcementBarPitchOfSlab - Reference: ø300 (schroef)
CPset_Phasing - Renovation Phase: Bestaand
Component Quantities - WSP_beton - ihwg beton, Mass: 887.213 kg; WSP_beton - ihwg beton, Component Volume (Net): 0.385745 m3; WSP_beton - ihwg beton, Component Volume (Gross): 0.385745 m3

# IfcSlab: Slab 787, 17_WSP_FD_beton - fundatiepaal v21-2:ø300 (schroef):1507025
In: -2 fundering
Classification: Vloerplaat - fundering (ARCHICAD Classification); Material: WSP_beton - ihwg beton
Component Quantities - WSP_beton - ihwg beton, Mass: 887.213 kg; WSP_beton - ihwg beton, Component Volume (Net): 0.385745 m3; WSP_beton - ihwg beton, Component Volume (Gross): 0.385745 m3
Pset_ReinforcementBarPitchOfSlab - Reference: ø300 (schroef)
Pset_SlabCommon - Reference: ø300 (schroef); IsExternal: yes; LoadBearing: no
CPset_Phasing - Renovation Phase: Bestaand

# IfcSlab: Slab 788, 17_WSP_FD_beton - fundatiepaal v21-2:ø300 (schroef):1507024
In: -2 fundering
Classification: Vloerplaat - fundering (ARCHICAD Classification); Material: WSP_beton - ihwg beton
Pset_SlabCommon - Reference: ø300 (schroef); IsExternal: yes; LoadBearing: no
Pset_ReinforcementBarPitchOfSlab - Reference: ø300 (schroef)
CPset_Phasing - Renovation Phase: Bestaand
Component Quantities - WSP_beton - ihwg beton, Mass: 887.213 kg; WSP_beton - ihwg beton, Component Volume (Net): 0.385745 m3; WSP_beton - ihwg beton, Component Volume (Gross): 0.385745 m3

# IfcSlab: Slab 789, 17_WSP_FD_beton - fundatiepaal v21-2:ø300 (schroef):1506799
In: -2 fundering
Classification: Vloerplaat - fundering (ARCHICAD Classification); Material: WSP_beton - ihwg beton
Pset_SlabCommon - Reference: ø300 (schroef); IsExternal: yes; LoadBearing: no
Pset_ReinforcementBarPitchOfSlab - Reference: ø300 (schroef)
CPset_Phasing - Renovation Phase: Bestaand
Component Quantities - WSP_beton - ihwg beton, Mass: 887.213 kg; WSP_beton - ihwg beton, Component Volume (Net): 0.385745 m3; WSP_beton - ihwg beton, Component Volume (Gross): 0.385745 m3

# IfcSlab: Slab 79, 17_WSP_FD_beton - fundatiepaal v21-2:ø300 (schroef):1473587
In: -2 fundering
Classification: Vloerplaat - fundering (ARCHICAD Classification); Material: WSP_beton - ihwg beton
Pset_ReinforcementBarPitchOfSlab - Reference: ø300 (schroef)
Pset_SlabCommon - Reference: ø300 (schroef); IsExternal: yes; LoadBearing: no
CPset_Phasing - Renovation Phase: Bestaand
Component Quantities - WSP_beton - ihwg beton, Mass: 903.056 kg; WSP_beton - ihwg beton, Component Volume (Net): 0.392633 m3; WSP_beton - ihwg beton, Component Volume (Gross): 0.392633 m3

# IfcSlab: Slab 790, 17_WSP_FD_beton - fundatiepaal v21-2:ø300 (schroef):1506798
In: -2 fundering
Classification: Vloerplaat - fundering (ARCHICAD Classification); Material: WSP_beton - ihwg beton
Pset_SlabCommon - Reference: ø300 (schroef); IsExternal: yes; LoadBearing: no
Pset_ReinforcementBarPitchOfSlab - Reference: ø300 (schroef)
CPset_Phasing - Renovation Phase: Bestaand
Component Quantities - WSP_beton - ihwg beton, Mass: 887.213 kg; WSP_beton - ihwg beton, Component Volume (Net): 0.385745 m3; WSP_beton - ihwg beton, Component Volume (Gross): 0.385745 m3

# IfcSlab: Slab 791, 17_WSP_FD_beton - fundatiepaal v21-2:ø300 (schroef):1506797
In: -2 fundering
Classification: Vloerplaat - fundering (ARCHICAD Classification); Material: WSP_beton - ihwg beton
Pset_SlabCommon - Reference: ø300 (schroef); IsExternal: yes; LoadBearing: no
Pset_ReinforcementBarPitchOfSlab - Reference: ø300 (schroef)
CPset_Phasing - Renovation Phase: Bestaand
Component Quantities - WSP_beton - ihwg beton, Mass: 887.213 kg; WSP_beton - ihwg beton, Component Volume (Net): 0.385745 m3; WSP_beton - ihwg beton, Component Volume (Gross): 0.385745 m3

# IfcSlab: Slab 792, 17_WSP_FD_beton - fundatiepaal v21-2:ø300 (schroef):1506796
In: -2 fundering
Classification: Vloerplaat - fundering (ARCHICAD Classification); Material: WSP_beton - ihwg beton
Pset_ReinforcementBarPitchOfSlab - Reference: ø300 (schroef)
Pset_SlabCommon - Reference: ø300 (schroef); IsExternal: yes; LoadBearing: no
CPset_Phasing - Renovation Phase: Bestaand
Component Quantities - WSP_beton - ihwg beton, Mass: 887.213 kg; WSP_beton - ihwg beton, Component Volume (Net): 0.385745 m3; WSP_beton - ihwg beton, Component Volume (Gross): 0.385745 m3

# IfcSlab: Slab 793, 17_WSP_FD_beton - fundatiepaal v21-2:ø300 (schroef):1506795
In: -2 fundering
Classification: Vloerplaat - fundering (ARCHICAD Classification); Material: WSP_beton - ihwg beton
Pset_SlabCommon - Reference: ø300 (schroef); IsExternal: yes; LoadBearing: no
Pset_ReinforcementBarPitchOfSlab - Reference: ø300 (schroef)
CPset_Phasing - Renovation Phase: Bestaand
Component Quantities - WSP_beton - ihwg beton, Mass: 887.213 kg; WSP_beton - ihwg beton, Component Volume (Net): 0.385745 m3; WSP_beton - ihwg beton, Component Volume (Gross): 0.385745 m3

# IfcSlab: Slab 794, 17_WSP_FD_beton - fundatiepaal v21-2:ø300 (schroef):1506794
In: -2 fundering
Classification: Vloerplaat - fundering (ARCHICAD Classification); Material: WSP_beton - ihwg beton
Pset_ReinforcementBarPitchOfSlab - Reference: ø300 (schroef)
Component Quantities - WSP_beton - ihwg beton, Mass: 887.213 kg; WSP_beton - ihwg beton, Component Volume (Net): 0.385745 m3; WSP_beton - ihwg beton, Component Volume (Gross): 0.385745 m3
Pset_SlabCommon - Reference: ø300 (schroef); IsExternal: yes; LoadBearing: no
CPset_Phasing - Renovation Phase: Bestaand

# IfcSlab: Slab 795, 17_WSP_FD_beton - fundatiepaal v21-2:ø300 (schroef):1506793
In: -2 fundering
Classification: Vloerplaat - fundering (ARCHICAD Classification); Material: WSP_beton - ihwg beton
Pset_SlabCommon - Reference: ø300 (schroef); IsExternal: yes; LoadBearing: no
Pset_ReinforcementBarPitchOfSlab - Reference: ø300 (schroef)
CPset_Phasing - Renovation Phase: Bestaand
Component Quantities - WSP_beton - ihwg beton, Mass: 887.213 kg; WSP_beton - ihwg beton, Component Volume (Net): 0.385745 m3; WSP_beton - ihwg beton, Component Volume (Gross): 0.385745 m3

# IfcSlab: Slab 796, 17_WSP_FD_beton - fundatiepaal v21-2:ø300 (schroef):1506792
In: -2 fundering
Classification: Vloerplaat - fundering (ARCHICAD Classification); Material: WSP_beton - ihwg beton
Pset_SlabCommon - Reference: ø300 (schroef); IsExternal: yes; LoadBearing: no
Pset_ReinforcementBarPitchOfSlab - Reference: ø300 (schroef)
Component Quantities - WSP_beton - ihwg beton, Mass: 887.213 kg; WSP_beton - ihwg beton, Component Volume (Net): 0.385745 m3; WSP_beton - ihwg beton, Component Volume (Gross): 0.385745 m3
CPset_Phasing - Renovation Phase: Bestaand

# IfcSlab: Slab 797, 17_WSP_FD_beton - fundatiepaal v21-2:ø300 (schroef):1506791
In: -2 fundering
Classification: Vloerplaat - fundering (ARCHICAD Classification); Material: WSP_beton - ihwg beton
Pset_SlabCommon - Reference: ø300 (schroef); IsExternal: yes; LoadBearing: no
Pset_ReinforcementBarPitchOfSlab - Reference: ø300 (schroef)
Component Quantities - WSP_beton - ihwg beton, Mass: 887.213 kg; WSP_beton - ihwg beton, Component Volume (Net): 0.385745 m3; WSP_beton - ihwg beton, Component Volume (Gross): 0.385745 m3
CPset_Phasing - Renovation Phase: Bestaand

# IfcSlab: Slab 798, 17_WSP_FD_beton - fundatiepaal v21-2:ø300 (schroef):1506790
In: -2 fundering
Classification: Vloerplaat - fundering (ARCHICAD Classification); Material: WSP_beton - ihwg beton
Pset_SlabCommon - Reference: ø300 (schroef); IsExternal: yes; LoadBearing: no
Pset_ReinforcementBarPitchOfSlab - Reference: ø300 (schroef)
CPset_Phasing - Renovation Phase: Bestaand
Component Quantities - WSP_beton - ihwg beton, Mass: 887.213 kg; WSP_beton - ihwg beton, Component Volume (Net): 0.385745 m3; WSP_beton - ihwg beton, Component Volume (Gross): 0.385745 m3

# IfcSlab: Slab 799, 17_WSP_FD_beton - fundatiepaal v21-2:ø300 (schroef):1506789
In: -2 fundering
Classification: Vloerplaat - fundering (ARCHICAD Classification); Material: WSP_beton - ihwg beton
Pset_SlabCommon - Reference: ø300 (schroef); IsExternal: yes; LoadBearing: no
CPset_Phasing - Renovation Phase: Bestaand
Component Quantities - WSP_beton - ihwg beton, Mass: 887.213 kg; WSP_beton - ihwg beton, Component Volume (Net): 0.385745 m3; WSP_beton - ihwg beton, Component Volume (Gross): 0.385745 m3
Pset_ReinforcementBarPitchOfSlab - Reference: ø300 (schroef)

# IfcSlab: Slab 8, 17_WSP_FD_beton - fundatiepaal v21-2:ø300 (schroef):1528055
In: -2 fundering
Classification: Vloerplaat - fundering (ARCHICAD Classification); Material: WSP_beton - ihwg beton
Pset_SlabCommon - Reference: ø300 (schroef); IsExternal: yes; LoadBearing: no
Pset_ReinforcementBarPitchOfSlab - Reference: ø300 (schroef)
CPset_Phasing - Renovation Phase: Bestaand
Component Quantities - WSP_beton - ihwg beton, Mass: 903.056 kg; WSP_beton - ihwg beton, Component Volume (Net): 0.392633 m3; WSP_beton - ihwg beton, Component Volume (Gross): 0.392633 m3

# IfcSlab: Slab 80, 17_WSP_FD_beton - fundatiepaal v21-2:ø300 (schroef):1473584
In: -2 fundering
Classification: Vloerplaat - fundering (ARCHICAD Classification); Material: WSP_beton - ihwg beton
Pset_ReinforcementBarPitchOfSlab - Reference: ø300 (schroef)
Pset_SlabCommon - Reference: ø300 (schroef); IsExternal: yes; LoadBearing: no
CPset_Phasing - Renovation Phase: Bestaand
Component Quantities - WSP_beton - ihwg beton, Mass: 903.056 kg; WSP_beton - ihwg beton, Component Volume (Net): 0.392633 m3; WSP_beton - ihwg beton, Component Volume (Gross): 0.392633 m3

# IfcSlab: Slab 800, 17_WSP_FD_beton - fundatiepaal v21-2:ø300 (schroef):1506788
In: -2 fundering
Classification: Vloerplaat - fundering (ARCHICAD Classification); Material: WSP_beton - ihwg beton
CPset_Phasing - Renovation Phase: Bestaand
Pset_ReinforcementBarPitchOfSlab - Reference: ø300 (schroef)
Pset_SlabCommon - Reference: ø300 (schroef); IsExternal: yes; LoadBearing: no
Component Quantities - WSP_beton - ihwg beton, Mass: 887.213 kg; WSP_beton - ihwg beton, Component Volume (Net): 0.385745 m3; WSP_beton - ihwg beton, Component Volume (Gross): 0.385745 m3

# IfcSlab: Slab 801, 17_WSP_FD_beton - fundatiepaal v21-2:ø300 (schroef):1506787
In: -2 fundering
Classification: Vloerplaat - fundering (ARCHICAD Classification); Material: WSP_beton - ihwg beton
Pset_SlabCommon - Reference: ø300 (schroef); IsExternal: yes; LoadBearing: no
Pset_ReinforcementBarPitchOfSlab - Reference: ø300 (schroef)
Component Quantities - WSP_beton - ihwg beton, Mass: 887.213 kg; WSP_beton - ihwg beton, Component Volume (Net): 0.385745 m3; WSP_beton - ihwg beton, Component Volume (Gross): 0.385745 m3
CPset_Phasing - Renovation Phase: Bestaand

# IfcSlab: Slab 802, 17_WSP_FD_beton - fundatiepaal v21-2:ø300 (schroef):1507375
In: -2 fundering
Classification: Vloerplaat - fundering (ARCHICAD Classification); Material: WSP_beton - ihwg beton
Pset_SlabCommon - Reference: ø300 (schroef); IsExternal: yes; LoadBearing: no
Pset_ReinforcementBarPitchOfSlab - Reference: ø300 (schroef)
Component Quantities - WSP_beton - ihwg beton, Mass: 887.213 kg; WSP_beton - ihwg beton, Component Volume (Net): 0.385745 m3; WSP_beton - ihwg beton, Component Volume (Gross): 0.385745 m3
CPset_Phasing - Renovation Phase: Bestaand

# IfcSlab: Slab 803, 17_WSP_FD_beton - fundatiepaal v21-2:ø300 (schroef):1507374
In: -2 fundering
Classification: Vloerplaat - fundering (ARCHICAD Classification); Material: WSP_beton - ihwg beton
Pset_ReinforcementBarPitchOfSlab - Reference: ø300 (schroef)
CPset_Phasing - Renovation Phase: Bestaand
Pset_SlabCommon - Reference: ø300 (schroef); IsExternal: yes; LoadBearing: no
Component Quantities - WSP_beton - ihwg beton, Mass: 887.213 kg; WSP_beton - ihwg beton, Component Volume (Net): 0.385745 m3; WSP_beton - ihwg beton, Component Volume (Gross): 0.385745 m3

# IfcSlab: Slab 804, 17_WSP_FD_beton - fundatiepaal v21-2:ø300 (schroef):1507373
In: -2 fundering
Classification: Vloerplaat - fundering (ARCHICAD Classification); Material: WSP_beton - ihwg beton
Pset_ReinforcementBarPitchOfSlab - Reference: ø300 (schroef)
CPset_Phasing - Renovation Phase: Bestaand
Component Quantities - WSP_beton - ihwg beton, Mass: 887.213 kg; WSP_beton - ihwg beton, Component Volume (Net): 0.385745 m3; WSP_beton - ihwg beton, Component Volume (Gross): 0.385745 m3
Pset_SlabCommon - Reference: ø300 (schroef); IsExternal: yes; LoadBearing: no

# IfcSlab: Slab 805, 17_WSP_FD_beton - fundatiepaal v21-2:ø300 (schroef):1507372
In: -2 fundering
Classification: Vloerplaat - fundering (ARCHICAD Classification); Material: WSP_beton - ihwg beton
Pset_SlabCommon - Reference: ø300 (schroef); IsExternal: yes; LoadBearing: no
Pset_ReinforcementBarPitchOfSlab - Reference: ø300 (schroef)
CPset_Phasing - Renovation Phase: Bestaand
Component Quantities - WSP_beton - ihwg beton, Mass: 887.213 kg; WSP_beton - ihwg beton, Component Volume (Net): 0.385745 m3; WSP_beton - ihwg beton, Component Volume (Gross): 0.385745 m3

# IfcSlab: Slab 806, 17_WSP_FD_beton - fundatiepaal v21-2:ø300 (schroef):1507371
In: -2 fundering
Classification: Vloerplaat - fundering (ARCHICAD Classification); Material: WSP_beton - ihwg beton
Pset_ReinforcementBarPitchOfSlab - Reference: ø300 (schroef)
CPset_Phasing - Renovation Phase: Bestaand
Pset_SlabCommon - Reference: ø300 (schroef); IsExternal: yes; LoadBearing: no
Component Quantities - WSP_beton - ihwg beton, Mass: 887.213 kg; WSP_beton - ihwg beton, Component Volume (Net): 0.385745 m3; WSP_beton - ihwg beton, Component Volume (Gross): 0.385745 m3

# IfcSlab: Slab 807, 17_WSP_FD_beton - fundatiepaal v21-2:ø300 (schroef):1507370
In: -2 fundering
Classification: Vloerplaat - fundering (ARCHICAD Classification); Material: WSP_beton - ihwg beton
Pset_ReinforcementBarPitchOfSlab - Reference: ø300 (schroef)
CPset_Phasing - Renovation Phase: Bestaand
Pset_SlabCommon - Reference: ø300 (schroef); IsExternal: yes; LoadBearing: no
Component Quantities - WSP_beton - ihwg beton, Mass: 887.213 kg; WSP_beton - ihwg beton, Component Volume (Net): 0.385745 m3; WSP_beton - ihwg beton, Component Volume (Gross): 0.385745 m3

# IfcSlab: Slab 808, 17_WSP_FD_beton - fundatiepaal v21-2:ø300 (schroef):1507369
In: -2 fundering
Classification: Vloerplaat - fundering (ARCHICAD Classification); Material: WSP_beton - ihwg beton
Pset_SlabCommon - Reference: ø300 (schroef); IsExternal: yes; LoadBearing: no
Pset_ReinforcementBarPitchOfSlab - Reference: ø300 (schroef)
Component Quantities - WSP_beton - ihwg beton, Mass: 887.213 kg; WSP_beton - ihwg beton, Component Volume (Net): 0.385745 m3; WSP_beton - ihwg beton, Component Volume (Gross): 0.385745 m3
CPset_Phasing - Renovation Phase: Bestaand

# IfcSlab: Slab 809, 17_WSP_FD_beton - fundatiepaal v21-2:ø300 (schroef):1507368
In: -2 fundering
Classification: Vloerplaat - fundering (ARCHICAD Classification); Material: WSP_beton - ihwg beton
Pset_ReinforcementBarPitchOfSlab - Reference: ø300 (schroef)
Pset_SlabCommon - Reference: ø300 (schroef); IsExternal: yes; LoadBearing: no
Component Quantities - WSP_beton - ihwg beton, Mass: 887.213 kg; WSP_beton - ihwg beton, Component Volume (Net): 0.385745 m3; WSP_beton - ihwg beton, Component Volume (Gross): 0.385745 m3
CPset_Phasing - Renovation Phase: Bestaand

# IfcSlab: Slab 81, 17_WSP_FD_beton - fundatiepaal v21-2:ø300 (schroef):1473585
In: -2 fundering
Classification: Vloerplaat - fundering (ARCHICAD Classification); Material: WSP_beton - ihwg beton
Pset_SlabCommon - Reference: ø300 (schroef); IsExternal: yes; LoadBearing: no
Component Quantities - WSP_beton - ihwg beton, Mass: 903.056 kg; WSP_beton - ihwg beton, Component Volume (Net): 0.392633 m3; WSP_beton - ihwg beton, Component Volume (Gross): 0.392633 m3
CPset_Phasing - Renovation Phase: Bestaand
Pset_ReinforcementBarPitchOfSlab - Reference: ø300 (schroef)

# IfcSlab: Slab 810, 17_WSP_FD_beton - fundatiepaal v21-2:ø300 (schroef):1507367
In: -2 fundering
Classification: Vloerplaat - fundering (ARCHICAD Classification); Material: WSP_beton - ihwg beton
Pset_SlabCommon - Reference: ø300 (schroef); IsExternal: yes; LoadBearing: no
Pset_ReinforcementBarPitchOfSlab - Reference: ø300 (schroef)
Component Quantities - WSP_beton - ihwg beton, Mass: 887.213 kg; WSP_beton - ihwg beton, Component Volume (Net): 0.385745 m3; WSP_beton - ihwg beton, Component Volume (Gross): 0.385745 m3
CPset_Phasing - Renovation Phase: Bestaand

# IfcSlab: Slab 811, 17_WSP_FD_beton - fundatiepaal v21-2:ø300 (schroef):1507366
In: -2 fundering
Classification: Vloerplaat - fundering (ARCHICAD Classification); Material: WSP_beton - ihwg beton
CPset_Phasing - Renovation Phase: Bestaand
Component Quantities - WSP_beton - ihwg beton, Mass: 887.213 kg; WSP_beton - ihwg beton, Component Volume (Net): 0.385745 m3; WSP_beton - ihwg beton, Component Volume (Gross): 0.385745 m3
Pset_ReinforcementBarPitchOfSlab - Reference: ø300 (schroef)
Pset_SlabCommon - Reference: ø300 (schroef); IsExternal: yes; LoadBearing: no

# IfcSlab: Slab 812, 17_WSP_FD_beton - fundatiepaal v21-2:ø300 (schroef):1507365
In: -2 fundering
Classification: Vloerplaat - fundering (ARCHICAD Classification); Material: WSP_beton - ihwg beton
Pset_ReinforcementBarPitchOfSlab - Reference: ø300 (schroef)
Pset_SlabCommon - Reference: ø300 (schroef); IsExternal: yes; LoadBearing: no
Component Quantities - WSP_beton - ihwg beton, Mass: 887.213 kg; WSP_beton - ihwg beton, Component Volume (Net): 0.385745 m3; WSP_beton - ihwg beton, Component Volume (Gross): 0.385745 m3
CPset_Phasing - Renovation Phase: Bestaand

# IfcSlab: Slab 813, 17_WSP_FD_beton - fundatiepaal v21-2:ø300 (schroef):1507364
In: -2 fundering
Classification: Vloerplaat - fundering (ARCHICAD Classification); Material: WSP_beton - ihwg beton
Pset_ReinforcementBarPitchOfSlab - Reference: ø300 (schroef)
CPset_Phasing - Renovation Phase: Bestaand
Pset_SlabCommon - Reference: ø300 (schroef); IsExternal: yes; LoadBearing: no
Component Quantities - WSP_beton - ihwg beton, Mass: 887.213 kg; WSP_beton - ihwg beton, Component Volume (Net): 0.385745 m3; WSP_beton - ihwg beton, Component Volume (Gross): 0.385745 m3

# IfcSlab: Slab 814, 17_WSP_FD_beton - fundatiepaal v21-2:ø300 (schroef):1507363
In: -2 fundering
Classification: Vloerplaat - fundering (ARCHICAD Classification); Material: WSP_beton - ihwg beton
Pset_ReinforcementBarPitchOfSlab - Reference: ø300 (schroef)
Pset_SlabCommon - Reference: ø300 (schroef); IsExternal: yes; LoadBearing: no
Component Quantities - WSP_beton - ihwg beton, Mass: 887.213 kg; WSP_beton - ihwg beton, Component Volume (Net): 0.385745 m3; WSP_beton - ihwg beton, Component Volume (Gross): 0.385745 m3
CPset_Phasing - Renovation Phase: Bestaand

# IfcSlab: Slab 815, 17_WSP_FD_beton - fundatiepaal v21-2:ø300 (schroef):1507362
In: -2 fundering
Classification: Vloerplaat - fundering (ARCHICAD Classification); Material: WSP_beton - ihwg beton
Pset_ReinforcementBarPitchOfSlab - Reference: ø300 (schroef)
CPset_Phasing - Renovation Phase: Bestaand
Pset_SlabCommon - Reference: ø300 (schroef); IsExternal: yes; LoadBearing: no
Component Quantities - WSP_beton - ihwg beton, Mass: 887.213 kg; WSP_beton - ihwg beton, Component Volume (Net): 0.385745 m3; WSP_beton - ihwg beton, Component Volume (Gross): 0.385745 m3

# IfcSlab: Slab 816, 17_WSP_FD_beton - fundatiepaal v21-2:ø300 (schroef):1507361
In: -2 fundering
Classification: Vloerplaat - fundering (ARCHICAD Classification); Material: WSP_beton - ihwg beton
Pset_SlabCommon - Reference: ø300 (schroef); IsExternal: yes; LoadBearing: no
Pset_ReinforcementBarPitchOfSlab - Reference: ø300 (schroef)
CPset_Phasing - Renovation Phase: Bestaand
Component Quantities - WSP_beton - ihwg beton, Mass: 887.213 kg; WSP_beton - ihwg beton, Component Volume (Net): 0.385745 m3; WSP_beton - ihwg beton, Component Volume (Gross): 0.385745 m3

# IfcSlab: Slab 817, 17_WSP_FD_beton - fundatiepaal v21-2:ø300 (schroef):1507360
In: -2 fundering
Classification: Vloerplaat - fundering (ARCHICAD Classification); Material: WSP_beton - ihwg beton
Pset_SlabCommon - Reference: ø300 (schroef); IsExternal: yes; LoadBearing: no
Pset_ReinforcementBarPitchOfSlab - Reference: ø300 (schroef)
CPset_Phasing - Renovation Phase: Bestaand
Component Quantities - WSP_beton - ihwg beton, Mass: 887.213 kg; WSP_beton - ihwg beton, Component Volume (Net): 0.385745 m3; WSP_beton - ihwg beton, Component Volume (Gross): 0.385745 m3

# IfcSlab: Slab 818, 17_WSP_FD_beton - fundatiepaal v21-2:ø300 (schroef):1507380
In: -2 fundering
Classification: Vloerplaat - fundering (ARCHICAD Classification); Material: WSP_beton - ihwg beton
Pset_SlabCommon - Reference: ø300 (schroef); IsExternal: yes; LoadBearing: no
CPset_Phasing - Renovation Phase: Bestaand
Pset_ReinforcementBarPitchOfSlab - Reference: ø300 (schroef)
Component Quantities - WSP_beton - ihwg beton, Mass: 887.213 kg; WSP_beton - ihwg beton, Component Volume (Net): 0.385745 m3; WSP_beton - ihwg beton, Component Volume (Gross): 0.385745 m3

# IfcSlab: Slab 819, 17_WSP_FD_beton - fundatiepaal v21-2:ø300 (schroef):1507379
In: -2 fundering
Classification: Vloerplaat - fundering (ARCHICAD Classification); Material: WSP_beton - ihwg beton
Pset_SlabCommon - Reference: ø300 (schroef); IsExternal: yes; LoadBearing: no
Pset_ReinforcementBarPitchOfSlab - Reference: ø300 (schroef)
CPset_Phasing - Renovation Phase: Bestaand
Component Quantities - WSP_beton - ihwg beton, Mass: 887.213 kg; WSP_beton - ihwg beton, Component Volume (Net): 0.385745 m3; WSP_beton - ihwg beton, Component Volume (Gross): 0.385745 m3

# IfcSlab: Slab 82, 17_WSP_FD_beton - fundatiepaal v21-2:ø300 (schroef):1473590
In: -2 fundering
Classification: Vloerplaat - fundering (ARCHICAD Classification); Material: WSP_beton - ihwg beton
Pset_SlabCommon - Reference: ø300 (schroef); IsExternal: yes; LoadBearing: no
Pset_ReinforcementBarPitchOfSlab - Reference: ø300 (schroef)
CPset_Phasing - Renovation Phase: Bestaand
Component Quantities - WSP_beton - ihwg beton, Mass: 903.056 kg; WSP_beton - ihwg beton, Component Volume (Net): 0.392633 m3; WSP_beton - ihwg beton, Component Volume (Gross): 0.392633 m3

# IfcSlab: Slab 820, 17_WSP_FD_beton - fundatiepaal v21-2:ø300 (schroef):1507378
In: -2 fundering
Classification: Vloerplaat - fundering (ARCHICAD Classification); Material: WSP_beton - ihwg beton
Pset_ReinforcementBarPitchOfSlab - Reference: ø300 (schroef)
Pset_SlabCommon - Reference: ø300 (schroef); IsExternal: yes; LoadBearing: no
CPset_Phasing - Renovation Phase: Bestaand
Component Quantities - WSP_beton - ihwg beton, Mass: 887.213 kg; WSP_beton - ihwg beton, Component Volume (Net): 0.385745 m3; WSP_beton - ihwg beton, Component Volume (Gross): 0.385745 m3

# IfcSlab: Slab 821, 17_WSP_FD_beton - fundatiepaal v21-2:ø300 (schroef):1507377
In: -2 fundering
Classification: Vloerplaat - fundering (ARCHICAD Classification); Material: WSP_beton - ihwg beton
Pset_SlabCommon - Reference: ø300 (schroef); IsExternal: yes; LoadBearing: no
CPset_Phasing - Renovation Phase: Bestaand
Pset_ReinforcementBarPitchOfSlab - Reference: ø300 (schroef)
Component Quantities - WSP_beton - ihwg beton, Mass: 887.213 kg; WSP_beton - ihwg beton, Component Volume (Net): 0.385745 m3; WSP_beton - ihwg beton, Component Volume (Gross): 0.385745 m3

# IfcSlab: Slab 822, 17_WSP_FD_beton - fundatiepaal v21-2:ø300 (schroef):1507376
In: -2 fundering
Classification: Vloerplaat - fundering (ARCHICAD Classification); Material: WSP_beton - ihwg beton
Pset_SlabCommon - Reference: ø300 (schroef); IsExternal: yes; LoadBearing: no
Component Quantities - WSP_beton - ihwg beton, Mass: 887.213 kg; WSP_beton - ihwg beton, Component Volume (Net): 0.385745 m3; WSP_beton - ihwg beton, Component Volume (Gross): 0.385745 m3
CPset_Phasing - Renovation Phase: Bestaand
Pset_ReinforcementBarPitchOfSlab - Reference: ø300 (schroef)

# IfcSlab: Slab 823, 17_WSP_FD_beton - fundatiepaal v21-2:ø300 (schroef):1507359
In: -2 fundering
Classification: Vloerplaat - fundering (ARCHICAD Classification); Material: WSP_beton - ihwg beton
Pset_SlabCommon - Reference: ø300 (schroef); IsExternal: yes; LoadBearing: no
Pset_ReinforcementBarPitchOfSlab - Reference: ø300 (schroef)
CPset_Phasing - Renovation Phase: Bestaand
Component Quantities - WSP_beton - ihwg beton, Mass: 887.213 kg; WSP_beton - ihwg beton, Component Volume (Net): 0.385745 m3; WSP_beton - ihwg beton, Component Volume (Gross): 0.385745 m3

# IfcSlab: Slab 824, 17_WSP_FD_beton - fundatiepaal v21-2:ø300 (schroef):1507358
In: -2 fundering
Classification: Vloerplaat - fundering (ARCHICAD Classification); Material: WSP_beton - ihwg beton
Pset_SlabCommon - Reference: ø300 (schroef); IsExternal: yes; LoadBearing: no
Pset_ReinforcementBarPitchOfSlab - Reference: ø300 (schroef)
CPset_Phasing - Renovation Phase: Bestaand
Component Quantities - WSP_beton - ihwg beton, Mass: 887.213 kg; WSP_beton - ihwg beton, Component Volume (Net): 0.385745 m3; WSP_beton - ihwg beton, Component Volume (Gross): 0.385745 m3

# IfcSlab: Slab 825, 17_WSP_FD_beton - fundatiepaal v21-2:ø300 (schroef):1507357
In: -2 fundering
Classification: Vloerplaat - fundering (ARCHICAD Classification); Material: WSP_beton - ihwg beton
Pset_SlabCommon - Reference: ø300 (schroef); IsExternal: yes; LoadBearing: no
CPset_Phasing - Renovation Phase: Bestaand
Component Quantities - WSP_beton - ihwg beton, Mass: 887.213 kg; WSP_beton - ihwg beton, Component Volume (Net): 0.385745 m3; WSP_beton - ihwg beton, Component Volume (Gross): 0.385745 m3
Pset_ReinforcementBarPitchOfSlab - Reference: ø300 (schroef)

# IfcSlab: Slab 826, 17_WSP_FD_beton - fundatiepaal v21-2:ø300 (schroef):1507356
In: -2 fundering
Classification: Vloerplaat - fundering (ARCHICAD Classification); Material: WSP_beton - ihwg beton
Pset_SlabCommon - Reference: ø300 (schroef); IsExternal: yes; LoadBearing: no
CPset_Phasing - Renovation Phase: Bestaand
Pset_ReinforcementBarPitchOfSlab - Reference: ø300 (schroef)
Component Quantities - WSP_beton - ihwg beton, Mass: 887.213 kg; WSP_beton - ihwg beton, Component Volume (Net): 0.385745 m3; WSP_beton - ihwg beton, Component Volume (Gross): 0.385745 m3

# IfcSlab: Slab 827, 17_WSP_FD_beton - fundatiepaal v21-2:ø300 (schroef):1507355
In: -2 fundering
Classification: Vloerplaat - fundering (ARCHICAD Classification); Material: WSP_beton - ihwg beton
Pset_SlabCommon - Reference: ø300 (schroef); IsExternal: yes; LoadBearing: no
CPset_Phasing - Renovation Phase: Bestaand
Pset_ReinforcementBarPitchOfSlab - Reference: ø300 (schroef)
Component Quantities - WSP_beton - ihwg beton, Mass: 887.213 kg; WSP_beton - ihwg beton, Component Volume (Net): 0.385745 m3; WSP_beton - ihwg beton, Component Volume (Gross): 0.385745 m3

# IfcSlab: Slab 828, 17_WSP_FD_beton - fundatiepaal v21-2:ø300 (schroef):1507354
In: -2 fundering
Classification: Vloerplaat - fundering (ARCHICAD Classification); Material: WSP_beton - ihwg beton
Pset_SlabCommon - Reference: ø300 (schroef); IsExternal: yes; LoadBearing: no
CPset_Phasing - Renovation Phase: Bestaand
Pset_ReinforcementBarPitchOfSlab - Reference: ø300 (schroef)
Component Quantities - WSP_beton - ihwg beton, Mass: 887.213 kg; WSP_beton - ihwg beton, Component Volume (Net): 0.385745 m3; WSP_beton - ihwg beton, Component Volume (Gross): 0.385745 m3

# IfcSlab: Slab 829, 17_WSP_FD_beton - fundatiepaal v21-2:ø300 (schroef):1507353
In: -2 fundering
Classification: Vloerplaat - fundering (ARCHICAD Classification); Material: WSP_beton - ihwg beton
Pset_SlabCommon - Reference: ø300 (schroef); IsExternal: yes; LoadBearing: no
Pset_ReinforcementBarPitchOfSlab - Reference: ø300 (schroef)
Component Quantities - WSP_beton - ihwg beton, Mass: 887.213 kg; WSP_beton - ihwg beton, Component Volume (Net): 0.385745 m3; WSP_beton - ihwg beton, Component Volume (Gross): 0.385745 m3
CPset_Phasing - Renovation Phase: Bestaand

# IfcSlab: Slab 83, 17_WSP_FD_beton - fundatiepaal v21-2:ø300 (schroef):1473591
In: -2 fundering
Classification: Vloerplaat - fundering (ARCHICAD Classification); Material: WSP_beton - ihwg beton
Pset_SlabCommon - Reference: ø300 (schroef); IsExternal: yes; LoadBearing: no
Pset_ReinforcementBarPitchOfSlab - Reference: ø300 (schroef)
CPset_Phasing - Renovation Phase: Bestaand
Component Quantities - WSP_beton - ihwg beton, Mass: 903.056 kg; WSP_beton - ihwg beton, Component Volume (Net): 0.392633 m3; WSP_beton - ihwg beton, Component Volume (Gross): 0.392633 m3

# IfcSlab: Slab 830, 17_WSP_FD_beton - fundatiepaal v21-2:ø300 (schroef):1507352
In: -2 fundering
Classification: Vloerplaat - fundering (ARCHICAD Classification); Material: WSP_beton - ihwg beton
Pset_ReinforcementBarPitchOfSlab - Reference: ø300 (schroef)
Pset_SlabCommon - Reference: ø300 (schroef); IsExternal: yes; LoadBearing: no
CPset_Phasing - Renovation Phase: Bestaand
Component Quantities - WSP_beton - ihwg beton, Mass: 887.213 kg; WSP_beton - ihwg beton, Component Volume (Net): 0.385745 m3; WSP_beton - ihwg beton, Component Volume (Gross): 0.385745 m3

# IfcSlab: Slab 831, 17_WSP_FD_beton - fundatiepaal v21-2:ø300 (schroef):1507351
In: -2 fundering
Classification: Vloerplaat - fundering (ARCHICAD Classification); Material: WSP_beton - ihwg beton
Pset_ReinforcementBarPitchOfSlab - Reference: ø300 (schroef)
Pset_SlabCommon - Reference: ø300 (schroef); IsExternal: yes; LoadBearing: no
CPset_Phasing - Renovation Phase: Bestaand
Component Quantities - WSP_beton - ihwg beton, Mass: 887.213 kg; WSP_beton - ihwg beton, Component Volume (Net): 0.385745 m3; WSP_beton - ihwg beton, Component Volume (Gross): 0.385745 m3

# IfcSlab: Slab 832, 17_WSP_FD_beton - fundatiepaal v21-2:ø300 (schroef):1507350
In: -2 fundering
Classification: Vloerplaat - fundering (ARCHICAD Classification); Material: WSP_beton - ihwg beton
Component Quantities - WSP_beton - ihwg beton, Mass: 887.213 kg; WSP_beton - ihwg beton, Component Volume (Net): 0.385745 m3; WSP_beton - ihwg beton, Component Volume (Gross): 0.385745 m3
Pset_SlabCommon - Reference: ø300 (schroef); IsExternal: yes; LoadBearing: no
CPset_Phasing - Renovation Phase: Bestaand
Pset_ReinforcementBarPitchOfSlab - Reference: ø300 (schroef)

# IfcSlab: Slab 833, 17_WSP_FD_beton - fundatiepaal v21-2:ø300 (schroef):1507349
In: -2 fundering
Classification: Vloerplaat - fundering (ARCHICAD Classification); Material: WSP_beton - ihwg beton
Pset_SlabCommon - Reference: ø300 (schroef); IsExternal: yes; LoadBearing: no
Pset_ReinforcementBarPitchOfSlab - Reference: ø300 (schroef)
CPset_Phasing - Renovation Phase: Bestaand
Component Quantities - WSP_beton - ihwg beton, Mass: 887.213 kg; WSP_beton - ihwg beton, Component Volume (Net): 0.385745 m3; WSP_beton - ihwg beton, Component Volume (Gross): 0.385745 m3

# IfcSlab: Slab 834, 17_WSP_FD_beton - fundatiepaal v21-2:ø300 (schroef):1507348
In: -2 fundering
Classification: Vloerplaat - fundering (ARCHICAD Classification); Material: WSP_beton - ihwg beton
Pset_SlabCommon - Reference: ø300 (schroef); IsExternal: yes; LoadBearing: no
CPset_Phasing - Renovation Phase: Bestaand
Pset_ReinforcementBarPitchOfSlab - Reference: ø300 (schroef)
Component Quantities - WSP_beton - ihwg beton, Mass: 887.213 kg; WSP_beton - ihwg beton, Component Volume (Net): 0.385745 m3; WSP_beton - ihwg beton, Component Volume (Gross): 0.385745 m3

# IfcSlab: Slab 835, 17_WSP_FD_beton - fundatiepaal v21-2:ø300 (schroef):1507347
In: -2 fundering
Classification: Vloerplaat - fundering (ARCHICAD Classification); Material: WSP_beton - ihwg beton
Pset_SlabCommon - Reference: ø300 (schroef); IsExternal: yes; LoadBearing: no
Pset_ReinforcementBarPitchOfSlab - Reference: ø300 (schroef)
Component Quantities - WSP_beton - ihwg beton, Mass: 887.213 kg; WSP_beton - ihwg beton, Component Volume (Net): 0.385745 m3; WSP_beton - ihwg beton, Component Volume (Gross): 0.385745 m3
CPset_Phasing - Renovation Phase: Bestaand

# IfcSlab: Slab 836, 17_WSP_FD_beton - fundatiepaal v21-2:ø300 (schroef):1507346
In: -2 fundering
Classification: Vloerplaat - fundering (ARCHICAD Classification); Material: WSP_beton - ihwg beton
Pset_ReinforcementBarPitchOfSlab - Reference: ø300 (schroef)
Pset_SlabCommon - Reference: ø300 (schroef); IsExternal: yes; LoadBearing: no
Component Quantities - WSP_beton - ihwg beton, Mass: 887.213 kg; WSP_beton - ihwg beton, Component Volume (Net): 0.385745 m3; WSP_beton - ihwg beton, Component Volume (Gross): 0.385745 m3
CPset_Phasing - Renovation Phase: Bestaand

# IfcSlab: Slab 837, 17_WSP_FD_beton - fundatiepaal v21-2:ø300 (schroef):1507345
In: -2 fundering
Classification: Vloerplaat - fundering (ARCHICAD Classification); Material: WSP_beton - ihwg beton
Pset_SlabCommon - Reference: ø300 (schroef); IsExternal: yes; LoadBearing: no
Pset_ReinforcementBarPitchOfSlab - Reference: ø300 (schroef)
CPset_Phasing - Renovation Phase: Bestaand
Component Quantities - WSP_beton - ihwg beton, Mass: 887.213 kg; WSP_beton - ihwg beton, Component Volume (Net): 0.385745 m3; WSP_beton - ihwg beton, Component Volume (Gross): 0.385745 m3

# IfcSlab: Slab 838, 17_WSP_FD_beton - fundatiepaal v21-2:ø300 (schroef):1509039
In: -2 fundering
Classification: Vloerplaat - fundering (ARCHICAD Classification); Material: WSP_beton - ihwg beton
Pset_SlabCommon - Reference: ø300 (schroef); IsExternal: yes; LoadBearing: no
CPset_Phasing - Renovation Phase: Bestaand
Pset_ReinforcementBarPitchOfSlab - Reference: ø300 (schroef)
Component Quantities - WSP_beton - ihwg beton, Mass: 903.056 kg; WSP_beton - ihwg beton, Component Volume (Net): 0.392633 m3; WSP_beton - ihwg beton, Component Volume (Gross): 0.392633 m3

# IfcSlab: Slab 839, 17_WSP_FD_beton - fundatiepaal v21-2:ø300 (schroef):1509038
In: -2 fundering
Classification: Vloerplaat - fundering (ARCHICAD Classification); Material: WSP_beton - ihwg beton
Pset_SlabCommon - Reference: ø300 (schroef); IsExternal: yes; LoadBearing: no
Pset_ReinforcementBarPitchOfSlab - Reference: ø300 (schroef)
CPset_Phasing - Renovation Phase: Bestaand
Component Quantities - WSP_beton - ihwg beton, Mass: 903.056 kg; WSP_beton - ihwg beton, Component Volume (Net): 0.392633 m3; WSP_beton - ihwg beton, Component Volume (Gross): 0.392633 m3

# IfcSlab: Slab 84, 17_WSP_FD_beton - fundatiepaal v21-2:ø300 (schroef):1473588
In: -2 fundering
Classification: Vloerplaat - fundering (ARCHICAD Classification); Material: WSP_beton - ihwg beton
Pset_SlabCommon - Reference: ø300 (schroef); IsExternal: yes; LoadBearing: no
Component Quantities - WSP_beton - ihwg beton, Mass: 903.056 kg; WSP_beton - ihwg beton, Component Volume (Net): 0.392633 m3; WSP_beton - ihwg beton, Component Volume (Gross): 0.392633 m3
CPset_Phasing - Renovation Phase: Bestaand
Pset_ReinforcementBarPitchOfSlab - Reference: ø300 (schroef)

# IfcSlab: Slab 840, 17_WSP_FD_beton - fundatiepaal v21-2:ø300 (schroef):1509037
In: -2 fundering
Classification: Vloerplaat - fundering (ARCHICAD Classification); Material: WSP_beton - ihwg beton
Pset_SlabCommon - Reference: ø300 (schroef); IsExternal: yes; LoadBearing: no
Pset_ReinforcementBarPitchOfSlab - Reference: ø300 (schroef)
CPset_Phasing - Renovation Phase: Bestaand
Component Quantities - WSP_beton - ihwg beton, Mass: 903.056 kg; WSP_beton - ihwg beton, Component Volume (Net): 0.392633 m3; WSP_beton - ihwg beton, Component Volume (Gross): 0.392633 m3

# IfcSlab: Slab 841, 17_WSP_FD_beton - fundatiepaal v21-2:ø300 (schroef):1509036
In: -2 fundering
Classification: Vloerplaat - fundering (ARCHICAD Classification); Material: WSP_beton - ihwg beton
Pset_SlabCommon - Reference: ø300 (schroef); IsExternal: yes; LoadBearing: no
Pset_ReinforcementBarPitchOfSlab - Reference: ø300 (schroef)
CPset_Phasing - Renovation Phase: Bestaand
Component Quantities - WSP_beton - ihwg beton, Mass: 903.056 kg; WSP_beton - ihwg beton, Component Volume (Net): 0.392633 m3; WSP_beton - ihwg beton, Component Volume (Gross): 0.392633 m3

# IfcSlab: Slab 842, 17_WSP_FD_beton - fundatiepaal v21-2:ø300 (schroef):1509035
In: -2 fundering
Classification: Vloerplaat - fundering (ARCHICAD Classification); Material: WSP_beton - ihwg beton
Pset_SlabCommon - Reference: ø300 (schroef); IsExternal: yes; LoadBearing: no
Pset_ReinforcementBarPitchOfSlab - Reference: ø300 (schroef)
Component Quantities - WSP_beton - ihwg beton, Mass: 887.213 kg; WSP_beton - ihwg beton, Component Volume (Net): 0.385745 m3; WSP_beton - ihwg beton, Component Volume (Gross): 0.385745 m3
CPset_Phasing - Renovation Phase: Bestaand

# IfcSlab: Slab 843, 17_WSP_FD_beton - fundatiepaal v21-2:ø300 (schroef):1509034
In: -2 fundering
Classification: Vloerplaat - fundering (ARCHICAD Classification); Material: WSP_beton - ihwg beton
Pset_ReinforcementBarPitchOfSlab - Reference: ø300 (schroef)
Pset_SlabCommon - Reference: ø300 (schroef); IsExternal: yes; LoadBearing: no
CPset_Phasing - Renovation Phase: Bestaand
Component Quantities - WSP_beton - ihwg beton, Mass: 887.213 kg; WSP_beton - ihwg beton, Component Volume (Net): 0.385745 m3; WSP_beton - ihwg beton, Component Volume (Gross): 0.385745 m3

# IfcSlab: Slab 844, 17_WSP_FD_beton - fundatiepaal v21-2:ø300 (schroef):1509033
In: -2 fundering
Classification: Vloerplaat - fundering (ARCHICAD Classification); Material: WSP_beton - ihwg beton
Pset_SlabCommon - Reference: ø300 (schroef); IsExternal: yes; LoadBearing: no
Pset_ReinforcementBarPitchOfSlab - Reference: ø300 (schroef)
CPset_Phasing - Renovation Phase: Bestaand
Component Quantities - WSP_beton - ihwg beton, Mass: 887.213 kg; WSP_beton - ihwg beton, Component Volume (Net): 0.385745 m3; WSP_beton - ihwg beton, Component Volume (Gross): 0.385745 m3

# IfcSlab: Slab 845, 17_WSP_FD_beton - fundatiepaal v21-2:ø300 (schroef):1509032
In: -2 fundering
Classification: Vloerplaat - fundering (ARCHICAD Classification); Material: WSP_beton - ihwg beton
Pset_SlabCommon - Reference: ø300 (schroef); IsExternal: yes; LoadBearing: no
Pset_ReinforcementBarPitchOfSlab - Reference: ø300 (schroef)
CPset_Phasing - Renovation Phase: Bestaand
Component Quantities - WSP_beton - ihwg beton, Mass: 887.213 kg; WSP_beton - ihwg beton, Component Volume (Net): 0.385745 m3; WSP_beton - ihwg beton, Component Volume (Gross): 0.385745 m3

# IfcSlab: Slab 846, 17_WSP_FD_beton - fundatiepaal v21-2:ø300 (schroef):1509031
In: -2 fundering
Classification: Vloerplaat - fundering (ARCHICAD Classification); Material: WSP_beton - ihwg beton
Pset_SlabCommon - Reference: ø300 (schroef); IsExternal: yes; LoadBearing: no
Pset_ReinforcementBarPitchOfSlab - Reference: ø300 (schroef)
Component Quantities - WSP_beton - ihwg beton, Mass: 903.056 kg; WSP_beton - ihwg beton, Component Volume (Net): 0.392633 m3; WSP_beton - ihwg beton, Component Volume (Gross): 0.392633 m3
CPset_Phasing - Renovation Phase: Bestaand

# IfcSlab: Slab 847, 17_WSP_FD_beton - fundatiepaal v21-2:ø300 (schroef):1509030
In: -2 fundering
Classification: Vloerplaat - fundering (ARCHICAD Classification); Material: WSP_beton - ihwg beton
Pset_SlabCommon - Reference: ø300 (schroef); IsExternal: yes; LoadBearing: no
Pset_ReinforcementBarPitchOfSlab - Reference: ø300 (schroef)
CPset_Phasing - Renovation Phase: Bestaand
Component Quantities - WSP_beton - ihwg beton, Mass: 903.056 kg; WSP_beton - ihwg beton, Component Volume (Net): 0.392633 m3; WSP_beton - ihwg beton, Component Volume (Gross): 0.392633 m3

# IfcSlab: Slab 848, 17_WSP_FD_beton - fundatiepaal v21-2:ø300 (schroef):1509029
In: -2 fundering
Classification: Vloerplaat - fundering (ARCHICAD Classification); Material: WSP_beton - ihwg beton
Pset_SlabCommon - Reference: ø300 (schroef); IsExternal: yes; LoadBearing: no
Pset_ReinforcementBarPitchOfSlab - Reference: ø300 (schroef)
Component Quantities - WSP_beton - ihwg beton, Mass: 903.056 kg; WSP_beton - ihwg beton, Component Volume (Net): 0.392633 m3; WSP_beton - ihwg beton, Component Volume (Gross): 0.392633 m3
CPset_Phasing - Renovation Phase: Bestaand

# IfcSlab: Slab 849, 17_WSP_FD_beton - fundatiepaal v21-2:ø300 (schroef):1509028
In: -2 fundering
Classification: Vloerplaat - fundering (ARCHICAD Classification); Material: WSP_beton - ihwg beton
Pset_SlabCommon - Reference: ø300 (schroef); IsExternal: yes; LoadBearing: no
Pset_ReinforcementBarPitchOfSlab - Reference: ø300 (schroef)
Component Quantities - WSP_beton - ihwg beton, Mass: 903.056 kg; WSP_beton - ihwg beton, Component Volume (Net): 0.392633 m3; WSP_beton - ihwg beton, Component Volume (Gross): 0.392633 m3
CPset_Phasing - Renovation Phase: Bestaand

# IfcSlab: Slab 85, 17_WSP_FD_beton - fundatiepaal v21-2:ø300 (schroef):1473589
In: -2 fundering
Classification: Vloerplaat - fundering (ARCHICAD Classification); Material: WSP_beton - ihwg beton
Pset_SlabCommon - Reference: ø300 (schroef); IsExternal: yes; LoadBearing: no
Pset_ReinforcementBarPitchOfSlab - Reference: ø300 (schroef)
CPset_Phasing - Renovation Phase: Bestaand
Component Quantities - WSP_beton - ihwg beton, Mass: 903.056 kg; WSP_beton - ihwg beton, Component Volume (Net): 0.392633 m3; WSP_beton - ihwg beton, Component Volume (Gross): 0.392633 m3

# IfcSlab: Slab 850, 17_WSP_FD_beton - fundatiepaal v21-2:ø300 (schroef):1509027
In: -2 fundering
Classification: Vloerplaat - fundering (ARCHICAD Classification); Material: WSP_beton - ihwg beton
Pset_SlabCommon - Reference: ø300 (schroef); IsExternal: yes; LoadBearing: no
Component Quantities - WSP_beton - ihwg beton, Mass: 903.056 kg; WSP_beton - ihwg beton, Component Volume (Net): 0.392633 m3; WSP_beton - ihwg beton, Component Volume (Gross): 0.392633 m3
Pset_ReinforcementBarPitchOfSlab - Reference: ø300 (schroef)
CPset_Phasing - Renovation Phase: Bestaand

# IfcSlab: Slab 851, 17_WSP_FD_beton - fundatiepaal v21-2:ø300 (schroef):1509026
In: -2 fundering
Classification: Vloerplaat - fundering (ARCHICAD Classification); Material: WSP_beton - ihwg beton
CPset_Phasing - Renovation Phase: Bestaand
Pset_SlabCommon - Reference: ø300 (schroef); IsExternal: yes; LoadBearing: no
Pset_ReinforcementBarPitchOfSlab - Reference: ø300 (schroef)
Component Quantities - WSP_beton - ihwg beton, Mass: 903.056 kg; WSP_beton - ihwg beton, Component Volume (Net): 0.392633 m3; WSP_beton - ihwg beton, Component Volume (Gross): 0.392633 m3

# IfcSlab: Slab 852, 17_WSP_FD_beton - fundatiepaal v21-2:ø300 (schroef):1509025
In: -2 fundering
Classification: Vloerplaat - fundering (ARCHICAD Classification); Material: WSP_beton - ihwg beton
Pset_SlabCommon - Reference: ø300 (schroef); IsExternal: yes; LoadBearing: no
Pset_ReinforcementBarPitchOfSlab - Reference: ø300 (schroef)
Component Quantities - WSP_beton - ihwg beton, Mass: 903.056 kg; WSP_beton - ihwg beton, Component Volume (Net): 0.392633 m3; WSP_beton - ihwg beton, Component Volume (Gross): 0.392633 m3
CPset_Phasing - Renovation Phase: Bestaand

# IfcSlab: Slab 853, 17_WSP_FD_beton - fundatiepaal v21-2:ø300 (schroef):1509024
In: -2 fundering
Classification: Vloerplaat - fundering (ARCHICAD Classification); Material: WSP_beton - ihwg beton
Pset_SlabCommon - Reference: ø300 (schroef); IsExternal: yes; LoadBearing: no
Component Quantities - WSP_beton - ihwg beton, Mass: 903.056 kg; WSP_beton - ihwg beton, Component Volume (Net): 0.392633 m3; WSP_beton - ihwg beton, Component Volume (Gross): 0.392633 m3
CPset_Phasing - Renovation Phase: Bestaand
Pset_ReinforcementBarPitchOfSlab - Reference: ø300 (schroef)

# IfcSlab: Slab 854, 17_WSP_FD_beton - fundatiepaal v21-2:ø300 (schroef):1509055
In: -2 fundering
Classification: Vloerplaat - fundering (ARCHICAD Classification); Material: WSP_beton - ihwg beton
Pset_ReinforcementBarPitchOfSlab - Reference: ø300 (schroef)
CPset_Phasing - Renovation Phase: Bestaand
Pset_SlabCommon - Reference: ø300 (schroef); IsExternal: yes; LoadBearing: no
Component Quantities - WSP_beton - ihwg beton, Mass: 903.056 kg; WSP_beton - ihwg beton, Component Volume (Net): 0.392633 m3; WSP_beton - ihwg beton, Component Volume (Gross): 0.392633 m3

# IfcSlab: Slab 855, 17_WSP_FD_beton - fundatiepaal v21-2:ø300 (schroef):1509054
In: -2 fundering
Classification: Vloerplaat - fundering (ARCHICAD Classification); Material: WSP_beton - ihwg beton
Pset_SlabCommon - Reference: ø300 (schroef); IsExternal: yes; LoadBearing: no
Pset_ReinforcementBarPitchOfSlab - Reference: ø300 (schroef)
Component Quantities - WSP_beton - ihwg beton, Mass: 903.056 kg; WSP_beton - ihwg beton, Component Volume (Net): 0.392633 m3; WSP_beton - ihwg beton, Component Volume (Gross): 0.392633 m3
CPset_Phasing - Renovation Phase: Bestaand

# IfcSlab: Slab 856, 17_WSP_FD_beton - fundatiepaal v21-2:ø300 (schroef):1509053
In: -2 fundering
Classification: Vloerplaat - fundering (ARCHICAD Classification); Material: WSP_beton - ihwg beton
Pset_ReinforcementBarPitchOfSlab - Reference: ø300 (schroef)
Pset_SlabCommon - Reference: ø300 (schroef); IsExternal: yes; LoadBearing: no
Component Quantities - WSP_beton - ihwg beton, Mass: 887.213 kg; WSP_beton - ihwg beton, Component Volume (Net): 0.385745 m3; WSP_beton - ihwg beton, Component Volume (Gross): 0.385745 m3
CPset_Phasing - Renovation Phase: Bestaand

# IfcSlab: Slab 857, 17_WSP_FD_beton - fundatiepaal v21-2:ø300 (schroef):1509052
In: -2 fundering
Classification: Vloerplaat - fundering (ARCHICAD Classification); Material: WSP_beton - ihwg beton
Pset_ReinforcementBarPitchOfSlab - Reference: ø300 (schroef)
Pset_SlabCommon - Reference: ø300 (schroef); IsExternal: yes; LoadBearing: no
Component Quantities - WSP_beton - ihwg beton, Mass: 887.213 kg; WSP_beton - ihwg beton, Component Volume (Net): 0.385745 m3; WSP_beton - ihwg beton, Component Volume (Gross): 0.385745 m3
CPset_Phasing - Renovation Phase: Bestaand

# IfcSlab: Slab 858, 17_WSP_FD_beton - fundatiepaal v21-2:ø300 (schroef):1509051
In: -2 fundering
Classification: Vloerplaat - fundering (ARCHICAD Classification); Material: WSP_beton - ihwg beton
Pset_SlabCommon - Reference: ø300 (schroef); IsExternal: yes; LoadBearing: no
Pset_ReinforcementBarPitchOfSlab - Reference: ø300 (schroef)
CPset_Phasing - Renovation Phase: Bestaand
Component Quantities - WSP_beton - ihwg beton, Mass: 887.213 kg; WSP_beton - ihwg beton, Component Volume (Net): 0.385745 m3; WSP_beton - ihwg beton, Component Volume (Gross): 0.385745 m3

# IfcSlab: Slab 859, 17_WSP_FD_beton - fundatiepaal v21-2:ø300 (schroef):1509050
In: -2 fundering
Classification: Vloerplaat - fundering (ARCHICAD Classification); Material: WSP_beton - ihwg beton
Pset_SlabCommon - Reference: ø300 (schroef); IsExternal: yes; LoadBearing: no
Pset_ReinforcementBarPitchOfSlab - Reference: ø300 (schroef)
Component Quantities - WSP_beton - ihwg beton, Mass: 887.213 kg; WSP_beton - ihwg beton, Component Volume (Net): 0.385745 m3; WSP_beton - ihwg beton, Component Volume (Gross): 0.385745 m3
CPset_Phasing - Renovation Phase: Bestaand

# IfcSlab: Slab 86, 17_WSP_FD_beton - fundatiepaal v21-2:ø300 (schroef):1473594
In: -2 fundering
Classification: Vloerplaat - fundering (ARCHICAD Classification); Material: WSP_beton - ihwg beton
Pset_SlabCommon - Reference: ø300 (schroef); IsExternal: yes; LoadBearing: no
CPset_Phasing - Renovation Phase: Bestaand
Component Quantities - WSP_beton - ihwg beton, Mass: 903.056 kg; WSP_beton - ihwg beton, Component Volume (Net): 0.392633 m3; WSP_beton - ihwg beton, Component Volume (Gross): 0.392633 m3
Pset_ReinforcementBarPitchOfSlab - Reference: ø300 (schroef)

# IfcSlab: Slab 860, 17_WSP_FD_beton - fundatiepaal v21-2:ø300 (schroef):1509049
In: -2 fundering
Classification: Vloerplaat - fundering (ARCHICAD Classification); Material: WSP_beton - ihwg beton
Pset_SlabCommon - Reference: ø300 (schroef); IsExternal: yes; LoadBearing: no
Pset_ReinforcementBarPitchOfSlab - Reference: ø300 (schroef)
CPset_Phasing - Renovation Phase: Bestaand
Component Quantities - WSP_beton - ihwg beton, Mass: 903.056 kg; WSP_beton - ihwg beton, Component Volume (Net): 0.392633 m3; WSP_beton - ihwg beton, Component Volume (Gross): 0.392633 m3

# IfcSlab: Slab 861, 17_WSP_FD_beton - fundatiepaal v21-2:ø300 (schroef):1509048
In: -2 fundering
Classification: Vloerplaat - fundering (ARCHICAD Classification); Material: WSP_beton - ihwg beton
CPset_Phasing - Renovation Phase: Bestaand
Pset_SlabCommon - Reference: ø300 (schroef); IsExternal: yes; LoadBearing: no
Pset_ReinforcementBarPitchOfSlab - Reference: ø300 (schroef)
Component Quantities - WSP_beton - ihwg beton, Mass: 903.056 kg; WSP_beton - ihwg beton, Component Volume (Net): 0.392633 m3; WSP_beton - ihwg beton, Component Volume (Gross): 0.392633 m3

# IfcSlab: Slab 862, 17_WSP_FD_beton - fundatiepaal v21-2:ø300 (schroef):1509047
In: -2 fundering
Classification: Vloerplaat - fundering (ARCHICAD Classification); Material: WSP_beton - ihwg beton
Pset_ReinforcementBarPitchOfSlab - Reference: ø300 (schroef)
CPset_Phasing - Renovation Phase: Bestaand
Pset_SlabCommon - Reference: ø300 (schroef); IsExternal: yes; LoadBearing: no
Component Quantities - WSP_beton - ihwg beton, Mass: 903.056 kg; WSP_beton - ihwg beton, Component Volume (Net): 0.392633 m3; WSP_beton - ihwg beton, Component Volume (Gross): 0.392633 m3

# IfcSlab: Slab 863, 17_WSP_FD_beton - fundatiepaal v21-2:ø300 (schroef):1509046
In: -2 fundering
Classification: Vloerplaat - fundering (ARCHICAD Classification); Material: WSP_beton - ihwg beton
Pset_SlabCommon - Reference: ø300 (schroef); IsExternal: yes; LoadBearing: no
Pset_ReinforcementBarPitchOfSlab - Reference: ø300 (schroef)
CPset_Phasing - Renovation Phase: Bestaand
Component Quantities - WSP_beton - ihwg beton, Mass: 903.056 kg; WSP_beton - ihwg beton, Component Volume (Net): 0.392633 m3; WSP_beton - ihwg beton, Component Volume (Gross): 0.392633 m3

# IfcSlab: Slab 864, 17_WSP_FD_beton - fundatiepaal v21-2:ø300 (schroef):1509045
In: -2 fundering
Classification: Vloerplaat - fundering (ARCHICAD Classification); Material: WSP_beton - ihwg beton
Pset_SlabCommon - Reference: ø300 (schroef); IsExternal: yes; LoadBearing: no
Pset_ReinforcementBarPitchOfSlab - Reference: ø300 (schroef)
CPset_Phasing - Renovation Phase: Bestaand
Component Quantities - WSP_beton - ihwg beton, Mass: 903.056 kg; WSP_beton - ihwg beton, Component Volume (Net): 0.392633 m3; WSP_beton - ihwg beton, Component Volume (Gross): 0.392633 m3

# IfcSlab: Slab 865, 17_WSP_FD_beton - fundatiepaal v21-2:ø300 (schroef):1509044
In: -2 fundering
Classification: Vloerplaat - fundering (ARCHICAD Classification); Material: WSP_beton - ihwg beton
CPset_Phasing - Renovation Phase: Bestaand
Component Quantities - WSP_beton - ihwg beton, Mass: 903.056 kg; WSP_beton - ihwg beton, Component Volume (Net): 0.392633 m3; WSP_beton - ihwg beton, Component Volume (Gross): 0.392633 m3
Pset_SlabCommon - Reference: ø300 (schroef); IsExternal: yes; LoadBearing: no
Pset_ReinforcementBarPitchOfSlab - Reference: ø300 (schroef)

# IfcSlab: Slab 866, 17_WSP_FD_beton - fundatiepaal v21-2:ø300 (schroef):1509043
In: -2 fundering
Classification: Vloerplaat - fundering (ARCHICAD Classification); Material: WSP_beton - ihwg beton
Pset_SlabCommon - Reference: ø300 (schroef); IsExternal: yes; LoadBearing: no
Pset_ReinforcementBarPitchOfSlab - Reference: ø300 (schroef)
CPset_Phasing - Renovation Phase: Bestaand
Component Quantities - WSP_beton - ihwg beton, Mass: 903.056 kg; WSP_beton - ihwg beton, Component Volume (Net): 0.392633 m3; WSP_beton - ihwg beton, Component Volume (Gross): 0.392633 m3

# IfcSlab: Slab 867, 17_WSP_FD_beton - fundatiepaal v21-2:ø300 (schroef):1509042
In: -2 fundering
Classification: Vloerplaat - fundering (ARCHICAD Classification); Material: WSP_beton - ihwg beton
Pset_SlabCommon - Reference: ø300 (schroef); IsExternal: yes; LoadBearing: no
Pset_ReinforcementBarPitchOfSlab - Reference: ø300 (schroef)
Component Quantities - WSP_beton - ihwg beton, Mass: 903.056 kg; WSP_beton - ihwg beton, Component Volume (Net): 0.392633 m3; WSP_beton - ihwg beton, Component Volume (Gross): 0.392633 m3
CPset_Phasing - Renovation Phase: Bestaand

# IfcSlab: Slab 868, 17_WSP_FD_beton - fundatiepaal v21-2:ø300 (schroef):1509041
In: -2 fundering
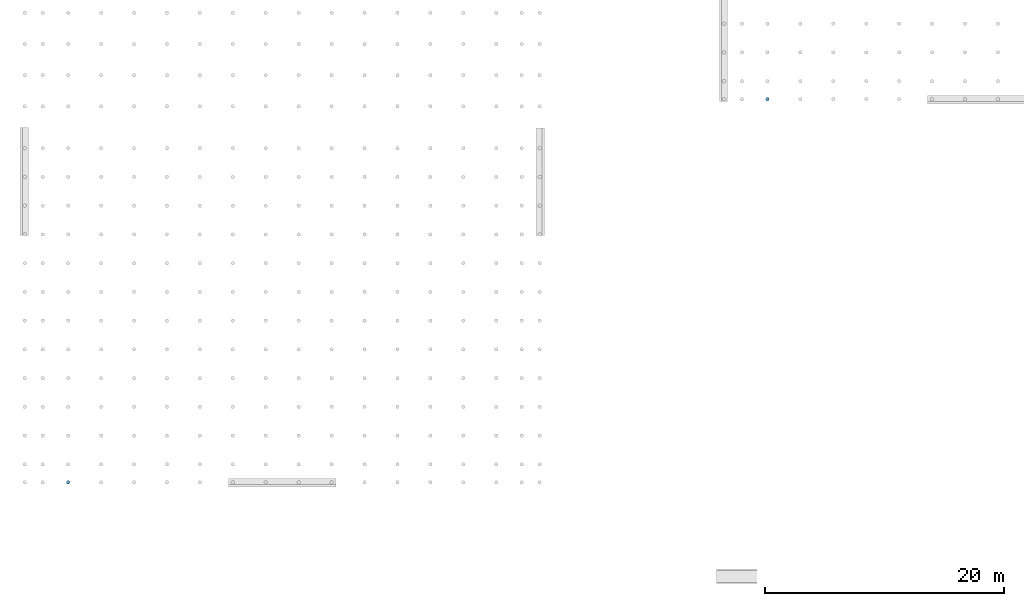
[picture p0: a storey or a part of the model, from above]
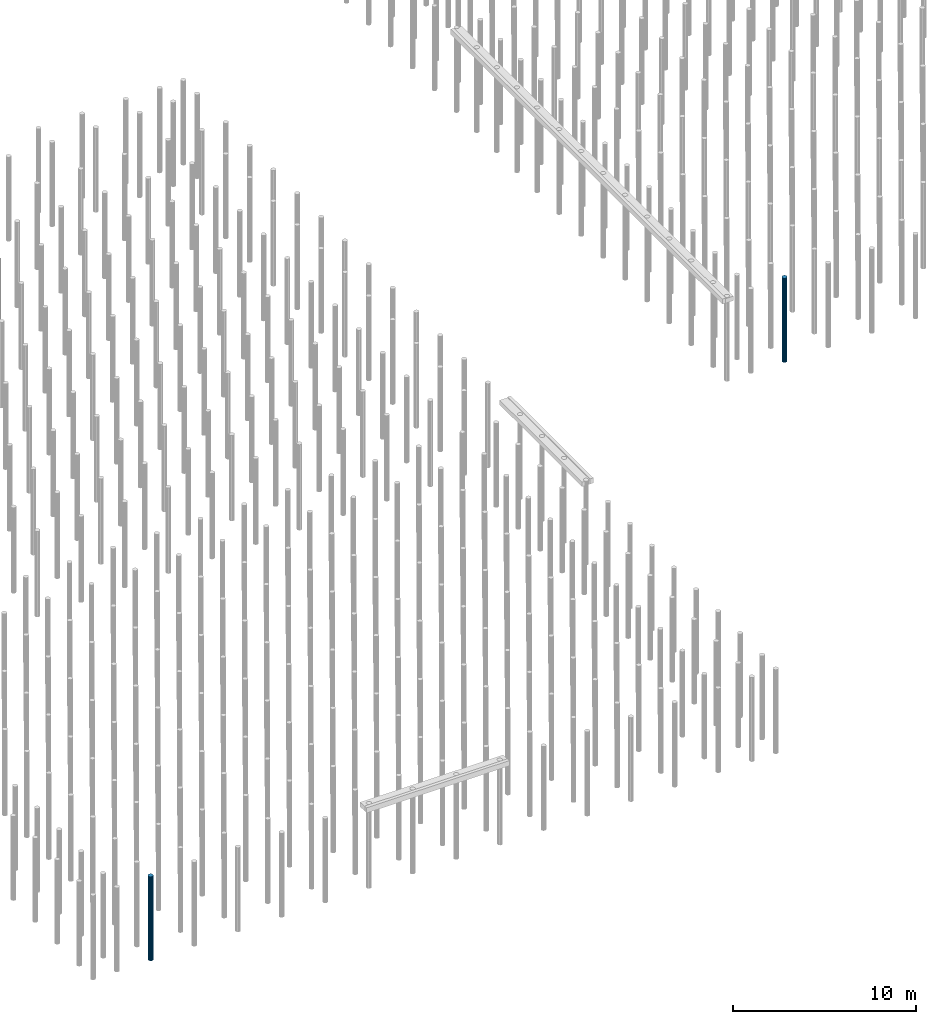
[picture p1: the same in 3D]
Properties of the parts of a building model (IFC2X3), part 11 of 13

# IfcSlab: Slab 868, 17_WSP_FD_beton - fundatiepaal v21-2:ø300 (schroef):1509041
Classification: Vloerplaat - fundering (ARCHICAD Classification); Material: WSP_beton - ihwg beton
Pset_SlabCommon - Reference: ø300 (schroef); IsExternal: yes; LoadBearing: no
CPset_Phasing - Renovation Phase: Bestaand
Component Quantities - WSP_beton - ihwg beton, Mass: 903.056 kg; WSP_beton - ihwg beton, Component Volume (Net): 0.392633 m3; WSP_beton - ihwg beton, Component Volume (Gross): 0.392633 m3
Pset_ReinforcementBarPitchOfSlab - Reference: ø300 (schroef)

# IfcSlab: Slab 869, 17_WSP_FD_beton - fundatiepaal v21-2:ø300 (schroef):1509040
In: -2 fundering
Classification: Vloerplaat - fundering (ARCHICAD Classification); Material: WSP_beton - ihwg beton
Pset_ReinforcementBarPitchOfSlab - Reference: ø300 (schroef)
Pset_SlabCommon - Reference: ø300 (schroef); IsExternal: yes; LoadBearing: no
CPset_Phasing - Renovation Phase: Bestaand
Component Quantities - WSP_beton - ihwg beton, Mass: 903.056 kg; WSP_beton - ihwg beton, Component Volume (Net): 0.392633 m3; WSP_beton - ihwg beton, Component Volume (Gross): 0.392633 m3

# IfcSlab: Slab 87, 17_WSP_FD_beton - fundatiepaal v21-2:ø300 (schroef):1473595
In: -2 fundering
Classification: Vloerplaat - fundering (ARCHICAD Classification); Material: WSP_beton - ihwg beton
Pset_SlabCommon - Reference: ø300 (schroef); IsExternal: yes; LoadBearing: no
CPset_Phasing - Renovation Phase: Bestaand
Pset_ReinforcementBarPitchOfSlab - Reference: ø300 (schroef)
Component Quantities - WSP_beton - ihwg beton, Mass: 903.056 kg; WSP_beton - ihwg beton, Component Volume (Net): 0.392633 m3; WSP_beton - ihwg beton, Component Volume (Gross): 0.392633 m3

# IfcSlab: Slab 870, 17_WSP_FD_beton - fundatiepaal v21-2:ø300 (schroef):1509023
In: -2 fundering
Classification: Vloerplaat - fundering (ARCHICAD Classification); Material: WSP_beton - ihwg beton
Pset_SlabCommon - Reference: ø300 (schroef); IsExternal: yes; LoadBearing: no
Component Quantities - WSP_beton - ihwg beton, Mass: 903.056 kg; WSP_beton - ihwg beton, Component Volume (Net): 0.392633 m3; WSP_beton - ihwg beton, Component Volume (Gross): 0.392633 m3
Pset_ReinforcementBarPitchOfSlab - Reference: ø300 (schroef)
CPset_Phasing - Renovation Phase: Bestaand

# IfcSlab: Slab 871, 17_WSP_FD_beton - fundatiepaal v21-2:ø300 (schroef):1509022
In: -2 fundering
Classification: Vloerplaat - fundering (ARCHICAD Classification); Material: WSP_beton - ihwg beton
Pset_SlabCommon - Reference: ø300 (schroef); IsExternal: yes; LoadBearing: no
Pset_ReinforcementBarPitchOfSlab - Reference: ø300 (schroef)
CPset_Phasing - Renovation Phase: Bestaand
Component Quantities - WSP_beton - ihwg beton, Mass: 903.056 kg; WSP_beton - ihwg beton, Component Volume (Net): 0.392633 m3; WSP_beton - ihwg beton, Component Volume (Gross): 0.392633 m3

# IfcSlab: Slab 872, 17_WSP_FD_beton - fundatiepaal v21-2:ø300 (schroef):1509021
In: -2 fundering
Classification: Vloerplaat - fundering (ARCHICAD Classification); Material: WSP_beton - ihwg beton
Pset_ReinforcementBarPitchOfSlab - Reference: ø300 (schroef)
Pset_SlabCommon - Reference: ø300 (schroef); IsExternal: yes; LoadBearing: no
Component Quantities - WSP_beton - ihwg beton, Mass: 903.056 kg; WSP_beton - ihwg beton, Component Volume (Net): 0.392633 m3; WSP_beton - ihwg beton, Component Volume (Gross): 0.392633 m3
CPset_Phasing - Renovation Phase: Bestaand

# IfcSlab: Slab 873, 17_WSP_FD_beton - fundatiepaal v21-2:ø300 (schroef):1509020
In: -2 fundering
Classification: Vloerplaat - fundering (ARCHICAD Classification); Material: WSP_beton - ihwg beton
Pset_ReinforcementBarPitchOfSlab - Reference: ø300 (schroef)
Pset_SlabCommon - Reference: ø300 (schroef); IsExternal: yes; LoadBearing: no
CPset_Phasing - Renovation Phase: Bestaand
Component Quantities - WSP_beton - ihwg beton, Mass: 903.056 kg; WSP_beton - ihwg beton, Component Volume (Net): 0.392633 m3; WSP_beton - ihwg beton, Component Volume (Gross): 0.392633 m3

# IfcSlab: Slab 874, 17_WSP_FD_beton - fundatiepaal v21-2:ø300 (schroef):1509019
In: -2 fundering
Classification: Vloerplaat - fundering (ARCHICAD Classification); Material: WSP_beton - ihwg beton
Pset_SlabCommon - Reference: ø300 (schroef); IsExternal: yes; LoadBearing: no
Pset_ReinforcementBarPitchOfSlab - Reference: ø300 (schroef)
Component Quantities - WSP_beton - ihwg beton, Mass: 903.056 kg; WSP_beton - ihwg beton, Component Volume (Net): 0.392633 m3; WSP_beton - ihwg beton, Component Volume (Gross): 0.392633 m3
CPset_Phasing - Renovation Phase: Bestaand

# IfcSlab: Slab 875, 17_WSP_FD_beton - fundatiepaal v21-2:ø300 (schroef):1509018
In: -2 fundering
Classification: Vloerplaat - fundering (ARCHICAD Classification); Material: WSP_beton - ihwg beton
Pset_ReinforcementBarPitchOfSlab - Reference: ø300 (schroef)
Pset_SlabCommon - Reference: ø300 (schroef); IsExternal: yes; LoadBearing: no
CPset_Phasing - Renovation Phase: Bestaand
Component Quantities - WSP_beton - ihwg beton, Mass: 903.056 kg; WSP_beton - ihwg beton, Component Volume (Net): 0.392633 m3; WSP_beton - ihwg beton, Component Volume (Gross): 0.392633 m3

# IfcSlab: Slab 876, 17_WSP_FD_beton - fundatiepaal v21-2:ø300 (schroef):1509017
In: -2 fundering
Classification: Vloerplaat - fundering (ARCHICAD Classification); Material: WSP_beton - ihwg beton
Pset_SlabCommon - Reference: ø300 (schroef); IsExternal: yes; LoadBearing: no
Pset_ReinforcementBarPitchOfSlab - Reference: ø300 (schroef)
CPset_Phasing - Renovation Phase: Bestaand
Component Quantities - WSP_beton - ihwg beton, Mass: 887.213 kg; WSP_beton - ihwg beton, Component Volume (Net): 0.385745 m3; WSP_beton - ihwg beton, Component Volume (Gross): 0.385745 m3

# IfcSlab: Slab 877, 17_WSP_FD_beton - fundatiepaal v21-2:ø300 (schroef):1509016
In: -2 fundering
Classification: Vloerplaat - fundering (ARCHICAD Classification); Material: WSP_beton - ihwg beton
Pset_SlabCommon - Reference: ø300 (schroef); IsExternal: yes; LoadBearing: no
Pset_ReinforcementBarPitchOfSlab - Reference: ø300 (schroef)
CPset_Phasing - Renovation Phase: Bestaand
Component Quantities - WSP_beton - ihwg beton, Mass: 887.213 kg; WSP_beton - ihwg beton, Component Volume (Net): 0.385745 m3; WSP_beton - ihwg beton, Component Volume (Gross): 0.385745 m3

# IfcSlab: Slab 878, 17_WSP_FD_beton - fundatiepaal v21-2:ø300 (schroef):1509015
In: -2 fundering
Classification: Vloerplaat - fundering (ARCHICAD Classification); Material: WSP_beton - ihwg beton
Pset_SlabCommon - Reference: ø300 (schroef); IsExternal: yes; LoadBearing: no
CPset_Phasing - Renovation Phase: Bestaand
Pset_ReinforcementBarPitchOfSlab - Reference: ø300 (schroef)
Component Quantities - WSP_beton - ihwg beton, Mass: 887.213 kg; WSP_beton - ihwg beton, Component Volume (Net): 0.385745 m3; WSP_beton - ihwg beton, Component Volume (Gross): 0.385745 m3

# IfcSlab: Slab 879, 17_WSP_FD_beton - fundatiepaal v21-2:ø300 (schroef):1509103
In: -2 fundering
Classification: Vloerplaat - fundering (ARCHICAD Classification); Material: WSP_beton - ihwg beton
Pset_SlabCommon - Reference: ø300 (schroef); IsExternal: yes; LoadBearing: no
Pset_ReinforcementBarPitchOfSlab - Reference: ø300 (schroef)
Component Quantities - WSP_beton - ihwg beton, Mass: 903.056 kg; WSP_beton - ihwg beton, Component Volume (Net): 0.392633 m3; WSP_beton - ihwg beton, Component Volume (Gross): 0.392633 m3
CPset_Phasing - Renovation Phase: Bestaand

# IfcSlab: Slab 88, 17_WSP_FD_beton - fundatiepaal v21-2:ø300 (schroef):1473592
In: -2 fundering
Classification: Vloerplaat - fundering (ARCHICAD Classification); Material: WSP_beton - ihwg beton
CPset_Phasing - Renovation Phase: Bestaand
Pset_ReinforcementBarPitchOfSlab - Reference: ø300 (schroef)
Component Quantities - WSP_beton - ihwg beton, Mass: 903.056 kg; WSP_beton - ihwg beton, Component Volume (Net): 0.392633 m3; WSP_beton - ihwg beton, Component Volume (Gross): 0.392633 m3
Pset_SlabCommon - Reference: ø300 (schroef); IsExternal: yes; LoadBearing: no

# IfcSlab: Slab 880, 17_WSP_FD_beton - fundatiepaal v21-2:ø300 (schroef):1509102
In: -2 fundering
Classification: Vloerplaat - fundering (ARCHICAD Classification); Material: WSP_beton - ihwg beton
Pset_SlabCommon - Reference: ø300 (schroef); IsExternal: yes; LoadBearing: no
CPset_Phasing - Renovation Phase: Bestaand
Pset_ReinforcementBarPitchOfSlab - Reference: ø300 (schroef)
Component Quantities - WSP_beton - ihwg beton, Mass: 903.056 kg; WSP_beton - ihwg beton, Component Volume (Net): 0.392633 m3; WSP_beton - ihwg beton, Component Volume (Gross): 0.392633 m3

# IfcSlab: Slab 881, 17_WSP_FD_beton - fundatiepaal v21-2:ø300 (schroef):1509101
In: -2 fundering
Classification: Vloerplaat - fundering (ARCHICAD Classification); Material: WSP_beton - ihwg beton
Pset_ReinforcementBarPitchOfSlab - Reference: ø300 (schroef)
Component Quantities - WSP_beton - ihwg beton, Mass: 903.056 kg; WSP_beton - ihwg beton, Component Volume (Net): 0.392633 m3; WSP_beton - ihwg beton, Component Volume (Gross): 0.392633 m3
CPset_Phasing - Renovation Phase: Bestaand
Pset_SlabCommon - Reference: ø300 (schroef); IsExternal: yes; LoadBearing: no

# IfcSlab: Slab 882, 17_WSP_FD_beton - fundatiepaal v21-2:ø300 (schroef):1509100
In: -2 fundering
Classification: Vloerplaat - fundering (ARCHICAD Classification); Material: WSP_beton - ihwg beton
Pset_ReinforcementBarPitchOfSlab - Reference: ø300 (schroef)
Pset_SlabCommon - Reference: ø300 (schroef); IsExternal: yes; LoadBearing: no
CPset_Phasing - Renovation Phase: Bestaand
Component Quantities - WSP_beton - ihwg beton, Mass: 903.056 kg; WSP_beton - ihwg beton, Component Volume (Net): 0.392633 m3; WSP_beton - ihwg beton, Component Volume (Gross): 0.392633 m3

# IfcSlab: Slab 883, 17_WSP_FD_beton - fundatiepaal v21-2:ø300 (schroef):1509099
In: -2 fundering
Classification: Vloerplaat - fundering (ARCHICAD Classification); Material: WSP_beton - ihwg beton
Pset_SlabCommon - Reference: ø300 (schroef); IsExternal: yes; LoadBearing: no
Component Quantities - WSP_beton - ihwg beton, Mass: 903.056 kg; WSP_beton - ihwg beton, Component Volume (Net): 0.392633 m3; WSP_beton - ihwg beton, Component Volume (Gross): 0.392633 m3
Pset_ReinforcementBarPitchOfSlab - Reference: ø300 (schroef)
CPset_Phasing - Renovation Phase: Bestaand

# IfcSlab: Slab 884, 17_WSP_FD_beton - fundatiepaal v21-2:ø300 (schroef):1509098
In: -2 fundering
Classification: Vloerplaat - fundering (ARCHICAD Classification); Material: WSP_beton - ihwg beton
Pset_ReinforcementBarPitchOfSlab - Reference: ø300 (schroef)
Pset_SlabCommon - Reference: ø300 (schroef); IsExternal: yes; LoadBearing: no
Component Quantities - WSP_beton - ihwg beton, Mass: 903.056 kg; WSP_beton - ihwg beton, Component Volume (Net): 0.392633 m3; WSP_beton - ihwg beton, Component Volume (Gross): 0.392633 m3
CPset_Phasing - Renovation Phase: Bestaand

# IfcSlab: Slab 885, 17_WSP_FD_beton - fundatiepaal v21-2:ø300 (schroef):1509097
In: -2 fundering
Classification: Vloerplaat - fundering (ARCHICAD Classification); Material: WSP_beton - ihwg beton
Pset_SlabCommon - Reference: ø300 (schroef); IsExternal: yes; LoadBearing: no
Pset_ReinforcementBarPitchOfSlab - Reference: ø300 (schroef)
Component Quantities - WSP_beton - ihwg beton, Mass: 903.056 kg; WSP_beton - ihwg beton, Component Volume (Net): 0.392633 m3; WSP_beton - ihwg beton, Component Volume (Gross): 0.392633 m3
CPset_Phasing - Renovation Phase: Bestaand

# IfcSlab: Slab 886, 17_WSP_FD_beton - fundatiepaal v21-2:ø300 (schroef):1509096
In: -2 fundering
Classification: Vloerplaat - fundering (ARCHICAD Classification); Material: WSP_beton - ihwg beton
Pset_SlabCommon - Reference: ø300 (schroef); IsExternal: yes; LoadBearing: no
Pset_ReinforcementBarPitchOfSlab - Reference: ø300 (schroef)
CPset_Phasing - Renovation Phase: Bestaand
Component Quantities - WSP_beton - ihwg beton, Mass: 903.056 kg; WSP_beton - ihwg beton, Component Volume (Net): 0.392633 m3; WSP_beton - ihwg beton, Component Volume (Gross): 0.392633 m3

# IfcSlab: Slab 887, 17_WSP_FD_beton - fundatiepaal v21-2:ø300 (schroef):1509095
In: -2 fundering
Classification: Vloerplaat - fundering (ARCHICAD Classification); Material: WSP_beton - ihwg beton
Pset_SlabCommon - Reference: ø300 (schroef); IsExternal: yes; LoadBearing: no
Pset_ReinforcementBarPitchOfSlab - Reference: ø300 (schroef)
CPset_Phasing - Renovation Phase: Bestaand
Component Quantities - WSP_beton - ihwg beton, Mass: 903.056 kg; WSP_beton - ihwg beton, Component Volume (Net): 0.392633 m3; WSP_beton - ihwg beton, Component Volume (Gross): 0.392633 m3

# IfcSlab: Slab 888, 17_WSP_FD_beton - fundatiepaal v21-2:ø300 (schroef):1509094
In: -2 fundering
Classification: Vloerplaat - fundering (ARCHICAD Classification); Material: WSP_beton - ihwg beton
Pset_SlabCommon - Reference: ø300 (schroef); IsExternal: yes; LoadBearing: no
Pset_ReinforcementBarPitchOfSlab - Reference: ø300 (schroef)
CPset_Phasing - Renovation Phase: Bestaand
Component Quantities - WSP_beton - ihwg beton, Mass: 903.056 kg; WSP_beton - ihwg beton, Component Volume (Net): 0.392633 m3; WSP_beton - ihwg beton, Component Volume (Gross): 0.392633 m3

# IfcSlab: Slab 889, 17_WSP_FD_beton - fundatiepaal v21-2:ø300 (schroef):1509093
In: -2 fundering
Classification: Vloerplaat - fundering (ARCHICAD Classification); Material: WSP_beton - ihwg beton
Component Quantities - WSP_beton - ihwg beton, Mass: 903.056 kg; WSP_beton - ihwg beton, Component Volume (Net): 0.392633 m3; WSP_beton - ihwg beton, Component Volume (Gross): 0.392633 m3
CPset_Phasing - Renovation Phase: Bestaand
Pset_ReinforcementBarPitchOfSlab - Reference: ø300 (schroef)
Pset_SlabCommon - Reference: ø300 (schroef); IsExternal: yes; LoadBearing: no

# IfcSlab: Slab 89, 17_WSP_FD_beton - fundatiepaal v21-2:ø300 (schroef):1473593
In: -2 fundering
Classification: Vloerplaat - fundering (ARCHICAD Classification); Material: WSP_beton - ihwg beton
Pset_SlabCommon - Reference: ø300 (schroef); IsExternal: yes; LoadBearing: no
Pset_ReinforcementBarPitchOfSlab - Reference: ø300 (schroef)
CPset_Phasing - Renovation Phase: Bestaand
Component Quantities - WSP_beton - ihwg beton, Mass: 903.056 kg; WSP_beton - ihwg beton, Component Volume (Net): 0.392633 m3; WSP_beton - ihwg beton, Component Volume (Gross): 0.392633 m3

# IfcSlab: Slab 890, 17_WSP_FD_beton - fundatiepaal v21-2:ø300 (schroef):1509092
In: -2 fundering
Classification: Vloerplaat - fundering (ARCHICAD Classification); Material: WSP_beton - ihwg beton
Pset_ReinforcementBarPitchOfSlab - Reference: ø300 (schroef)
CPset_Phasing - Renovation Phase: Bestaand
Pset_SlabCommon - Reference: ø300 (schroef); IsExternal: yes; LoadBearing: no
Component Quantities - WSP_beton - ihwg beton, Mass: 903.056 kg; WSP_beton - ihwg beton, Component Volume (Net): 0.392633 m3; WSP_beton - ihwg beton, Component Volume (Gross): 0.392633 m3

# IfcSlab: Slab 891, 17_WSP_FD_beton - fundatiepaal v21-2:ø300 (schroef):1509091
In: -2 fundering
Classification: Vloerplaat - fundering (ARCHICAD Classification); Material: WSP_beton - ihwg beton
Pset_SlabCommon - Reference: ø300 (schroef); IsExternal: yes; LoadBearing: no
Pset_ReinforcementBarPitchOfSlab - Reference: ø300 (schroef)
Component Quantities - WSP_beton - ihwg beton, Mass: 903.056 kg; WSP_beton - ihwg beton, Component Volume (Net): 0.392633 m3; WSP_beton - ihwg beton, Component Volume (Gross): 0.392633 m3
CPset_Phasing - Renovation Phase: Bestaand

# IfcSlab: Slab 892, 17_WSP_FD_beton - fundatiepaal v21-2:ø300 (schroef):1509090
In: -2 fundering
Classification: Vloerplaat - fundering (ARCHICAD Classification); Material: WSP_beton - ihwg beton
Pset_ReinforcementBarPitchOfSlab - Reference: ø300 (schroef)
Pset_SlabCommon - Reference: ø300 (schroef); IsExternal: yes; LoadBearing: no
Component Quantities - WSP_beton - ihwg beton, Mass: 903.056 kg; WSP_beton - ihwg beton, Component Volume (Net): 0.392633 m3; WSP_beton - ihwg beton, Component Volume (Gross): 0.392633 m3
CPset_Phasing - Renovation Phase: Bestaand

# IfcSlab: Slab 893, 17_WSP_FD_beton - fundatiepaal v21-2:ø300 (schroef):1509089
In: -2 fundering
Classification: Vloerplaat - fundering (ARCHICAD Classification); Material: WSP_beton - ihwg beton
Pset_ReinforcementBarPitchOfSlab - Reference: ø300 (schroef)
Component Quantities - WSP_beton - ihwg beton, Mass: 887.213 kg; WSP_beton - ihwg beton, Component Volume (Net): 0.385745 m3; WSP_beton - ihwg beton, Component Volume (Gross): 0.385745 m3
CPset_Phasing - Renovation Phase: Bestaand
Pset_SlabCommon - Reference: ø300 (schroef); IsExternal: yes; LoadBearing: no

# IfcSlab: Slab 894, 17_WSP_FD_beton - fundatiepaal v21-2:ø300 (schroef):1509088
In: -2 fundering
Classification: Vloerplaat - fundering (ARCHICAD Classification); Material: WSP_beton - ihwg beton
Pset_SlabCommon - Reference: ø300 (schroef); IsExternal: yes; LoadBearing: no
CPset_Phasing - Renovation Phase: Bestaand
Pset_ReinforcementBarPitchOfSlab - Reference: ø300 (schroef)
Component Quantities - WSP_beton - ihwg beton, Mass: 887.213 kg; WSP_beton - ihwg beton, Component Volume (Net): 0.385745 m3; WSP_beton - ihwg beton, Component Volume (Gross): 0.385745 m3

# IfcSlab: Slab 895, 17_WSP_FD_beton - fundatiepaal v21-2:ø300 (schroef):1509104
In: -2 fundering
Classification: Vloerplaat - fundering (ARCHICAD Classification); Material: WSP_beton - ihwg beton
Pset_SlabCommon - Reference: ø300 (schroef); IsExternal: yes; LoadBearing: no
Pset_ReinforcementBarPitchOfSlab - Reference: ø300 (schroef)
CPset_Phasing - Renovation Phase: Bestaand
Component Quantities - WSP_beton - ihwg beton, Mass: 887.213 kg; WSP_beton - ihwg beton, Component Volume (Net): 0.385745 m3; WSP_beton - ihwg beton, Component Volume (Gross): 0.385745 m3

# IfcSlab: Slab 896, 17_WSP_FD_beton - fundatiepaal v21-2:ø300 (schroef):1509071
In: -2 fundering
Classification: Vloerplaat - fundering (ARCHICAD Classification); Material: WSP_beton - ihwg beton
Pset_ReinforcementBarPitchOfSlab - Reference: ø300 (schroef)
Pset_SlabCommon - Reference: ø300 (schroef); IsExternal: yes; LoadBearing: no
CPset_Phasing - Renovation Phase: Bestaand
Component Quantities - WSP_beton - ihwg beton, Mass: 887.213 kg; WSP_beton - ihwg beton, Component Volume (Net): 0.385745 m3; WSP_beton - ihwg beton, Component Volume (Gross): 0.385745 m3

# IfcSlab: Slab 897, 17_WSP_FD_beton - fundatiepaal v21-2:ø300 (schroef):1509070
In: -2 fundering
Classification: Vloerplaat - fundering (ARCHICAD Classification); Material: WSP_beton - ihwg beton
Pset_ReinforcementBarPitchOfSlab - Reference: ø300 (schroef)
CPset_Phasing - Renovation Phase: Bestaand
Component Quantities - WSP_beton - ihwg beton, Mass: 887.213 kg; WSP_beton - ihwg beton, Component Volume (Net): 0.385745 m3; WSP_beton - ihwg beton, Component Volume (Gross): 0.385745 m3
Pset_SlabCommon - Reference: ø300 (schroef); IsExternal: yes; LoadBearing: no

# IfcSlab: Slab 898, 17_WSP_FD_beton - fundatiepaal v21-2:ø300 (schroef):1509069
In: -2 fundering
Classification: Vloerplaat - fundering (ARCHICAD Classification); Material: WSP_beton - ihwg beton
Pset_SlabCommon - Reference: ø300 (schroef); IsExternal: yes; LoadBearing: no
Pset_ReinforcementBarPitchOfSlab - Reference: ø300 (schroef)
Component Quantities - WSP_beton - ihwg beton, Mass: 887.213 kg; WSP_beton - ihwg beton, Component Volume (Net): 0.385745 m3; WSP_beton - ihwg beton, Component Volume (Gross): 0.385745 m3
CPset_Phasing - Renovation Phase: Bestaand

# IfcSlab: Slab 899, 17_WSP_FD_beton - fundatiepaal v21-2:ø300 (schroef):1509068
In: -2 fundering
Classification: Vloerplaat - fundering (ARCHICAD Classification); Material: WSP_beton - ihwg beton
CPset_Phasing - Renovation Phase: Bestaand
Pset_SlabCommon - Reference: ø300 (schroef); IsExternal: yes; LoadBearing: no
Pset_ReinforcementBarPitchOfSlab - Reference: ø300 (schroef)
Component Quantities - WSP_beton - ihwg beton, Mass: 887.213 kg; WSP_beton - ihwg beton, Component Volume (Net): 0.385745 m3; WSP_beton - ihwg beton, Component Volume (Gross): 0.385745 m3

# IfcSlab: Slab 9, 17_WSP_FD_beton - fundatiepaal v21-2:ø300 (schroef):1528054
In: -2 fundering
Classification: Vloerplaat - fundering (ARCHICAD Classification); Material: WSP_beton - ihwg beton
Pset_SlabCommon - Reference: ø300 (schroef); IsExternal: yes; LoadBearing: no
Pset_ReinforcementBarPitchOfSlab - Reference: ø300 (schroef)
Component Quantities - WSP_beton - ihwg beton, Mass: 903.056 kg; WSP_beton - ihwg beton, Component Volume (Net): 0.392633 m3; WSP_beton - ihwg beton, Component Volume (Gross): 0.392633 m3
CPset_Phasing - Renovation Phase: Bestaand

# IfcSlab: Slab 90, 17_WSP_FD_beton - fundatiepaal v21-2:ø300 (schroef):1473598
In: -2 fundering
Classification: Vloerplaat - fundering (ARCHICAD Classification); Material: WSP_beton - ihwg beton
Component Quantities - WSP_beton - ihwg beton, Mass: 903.056 kg; WSP_beton - ihwg beton, Component Volume (Net): 0.392633 m3; WSP_beton - ihwg beton, Component Volume (Gross): 0.392633 m3
CPset_Phasing - Renovation Phase: Bestaand
Pset_ReinforcementBarPitchOfSlab - Reference: ø300 (schroef)
Pset_SlabCommon - Reference: ø300 (schroef); IsExternal: yes; LoadBearing: no

# IfcSlab: Slab 900, 17_WSP_FD_beton - fundatiepaal v21-2:ø300 (schroef):1509067
In: -2 fundering
Classification: Vloerplaat - fundering (ARCHICAD Classification); Material: WSP_beton - ihwg beton
Pset_SlabCommon - Reference: ø300 (schroef); IsExternal: yes; LoadBearing: no
CPset_Phasing - Renovation Phase: Bestaand
Pset_ReinforcementBarPitchOfSlab - Reference: ø300 (schroef)
Component Quantities - WSP_beton - ihwg beton, Mass: 903.056 kg; WSP_beton - ihwg beton, Component Volume (Net): 0.392633 m3; WSP_beton - ihwg beton, Component Volume (Gross): 0.392633 m3

# IfcSlab: Slab 901, 17_WSP_FD_beton - fundatiepaal v21-2:ø300 (schroef):1509066
In: -2 fundering
Classification: Vloerplaat - fundering (ARCHICAD Classification); Material: WSP_beton - ihwg beton
Pset_SlabCommon - Reference: ø300 (schroef); IsExternal: yes; LoadBearing: no
Pset_ReinforcementBarPitchOfSlab - Reference: ø300 (schroef)
Component Quantities - WSP_beton - ihwg beton, Mass: 903.056 kg; WSP_beton - ihwg beton, Component Volume (Net): 0.392633 m3; WSP_beton - ihwg beton, Component Volume (Gross): 0.392633 m3
CPset_Phasing - Renovation Phase: Bestaand

# IfcSlab: Slab 902, 17_WSP_FD_beton - fundatiepaal v21-2:ø300 (schroef):1509065
In: -2 fundering
Classification: Vloerplaat - fundering (ARCHICAD Classification); Material: WSP_beton - ihwg beton
Pset_SlabCommon - Reference: ø300 (schroef); IsExternal: yes; LoadBearing: no
Pset_ReinforcementBarPitchOfSlab - Reference: ø300 (schroef)
CPset_Phasing - Renovation Phase: Bestaand
Component Quantities - WSP_beton - ihwg beton, Mass: 903.056 kg; WSP_beton - ihwg beton, Component Volume (Net): 0.392633 m3; WSP_beton - ihwg beton, Component Volume (Gross): 0.392633 m3

# IfcSlab: Slab 903, 17_WSP_FD_beton - fundatiepaal v21-2:ø300 (schroef):1509064
In: -2 fundering
Classification: Vloerplaat - fundering (ARCHICAD Classification); Material: WSP_beton - ihwg beton
Pset_ReinforcementBarPitchOfSlab - Reference: ø300 (schroef)
Pset_SlabCommon - Reference: ø300 (schroef); IsExternal: yes; LoadBearing: no
CPset_Phasing - Renovation Phase: Bestaand
Component Quantities - WSP_beton - ihwg beton, Mass: 903.056 kg; WSP_beton - ihwg beton, Component Volume (Net): 0.392633 m3; WSP_beton - ihwg beton, Component Volume (Gross): 0.392633 m3

# IfcSlab: Slab 904, 17_WSP_FD_beton - fundatiepaal v21-2:ø300 (schroef):1509063
In: -2 fundering
Classification: Vloerplaat - fundering (ARCHICAD Classification); Material: WSP_beton - ihwg beton
Pset_SlabCommon - Reference: ø300 (schroef); IsExternal: yes; LoadBearing: no
Pset_ReinforcementBarPitchOfSlab - Reference: ø300 (schroef)
CPset_Phasing - Renovation Phase: Bestaand
Component Quantities - WSP_beton - ihwg beton, Mass: 903.056 kg; WSP_beton - ihwg beton, Component Volume (Net): 0.392633 m3; WSP_beton - ihwg beton, Component Volume (Gross): 0.392633 m3

# IfcSlab: Slab 905, 17_WSP_FD_beton - fundatiepaal v21-2:ø300 (schroef):1509062
In: -2 fundering
Classification: Vloerplaat - fundering (ARCHICAD Classification); Material: WSP_beton - ihwg beton
Pset_SlabCommon - Reference: ø300 (schroef); IsExternal: yes; LoadBearing: no
Pset_ReinforcementBarPitchOfSlab - Reference: ø300 (schroef)
Component Quantities - WSP_beton - ihwg beton, Mass: 903.056 kg; WSP_beton - ihwg beton, Component Volume (Net): 0.392633 m3; WSP_beton - ihwg beton, Component Volume (Gross): 0.392633 m3
CPset_Phasing - Renovation Phase: Bestaand

# IfcSlab: Slab 906, 17_WSP_FD_beton - fundatiepaal v21-2:ø300 (schroef):1509061
In: -2 fundering
Classification: Vloerplaat - fundering (ARCHICAD Classification); Material: WSP_beton - ihwg beton
Pset_SlabCommon - Reference: ø300 (schroef); IsExternal: yes; LoadBearing: no
CPset_Phasing - Renovation Phase: Bestaand
Component Quantities - WSP_beton - ihwg beton, Mass: 903.056 kg; WSP_beton - ihwg beton, Component Volume (Net): 0.392633 m3; WSP_beton - ihwg beton, Component Volume (Gross): 0.392633 m3
Pset_ReinforcementBarPitchOfSlab - Reference: ø300 (schroef)

# IfcSlab: Slab 907, 17_WSP_FD_beton - fundatiepaal v21-2:ø300 (schroef):1509060
In: -2 fundering
Classification: Vloerplaat - fundering (ARCHICAD Classification); Material: WSP_beton - ihwg beton
Pset_SlabCommon - Reference: ø300 (schroef); IsExternal: yes; LoadBearing: no
CPset_Phasing - Renovation Phase: Bestaand
Component Quantities - WSP_beton - ihwg beton, Mass: 903.056 kg; WSP_beton - ihwg beton, Component Volume (Net): 0.392633 m3; WSP_beton - ihwg beton, Component Volume (Gross): 0.392633 m3
Pset_ReinforcementBarPitchOfSlab - Reference: ø300 (schroef)

# IfcSlab: Slab 908, 17_WSP_FD_beton - fundatiepaal v21-2:ø300 (schroef):1509059
In: -2 fundering
Classification: Vloerplaat - fundering (ARCHICAD Classification); Material: WSP_beton - ihwg beton
Pset_SlabCommon - Reference: ø300 (schroef); IsExternal: yes; LoadBearing: no
CPset_Phasing - Renovation Phase: Bestaand
Component Quantities - WSP_beton - ihwg beton, Mass: 903.056 kg; WSP_beton - ihwg beton, Component Volume (Net): 0.392633 m3; WSP_beton - ihwg beton, Component Volume (Gross): 0.392633 m3
Pset_ReinforcementBarPitchOfSlab - Reference: ø300 (schroef)

# IfcSlab: Slab 909, 17_WSP_FD_beton - fundatiepaal v21-2:ø300 (schroef):1509058
In: -2 fundering
Classification: Vloerplaat - fundering (ARCHICAD Classification); Material: WSP_beton - ihwg beton
Pset_ReinforcementBarPitchOfSlab - Reference: ø300 (schroef)
Pset_SlabCommon - Reference: ø300 (schroef); IsExternal: yes; LoadBearing: no
CPset_Phasing - Renovation Phase: Bestaand
Component Quantities - WSP_beton - ihwg beton, Mass: 903.056 kg; WSP_beton - ihwg beton, Component Volume (Net): 0.392633 m3; WSP_beton - ihwg beton, Component Volume (Gross): 0.392633 m3

# IfcSlab: Slab 91, 17_WSP_FD_beton - fundatiepaal v21-2:ø300 (schroef):1473599
In: -2 fundering
Classification: Vloerplaat - fundering (ARCHICAD Classification); Material: WSP_beton - ihwg beton
Pset_SlabCommon - Reference: ø300 (schroef); IsExternal: yes; LoadBearing: no
Pset_ReinforcementBarPitchOfSlab - Reference: ø300 (schroef)
CPset_Phasing - Renovation Phase: Bestaand
Component Quantities - WSP_beton - ihwg beton, Mass: 903.056 kg; WSP_beton - ihwg beton, Component Volume (Net): 0.392633 m3; WSP_beton - ihwg beton, Component Volume (Gross): 0.392633 m3

# IfcSlab: Slab 910, 17_WSP_FD_beton - fundatiepaal v21-2:ø300 (schroef):1509057
In: -2 fundering
Classification: Vloerplaat - fundering (ARCHICAD Classification); Material: WSP_beton - ihwg beton
Pset_ReinforcementBarPitchOfSlab - Reference: ø300 (schroef)
Pset_SlabCommon - Reference: ø300 (schroef); IsExternal: yes; LoadBearing: no
CPset_Phasing - Renovation Phase: Bestaand
Component Quantities - WSP_beton - ihwg beton, Mass: 903.056 kg; WSP_beton - ihwg beton, Component Volume (Net): 0.392633 m3; WSP_beton - ihwg beton, Component Volume (Gross): 0.392633 m3

# IfcSlab: Slab 911, 17_WSP_FD_beton - fundatiepaal v21-2:ø300 (schroef):1509056
In: -2 fundering
Classification: Vloerplaat - fundering (ARCHICAD Classification); Material: WSP_beton - ihwg beton
Pset_SlabCommon - Reference: ø300 (schroef); IsExternal: yes; LoadBearing: no
Pset_ReinforcementBarPitchOfSlab - Reference: ø300 (schroef)
Component Quantities - WSP_beton - ihwg beton, Mass: 903.056 kg; WSP_beton - ihwg beton, Component Volume (Net): 0.392633 m3; WSP_beton - ihwg beton, Component Volume (Gross): 0.392633 m3
CPset_Phasing - Renovation Phase: Bestaand

# IfcSlab: Slab 912, 17_WSP_FD_beton - fundatiepaal v21-2:ø300 (schroef):1509087
In: -2 fundering
Classification: Vloerplaat - fundering (ARCHICAD Classification); Material: WSP_beton - ihwg beton
Pset_SlabCommon - Reference: ø300 (schroef); IsExternal: yes; LoadBearing: no
Component Quantities - WSP_beton - ihwg beton, Mass: 887.213 kg; WSP_beton - ihwg beton, Component Volume (Net): 0.385745 m3; WSP_beton - ihwg beton, Component Volume (Gross): 0.385745 m3
CPset_Phasing - Renovation Phase: Bestaand
Pset_ReinforcementBarPitchOfSlab - Reference: ø300 (schroef)

# IfcSlab: Slab 913, 17_WSP_FD_beton - fundatiepaal v21-2:ø300 (schroef):1509086
In: -2 fundering
Classification: Vloerplaat - fundering (ARCHICAD Classification); Material: WSP_beton - ihwg beton
Pset_ReinforcementBarPitchOfSlab - Reference: ø300 (schroef)
Pset_SlabCommon - Reference: ø300 (schroef); IsExternal: yes; LoadBearing: no
CPset_Phasing - Renovation Phase: Bestaand
Component Quantities - WSP_beton - ihwg beton, Mass: 887.213 kg; WSP_beton - ihwg beton, Component Volume (Net): 0.385745 m3; WSP_beton - ihwg beton, Component Volume (Gross): 0.385745 m3

# IfcSlab: Slab 914, 17_WSP_FD_beton - fundatiepaal v21-2:ø300 (schroef):1509085
In: -2 fundering
Classification: Vloerplaat - fundering (ARCHICAD Classification); Material: WSP_beton - ihwg beton
Pset_SlabCommon - Reference: ø300 (schroef); IsExternal: yes; LoadBearing: no
Pset_ReinforcementBarPitchOfSlab - Reference: ø300 (schroef)
Component Quantities - WSP_beton - ihwg beton, Mass: 903.056 kg; WSP_beton - ihwg beton, Component Volume (Net): 0.392633 m3; WSP_beton - ihwg beton, Component Volume (Gross): 0.392633 m3
CPset_Phasing - Renovation Phase: Bestaand

# IfcSlab: Slab 915, 17_WSP_FD_beton - fundatiepaal v21-2:ø300 (schroef):1509084
In: -2 fundering
Classification: Vloerplaat - fundering (ARCHICAD Classification); Material: WSP_beton - ihwg beton
Pset_SlabCommon - Reference: ø300 (schroef); IsExternal: yes; LoadBearing: no
Component Quantities - WSP_beton - ihwg beton, Mass: 903.056 kg; WSP_beton - ihwg beton, Component Volume (Net): 0.392633 m3; WSP_beton - ihwg beton, Component Volume (Gross): 0.392633 m3
Pset_ReinforcementBarPitchOfSlab - Reference: ø300 (schroef)
CPset_Phasing - Renovation Phase: Bestaand

# IfcSlab: Slab 916, 17_WSP_FD_beton - fundatiepaal v21-2:ø300 (schroef):1509083
In: -2 fundering
Classification: Vloerplaat - fundering (ARCHICAD Classification); Material: WSP_beton - ihwg beton
Pset_SlabCommon - Reference: ø300 (schroef); IsExternal: yes; LoadBearing: no
Pset_ReinforcementBarPitchOfSlab - Reference: ø300 (schroef)
CPset_Phasing - Renovation Phase: Bestaand
Component Quantities - WSP_beton - ihwg beton, Mass: 903.056 kg; WSP_beton - ihwg beton, Component Volume (Net): 0.392633 m3; WSP_beton - ihwg beton, Component Volume (Gross): 0.392633 m3

# IfcSlab: Slab 917, 17_WSP_FD_beton - fundatiepaal v21-2:ø300 (schroef):1509082
In: -2 fundering
Classification: Vloerplaat - fundering (ARCHICAD Classification); Material: WSP_beton - ihwg beton
Pset_SlabCommon - Reference: ø300 (schroef); IsExternal: yes; LoadBearing: no
Pset_ReinforcementBarPitchOfSlab - Reference: ø300 (schroef)
CPset_Phasing - Renovation Phase: Bestaand
Component Quantities - WSP_beton - ihwg beton, Mass: 903.056 kg; WSP_beton - ihwg beton, Component Volume (Net): 0.392633 m3; WSP_beton - ihwg beton, Component Volume (Gross): 0.392633 m3

# IfcSlab: Slab 918, 17_WSP_FD_beton - fundatiepaal v21-2:ø300 (schroef):1509081
In: -2 fundering
Classification: Vloerplaat - fundering (ARCHICAD Classification); Material: WSP_beton - ihwg beton
Component Quantities - WSP_beton - ihwg beton, Mass: 903.056 kg; WSP_beton - ihwg beton, Component Volume (Net): 0.392633 m3; WSP_beton - ihwg beton, Component Volume (Gross): 0.392633 m3
CPset_Phasing - Renovation Phase: Bestaand
Pset_SlabCommon - Reference: ø300 (schroef); IsExternal: yes; LoadBearing: no
Pset_ReinforcementBarPitchOfSlab - Reference: ø300 (schroef)

# IfcSlab: Slab 919, 17_WSP_FD_beton - fundatiepaal v21-2:ø300 (schroef):1509080
In: -2 fundering
Classification: Vloerplaat - fundering (ARCHICAD Classification); Material: WSP_beton - ihwg beton
Component Quantities - WSP_beton - ihwg beton, Mass: 903.056 kg; WSP_beton - ihwg beton, Component Volume (Net): 0.392633 m3; WSP_beton - ihwg beton, Component Volume (Gross): 0.392633 m3
CPset_Phasing - Renovation Phase: Bestaand
Pset_SlabCommon - Reference: ø300 (schroef); IsExternal: yes; LoadBearing: no
Pset_ReinforcementBarPitchOfSlab - Reference: ø300 (schroef)

# IfcSlab: Slab 92, 17_WSP_FD_beton - fundatiepaal v21-2:ø300 (schroef):1473596
In: -2 fundering
Classification: Vloerplaat - fundering (ARCHICAD Classification); Material: WSP_beton - ihwg beton
Pset_SlabCommon - Reference: ø300 (schroef); IsExternal: yes; LoadBearing: no
Pset_ReinforcementBarPitchOfSlab - Reference: ø300 (schroef)
Component Quantities - WSP_beton - ihwg beton, Mass: 903.056 kg; WSP_beton - ihwg beton, Component Volume (Net): 0.392633 m3; WSP_beton - ihwg beton, Component Volume (Gross): 0.392633 m3
CPset_Phasing - Renovation Phase: Bestaand

# IfcSlab: Slab 920, 17_WSP_FD_beton - fundatiepaal v21-2:ø300 (schroef):1509079
In: -2 fundering
Classification: Vloerplaat - fundering (ARCHICAD Classification); Material: WSP_beton - ihwg beton
Pset_ReinforcementBarPitchOfSlab - Reference: ø300 (schroef)
Pset_SlabCommon - Reference: ø300 (schroef); IsExternal: yes; LoadBearing: no
Component Quantities - WSP_beton - ihwg beton, Mass: 903.056 kg; WSP_beton - ihwg beton, Component Volume (Net): 0.392633 m3; WSP_beton - ihwg beton, Component Volume (Gross): 0.392633 m3
CPset_Phasing - Renovation Phase: Bestaand

# IfcSlab: Slab 921, 17_WSP_FD_beton - fundatiepaal v21-2:ø300 (schroef):1509078
In: -2 fundering
Classification: Vloerplaat - fundering (ARCHICAD Classification); Material: WSP_beton - ihwg beton
Pset_SlabCommon - Reference: ø300 (schroef); IsExternal: yes; LoadBearing: no
Pset_ReinforcementBarPitchOfSlab - Reference: ø300 (schroef)
CPset_Phasing - Renovation Phase: Bestaand
Component Quantities - WSP_beton - ihwg beton, Mass: 903.056 kg; WSP_beton - ihwg beton, Component Volume (Net): 0.392633 m3; WSP_beton - ihwg beton, Component Volume (Gross): 0.392633 m3

# IfcSlab: Slab 922, 17_WSP_FD_beton - fundatiepaal v21-2:ø300 (schroef):1509077
In: -2 fundering
Classification: Vloerplaat - fundering (ARCHICAD Classification); Material: WSP_beton - ihwg beton
Pset_ReinforcementBarPitchOfSlab - Reference: ø300 (schroef)
Pset_SlabCommon - Reference: ø300 (schroef); IsExternal: yes; LoadBearing: no
Component Quantities - WSP_beton - ihwg beton, Mass: 903.056 kg; WSP_beton - ihwg beton, Component Volume (Net): 0.392633 m3; WSP_beton - ihwg beton, Component Volume (Gross): 0.392633 m3
CPset_Phasing - Renovation Phase: Bestaand

# IfcSlab: Slab 923, 17_WSP_FD_beton - fundatiepaal v21-2:ø300 (schroef):1509076
In: -2 fundering
Classification: Vloerplaat - fundering (ARCHICAD Classification); Material: WSP_beton - ihwg beton
Pset_SlabCommon - Reference: ø300 (schroef); IsExternal: yes; LoadBearing: no
CPset_Phasing - Renovation Phase: Bestaand
Component Quantities - WSP_beton - ihwg beton, Mass: 903.056 kg; WSP_beton - ihwg beton, Component Volume (Net): 0.392633 m3; WSP_beton - ihwg beton, Component Volume (Gross): 0.392633 m3
Pset_ReinforcementBarPitchOfSlab - Reference: ø300 (schroef)

# IfcSlab: Slab 924, 17_WSP_FD_beton - fundatiepaal v21-2:ø300 (schroef):1509075
In: -2 fundering
Classification: Vloerplaat - fundering (ARCHICAD Classification); Material: WSP_beton - ihwg beton
Pset_ReinforcementBarPitchOfSlab - Reference: ø300 (schroef)
Pset_SlabCommon - Reference: ø300 (schroef); IsExternal: yes; LoadBearing: no
CPset_Phasing - Renovation Phase: Bestaand
Component Quantities - WSP_beton - ihwg beton, Mass: 903.056 kg; WSP_beton - ihwg beton, Component Volume (Net): 0.392633 m3; WSP_beton - ihwg beton, Component Volume (Gross): 0.392633 m3

# IfcSlab: Slab 925, 17_WSP_FD_beton - fundatiepaal v21-2:ø300 (schroef):1509074
In: -2 fundering
Classification: Vloerplaat - fundering (ARCHICAD Classification); Material: WSP_beton - ihwg beton
Pset_SlabCommon - Reference: ø300 (schroef); IsExternal: yes; LoadBearing: no
CPset_Phasing - Renovation Phase: Bestaand
Pset_ReinforcementBarPitchOfSlab - Reference: ø300 (schroef)
Component Quantities - WSP_beton - ihwg beton, Mass: 903.056 kg; WSP_beton - ihwg beton, Component Volume (Net): 0.392633 m3; WSP_beton - ihwg beton, Component Volume (Gross): 0.392633 m3

# IfcSlab: Slab 926, 17_WSP_FD_beton - fundatiepaal v21-2:ø300 (schroef):1509073
In: -2 fundering
Classification: Vloerplaat - fundering (ARCHICAD Classification); Material: WSP_beton - ihwg beton
Pset_ReinforcementBarPitchOfSlab - Reference: ø300 (schroef)
Pset_SlabCommon - Reference: ø300 (schroef); IsExternal: yes; LoadBearing: no
Component Quantities - WSP_beton - ihwg beton, Mass: 903.056 kg; WSP_beton - ihwg beton, Component Volume (Net): 0.392633 m3; WSP_beton - ihwg beton, Component Volume (Gross): 0.392633 m3
CPset_Phasing - Renovation Phase: Bestaand

# IfcSlab: Slab 927, 17_WSP_FD_beton - fundatiepaal v21-2:ø300 (schroef):1509072
In: -2 fundering
Classification: Vloerplaat - fundering (ARCHICAD Classification); Material: WSP_beton - ihwg beton
Pset_SlabCommon - Reference: ø300 (schroef); IsExternal: yes; LoadBearing: no
Pset_ReinforcementBarPitchOfSlab - Reference: ø300 (schroef)
Component Quantities - WSP_beton - ihwg beton, Mass: 903.056 kg; WSP_beton - ihwg beton, Component Volume (Net): 0.392633 m3; WSP_beton - ihwg beton, Component Volume (Gross): 0.392633 m3
CPset_Phasing - Renovation Phase: Bestaand

# IfcSlab: Slab 928, 17_WSP_FD_beton - fundatiepaal v21-2:ø300 (schroef):1462114
In: -2 fundering
Classification: Vloerplaat - fundering (ARCHICAD Classification); Material: WSP_beton - ihwg beton
Pset_SlabCommon - Reference: ø300 (schroef); IsExternal: yes; LoadBearing: no
Pset_ReinforcementBarPitchOfSlab - Reference: ø300 (schroef)
Component Quantities - WSP_beton - ihwg beton, Mass: 887.213 kg; WSP_beton - ihwg beton, Component Volume (Net): 0.385745 m3; WSP_beton - ihwg beton, Component Volume (Gross): 0.385745 m3
CPset_Phasing - Renovation Phase: Bestaand

# IfcSlab: Slab 929, 17_WSP_FD_beton - fundatiepaal v21-2:ø300 (schroef):1462037
In: -2 fundering
Classification: Vloerplaat - fundering (ARCHICAD Classification); Material: WSP_beton - ihwg beton
Pset_SlabCommon - Reference: ø300 (schroef); IsExternal: yes; LoadBearing: no
Pset_ReinforcementBarPitchOfSlab - Reference: ø300 (schroef)
CPset_Phasing - Renovation Phase: Bestaand
Component Quantities - WSP_beton - ihwg beton, Mass: 887.213 kg; WSP_beton - ihwg beton, Component Volume (Net): 0.385745 m3; WSP_beton - ihwg beton, Component Volume (Gross): 0.385745 m3

# IfcSlab: Slab 93, 17_WSP_FD_beton - fundatiepaal v21-2:ø300 (schroef):1473597
In: -2 fundering
Classification: Vloerplaat - fundering (ARCHICAD Classification); Material: WSP_beton - ihwg beton
Pset_SlabCommon - Reference: ø300 (schroef); IsExternal: yes; LoadBearing: no
Pset_ReinforcementBarPitchOfSlab - Reference: ø300 (schroef)
CPset_Phasing - Renovation Phase: Bestaand
Component Quantities - WSP_beton - ihwg beton, Mass: 903.056 kg; WSP_beton - ihwg beton, Component Volume (Net): 0.392633 m3; WSP_beton - ihwg beton, Component Volume (Gross): 0.392633 m3

# IfcSlab: Slab 930, 17_WSP_FD_beton - fundatiepaal v21-2:ø300 (schroef):1462038
In: -2 fundering
Classification: Vloerplaat - fundering (ARCHICAD Classification); Material: WSP_beton - ihwg beton
Pset_SlabCommon - Reference: ø300 (schroef); IsExternal: yes; LoadBearing: no
Pset_ReinforcementBarPitchOfSlab - Reference: ø300 (schroef)
CPset_Phasing - Renovation Phase: Bestaand
Component Quantities - WSP_beton - ihwg beton, Mass: 887.213 kg; WSP_beton - ihwg beton, Component Volume (Net): 0.385745 m3; WSP_beton - ihwg beton, Component Volume (Gross): 0.385745 m3

# IfcSlab: Slab 931, 17_WSP_FD_beton - fundatiepaal v21-2:ø300 (schroef):1462023
In: -2 fundering
Classification: Vloerplaat - fundering (ARCHICAD Classification); Material: WSP_beton - ihwg beton
Pset_SlabCommon - Reference: ø300 (schroef); IsExternal: yes; LoadBearing: no
CPset_Phasing - Renovation Phase: Bestaand
Pset_ReinforcementBarPitchOfSlab - Reference: ø300 (schroef)
Component Quantities - WSP_beton - ihwg beton, Mass: 887.213 kg; WSP_beton - ihwg beton, Component Volume (Net): 0.385745 m3; WSP_beton - ihwg beton, Component Volume (Gross): 0.385745 m3

# IfcSlab: Slab 932, 17_WSP_FD_beton - fundatiepaal v21-2:ø300 (schroef):1462154
In: -2 fundering
Classification: Vloerplaat - fundering (ARCHICAD Classification); Material: WSP_beton - ihwg beton
CPset_Phasing - Renovation Phase: Bestaand
Component Quantities - WSP_beton - ihwg beton, Mass: 887.213 kg; WSP_beton - ihwg beton, Component Volume (Net): 0.385745 m3; WSP_beton - ihwg beton, Component Volume (Gross): 0.385745 m3
Pset_SlabCommon - Reference: ø300 (schroef); IsExternal: yes; LoadBearing: no
Pset_ReinforcementBarPitchOfSlab - Reference: ø300 (schroef)

# IfcSlab: Slab 933, 17_WSP_FD_beton - fundatiepaal v21-2:ø300 (schroef):1463603
In: -2 fundering
Classification: Vloerplaat - fundering (ARCHICAD Classification); Material: WSP_beton - ihwg beton
Pset_SlabCommon - Reference: ø300 (schroef); IsExternal: yes; LoadBearing: no
Pset_ReinforcementBarPitchOfSlab - Reference: ø300 (schroef)
CPset_Phasing - Renovation Phase: Bestaand
Component Quantities - WSP_beton - ihwg beton, Mass: 887.213 kg; WSP_beton - ihwg beton, Component Volume (Net): 0.385745 m3; WSP_beton - ihwg beton, Component Volume (Gross): 0.385745 m3

# IfcSlab: Slab 934, 17_WSP_FD_beton - fundatiepaal v21-2:ø300 (schroef):1463602
In: -2 fundering
Classification: Vloerplaat - fundering (ARCHICAD Classification); Material: WSP_beton - ihwg beton
Pset_SlabCommon - Reference: ø300 (schroef); IsExternal: yes; LoadBearing: no
CPset_Phasing - Renovation Phase: Bestaand
Component Quantities - WSP_beton - ihwg beton, Mass: 887.213 kg; WSP_beton - ihwg beton, Component Volume (Net): 0.385745 m3; WSP_beton - ihwg beton, Component Volume (Gross): 0.385745 m3
Pset_ReinforcementBarPitchOfSlab - Reference: ø300 (schroef)

# IfcSlab: Slab 935, 17_WSP_FD_beton - fundatiepaal v21-2:ø300 (schroef):1462645
In: -2 fundering
Classification: Vloerplaat - fundering (ARCHICAD Classification); Material: WSP_beton - ihwg beton
Pset_ReinforcementBarPitchOfSlab - Reference: ø300 (schroef)
Pset_SlabCommon - Reference: ø300 (schroef); IsExternal: yes; LoadBearing: no
CPset_Phasing - Renovation Phase: Bestaand
Component Quantities - WSP_beton - ihwg beton, Mass: 887.213 kg; WSP_beton - ihwg beton, Component Volume (Net): 0.385745 m3; WSP_beton - ihwg beton, Component Volume (Gross): 0.385745 m3

# IfcSlab: Slab 936, 17_WSP_FD_beton - fundatiepaal v21-2:ø300 (schroef):1462646
In: -2 fundering
Classification: Vloerplaat - fundering (ARCHICAD Classification); Material: WSP_beton - ihwg beton
CPset_Phasing - Renovation Phase: Bestaand
Pset_ReinforcementBarPitchOfSlab - Reference: ø300 (schroef)
Component Quantities - WSP_beton - ihwg beton, Mass: 887.213 kg; WSP_beton - ihwg beton, Component Volume (Net): 0.385745 m3; WSP_beton - ihwg beton, Component Volume (Gross): 0.385745 m3
Pset_SlabCommon - Reference: ø300 (schroef); IsExternal: yes; LoadBearing: no

# IfcSlab: Slab 937, 17_WSP_FD_beton - fundatiepaal v21-2:ø300 (schroef):1462783
In: -2 fundering
Classification: Vloerplaat - fundering (ARCHICAD Classification); Material: WSP_beton - ihwg beton
Pset_SlabCommon - Reference: ø300 (schroef); IsExternal: yes; LoadBearing: no
Pset_ReinforcementBarPitchOfSlab - Reference: ø300 (schroef)
Component Quantities - WSP_beton - ihwg beton, Mass: 887.213 kg; WSP_beton - ihwg beton, Component Volume (Net): 0.385745 m3; WSP_beton - ihwg beton, Component Volume (Gross): 0.385745 m3
CPset_Phasing - Renovation Phase: Bestaand

# IfcSlab: Slab 938, 17_WSP_FD_beton - fundatiepaal v21-2:ø300 (schroef):1462782
In: -2 fundering
Classification: Vloerplaat - fundering (ARCHICAD Classification); Material: WSP_beton - ihwg beton
Pset_ReinforcementBarPitchOfSlab - Reference: ø300 (schroef)
CPset_Phasing - Renovation Phase: Bestaand
Pset_SlabCommon - Reference: ø300 (schroef); IsExternal: yes; LoadBearing: no
Component Quantities - WSP_beton - ihwg beton, Mass: 887.213 kg; WSP_beton - ihwg beton, Component Volume (Net): 0.385745 m3; WSP_beton - ihwg beton, Component Volume (Gross): 0.385745 m3

# IfcSlab: Slab 939, 17_WSP_FD_beton - fundatiepaal v21-2:ø300 (schroef):1462761
In: -2 fundering
Classification: Vloerplaat - fundering (ARCHICAD Classification); Material: WSP_beton - ihwg beton
Pset_ReinforcementBarPitchOfSlab - Reference: ø300 (schroef)
Pset_SlabCommon - Reference: ø300 (schroef); IsExternal: yes; LoadBearing: no
Component Quantities - WSP_beton - ihwg beton, Mass: 887.213 kg; WSP_beton - ihwg beton, Component Volume (Net): 0.385745 m3; WSP_beton - ihwg beton, Component Volume (Gross): 0.385745 m3
CPset_Phasing - Renovation Phase: Bestaand

# IfcSlab: Slab 94, 17_WSP_FD_beton - fundatiepaal v21-2:ø300 (schroef):1473538
In: -2 fundering
Classification: Vloerplaat - fundering (ARCHICAD Classification); Material: WSP_beton - ihwg beton
Pset_SlabCommon - Reference: ø300 (schroef); IsExternal: yes; LoadBearing: no
Component Quantities - WSP_beton - ihwg beton, Mass: 903.056 kg; WSP_beton - ihwg beton, Component Volume (Net): 0.392633 m3; WSP_beton - ihwg beton, Component Volume (Gross): 0.392633 m3
CPset_Phasing - Renovation Phase: Bestaand
Pset_ReinforcementBarPitchOfSlab - Reference: ø300 (schroef)

# IfcSlab: Slab 940, 17_WSP_FD_beton - fundatiepaal v21-2:ø300 (schroef):1462760
In: -2 fundering
Classification: Vloerplaat - fundering (ARCHICAD Classification); Material: WSP_beton - ihwg beton
Pset_SlabCommon - Reference: ø300 (schroef); IsExternal: yes; LoadBearing: no
Pset_ReinforcementBarPitchOfSlab - Reference: ø300 (schroef)
Component Quantities - WSP_beton - ihwg beton, Mass: 887.213 kg; WSP_beton - ihwg beton, Component Volume (Net): 0.385745 m3; WSP_beton - ihwg beton, Component Volume (Gross): 0.385745 m3
CPset_Phasing - Renovation Phase: Bestaand

# IfcSlab: Slab 941, 17_WSP_FD_beton - fundatiepaal v21-2:ø300 (schroef):1462893
In: -2 fundering
Classification: Vloerplaat - fundering (ARCHICAD Classification); Material: WSP_beton - ihwg beton
Pset_ReinforcementBarPitchOfSlab - Reference: ø300 (schroef)
Pset_SlabCommon - Reference: ø300 (schroef); IsExternal: yes; LoadBearing: no
CPset_Phasing - Renovation Phase: Bestaand
Component Quantities - WSP_beton - ihwg beton, Mass: 887.213 kg; WSP_beton - ihwg beton, Component Volume (Net): 0.385745 m3; WSP_beton - ihwg beton, Component Volume (Gross): 0.385745 m3

# IfcSlab: Slab 942, 17_WSP_FD_beton - fundatiepaal v21-2:ø300 (schroef):1462892
In: -2 fundering
Classification: Vloerplaat - fundering (ARCHICAD Classification); Material: WSP_beton - ihwg beton
Pset_SlabCommon - Reference: ø300 (schroef); IsExternal: yes; LoadBearing: no
Pset_ReinforcementBarPitchOfSlab - Reference: ø300 (schroef)
CPset_Phasing - Renovation Phase: Bestaand
Component Quantities - WSP_beton - ihwg beton, Mass: 887.213 kg; WSP_beton - ihwg beton, Component Volume (Net): 0.385745 m3; WSP_beton - ihwg beton, Component Volume (Gross): 0.385745 m3

# IfcSlab: Slab 943, 17_WSP_FD_beton - fundatiepaal v21-2:ø300 (schroef):1462871
In: -2 fundering
Classification: Vloerplaat - fundering (ARCHICAD Classification); Material: WSP_beton - ihwg beton
Component Quantities - WSP_beton - ihwg beton, Mass: 887.213 kg; WSP_beton - ihwg beton, Component Volume (Net): 0.385745 m3; WSP_beton - ihwg beton, Component Volume (Gross): 0.385745 m3
Pset_ReinforcementBarPitchOfSlab - Reference: ø300 (schroef)
Pset_SlabCommon - Reference: ø300 (schroef); IsExternal: yes; LoadBearing: no
CPset_Phasing - Renovation Phase: Bestaand

# IfcSlab: Slab 944, 17_WSP_FD_beton - fundatiepaal v21-2:ø300 (schroef):1462870
In: -2 fundering
Classification: Vloerplaat - fundering (ARCHICAD Classification); Material: WSP_beton - ihwg beton
Pset_SlabCommon - Reference: ø300 (schroef); IsExternal: yes; LoadBearing: no
Pset_ReinforcementBarPitchOfSlab - Reference: ø300 (schroef)
CPset_Phasing - Renovation Phase: Bestaand
Component Quantities - WSP_beton - ihwg beton, Mass: 887.213 kg; WSP_beton - ihwg beton, Component Volume (Net): 0.385745 m3; WSP_beton - ihwg beton, Component Volume (Gross): 0.385745 m3

# IfcSlab: Slab 945, 17_WSP_FD_beton - fundatiepaal v21-2:ø300 (schroef):1462849
In: -2 fundering
Classification: Vloerplaat - fundering (ARCHICAD Classification); Material: WSP_beton - ihwg beton
Pset_ReinforcementBarPitchOfSlab - Reference: ø300 (schroef)
CPset_Phasing - Renovation Phase: Bestaand
Pset_SlabCommon - Reference: ø300 (schroef); IsExternal: yes; LoadBearing: no
Component Quantities - WSP_beton - ihwg beton, Mass: 887.213 kg; WSP_beton - ihwg beton, Component Volume (Net): 0.385745 m3; WSP_beton - ihwg beton, Component Volume (Gross): 0.385745 m3

# IfcSlab: Slab 946, 17_WSP_FD_beton - fundatiepaal v21-2:ø300 (schroef):1462848
In: -2 fundering
Classification: Vloerplaat - fundering (ARCHICAD Classification); Material: WSP_beton - ihwg beton
Pset_SlabCommon - Reference: ø300 (schroef); IsExternal: yes; LoadBearing: no
Pset_ReinforcementBarPitchOfSlab - Reference: ø300 (schroef)
CPset_Phasing - Renovation Phase: Bestaand
Component Quantities - WSP_beton - ihwg beton, Mass: 887.213 kg; WSP_beton - ihwg beton, Component Volume (Net): 0.385745 m3; WSP_beton - ihwg beton, Component Volume (Gross): 0.385745 m3

# IfcSlab: Slab 947, 17_WSP_FD_beton - fundatiepaal v21-2:ø300 (schroef):1462827
In: -2 fundering
Classification: Vloerplaat - fundering (ARCHICAD Classification); Material: WSP_beton - ihwg beton
Pset_ReinforcementBarPitchOfSlab - Reference: ø300 (schroef)
CPset_Phasing - Renovation Phase: Bestaand
Pset_SlabCommon - Reference: ø300 (schroef); IsExternal: yes; LoadBearing: no
Component Quantities - WSP_beton - ihwg beton, Mass: 887.213 kg; WSP_beton - ihwg beton, Component Volume (Net): 0.385745 m3; WSP_beton - ihwg beton, Component Volume (Gross): 0.385745 m3

# IfcSlab: Slab 948, 17_WSP_FD_beton - fundatiepaal v21-2:ø300 (schroef):1462826
In: -2 fundering
Classification: Vloerplaat - fundering (ARCHICAD Classification); Material: WSP_beton - ihwg beton
Pset_ReinforcementBarPitchOfSlab - Reference: ø300 (schroef)
CPset_Phasing - Renovation Phase: Bestaand
Pset_SlabCommon - Reference: ø300 (schroef); IsExternal: yes; LoadBearing: no
Component Quantities - WSP_beton - ihwg beton, Mass: 887.213 kg; WSP_beton - ihwg beton, Component Volume (Net): 0.385745 m3; WSP_beton - ihwg beton, Component Volume (Gross): 0.385745 m3

# IfcSlab: Slab 949, 17_WSP_FD_beton - fundatiepaal v21-2:ø300 (schroef):1462805
In: -2 fundering
Classification: Vloerplaat - fundering (ARCHICAD Classification); Material: WSP_beton - ihwg beton
Pset_SlabCommon - Reference: ø300 (schroef); IsExternal: yes; LoadBearing: no
Pset_ReinforcementBarPitchOfSlab - Reference: ø300 (schroef)
CPset_Phasing - Renovation Phase: Bestaand
Component Quantities - WSP_beton - ihwg beton, Mass: 887.213 kg; WSP_beton - ihwg beton, Component Volume (Net): 0.385745 m3; WSP_beton - ihwg beton, Component Volume (Gross): 0.385745 m3

# IfcSlab: Slab 95, 17_WSP_FD_beton - fundatiepaal v21-2:ø300 (schroef):1473539
In: -2 fundering
Classification: Vloerplaat - fundering (ARCHICAD Classification); Material: WSP_beton - ihwg beton
Pset_SlabCommon - Reference: ø300 (schroef); IsExternal: yes; LoadBearing: no
Pset_ReinforcementBarPitchOfSlab - Reference: ø300 (schroef)
Component Quantities - WSP_beton - ihwg beton, Mass: 903.056 kg; WSP_beton - ihwg beton, Component Volume (Net): 0.392633 m3; WSP_beton - ihwg beton, Component Volume (Gross): 0.392633 m3
CPset_Phasing - Renovation Phase: Bestaand

# IfcSlab: Slab 950, 17_WSP_FD_beton - fundatiepaal v21-2:ø300 (schroef):1462804
In: -2 fundering
Classification: Vloerplaat - fundering (ARCHICAD Classification); Material: WSP_beton - ihwg beton
Pset_SlabCommon - Reference: ø300 (schroef); IsExternal: yes; LoadBearing: no
Pset_ReinforcementBarPitchOfSlab - Reference: ø300 (schroef)
CPset_Phasing - Renovation Phase: Bestaand
Component Quantities - WSP_beton - ihwg beton, Mass: 887.213 kg; WSP_beton - ihwg beton, Component Volume (Net): 0.385745 m3; WSP_beton - ihwg beton, Component Volume (Gross): 0.385745 m3

# IfcSlab: Slab 951, 17_WSP_FD_beton - fundatiepaal v21-2:ø300 (schroef):1462981
In: -2 fundering
Classification: Vloerplaat - fundering (ARCHICAD Classification); Material: WSP_beton - ihwg beton
Pset_SlabCommon - Reference: ø300 (schroef); IsExternal: yes; LoadBearing: no
Pset_ReinforcementBarPitchOfSlab - Reference: ø300 (schroef)
CPset_Phasing - Renovation Phase: Bestaand
Component Quantities - WSP_beton - ihwg beton, Mass: 887.213 kg; WSP_beton - ihwg beton, Component Volume (Net): 0.385745 m3; WSP_beton - ihwg beton, Component Volume (Gross): 0.385745 m3

# IfcSlab: Slab 952, 17_WSP_FD_beton - fundatiepaal v21-2:ø300 (schroef):1462980
In: -2 fundering
Classification: Vloerplaat - fundering (ARCHICAD Classification); Material: WSP_beton - ihwg beton
Pset_ReinforcementBarPitchOfSlab - Reference: ø300 (schroef)
Pset_SlabCommon - Reference: ø300 (schroef); IsExternal: yes; LoadBearing: no
Component Quantities - WSP_beton - ihwg beton, Mass: 887.213 kg; WSP_beton - ihwg beton, Component Volume (Net): 0.385745 m3; WSP_beton - ihwg beton, Component Volume (Gross): 0.385745 m3
CPset_Phasing - Renovation Phase: Bestaand

# IfcSlab: Slab 953, 17_WSP_FD_beton - fundatiepaal v21-2:ø300 (schroef):1462959
In: -2 fundering
Classification: Vloerplaat - fundering (ARCHICAD Classification); Material: WSP_beton - ihwg beton
Pset_SlabCommon - Reference: ø300 (schroef); IsExternal: yes; LoadBearing: no
Pset_ReinforcementBarPitchOfSlab - Reference: ø300 (schroef)
CPset_Phasing - Renovation Phase: Bestaand
Component Quantities - WSP_beton - ihwg beton, Mass: 887.213 kg; WSP_beton - ihwg beton, Component Volume (Net): 0.385745 m3; WSP_beton - ihwg beton, Component Volume (Gross): 0.385745 m3

# IfcSlab: Slab 954, 17_WSP_FD_beton - fundatiepaal v21-2:ø300 (schroef):1462958
In: -2 fundering
Classification: Vloerplaat - fundering (ARCHICAD Classification); Material: WSP_beton - ihwg beton
Pset_SlabCommon - Reference: ø300 (schroef); IsExternal: yes; LoadBearing: no
Pset_ReinforcementBarPitchOfSlab - Reference: ø300 (schroef)
Component Quantities - WSP_beton - ihwg beton, Mass: 887.213 kg; WSP_beton - ihwg beton, Component Volume (Net): 0.385745 m3; WSP_beton - ihwg beton, Component Volume (Gross): 0.385745 m3
CPset_Phasing - Renovation Phase: Bestaand

# IfcSlab: Slab 955, 17_WSP_FD_beton - fundatiepaal v21-2:ø300 (schroef):1462937
In: -2 fundering
Classification: Vloerplaat - fundering (ARCHICAD Classification); Material: WSP_beton - ihwg beton
Pset_SlabCommon - Reference: ø300 (schroef); IsExternal: yes; LoadBearing: no
CPset_Phasing - Renovation Phase: Bestaand
Component Quantities - WSP_beton - ihwg beton, Mass: 887.213 kg; WSP_beton - ihwg beton, Component Volume (Net): 0.385745 m3; WSP_beton - ihwg beton, Component Volume (Gross): 0.385745 m3
Pset_ReinforcementBarPitchOfSlab - Reference: ø300 (schroef)

# IfcSlab: Slab 956, 17_WSP_FD_beton - fundatiepaal v21-2:ø300 (schroef):1462936
In: -2 fundering
Classification: Vloerplaat - fundering (ARCHICAD Classification); Material: WSP_beton - ihwg beton
Pset_SlabCommon - Reference: ø300 (schroef); IsExternal: yes; LoadBearing: no
Pset_ReinforcementBarPitchOfSlab - Reference: ø300 (schroef)
Component Quantities - WSP_beton - ihwg beton, Mass: 887.213 kg; WSP_beton - ihwg beton, Component Volume (Net): 0.385745 m3; WSP_beton - ihwg beton, Component Volume (Gross): 0.385745 m3
CPset_Phasing - Renovation Phase: Bestaand

# IfcSlab: Slab 957, 17_WSP_FD_beton - fundatiepaal v21-2:ø300 (schroef):1462915
In: -2 fundering
Classification: Vloerplaat - fundering (ARCHICAD Classification); Material: WSP_beton - ihwg beton
Pset_ReinforcementBarPitchOfSlab - Reference: ø300 (schroef)
Pset_SlabCommon - Reference: ø300 (schroef); IsExternal: yes; LoadBearing: no
CPset_Phasing - Renovation Phase: Bestaand
Component Quantities - WSP_beton - ihwg beton, Mass: 887.213 kg; WSP_beton - ihwg beton, Component Volume (Net): 0.385745 m3; WSP_beton - ihwg beton, Component Volume (Gross): 0.385745 m3

# IfcSlab: Slab 958, 17_WSP_FD_beton - fundatiepaal v21-2:ø300 (schroef):1462914
In: -2 fundering
Classification: Vloerplaat - fundering (ARCHICAD Classification); Material: WSP_beton - ihwg beton
Pset_ReinforcementBarPitchOfSlab - Reference: ø300 (schroef)
Pset_SlabCommon - Reference: ø300 (schroef); IsExternal: yes; LoadBearing: no
CPset_Phasing - Renovation Phase: Bestaand
Component Quantities - WSP_beton - ihwg beton, Mass: 887.213 kg; WSP_beton - ihwg beton, Component Volume (Net): 0.385745 m3; WSP_beton - ihwg beton, Component Volume (Gross): 0.385745 m3

# IfcSlab: Slab 959, 17_WSP_FD_beton - fundatiepaal v21-2:ø300 (schroef):1597223
In: -2 fundering
Classification: Vloerplaat - fundering (ARCHICAD Classification); Material: WSP_beton - ihwg beton
Pset_ReinforcementBarPitchOfSlab - Reference: ø300 (schroef)
Component Quantities - WSP_beton - ihwg beton, Mass: 788.986 kg; WSP_beton - ihwg beton, Component Volume (Net): 0.343037 m3; WSP_beton - ihwg beton, Component Volume (Gross): 0.343037 m3
Pset_SlabCommon - Reference: ø300 (schroef); IsExternal: yes; LoadBearing: no
CPset_Phasing - Renovation Phase: Bestaand

# IfcSlab: Slab 96, 17_WSP_FD_beton - fundatiepaal v21-2:ø300 (schroef):1473536
In: -2 fundering
Classification: Vloerplaat - fundering (ARCHICAD Classification); Material: WSP_beton - ihwg beton
Pset_ReinforcementBarPitchOfSlab - Reference: ø300 (schroef)
CPset_Phasing - Renovation Phase: Bestaand
Pset_SlabCommon - Reference: ø300 (schroef); IsExternal: yes; LoadBearing: no
Component Quantities - WSP_beton - ihwg beton, Mass: 903.056 kg; WSP_beton - ihwg beton, Component Volume (Net): 0.392633 m3; WSP_beton - ihwg beton, Component Volume (Gross): 0.392633 m3

# IfcSlab: Slab 960, 17_WSP_FD_beton - fundatiepaal v21-2:ø300 (schroef):1597226
In: -2 fundering
Classification: Vloerplaat - fundering (ARCHICAD Classification); Material: WSP_beton - ihwg beton
Pset_ReinforcementBarPitchOfSlab - Reference: ø300 (schroef)
Component Quantities - WSP_beton - ihwg beton, Mass: 788.986 kg; WSP_beton - ihwg beton, Component Volume (Net): 0.343037 m3; WSP_beton - ihwg beton, Component Volume (Gross): 0.343037 m3
CPset_Phasing - Renovation Phase: Bestaand
Pset_SlabCommon - Reference: ø300 (schroef); IsExternal: yes; LoadBearing: no

# IfcSlab: Slab 961, 17_WSP_FD_beton - fundatiepaal v21-2:ø300 (schroef):1597227
In: -2 fundering
Classification: Vloerplaat - fundering (ARCHICAD Classification); Material: WSP_beton - ihwg beton
Pset_SlabCommon - Reference: ø300 (schroef); IsExternal: yes; LoadBearing: no
Pset_ReinforcementBarPitchOfSlab - Reference: ø300 (schroef)
CPset_Phasing - Renovation Phase: Bestaand
Component Quantities - WSP_beton - ihwg beton, Mass: 788.986 kg; WSP_beton - ihwg beton, Component Volume (Net): 0.343037 m3; WSP_beton - ihwg beton, Component Volume (Gross): 0.343037 m3

# IfcSlab: Slab 962, 17_WSP_FD_beton - fundatiepaal v21-2:ø300 (schroef):1597224
In: -2 fundering
Classification: Vloerplaat - fundering (ARCHICAD Classification); Material: WSP_beton - ihwg beton
Pset_ReinforcementBarPitchOfSlab - Reference: ø300 (schroef)
Pset_SlabCommon - Reference: ø300 (schroef); IsExternal: yes; LoadBearing: no
CPset_Phasing - Renovation Phase: Bestaand
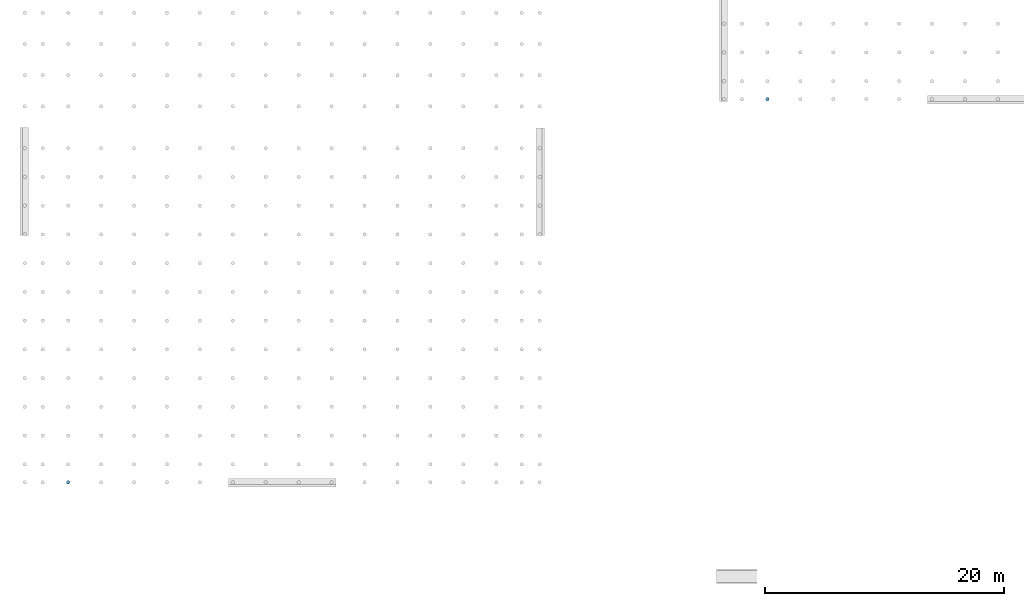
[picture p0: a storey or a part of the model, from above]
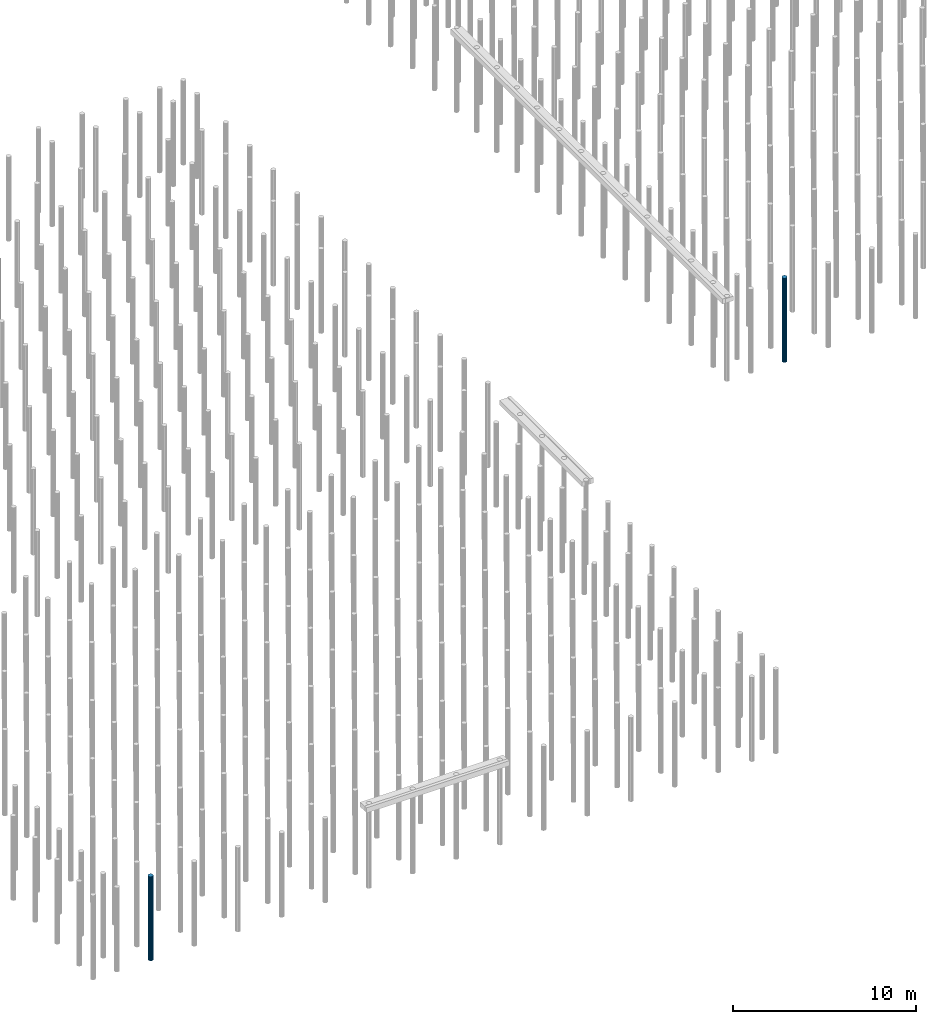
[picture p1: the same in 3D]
Properties of the parts of a building model (IFC2X3), part 12 of 13

# IfcSlab: Slab 962, 17_WSP_FD_beton - fundatiepaal v21-2:ø300 (schroef):1597224
Component Quantities - WSP_beton - ihwg beton, Mass: 788.986 kg; WSP_beton - ihwg beton, Component Volume (Net): 0.343037 m3; WSP_beton - ihwg beton, Component Volume (Gross): 0.343037 m3

# IfcSlab: Slab 963, 17_WSP_FD_beton - fundatiepaal v21-2:ø300 (schroef):1597225
In: -2 fundering
Classification: Vloerplaat - fundering (ARCHICAD Classification); Material: WSP_beton - ihwg beton
Pset_SlabCommon - Reference: ø300 (schroef); IsExternal: yes; LoadBearing: no
Pset_ReinforcementBarPitchOfSlab - Reference: ø300 (schroef)
CPset_Phasing - Renovation Phase: Bestaand
Component Quantities - WSP_beton - ihwg beton, Mass: 788.986 kg; WSP_beton - ihwg beton, Component Volume (Net): 0.343037 m3; WSP_beton - ihwg beton, Component Volume (Gross): 0.343037 m3

# IfcSlab: Slab 964, 17_WSP_FD_beton - fundatiepaal v21-2:ø300 (schroef):1597030
In: -2 fundering
Classification: Vloerplaat - fundering (ARCHICAD Classification); Material: WSP_beton - ihwg beton
Pset_ReinforcementBarPitchOfSlab - Reference: ø300 (schroef)
Pset_SlabCommon - Reference: ø300 (schroef); IsExternal: yes; LoadBearing: no
CPset_Phasing - Renovation Phase: Bestaand
Component Quantities - WSP_beton - ihwg beton, Mass: 788.986 kg; WSP_beton - ihwg beton, Component Volume (Net): 0.343037 m3; WSP_beton - ihwg beton, Component Volume (Gross): 0.343037 m3

# IfcSlab: Slab 965, 17_WSP_FD_beton - fundatiepaal v21-2:ø300 (schroef):1597031
In: -2 fundering
Classification: Vloerplaat - fundering (ARCHICAD Classification); Material: WSP_beton - ihwg beton
Pset_SlabCommon - Reference: ø300 (schroef); IsExternal: yes; LoadBearing: no
Pset_ReinforcementBarPitchOfSlab - Reference: ø300 (schroef)
CPset_Phasing - Renovation Phase: Bestaand
Component Quantities - WSP_beton - ihwg beton, Mass: 788.986 kg; WSP_beton - ihwg beton, Component Volume (Net): 0.343037 m3; WSP_beton - ihwg beton, Component Volume (Gross): 0.343037 m3

# IfcSlab: Slab 966, 17_WSP_FD_beton - fundatiepaal v21-2:ø300 (schroef):1597028
In: -2 fundering
Classification: Vloerplaat - fundering (ARCHICAD Classification); Material: WSP_beton - ihwg beton
Pset_SlabCommon - Reference: ø300 (schroef); IsExternal: yes; LoadBearing: no
CPset_Phasing - Renovation Phase: Bestaand
Pset_ReinforcementBarPitchOfSlab - Reference: ø300 (schroef)
Component Quantities - WSP_beton - ihwg beton, Mass: 788.986 kg; WSP_beton - ihwg beton, Component Volume (Net): 0.343037 m3; WSP_beton - ihwg beton, Component Volume (Gross): 0.343037 m3

# IfcSlab: Slab 967, 17_WSP_FD_beton - fundatiepaal v21-2:ø300 (schroef):1597029
In: -2 fundering
Classification: Vloerplaat - fundering (ARCHICAD Classification); Material: WSP_beton - ihwg beton
Pset_SlabCommon - Reference: ø300 (schroef); IsExternal: yes; LoadBearing: no
Pset_ReinforcementBarPitchOfSlab - Reference: ø300 (schroef)
CPset_Phasing - Renovation Phase: Bestaand
Component Quantities - WSP_beton - ihwg beton, Mass: 788.986 kg; WSP_beton - ihwg beton, Component Volume (Net): 0.343037 m3; WSP_beton - ihwg beton, Component Volume (Gross): 0.343037 m3

# IfcSlab: Slab 968, 17_WSP_FD_beton - fundatiepaal v21-2:ø300 (schroef):1597032
In: -2 fundering
Classification: Vloerplaat - fundering (ARCHICAD Classification); Material: WSP_beton - ihwg beton
Pset_ReinforcementBarPitchOfSlab - Reference: ø300 (schroef)
Pset_SlabCommon - Reference: ø300 (schroef); IsExternal: yes; LoadBearing: no
CPset_Phasing - Renovation Phase: Bestaand
Component Quantities - WSP_beton - ihwg beton, Mass: 788.986 kg; WSP_beton - ihwg beton, Component Volume (Net): 0.343037 m3; WSP_beton - ihwg beton, Component Volume (Gross): 0.343037 m3

# IfcSlab: Slab 969, 17_WSP_FD_beton - fundatiepaal v21-2:ø300 (schroef):1596958
In: -2 fundering
Classification: Vloerplaat - fundering (ARCHICAD Classification); Material: WSP_beton - ihwg beton
Pset_SlabCommon - Reference: ø300 (schroef); IsExternal: yes; LoadBearing: no
Pset_ReinforcementBarPitchOfSlab - Reference: ø300 (schroef)
CPset_Phasing - Renovation Phase: Bestaand
Component Quantities - WSP_beton - ihwg beton, Mass: 788.986 kg; WSP_beton - ihwg beton, Component Volume (Net): 0.343037 m3; WSP_beton - ihwg beton, Component Volume (Gross): 0.343037 m3

# IfcSlab: Slab 97, 17_WSP_FD_beton - fundatiepaal v21-2:ø300 (schroef):1473537
In: -2 fundering
Classification: Vloerplaat - fundering (ARCHICAD Classification); Material: WSP_beton - ihwg beton
Pset_SlabCommon - Reference: ø300 (schroef); IsExternal: yes; LoadBearing: no
Pset_ReinforcementBarPitchOfSlab - Reference: ø300 (schroef)
CPset_Phasing - Renovation Phase: Bestaand
Component Quantities - WSP_beton - ihwg beton, Mass: 903.056 kg; WSP_beton - ihwg beton, Component Volume (Net): 0.392633 m3; WSP_beton - ihwg beton, Component Volume (Gross): 0.392633 m3

# IfcSlab: Slab 970, 17_WSP_FD_beton - fundatiepaal v21-2:ø300 (schroef):1596959
In: -2 fundering
Classification: Vloerplaat - fundering (ARCHICAD Classification); Material: WSP_beton - ihwg beton
Pset_SlabCommon - Reference: ø300 (schroef); IsExternal: yes; LoadBearing: no
Pset_ReinforcementBarPitchOfSlab - Reference: ø300 (schroef)
Component Quantities - WSP_beton - ihwg beton, Mass: 788.986 kg; WSP_beton - ihwg beton, Component Volume (Net): 0.343037 m3; WSP_beton - ihwg beton, Component Volume (Gross): 0.343037 m3
CPset_Phasing - Renovation Phase: Bestaand

# IfcSlab: Slab 971, 17_WSP_FD_beton - fundatiepaal v21-2:ø300 (schroef):1596964
In: -2 fundering
Classification: Vloerplaat - fundering (ARCHICAD Classification); Material: WSP_beton - ihwg beton
Pset_ReinforcementBarPitchOfSlab - Reference: ø300 (schroef)
Pset_SlabCommon - Reference: ø300 (schroef); IsExternal: yes; LoadBearing: no
CPset_Phasing - Renovation Phase: Bestaand
Component Quantities - WSP_beton - ihwg beton, Mass: 788.986 kg; WSP_beton - ihwg beton, Component Volume (Net): 0.343037 m3; WSP_beton - ihwg beton, Component Volume (Gross): 0.343037 m3

# IfcSlab: Slab 972, 17_WSP_FD_beton - fundatiepaal v21-2:ø300 (schroef):1596965
In: -2 fundering
Classification: Vloerplaat - fundering (ARCHICAD Classification); Material: WSP_beton - ihwg beton
Pset_SlabCommon - Reference: ø300 (schroef); IsExternal: yes; LoadBearing: no
CPset_Phasing - Renovation Phase: Bestaand
Pset_ReinforcementBarPitchOfSlab - Reference: ø300 (schroef)
Component Quantities - WSP_beton - ihwg beton, Mass: 788.986 kg; WSP_beton - ihwg beton, Component Volume (Net): 0.343037 m3; WSP_beton - ihwg beton, Component Volume (Gross): 0.343037 m3

# IfcSlab: Slab 973, 17_WSP_FD_beton - fundatiepaal v21-2:ø300 (schroef):1596962
In: -2 fundering
Classification: Vloerplaat - fundering (ARCHICAD Classification); Material: WSP_beton - ihwg beton
Pset_SlabCommon - Reference: ø300 (schroef); IsExternal: yes; LoadBearing: no
Component Quantities - WSP_beton - ihwg beton, Mass: 788.986 kg; WSP_beton - ihwg beton, Component Volume (Net): 0.343037 m3; WSP_beton - ihwg beton, Component Volume (Gross): 0.343037 m3
CPset_Phasing - Renovation Phase: Bestaand
Pset_ReinforcementBarPitchOfSlab - Reference: ø300 (schroef)

# IfcSlab: Slab 974, 17_WSP_FD_beton - fundatiepaal v21-2:ø300 (schroef):1596963
In: -2 fundering
Classification: Vloerplaat - fundering (ARCHICAD Classification); Material: WSP_beton - ihwg beton
Pset_SlabCommon - Reference: ø300 (schroef); IsExternal: yes; LoadBearing: no
Pset_ReinforcementBarPitchOfSlab - Reference: ø300 (schroef)
Component Quantities - WSP_beton - ihwg beton, Mass: 788.986 kg; WSP_beton - ihwg beton, Component Volume (Net): 0.343037 m3; WSP_beton - ihwg beton, Component Volume (Gross): 0.343037 m3
CPset_Phasing - Renovation Phase: Bestaand

# IfcSlab: Slab 975, 17_WSP_FD_beton - fundatiepaal v21-2:ø300 (schroef):1596960
In: -2 fundering
Classification: Vloerplaat - fundering (ARCHICAD Classification); Material: WSP_beton - ihwg beton
Pset_ReinforcementBarPitchOfSlab - Reference: ø300 (schroef)
Component Quantities - WSP_beton - ihwg beton, Mass: 788.986 kg; WSP_beton - ihwg beton, Component Volume (Net): 0.343037 m3; WSP_beton - ihwg beton, Component Volume (Gross): 0.343037 m3
CPset_Phasing - Renovation Phase: Bestaand
Pset_SlabCommon - Reference: ø300 (schroef); IsExternal: yes; LoadBearing: no

# IfcSlab: Slab 976, 17_WSP_FD_beton - fundatiepaal v21-2:ø300 (schroef):1596961
In: -2 fundering
Classification: Vloerplaat - fundering (ARCHICAD Classification); Material: WSP_beton - ihwg beton
Pset_SlabCommon - Reference: ø300 (schroef); IsExternal: yes; LoadBearing: no
Component Quantities - WSP_beton - ihwg beton, Mass: 788.986 kg; WSP_beton - ihwg beton, Component Volume (Net): 0.343037 m3; WSP_beton - ihwg beton, Component Volume (Gross): 0.343037 m3
CPset_Phasing - Renovation Phase: Bestaand
Pset_ReinforcementBarPitchOfSlab - Reference: ø300 (schroef)

# IfcSlab: Slab 977, 17_WSP_FD_beton - fundatiepaal v21-2:ø300 (schroef):1596896
In: -2 fundering
Classification: Vloerplaat - fundering (ARCHICAD Classification); Material: WSP_beton - ihwg beton
Pset_ReinforcementBarPitchOfSlab - Reference: ø300 (schroef)
CPset_Phasing - Renovation Phase: Bestaand
Component Quantities - WSP_beton - ihwg beton, Mass: 788.986 kg; WSP_beton - ihwg beton, Component Volume (Net): 0.343037 m3; WSP_beton - ihwg beton, Component Volume (Gross): 0.343037 m3
Pset_SlabCommon - Reference: ø300 (schroef); IsExternal: yes; LoadBearing: no

# IfcSlab: Slab 978, 17_WSP_FD_beton - fundatiepaal v21-2:ø300 (schroef):1596897
In: -2 fundering
Classification: Vloerplaat - fundering (ARCHICAD Classification); Material: WSP_beton - ihwg beton
Pset_SlabCommon - Reference: ø300 (schroef); IsExternal: yes; LoadBearing: no
Pset_ReinforcementBarPitchOfSlab - Reference: ø300 (schroef)
Component Quantities - WSP_beton - ihwg beton, Mass: 788.986 kg; WSP_beton - ihwg beton, Component Volume (Net): 0.343037 m3; WSP_beton - ihwg beton, Component Volume (Gross): 0.343037 m3
CPset_Phasing - Renovation Phase: Bestaand

# IfcSlab: Slab 979, 17_WSP_FD_beton - fundatiepaal v21-2:ø300 (schroef):1596800
In: -2 fundering
Classification: Vloerplaat - fundering (ARCHICAD Classification); Material: WSP_beton - ihwg beton
Pset_ReinforcementBarPitchOfSlab - Reference: ø300 (schroef)
Pset_SlabCommon - Reference: ø300 (schroef); IsExternal: yes; LoadBearing: no
Component Quantities - WSP_beton - ihwg beton, Mass: 788.986 kg; WSP_beton - ihwg beton, Component Volume (Net): 0.343037 m3; WSP_beton - ihwg beton, Component Volume (Gross): 0.343037 m3
CPset_Phasing - Renovation Phase: Bestaand

# IfcSlab: Slab 98, 17_WSP_FD_beton - fundatiepaal v21-2:ø300 (schroef):1473542
In: -2 fundering
Classification: Vloerplaat - fundering (ARCHICAD Classification); Material: WSP_beton - ihwg beton
Pset_ReinforcementBarPitchOfSlab - Reference: ø300 (schroef)
CPset_Phasing - Renovation Phase: Bestaand
Pset_SlabCommon - Reference: ø300 (schroef); IsExternal: yes; LoadBearing: no
Component Quantities - WSP_beton - ihwg beton, Mass: 903.056 kg; WSP_beton - ihwg beton, Component Volume (Net): 0.392633 m3; WSP_beton - ihwg beton, Component Volume (Gross): 0.392633 m3

# IfcSlab: Slab 980, 17_WSP_FD_beton - fundatiepaal v21-2:ø300 (schroef):1596799
In: -2 fundering
Classification: Vloerplaat - fundering (ARCHICAD Classification); Material: WSP_beton - ihwg beton
Pset_ReinforcementBarPitchOfSlab - Reference: ø300 (schroef)
Pset_SlabCommon - Reference: ø300 (schroef); IsExternal: yes; LoadBearing: no
CPset_Phasing - Renovation Phase: Bestaand
Component Quantities - WSP_beton - ihwg beton, Mass: 788.986 kg; WSP_beton - ihwg beton, Component Volume (Net): 0.343037 m3; WSP_beton - ihwg beton, Component Volume (Gross): 0.343037 m3

# IfcSlab: Slab 981, 17_WSP_FD_beton - fundatiepaal v21-2:ø300 (schroef):1596702
In: -2 fundering
Classification: Vloerplaat - fundering (ARCHICAD Classification); Material: WSP_beton - ihwg beton
Pset_SlabCommon - Reference: ø300 (schroef); IsExternal: yes; LoadBearing: no
Pset_ReinforcementBarPitchOfSlab - Reference: ø300 (schroef)
CPset_Phasing - Renovation Phase: Bestaand
Component Quantities - WSP_beton - ihwg beton, Mass: 788.986 kg; WSP_beton - ihwg beton, Component Volume (Net): 0.343037 m3; WSP_beton - ihwg beton, Component Volume (Gross): 0.343037 m3

# IfcSlab: Slab 982, 17_WSP_FD_beton - fundatiepaal v21-2:ø300 (schroef):1596667
In: -2 fundering
Classification: Vloerplaat - fundering (ARCHICAD Classification); Material: WSP_beton - ihwg beton
Component Quantities - WSP_beton - ihwg beton, Mass: 788.986 kg; WSP_beton - ihwg beton, Component Volume (Net): 0.343037 m3; WSP_beton - ihwg beton, Component Volume (Gross): 0.343037 m3
CPset_Phasing - Renovation Phase: Bestaand
Pset_ReinforcementBarPitchOfSlab - Reference: ø300 (schroef)
Pset_SlabCommon - Reference: ø300 (schroef); IsExternal: yes; LoadBearing: no

# IfcSlab: Slab 983, 17_WSP_FD_beton - fundatiepaal v21-2:ø300 (schroef):1596571
In: -2 fundering
Classification: Vloerplaat - fundering (ARCHICAD Classification); Material: WSP_beton - ihwg beton
Pset_SlabCommon - Reference: ø300 (schroef); IsExternal: yes; LoadBearing: no
Pset_ReinforcementBarPitchOfSlab - Reference: ø300 (schroef)
CPset_Phasing - Renovation Phase: Bestaand
Component Quantities - WSP_beton - ihwg beton, Mass: 788.986 kg; WSP_beton - ihwg beton, Component Volume (Net): 0.343037 m3; WSP_beton - ihwg beton, Component Volume (Gross): 0.343037 m3

# IfcSlab: Slab 984, 17_WSP_FD_beton - fundatiepaal v21-2:ø300 (schroef):1596298
In: -2 fundering
Classification: Vloerplaat - fundering (ARCHICAD Classification); Material: WSP_beton - ihwg beton
Pset_SlabCommon - Reference: ø300 (schroef); IsExternal: yes; LoadBearing: no
Component Quantities - WSP_beton - ihwg beton, Mass: 788.986 kg; WSP_beton - ihwg beton, Component Volume (Net): 0.343037 m3; WSP_beton - ihwg beton, Component Volume (Gross): 0.343037 m3
CPset_Phasing - Renovation Phase: Bestaand
Pset_ReinforcementBarPitchOfSlab - Reference: ø300 (schroef)

# IfcSlab: Slab 99, 17_WSP_FD_beton - fundatiepaal v21-2:ø300 (schroef):1473543
In: -2 fundering
Classification: Vloerplaat - fundering (ARCHICAD Classification); Material: WSP_beton - ihwg beton
Pset_SlabCommon - Reference: ø300 (schroef); IsExternal: yes; LoadBearing: no
Pset_ReinforcementBarPitchOfSlab - Reference: ø300 (schroef)
CPset_Phasing - Renovation Phase: Bestaand
Component Quantities - WSP_beton - ihwg beton, Mass: 903.056 kg; WSP_beton - ihwg beton, Component Volume (Net): 0.392633 m3; WSP_beton - ihwg beton, Component Volume (Gross): 0.392633 m3

# IfcSlab: bepalting-volkern_8 8, plafondafwerking_06
In: 00 begane grond
Classification: Vloer (ARCHICAD Classification); Material: Hout - Spaanplaat
CPset_Phasing - Renovation Phase: Bestaand
Pset_SlabCommon - IsExternal: no; LoadBearing: yes
Component Quantities - Hout - Spaanplaat, Mass: 7.1424 kg; Hout - Spaanplaat, Projected Component Area (Net): 1.488 m2; Hout - Spaanplaat, Projected Component Area (Gross): 1.488 m2; Hout - Spaanplaat, Component Thickness: 8 mm; Hout - Spaanplaat, Component Volume (Net): 0.011904 m3; Hout - Spaanplaat, Component Volume (Gross): 0.011904 m3
BaseQuantities - Width: 8 mm; Perimeter: 6040 mm; GrossArea: 1.488 m2; NetArea: 1.488 m2; GrossVolume: 0.011904 m3; NetVolume: 0.011904 m3

# IfcSlab: beton-ihwg-vloer_300 300 (2)
In: 00 begane grond
Classification: 13.22 vloeren als gebouwonderdeel (NL/SfB (4 cijfers)); Vloer (ARCHICAD Classification); Material: Beton gewapend C vloer
CPset_Phasing - Renovation Phase: Bestaand
BaseQuantities - Width: 300 mm
Pset_SlabCommon - IsExternal: yes; LoadBearing: yes
Component Quantities - Beton gewapend C vloer, Component Thickness: 300 mm
Name | Perimeter (mm) | GrossArea (m2) = NetArea (m2) = Beton gewapend C vloer, Projected Component Area (Net) (m2) = Beton gewapend C vloer, Projected Component Area (Gross) (m2) | GrossVolume (m3) = NetVolume (m3) = Beton gewapend C vloer, Component Volume (Net) (m3) = Beton gewapend C vloer, Component Volume (Gross) (m3) | Beton gewapend C vloer, Mass (kg)
betonnen vloer | 200800 | 2403.4 | 721.02 | 1730448
betonnen vloer | 186400 | 2119.72 | 635.916 | 1526198

# IfcSlab: beton-ihwg-vloer_400 400 (2)
In: 00 begane grond
Classification: 13.22 vloeren als gebouwonderdeel (NL/SfB (4 cijfers)); Vloer (ARCHICAD Classification); Material: Beton gewapend C vloer
Component Quantities - Beton gewapend C vloer, Component Thickness: 400 mm
BaseQuantities - Width: 400 mm
Pset_SlabCommon - IsExternal: yes; LoadBearing: yes
CPset_Phasing - Renovation Phase: Bestaand
Name | Beton gewapend C vloer, Mass (kg) | Beton gewapend C vloer, Projected Component Area (Net) (m2) = NetArea (m2) | Beton gewapend C vloer, Projected Component Area (Gross) (m2) = GrossArea (m2) | Beton gewapend C vloer, Component Volume (Net) (m3) = NetVolume (m3) | Beton gewapend C vloer, Component Volume (Gross) (m3) = GrossVolume (m3) | Perimeter (mm)
betonnen vloer | 400896 | 417.6 | 2821 | 167.04 | 1128.4 | 216800
betonnen vloer | 373248 | 388.8 | 2508.52 | 155.52 | 1003.41 | 202400

# IfcSlab: beton-prefab-vloer_200 200 (3)
In: 01 dak
Material: Beton gewapend prefab vloer
CPset_Phasing - Renovation Phase: Bestaand
Pset_SlabCommon - IsExternal: no; LoadBearing: yes
Component Quantities - Beton gewapend prefab vloer, Component Thickness: 200 mm
BaseQuantities - Width: 200 mm
Name | Classification | Beton gewapend prefab vloer, Mass (kg) | Beton gewapend prefab vloer, Projected Component Area (Net) (m2) = NetArea (m2) | Beton gewapend prefab vloer, Projected Component Area (Gross) (m2) = GrossArea (m2) | Beton gewapend prefab vloer, Component Volume (Net) (m3) = NetVolume (m3) | Beton gewapend prefab vloer, Component Volume (Gross) (m3) = GrossVolume (m3) | Perimeter (mm)
Vloer-x | Vloer (ARCHICAD Classification) | 34699.7 | 72.2911 | 82.2361 | 14.4582 | 16.4472 | 41637.4
Vloer-x | Vloer (ARCHICAD Classification) | 34715.1 | 72.3232 | 72.3232 | 14.4646 | 14.4646 | 40360
prefab vloer | Vloer (ARCHICAD Classification); 23.21 vrijdragende vloeren (NL/SfB (4 cijfers)) | 34724.7 | 72.3431 | 72.3431 | 14.4686 | 14.4686 | 40362.6

# IfcSlab: dekvloer_70 70, Vloer-x
In: 00 begane grond
Classification: Vloer (ARCHICAD Classification); Material: Cement
CPset_Phasing - Renovation Phase: Bestaand
Pset_SlabCommon - IsExternal: no; LoadBearing: no
Component Quantities - Cement, Mass: 31639 kg; Cement, Projected Component Area (Net): 238.048 m2; Cement, Projected Component Area (Gross): 233.437 m2; Cement, Component Thickness: 70 mm; Cement, Component Volume (Net): 16.6521 m3; Cement, Component Volume (Gross): 16.3406 m3
BaseQuantities - Width: 70 mm; Perimeter: 62956 mm; GrossArea: 244.416 m2; NetArea: 238.027 m2; GrossVolume: 17.0993 m3; NetVolume: 16.6521 m3

# IfcSlab: druklaag_70 70, Vloer-x
In: 01 dak
Classification: Vloer (ARCHICAD Classification); Material: Beton C
Pset_SlabCommon - IsExternal: no; LoadBearing: yes
CPset_Phasing - Renovation Phase: Bestaand
Component Quantities - Beton C, Mass: 29013.5 kg; Beton C, Projected Component Area (Net): 234.688 m2; Beton C, Projected Component Area (Gross): 238.64 m2; Beton C, Component Thickness: 70 mm; Beton C, Component Volume (Net): 12.089 m3; Beton C, Component Volume (Gross): 16.7048 m3
BaseQuantities - Width: 70 mm; Perimeter: 61800 mm; GrossArea: 238.64 m2; NetArea: 234.688 m2; GrossVolume: 12.3657 m3; NetVolume: 12.089 m3

# IfcSlab: kanaalplaatvloer-geisoleerd_350 350, begane grondvloer
In: 00 begane grond
Classification: Vloer (ARCHICAD Classification); 23.21 vrijdragende vloeren (NL/SfB (4 cijfers)); Material: Beton gewapend prefab vloer, Isolatie - EPS
Component Quantities - Beton gewapend prefab vloer, Mass: 117533 kg; Beton gewapend prefab vloer, Projected Component Area (Net): 244.86 m2; Beton gewapend prefab vloer, Projected Component Area (Gross): 244.86 m2; Beton gewapend prefab vloer, Component Thickness: 200 mm; Beton gewapend prefab vloer, Component Volume (Net): 48.972 m3; Beton gewapend prefab vloer, Component Volume (Gross): 48.972 m3; Isolatie - EPS, Mass: 5876.64 kg; Isolatie - EPS, Projected Component Area (Net): 244.86 m2; Isolatie - EPS, Projected Component Area (Gross): 244.86 m2; Isolatie - EPS, Component Thickness: 150 mm; Isolatie - EPS, Component Volume (Net): 36.729 m3; Isolatie - EPS, Component Volume (Gross): 36.729 m3
BaseQuantities - Width: 350 mm; Perimeter: 62600 mm; GrossArea: 244.86 m2; NetArea: 244.86 m2; GrossVolume: 85.701 m3; NetVolume: 85.701 m3
Pset_SlabCommon - IsExternal: yes; LoadBearing: yes
CPset_Phasing - Renovation Phase: Bestaand

# IfcSlab: plafondafwerking_50 50 (13)
In: 00 begane grond
Classification: Vloer (ARCHICAD Classification); Material: Plafondafwerking (2)
CPset_Phasing - Renovation Phase: Bestaand
BaseQuantities - Width: 50 mm
Pset_SlabCommon - IsExternal: no; LoadBearing: yes
Component Quantities - Plafondafwerking 1, Component Thickness: 25 mm; Plafondafwerking 2, Component Thickness: 25 mm
Name | Perimeter (mm) | GrossArea (m2) | NetArea (m2) = Plafondafwerking 1, Projected Component Area (Net) (m2) = Plafondafwerking 1, Projected Component Area (Gross) (m2) = Plafondafwerking 2, Projected Component Area (Gross) (m2) | GrossVolume (m3) | NetVolume (m3) | Plafondafwerking 1, Mass (kg) | Plafondafwerking 1, Component Volume (Net) (m3) = Plafondafwerking 1, Component Volume (Gross) (m3) = Plafondafwerking 2, Component Volume (Gross) (m3) | Plafondafwerking 2, Mass (kg) | Plafondafwerking 2, Projected Component Area (Net) (m2) | Plafondafwerking 2, Component Volume (Net) (m3)
plafondafwerking_04 | 21048 | 18.3629 | 18.3629 | 0.918147 | 0.918143 | 1055.86 | 0.459071 | 1055.86 | 18.3629 | 0.459071
Vloer-x | 7144 | 2.9745 | 2.97441 | 0.148725 | 0.14872 | 171.029 | 0.0743602 | 171.029 | 2.97441 | 0.0743602
Vloer-x | 9180 | 4.61813 | 4.61813 | 0.230907 | 0.230907 | 265.543 | 0.115453 | 265.543 | 4.61813 | 0.115453
Vloer-x | 9300 | 5.405 | 5.405 | 0.27025 | 0.27025 | 310.787 | 0.135125 | 310.787 | 5.405 | 0.135125
Vloer-x | 7800 | 3.7125 | 3.7125 | 0.185625 | 0.185625 | 213.469 | 0.0928125 | 213.469 | 3.7125 | 0.0928125
Vloer-x | 13562 | 6.4419 | 6.33841 | 0.32468 | 0.319505 | 364.459 | 0.15846 | 370.404 | 6.44181 | 0.161045
Vloer-x | 7300 | 2.225 | 2.21931 | 0.11125 | 0.110965 | 127.61 | 0.0554827 | 127.61 | 2.21931 | 0.0554827
3 x Vloer-x | 4700 | 1.375 | 1.375 | 0.06875 | 0.06875 | 79.0625 | 0.034375 | 79.0625 | 1.375 | 0.034375
Vloer-x | 7900 | 3.075 | 3.075 | 0.15375 | 0.15375 | 176.812 | 0.076875 | 176.813 | 3.075 | 0.076875
Vloer-x | 6300 | 2.255 | 2.255 | 0.11275 | 0.11275 | 129.662 | 0.056375 | 129.662 | 2.255 | 0.056375
plafondafwerking_06 | 6200 | 1.5925 | 1.5925 | 0.079625 | 0.079625 | 91.5688 | 0.0398125 | 91.5688 | 1.5925 | 0.0398125

# IfcSlab: vloerafwerking-tegels_9 9 (10)
In: 00 begane grond
Classification: Vloer (ARCHICAD Classification); Material: Tegels - Vloer
Pset_SlabCommon - IsExternal: no; LoadBearing: no
CPset_Phasing - Renovation Phase: Bestaand
Component Quantities - Tegels - Vloer, Component Thickness: 9 mm
BaseQuantities - Width: 9 mm
Name | Tegels - Vloer, Mass (kg) | Tegels - Vloer, Projected Component Area (Net) (m2) = NetArea (m2) | Tegels - Vloer, Projected Component Area (Gross) (m2) | Tegels - Vloer, Component Volume (Net) (m3) = NetVolume (m3) | Tegels - Vloer, Component Volume (Gross) (m3) | Perimeter (mm) | GrossArea (m2) | GrossVolume (m3)
vloerafwerking_02 | 428.636 | 20.7071 | 20.5822 | 0.186363 | 0.185239 | 26614 | 20.7456 | 0.186711
vloerafwerking_02 | 78.097 | 3.7728 | 3.7125 | 0.0339552 | 0.0334125 | 7934 | 3.7728 | 0.0339552
vloerafwerking_04 | 113.132 | 5.4653 | 5.405 | 0.0491877 | 0.048645 | 9434 | 5.4653 | 0.0491877
vloerafwerking_04 | 96.8435 | 4.67843 | 4.61813 | 0.0421059 | 0.0415632 | 9350 | 4.70991 | 0.0423892
vloerafwerking_02 | 78.5199 | 3.79323 | 3.62953 | 0.0341391 | 0.0326658 | 9266 | 3.79323 | 0.0341391
vloerafwerking_02 | 133.817 | 6.46461 | 6.33841 | 0.0581815 | 0.0570457 | 13696 | 6.5022 | 0.0585198
2 x vloerafwerking_02 | 0.61272 | 0.0296 | 0.0296 | 0.0002664 | 0.0002664 | 1560 | 0.0296 | 0.0002664
vloerafwerking_02 | 126.106 | 6.0921 | 5.825 | 0.0548289 | 0.052425 | 10734 | 6.2403 | 0.0561627
vloerafwerking_04 | 62.8185 | 3.03471 | 2.97441 | 0.0273124 | 0.0267697 | 7278 | 3.0348 | 0.0273132

# IfcSlab: vloerafwerking_9 9 (3)
In: 00 begane grond
Classification: Vloer (ARCHICAD Classification); Material: Vloerafwerking
CPset_Phasing - Renovation Phase: Bestaand
BaseQuantities - Width: 9 mm
Component Quantities - Vloerafwerking, Component Thickness: 9 mm
Pset_SlabCommon - IsExternal: no; LoadBearing: no
Name | Perimeter (mm) | GrossArea (m2) | NetArea (m2) = Vloerafwerking, Projected Component Area (Net) (m2) | GrossVolume (m3) | NetVolume (m3) = Vloerafwerking, Component Volume (Net) (m3) | Vloerafwerking, Mass (kg) | Vloerafwerking, Projected Component Area (Gross) (m2) | Vloerafwerking, Component Volume (Gross) (m3)
vloerafwerking_03 | 8016 | 3.47243 | 3.47243 | 0.0312519 | 0.0312519 | 71.8793 | 3.47243 | 0.0312519
vloerafwerking_03 | 7839.9 | 3.41517 | 3.40983 | 0.0307365 | 0.0306885 | 70.5835 | 3.2265 | 0.0290385
vloerafwerking_01 | 77916 | 197.821 | 173.02 | 1.78039 | 1.55718 | 3581.52 | 192.886 | 1.73598

# IfcWall: HSB WAND - 119/15.89.15 119 (3)
In: 00 begane grond
Classification: Wand (ARCHICAD Classification); Material: Hout - Multiplex (2), Isolatie - Steenwol zacht
Pset_WallCommon - IsExternal: yes; LoadBearing: no
CPset_Phasing - Renovation Phase: Bestaand
BaseQuantities - Height: 395 mm; Width: 119 mm
Component Quantities - Hout - Multiplex 1, Component Thickness: 15 mm; Hout - Multiplex 1, Rectangular Component Height: 395 mm; Hout - Multiplex 1, Rectangular Component Width: 15 mm; Hout - Multiplex 1, Component Cross Section Area: 0.005925 m2; Isolatie - Steenwol zacht, Component Thickness: 89 mm; Isolatie - Steenwol zacht, Rectangular Component Height: 395 mm; Isolatie - Steenwol zacht, Rectangular Component Width: 89 mm; Isolatie - Steenwol zacht, Component Cross Section Area: 0.035155 m2; Hout - Multiplex 2, Component Thickness: 15 mm; Hout - Multiplex 2, Rectangular Component Height: 395 mm; Hout - Multiplex 2, Rectangular Component Width: 15 mm; Hout - Multiplex 2, Component Cross Section Area: 0.005925 m2
Name | Length (mm) | GrossFootprintArea (m2) = NetFootprintArea (m2) | GrossSideArea (m2) = NetSideArea (m2) | GrossVolume (m3) = NetVolume (m3) | Hout - Multiplex 1, Mass (kg) | Hout - Multiplex 1, Projected Component Area (Net) (m2) = Hout - Multiplex 1, Projected Component Area (Gross) (m2) | Hout - Multiplex 1, Component Volume (Net) (m3) = Hout - Multiplex 1, Component Volume (Gross) (m3) | Isolatie - Steenwol zacht, Mass (kg) | Isolatie - Steenwol zacht, Projected Component Area (Net) (m2) = Isolatie - Steenwol zacht, Projected Component Area (Gross) (m2) | Isolatie - Steenwol zacht, Component Volume (Net) (m3) = Isolatie - Steenwol zacht, Component Volume (Gross) (m3) | Hout - Multiplex 2, Mass (kg) | Hout - Multiplex 2, Projected Component Area (Net) (m2) = Hout - Multiplex 2, Projected Component Area (Gross) (m2) | Hout - Multiplex 2, Component Volume (Net) (m3) = Hout - Multiplex 2, Component Volume (Gross) (m3)
Wand-x | 2669 | 0.325982 | 1.06018 | 0.128763 | 10.7006 | 1.0191 | 0.0152865 | 4.36309 | 1.08941 | 0.0969575 | 11.5632 | 1.10126 | 0.0165189
Wand-x | 1684.5 | 0.19627 | 0.662415 | 0.0775267 | 6.73969 | 0.641875 | 0.00962813 | 2.59444 | 0.6478 | 0.0576542 | 7.17103 | 0.682955 | 0.0102443
Wand-x | 1684.5 | 0.19627 | 0.662415 | 0.0775267 | 7.17103 | 0.682955 | 0.0102443 | 2.59444 | 0.6478 | 0.0576542 | 6.73969 | 0.641875 | 0.00962813

# IfcWall: HSB WAND - 74/15.44.15 74 (4)
In: 01 dak
Classification: Wand (ARCHICAD Classification); Material: Hout - Multiplex (2), Isolatie - Steenwol zacht
CPset_Phasing - Renovation Phase: Bestaand
BaseQuantities - Height: 290.006 mm; Width: 74 mm
Pset_WallCommon - IsExternal: yes; LoadBearing: no
Component Quantities - Hout - Multiplex 1, Component Thickness: 15 mm; Hout - Multiplex 1, Rectangular Component Height: 290.006 mm; Hout - Multiplex 1, Rectangular Component Width: 15 mm; Hout - Multiplex 1, Component Cross Section Area: 0.0043501 m2; Isolatie - Steenwol zacht, Component Thickness: 44 mm; Isolatie - Steenwol zacht, Rectangular Component Height: 290.006 mm; Isolatie - Steenwol zacht, Rectangular Component Width: 44 mm; Isolatie - Steenwol zacht, Component Cross Section Area: 0.0127603 m2; Hout - Multiplex 2, Component Thickness: 15 mm; Hout - Multiplex 2, Rectangular Component Height: 290.006 mm; Hout - Multiplex 2, Rectangular Component Width: 15 mm; Hout - Multiplex 2, Component Cross Section Area: 0.0043501 m2
Name | Length (mm) | GrossFootprintArea (m2) = NetFootprintArea (m2) | GrossSideArea (m2) = NetSideArea (m2) | GrossVolume (m3) = NetVolume (m3) | Hout - Multiplex 1, Mass (kg) | Hout - Multiplex 1, Projected Component Area (Net) (m2) = Hout - Multiplex 1, Projected Component Area (Gross) (m2) | Hout - Multiplex 1, Component Volume (Net) (m3) = Hout - Multiplex 1, Component Volume (Gross) (m3) | Isolatie - Steenwol zacht, Mass (kg) | Isolatie - Steenwol zacht, Projected Component Area (Net) (m2) = Isolatie - Steenwol zacht, Projected Component Area (Gross) (m2) | Isolatie - Steenwol zacht, Component Volume (Net) (m3) = Isolatie - Steenwol zacht, Component Volume (Gross) (m3) | Hout - Multiplex 2, Mass (kg) | Hout - Multiplex 2, Projected Component Area (Net) (m2) = Hout - Multiplex 2, Projected Component Area (Gross) (m2) | Hout - Multiplex 2, Component Volume (Net) (m3) = Hout - Multiplex 2, Component Volume (Gross) (m3)
Wand-x | 2624 | 0.194176 | 0.760977 | 0.0563123 | 7.8106 | 0.743866 | 0.011158 | 1.50673 | 0.760977 | 0.033483 | 8.16992 | 0.778087 | 0.0116713
Wand-x | 1624 | 0.120176 | 0.47097 | 0.0348518 | 4.76553 | 0.45386 | 0.0068079 | 0.932521 | 0.47097 | 0.0207227 | 5.12485 | 0.488081 | 0.00732121
Wand-x | 1624 | 0.122562 | 0.47532 | 0.0355438 | 4.81121 | 0.45821 | 0.00687315 | 0.957787 | 0.483731 | 0.0212841 | 5.17052 | 0.492431 | 0.00738646
Wand-x | 2624 | 0.19179 | 0.756627 | 0.0556203 | 7.76492 | 0.739516 | 0.0110927 | 1.48147 | 0.748217 | 0.0329215 | 8.12424 | 0.773737 | 0.0116061

# IfcWall: Hout C 50 (10)
In: 00 begane grond
Classification: Wand (ARCHICAD Classification); Material: Hout C
CPset_Phasing - Renovation Phase: Bestaand
Pset_WallCommon - IsExternal: no; LoadBearing: no
BaseQuantities - Length: 178 mm; Height: 3120 mm; Width: 50 mm; GrossFootprintArea: 0.0089 m2; NetFootprintArea: 0.0089 m2; GrossSideArea: 0.55536 m2; NetSideArea: 0.55536 m2; GrossVolume: 0.027768 m3; NetVolume: 0.027768 m3
Component Quantities - Hout C, Mass: 15.2724 kg; Hout C, Projected Component Area (Net): 0.55536 m2; Hout C, Projected Component Area (Gross): 0.55536 m2; Hout C, Component Thickness: 50 mm; Hout C, Rectangular Component Height: 3120 mm; Hout C, Rectangular Component Width: 50 mm; Hout C, Component Cross Section Area: 0.156 m2; Hout C, Component Volume (Net): 0.027768 m3; Hout C, Component Volume (Gross): 0.027768 m3

# IfcWall: Kunststof - massief 15 (4)
In: 01 dak
Material: Kunststof - massief
BaseQuantities - Length: 6980 mm; Height: 461.26 mm; Width: 15 mm; GrossFootprintArea: 0.1047 m2; NetFootprintArea: 0.1047 m2; GrossSideArea: 2.19339 m2; NetSideArea: 2.19339 m2; GrossVolume: 0.0329009 m3; NetVolume: 0.0329009 m3
Pset_WallCommon - IsExternal: yes; LoadBearing: no
CPset_Phasing - Renovation Phase: Bestaand
Component Quantities - Kunststof - massief, Mass: 45.7322 kg; Kunststof - massief, Projected Component Area (Net): 2.19339 m2; Kunststof - massief, Projected Component Area (Gross): 3.42051 m2; Kunststof - massief, Component Thickness: 15 mm; Kunststof - massief, Rectangular Component Height: 500 mm; Kunststof - massief, Rectangular Component Width: 15 mm; Kunststof - massief, Component Cross Section Area: 0.0075 m2; Kunststof - massief, Component Volume (Net): 0.0329009 m3; Kunststof - massief, Component Volume (Gross): 0.0513076 m3
Name | Classification
3 x Wand-x | Wand (ARCHICAD Classification)
lichtstraat | Wand (ARCHICAD Classification); 37.21 gesloten ramen (NL/SfB (4 cijfers))

# IfcWall: Membraan - waterdicht 5, legioblock
In: 00 begane grond
Classification: Wand (ARCHICAD Classification); 21.13 systeemwanden (NL/SfB (4 cijfers)); Material: Membraan - waterdicht
Component Quantities - Membraan - waterdicht, Mass: 40.362 kg; Membraan - waterdicht, Projected Component Area (Net): 7.688 m2; Membraan - waterdicht, Projected Component Area (Gross): 7.688 m2; Membraan - waterdicht, Component Thickness: 5 mm; Membraan - waterdicht, Rectangular Component Height: 1600 mm; Membraan - waterdicht, Rectangular Component Width: 5 mm; Membraan - waterdicht, Component Cross Section Area: 0.008 m2; Membraan - waterdicht, Component Volume (Net): 0.03844 m3; Membraan - waterdicht, Component Volume (Gross): 0.03844 m3
BaseQuantities - Length: 4805 mm; Height: 1600 mm; Width: 5 mm; GrossFootprintArea: 0.024025 m2; NetFootprintArea: 0.024025 m2; GrossSideArea: 7.688 m2; NetSideArea: 7.688 m2; GrossVolume: 0.03844 m3; NetVolume: 0.03844 m3
Pset_WallCommon - IsExternal: yes; LoadBearing: no
CPset_Phasing - Renovation Phase: Bestaand

# IfcWall: Metaal - Aluminium 5 (3)
In: 01 dak
Classification: Wand (ARCHICAD Classification); Material: Metaal - Aluminium
CPset_Phasing - Renovation Phase: Bestaand
Component Quantities - Metaal - Aluminium, Component Thickness: 5 mm; Metaal - Aluminium, Rectangular Component Height: 60 mm; Metaal - Aluminium, Rectangular Component Width: 5 mm; Metaal - Aluminium, Component Cross Section Area: 0.0003 m2
BaseQuantities - Height: 60 mm; Width: 5 mm
Pset_WallCommon - IsExternal: no; LoadBearing: no
Name | Metaal - Aluminium, Mass (kg) | Metaal - Aluminium, Projected Component Area (Net) (m2) = Metaal - Aluminium, Projected Component Area (Gross) (m2) = GrossSideArea (m2) = NetSideArea (m2) | Metaal - Aluminium, Component Volume (Net) (m3) = Metaal - Aluminium, Component Volume (Gross) (m3) = GrossVolume (m3) = NetVolume (m3) | Length (mm) | GrossFootprintArea (m2) = NetFootprintArea (m2)
Wand-x | 0.5208 | 0.0372 | 0.000186 | 615 | 0.0031
2 x Wand-x | 0.0462 | 0.0033 | 0.0000165 | 57.5 | 0.000275

# IfcWall: Wandeinde 1 27, Wandeinde-x
In: 00 begane grond
Classification: Wand (ARCHICAD Classification); Material: Hout - Multiplex
BaseQuantities - Height: 0 mm; Width: 0 mm; GrossSideArea: 0 m2; NetSideArea: 0 m2; GrossVolume: 0.00624 m3; NetVolume: 0.00624 m3
CPset_Phasing - Renovation Phase: Bestaand
Component Quantities - Hout - Multiplex, Mass: 4.368 kg; Hout - Multiplex, Component Volume (Net): 0.00624 m3; Hout - Multiplex, Component Volume (Gross): 0.00624 m3

# IfcWall: bepalting-volkern_8 8, volkernplaat
In: 00 begane grond
Classification: Wand (ARCHICAD Classification); Material: Hout - Spaanplaat
CPset_Phasing - Renovation Phase: Bestaand
Pset_WallCommon - IsExternal: yes; LoadBearing: no
BaseQuantities - Length: 2410 mm; Height: 1640 mm; Width: 8 mm; GrossFootprintArea: 0.0192 m2; NetFootprintArea: 0.0192 m2; GrossSideArea: 3.936 m2; NetSideArea: 3.936 m2; GrossVolume: 0.031488 m3; NetVolume: 0.031488 m3
Component Quantities - Hout - Spaanplaat, Mass: 18.8928 kg; Hout - Spaanplaat, Projected Component Area (Net): 3.936 m2; Hout - Spaanplaat, Projected Component Area (Gross): 3.936 m2; Hout - Spaanplaat, Component Thickness: 8 mm; Hout - Spaanplaat, Rectangular Component Height: 1640 mm; Hout - Spaanplaat, Rectangular Component Width: 8 mm; Hout - Spaanplaat, Component Cross Section Area: 0.01312 m2; Hout - Spaanplaat, Component Volume (Net): 0.031488 m3; Hout - Spaanplaat, Component Volume (Gross): 0.031488 m3

# IfcWall: beplating-aluminium_5 5 (8)
In: 01 dak
Classification: Wand (ARCHICAD Classification); Material: Metaal - Aluminium C
CPset_Phasing - Renovation Phase: Bestaand
BaseQuantities - Width: 5 mm
Pset_WallCommon - IsExternal: yes; LoadBearing: no
Component Quantities - Metaal - Aluminium C, Component Thickness: 5 mm; Metaal - Aluminium C, Rectangular Component Height: 814 mm; Metaal - Aluminium C, Rectangular Component Width: 5 mm; Metaal - Aluminium C, Component Cross Section Area: 0.00407 m2
Name | Length (mm) | Height (mm) | GrossFootprintArea (m2) = NetFootprintArea (m2) | GrossSideArea (m2) = NetSideArea (m2) = Metaal - Aluminium C, Projected Component Area (Net) (m2) = Metaal - Aluminium C, Projected Component Area (Gross) (m2) | GrossVolume (m3) = NetVolume (m3) = Metaal - Aluminium C, Component Volume (Net) (m3) = Metaal - Aluminium C, Component Volume (Gross) (m3) | Metaal - Aluminium C, Mass (kg)
Wand-x | 42975 | 814 | 0.214875 | 34.9817 | 0.174908 | 489.743
Wand-x | 6980 | 814 | 0.0349 | 5.6808 | 0.028404 | 79.5312
Wand-x | 6980 | 814 | 0.034925 | 5.68487 | 0.0284244 | 79.5882
Wand-x | 42975 | 630 | 0.21485 | 27.0711 | 0.135356 | 378.995
Wand-x | 6982.5 | 814 | 0.034925 | 5.68487 | 0.0284244 | 79.5882
Wand-x | 50175 | 814 | 0.250875 | 40.8425 | 0.204212 | 571.794
Wand-x | 50170 | 814 | 0.25085 | 40.8384 | 0.204192 | 571.737
Wand-x | 6982.5 | 814 | 0.0349 | 5.6808 | 0.028404 | 79.5312

# IfcWall: beplating-gips_12.5 13 (4)
In: 00 begane grond
Classification: Wand (ARCHICAD Classification); Material: Gipsplaat
CPset_Phasing - Renovation Phase: Bestaand
Pset_WallCommon - IsExternal: no; LoadBearing: no
BaseQuantities - Height: 3120 mm; Width: 12.5 mm
Component Quantities - Gipsplaat, Component Thickness: 12.5 mm; Gipsplaat, Rectangular Component Height: 3120 mm; Gipsplaat, Rectangular Component Width: 12.5 mm; Gipsplaat, Component Cross Section Area: 0.039 m2
Name | Length (mm) | GrossFootprintArea (m2) = NetFootprintArea (m2) | GrossSideArea (m2) = NetSideArea (m2) = Gipsplaat, Projected Component Area (Net) (m2) = Gipsplaat, Projected Component Area (Gross) (m2) | GrossVolume (m3) = NetVolume (m3) = Gipsplaat, Component Volume (Net) (m3) = Gipsplaat, Component Volume (Gross) (m3) | Gipsplaat, Mass (kg)
Wand-x | 1650 | 0.023125 | 5.15 | 0.064375 | 51.5
Wand-x | 1100 | 0.015 | 3.433 | 0.0429125 | 34.33
2 x Wand-x | 1100 | 0.01375 | 3.432 | 0.0429 | 34.32

# IfcWall: beplating-hout_18 18 (12)
In: 00 begane grond
Material: Hout AFW
CPset_Phasing - Renovation Phase: Bestaand
Component Quantities - Hout AFW, Component Thickness: 18 mm; Hout AFW, Rectangular Component Width: 18 mm
BaseQuantities - Width: 18 mm
Pset_WallCommon - IsExternal: no; LoadBearing: no
Name | Classification | Hout AFW, Mass (kg) | Hout AFW, Projected Component Area (Net) (m2) = Hout AFW, Projected Component Area (Gross) (m2) = GrossSideArea (m2) = NetSideArea (m2) | Hout AFW, Rectangular Component Height (mm) | Hout AFW, Component Cross Section Area (m2) | Hout AFW, Component Volume (Net) (m3) = Hout AFW, Component Volume (Gross) (m3) = GrossVolume (m3) = NetVolume (m3) | Length (mm) | Height (mm) | GrossFootprintArea (m2) = NetFootprintArea (m2)
Wand-x | Wand (ARCHICAD Classification) | 17.0766 | 1.72491 | 689.965 | 0.0124194 | 0.0310484 | 2500 | 689.965 | 0.045
Wand-x | Wand (ARCHICAD Classification) | 16.9228 | 1.70938 | 1139.97 | 0.0205194 | 0.0307688 | 1490.5 | 1139.97 | 0.026991
Wand-x | Wand (ARCHICAD Classification) | 28.011 | 2.82939 | 1139.97 | 0.0205194 | 0.0509291 | 2482 | 1139.97 | 0.044676
Wand-x | Wand (ARCHICAD Classification) | 16.7197 | 1.68886 | 1139.97 | 0.0205194 | 0.0303994 | 1490.5 | 1139.97 | 0.026667
Wand-x | Wand (ARCHICAD Classification) | 147.171 | 14.8658 | 3120 | 0.05616 | 0.267584 | 4771 | 3110 | 0.08604
Wand-x | Wand (ARCHICAD Classification) | 180.485 | 18.2308 | 3120 | 0.05616 | 0.328155 | 5771 | 3110 | 0.105516
beplating multiplex | Wand (ARCHICAD Classification); 42 BINNENWANDAFWERKINGEN (NL/SfB (4 cijfers)) | 8.316 | 0.84 | 2400 | 0.0432 | 0.01512 | 359 | 2400 | 0.0063
beplating multiplex | Wand (ARCHICAD Classification); 42 BINNENWANDAFWERKINGEN (NL/SfB (4 cijfers)) | 8.74368 | 0.8832 | 2400 | 0.0432 | 0.0158976 | 359 | 2400 | 0.006624
beplating multiplex | Wand (ARCHICAD Classification); 42 BINNENWANDAFWERKINGEN (NL/SfB (4 cijfers)) | 18.7229 | 1.8912 | 2400 | 0.0432 | 0.0340416 | 788 | 2400 | 0.014184
Wand-x | Wand (ARCHICAD Classification) | 58.4375 | 5.90278 | 3120 | 0.05616 | 0.10625 | 1898 | 3110 | 0.034164
Wand-x | Wand (ARCHICAD Classification) | 91.3266 | 9.22491 | 3689.97 | 0.0664194 | 0.166048 | 2500 | 3689.97 | 0.045
Wand-x | Wand (ARCHICAD Classification) | 74.25 | 7.5 | 3000 | 0.054 | 0.135 | 2500 | 3000 | 0.045

# IfcWall: beplating-volkern_20 20 (3)
In: 00 begane grond
Classification: Wand (ARCHICAD Classification); Material: Hout - Spaanplaat
CPset_Phasing - Renovation Phase: Bestaand
BaseQuantities - Width: 20 mm
Pset_WallCommon - IsExternal: yes; LoadBearing: no
Component Quantities - Hout - Spaanplaat, Component Thickness: 20 mm; Hout - Spaanplaat, Rectangular Component Width: 20 mm
Name | Length (mm) | Height (mm) = Hout - Spaanplaat, Rectangular Component Height (mm) | GrossFootprintArea (m2) = NetFootprintArea (m2) | GrossSideArea (m2) = NetSideArea (m2) = Hout - Spaanplaat, Projected Component Area (Net) (m2) = Hout - Spaanplaat, Projected Component Area (Gross) (m2) | GrossVolume (m3) = NetVolume (m3) = Hout - Spaanplaat, Component Volume (Net) (m3) = Hout - Spaanplaat, Component Volume (Gross) (m3) | Hout - Spaanplaat, Mass (kg) | Hout - Spaanplaat, Component Cross Section Area (m2)
volkernplaat | 628 | 2581 | 0.01456 | 1.87897 | 0.0375794 | 22.5476 | 0.05162
volkernplaat | 620 | 1640 | 0.0124 | 1.0168 | 0.020336 | 12.2016 | 0.0328
volkernplaat | 624 | 2590 | 0.01456 | 1.88552 | 0.0377104 | 22.6262 | 0.0518

# IfcWall: beton-ihwg-wand_400 400 (18)
In: 00 begane grond
Classification: 21.21 massieve wanden (NL/SfB (4 cijfers)); Wand (ARCHICAD Classification); Material: Beton gewapend C
CPset_Phasing - Renovation Phase: Bestaand
Pset_WallCommon - IsExternal: yes; LoadBearing: yes
BaseQuantities - Height: 4020 mm; Width: 400 mm
Component Quantities - Beton gewapend C, Component Thickness: 400 mm; Beton gewapend C, Rectangular Component Height: 4020 mm; Beton gewapend C, Rectangular Component Width: 400 mm; Beton gewapend C, Component Cross Section Area: 1.608 m2
Name | Length (mm) | GrossFootprintArea (m2) = NetFootprintArea (m2) | GrossSideArea (m2) | NetSideArea (m2) | GrossVolume (m3) | NetVolume (m3) = Beton gewapend C, Component Volume (Net) (m3) | Beton gewapend C, Mass (kg) | Beton gewapend C, Projected Component Area (Net) (m2) | Beton gewapend C, Projected Component Area (Gross) (m2) | Beton gewapend C, Component Volume (Gross) (m3)
3 x betonnen wand | 18040 | 7.1175 | 64.2213 | 64.2213 | 29.1478 | 29.1478 | 67040.1 | 73.3248 | 73.3248 | 29.3299
betonnen wand | 200 | 0.16 | 1.608 | 1.608 | 0.6432 | 0.6432 | 1479.36 | 1.608 | 1.608 | 0.6432
betonnen wand | 21640 | 8.5215 | 76.8573 | 76.8573 | 34.8999 | 34.8999 | 80269.8 | 87.7968 | 87.7968 | 35.1187
betonnen wand | 36010 | 14.1258 | 127.296 | 127.296 | 57.8603 | 57.8603 | 133079 | 145.564 | 145.564 | 58.2257
betonnen wand | 18040 | 6.71434 | 64.7537 | 62.2856 | 29.1585 | 28.1712 | 64793.8 | 70.8566 | 73.3248 | 29.3299
2 x betonnen wand | 18040 | 6.55434 | 63.1457 | 60.6776 | 28.5153 | 27.528 | 63314.5 | 69.2486 | 71.7168 | 28.6867
betonnen wand | 18040 | 7.1175 | 64.2213 | 64.2213 | 29.1479 | 29.1479 | 67040.1 | 73.3248 | 73.3248 | 29.3299
betonnen wand | 36040 | 13.9776 | 125.798 | 125.798 | 57.2652 | 57.2652 | 131710 | 144.077 | 144.077 | 57.6307
betonnen wand | 21610 | 8.3499 | 75.1491 | 75.1491 | 34.2089 | 34.2089 | 78680.5 | 86.0682 | 86.0682 | 34.4273
betonnen wand | 57400 | 22.23 | 200.07 | 200.07 | 91.0746 | 91.0746 | 209472 | 229.14 | 229.14 | 91.656
betonnen wand | 18040 | 6.96794 | 63.1457 | 60.6983 | 28.5153 | 27.5363 | 63333.5 | 69.2693 | 71.7168 | 28.6867
3 x betonnen wand | 600 | 0.234 | 2.106 | 2.106 | 0.95868 | 0.95868 | 2204.96 | 2.412 | 2.412 | 0.9648
betonnen wand | 22040 | 8.5965 | 77.4063 | 77.4063 | 35.2164 | 35.2164 | 80997.8 | 88.6008 | 88.6008 | 35.4403

# IfcWall: isolatie-PIR_100 100 (20)
In: 01 dak
Material: Isolatie - PIR
CPset_Phasing - Renovation Phase: Bestaand
BaseQuantities - Width: 100 mm
Pset_WallCommon - IsExternal: yes; LoadBearing: no
Component Quantities - Isolatie - PIR, Component Thickness: 100 mm; Isolatie - PIR, Rectangular Component Width: 100 mm
Name | Classification | Length (mm) | Height (mm) | GrossFootprintArea (m2) = NetFootprintArea (m2) | GrossSideArea (m2) = NetSideArea (m2) | GrossVolume (m3) = NetVolume (m3) = Isolatie - PIR, Component Volume (Net) (m3) | Isolatie - PIR, Mass (kg) | Isolatie - PIR, Projected Component Area (Net) (m2) | Isolatie - PIR, Projected Component Area (Gross) (m2) | Isolatie - PIR, Rectangular Component Height (mm) | Isolatie - PIR, Component Cross Section Area (m2) | Isolatie - PIR, Component Volume (Gross) (m3)
sandwichpaneel | Wand (ARCHICAD Classification); 21.13 systeemwanden (NL/SfB (4 cijfers)) | 57196 | 1054.96 | 5.7096 | 60.234 | 6.0234 | 963.745 | 60.234 | 60.234 | 1054.96 | 0.105496 | 6.0234
Wand-x | Wand (ARCHICAD Classification) | 15300 | 410 | 1.52 | 6.232 | 0.6232 | 99.712 | 6.232 | 6.232 | 410 | 0.041 | 0.6232
Wand-x | Wand (ARCHICAD Classification) | 15800 | 410 | 1.58 | 6.478 | 0.6478 | 103.648 | 6.478 | 6.478 | 410 | 0.041 | 0.6478
Wand-x | Wand (ARCHICAD Classification) | 15800 | 410 | 1.59 | 6.519 | 0.6519 | 104.304 | 6.519 | 6.519 | 410 | 0.041 | 0.6519
Wand-x | Wand (ARCHICAD Classification) | 15300 | 410 | 1.53 | 6.273 | 0.6273 | 100.368 | 6.273 | 6.273 | 410 | 0.041 | 0.6273
sandwichpaneel | Wand (ARCHICAD Classification); 21.13 systeemwanden (NL/SfB (4 cijfers)) | 42796 | 1054.96 | 3.77801 | 41.0503 | 4.42448 | 707.917 | 45.2536 | 45.2536 | 1054.96 | 0.105496 | 4.52536
sandwichpaneel | Wand (ARCHICAD Classification); 21.13 systeemwanden (NL/SfB (4 cijfers)) | 64396 | 1054.96 | 6.4396 | 67.9352 | 6.79352 | 1086.96 | 67.9352 | 67.9352 | 1054.96 | 0.105496 | 6.79352
sandwichpaneel | Wand (ARCHICAD Classification); 21.13 systeemwanden (NL/SfB (4 cijfers)) | 42796 | 1054.96 | 3.76801 | 40.9448 | 4.41393 | 706.229 | 45.1481 | 45.1481 | 1054.96 | 0.105496 | 4.51481
sandwichpaneel | Wand (ARCHICAD Classification); 21.13 systeemwanden (NL/SfB (4 cijfers)) | 64396 | 1054.96 | 6.4296 | 67.8297 | 6.78297 | 1085.28 | 67.8297 | 67.8297 | 1054.96 | 0.105496 | 6.78297
sandwichpaneel | Wand (ARCHICAD Classification); 21.13 systeemwanden (NL/SfB (4 cijfers)) | 42796 | 1054.96 | 0.0261169 | 36.8462 | 3.68462 | 589.54 | 36.8462 | 45.2536 | 1054.96 | 0.105496 | 4.52536
sandwichpaneel | Wand (ARCHICAD Classification); 21.13 systeemwanden (NL/SfB (4 cijfers)) | 43520 | 688 | 4.352 | 29.9418 | 2.99418 | 479.068 | 29.9418 | 29.9418 | 688 | 0.0688 | 2.99418
sandwichpaneel | Wand (ARCHICAD Classification); 21.13 systeemwanden (NL/SfB (4 cijfers)) | 57196 | 1054.96 | 5.7196 | 60.3395 | 6.03395 | 965.432 | 60.3395 | 60.3395 | 1054.96 | 0.105496 | 6.03395
sandwichpaneel | Wand (ARCHICAD Classification); 21.13 systeemwanden (NL/SfB (4 cijfers)) | 42796 | 1054.96 | 0.0161169 | 36.7408 | 3.67408 | 587.852 | 36.7408 | 45.1481 | 1054.96 | 0.105496 | 4.51481
sandwichpaneel | Wand (ARCHICAD Classification); 21.13 systeemwanden (NL/SfB (4 cijfers)) | 7520 | 688 | 0.682396 | 5.06171 | 0.515135 | 82.4216 | 5.17376 | 5.17376 | 688 | 0.0688 | 0.517376
2 x sandwichpaneel | Wand (ARCHICAD Classification); 21.13 systeemwanden (NL/SfB (4 cijfers)) | 7520 | 688 | 0.762 | 5.24256 | 0.524256 | 83.881 | 5.24256 | 5.24256 | 688 | 0.0688 | 0.524256
sandwichpaneel | Wand (ARCHICAD Classification); 21.13 systeemwanden (NL/SfB (4 cijfers)) | 50720 | 491.148 | 0 | 24.8641 | 2.48641 | 397.825 | 24.911 | 34.8954 | 688 | 0.0688 | 3.48954
sandwichpaneel | Wand (ARCHICAD Classification); 21.13 systeemwanden (NL/SfB (4 cijfers)) | 7520 | 688 | 0.752 | 5.17376 | 0.517376 | 82.7802 | 5.17376 | 5.17376 | 688 | 0.0688 | 0.517376
sandwichpaneel | Wand (ARCHICAD Classification); 21.13 systeemwanden (NL/SfB (4 cijfers)) | 43520 | 688 | 4.342 | 29.873 | 2.9873 | 477.967 | 29.873 | 29.873 | 688 | 0.0688 | 2.9873
sandwichpaneel | Wand (ARCHICAD Classification); 21.13 systeemwanden (NL/SfB (4 cijfers)) | 50720 | 688 | 5.062 | 34.8266 | 3.48266 | 557.225 | 34.8266 | 34.8266 | 688 | 0.0688 | 3.48266

# IfcWall: lego block_400 400, legioblokken
In: 00 begane grond
Classification: Wand (ARCHICAD Classification); 22.13 systeemwanden; vast (NL/SfB (4 cijfers)); Material: Steen - Legio block
CPset_Phasing - Renovation Phase: Bestaand
Pset_WallCommon - IsExternal: no; LoadBearing: no
BaseQuantities - Length: 1600 mm; Height: 4000 mm; Width: 400 mm; GrossFootprintArea: 0.64 m2; NetFootprintArea: 0.64 m2; GrossSideArea: 6.4 m2; NetSideArea: 6.4 m2; GrossVolume: 2.56 m3; NetVolume: 2.56 m3
Component Quantities - Steen - Legio block, Mass: 4864 kg; Steen - Legio block, Projected Component Area (Net): 6.4 m2; Steen - Legio block, Projected Component Area (Gross): 6.4 m2; Steen - Legio block, Component Thickness: 400 mm; Steen - Legio block, Rectangular Component Height: 4000 mm; Steen - Legio block, Rectangular Component Width: 400 mm; Steen - Legio block, Component Cross Section Area: 1.6 m2; Steen - Legio block, Component Volume (Net): 2.56 m3; Steen - Legio block, Component Volume (Gross): 2.56 m3

# IfcWall: lego block_800 800 (32)
In: 00 begane grond
Material: Steen - Legio block
Component Quantities - Steen - Legio block, Component Thickness: 800 mm; Steen - Legio block, Rectangular Component Width: 800 mm
BaseQuantities - Width: 800 mm
Pset_WallCommon - LoadBearing: no
CPset_Phasing - Renovation Phase: Bestaand
Name | Classification | Steen - Legio block, Mass (kg) | Steen - Legio block, Projected Component Area (Net) (m2) = Steen - Legio block, Projected Component Area (Gross) (m2) = GrossSideArea (m2) = NetSideArea (m2) | Steen - Legio block, Rectangular Component Height (mm) = Height (mm) | Steen - Legio block, Component Cross Section Area (m2) | Steen - Legio block, Component Volume (Net) (m3) = Steen - Legio block, Component Volume (Gross) (m3) = GrossVolume (m3) = NetVolume (m3) | Length (mm) | GrossFootprintArea (m2) = NetFootprintArea (m2) | IsExternal
4 x legioblokken | Wand (ARCHICAD Classification); 22.13 systeemwanden; vast (NL/SfB (4 cijfers)) | 107008 | 70.4 | 4000 | 3.2 | 56.32 | 17600 | 14.08 | no
legioblokken | Wand (ARCHICAD Classification); 22.13 systeemwanden; vast (NL/SfB (4 cijfers)) | 97280 | 64 | 4000 | 3.2 | 51.2 | 16000 | 12.8 | no
legioblokken | Wand (ARCHICAD Classification); 22.13 systeemwanden; vast (NL/SfB (4 cijfers)) | 53504 | 35.2 | 4000 | 3.2 | 28.16 | 8800 | 7.04 | no
26 x legioblock (aanrijdbeveiliging) | Wand (ARCHICAD Classification); 71 Vaste verkeersvoorzieningen (NL/SfB (4 cijfers)) | 972.8 | 0.64 | 800 | 0.64 | 0.512 | 800 | 0.64 | yes

# IfcWall: metalstudwand-geisoleerd_100 100 (46)
In: 00 begane grond
Material: Gipsplaat (2), Isolatie - Steenwol LSW
Component Quantities - Gipsplaat 2, Component Thickness: 12.5 mm; Gipsplaat 2, Rectangular Component Width: 12.5 mm; Isolatie - Steenwol LSW, Component Thickness: 75 mm; Isolatie - Steenwol LSW, Rectangular Component Width: 75 mm; Gipsplaat 1, Component Thickness: 12.5 mm; Gipsplaat 1, Rectangular Component Width: 12.5 mm
BaseQuantities - Width: 100 mm
CPset_Phasing - Renovation Phase: Bestaand
Pset_WallCommon - IsExternal: no; LoadBearing: no
Name | Classification | Gipsplaat 2, Mass (kg) | Gipsplaat 2, Projected Component Area (Net) (m2) | Gipsplaat 2, Projected Component Area (Gross) (m2) | Gipsplaat 2, Rectangular Component Height (mm) = Isolatie - Steenwol LSW, Rectangular Component Height (mm) = Gipsplaat 1, Rectangular Component Height (mm) | Gipsplaat 2, Component Cross Section Area (m2) = Gipsplaat 1, Component Cross Section Area (m2) | Gipsplaat 2, Component Volume (Net) (m3) | Gipsplaat 2, Component Volume (Gross) (m3) | Isolatie - Steenwol LSW, Mass (kg) | Isolatie - Steenwol LSW, Projected Component Area (Net) (m2) | Isolatie - Steenwol LSW, Projected Component Area (Gross) (m2) | Isolatie - Steenwol LSW, Component Cross Section Area (m2) | Isolatie - Steenwol LSW, Component Volume (Net) (m3) | Isolatie - Steenwol LSW, Component Volume (Gross) (m3) | Gipsplaat 1, Mass (kg) | Gipsplaat 1, Projected Component Area (Net) (m2) | Gipsplaat 1, Projected Component Area (Gross) (m2) | Gipsplaat 1, Component Volume (Net) (m3) | Gipsplaat 1, Component Volume (Gross) (m3) | Length (mm) | Height (mm) | GrossFootprintArea (m2) = NetFootprintArea (m2) | GrossSideArea (m2) | NetSideArea (m2) | GrossVolume (m3) | NetVolume (m3)
Wand-x | Wand (ARCHICAD Classification) | 5.122 | 0.5122 | 3.4814 | 3050 | 0.038125 | 0.0064025 | 0.0435175 | 2.11163 | 0.5122 | 3.4814 | 0.22875 | 0.0383933 | 0.261083 | 4.97675 | 0.497675 | 3.46687 | 0.00622094 | 0.0433359 | 1142 | 450 | 0.00300872 | 3.47414 | 0.504937 | 0.347937 | 0.0510167
Wand-x | Wand (ARCHICAD Classification) | 5.122 | 0.5122 | 3.4814 | 3050 | 0.038125 | 0.0064025 | 0.0435175 | 2.10843 | 0.5122 | 3.4814 | 0.22875 | 0.0383351 | 0.261025 | 4.97675 | 0.497675 | 3.46687 | 0.00622094 | 0.0433359 | 1142 | 450 | 0.00387 | 3.47414 | 0.504937 | 0.347879 | 0.0509585
Wand-x | Wand (ARCHICAD Classification) | 10.71 | 1.071 | 7.259 | 3050 | 0.038125 | 0.0133875 | 0.0907375 | 4.41788 | 1.071 | 7.259 | 0.22875 | 0.080325 | 0.544425 | 10.71 | 1.071 | 7.259 | 0.0133875 | 0.0907375 | 2380 | 450 | 0 | 7.259 | 1.071 | 0.7259 | 0.1071
metalstudwand | Wand (ARCHICAD Classification); 22.23 systeemwanden; vast (NL/SfB (4 cijfers)) | 16.588 | 1.6588 | 11.7247 | 3110 | 0.038875 | 0.020735 | 0.146559 | 6.74215 | 1.6588 | 11.7247 | 0.23325 | 0.122585 | 0.877527 | 16.1012 | 1.61012 | 11.676 | 0.0201265 | 0.14595 | 3770 | 440 | 0.0125 | 11.7004 | 1.63446 | 1.17004 | 0.163446
metalstudwand | Wand (ARCHICAD Classification); 22.23 systeemwanden; vast (NL/SfB (4 cijfers)) | 16.588 | 1.6588 | 11.7247 | 3110 | 0.038875 | 0.020735 | 0.146559 | 6.84255 | 1.6588 | 11.7247 | 0.23325 | 0.12441 | 0.879352 | 16.588 | 1.6588 | 11.7247 | 0.020735 | 0.146559 | 3770 | 440 | 0 | 11.7247 | 1.6588 | 1.17247 | 0.16588
metalstudwand | Wand (ARCHICAD Classification); 22.23 systeemwanden; vast (NL/SfB (4 cijfers)) | 6.46587 | 0.646587 | 4.49139 | 3120 | 0.039 | 0.00808234 | 0.0561423 | 2.66717 | 0.646587 | 4.49139 | 0.234 | 0.048494 | 0.336854 | 5.57355 | 0.646587 | 4.49139 | 0.00696694 | 0.0550269 | 1440 | 450 | 0.01716 | 4.44491 | 0.600112 | 0.448023 | 0.0635433
metalstudwand | Wand (ARCHICAD Classification); 22.23 systeemwanden; vast (NL/SfB (4 cijfers)) | 124.668 | 12.4668 | 15.2276 | 3120 | 0.039 | 0.155835 | 0.190345 | 51.4257 | 12.4668 | 15.2276 | 0.234 | 0.935013 | 1.14207 | 124.668 | 12.4668 | 15.2276 | 0.155835 | 0.190345 | 4900 | 3120 | 0.3848 | 15.2276 | 12.4668 | 1.52276 | 1.24668
metalstudwand | Wand (ARCHICAD Classification); 22.23 systeemwanden; vast (NL/SfB (4 cijfers)) | 59.28 | 5.928 | 5.928 | 3120 | 0.039 | 0.0741 | 0.0741 | 24.453 | 5.928 | 5.928 | 0.234 | 0.4446 | 0.4446 | 59.28 | 5.928 | 5.928 | 0.0741 | 0.0741 | 1900 | 3120 | 0.19 | 5.928 | 5.928 | 0.5928 | 0.5928
metalstudwand | Wand (ARCHICAD Classification); 22.23 systeemwanden; vast (NL/SfB (4 cijfers)) | 31.4137 | 3.14137 | 5.928 | 3120 | 0.039 | 0.0392671 | 0.0741 | 12.9582 | 3.14137 | 5.928 | 0.234 | 0.235603 | 0.4446 | 31.4137 | 3.14137 | 5.928 | 0.0392671 | 0.0741 | 1900 | 3120 | 0.19 | 5.928 | 3.14137 | 0.5928 | 0.314137
2 x metalstudwand | Wand (ARCHICAD Classification); 22.23 systeemwanden; vast (NL/SfB (4 cijfers)) | 17.16 | 1.716 | 1.716 | 3120 | 0.039 | 0.02145 | 0.02145 | 7.0785 | 1.716 | 1.716 | 0.234 | 0.1287 | 0.1287 | 17.16 | 1.716 | 1.716 | 0.02145 | 0.02145 | 550 | 3120 | 0.055 | 1.716 | 1.716 | 0.1716 | 0.1716
metalstudwand | Wand (ARCHICAD Classification); 22.23 systeemwanden; vast (NL/SfB (4 cijfers)) | 120.479 | 12.0479 | 12.0479 | 3120 | 0.039 | 0.150599 | 0.150599 | 49.5368 | 12.0089 | 12.0089 | 0.234 | 0.900669 | 0.900669 | 117.749 | 11.7749 | 11.7749 | 0.147186 | 0.147186 | 3812 | 3120 | 0.384169 | 11.9114 | 11.9114 | 1.19845 | 1.19845
metalstudwand | Wand (ARCHICAD Classification); 22.23 systeemwanden; vast (NL/SfB (4 cijfers)) | 72.604 | 7.2604 | 7.2604 | 3120 | 0.039 | 0.090755 | 0.090755 | 28.9839 | 7.0264 | 7.0264 | 0.234 | 0.52698 | 0.52698 | 69.874 | 6.9874 | 6.9874 | 0.0873425 | 0.0873425 | 2290 | 3120 | 0.226031 | 7.1239 | 7.1239 | 0.705077 | 0.705077
metalstudwand | Wand (ARCHICAD Classification); 22.23 systeemwanden; vast (NL/SfB (4 cijfers)) | 70.185 | 7.0185 | 7.0185 | 3120 | 0.039 | 0.0877312 | 0.0877312 | 28.9513 | 7.0185 | 7.0185 | 0.234 | 0.526387 | 0.526387 | 70.185 | 7.0185 | 7.0185 | 0.0877313 | 0.0877313 | 2250 | 3120 | 0.225 | 7.0185 | 7.0185 | 0.70185 | 0.70185
metalstudwand | Wand (ARCHICAD Classification); 22.23 systeemwanden; vast (NL/SfB (4 cijfers)) | 77.75 | 7.775 | 7.775 | 3110 | 0.038875 | 0.0971875 | 0.0971875 | 31.7512 | 7.69725 | 7.69725 | 0.23325 | 0.577294 | 0.577294 | 72.3075 | 7.23075 | 7.23075 | 0.0903844 | 0.0903844 | 2400 | 3110 | 0.245938 | 7.50288 | 7.50288 | 0.764866 | 0.764866
metalstudwand | Wand (ARCHICAD Classification); 22.23 systeemwanden; vast (NL/SfB (4 cijfers)) | 202.883 | 20.2883 | 23.0491 | 3120 | 0.039 | 0.253604 | 0.288114 | 82.5664 | 20.0161 | 22.7769 | 0.234 | 1.50121 | 1.70827 | 197.432 | 19.7432 | 22.504 | 0.24679 | 0.2813 | 7300 | 3120 | 0.634569 | 22.7766 | 20.0158 | 2.27768 | 2.0016
metalstudwand | Wand (ARCHICAD Classification); 22.23 systeemwanden; vast (NL/SfB (4 cijfers)) | 16.5544 | 1.65544 | 7.177 | 3120 | 0.039 | 0.020693 | 0.0897125 | 6.82869 | 1.65544 | 7.177 | 0.234 | 0.124158 | 0.538275 | 16.5544 | 1.65544 | 7.177 | 0.020693 | 0.0897125 | 2300 | 3120 | 0.0332 | 7.177 | 1.65544 | 0.7177 | 0.165544
metalstudwand | Wand (ARCHICAD Classification); 22.23 systeemwanden; vast (NL/SfB (4 cijfers)) | 20.2787 | 2.02787 | 2.02787 | 3120 | 0.039 | 0.0253484 | 0.0253484 | 8.36189 | 2.02712 | 2.02712 | 0.234 | 0.152034 | 0.152034 | 14.05 | 1.405 | 1.405 | 0.0175625 | 0.0175625 | 650 | 3120 | 0.06375 | 1.71644 | 1.71644 | 0.194945 | 0.194945
metalstudwand | Wand (ARCHICAD Classification); 22.23 systeemwanden; vast (NL/SfB (4 cijfers)) | 225.859 | 22.5859 | 30.8683 | 3110 | 0.038875 | 0.282324 | 0.385853 | 92.1985 | 22.3512 | 30.6335 | 0.23325 | 1.67634 | 2.29751 | 220.79 | 22.079 | 30.3614 | 0.275988 | 0.379517 | 9850 | 3110 | 0.6748 | 30.6148 | 22.3325 | 3.06288 | 2.23465
metalstudwand | Wand (ARCHICAD Classification); 22.23 systeemwanden; vast (NL/SfB (4 cijfers)) | 16.546 | 1.6546 | 1.6546 | 3120 | 0.039 | 0.0206825 | 0.0206825 | 9.23062 | 2.23772 | 2.23772 | 0.234 | 0.167829 | 0.167829 | 20.0447 | 2.00447 | 2.00447 | 0.0250559 | 0.0250559 | 680 | 3120 | 0.0697188 | 1.82954 | 1.82954 | 0.213568 | 0.213568
metalstudwand | Wand (ARCHICAD Classification); 22.23 systeemwanden; vast (NL/SfB (4 cijfers)) | 75.1608 | 7.51608 | 7.51608 | 3110 | 0.038875 | 0.093951 | 0.093951 | 31.3245 | 7.59383 | 7.59383 | 0.23325 | 0.569537 | 0.569537 | 80.6033 | 8.06033 | 8.06033 | 0.100754 | 0.100754 | 2550 | 3110 | 0.249063 | 7.78821 | 7.78821 | 0.764242 | 0.764242
metalstudwand | Wand (ARCHICAD Classification); 22.23 systeemwanden; vast (NL/SfB (4 cijfers)) | 6.13138 | 0.6466 | 4.4914 | 3120 | 0.039 | 0.00766422 | 0.0557242 | 2.58799 | 0.6466 | 4.4914 | 0.234 | 0.0470543 | 0.335414 | 6.466 | 0.6466 | 4.4914 | 0.0080825 | 0.0561425 | 1440 | 450 | 0.0286 | 4.4914 | 0.6466 | 0.447281 | 0.062801
metalstudwand | Wand (ARCHICAD Classification); 22.23 systeemwanden; vast (NL/SfB (4 cijfers)) | 37.45 | 3.745 | 3.745 | 3120 | 0.039 | 0.0468125 | 0.0468125 | 15.2872 | 3.706 | 3.706 | 0.234 | 0.27795 | 0.27795 | 34.72 | 3.472 | 3.472 | 0.0434 | 0.0434 | 1150 | 3120 | 0.127969 | 3.6085 | 3.6085 | 0.368162 | 0.368162
metalstudwand | Wand (ARCHICAD Classification); 22.23 systeemwanden; vast (NL/SfB (4 cijfers)) | 45.24 | 4.524 | 4.524 | 3120 | 0.039 | 0.05655 | 0.05655 | 18.6615 | 4.524 | 4.524 | 0.234 | 0.3393 | 0.3393 | 45.24 | 4.524 | 4.524 | 0.05655 | 0.05655 | 1450 | 3120 | 0.145 | 4.524 | 4.524 | 0.4524 | 0.4524
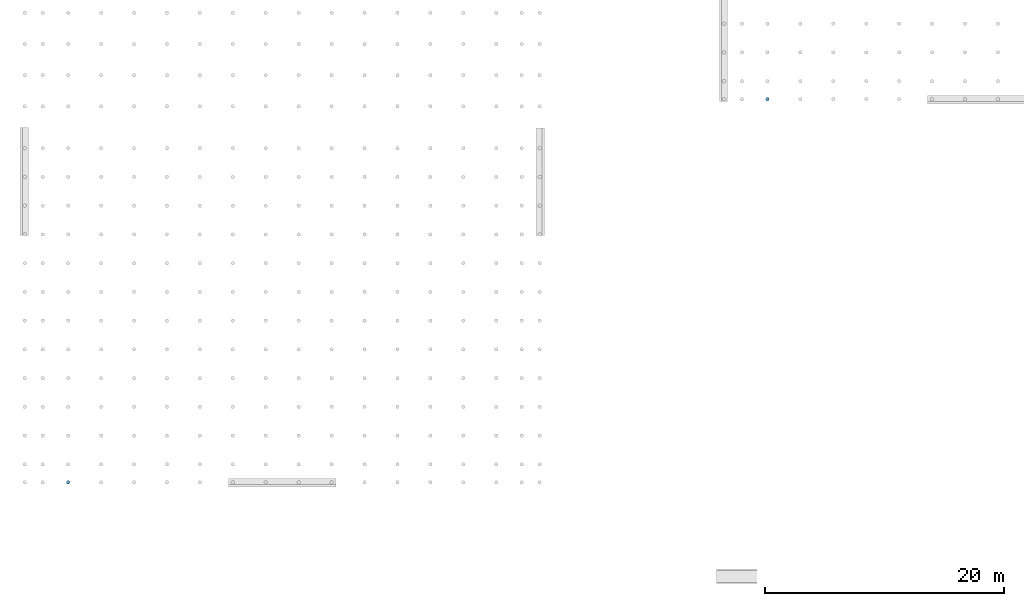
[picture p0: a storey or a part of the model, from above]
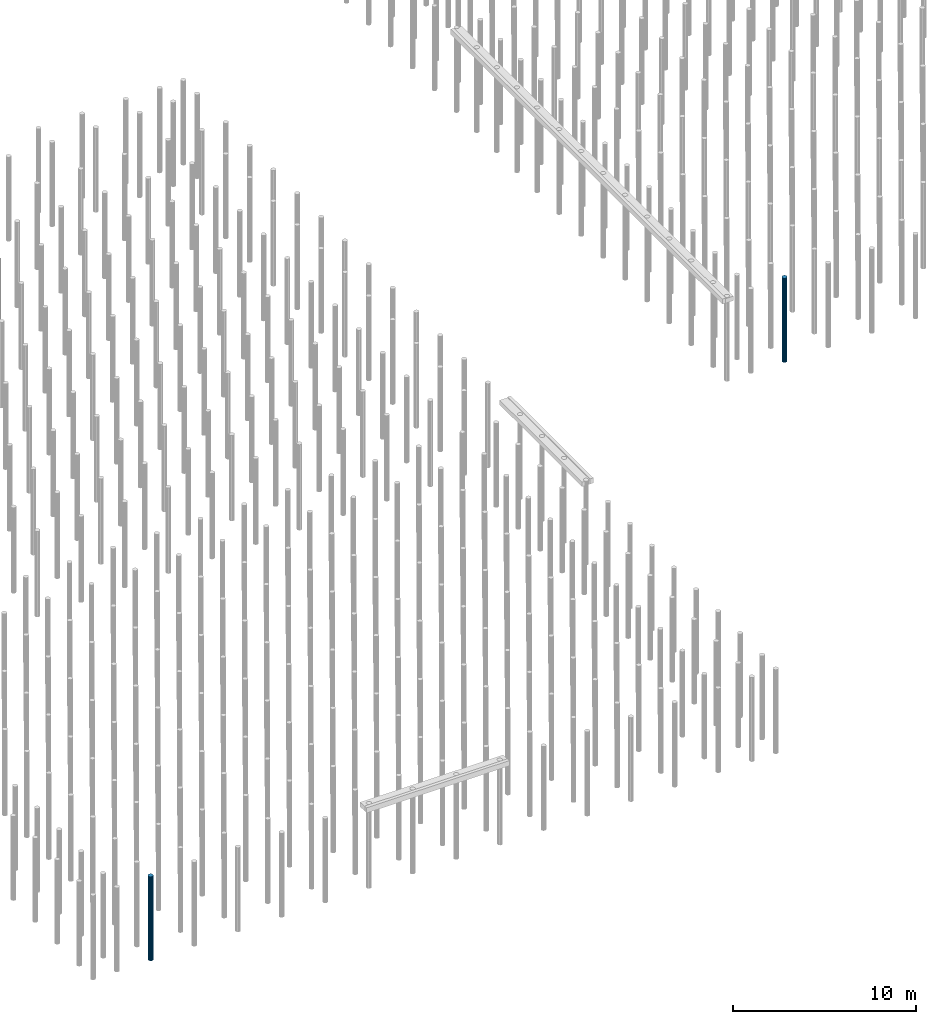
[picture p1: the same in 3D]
Properties of the parts of a building model (IFC2X3), part 13 of 13

# IfcWall: metalstudwand-geisoleerd_100 100 (46)
Name | Classification | Gipsplaat 2, Mass (kg) | Gipsplaat 2, Projected Component Area (Net) (m2) | Gipsplaat 2, Projected Component Area (Gross) (m2) | Gipsplaat 2, Rectangular Component Height (mm) = Isolatie - Steenwol LSW, Rectangular Component Height (mm) = Gipsplaat 1, Rectangular Component Height (mm) | Gipsplaat 2, Component Cross Section Area (m2) = Gipsplaat 1, Component Cross Section Area (m2) | Gipsplaat 2, Component Volume (Net) (m3) | Gipsplaat 2, Component Volume (Gross) (m3) | Isolatie - Steenwol LSW, Mass (kg) | Isolatie - Steenwol LSW, Projected Component Area (Net) (m2) | Isolatie - Steenwol LSW, Projected Component Area (Gross) (m2) | Isolatie - Steenwol LSW, Component Cross Section Area (m2) | Isolatie - Steenwol LSW, Component Volume (Net) (m3) | Isolatie - Steenwol LSW, Component Volume (Gross) (m3) | Gipsplaat 1, Mass (kg) | Gipsplaat 1, Projected Component Area (Net) (m2) | Gipsplaat 1, Projected Component Area (Gross) (m2) | Gipsplaat 1, Component Volume (Net) (m3) | Gipsplaat 1, Component Volume (Gross) (m3) | Length (mm) | Height (mm) | GrossFootprintArea (m2) = NetFootprintArea (m2) | GrossSideArea (m2) | NetSideArea (m2) | GrossVolume (m3) | NetVolume (m3)
metalstudwand | Wand (ARCHICAD Classification); 22.23 systeemwanden; vast (NL/SfB (4 cijfers)) | 39.0822 | 3.90822 | 6.669 | 3120 | 0.039 | 0.0488528 | 0.0833625 | 15.1562 | 3.67422 | 6.435 | 0.234 | 0.275567 | 0.482625 | 36.3522 | 3.63522 | 6.396 | 0.0454402 | 0.07995 | 2100 | 3120 | 0.103631 | 6.5325 | 3.77172 | 0.645938 | 0.36986
metalstudwand | Wand (ARCHICAD Classification); 22.23 systeemwanden; vast (NL/SfB (4 cijfers)) | 34.32 | 3.432 | 3.432 | 3120 | 0.039 | 0.0429 | 0.0429 | 14.157 | 3.432 | 3.432 | 0.234 | 0.2574 | 0.2574 | 34.32 | 3.432 | 3.432 | 0.0429 | 0.0429 | 1100 | 3120 | 0.11 | 3.432 | 3.432 | 0.3432 | 0.3432
metalstudwand | Wand (ARCHICAD Classification); 22.23 systeemwanden; vast (NL/SfB (4 cijfers)) | 31.3534 | 3.13534 | 5.89612 | 3120 | 0.039 | 0.0391917 | 0.0737015 | 12.7724 | 3.09634 | 5.85712 | 0.234 | 0.232225 | 0.439284 | 28.6234 | 2.86234 | 5.62312 | 0.0357792 | 0.070289 | 1840 | 3120 | 0.0885687 | 5.75962 | 2.99884 | 0.583274 | 0.307196
metalstudwand | Wand (ARCHICAD Classification); 22.23 systeemwanden; vast (NL/SfB (4 cijfers)) | 33.1667 | 3.31667 | 6.04142 | 3120 | 0.039 | 0.0414583 | 0.0755177 | 12.716 | 3.08267 | 5.80742 | 0.234 | 0.2312 | 0.435556 | 30.4367 | 3.04367 | 5.76842 | 0.0380458 | 0.0721052 | 1900 | 3120 | 0.187031 | 5.90492 | 3.18017 | 0.583179 | 0.310704
metalstudwand | Wand (ARCHICAD Classification); 22.23 systeemwanden; vast (NL/SfB (4 cijfers)) | 21.4341 | 2.14341 | 14.8793 | 3120 | 0.039 | 0.0267927 | 0.185991 | 8.84158 | 2.14341 | 14.8793 | 0.234 | 0.160756 | 1.11595 | 21.4341 | 2.14341 | 14.8793 | 0.0267927 | 0.185991 | 4770 | 450 | 0 | 14.8793 | 2.14341 | 1.48793 | 0.214341
metalstudwand | Wand (ARCHICAD Classification); 22.23 systeemwanden; vast (NL/SfB (4 cijfers)) | 60.4413 | 6.04413 | 6.04413 | 3120 | 0.039 | 0.0755516 | 0.0755516 | 21.4041 | 5.18888 | 5.18888 | 0.234 | 0.389166 | 0.389166 | 51.5 | 5.15 | 5.15 | 0.064375 | 0.064375 | 1700 | 3120 | 0.18625 | 5.59706 | 5.59706 | 0.529092 | 0.529092
metalstudwand | Wand (ARCHICAD Classification); 22.23 systeemwanden; vast (NL/SfB (4 cijfers)) | 51.5 | 5.15 | 5.15 | 3120 | 0.039 | 0.064375 | 0.064375 | 21.2438 | 5.15 | 5.15 | 0.234 | 0.38625 | 0.38625 | 57.72 | 5.772 | 5.772 | 0.07215 | 0.07215 | 1650 | 3120 | 0.18625 | 5.461 | 5.461 | 0.522775 | 0.522775
metalstudwand | Wand (ARCHICAD Classification); 22.23 systeemwanden; vast (NL/SfB (4 cijfers)) | 16.588 | 1.6588 | 11.7247 | 3110 | 0.038875 | 0.020735 | 0.146559 | 6.84255 | 1.6588 | 11.7247 | 0.23325 | 0.12441 | 0.879352 | 15.6832 | 1.6588 | 11.7247 | 0.019604 | 0.145428 | 3770 | 440 | 0.01885 | 11.6116 | 1.5457 | 1.17134 | 0.164749
2 x metalstudwand | Wand (ARCHICAD Classification); 22.23 systeemwanden; vast (NL/SfB (4 cijfers)) | 17.072 | 1.7072 | 12.0668 | 3110 | 0.038875 | 0.02134 | 0.150835 | 7.0422 | 1.7072 | 12.0668 | 0.23325 | 0.12804 | 0.90501 | 17.072 | 1.7072 | 12.0668 | 0.02134 | 0.150835 | 3880 | 440 | 0 | 12.0668 | 1.7072 | 1.20668 | 0.17072
metalstudwand | Wand (ARCHICAD Classification); 22.23 systeemwanden; vast (NL/SfB (4 cijfers)) | 34.4235 | 3.44236 | 11.7247 | 3110 | 0.038875 | 0.0430294 | 0.146559 | 14.1997 | 3.44236 | 11.7247 | 0.23325 | 0.258177 | 0.879352 | 34.4236 | 3.44236 | 11.7247 | 0.0430295 | 0.146559 | 3770 | 3110 | 0.0668 | 11.7247 | 3.44236 | 1.17247 | 0.344236
metalstudwand | Wand (ARCHICAD Classification); 22.23 systeemwanden; vast (NL/SfB (4 cijfers)) | 65.4524 | 6.54524 | 12.0668 | 3110 | 0.038875 | 0.0818155 | 0.150835 | 26.9991 | 6.54524 | 12.0668 | 0.23325 | 0.490893 | 0.90501 | 65.4523 | 6.54524 | 12.0668 | 0.0818154 | 0.150835 | 3880 | 3110 | 0.1812 | 12.0668 | 6.54524 | 1.20668 | 0.654524
metalstudwand | Wand (ARCHICAD Classification); 22.23 systeemwanden; vast (NL/SfB (4 cijfers)) | 17.072 | 1.7072 | 12.0668 | 3110 | 0.038875 | 0.02134 | 0.150835 | 6.9418 | 1.7072 | 12.0668 | 0.23325 | 0.126215 | 0.903185 | 16.5852 | 1.65852 | 12.0181 | 0.0207315 | 0.150227 | 3880 | 440 | 0.0125 | 12.0425 | 1.68286 | 1.20425 | 0.168286
metalstudwand | Wand (ARCHICAD Classification); 22.23 systeemwanden; vast (NL/SfB (4 cijfers)) | 15.6302 | 1.56302 | 1.56302 | 3120 | 0.039 | 0.0195377 | 0.0195377 | 6.28657 | 1.52402 | 1.52402 | 0.234 | 0.114301 | 0.114301 | 12.9002 | 1.29002 | 1.29002 | 0.0161252 | 0.0161252 | 451.448 | 3120 | 0.0481135 | 1.42652 | 1.42652 | 0.149964 | 0.149964
metalstudwand | Wand (ARCHICAD Classification); 22.23 systeemwanden; vast (NL/SfB (4 cijfers)) | 39.8428 | 3.98428 | 3.98428 | 3120 | 0.039 | 0.0498035 | 0.0498035 | 15.4699 | 3.75028 | 3.75028 | 0.234 | 0.281271 | 0.281271 | 37.1128 | 3.71128 | 3.71128 | 0.046391 | 0.046391 | 1240 | 3120 | 0.121031 | 3.84778 | 3.84778 | 0.377465 | 0.377465
metalstudwand | Wand (ARCHICAD Classification); 22.23 systeemwanden; vast (NL/SfB (4 cijfers)) | 12.3875 | 1.23875 | 1.23875 | 3120 | 0.039 | 0.0154843 | 0.0154843 | 6.0596 | 1.469 | 1.469 | 0.234 | 0.110175 | 0.110175 | 15.0737 | 1.50737 | 1.50737 | 0.0188421 | 0.0188421 | 441 | 3070 | 0.0470687 | 1.37306 | 1.37306 | 0.144501 | 0.144501
metalstudwand | Wand (ARCHICAD Classification); 22.23 systeemwanden; vast (NL/SfB (4 cijfers)) | 5.85755 | 0.585755 | 3.27416 | 3120 | 0.039 | 0.00732194 | 0.0409269 | 3.52432 | 0.85438 | 3.54278 | 0.234 | 0.0640785 | 0.265709 | 11.23 | 1.123 | 3.8114 | 0.0140376 | 0.0476426 | 1154 | 3070 | 0.1154 | 3.54278 | 0.85438 | 0.354278 | 0.085438
metalstudwand | Wand (ARCHICAD Classification); 22.23 systeemwanden; vast (NL/SfB (4 cijfers)) | 5.85755 | 0.585755 | 3.27415 | 3120 | 0.039 | 0.00732194 | 0.0409269 | 3.52432 | 0.85438 | 3.54278 | 0.234 | 0.0640785 | 0.265709 | 11.23 | 1.123 | 3.8114 | 0.0140376 | 0.0476426 | 1154 | 3070 | 0.1154 | 3.54278 | 0.85438 | 0.354278 | 0.085438
metalstudwand | Wand (ARCHICAD Classification); 22.23 systeemwanden; vast (NL/SfB (4 cijfers)) | 12.0037 | 1.20037 | 1.20037 | 3120 | 0.039 | 0.0150046 | 0.0150046 | 5.10982 | 1.23875 | 1.23875 | 0.234 | 0.0929059 | 0.0929059 | 14.69 | 1.469 | 1.469 | 0.0183624 | 0.0183624 | 441 | 3070 | 0.0411313 | 1.33468 | 1.33468 | 0.126273 | 0.126273
metalstudwand | Wand (ARCHICAD Classification); 22.23 systeemwanden; vast (NL/SfB (4 cijfers)) | 12.3874 | 1.23875 | 1.23875 | 3120 | 0.039 | 0.0154843 | 0.0154843 | 6.0596 | 1.469 | 1.469 | 0.234 | 0.110175 | 0.110175 | 15.0737 | 1.50737 | 1.50737 | 0.0188421 | 0.0188421 | 441 | 3070 | 0.0470687 | 1.37306 | 1.37306 | 0.144501 | 0.144501
metalstudwand | Wand (ARCHICAD Classification); 22.23 systeemwanden; vast (NL/SfB (4 cijfers)) | 12.0037 | 1.20037 | 1.20037 | 3120 | 0.039 | 0.0150046 | 0.0150046 | 5.10982 | 1.23875 | 1.23875 | 0.234 | 0.0929059 | 0.0929059 | 14.6899 | 1.469 | 1.469 | 0.0183624 | 0.0183624 | 441 | 3070 | 0.0411313 | 1.33468 | 1.33468 | 0.126273 | 0.126273
metalstudwand | Wand (ARCHICAD Classification); 22.23 systeemwanden; vast (NL/SfB (4 cijfers)) | 71.77 | 7.177 | 7.177 | 3120 | 0.039 | 0.0897125 | 0.0897125 | 29.6051 | 7.177 | 7.177 | 0.234 | 0.538275 | 0.538275 | 71.77 | 7.177 | 7.177 | 0.0897125 | 0.0897125 | 2300 | 3120 | 0.24 | 7.177 | 7.177 | 0.7177 | 0.7177

# IfcWall: metalstudwand-geisoleerd_100_dg 100, metalstudwand
In: 00 begane grond
Classification: Wand (ARCHICAD Classification); 22.23 systeemwanden; vast (NL/SfB (4 cijfers)); Material: Gipsplaat (2), Isolatie - Steenwol LSW
CPset_Phasing - Renovation Phase: Bestaand
BaseQuantities - Length: 4770 mm; Height: 3120 mm; Width: 100 mm; GrossFootprintArea: 0.477 m2; NetFootprintArea: 0.477 m2; GrossSideArea: 14.8793 m2; NetSideArea: 14.8793 m2; GrossVolume: 1.48007 m3; NetVolume: 1.48007 m3
Component Quantities - Gipsplaat 2, Mass: 297.586 kg; Gipsplaat 2, Projected Component Area (Net): 14.8793 m2; Gipsplaat 2, Projected Component Area (Gross): 14.8793 m2; Gipsplaat 2, Component Thickness: 25 mm; Gipsplaat 2, Rectangular Component Height: 3120 mm; Gipsplaat 2, Rectangular Component Width: 25 mm; Gipsplaat 2, Component Cross Section Area: 0.078 m2; Gipsplaat 2, Component Volume (Net): 0.371982 m3; Gipsplaat 2, Component Volume (Gross): 0.371982 m3; Isolatie - Steenwol LSW, Mass: 40.4856 kg; Isolatie - Steenwol LSW, Projected Component Area (Net): 14.8793 m2; Isolatie - Steenwol LSW, Projected Component Area (Gross): 14.8793 m2; Isolatie - Steenwol LSW, Component Thickness: 50 mm; Isolatie - Steenwol LSW, Rectangular Component Height: 3120 mm; Isolatie - Steenwol LSW, Rectangular Component Width: 50 mm; Isolatie - Steenwol LSW, Component Cross Section Area: 0.156 m2; Isolatie - Steenwol LSW, Component Volume (Net): 0.736102 m3; Isolatie - Steenwol LSW, Component Volume (Gross): 0.736102 m3; Gipsplaat 1, Mass: 297.586 kg; Gipsplaat 1, Projected Component Area (Net): 14.8793 m2; Gipsplaat 1, Projected Component Area (Gross): 14.8793 m2; Gipsplaat 1, Component Thickness: 25 mm; Gipsplaat 1, Rectangular Component Height: 3120 mm; Gipsplaat 1, Rectangular Component Width: 25 mm; Gipsplaat 1, Component Cross Section Area: 0.078 m2; Gipsplaat 1, Component Volume (Net): 0.371983 m3; Gipsplaat 1, Component Volume (Gross): 0.371983 m3
Pset_WallCommon - IsExternal: no; LoadBearing: no

# IfcWall: metalstudwand-geisoleerd_120 120, Wand-x
In: 00 begane grond
Classification: Wand (ARCHICAD Classification); Material: Gipsplaat (2), Isolatie - Steenwol LSW (2)
BaseQuantities - Length: 4770 mm; Height: 3120 mm; Width: 120 mm; GrossFootprintArea: 0.5724 m2; NetFootprintArea: 0.5724 m2; GrossSideArea: 14.8793 m2; NetSideArea: 14.8793 m2; GrossVolume: 1.77768 m3; NetVolume: 1.77768 m3
Pset_WallCommon - IsExternal: no; LoadBearing: no
CPset_Phasing - Renovation Phase: Bestaand
Component Quantities - Gipsplaat 2, Mass: 148.793 kg; Gipsplaat 2, Projected Component Area (Net): 14.8793 m2; Gipsplaat 2, Projected Component Area (Gross): 14.8793 m2; Gipsplaat 2, Component Thickness: 12.5 mm; Gipsplaat 2, Rectangular Component Height: 3120 mm; Gipsplaat 2, Rectangular Component Width: 12.5 mm; Gipsplaat 2, Component Cross Section Area: 0.039 m2; Gipsplaat 2, Component Volume (Net): 0.185991 m3; Gipsplaat 2, Component Volume (Gross): 0.185991 m3; Isolatie - Steenwol LSW 2, Mass: 32.6806 kg; Isolatie - Steenwol LSW 2, Projected Component Area (Net): 14.8793 m2; Isolatie - Steenwol LSW 2, Projected Component Area (Gross): 14.8793 m2; Isolatie - Steenwol LSW 2, Component Thickness: 40 mm; Isolatie - Steenwol LSW 2, Rectangular Component Height: 3120 mm; Isolatie - Steenwol LSW 2, Rectangular Component Width: 40 mm; Isolatie - Steenwol LSW 2, Component Cross Section Area: 0.1248 m2; Isolatie - Steenwol LSW 2, Component Volume (Net): 0.594192 m3; Isolatie - Steenwol LSW 2, Component Volume (Gross): 0.594192 m3; Isolatie - Steenwol LSW 1, Mass: 32.6806 kg; Isolatie - Steenwol LSW 1, Projected Component Area (Net): 14.8793 m2; Isolatie - Steenwol LSW 1, Projected Component Area (Gross): 14.8793 m2; Isolatie - Steenwol LSW 1, Component Thickness: 40 mm; Isolatie - Steenwol LSW 1, Rectangular Component Height: 3120 mm; Isolatie - Steenwol LSW 1, Rectangular Component Width: 40 mm; Isolatie - Steenwol LSW 1, Component Cross Section Area: 0.1248 m2; Isolatie - Steenwol LSW 1, Component Volume (Net): 0.594192 m3; Isolatie - Steenwol LSW 1, Component Volume (Gross): 0.594192 m3; Gipsplaat 1, Mass: 148.793 kg; Gipsplaat 1, Projected Component Area (Net): 14.8793 m2; Gipsplaat 1, Projected Component Area (Gross): 14.8793 m2; Gipsplaat 1, Component Thickness: 12.5 mm; Gipsplaat 1, Rectangular Component Height: 3120 mm; Gipsplaat 1, Rectangular Component Width: 12.5 mm; Gipsplaat 1, Component Cross Section Area: 0.039 m2; Gipsplaat 1, Component Volume (Net): 0.185991 m3; Gipsplaat 1, Component Volume (Gross): 0.185991 m3

# IfcWall: paneel_ntb_50 50 (30)
In: 00 begane grond
Material: Isolatie - PIR
CPset_Phasing - Renovation Phase: Bestaand
BaseQuantities - Width: 50 mm
Pset_WallCommon - IsExternal: yes; LoadBearing: no
Component Quantities - Isolatie - PIR, Component Thickness: 25 mm; Isolatie - PIR, Rectangular Component Width: 25 mm
Name | Classification | Length (mm) | Height (mm) = Isolatie - PIR, Rectangular Component Height (mm) | GrossFootprintArea (m2) = NetFootprintArea (m2) | GrossSideArea (m2) = NetSideArea (m2) | GrossVolume (m3) = NetVolume (m3) | Isolatie - PIR, Mass (kg) | Isolatie - PIR, Projected Component Area (Net) (m2) | Isolatie - PIR, Projected Component Area (Gross) (m2) | Isolatie - PIR, Component Cross Section Area (m2) | Isolatie - PIR, Component Volume (Net) (m3) | Isolatie - PIR, Component Volume (Gross) (m3)
sandwichpaneel (pir) | Wand (ARCHICAD Classification) | 335 | 1100 | 0.017375 | 0.378707 | 0.0190446 | 1.58091 | 0.396 | 0.396 | 0.0275 | 0.00988068 | 0.0099
sandwichpaneel (pir) | Wand (ARCHICAD Classification) | 335 | 1600 | 0.017375 | 0.556 | 0.0278 | 2.304 | 0.576 | 0.576 | 0.04 | 0.0144 | 0.0144
sandwichpaneel (pir) | Wand (ARCHICAD Classification) | 220 | 1100 | 0.011625 | 0.253494 | 0.0127427 | 1.07591 | 0.2695 | 0.2695 | 0.0275 | 0.00672446 | 0.0067375
sandwichpaneel (pir) | Wand (ARCHICAD Classification) | 220 | 990 | 0.011625 | 0.230175 | 0.0115088 | 0.9702 | 0.24255 | 0.24255 | 0.02475 | 0.00606375 | 0.00606375
2 x sandwichpaneel (pir) | Wand (ARCHICAD Classification) | 3990 | 990 | 0.1995 | 3.9501 | 0.197505 | 15.8004 | 3.9501 | 3.9501 | 0.02475 | 0.0987525 | 0.0987525
sandwichpaneel (pir) | Wand (ARCHICAD Classification) | 340 | 1600 | 0.017625 | 0.564 | 0.0282 | 2.336 | 0.584 | 0.584 | 0.04 | 0.0146 | 0.0146
2 x sandwichpaneel (pir) | Wand (ARCHICAD Classification) | 4825 | 990 | 0.24125 | 4.77675 | 0.238837 | 19.107 | 4.77675 | 4.77675 | 0.02475 | 0.119419 | 0.119419
sandwichpaneel (pir) | Wand (ARCHICAD Classification) | 335 | 990 | 0.017375 | 0.344025 | 0.0172013 | 1.4256 | 0.3564 | 0.3564 | 0.02475 | 0.00891 | 0.00891
sandwichpaneel (pir) | Wand (ARCHICAD Classification); 21.13 systeemwanden (NL/SfB (4 cijfers)) | 16325 | 3710 | 0.817499 | 60.4351 | 3.02759 | 242.696 | 60.7098 | 60.7097 | 0.09275 | 1.51685 | 1.51774
sandwichpaneel (pir) | Wand (ARCHICAD Classification) | 4825 | 1100 | 0.24125 | 5.25349 | 0.264404 | 21.1878 | 5.3075 | 5.3075 | 0.0275 | 0.132424 | 0.132687
sandwichpaneel (pir) | Wand (ARCHICAD Classification); 21.13 systeemwanden (NL/SfB (4 cijfers)) | 3940 | 1100 | 0.197 | 4.2899 | 0.215907 | 17.3015 | 4.334 | 4.334 | 0.0275 | 0.108135 | 0.10835
2 x sandwichpaneel (pir) | Wand (ARCHICAD Classification) | 3990 | 1100 | 0.1995 | 4.34434 | 0.218647 | 17.5211 | 4.389 | 4.389 | 0.0275 | 0.109507 | 0.109725
sandwichpaneel (pir) | Wand (ARCHICAD Classification) | 220 | 1100 | 0.011625 | 0.25575 | 0.0127875 | 1.078 | 0.2695 | 0.2695 | 0.0275 | 0.0067375 | 0.0067375
2 x sandwichpaneel (pir) | Wand (ARCHICAD Classification) | 5490 | 1100 | 0.2745 | 5.97755 | 0.300845 | 24.108 | 6.039 | 6.039 | 0.0275 | 0.150675 | 0.150975
sandwichpaneel (pir) | Wand (ARCHICAD Classification) | 3940 | 990 | 0.197 | 3.9006 | 0.19503 | 15.6024 | 3.9006 | 3.9006 | 0.02475 | 0.097515 | 0.097515
sandwichpaneel (pir) | Wand (ARCHICAD Classification) | 220 | 990 | 0.011625 | 0.230175 | 0.0115087 | 0.9702 | 0.24255 | 0.24255 | 0.02475 | 0.00606375 | 0.00606375
sandwichpaneel (pir) | Wand (ARCHICAD Classification) | 2905 | 990 | 0.14525 | 2.87595 | 0.143797 | 11.5038 | 2.87595 | 2.87595 | 0.02475 | 0.0718987 | 0.0718987
sandwichpaneel (pir) | Wand (ARCHICAD Classification) | 3940 | 1100 | 0.197 | 4.2899 | 0.215907 | 17.3015 | 4.334 | 4.334 | 0.0275 | 0.108135 | 0.10835
sandwichpaneel (pir) | Wand (ARCHICAD Classification); 21.13 systeemwanden (NL/SfB (4 cijfers)) | 5170 | 1100 | 0.257875 | 5.61566 | 0.282625 | 22.7028 | 5.687 | 5.687 | 0.0275 | 0.141892 | 0.142175
sandwichpaneel (pir) | Wand (ARCHICAD Classification) | 340 | 1100 | 0.016375 | 0.356724 | 0.0179477 | 1.49303 | 0.374 | 0.374 | 0.0275 | 0.00933142 | 0.00935
sandwichpaneel (pir) | Wand (ARCHICAD Classification) | 340 | 990 | 0.016375 | 0.324225 | 0.0162112 | 1.3464 | 0.3366 | 0.3366 | 0.02475 | 0.008415 | 0.008415
2 x sandwichpaneel (pir) | Wand (ARCHICAD Classification) | 5170 | 990 | 0.257875 | 5.10593 | 0.255296 | 20.4732 | 5.1183 | 5.1183 | 0.02475 | 0.127958 | 0.127958
sandwichpaneel (pir) | Wand (ARCHICAD Classification) | 5170 | 1100 | 0.257875 | 5.61566 | 0.282625 | 22.7028 | 5.687 | 5.687 | 0.0275 | 0.141892 | 0.142175
sandwichpaneel (pir) | Wand (ARCHICAD Classification); 21.13 systeemwanden (NL/SfB (4 cijfers)) | 4825 | 1100 | 0.24125 | 5.25349 | 0.264404 | 21.1878 | 5.3075 | 5.3075 | 0.0275 | 0.132424 | 0.132687
sandwichpaneel (pir) | Wand (ARCHICAD Classification) | 5490 | 990 | 0.2745 | 5.4351 | 0.271755 | 21.7404 | 5.4351 | 5.4351 | 0.02475 | 0.135878 | 0.135878

# IfcWall: rodeca_20 20, rodeca
In: 00 begane grond
Classification: Wand (ARCHICAD Classification); 22.13 systeemwanden; vast (NL/SfB (4 cijfers)); Material: Glas - rodeca
CPset_Phasing - Renovation Phase: Bestaand
Pset_WallCommon - IsExternal: no; LoadBearing: no
Component Quantities - Glas - rodeca, Mass: 1619.21 kg; Glas - rodeca, Projected Component Area (Net): 37.919 m2; Glas - rodeca, Projected Component Area (Gross): 37.919 m2; Glas - rodeca, Component Thickness: 20 mm; Glas - rodeca, Rectangular Component Height: 2718.62 mm; Glas - rodeca, Rectangular Component Width: 20 mm; Glas - rodeca, Component Cross Section Area: 0.0543724 m2; Glas - rodeca, Component Volume (Net): 0.742758 m3; Glas - rodeca, Component Volume (Gross): 0.742758 m3
BaseQuantities - Length: 14122 mm; Height: 2718.62 mm; Width: 20 mm; GrossFootprintArea: 0.282324 m2; NetFootprintArea: 0.282324 m2; GrossSideArea: 37.919 m2; NetSideArea: 37.919 m2; GrossVolume: 0.742758 m3; NetVolume: 0.742758 m3

# IfcWall: rodeca_30 30 (6)
In: 00 begane grond
Material: Glas - rodeca
CPset_Phasing - Renovation Phase: Bestaand
Component Quantities - Glas - rodeca, Component Thickness: 30 mm; Glas - rodeca, Rectangular Component Width: 30 mm
BaseQuantities - Width: 30 mm
Pset_WallCommon - LoadBearing: no
Name | Classification | Glas - rodeca, Mass (kg) | Glas - rodeca, Projected Component Area (Net) (m2) = GrossSideArea (m2) = NetSideArea (m2) | Glas - rodeca, Projected Component Area (Gross) (m2) | Glas - rodeca, Rectangular Component Height (mm) | Glas - rodeca, Component Cross Section Area (m2) | Glas - rodeca, Component Volume (Net) (m3) = GrossVolume (m3) = NetVolume (m3) | Glas - rodeca, Component Volume (Gross) (m3) | Length (mm) | Height (mm) | GrossFootprintArea (m2) = NetFootprintArea (m2) | IsExternal
Wand-x | Wand (ARCHICAD Classification) | 3579.79 | 54.7368 | 54.7368 | 3785 | 0.11355 | 1.6421 | 1.6421 | 14462.5 | 3785 | 0.433875 | yes
rodeca | Wand (ARCHICAD Classification); 21.13 systeemwanden (NL/SfB (4 cijfers)) | 13889.8 | 212.382 | 212.382 | 3725 | 0.11175 | 6.37146 | 6.37146 | 57697.5 | 3680 | 1.73137 | yes
strekmetaal | Wand (ARCHICAD Classification); 22.13 systeemwanden; vast (NL/SfB (4 cijfers)) | 6645.47 | 101.613 | 101.613 | 2845 | 0.08535 | 3.04838 | 3.04838 | 35716.2 | 2845 | 1.07149 | no
rodeca | Wand (ARCHICAD Classification); 22.13 systeemwanden; vast (NL/SfB (4 cijfers)) | 3966.17 | 60.6447 | 60.6447 | 2845 | 0.08535 | 1.81934 | 1.81934 | 21316.3 | 2845 | 0.639488 | no
rodeca | Wand (ARCHICAD Classification); 22.13 systeemwanden; vast (NL/SfB (4 cijfers)) | 2311.74 | 35.8597 | 38.0743 | 2718.62 | 0.0815586 | 1.06043 | 1.14223 | 14005 | 2718.62 | 0.409581 | no
rodeca | Wand (ARCHICAD Classification); 21.13 systeemwanden (NL/SfB (4 cijfers)) | 3468.69 | 53.038 | 53.038 | 3725 | 0.11175 | 1.59114 | 1.59114 | 14477.5 | 3680 | 0.432375 | yes

# IfcWall: sandwichpaneel-PIR_100 100 (8)
In: 00 begane grond
Classification: Wand (ARCHICAD Classification); 21.13 systeemwanden (NL/SfB (4 cijfers)); Material: Metaal - Aluminium C (2), Isolatie - PIR
CPset_Phasing - Renovation Phase: Bestaand
Pset_WallCommon - IsExternal: yes; LoadBearing: no
Component Quantities - Metaal - Aluminium C 2, Component Thickness: 5 mm; Metaal - Aluminium C 2, Rectangular Component Height: 8160 mm; Metaal - Aluminium C 2, Rectangular Component Width: 5 mm; Metaal - Aluminium C 2, Component Cross Section Area: 0.0408 m2; Isolatie - PIR, Component Thickness: 90 mm; Isolatie - PIR, Rectangular Component Height: 8160 mm; Isolatie - PIR, Rectangular Component Width: 90 mm; Isolatie - PIR, Component Cross Section Area: 0.7344 m2; Metaal - Aluminium C 1, Component Thickness: 5 mm; Metaal - Aluminium C 1, Rectangular Component Height: 8160 mm; Metaal - Aluminium C 1, Rectangular Component Width: 5 mm; Metaal - Aluminium C 1, Component Cross Section Area: 0.0408 m2
BaseQuantities - Height: 8160 mm; Width: 100 mm
Name | Metaal - Aluminium C 2, Mass (kg) | Metaal - Aluminium C 2, Projected Component Area (Net) (m2) | Metaal - Aluminium C 2, Projected Component Area (Gross) (m2) | Metaal - Aluminium C 2, Component Volume (Net) (m3) | Metaal - Aluminium C 2, Component Volume (Gross) (m3) | Isolatie - PIR, Mass (kg) | Isolatie - PIR, Projected Component Area (Net) (m2) | Isolatie - PIR, Projected Component Area (Gross) (m2) | Isolatie - PIR, Component Volume (Net) (m3) | Isolatie - PIR, Component Volume (Gross) (m3) | Metaal - Aluminium C 1, Mass (kg) | Metaal - Aluminium C 1, Projected Component Area (Net) (m2) | Metaal - Aluminium C 1, Projected Component Area (Gross) (m2) | Metaal - Aluminium C 1, Component Volume (Net) (m3) | Metaal - Aluminium C 1, Component Volume (Gross) (m3) | Length (mm) | GrossFootprintArea (m2) = NetFootprintArea (m2) | GrossSideArea (m2) | NetSideArea (m2) | GrossVolume (m3) | NetVolume (m3)
sandwichpaneel (pir) | 7180.73 | 512.909 | 530.359 | 2.56455 | 2.6518 | 7374.73 | 512.134 | 529.584 | 46.0921 | 47.6626 | 7159.02 | 511.359 | 528.809 | 2.55679 | 2.64404 | 64900 | 5.792 | 529.584 | 512.134 | 52.9584 | 51.2134
2 x sandwichpaneel (pir) | 4715.82 | 336.844 | 354.144 | 1.68422 | 1.77072 | 4849.38 | 336.762 | 354.062 | 30.3086 | 31.8656 | 4694.11 | 335.294 | 352.594 | 1.67647 | 1.76297 | 43300 | 3.64615 | 353.369 | 336.069 | 35.3993 | 33.6693
sandwichpaneel (pir) | 7180.16 | 512.868 | 530.318 | 2.56434 | 2.65159 | 7364.15 | 511.4 | 528.85 | 46.026 | 47.5965 | 7158.45 | 511.318 | 528.768 | 2.55659 | 2.64384 | 64900 | 5.78385 | 529.543 | 512.093 | 52.8919 | 51.1469
2 x sandwichpaneel (pir) | 4715.24 | 336.803 | 354.103 | 1.68402 | 1.77052 | 4838.8 | 336.028 | 353.328 | 30.2425 | 31.7995 | 4693.54 | 335.253 | 352.553 | 1.67626 | 1.76276 | 43300 | 3.638 | 353.328 | 336.028 | 35.3328 | 33.6028
sandwichpaneel (pir) | 5440.28 | 388.591 | 471.566 | 1.94296 | 2.35783 | 5574.57 | 387.123 | 470.098 | 34.841 | 42.3088 | 5418.57 | 387.041 | 470.016 | 1.93521 | 2.35008 | 57700 | 2.44285 | 470.791 | 387.816 | 47.0167 | 38.7192
sandwichpaneel (pir) | 6602.5 | 471.607 | 471.607 | 2.35804 | 2.35804 | 6779.98 | 470.832 | 470.832 | 42.3749 | 42.3749 | 6580.8 | 470.057 | 470.057 | 2.35028 | 2.35028 | 57700 | 5.77 | 470.832 | 470.832 | 47.0832 | 47.0832

# IfcWall: sandwichpaneel-PIR_120 120 (17)
In: 00 begane grond
Classification: Wand (ARCHICAD Classification); 22.13 systeemwanden; vast (NL/SfB (4 cijfers)); Material: Metaal - Aluminium C (2), Isolatie - PIR
Pset_WallCommon - IsExternal: no; LoadBearing: no
CPset_Phasing - Renovation Phase: Bestaand
BaseQuantities - Height: 12000 mm; Width: 120 mm
Component Quantities - Metaal - Aluminium C 2, Component Thickness: 2 mm; Metaal - Aluminium C 2, Rectangular Component Height: 12000 mm; Metaal - Aluminium C 2, Rectangular Component Width: 2 mm; Metaal - Aluminium C 2, Component Cross Section Area: 0.024 m2; Isolatie - PIR, Component Thickness: 116 mm; Isolatie - PIR, Rectangular Component Height: 12000 mm; Isolatie - PIR, Rectangular Component Width: 116 mm; Isolatie - PIR, Component Cross Section Area: 1.392 m2; Metaal - Aluminium C 1, Component Thickness: 2 mm; Metaal - Aluminium C 1, Rectangular Component Height: 12000 mm; Metaal - Aluminium C 1, Rectangular Component Width: 2 mm; Metaal - Aluminium C 1, Component Cross Section Area: 0.024 m2
Name | Length (mm) | GrossFootprintArea (m2) = NetFootprintArea (m2) | GrossSideArea (m2) | NetSideArea (m2) | GrossVolume (m3) | NetVolume (m3) | Metaal - Aluminium C 2, Mass (kg) | Metaal - Aluminium C 2, Projected Component Area (Net) (m2) | Metaal - Aluminium C 2, Projected Component Area (Gross) (m2) | Metaal - Aluminium C 2, Component Volume (Net) (m3) | Metaal - Aluminium C 2, Component Volume (Gross) (m3) | Isolatie - PIR, Mass (kg) | Isolatie - PIR, Projected Component Area (Net) (m2) = Metaal - Aluminium C 1, Projected Component Area (Net) (m2) | Isolatie - PIR, Projected Component Area (Gross) (m2) = Metaal - Aluminium C 1, Projected Component Area (Gross) (m2) | Isolatie - PIR, Component Volume (Net) (m3) | Isolatie - PIR, Component Volume (Gross) (m3) | Metaal - Aluminium C 1, Mass (kg) | Metaal - Aluminium C 1, Component Volume (Net) (m3) | Metaal - Aluminium C 1, Component Volume (Gross) (m3)
sandwichpaneel | 57000 | 6.33738 | 683.365 | 673.575 | 82.0042 | 80.8294 | 3771.99 | 673.57 | 683.36 | 1.34714 | 1.36672 | 12501.6 | 673.58 | 683.37 | 78.1351 | 79.2707 | 3772.05 | 1.34716 | 1.36674
sandwichpaneel | 13990 | 1.6773 | 167.73 | 167.73 | 20.1276 | 20.1276 | 939.288 | 167.73 | 167.73 | 0.33546 | 0.33546 | 3113.07 | 167.73 | 167.73 | 19.4567 | 19.4567 | 939.288 | 0.33546 | 0.33546
13 x sandwichpaneel | 1000 | 0.12 | 12 | 12 | 1.44 | 1.44 | 67.2 | 12 | 12 | 0.024 | 0.024 | 222.72 | 12 | 12 | 1.392 | 1.392 | 67.2 | 0.024 | 0.024
sandwichpaneel | 890 | 0.1068 | 10.68 | 10.68 | 1.2816 | 1.2816 | 59.808 | 10.68 | 10.68 | 0.02136 | 0.02136 | 198.221 | 10.68 | 10.68 | 1.23888 | 1.23888 | 59.808 | 0.02136 | 0.02136
sandwichpaneel | 75 | 0.009 | 0.9 | 0.9 | 0.108 | 0.108 | 5.04 | 0.9 | 0.9 | 0.0018 | 0.0018 | 16.704 | 0.9 | 0.9 | 0.1044 | 0.1044 | 5.04 | 0.0018 | 0.0018

# IfcWall: sandwichpaneel-STW_200 200 (4)
In: 00 begane grond
Classification: Wand (ARCHICAD Classification); 21.23 systeemwanden (NL/SfB (4 cijfers)); Material: Metaal - Aluminium C (2), Isolatie - Steenwol hard
CPset_Phasing - Renovation Phase: Bestaand
BaseQuantities - Height: 4100 mm; Width: 200 mm
Pset_WallCommon - IsExternal: yes; LoadBearing: no
Component Quantities - Metaal - Aluminium C 2, Component Thickness: 5 mm; Metaal - Aluminium C 2, Rectangular Component Height: 4100 mm; Metaal - Aluminium C 2, Rectangular Component Width: 5 mm; Metaal - Aluminium C 2, Component Cross Section Area: 0.0205 m2; Isolatie - Steenwol hard, Component Thickness: 190 mm; Isolatie - Steenwol hard, Rectangular Component Height: 4100 mm; Isolatie - Steenwol hard, Rectangular Component Width: 190 mm; Isolatie - Steenwol hard, Component Cross Section Area: 0.779 m2; Metaal - Aluminium C 1, Component Thickness: 5 mm; Metaal - Aluminium C 1, Rectangular Component Height: 4100 mm; Metaal - Aluminium C 1, Rectangular Component Width: 5 mm; Metaal - Aluminium C 1, Component Cross Section Area: 0.0205 m2
Name | Length (mm) | GrossFootprintArea (m2) = NetFootprintArea (m2) | GrossSideArea (m2) | NetSideArea (m2) | GrossVolume (m3) | NetVolume (m3) | Metaal - Aluminium C 2, Mass (kg) | Metaal - Aluminium C 2, Projected Component Area (Net) (m2) | Metaal - Aluminium C 2, Projected Component Area (Gross) (m2) | Metaal - Aluminium C 2, Component Volume (Net) (m3) | Metaal - Aluminium C 2, Component Volume (Gross) (m3) | Isolatie - Steenwol hard, Mass (kg) | Isolatie - Steenwol hard, Projected Component Area (Net) (m2) | Isolatie - Steenwol hard, Projected Component Area (Gross) (m2) | Isolatie - Steenwol hard, Component Volume (Net) (m3) | Isolatie - Steenwol hard, Component Volume (Gross) (m3) | Metaal - Aluminium C 1, Mass (kg) | Metaal - Aluminium C 1, Projected Component Area (Net) (m2) | Metaal - Aluminium C 1, Projected Component Area (Gross) (m2) | Metaal - Aluminium C 1, Component Volume (Net) (m3) | Metaal - Aluminium C 1, Component Volume (Gross) (m3)
sandwichpaneel (steenwol) | 15600 | 3.15615 | 63.7924 | 39.1804 | 12.9057 | 7.95516 | 560.168 | 40.012 | 64.78 | 0.20006 | 0.3239 | 1210.13 | 39.979 | 64.739 | 7.56333 | 12.3004 | 536.955 | 38.3592 | 63.181 | 0.19177 | 0.315905
sandwichpaneel (steenwol) | 16100 | 3.22 | 65.8158 | 39.0208 | 13.1666 | 7.80761 | 555.835 | 39.7025 | 66.8095 | 0.198512 | 0.334047 | 1186.78 | 39.215 | 66.01 | 7.41737 | 12.5419 | 536.824 | 38.3499 | 65.2105 | 0.191723 | 0.326052
sandwichpaneel (steenwol) | 15600 | 3.12 | 63.7719 | 33.7099 | 12.7577 | 6.77343 | 483.581 | 34.5415 | 64.7595 | 0.172707 | 0.323797 | 1029.81 | 34.046 | 63.96 | 6.43631 | 12.1524 | 460.37 | 32.8888 | 63.1605 | 0.164418 | 0.315802
sandwichpaneel (steenwol) | 16100 | 3.18385 | 65.7954 | 65.7954 | 13.0186 | 13.0186 | 935.046 | 66.789 | 66.789 | 0.333945 | 0.333945 | 1977.71 | 65.231 | 65.231 | 12.3607 | 12.3939 | 907.299 | 64.8125 | 65.19 | 0.324035 | 0.32595

# IfcWall: strekmetaal_20 20 (7)
In: 00 begane grond
Classification: Wand (ARCHICAD Classification); 21.13 systeemwanden (NL/SfB (4 cijfers)); Material: Metaal - Aluminium (strekmetaal)
BaseQuantities - Height: 3785 mm; Width: 20 mm
Pset_WallCommon - IsExternal: yes; LoadBearing: no
CPset_Phasing - Renovation Phase: Bestaand
Component Quantities - Metaal - Aluminium (strekmetaal), Component Thickness: 20 mm; Metaal - Aluminium (strekmetaal), Rectangular Component Height: 3785 mm; Metaal - Aluminium (strekmetaal), Rectangular Component Width: 20 mm; Metaal - Aluminium (strekmetaal), Component Cross Section Area: 0.0757 m2
Name | Length (mm) | GrossFootprintArea (m2) = NetFootprintArea (m2) | GrossSideArea (m2) = NetSideArea (m2) = Metaal - Aluminium (strekmetaal), Projected Component Area (Net) (m2) = Metaal - Aluminium (strekmetaal), Projected Component Area (Gross) (m2) | GrossVolume (m3) = NetVolume (m3) = Metaal - Aluminium (strekmetaal), Component Volume (Net) (m3) = Metaal - Aluminium (strekmetaal), Component Volume (Gross) (m3) | Metaal - Aluminium (strekmetaal), Mass (kg)
strekmetaal | 43380 | 0.868 | 164.269 | 3.28538 | 9199.06
strekmetaal | 64980 | 1.2996 | 245.949 | 4.91899 | 13773.2
strekmetaal | 43380 | 0.8676 | 164.193 | 3.28387 | 9194.82
strekmetaal | 57780 | 1.1556 | 218.697 | 4.37395 | 12247
strekmetaal | 64980 | 1.2992 | 245.874 | 4.91747 | 13768.9
strekmetaal | 43390 | 0.868 | 164.269 | 3.28538 | 9199.06
strekmetaal | 28890 | 0.5776 | 109.311 | 2.18622 | 6121.4

# IfcWall: strekmetaal_personeelsgebouw_20 20 (8)
In: 01 dak
Classification: Wand (ARCHICAD Classification); 21.13 systeemwanden (NL/SfB (4 cijfers)); Material: Metaal - Aluminium (strekmetaal-personeelgebouw)
Pset_WallCommon - IsExternal: yes; LoadBearing: no
BaseQuantities - Height: 1370.01 mm; Width: 20 mm
CPset_Phasing - Renovation Phase: Bestaand
Component Quantities - Metaal - Aluminium (strekmetaal-personeelgebouw), Component Thickness: 20 mm; Metaal - Aluminium (strekmetaal-personeelgebouw), Rectangular Component Height: 1370.01 mm; Metaal - Aluminium (strekmetaal-personeelgebouw), Rectangular Component Width: 20 mm; Metaal - Aluminium (strekmetaal-personeelgebouw), Component Cross Section Area: 0.0274001 m2
Name | Length (mm) | GrossFootprintArea (m2) = NetFootprintArea (m2) | GrossSideArea (m2) = NetSideArea (m2) = Metaal - Aluminium (strekmetaal-personeelgebouw), Projected Component Area (Net) (m2) = Metaal - Aluminium (strekmetaal-personeelgebouw), Projected Component Area (Gross) (m2) | GrossVolume (m3) = NetVolume (m3) = Metaal - Aluminium (strekmetaal-personeelgebouw), Component Volume (Net) (m3) = Metaal - Aluminium (strekmetaal-personeelgebouw), Component Volume (Gross) (m3) | Metaal - Aluminium (strekmetaal-personeelgebouw), Mass (kg)
strekmetaal | 6060 | 0.1216 | 8.32964 | 0.166593 | 466.46
strekmetaal | 1290 | 0.0256 | 1.75361 | 0.0350722 | 98.2021
strekmetaal | 2520 | 0.0506 | 3.46612 | 0.0693223 | 194.103
strekmetaal | 2520 | 0.0504 | 3.45242 | 0.0690483 | 193.335
strekmetaal | 2520 | 0.0502 | 3.43872 | 0.0687743 | 192.568
strekmetaal | 60 | 0.001 | 0.0685003 | 0.00137001 | 3.83602
strekmetaal | 1020 | 0.0204 | 1.39741 | 0.0279481 | 78.2548
strekmetaal | 1160 | 0.0232 | 1.58921 | 0.0317841 | 88.9956

# IfcWall: wandafwerking-staal_10 10 (21)
In: 00 begane grond
Classification: Wand (ARCHICAD Classification); 22.21 massieve wanden (NL/SfB (4 cijfers)); Material: Metaal - Staal C
CPset_Phasing - Renovation Phase: Bestaand
Pset_WallCommon - IsExternal: no; LoadBearing: yes
BaseQuantities - Height: 1020 mm; Width: 10 mm
Component Quantities - Metaal - Staal C, Component Thickness: 10 mm; Metaal - Staal C, Rectangular Component Height: 1020 mm; Metaal - Staal C, Rectangular Component Width: 10 mm; Metaal - Staal C, Component Cross Section Area: 0.0102 m2
Name | Length (mm) | GrossFootprintArea (m2) = NetFootprintArea (m2) | GrossSideArea (m2) = NetSideArea (m2) = Metaal - Staal C, Projected Component Area (Net) (m2) = Metaal - Staal C, Projected Component Area (Gross) (m2) | GrossVolume (m3) = NetVolume (m3) = Metaal - Staal C, Component Volume (Net) (m3) = Metaal - Staal C, Component Volume (Gross) (m3) | Metaal - Staal C, Mass (kg)
2 x staalplaat ingestort in wand | 1140 | 0.0114 | 1.1628 | 0.011628 | 92.4426
2 x staalplaat ingestort in wand | 15671 | 0.15676 | 15.9895 | 0.159895 | 1271.17
staalplaat ingestort in wand | 21415 | 0.2142 | 21.8484 | 0.218484 | 1736.95
staalplaat ingestort in wand | 35815 | 0.3581 | 36.5262 | 0.365262 | 2903.83
3 x staalplaat ingestort in wand | 17845 | 0.1784 | 18.1968 | 0.181968 | 1446.65
staalplaat ingestort in wand | 21445 | 0.2144 | 21.8688 | 0.218688 | 1738.57
staalplaat ingestort in wand | 35845 | 0.3585 | 36.567 | 0.36567 | 2907.08
2 x staalplaat ingestort in wand | 14543 | 0.14543 | 14.8339 | 0.148339 | 1179.29
staalplaat ingestort in wand | 21950 | 0.2195 | 22.389 | 0.22389 | 1779.93
3 x staalplaat ingestort in wand | 600 | 0.006 | 0.612 | 0.00612 | 48.654
staalplaat ingestort in wand | 17845 | 0.1785 | 18.207 | 0.18207 | 1447.46
staalplaat ingestort in wand | 57010 | 0.5701 | 58.1502 | 0.581502 | 4622.94
2 x staalplaat ingestort in wand | 2263 | 0.02263 | 2.30826 | 0.0230826 | 183.507

# IfcWindow: Daklicht rond 02 27 (16)
In: 01 dak
Type - ParameterTakesPrecedence: no; Sizeable: no
OverallHeight: 800 mm; OverallWidth: 800 mm
Material - Glas: Glas - kozijn exterieur
Pset_WindowCommon - ThermalTransmittance: 0; IsExternal: yes
CPset_Phasing - Renovation Phase: Bestaand
BaseQuantities - GrossArea: 0.64 m2; Height: 800 mm; Width: 800 mm; Perimeter: 3200 mm; Area: 0.64 m2; Volume: 0.064 m3; Depth: 100 mm; NetVolume: 0.064 m3
Component Quantities - Component, Component Volume (Net): 0.00906553 m3; Component, Component Volume (Gross): 0.00906553 m3
Name | Classification
15 x Merk-x | Daklicht (ARCHICAD Classification)
solatube | 37.21 gesloten ramen (NL/SfB (4 cijfers)); Daklicht (ARCHICAD Classification)

# IfcWindow: Daklicht vlak paneel 27, daklicht
In: 01 dak
Type - ParameterTakesPrecedence: no; Sizeable: no
OverallHeight: 2788 mm; OverallWidth: 1788 mm; Classification: 31.21 gesloten ramen (NL/SfB (4 cijfers)); Daklicht (ARCHICAD Classification)
Material - Glas: Glas - kozijn exterieur
Pset_WindowCommon - ThermalTransmittance: 0; IsExternal: yes
Component Quantities - Component, Component Volume (Net): 0.199777 m3; Component, Component Volume (Gross): 0.199777 m3
BaseQuantities - GrossArea: 4.98494 m2; Height: 2788 mm; Width: 1788 mm; Perimeter: 9152 mm; Area: 4.98494 m2; Volume: 0.797591 m3; Depth: 160 mm; NetVolume: 0.797591 m3
CPset_Phasing - Renovation Phase: Bestaand

# IfcWindow: R1 27, Bi-S08
In: 00 begane grond
Type - OperationType: DOUBLE_PANEL_VERTICAL; ParameterTakesPrecedence: no; Sizeable: no
OverallHeight: 1575 mm; OverallWidth: 1730 mm; Classification: Raam (ARCHICAD Classification)
Material - Afwerking dagkant binnen: n.v.t.; Afwerking dagkant buiten: n.v.t.; Draaiend deel: n.v.t.; Frame: Aluminium; Onderdorpel: n.v.t.; Rollaag / latei: n.v.t.; Spouwlat: n.v.t.; Vensterbank: n.v.t.; Ventilatierooster: n.v.t.; Zonwering - behuizing: n.v.t.; Zonwering - isolatie: n.v.t.; Glas: Glas - kozijn interieur
Pset_WindowCommon - FireRating: n.v.t.; ThermalTransmittance: 0; GlazingAreaFraction: 2.15667; IsExternal: yes
Component Quantities - Component, Component Volume (Net): 0.0295995 m3; Component, Component Volume (Gross): 0.0295995 m3
CPset_Phasing - Renovation Phase: Bestaand
BaseQuantities - GrossArea: 2.72475 m2; Height: 1575 mm; Width: 1730 mm; Perimeter: 6610 mm; Area: 2.72475 m2; Volume: 0.0295995 m3; Depth: 100 mm; NetVolume: 0.0295995 m3

# IfcWindow: R1 27 (11)
In: 00 begane grond
Type - OperationType: SINGLE_PANEL; ParameterTakesPrecedence: no; Sizeable: no
Pset_WindowCommon - FireRating: n.v.t.; ThermalTransmittance: 0; IsExternal: yes
Material - Afwerking dagkant binnen: n.v.t.; Afwerking dagkant buiten: n.v.t.; Draaiend deel: n.v.t.; Frame: Aluminium; Onderdorpel: n.v.t.; Rollaag / latei: n.v.t.; Spouwlat: n.v.t.; Vensterbank: n.v.t.; Ventilatierooster: n.v.t.; Zonwering - behuizing: n.v.t.; Zonwering - isolatie: n.v.t.
CPset_Phasing - Renovation Phase: Bestaand
Name | OverallHeight (mm) = Height (mm) | OverallWidth (mm) | Classification | GlazingAreaFraction | Glas | GrossArea (m2) = Area (m2) | Width (mm) | Perimeter (mm) | Volume (m3) = NetVolume (m3) = Component, Component Volume (Net) (m3) = Component, Component Volume (Gross) (m3) | Depth (mm)
aluminium kozijn | 1600 | 15458 | Raam (ARCHICAD Classification); 31.21 gesloten ramen (NL/SfB (4 cijfers)) | 22.4314 | Glas - kozijn exterieur | 24.448 | 15280 | 33760 | 0.227277 | 200
aluminium kozijn | 1600 | 3093 | Raam (ARCHICAD Classification); 31.21 gesloten ramen (NL/SfB (4 cijfers)) | 4.32905 | Glas - kozijn exterieur | 4.664 | 2915 | 9030 | 0.0511747 | 200
aluminium kozijn | 1600 | 12128 | Raam (ARCHICAD Classification); 31.21 gesloten ramen (NL/SfB (4 cijfers)) | 17.5563 | Glas - kozijn exterieur | 19.12 | 11950 | 27100 | 0.179851 | 200
aluminium kozijn | 1600 | 5123 | Raam (ARCHICAD Classification); 31.21 gesloten ramen (NL/SfB (4 cijfers)) | 7.30097 | Glas - kozijn exterieur | 7.912 | 4945 | 13090 | 0.080086 | 200
2 x aluminium kozijn | 2600 | 1545 | Raam (ARCHICAD Classification); 31.21 gesloten ramen (NL/SfB (4 cijfers)) | 3.47178 | Glas - kozijn exterieur | 4.017 | 1545 | 8290 | 0.0392561 | 200
aluminium kozijn | 1600 | 4825 | Raam (ARCHICAD Classification); 31.21 gesloten ramen (NL/SfB (4 cijfers)) | 6.8647 | Glas - kozijn exterieur | 7.72 | 4825 | 12850 | 0.0615819 | 200
Bi-S01c | 2600 | 1142 | Raam (ARCHICAD Classification) | 2.52945 | Glas - kozijn interieur | 2.9692 | 1142 | 7484 | 0.026385 | 100
Bi-S01a | 2600 | 1142 | Raam (ARCHICAD Classification) | 2.52945 | Glas - kozijn interieur | 2.9692 | 1142 | 7484 | 0.026385 | 100
Bi-S03 | 2600 | 3880 | Raam (ARCHICAD Classification) | 9.306 | Glas - kozijn interieur | 10.088 | 3880 | 12960 | 0.04692 | 100
Bi-S11 | 2600 | 3880 | Raam (ARCHICAD Classification) | 9.306 | Glas - kozijn interieur | 10.088 | 3880 | 12960 | 0.04692 | 100
